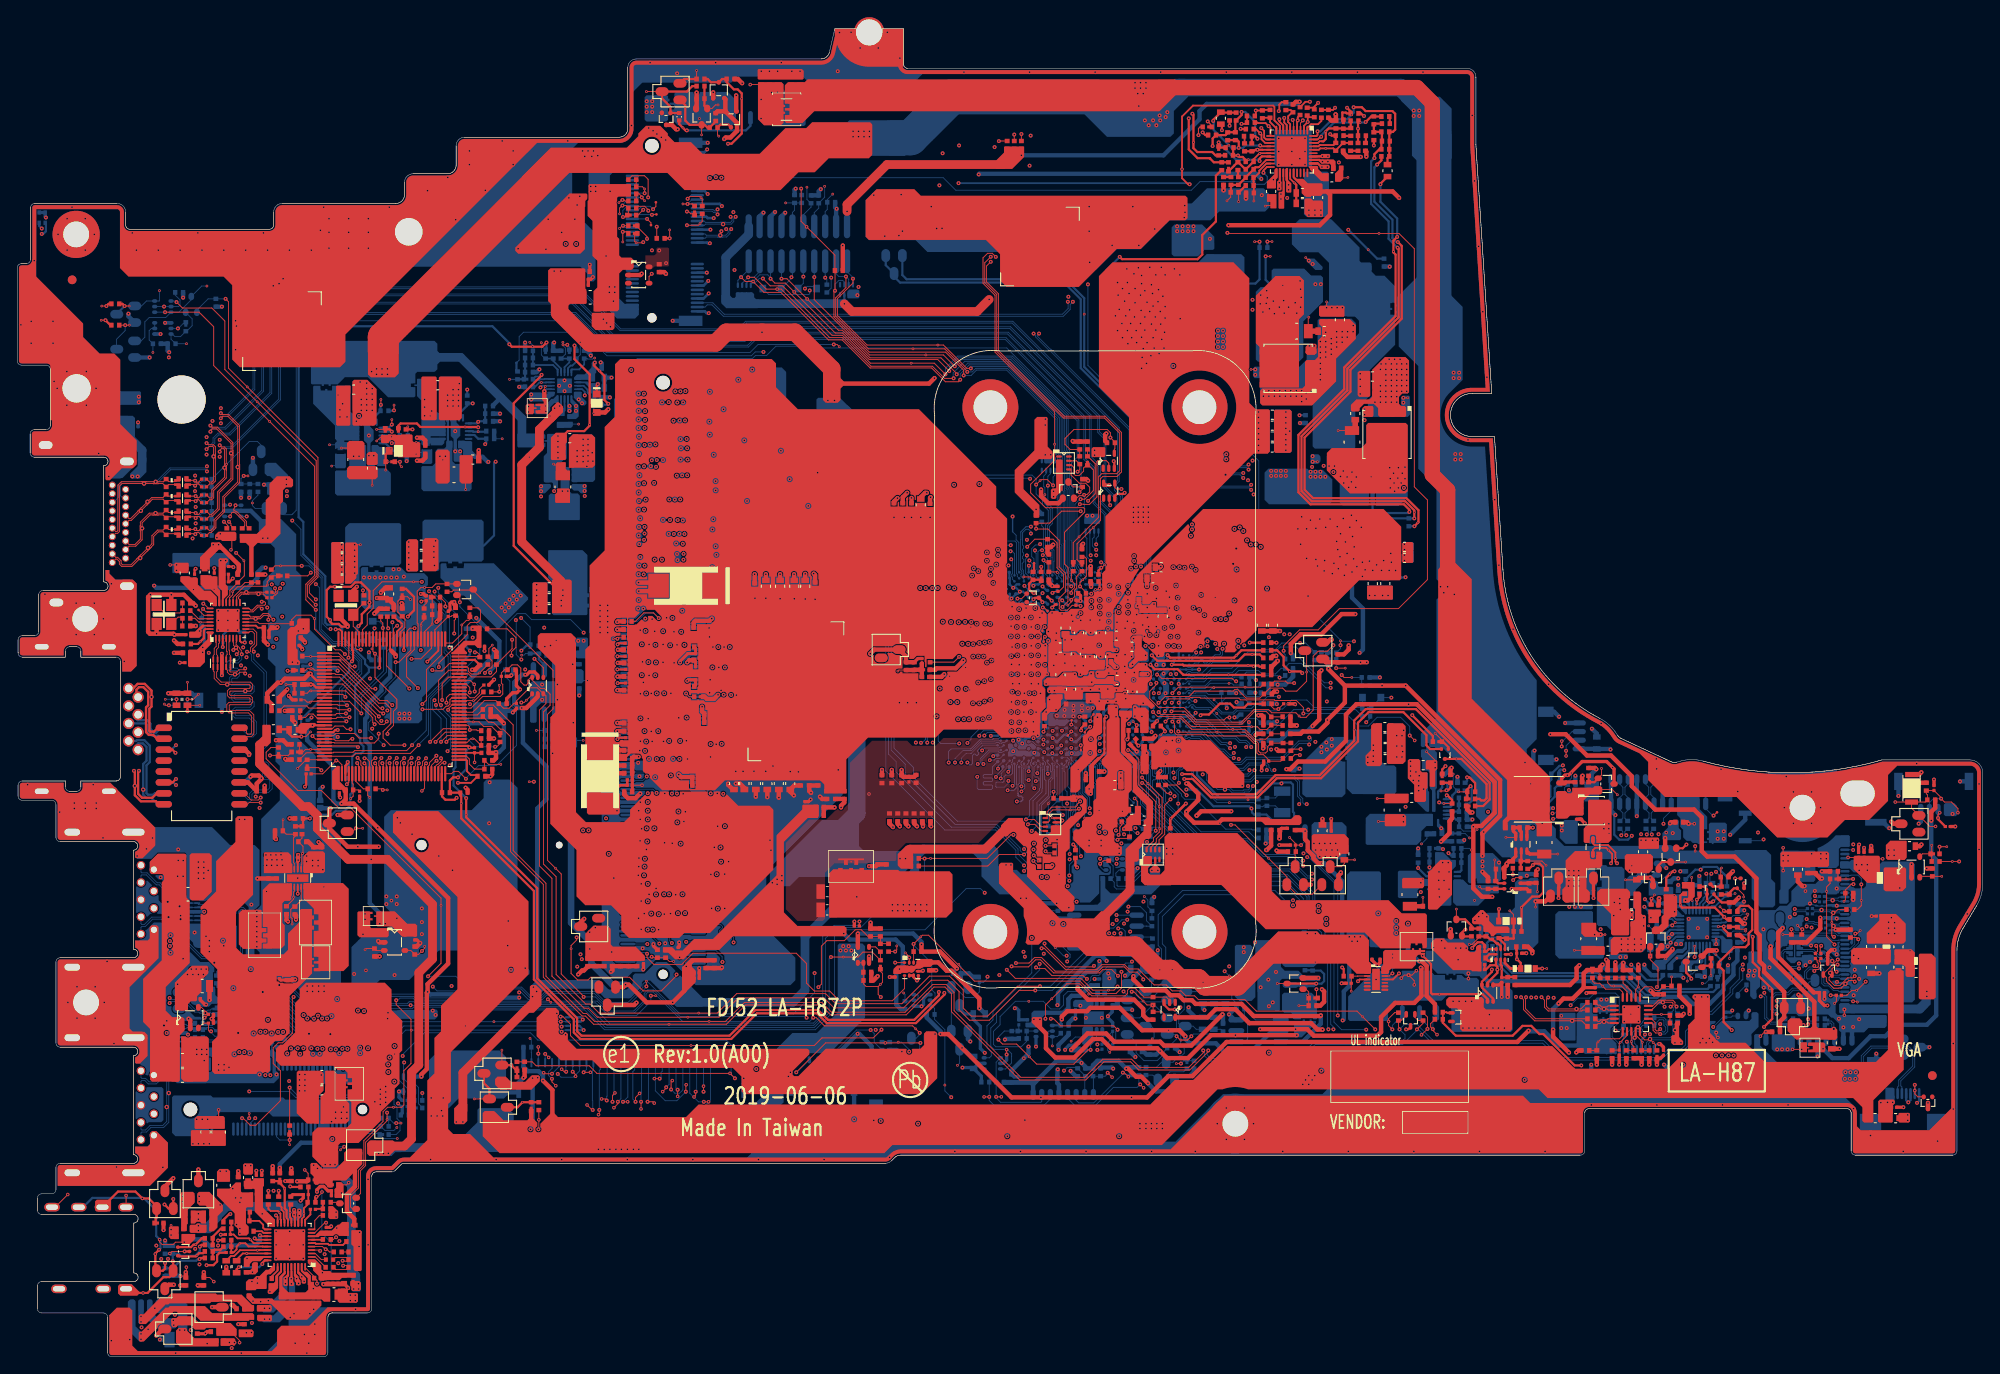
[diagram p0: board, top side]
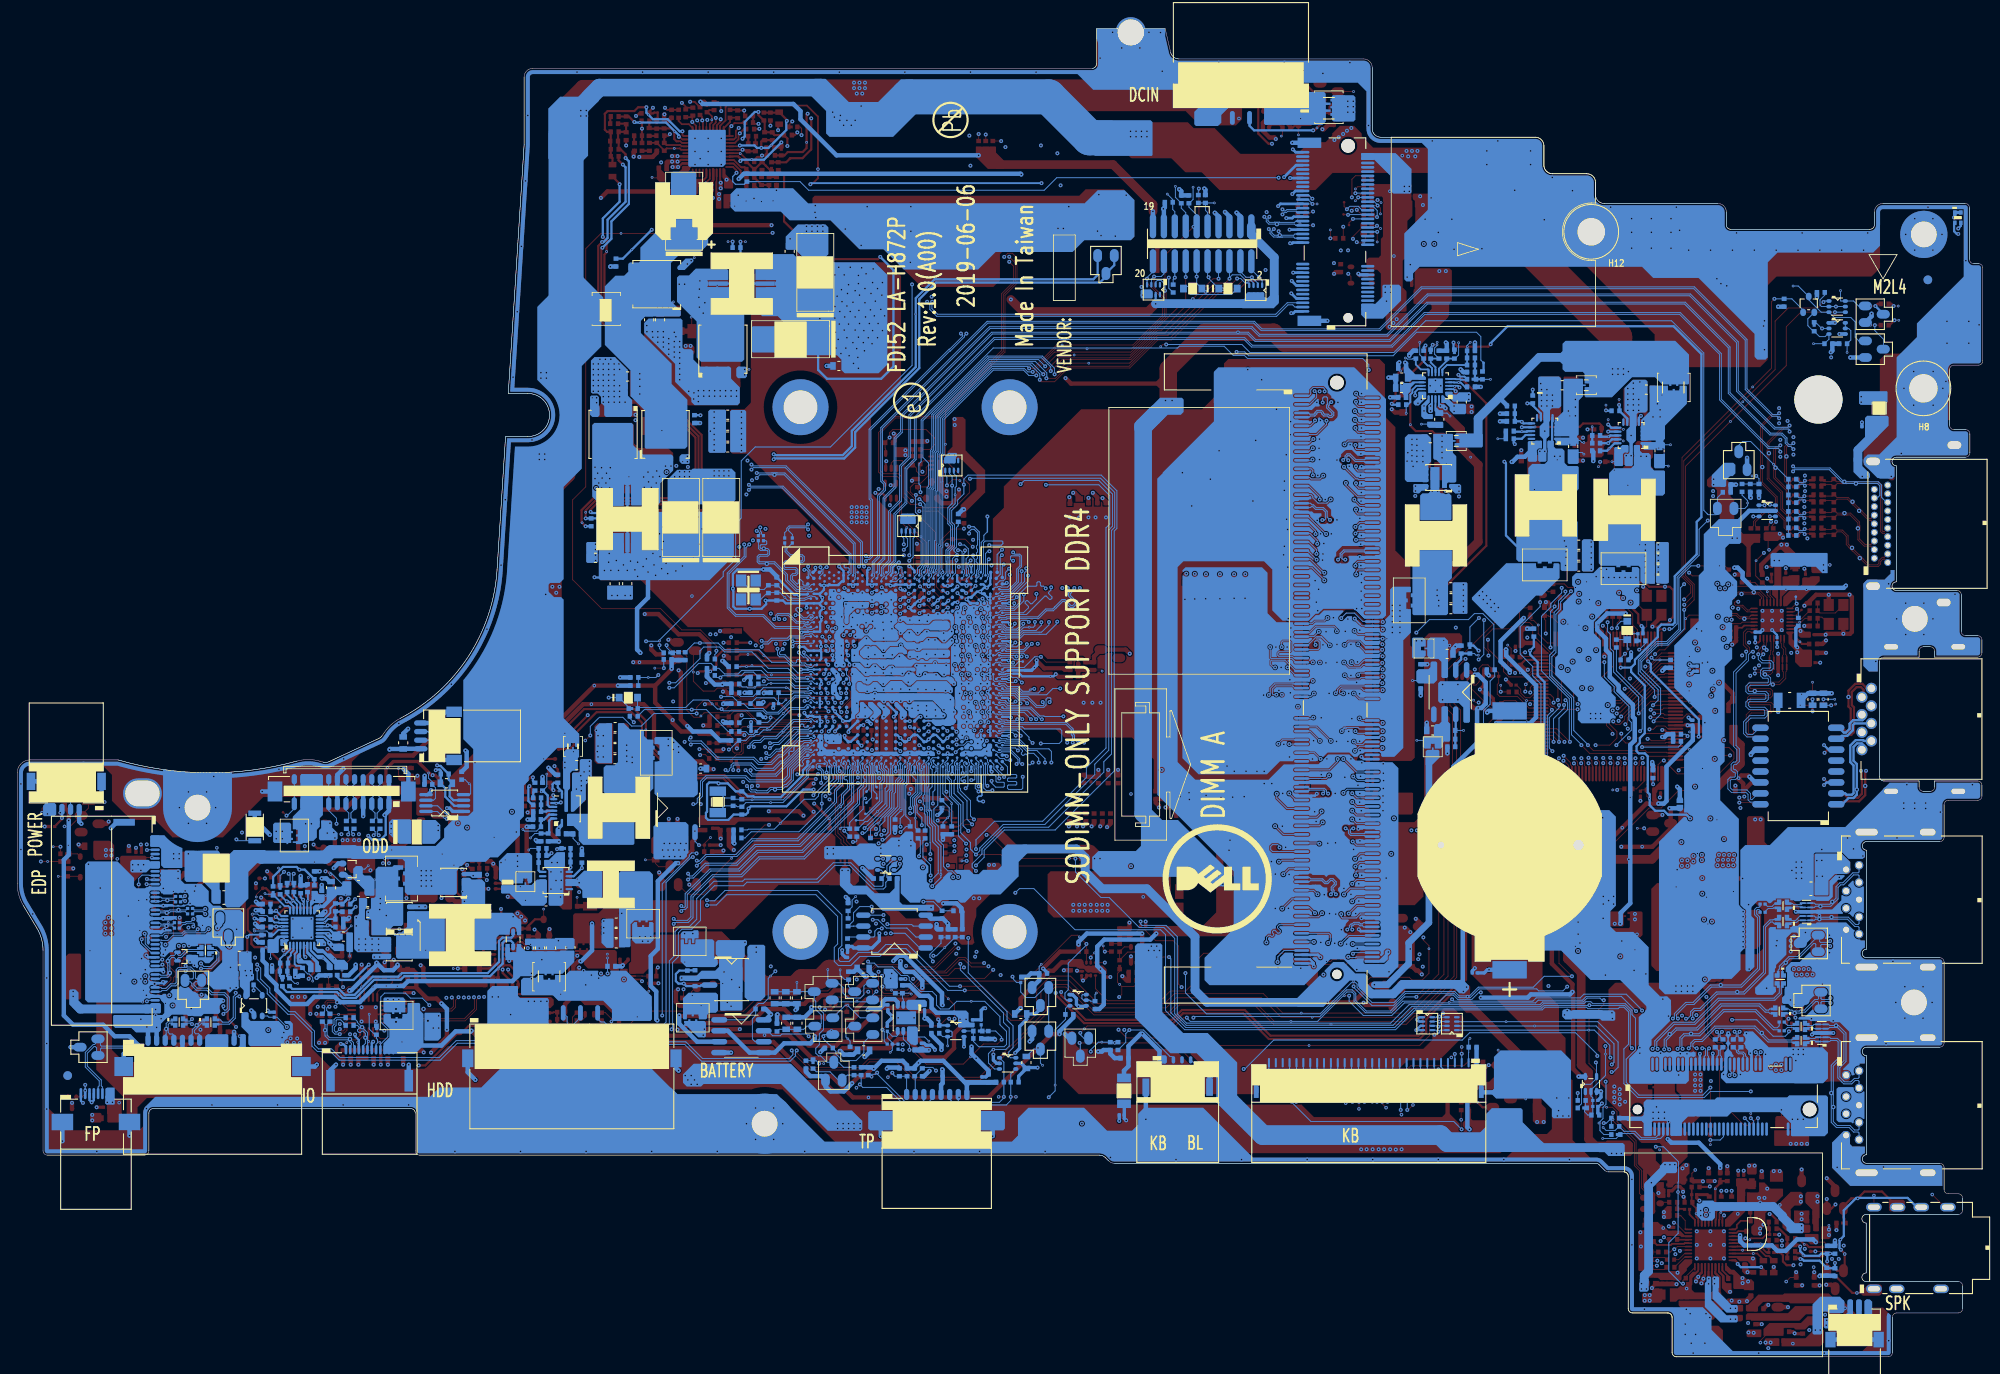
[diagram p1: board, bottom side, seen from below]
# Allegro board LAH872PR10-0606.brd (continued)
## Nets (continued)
BST_3V: PR301.1 PU301.1
BST_3V_R: PC307.1 PR301.2
BST_5V: PR501.1 PU501.1
BST_5V_R: PC507.1 PR501.2
BST_CHG: PCB06.1 PRB14.2
BST_CHG_R: PRB14.1 PUB01.12
BST_NB: PRZ08.1 PUZ01.31
BST_NB_R: PCZ09.1 PRZ08.2
BT_ON#: RW12.2 UC1.AV33
BT_ON#_R: JWLAN1.54 RW10.1 RW12.1
CAM_DETECT#: R5.1 RC34.1 UC1.AJ1
CAM_DETECT#_R: JEDP1.4 R5.2
CAP_LED: JKB1.27 R38.2
CAP_LED#_Q: Q11.1 R36.2 R38.1
CAP_LED#_R: Q10.1 Q11.2
CAPS_LED#: Q10.3 R37.2 R39.1 UE1.91
CBN: CA496.2 UA1.28
CBP: CA496.1 UA1.30
CCLIM: PRB27.2 PRB28.2 PUB01.26
CLK_PCIE_N0: UC1.M1 UL1.16
CLK_PCIE_N1: JWLAN1.49 UC1.L1
CLK_PCIE_N2: JSSD1.53 UC1.K1
CLK_PCIE_P0: UC1.M2 UL1.15
CLK_PCIE_P1: JWLAN1.47 UC1.L2
CLK_PCIE_P2: JSSD1.55 UC1.K2
CLK_SMB: PBATT1.7 PR42.1
CLKREQ_PCIE#0: RC130.1 UC1.AY32 UL1.12
CLKREQ_PCIE#1: RC36.1 RW5.1 UC1.AY31
CLKREQ_PCIE#1_R: JWLAN1.53 RW5.2
CLKREQ_PCIE#2: JSSD1.52 RC35.1 UC1.AV29
CLKRUN#: RE12.1 UC1.AY26
CLKRUN#_R: RE12.2 UE1.38
CMSRC: PRB08.2 PUB01.5
COMP: PCB12.1 PRB30.1 PUB01.28
CORE_NB_GATE: Q18.2 Q19.2 R54.1 U5.1 U5.6
CORETYPE: RC22.2 UC1.D9
CPVEE: CA25.1 UA1.27
CS_1.2V: PRM03.1 PUM01.13
CSIN_CHG: PCB03.2 PCB05.1 PRB12.2 PUB01.14
CSIP_CHG: PCB03.1 PCB04.1 PRB11.2 PUB01.15
CSON: PCB15.2 PCB16.1 PRB37.1 PUB01.1
CSON_R: PRB01.3 PRB37.2
CSOP: PCB15.1 PCB17.1 PRB36.1 PUB01.2
CSOP_R: PRB01.2 PRB36.2
DAT_SMB: PBATT1.6 PR37.1
DBC_EN: RV8.2 UE1.89
DBC_EN_R: JEDP1.11 RV8.1 RV10.1
DCIN_CHG: PCB07.2 PRB15.2 PUB01.17
DDR_A_ACT#: JDIMM1.114 UC1.L35
DDR_A_ADD0: JDIMM1.144 UC1.AG38
DDR_A_ADD1: JDIMM1.133 UC1.W35
DDR_A_ADD2: JDIMM1.132 UC1.W38
DDR_A_ADD3: JDIMM1.131 UC1.W34
DDR_A_ADD4: JDIMM1.128 UC1.U38
DDR_A_ADD5: JDIMM1.126 UC1.U37
DDR_A_ADD6: JDIMM1.127 UC1.U34
DDR_A_ADD7: JDIMM1.122 UC1.R35
DDR_A_ADD8: JDIMM1.125 UC1.R38
DDR_A_ADD9: JDIMM1.121 UC1.N38
DDR_A_ADD10: JDIMM1.146 UC1.AG34
DDR_A_ADD11: JDIMM1.120 UC1.R34
DDR_A_ADD12: JDIMM1.119 UC1.N37
DDR_A_ADD13: JDIMM1.158 UC1.AN35
DDR_A_BA0: JDIMM1.150 UC1.AJ38
DDR_A_BA1: JDIMM1.145 UC1.AG35
DDR_A_BG0: JDIMM1.115 UC1.N34
DDR_A_BG1: JDIMM1.113 UC1.L38
DDR_A_CAS#: JDIMM1.156 UC1.AN38
DDR_A_CKE0: JDIMM1.109 UC1.J38
DDR_A_CKE1: JDIMM1.110 UC1.J34
DDR_A_CLK0: JDIMM1.137 UC1.AC35
DDR_A_CLK1: JDIMM1.138 UC1.AA34
DDR_A_CLK#0: JDIMM1.139 UC1.AC34
DDR_A_CLK#1: JDIMM1.140 UC1.AA32
DDR_A_CS0#: JDIMM1.149 UC1.AL35
DDR_A_CS1#: JDIMM1.157 UC1.AR37
DDR_A_DM0: JDIMM1.12 UC1.B35
DDR_A_DM1: JDIMM1.33 UC1.D40
DDR_A_DM2: JDIMM1.54 UC1.K40
DDR_A_DM3: JDIMM1.75 UC1.T41
DDR_A_DM4: JDIMM1.178 UC1.AE41
DDR_A_DM5: JDIMM1.199 UC1.AL40
DDR_A_DM6: JDIMM1.220 UC1.AU40
DDR_A_DM7: JDIMM1.241 UC1.BA37
DDR_A_DQ0: JDIMM1.8 UC1.A34
DDR_A_DQ1: JDIMM1.7 UC1.B34
DDR_A_DQ2: JDIMM1.20 UC1.A38
DDR_A_DQ3: JDIMM1.21 UC1.B38
DDR_A_DQ4: JDIMM1.4 UC1.A33
DDR_A_DQ5: JDIMM1.3 UC1.B33
DDR_A_DQ6: JDIMM1.16 UC1.A37
DDR_A_DQ7: JDIMM1.17 UC1.B37
DDR_A_DQ8: JDIMM1.28 UC1.B41
DDR_A_DQ9: JDIMM1.29 UC1.C40
DDR_A_DQ10: JDIMM1.41 UC1.F41
DDR_A_DQ11: JDIMM1.42 UC1.G40
DDR_A_DQ12: JDIMM1.24 UC1.A40
DDR_A_DQ13: JDIMM1.25 UC1.B40
DDR_A_DQ14: JDIMM1.38 UC1.E41
DDR_A_DQ15: JDIMM1.37 UC1.F40
DDR_A_DQ16: JDIMM1.50 UC1.J40
DDR_A_DQ17: JDIMM1.49 UC1.J41
DDR_A_DQ18: JDIMM1.62 UC1.N40
DDR_A_DQ19: JDIMM1.63 UC1.N41
DDR_A_DQ20: JDIMM1.46 UC1.H40
DDR_A_DQ21: JDIMM1.45 UC1.H41
DDR_A_DQ22: JDIMM1.58 UC1.M40
DDR_A_DQ23: JDIMM1.59 UC1.M41
DDR_A_DQ24: JDIMM1.70 UC1.R40
DDR_A_DQ25: JDIMM1.71 UC1.T40
DDR_A_DQ26: JDIMM1.83 UC1.W40
DDR_A_DQ27: JDIMM1.84 UC1.Y40
DDR_A_DQ28: JDIMM1.66 UC1.P40
DDR_A_DQ29: JDIMM1.67 UC1.P41
DDR_A_DQ30: JDIMM1.79 UC1.V40
DDR_A_DQ31: JDIMM1.80 UC1.V41
DDR_A_DQ32: JDIMM1.174 UC1.AD41
DDR_A_DQ33: JDIMM1.173 UC1.AD40
DDR_A_DQ34: JDIMM1.187 UC1.AH41
DDR_A_DQ35: JDIMM1.186 UC1.AH40
DDR_A_DQ36: JDIMM1.170 UC1.AB40
DDR_A_DQ37: JDIMM1.169 UC1.AC40
DDR_A_DQ38: JDIMM1.183 UC1.AF40
DDR_A_DQ39: JDIMM1.182 UC1.AG40
DDR_A_DQ40: JDIMM1.195 UC1.AK41
DDR_A_DQ41: JDIMM1.194 UC1.AK40
DDR_A_DQ42: JDIMM1.207 UC1.AP41
DDR_A_DQ43: JDIMM1.208 UC1.AP40
DDR_A_DQ44: JDIMM1.191 UC1.AJ41
DDR_A_DQ45: JDIMM1.190 UC1.AJ40
DDR_A_DQ46: JDIMM1.203 UC1.AN41
DDR_A_DQ47: JDIMM1.204 UC1.AN40
DDR_A_DQ48: JDIMM1.216 UC1.AT40
DDR_A_DQ49: JDIMM1.215 UC1.AU41
DDR_A_DQ50: JDIMM1.228 UC1.AY40
DDR_A_DQ51: JDIMM1.229 UC1.BA40
DDR_A_DQ52: JDIMM1.211 UC1.AR40
DDR_A_DQ53: JDIMM1.212 UC1.AT41
DDR_A_DQ54: JDIMM1.224 UC1.AW40
DDR_A_DQ55: JDIMM1.225 UC1.AY41
DDR_A_DQ56: JDIMM1.237 UC1.BA38
DDR_A_DQ57: JDIMM1.236 UC1.AY37
DDR_A_DQ58: JDIMM1.249 UC1.BA34
DDR_A_DQ59: JDIMM1.250 UC1.BA33
DDR_A_DQ60: JDIMM1.232 UC1.AY39
DDR_A_DQ61: JDIMM1.233 UC1.AY38
DDR_A_DQ62: JDIMM1.245 UC1.AY35
DDR_A_DQ63: JDIMM1.246 UC1.AY34
DDR_A_DQS0: JDIMM1.13 UC1.B36
DDR_A_DQS1: JDIMM1.34 UC1.E40
DDR_A_DQS2: JDIMM1.55 UC1.L40
DDR_A_DQS3: JDIMM1.76 UC1.U41
DDR_A_DQS4: JDIMM1.179 UC1.AF41
DDR_A_DQS5: JDIMM1.200 UC1.AM40
DDR_A_DQS6: JDIMM1.221 UC1.AV40
DDR_A_DQS7: JDIMM1.242 UC1.BA36
DDR_A_DQS#0: JDIMM1.11 UC1.A36
DDR_A_DQS#1: JDIMM1.32 UC1.D41
DDR_A_DQS#2: JDIMM1.53 UC1.K41
DDR_A_DQS#3: JDIMM1.74 UC1.U40
DDR_A_DQS#4: JDIMM1.177 UC1.AE40
DDR_A_DQS#5: JDIMM1.198 UC1.AM41
DDR_A_DQS#6: JDIMM1.219 UC1.AV41
DDR_A_DQS#7: JDIMM1.240 UC1.AY36
DDR_A_EVENT#: JDIMM1.134 RC6.2 UC1.AA41
DDR_A_ODT0: JDIMM1.155 UC1.AN37
DDR_A_ODT1: JDIMM1.161 UC1.AU38
DDR_A_RAS#: JDIMM1.152 UC1.AJ37
DDR_A_RST#: CD1.1 DC1.2 JDIMM1.108 UC1.G38
DDR_A_SA0: JDIMM1.256 RD5.2 RD6.1
DDR_A_VREFDQ: T1.1(TP-1) UC1.Y41
DDR_A_WE#: JDIMM1.151 UC1.AL38
DDR_A_ZVDDIO: RC4.1 UC1.AB41
DEVSLP0_HDD: RC101.2 RS23.1 UC1.AV31
DEVSLP1_SSD: RC99.2 RS28.2 UC1.AU31
DEW1: RS4.1 RS17.1 US1.16
DEW2: RS3.1 RS16.1 US1.6
DISPOFF#: DV1.1 JEDP1.28 RV6.1 RV33.1
DMIC_CLK: L5.2 UA1.3
DMIC_DATA: RA46.2 UA1.2
DP_AUX_ZVSS: RC13.1 UC1.D21
DP_ZVSS: RC15.1 UC1.B18
EC_ENVDD: RV5.2 UE1.71
EC_MUTE#: RA8.2 UA1.40 UE1.83
EC_ON: PQB29.2 PR506.1 UE1.112
EC_PME#: RE17.1 RE32.1 UE1.29
EC_RSMRST#: CE11.1 DC2.1 RC93.1 RE28.1 UE1.100
EC_RSMRST#_R: CC14.2 DC2.2 RC93.2 RC96.2 UC1.AG1
EC_RST#: CE19.1 RE50.2 UE1.37
EC_RX: RW8.1 UE1.31
EC_RX_R: JWLAN1.40 RW8.2
EC_SCI#: RE19.2 RE21.2 UC1.AA8 UE1.20
EC_SMB_CK1: PD5.3 PR42.2 PRB20.1 RE13.2 UE1.77
EC_SMB_CK2: C14.1 QC2.3 RE15.2 U1.8 UE1.79
EC_SMB_DA1: PD5.2 PR37.2 PRB19.1 RE14.2 UE1.78
EC_SMB_DA2: C15.1 QC2.6 RE10.2 U1.7 UE1.80
EC_TP_INT#: R24.1 RE26.1 UE1.106
EC_TX: RE38.1 RW7.1 UE1.30
EC_TX_R: JWLAN1.38 RW7.2
ECAGND: CE5.2 CE7.1 LE2.1 PH1.2 UE1.69
EDP_AUXN: CV3.1 UC1.H15
EDP_AUXN_C: CV3.2 JEDP1.16
EDP_AUXP: CV2.1 UC1.G15
EDP_AUXP_C: CV2.2 JEDP1.15
EDP_HPD: JEDP1.12 RV1.1 UC1.D15
EDP_TXN0: CV4.1 UC1.B9
EDP_TXN0_C: CV4.2 JEDP1.18
EDP_TXN1: CV6.1 UC1.B10
EDP_TXN1_C: CV6.2 JEDP1.21
EDP_TXP0: CV5.1 UC1.A9
EDP_TXP0_C: CV5.2 JEDP1.19
EDP_TXP1: CV7.1 UC1.A10
EDP_TXP1_C: CV7.2 JEDP1.22
EGPIO131: RC75.2 UC1.AP31
EN_0.6VSP: PCM16.1 PRM09.2 PUM01.7
EN_0.95V: PCH09.1 PRH01.2 PRH02.1 PUH01.6
EN_1.2V: PCM15.1 PRM08.2 PUM01.8
EN_1.8V: PC1805.1 PR1801.2 PR1802.1 PU1801.5
EN_2.5V: PC2503.1 PR2501.2 PU2501.2
EN_3V: PR502.1 PU301.12
EN_5V: PR503.1 PU501.12
ENABLE_APU: PRZ85.2 PUZ01.8
ENLDO_3V5V: PC317.1 PR302.1 PR303.1 PU301.11 PU501.11
ENVDD: RC19.1 RC21.2 RV4.2 UC9.4
ENVDD_R: RC21.1 RPC2.6 UC1.B24 UC9.2
ENVDD_RE: RV4.1 RV5.1 UV1.4
FAN1_PWM: JFAN1.2 RE51.1 UE1.26
FAN1_TACH: JFAN1.3 RE52.1 UE1.28
FB_0.95V: PRH08.1 PRH09.1 PRH12.2 PUH01.10
FB_1.2V: PCM17.1 PRM10.1 PRM11.1 PUM01.6
FB_1.8V: PC1807.2 PR1805.1 PR1806.2 PU1801.6
FB_3V: PC315.1 PU301.13
FB_3V_R: PC315.2 PR306.1
FB_5V: PC517.1 PU501.13
FB_5V_R: PC517.2 PR509.1
FFS_INT1: RC57.1 UC1.AU33 US2.12
FFS_INT2: QS1.2 RC59.1 UC1.AH2 US2.11
FFS_INT2_Q: JHDD1.9 QS1.3 RS24.2
FPR_SCAN#: EU2.3 JFP1.2 RE23.1 UE1.118
FSET: PRB38.1 PUB01.3
GATEA20: RPC7.6 UC1.AU35 UE1.1
GPIO93: RC53.2 UC1.BA29
H_PROCHOT#: PQ11.1 PQ12.3 PQB32.1 PRB21.1 PRZ21.2 PUZ01.4 RC33.2 RC37.2 RE33.2 UC1.A31
HDA_BIT_CLK: RC87.2 RPC4.7 RPC5.6 UC1.AY6
HDA_BIT_CLK_R: RA50.2 RPC4.2 UA1.5
HDA_CODEC_SDIN0: RA30.2 UA1.7
HDA_RST#: RPC4.5 RPC5.8 UC1.AY4
HDA_SDIN0: RA30.1 RC86.2 UC1.BA6
HDA_SDIN1: RC83.2 UC1.AY5
HDA_SDIN2: RC85.2 UC1.BA5
HDA_SDOUT: RPC4.8 RPC5.5 UC1.BA4
HDA_SDOUT_R: RPC4.1 UA1.4
HDA_SYNC: RPC4.6 RPC5.7 UC1.BA3
HDA_SYNC_R: RPC4.3 UA1.9
HDD_A0_EQ: RS12.2 RS13.1 US1.18
HDD_A0_PRE0: RS7.2 RS20.1 US1.9
HDD_A0_PRE1: RS10.2 RS19.1 US1.17
HDD_B0_EQ: RS14.1 RS15.1 US1.13
HDD_B0_PRE0: RS8.2 RS18.1 US1.8
HDD_B0_PRE1: RS11.2 RS21.1 US1.19
HDMI_CLKN: CV15.2 LV2.2 RV11.1 RV16.1
HDMI_CLKP: CV16.2 LV2.3 RV13.1 RV17.1
HDMI_CTRL_CLK: JHDMI1.15 QV3.6 RV39.2
HDMI_CTRL_DATA: JHDMI1.16 QV3.3 RV38.2
HDMI_HPD: CV24.1 JHDMI1.19 RV30.2 RV31.1
HDMI_L_CLKN: JHDMI1.12 LV2.1 RV11.2 RV12.1
HDMI_L_CLKP: JHDMI1.10 LV2.4 RV12.2 RV13.2
HDMI_L_TX_N0: JHDMI1.9 LV3.1 RV14.2 RV15.1
HDMI_L_TX_N1: JHDMI1.6 LV4.1 RV23.2 RV24.1
HDMI_L_TX_N2: JHDMI1.3 LV5.1 RV28.2 RV29.2
HDMI_L_TX_P0: JHDMI1.7 LV3.4 RV15.2 RV22.2
HDMI_L_TX_P1: JHDMI1.4 LV4.4 RV24.2 RV25.2
HDMI_L_TX_P2: JHDMI1.1 LV5.4 RV26.2 RV28.1
HDMI_TX_N0: CV18.2 LV3.2 RV14.1 RV34.1
HDMI_TX_N1: CV20.2 LV4.2 RV21.1 RV23.1
HDMI_TX_N2: CV22.2 LV5.2 RV19.1 RV29.1
HDMI_TX_P0: CV19.2 LV3.3 RV22.1 RV35.1
HDMI_TX_P1: CV21.2 LV4.3 RV20.1 RV25.1
HDMI_TX_P2: CV23.2 LV5.3 RV18.1 RV26.1
HPOUT_L: CA498.1 DA8.2 JHP1.1 LA2.2 RA54.1
HPOUT_R: CA504.1 DA8.3 JHP1.2 LA3.2 RA57.1
HVB_FUNCTION: RC84.2 UC1.AP27
HW_ACAV_IN: PR31.1 PR909.2 PRB22.2 PRB25.2 PRB26.1 RE37.2
I2C_0_SCL: Q1.1 R2.2 UC1.AY22
I2C_0_SCL_R: Q1.6 R1.2 R12.1
I2C_0_SDA: Q1.4 R3.2 UC1.BA22
I2C_0_SDA_R: Q1.3 R4.2 R11.1
I2C_1_SCL: RPC7.8 UC1.AU19
I2C_1_SDA: RPC7.7 UC1.AV19
I2C_3_SCL: Q5.3 RPC6.1 UC1.AC5
I2C_3_SCL_R: JTP1.6 Q5.4 R35.1
I2C_3_SDA: Q5.6 RPC6.2 UC1.AC4
I2C_3_SDA_R: JTP1.7 Q5.1 R33.1
ILMT_0.95V: PRH03.2 PRH04.1 PUH01.12
IMON_APU: PCZ62.2 PRZ76.2 PUZ01.10
IMON_NB: PCZ18.2 PRZ18.2 PUZ01.2
INVTPWM: JEDP1.27 RC20.1 RC23.1 RV7.1 UC10.4
INVTPWM_R: RC23.2 RPC2.7 UC1.A24 UC10.2
ISOLATE#: RL8.2 RL9.1 UL1.20
JACK_PLUG: DA9.3 JHP1.5 RA51.1
JACK_PLUG_DET: DA9.2 JHP1.6 RA62.1
JHDD_P10: JHDD1.8 RS23.2
KB_BL_PWM: JKBBL1.4 Q4.1
KB_DET: R30.1 R31.1 UC1.BA28
KB_LED_PWM: Q4.2 UE1.25
KB_RST#: RC113.2 UC1.BA30 UE1.2
KSI0: JKB1.9 UE1.55
KSI1: JKB1.7 UE1.56
KSI2: JKB1.5 UE1.57
KSI3: JKB1.8 UE1.58
KSI4: JKB1.4 UE1.59
KSI5: JKB1.6 UE1.60
KSI6: JKB1.3 UE1.61
KSI7: JKB1.2 UE1.62
KSO0: JKB1.18 UE1.39
KSO1: JKB1.16 UE1.40
KSO2: JKB1.17 UE1.41
KSO3: JKB1.15 UE1.42
KSO4: JKB1.11 UE1.43
KSO5: JKB1.10 UE1.44
KSO6: JKB1.13 UE1.45
KSO7: JKB1.12 UE1.46
KSO8: JKB1.14 UE1.47
KSO9: JKB1.24 UE1.48
KSO10: JKB1.26 UE1.49
KSO11: JKB1.25 UE1.50
KSO12: JKB1.19 UE1.51
KSO13: JKB1.22 UE1.52
KSO14: JKB1.23 UE1.53
KSO15: JKB1.21 UE1.54
KSO16: JKB1.20 UE1.81
LAN_MDIN0: EL1.4 EL1.7 TL1.15 UL1.2
LAN_MDIN1: EL1.1 EL1.9 TL1.9 UL1.5
LAN_MDIN2: TL2.10 UL1.7
LAN_MDIN3: TL2.16 UL1.10
LAN_MDIP0: EL1.5 EL1.6 TL1.16 UL1.1
LAN_MDIP1: EL1.2 EL1.8 TL1.10 UL1.4
LAN_MDIP2: TL2.9 UL1.6
LAN_MDIP3: TL2.15 UL1.9
LANXIN: RL2.2 UL1.28
LANXIN_R: CL1.1 RL2.1 YL1.1
LANXOUT: RL3.2 UL1.29
LANXOUT_R: CL7.1 RL3.1 YL1.3
LCD_TEST: RV2.1 UE1.72
LCD_TST_C: JEDP1.10 RV2.2
LDO1_CAP: CA479.2 RA47.2 UA1.21
LDO2_CAP: CA482.2 UA1.32
LDO3_CAP: CA493.2 UA1.6
LG1_APU: PQZ05.4 PQZ06.4 PUZ01.24
LG_1.2V: PQM01.8 PUM01.15
LG_CHG: PQB25.4 PUB01.9
LG_NB: PQZ02.4 PQZ03.4 PUZ01.34
LID_SW#: DE1.1 EC2.1 JPWR1.3 RE18.1 UE1.115
LINE1-L: CA500.1 UA1.18
LINE1-L_C: CA500.2 RA59.1
LINE1-L_R: CA503.2 RA55.1
LINE1-R: CA503.1 UA1.17
LOM_TCT: CL21.1 TL1.11 TL1.14 TL2.11 TL2.14
LPC_AD0: UC1.BA26 UE1.10
LPC_AD1: UC1.AY28 UE1.8
LPC_AD2: UC1.AY25 UE1.7
LPC_AD3: UC1.AY23 UE1.5
LPC_CLK0_EC: RC77.2 RC89.1 RC107.1 RE11.1 UE1.12
LPC_CLK1: RC78.2 RC94.1 RC109.1
LPC_FRAME#: RC76.2 RC88.1 UC1.AY24 UE1.4
LPC_RST_A#: RC111.2 UC1.AY27
LPCPD#: RC108.2 UC1.AC1
LX1_APU: PCZ38.2 PLZ04.1 PQZ04.1 PQZ04.2 PQZ04.3 PQZ05.5 PQZ06.5 PRZ74.1 PUZ01.23
LX_0.95V: PCH12.2 PLH01.1 PRH07.1 PUH01.2 PUH01.3
LX_1.2V: PCM12.2 PLM01.2 PQM01.9 PRM01.1 PUM01.16
LX_1.8V: PL1812.1 PR1804.1 PU1801.2 PU1801.3
LX_3V: PC307.2 PL301.1 PR305.1 PU301.6 PU301.19 PU301.20
LX_5V: PC507.2 PL501.1 PR505.1 PU501.6 PU501.19 PU501.20
LX_CHG: PCB06.2 PLB01.1 PQB25.5 PQB26.1 PQB26.2 PQB26.3 PRB40.1 PUB01.10
LX_NB: PCZ09.2 PLZ02.1 PQZ01.1 PQZ01.2 PQZ01.3 PQZ02.5 PQZ03.5 PRZ10.1 PUZ01.33
MASK_BASE_LED#: Q7.2 Q7.5 R78.2 RE53.2
MASK_SATA_LED#: Q12.2 R42.1 RE20.2
MCT: CL20.1 RL12.1 RL13.1 RL14.1 RL15.1
MCT0: RL12.2 TL1.3
MCT1: RL13.2 TL1.6
MCT2: RL14.2 TL2.6
MCT3: RL15.2 TL2.3
MEM_VOLT_SEL: RC79.2 RC90.1 UC1.AJ7
MIC_CAP: CA26.1 UA1.15
NCT7718_DXN: C12.2 C13.2 Q13.3 U1.3
NCT7718_DXP: C12.1 C13.1 Q13.1 Q13.2 U1.2
NO_SMOKE_OVP: PC908.1 PC909.1 PD901.2 PQ900.5 PU900.1
NO_SMOKE_UVP: PC910.1 PC911.1 PD902.2 PQ900.2 PU900.7
NTC_CHG: PRB13.2 PUB01.13
ODD_DA#: JODD1.23 JODD1.24 T18.1(TP-1)
ON/OFF#: CE18.1 EC1.1 ED3.3 JPWR1.2 RE44.2 SW1.2 SW2.2 UE1.114
P_ZVDDP: RC1.2 UC1.U8
P_ZVSS: RC2.1 UC1.W8
PANEL_BKLEN: DV1.3 QC1.1 RC8.1 RE48.2
PANEL_BKLEN_APU: QC1.3 RPC2.5 UC1.B23
PBTN_OUT#: CE15.1 RC74.2 UC1.AD2 UE1.15
PCIE_ARX_C_DTX_N0: CL9.1 UL1.18
PCIE_ARX_C_DTX_P0: CL8.1 UL1.17
PCIE_ARX_DTX_N0: CL9.2 UC1.U5
PCIE_ARX_DTX_N1: JWLAN1.43 UC1.R10
PCIE_ARX_DTX_N2: JSSD1.43 UC1.R4
PCIE_ARX_DTX_N3: JSSD1.29 UC1.N5
PCIE_ARX_DTX_P0: CL8.2 UC1.U4
PCIE_ARX_DTX_P1: JWLAN1.41 UC1.R8
PCIE_ARX_DTX_P2: JSSD1.41 UC1.R5
PCIE_ARX_DTX_P3: JSSD1.31 UC1.N4
PCIE_ATX_C_DRX_N0: CL14.2 UL1.14
PCIE_ATX_C_DRX_N1: CC2.2 JWLAN1.37
PCIE_ATX_C_DRX_N2: CS33.2 JSSD1.47
PCIE_ATX_C_DRX_N3: CS31.2 JSSD1.35
PCIE_ATX_C_DRX_P0: CL13.2 UL1.13
PCIE_ATX_C_DRX_P1: CC1.2 JWLAN1.35
PCIE_ATX_C_DRX_P2: CS34.2 JSSD1.49
PCIE_ATX_C_DRX_P3: CS32.2 JSSD1.37
PCIE_ATX_DRX_N0: CL14.1 UC1.D1
PCIE_ATX_DRX_N1: CC2.1 UC1.C1
PCIE_ATX_DRX_N2: CS33.1 UC1.B1
PCIE_ATX_DRX_N3: CS31.1 UC1.B3
PCIE_ATX_DRX_P0: CL13.1 UC1.D2
PCIE_ATX_DRX_P1: CC1.1 UC1.C2
PCIE_ATX_DRX_P2: CS34.1 UC1.B2
PCIE_ATX_DRX_P3: CS32.1 UC1.A3
PLT_RST#: CC21.1 RC66.2 RC111.1 RC112.2 RL16.2 RW3.2 UE1.13
PLT_RST#_RW: JWLAN1.52 RW3.1 RW4.1
PM_SLP_S3#: RE31.1 UC1.AC2
PM_SLP_S3#_EC: RE31.2 UE1.6
PM_SLP_S5#: CE16.1 R67.2 RE35.1 UC1.AG4
PM_SLP_S5#_R: RE35.2 UE1.123
POK: CE17.1 PR35.1 PR304.2 PR504.2 PU301.9 PU501.9 UE1.34
PROG: PRB17.2 PUB01.19
PROH: PQB33.2 PRB21.2 PRB44.2 PUB01.23
PS_ID: PD2.1 PR1.2 PR5.1 UE1.16
PSID: PJPDC1.3 PL3.1
PSID-1: PQ2.2 PR3.2 PR6.1
PSID-2: PD1.2 PL3.2 PQ1.1 PR3.1
PSID-3: PQ1.3 PR1.1
PSID-4: PQ1.2 PQ2.1 PR4.2 PR7.1
PSID-5: PD3.1 PR7.2
PTP_DIS#: JTP1.3 R23.2 UE1.19
QPCN_CHG: PCB18.2 PUB01.6
QPCP_CHG: PCB18.1 PUB01.4
REGOUT: CL2.1 RL1.1 UL1.24
RESERVE_2: RC56.1 RC61.2 UC1.AY29
RING2: LA1.1 RA60.2 UA1.13
RING2_R: CA497.1 CA501.1 DA5.3 JHP1.4 LA1.2
RJ45_MDIN0: JLAN1.2 TL1.2
RJ45_MDIN1: JLAN1.6 TL1.8
RJ45_MDIN2: JLAN1.5 TL2.7
RJ45_MDIN3: JLAN1.8 TL2.1
RJ45_MDIP0: JLAN1.1 TL1.1
RJ45_MDIP1: JLAN1.3 TL1.7
RJ45_MDIP2: JLAN1.4 TL2.8
RJ45_MDIP3: JLAN1.7 TL2.2
RTC_CLK: RC62.1 RC80.2 RC91.1 UC1.AN4
RTC_DET#: QC3.1 RC70.2 UC1.AG8
RTC_DIS: QE1.2 RE29.1 UE1.36
S5_MUX_CTRL: Q15.5 R57.1 R65.2 UC1.AA7
SATA_ACT#: Q14.2 R44.1 RC104.2 RS27.2 UC1.AY30
SATA_ACT#_R: Q12.3 Q14.3 R44.2 R49.2
SATA_ARX_C_DTX_N0: CS10.2 JHDD1.5
SATA_ARX_C_DTX_N1: CS17.2 JODD1.9 JODD1.10
SATA_ARX_C_DTX_P0: CS9.2 JHDD1.6
SATA_ARX_C_DTX_P1: CS16.2 JODD1.11 JODD1.12
SATA_ARX_C_RD_DTX_N0: CS6.2 US1.4
SATA_ARX_C_RD_DTX_P0: CS5.2 US1.5
SATA_ARX_DTX_N0: CS6.1 UC1.AY12
SATA_ARX_DTX_N1: CS17.1 UC1.BA8
SATA_ARX_DTX_P0: CS5.1 UC1.BA12
SATA_ARX_DTX_P1: CS16.1 UC1.AY8
SATA_ARX_RD_DTX_N0: CS10.1 US1.12
SATA_ARX_RD_DTX_P0: CS9.1 US1.11
SATA_ATX_C_DRX_N0: CS8.2 JHDD1.3
SATA_ATX_C_DRX_N1: CS15.2 JODD1.5 JODD1.6
SATA_ATX_C_DRX_P0: CS7.2 JHDD1.2
SATA_ATX_C_DRX_P1: CS14.2 JODD1.3 JODD1.4
SATA_ATX_C_RD_DRX_N0: CS4.2 US1.2
SATA_ATX_C_RD_DRX_P0: CS3.2 US1.1
SATA_ATX_DRX_N0: CS4.1 UC1.AY10
SATA_ATX_DRX_N1: CS15.1 UC1.BA9
SATA_ATX_DRX_P0: CS3.1 UC1.BA10
SATA_ATX_DRX_P1: CS14.1 UC1.AY9
SATA_ATX_RD_DRX_N0: CS8.1 US1.14
SATA_ATX_RD_DRX_P0: CS7.1 US1.15
SATA_EN: CS35.1 RS9.2 US1.7
SATA_ODD_PRSNT#: JODD1.15 JODD1.16 RC44.2 UC1.AG5 UE1.101
SATA_ZVDD: RC103.1 UC1.AP11
SATA_ZVSS: RC102.1 UC1.AU11
SCL_CHG: PRB20.2 PUB01.22
SDA_CHG: PRB19.2 PUB01.21
SERIRQ: UC1.AV27 UE1.3
SKU_ID: RC132.1 RC133.2 UC1.AE8
SLEEVE: LA13.1 RA56.2 UA1.14
SLEEVE_R: CA499.1 CA502.1 DA5.2 JHP1.3 LA13.2
SN_0.95V: PCH13.1 PRH07.2
SN_1.2V: PCM11.1 PRM01.2
SN_1.8V: PC1806.1 PR1804.2
SN_3V: PC309.1 PR305.2
SN_5V: PC509.1 PR505.2
SN_+APU_CORE: PCZ54.1 PRZ74.2
SN_+APU_CORE_NB: PCZ13.1 PRZ10.2
SN_CHG: PCB29.1 PRB40.2
SSD_SCP#: RE49.1 RS26.2 UE1.107
SUSCLK_WLAN: JWLAN1.50 RC62.2 RE34.1
SUSP#: DE2.2 PRM09.1 R51.1 R52.1 R53.1 UE1.116
SWTRAP: RE39.1 RE41.2 UE1.70
SYS_RESET_L: CC15.2 RC81.2 RC92.1 UC1.AF1
SYSON: CE12.1 PR2501.1 PRM08.1 UE1.95
T_CRIT#: R46.2 U1.4
TON_1.2V: PRM07.2 PUM01.9
TOUCH_SCREEN_INT#: JEDP1.24 R17.2
TOUCH_SCREEN_RST: JEDP1.25 R19.2
TP_CLK: C7.1 JTP1.1 R25.2 UE1.87
TP_DATA: C8.1 JTP1.2 R26.2 UE1.88
TP_EN: R34.1 UE1.82
TP_I2C_INT#: JTP1.4 Q2.3 R22.2 R24.2 R29.1
TP_I2C_INT#_APU: Q2.1 R22.1 RC52.2
TP_ON#_GATE: C9.2 Q3.2 Q6.2 R34.2
TPAN_VDD_F: F2.1 R13.2 R14.2 R20.1
TS_EN_R: DE1.2 R6.2
TS_EN_RR: JEDP1.39 R6.1
UG1_APU: PQZ04.4 PUZ01.22
UG_1.2V: PQM01.1 PUM01.17
UG_CHG: PQB26.4 PUB01.11
UG_NB: PQZ01.4 PUZ01.32
USB3_ARX_DTX_0_N1: LU1.2 RU2.1 UC1.W1
USB3_ARX_DTX_0_N1_R: EU4.1 EU4.9 JUSB1.5 LU1.1 RU2.2
USB3_ARX_DTX_0_N2: LU4.2 RU7.1 UC1.Y1
USB3_ARX_DTX_0_N2_R: EU6.1 EU6.9 JUSB2.5 LU4.1 RU7.2
USB3_ARX_DTX_0_P1: LU1.3 RU1.1 UC1.W2
USB3_ARX_DTX_0_P1_R: EU4.2 EU4.8 JUSB1.6 LU1.4 RU1.2
USB3_ARX_DTX_0_P2: LU4.3 RU8.1 UC1.Y2
USB3_ARX_DTX_0_P2_R: EU6.2 EU6.8 JUSB2.6 LU4.4 RU8.2
USB3_ATX_C_DRX_0_N1: CU10.1 LU2.2 RU3.1
USB3_ATX_C_DRX_0_N2: CU20.1 LU5.2 RU9.1
USB3_ATX_C_DRX_0_P1: CU11.1 LU2.3 RU4.1
USB3_ATX_C_DRX_0_P2: CU21.1 LU5.3 RU10.1
USB3_ATX_DRX_0_N1: CU10.2 UC1.R2
USB3_ATX_DRX_0_N2: CU20.2 UC1.P2
USB3_ATX_DRX_0_P1: CU11.2 UC1.R1
USB3_ATX_DRX_0_P2: CU21.2 UC1.P1
USB3_ATX_L_DRX_0_N1: EU4.4 EU4.7 JUSB1.8 LU2.1 RU3.2
USB3_ATX_L_DRX_0_N2: EU6.4 EU6.7 JUSB2.8 LU5.1 RU9.2
USB3_ATX_L_DRX_0_P1: EU4.5 EU4.6 JUSB1.9 LU2.4 RU4.2
USB3_ATX_L_DRX_0_P2: EU6.5 EU6.6 JUSB2.9 LU5.4 RU10.2
USB20_N0: LU7.3 RU14.1 UC1.AW2
USB20_N0_R: JIOB1.4 LU7.4 RU14.2
USB20_N1: LU8.3 RU16.1 UC1.AV2
USB20_N1_R: JIOB1.7 LU8.4 RU16.2
USB20_N2: D1.2 JEDP1.36 R11.2 UC1.AU2
USB20_N3: L1.4 R9.1 UC1.AT2
USB20_N3_R: ED2.2 JEDP1.33 L1.3 R9.2
USB20_N4: JWLAN1.5 UC1.AR2
USB20_N5: LU3.3 RU6.1 UC1.AP2
USB20_N5_R: EU3.3 JUSB1.2 LU3.4 RU6.2
USB20_N6: LU6.3 RU12.1 UC1.AN2
USB20_N6_R: EU5.3 JUSB2.2 LU6.4 RU12.2
USB20_N7: EU1.2 JFP1.6 UC1.AM2
USB20_P0: LU7.2 RU13.1 UC1.AW1
USB20_P0_R: JIOB1.3 LU7.1 RU13.2
USB20_P1: LU8.2 RU15.1 UC1.AV1
USB20_P1_R: JIOB1.6 LU8.1 RU15.2
USB20_P2: D1.3 JEDP1.37 R12.2 UC1.AU1
USB20_P3: L1.1 R8.1 UC1.AT1
USB20_P3_R: ED2.3 JEDP1.34 L1.2 R8.2
USB20_P4: JWLAN1.3 UC1.AR1
USB20_P5: LU3.2 RU5.1 UC1.AP1
USB20_P5_R: EU3.2 JUSB1.3 LU3.1 RU5.2
USB20_P6: LU6.2 RU11.1 UC1.AN1
USB20_P6_R: EU5.2 JUSB2.3 LU6.1 RU11.2
USB20_P7: EU1.3 JFP1.5 UC1.AM1
USB_EN#: CU12.1 CU24.1 RE16.2 UE1.84 UU1.4 UU2.4
USB_OC0#: CU13.1 RC68.2 UC1.AB2 UU1.3
USB_OC1#: CU25.1 RC69.2 UC1.AG2 UU2.3
USB_ZVSS: RC100.1 UC1.AN7
USBSS_ZVDD: RC106.1 UC1.W5
USBSS_ZVSS: RC105.1 UC1.W4
VCIN0_PH1: PH1.1 PR9.2 UE1.109
VCIN1_BATT_TEMP: CE7.2 PC14.1 PD6.2 PR39.2 PR41.1 PRB24.2 UE1.63
VCIN1_BATT_TEMP_R: PBATT1.5 PR39.1
VCOUT0: RE30.1 UE1.104
VCOUT0_MAIN_PWR_ON: CE14.1 PR507.1 RE30.2
VCOUT1_PH: CE9.1 CE13.1 RE33.1 UE1.103
VGATE: PRZ70.2 PUZ01.20 RC38.1 UE1.74
VL: PC515.1 PU501.15
VR_ON: PRH20.2 PRZ85.1 UE1.121
VREF_0.775V: PC803.1 PQ801.1 PR802.2 PR803.1 PU800.3
VSUM+_APU: PCZ53.1 PCZ66.1 PRZ71.1 PRZ79.1 PRZ84.1 PUZ01.14
VSUM+_APU_R: PLZ04.2 PRZ84.2
VSUM-_APU: PCZ53.2 PCZ65.1 PCZ66.2 PHZ4.2 PLZ04.3 PRZ66.1 PRZ71.2 PRZ72.1
VSUMN_NB: PCZ11.2 PCZ12.2 PCZ14.1 PHZ1.2 PLZ02.3 PRZ11.2 PRZ13.1 PRZ15.1
VSUMP_NB: PCZ11.1 PCZ12.1 PRZ09.1 PRZ11.1 PRZ12.1 PUZ01.40
VSUMP_NB_R: PLZ02.2 PRZ12.2
VTTREF_1.2V: PCM19.1 PUM01.4
WL_OFF#: RC98.2 RW13.2 UC1.AA4
WL_OFF#_R: JWLAN1.56 RW11.1 RW13.1
WLAN_EN: RE54.1 UE1.64 UW1.4
WLAN_WAKE#: RE25.1 RW6.1 UE1.90
WLAN_WAKE#_R: JWLAN1.55 RW6.2
WOL_EN: RL11.2 UE1.98 UL2.4
XCLKI: RE34.2 UE1.122 YE1.3
N17389450: PC516.2 PD501.2 PR502.2 PR503.2 PR506.2 PR508.1
N17415515: PJP2.1 PJPDC1.1 PJPDC1.2 PL2.1
N21380741: PC508.1 PU501.16 PU501.17
N23133643: PDB01.1 PRB15.1
N27121430: RC3.2 UC1.AA40
N27174658: PC903.2 PD901.1 PR904.2 PR905.2 PU900.3
N27174719: PC904.2 PR907.2 PR908.2 PU900.6
N27174755: PC905.1 PD902.1 PR909.1 PR911.1 PU900.5
N27174767: PD900.1 PR906.2 PR907.1
N27174913: PQ900.3 PQ900.6 PR901.1
N27175044: PC901.2 PR902.2 PR903.2 PU900.2
N28483977: PQ13.2 PR31.2 PR35.2 PR45.1
N28484391: PC13.1 PQ12.6 PR33.2
N28484416: PQ12.2 PR36.2 PR44.2
N28484439: PC14.2 PQ11.2 PR43.1
N28484451: PQ13.5 PQ13.6 PR34.2 PR38.1
N28484500: PC13.2 PQ12.5 PR40.1
N28866422: PRB02.3 PRB12.1
N28866577: PCB11.1 PRB30.2
N28866613: PRB02.2 PRB11.1
N29056076: PQB28.2 PQB29.1
N29179188: PCB01.1 PQB03.3 PQB11.1 PQB11.2 PQB11.3 PQB12.1 PQB12.2 PQB12.3 PRB03.1 PRB08.1
N29179461: PCB70.1 PQB12.5 PRB02.1
N29179506: PCB01.2 PQB03.1 PQB11.4 PQB12.4 PRB07.1
N33029358: RA32.2 UA1.10
N33029552: CA487.2 RA50.1
N33029645: CA478.1 RA31.2 RA48.1
N33495776: JHDT1.13 RH3.2
N33495778: JHDT1.15 RH4.2
N33495792: JHDT1.11 RH2.2
N33497375: RC30.2 T12.1(TP-1)
N33500586: T17.1(TP-1) UC1.AY16
N33500588: T16.1(TP-1) UC1.BA13
N33500590: T15.1(TP-1) UC1.BA16
N33500707: T14.1(TP-1) UC1.AY15
N33501029: T13.1(TP-1) UC1.BA14
N33501291: CC16.1 RC63.2 RC65.2 RC67.1 UC13.1 UC13.2
N33501698: T25.1(TP-1) UC1.AY14
N33504981: RC107.2 UC1.BA25
N33505212: RC109.2 UC1.BA24
N33518659: JDIMM1.143 RD4.2
N33520030: JDIMM1.116 RD1.2
N33523233: RV3.2 UV1.3
N33524727: QV1.1 RV16.2 RV17.2 RV18.2 RV19.2 RV20.2 RV21.2 RV34.2 RV35.2
N33525049: QV2.2 RV30.1
N33527050: JWLAN1.48 T19.1(TP-1)
N33527052: JWLAN1.46 T24.1(TP-1)
N33527054: JWLAN1.44 T23.1(TP-1)
N33528036: DA10.2 RA52.1
N33528038: DA10.3 RA53.1
N33534280: C9.1 Q3.3 R28.2
N33534316: Q6.1 R32.1
N33537088: JKB1.30 R39.2 R41.1
N33537136: JKB1.1 RE43.2
N33538511: LED1.2 R40.1
N33538529: LED1.4 R43.1
N33538830: Q14.5 Q14.6 R50.2
N33539236: JKBBL1.2 R30.2
N33547368: QS1.5 QS1.6 RS25.2
N33548334: JSSD1.10 RS27.1
N33548545: JSSD1.8 RS26.1
N33548604: JSSD1.38 RS28.1
N33562066: Q16.1 R56.2
N33562240: Q15.2 Q15.3 R55.1
N33563792: R64.2 R68.2 U6.3
N33563833: Q18.1 R71.2
N33563843: Q20.1 R72.2
N33563845: Q18.3 Q19.3
N33563855: Q20.3 Q21.3
N33563865: C37.1 C38.1 C39.1 C40.1 C44.1 Q19.1 Q21.1 R73.1
N33564171: R61.1 U6.7 U6.8
N33564185: C46.1 R63.1 R65.1 U6.6
N33564230: C47.1 R66.1 R67.1 U6.5
N33566966: RE48.1 UE1.76
N33567076: CE8.1 RE11.2
N33568379: RE36.1 UE1.125
N34251929: T26.1(TP-1) UC1.AP23
N34251932: T27.1(TP-1) UC1.AP25
N34251935: T28.1(TP-1) UC1.AR25
N34251938: T29.1(TP-1) UC1.AV25
N34368532: C17.1 U2.12
N34368546: C24.1 U2.10
N34368727: C20.2 U3.12
N34582676: RE20.1 UE1.97
N34587636: RL10.2 UL2.3
N34587774: TP53.1(TP-1) UL1.27
N34587776: TP54.1(TP-1) UL1.25
N34587780: RL6.2 UL1.26
N34587808: RL7.2 UL1.31
N35139402: CC121.1 RC128.1
N35174703: PQB33.1 PRB42.2 PRB43.1
N35174707: PCB36.1 PQB32.2 PRB43.2
N35501849: RS6.2 US1.20
N35501851: RS5.2 US1.10
N35711175: RE53.1 UE1.92
N35713947: RL16.1 RL17.1 UL1.19
N38653708: PRH05.2 PUH01.7
N39173777: PCH10.1 PUH01.9
N39173785: PCH11.1 PRH11.2 PUH01.11
N39200796: PRM06.2 PUM01.10
N39291721: PQ13.3 PR32.2
N39393826: PQB03.2 PRB03.2 PRB04.1
N39406703: PRB31.2 PUB01.29
N39655859: PD501.1 PR507.2
N39825950: PRZ81.2 PUZ01.13
N39825993: PRZ16.2 PUZ01.1
N39826003: PHZ3.2 PRZ80.1 PRZ87.2
N39826010: PCZ07.2 PRZ07.1
N39826022: PCZ08.1 PRZ00.2 PRZ03.2 PRZ04.1 PRZ07.2 PUZ01.37
N39826039: PCZ07.1 PCZ10.2 PRZ03.1 PRZ06.2 PUZ01.38
N39826047: PCZ61.2 PRZ66.2 PUZ01.15
N39826052: PCZ15.1 PRZ15.2
N39826074: PCZ61.1 PRZ72.2
N39826078: PCZ63.1 PRZ26.1 PUZ01.25
N39826110: PCZ15.2 PRZ13.2 PUZ01.39
N39826159: PRZ80.2 PUZ01.11
N39826167: PCZ59.1 PCZ60.1 PRZ47.1 PRZ75.1 PUZ01.16
N39826173: PCZ58.1 PRZ69.1 PUZ01.17
N39826315: PCZ06.2 PCZ08.2 PRZ05.1 PUZ01.36
N39826443: PCZ06.1 PRZ04.2
N39826445: PCZ04.2 PRZ00.1
N39826475: PCZ68.1 PRZ47.2 PRZ65.1 PRZ73.2 PRZ77.1 PUZ01.18
N39826481: PCZ60.2 PRZ73.1
N39826485: PCZ37.1 PRZ65.2
N39826489: PCZ57.2 PCZ68.2 PRZ78.1 PUZ01.19
N39826495: PCZ57.1 PRZ77.2
N39826560: PHZ1.1 PRZ09.2
N39826575: PHZ4.1 PRZ79.2
N39826587: PHZ2.2 PRZ16.1 PRZ86.2
N39839956: PR1803.2 PU1801.4
N39865555: PCM17.2 PCM18.1 PRM10.2 PRM13.1 PRM14.1
N39865992: PRH08.2 PRH13.1 PRH14.1
N40401450: PQH01.2 PRH20.1
N40405759: PQH01.1 PRH14.2
N48572179: PCH14.2 PRH12.1

Pads without a net: DC1 3; DC3 3; DD1 3; DD2 3; ED3 2; EU2 2; FD1 1; FD2 1; FD3 1; FD4 1; JDIMM1 87 88 91 92 95 96 97 100 101 104 105 162 165; JEDP1 5 6 9 14 26; JHDMI1 13 14; JKB1 28 29; JKBBL1 3; JSSD1 5 6 7 11 12 13 17 19 20 22 23 24 25 26 28 30 32 34 36 40 42 44 46 48 56 58 67 68 69; JWLAN1 6 8 9 10 11 12 14 15 16 17 20 21 22 23 32 34 36 42 58 59 60 61 62 64 65 66 67 68 70 71 73; PD1 3; PD6 3; PJPDC1 4; PU301 10 15; PU501 10; PU1801 1 7; PU2501 1 5; PUB01 30; PUZ01 27 28 29 30 35; RPC1 4 5; RPC2 1 8; RPC4 4; RPC7 4 5; RPH2 1 8; TL1 4 5 12 13; TL2 4 5 12 13; U3 5 6 7 8 9 10; UC1 A4 A5 A6 A7 A11 A12 A19 A20 A21 A22 AA37 AA38 AB1 AD1 AE34 AE37 AE38 AH1 AJ34 AK1 AK2 AL8 AL34 AM15 AM17 AM19 AN8 AN34 AP13 AP15 AP17 AP19 AP21 AR13 AR15 AR17 AR21 AR29 AR38 AU4 AU13 AU15 AU17 AU23 AU27 AV7 AV9 AV11 AV13 AV15 AV17 AV21 AV23 AV35 AY3 AY7 AY18 B4 B5 B6 B7 B11 B12 B19 B20 B21 B22 BA27 D7 D11 D13 D19 E4 E7 E31 G4 G5 G19 H1 H2 H11 H13 H19 J1 J2 J4 J5 J37 L4 L5 L11 L34 T1 T2 V1 V2; UC9 1; UC10 1; UC11 1; UC12 1; UE1 14 18 68 85 86 102 117 119 120 126 128; UW1 3; YC2 2 4; YE1 1

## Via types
v1: diameter 0.457, hole 0.203, TOP to BOTTOM, 3851 vias
v2: diameter 0.305, hole 0.152, TOP to BOTTOM, 429 vias
v3: diameter 0.508, hole 0.254, TOP to BOTTOM, 60 vias
v4: diameter 0.406, hole 0.203, TOP to BOTTOM, 183 vias

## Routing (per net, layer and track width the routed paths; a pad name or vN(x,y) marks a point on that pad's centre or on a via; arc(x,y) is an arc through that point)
0.95VS_GATE: length 6.1
  TOP w0.102: Q17.1 148.5,58.66 R58.2 148.57,59.46 C35.1 ; C35.1 v1(149.18,59.49) ; C35.1 148.54,59.69 v2(147.85,60.37)
  BOTTOM w0.102: v1(149.18,59.49) 149.2,59.49 149.64,59.94 U4.4
0.95VS_PWR_EN#: length 168.9
  TOP w0.102: RE24.1 56.93,84.64 57.95,83.62 57.95,82.48 57.44,81.97 v1(57.44,81.53) ; v1(130.84,43.87) 130.84,44 130.12,44.72 129.26,44.72 128.65,45.33 126.15,45.33 125.65,44.84 120.61,44.84 119.03,46.41 118.21,46.41 117.57,45.78 v1(116.05,45.78) ; v1(141.04,61.84) 141.51,61.84 v2(145.39,57.97) 147.53,55.82 Q17.2 148.65,53.78 150.48,53.78 Q16.2
  TOP w0.203: v1(47.66,80.83) 48.93,82.1 UE1.99
  IN1 w0.127: v1(130.84,43.87) 130.84,44.3 133.99,47.45 133.99,47.72 133.94,47.77 133.94,50.62 141.19,57.87 141.19,61.69 v1(141.04,61.84)
  IN2 w0.127: v1(47.66,80.83) 47.89,81.06 53.16,81.06 53.69,81.59 57.37,81.59 v1(57.44,81.53) 58.77,81.53 59.72,82.48 60.68,82.48 61.97,81.19 61.97,74.89 62.99,73.87 62.99,61.82 64.99,59.81 69.08,59.81 70.6,58.29 70.6,54.71 71.09,54.22 71.09,49.34 71.7,48.74 71.7,47.09 72.06,46.73 72.06,44.65 72.39,44.32 73.23,44.32 74.62,42.92 86.95,42.92 89.58,45.55 100.52,45.55 101.51,46.54 102.21,46.54 102.97,47.3 107.22,47.3 108.17,46.35 110.78,46.35 111.01,46.12 115.71,46.12 v1(116.05,45.78)
0.775VALW_GATE: length 18.2
  TOP w0.127: v1(134.72,37.27) 135.16,36.83 v2(135.23,36.83) 135.99,36.83 v1(136.43,37.27)
  BOTTOM w0.102: Q20.2 129.11,37.48 130.02,36.57 130.02,35.34 130.92,34.44 132.48,34.44 133.26,35.22 133.26,35.51 133.63,35.87 R59.1 133.63,35.92 133.99,36.29 134.04,36.29 134.72,36.97 v1(134.72,37.27) 134.72,37.33 134.57,37.48 Q21.2 ; U5.7 141.19,37.9 140.62,37.33 139.73,37.33 139.54,37.52 136.69,37.52 v1(136.43,37.27)
1.8VS_GATE: length 3.6
  TOP w0.102: U3.3 155.78,44.27 155.76,44.25 R52.2 155.05,43.47 C21.2 v2(155.01,42.5)
3VS_GATE: length 7.1
  TOP w0.102: v2(30.9,62.44) 30.87,62.42 C25.2 31.26,60.76 R53.2 32.33,60.56 32.11,60.34 32.11,57.45 32.2,57.37 U2.5
3VS_LS:
  vias: v2(28.98,54.1)
5VS:
  vias: v2(35.63,54.63)
5VS_GATE: length 4.6
  TOP w0.102: U2.3 33,57.22 33.07,57.29 33.07,58.43 v2(33.16,58.52) 33.21,58.57 33.21,59.36 C16.2 33.09,60.31 R51.2
+0.6V_DDR_VTT: length 57.9
  IN2 w1.016: 58.33,109.66 57.48,108.81 57.48,91.2 59.37,89.31 59.37,86.38 60,85.75 65.81,85.75 66.77,84.78 66.77,67.18 66.01,66.42 66.01,62.23
  BOTTOM w0.203: v1(69.07,47.06) 69.28,46.86 69.28,46.26 69.55,45.99 70.84,45.99
  vias: v1(59.41,110.49) v1(59.41,109.85) v1(65.76,61.21) v1(66.39,61.21) v1(66.53,49.37) v1(67.17,49.9) v4(66.53,47.42)
+0.6VSP: length 3.3
  TOP w0.102: v2(61.36,112.81) 61.25,112.7 v1(61.25,112.26)
  TOP w0.508: v1(61.25,112.26) 61.25,111.37 61.44,111.18 v1(61.44,110.55)
  BOTTOM w0.203: PUM01.2 61.48,112.5 v1(61.25,112.26)
  vias: v1(61.44,109.91)
+0.95VALW: length 55.7
  TOP w0.254: v1(149.32,79.5) 149.13,79.69 v4(147.86,79.69) 147.16,80.4 147.16,81.38 146.39,82.14 RC106.2
  IN1 w0.254: v1(149.32,79.5) 149.32,79.58 149.07,79.83 146.43,79.83 146.14,79.54 140.86,79.54 140.13,78.81 131.63,78.81 130.9,78.08 130.9,76.76 130.34,76.2 130.34,75.99 130.21,75.86 130.21,75.8 v1(129.89,75.48)
  IN1 w0.508: v1(129.32,49.44) 138.08,58.2 138.08,64.51 137.82,64.77 137.82,67.66 v1(137.75,67.72)
  IN2 w0.508: v1(129.32,49.44) 129.28,49.4 129.28,48.33 127.53,46.58 127.53,45.13 126.97,44.57 v1(126.78,44.57)
  vias: v1(126.91,44) v1(129.87,74.49) v1(130.69,74.44) v1(151.55,70.92) v1(151.55,70.29) v1(152.12,71.43) v1(152.18,70.61) v1(152.75,71.81) v1(152.75,71.05)
+0.95VALWP: length 16
  TOP w0.254: v1(168.47,67.37) 168.75,67.37 169.41,66.71 PRH13.2
  IN2 w0.254: 158.28,69.21 159.42,70.35 167.48,70.35 168.47,69.36 v1(168.47,67.37)
  BOTTOM w0.254: v1(168.47,67.37) 168.47,66.98 PCH14.1
  vias: v1(156.94,69.72) v1(156.94,69.08) v1(157.58,71.12) v1(157.58,70.48) v1(157.58,69.85) v1(157.56,69.22)
+0.95VS: length 25
  TOP w0.254: RC103.2 129.13,71.92 v1(128.99,71.78)
  IN1 w0.254: v1(128.99,71.78) 127.05,71.78 126.42,72.4 125.45,72.4 125.32,72.27 124.39,72.27 123.98,71.86 123.41,71.86 122.84,71.29 121.95,71.29 121.59,71.65 121.16,71.65 120.8,71.29 120.8,67.03 119.66,65.89 119.66,65.63 116.74,62.71 116.74,61.16 117.63,60.27 117.63,59.24 117.88,58.99 v1(118.09,58.99)
  vias: v1(101.69,52.55) v1(101.69,51.86) v1(102.33,52.55) v1(102.33,51.86) v1(102.96,52.55) v1(102.96,51.86) v1(103.66,52.55) v1(103.66,51.86) v1(104.36,52.55) v1(104.36,51.86) v1(104.99,52.55) v1(104.99,51.86) v1(105.69,52.55) v1(105.69,51.86) v1(150.68,59.69) v1(150.87,58.92) v1(151.32,59.69) v1(151.35,58.16) v1(151.51,58.92) v1(151.95,59.69) v1(151.99,58.16) v1(152.14,58.92) v1(152.59,59.69) v1(152.62,58.16) v1(152.78,58.92) v1(153.22,59.69) v1(153.26,58.16) v1(153.41,58.92) v4(97.56,53.48)
+0.95VS_APU_GFX: length 26.4
  TOP w0.508: v1(146.29,81.51) 146.27,81.48 145.94,81.48 RC1.1
  IN1 w0.254: v1(123.73,75.71) 123.73,76.45 124.11,76.83 124.62,76.83 125.17,77.38 125.17,77.73 126.18,78.74 128.57,78.74 129.29,79.45 129.29,79.72 129.63,80.06 129.89,80.06 130.94,81.1 139.85,81.1 140.26,81.51 v1(146.29,81.51)
  vias: v1(120.8,74.53) v1(121.71,75.21) v1(121.67,74.51) v1(122.74,75.69) v1(122.74,75.13) v1(122.72,74.48) v1(123.72,75.16) v1(124.42,75.41) v1(124.98,75.43) v4(98.98,65.44)
+0.775VALW: length 46
  TOP w0.508: v1(148.69,37.4) v4(141.56,37.4) 138.72,37.4 136.05,34.73 133.61,34.73 v1(132.8,35.54) 132.47,35.87 127.1,35.87 126.02,36.95 125,36.95 122.84,34.79 120.62,34.79 119.54,35.87 119.54,37.59 118.53,38.6
  BOTTOM w0.508: 119.54,40 121.57,40 122.14,40.57 122.14,41.59 122.53,41.97 123.51,41.97 124.73,43.19 R64.1 ; C43.1 131.24,35.14 R72.1 132.36,35.14 132.76,35.54 132.8,35.54 v1(132.8,35.54)
  vias: v1(118.14,39.24) v1(118.84,39.24)
+1.2V_DDR: length 82.7
  TOP w0.254: CD7.1 72.82,73.7 v1(73.32,74.19) ; RD2.2 70.54,69.61 CD5.1
  TOP w0.508: CC25.1 104.99,97.6 v1(105,97.59) ; CC30.1 v1(91.57,88.11) ; CD5.1 72.31,70.52 v1(72.35,70.49) ; CD24.1 72.03,77.51 72.42,77.12 v1(72.42,77.08) ; v1(90.3,88.13) CC23.1 ; CD30.1 71.45,78.5 CD9.1 72.68,78.33 v1(72.76,78.41) ; v1(103.09,97.59) 102.9,97.79 CC62.1 ; v1(87,88.2) CC24.1 ; CC33.1 v1(88.65,88.13) ; CC60.1 103.91,97.6 v1(103.92,97.59) ; v1(101.88,97.59) CC61.1 ; CC64.1 v1(106.07,97.59) ; v1(85.73,88.2) CC34.1 ; CC38.1 v1(92.71,88.07)
  BOTTOM w0.254: UC1.AE35 117.53,77.71 117.04,77.25 v1(117.03,77.16) ; JDIMM1.148 72.25,73.49 72.39,73.63 72.76,73.63 v1(73.32,74.19) ; UC1.AR35 v1(118.09,72.67) ; JDIMM1.130 71.93,79.99 72.04,79.88 72.76,79.88 v1(73.42,79.22) ; UC1.AL37 116.83,74.26 v1(117.23,73.86) 118.04,73.86 v1(118.07,73.83) ; v1(80.47,77.2) 80.43,77.24 JDIMM1.141 ; v1(72.41,71.57) 71.99,71.99 JDIMM1.154 ; v1(117.23,87.06) 117.63,86.66 UC1.J35 ; JDIMM1.159 78.07,70.74 77.89,70.92 77.89,71.5 v1(77.76,71.63) 78.37,72.24 JDIMM1.153 ; UC1.L32 v1(118.83,85.96) ; JDIMM1.142 72.32,76.99 72.41,77.08 v1(72.42,77.08)
  BOTTOM w0.279: JDIMM1.163 v1(80.56,69.74)
  BOTTOM w0.305: JDIMM1.117 79.98,83.24 v1(80.44,83.7) ; v1(76.33,80.68) 76.77,80.24 JDIMM1.129 ; v1(80.52,78.71) 80.49,78.74 JDIMM1.135 ; 118.65,73.83 v1(118.07,73.83) ; 118.65,73.83 UC1.AL32 ; 118.65,73.83 118.96,73.51 118.96,73.13 118.58,72.74 118.17,72.74 v1(118.09,72.67) ; JDIMM1.124 71.96,81.49 v1(72.66,80.79) ; v1(117.83,84.86) 117.63,84.66 UC1.N35 v1(117.03,83.76) 116.83,83.56 UC1.R37 ; v1(117.83,80.46) UC1.AA35 ; UC1.AA35 117.58,79.91 v1(117.03,79.36) 116.83,79.16 UC1.AC37 117.31,78.27 v1(117.83,78.26) ; UC1.AA35 117.58,79.92 116.82,80.95 UC1.W37 116.83,81.36 v1(117.03,81.56) UC1.U35 117.63,82.46 v1(117.83,82.66) ; JDIMM1.118 71.76,82.99 72.33,83.56 73.29,83.56 v1(74.08,84.35) ; 118.68,76.06 v1(117.83,76.06) 117.63,75.86 UC1.AJ35 117.08,74.96 v1(116.97,74.96) 116.83,74.82 UC1.AL37 ; 118.68,76.06 UC1.AJ32 ; 118.68,76.06 UC1.AG32 119.23,76.8 v1(118.9,77.13) 118.9,77.37 UC1.AE32 119.19,77.71 v1(118.66,78.24) 118.64,78.26 v1(117.83,78.26) ; v1(117.83,78.26) UC1.AE35 ; v1(76.87,74.29) 77.43,73.74 JDIMM1.147 ; JDIMM1.136 72.68,78.49 v1(72.76,78.41) ; v1(119.45,82.69) 119.23,82.47 UC1.U32 v1(119.44,81.5) 119.23,81.3 UC1.W32 ; JDIMM1.112 v1(72.39,84.49) ; v1(117.03,77.16) 117.03,76.81 UC1.AG37 ; v1(76.67,82.78) 76.67,82.18 77.11,81.74 JDIMM1.123 ; UC1.L37 116.83,85.76 v1(117.03,85.96) UC1.J35 ; v1(80.4,84.74) JDIMM1.111
  BOTTOM w0.4: v1(118.66,78.24) UC1.AC32
  vias: v1(67.73,87.37) v1(67.73,86.74) v1(67.73,86.1) v1(67.73,85.47) v1(67.73,84.83) v1(67.73,84.2) v1(68.61,87.37) v1(68.61,86.74) v1(68.61,86.1) v1(68.61,85.47) v1(68.61,84.83) v1(68.61,84.2) v1(73.42,82.83) v1(73.67,77.13) v1(73.67,72.72) v1(73.77,85.77) v1(73.77,71.55) v1(75.04,82.83) v1(75.04,80.74) v1(75.1,71.55) v1(75.45,85.93) v1(75.96,77.14) v1(76.31,84.3) v1(77.89,69.5) v1(80.84,82.52) v1(81.22,71.22) v1(81.53,80.15) v1(81.79,77.48) v1(82.14,82.52) v1(83.5,68.07) v1(83.57,76.93) v1(84.34,68.07) v1(85.61,68.08) v1(86.98,68.08) v1(87.82,68.69) v1(89.83,68.04) v1(90.78,68) v1(95.4,68.24) v1(102.52,76.05) v1(103.47,76.05) v1(104.48,76.05) v1(115.49,84.95) v1(115.54,80.51) v1(115.54,76.14) v1(115.6,87.21) v1(115.6,82.52) v1(115.68,78.26) v1(116.43,80.46) v1(116.43,78.26) v1(116.37,71.75) v1(116.78,71.31) v1(118.39,74.96) v1(118.59,72.26) v1(119.1,86.48) v1(119.67,79.37) v4(93.01,102.79)
+1.2VP: length 54.4
  TOP w0.254: PCM10.1 57.69,94.29 57.69,110.87 60.93,114.1 v1(60.93,114.17)
  TOP w1.016: 62.26,109.41 60.68,107.82 60.68,105.76 v2(59.51,104.6) 58.62,103.71 58.62,94.76 63.15,90.23 63.15,89.85
  BOTTOM w0.203: v1(60.93,114.17) 60.73,113.97 60.22,113.97 59.93,113.67 PRM14.2 59.99,113.6 60.68,113.6 60.75,113.66 61.25,113.66 61.29,113.7 PUM01.5
  vias: v1(62.45,110.29) v1(63.03,110.55) v1(63.22,87.94) v1(63.22,87.31) v1(63.41,89.15) v1(63.41,88.51)
+1.8V_ALW: length 168.2
  TOP w0.254: v1(137.5,74.59) 137.59,74.67 138.48,74.67 139.75,75.94 140.94,75.94 141.39,75.5 142.59,75.5 143.02,75.92 RC96.1
  TOP w1.016: 129.31,58.01 129.31,54.22 126.6,51.5 ; 28.16,71.18 28.16,68.96 33.15,63.97 33.85,63.97 34.87,62.95 34.87,61.43 38.45,57.84 v4(41.13,57.84) 43.02,57.84 48.26,52.61 48.26,46.25 46.67,44.66 46.67,33.93 45.82,33.08 45.82,25.33 44.99,24.51 42.9,24.51
  TOP w2.286: 145.32,46.67 141.8,43.14 138.05,43.14 137.26,43.94 135.1,43.94 134.02,45.02 132.62,45.02 129.91,47.73 125.24,47.73
  IN1 w0.254: v1(128.97,74.23) 128.97,74.32 129.63,74.98 130.95,74.98 131.51,74.42 137.34,74.42 v1(137.5,74.59)
  IN1 w1.778: 112.81,55.75 111.82,55.75 106.55,50.48 101.25,50.48 98.65,47.87
  BOTTOM w1.016: 43.63,24.33 51.23,24.33 51.47,24.57
  BOTTOM w2.286: 57.12,24.95 62.2,24.95 63.03,25.78 83.66,25.78 87.79,29.9
  vias: v1(42.01,23.64) v1(42.57,23.63) v1(43.12,23.66) v1(95.67,47.24) v1(95.98,47.75) v1(96.3,47.24) v1(96.62,47.75) v1(96.94,47.24) v1(114.9,57.19) v1(115.47,57.19) v1(116.61,53.32) v1(117.25,53.32) v1(149.89,49.21) v1(150.85,49.21) v1(154.78,48.83) v1(155.1,48.32) v1(155.42,48.83) v1(155.74,48.32) v1(156.05,48.83)
+1.8V_AVDD: length 27.2
  TOP w0.102: v4(33.41,21.73) 33.8,21.33 RA35.2
  TOP w0.508: RA35.2 33.64,20.4 v1(32.52,20.4)
  IN2 w0.508: v1(32.52,20.4) 32.52,19.91 32.52,19.91 32.52,18.83 31.15,17.46 31.15,16.06 30.77,15.68 28.36,15.68 26.32,13.65 24.93,13.65 22.91,11.63 22.91,9.19 23.97,8.12 27.4,8.12 27.97,7.55 v1(29.37,7.55)
+1.8V_CPVDD: length 20.8
  TOP w0.102: v4(38.52,20.24) 38.27,20 RA36.2
  IN2 w0.508: v1(37.69,19.05) 38.13,18.6 38.13,12.98 36.13,10.98 35.21,10.98 34.26,10.03 28.29,10.03 26.89,11.43 v1(26.7,11.43)
+1.8V_DVDDIO:
  vias: v4(37.13,14.97)
+1.8VALWP: length 17.3
  IN2 w0.254: v1(166.32,58.56) 166.76,58.56 167.62,57.71 167.62,54.17 165.55,52.1 158.69,52.1 v1(158.15,51.56)
  BOTTOM w0.254: v1(166.32,58.56) 166.59,58.29 PC1807.1 PR1806.1
+1.8VS: length 314.9
  TOP w0.381: QC2.5 60.49,79.24 60.11,79.62 59.53,79.62 59.22,79.31 v1(59.03,79.31) ; v1(124.55,59.41) 124.88,59.08 ; UC9.5 126.47,101.34 v1(126.91,101.34) ; 124.25,58.9 124.3,58.85
  TOP w0.432: QC2.2 60.49,76.77
  TOP w0.483: PRZ23.1 148.27,145.61 148.57,145.92 v1(149.01,145.92)
  TOP w0.508: QC1.2 121.49,99.74 121,99.25 119.8,99.25 118.97,100.07 v1(118.97,100.83) ; 60.49,76.77 59.15,75.43 v1(58.63,75.43) ; v1(120.38,94.42) 120.11,94.15 RC18.1 119.72,93.44 RC25.2 ; RA65.1 39.16,16.05 38.31,16.9 38.31,18.86 39.25,19.8 39.25,21.61 38.96,21.9 ; v1(123.85,94.53) 123.73,94.4 RC24.2 ; RC26.1 131.35,39.19 130.84,39.7 130.84,40.46 129.78,41.52 124.43,41.52 123.22,42.73 v1(123.22,42.92) ; RC17.1 v1(118.39,98.53)
  TOP w1.016: v1(96.11,122.42) 97,121.53 111.54,121.53 v1(112.94,122.93) ; 59.28,40.51 51.79,33.02 51.79,28.57 ; 114.52,138.62 101.06,138.62 96.43,133.98 v1(96.43,133.17)
  IN1 w0.508: v1(126.91,101.34) 126.91,102.99 125.64,104.26 ; v1(125.74,46.01) 125.27,46.48 125.27,51.93 129.28,55.95 129.28,57.64 ; v1(118.97,100.83) 118.97,99.11 v1(118.39,98.53)
  IN1 w1.016: v1(96.11,122.42) 98.08,122.42 99.48,123.82 99.48,128.84 96.43,131.88 v1(96.43,133.17) ; 118.72,109.33 118.72,112.77 112.94,118.55 v1(112.94,122.93)
  IN2 w1.016: 34.83,23.11 34.83,24.8 36.32,26.29 44.44,26.29 44.69,26.54 48.61,26.54
  BOTTOM w0.254: RPH2.7 v1(96.11,122.42)
  BOTTOM w0.508: v1(149.01,145.92) 148.75,145.66 138.21,145.66 137.38,144.84 137.38,143.89 133.19,139.7 v1(116.68,139.7) ; v1(59.98,42.98) 60.42,43.43 60.42,63.75 61.5,64.83 61.5,68.64 58.77,71.37 58.77,75.3 v1(58.63,75.43) 58.26,75.43 57.76,75.94 57.76,78.42 58.65,79.31 v1(59.03,79.31) ; v1(123.22,42.92) 123.22,43.72 124.25,44.74 125.27,44.74 125.78,45.25 125.78,45.97 v1(125.74,46.01) ; 96.43,131.44 v1(96.43,133.17) ; RC33.1 118.51,98.53 v1(118.39,98.53)
  BOTTOM w1.016: 111.41,59.05 105.32,59.05 104.3,58.03 104.3,56.38 102.33,54.41 97.13,54.41 91.54,48.83 91.54,42.6 90.14,41.21 76.81,41.21 ; 72.04,43.72 72.04,43.21 71.03,42.19 68.52,42.19 67.41,43.3 61.12,43.3 ; 82.33,122.74 82.33,127.82 85,130.49 JHDT1.1 ; v1(96.11,122.42) 96.09,122.45 85.47,122.45
  vias: v1(34.45,22.28) v1(34.9,21.9) v1(51.02,27.3) v1(51.79,27.3) v1(60.36,42.48) v1(119.48,109.02) v1(119.46,108.33) v1(119.46,104.87) v1(120.11,104.88) v1(124.55,60.05) v1(125.19,105.41) v1(125.19,104.83) v1(125.95,60.05) v1(125.95,59.41) v1(127.69,75.5) v1(127.69,74.42) v1(128.04,59.13) v1(128.04,58.52) v1(133.57,59.11) v1(133.57,58.46) v1(134.27,59.11) v1(134.27,58.46) v4(59.88,41.88)
+1.8VS_LS:
  vias: v2(159.83,46.82)
+2.5V_MEM: length 49.2
  TOP w0.508: DD1.2 70.42,42.99 v1(70.7,43.26) 71.07,43.26 73.12,41.21 v4(76.17,41.21) 77.5,42.54 77.5,45.15 v1(77.74,45.39) 78.46,46.11 CD40.1 CD41.1
  BOTTOM w0.254: 77.74,45.49 77.74,45.79 78.19,46.24 JDIMM1.257 ; 77.74,45.49 v1(77.74,45.39) ; 77.74,45.49 77.99,45.74 JDIMM1.259
  BOTTOM w0.762: v1(70.7,43.26) 69.16,43.26 66.71,45.72 66.71,48.13 64.36,50.48 64.36,69.46
+2.5VP: length 0.9
  BOTTOM w0.102: 64.85,71.67 v2(65.77,71.67)
+3V_DVDD: length 10.8
  TOP w0.102: v1(34.77,18.6) 34.92,18.6 35.42,19.1 v4(35.42,19.16)
  TOP w0.305: RA40.2 34.65,18.49 v1(34.77,18.6)
  IN1 w0.305: v1(34.77,18.6) 34.69,18.52 34.69,10.55 v1(35.47,9.77)
+3VALW: length 411.6
  TOP w0.254: RPC6.8 121.16,62.64 v1(121.45,62.35) 121.45,62.33 121.25,62.14 RPC6.7 ; v1(126.54,74.42) 126.33,74.21 126.33,70.14 125.82,69.64
  TOP w0.508: 154.28,78.04 152.36,79.95 v1(152.36,80.01) ; 154.28,78.04 v1(158.59,78.04) v4(161.34,78.04) 172.31,67.07 172.31,62.92 v4(170.4,61.02) 170.26,60.88 v1(170.26,58.24) ; 154.28,78.04 154.28,76.07 v1(152.24,74.04) 152.24,73.72 151.23,72.7 149.39,72.7 149.11,72.43 RC55.2 ; RC82.1 RC79.1 144.62,74.59 v1(144.22,74.59) ; v1(109.19,45.14) 107.22,47.11 RC59.2 v1(105.08,47.94) ; PR33.1 170.91,55.75 v1(170.26,56.4) ; v1(30.07,71.69) 30.9,71.69 31.37,71.21 RE17.2 ; v1(165.45,59.91) 166.43,60.88 166.43,62.25 166.59,62.42 166.59,62.47 166.73,62.61 PRH05.1 ; RC44.1 RE18.2 42.05,86.97 v1(41.5,86.42) ; PRB42.1 198.87,55.95 v1(199.36,56.45) ; RA41.2 v1(29.69,22.16) ; RE3.2 30.45,76.67 v1(31.38,77.59) ; RC70.1 146.06,77.34 v1(146.39,77.34) ; PR41.2 164.74,41 163.78,41.97 163.78,45.43 163.21,46 v1(162.95,46) ; PR5.2 83.75,148.57 v1(84.24,148.08) ; RC80.1 144.79,70.76 v1(144.77,70.74) ; RL10.1 v1(42.12,46.55) ; v1(31.1,75.1) 31.52,75.1 31.54,75.12 RE19.1 ; UC13.5 v1(97.68,49.21)
  IN1 w0.381: v1(141.64,77.16) 141.55,77.26 135.1,77.26 v1(135,77.16)
  IN1 w0.508: v1(84.24,148.08) 84.24,148.01 84.93,147.32 84.93,127.38 83.92,126.36 v1(83.35,126.36) ; v1(30.65,58.37) 30.65,58.87 31.76,59.98 31.76,61.04 30.26,62.54 30.26,67.94 30.01,68.19 30.01,71.62 v1(30.07,71.69) ; v1(146.39,73.89) 146.52,74.02 152.22,74.02 v1(152.24,74.04) ; v1(19.27,123.15) 20.27,123.15 22.01,121.41 28.55,121.41 32.86,125.73 60.07,125.73 v1(63.74,129.4) ; v1(42.77,50.35) 42.96,50.16 42.96,47.39 v1(42.12,46.55) 42.12,35.92 40.55,34.35 33.24,34.35 31.59,32.7 v1(31.59,32.06) ; v1(199.36,56.45) 207.87,56.45 210.73,53.59 211.62,53.59 212.89,52.32 220.57,52.32 224.32,56.07 224.32,62.54 v1(224.89,63.11) ; v1(41.5,86.42) 41.82,86.74 45.82,86.74 46.33,86.23 48.87,86.23 49.63,85.47 51.15,85.47 52.93,83.69 v1(52.93,83.62)
  IN1 w1.016: 31.28,56.31 31.28,55.62 32.1,54.8 33.24,54.8 38.39,49.65 41.37,49.65
  IN2 w0.381: v1(126.54,74.42) 126.54,72.85 127.03,72.36 130.46,72.36 131.77,71.05 135.17,71.05 135.6,71.48 135.6,76.56 v1(135,77.16)
  IN2 w0.508: v1(29.69,22.16) 29.69,30.41 31.34,32.06 v1(31.59,32.06) ; v1(31.38,77.59) 30.7,76.92 30.7,75.88 31.1,75.48 v1(31.1,75.1) 30.07,74.07 v1(30.07,71.69) ; v1(172.18,57.46) 173.2,58.48 174.19,58.48 174.83,59.11 176.35,59.11 177.05,59.81 187.89,59.81 188.27,59.43 191.97,59.43 192.71,60.17 195.64,60.17 v1(199.36,56.45)
  BOTTOM w0.254: UC1.AJ17 UC1.AL19 126.23,74.73 126.29,74.68 v1(126.54,74.42)
  BOTTOM w0.381: R28.1 108.73,44.69 v1(109.19,45.14)
  BOTTOM w0.508: v1(161.6,50.36) 161.6,47.25 162.86,46 v1(162.95,46) ; RC72.1 RC71.1 146.39,78.23 v1(146.47,78.16) 147.34,78.16 148.25,79.07 RC48.1 RC74.1 ; v1(114.78,36.89) 114.85,36.96 R63.2 116.33,36.96 R57.2 ; RC68.1 RC42.1 152.28,81.01 RC22.1 v1(152.36,80.01) ; v1(42.13,50.35) 42.07,50.41 42.07,51.62 40.97,52.73 40.97,71.14 40.44,71.67 40.44,74.18 40.66,74.4 40.66,75.81 42.32,77.47 42.32,78.03 43.34,79.05 43.34,81.72 43.79,82.16 43.79,83.5 44.8,84.51 44.8,85.28 43.66,86.42 v1(41.5,86.42) ; R78.1 v1(19.27,123.15) ; RC81.1 141.59,77.21 v1(141.64,77.16) ; PR1803.1 v1(162.78,59.11) ; RC69.1 146.32,75.94 v1(146.37,75.9) ; v1(165.45,59.91) 165.48,59.94 PRH03.1 ; v1(105.08,47.94) 105.08,48.24 104.11,49.21 v1(97.68,49.21) ; v1(66.65,116.4) 66.65,116.51 66.19,116.98 PRM06.1 ; RC73.1 146,73.72 146.02,73.74 146.24,73.74 v1(146.39,73.89) ; RC132.2 v1(158.59,78.04)
  vias: v1(28.9,58.35) v1(29.03,57.78) v1(28.99,57.15) v1(29.47,58.35) v1(29.6,57.78) v1(29.56,57.15) v1(30.07,58.35) v1(30.18,57.78) v1(30.2,57.15) v1(30.77,57.78) v1(30.83,57.15) v1(56.3,87.12) v1(56.68,86.67) v1(56.75,87.57) v1(57.13,87.13) v1(57.21,88.03) v1(57.59,87.59) v1(57.67,88.49) v1(58.05,88.04) v1(58.12,88.95) v1(58.5,88.5) v1(65.19,83.24) v1(65.82,83.24) v1(74.6,128.63) v1(75.4,127.16) v1(124.56,66.02) v1(124.75,65.48) v1(142.53,47.62) v1(142.53,47.05) v1(170.26,57.6) v1(170.26,57.03) v4(44.12,50.99)
+3VALW_1.8V:
  vias: v2(169.34,53.07)
+3VALW_2.5V:
  vias: v2(62.63,83.29)
+3VALW_EC: length 279.5
  TOP w0.254: UE1.9 34.79,78.62 34.09,79.33 v1(34.09,79.42)
  TOP w0.457: YE1.4 39.05,89.11 v1(39.47,89.53)
  TOP w0.508: v1(56.55,73.66) 55.76,74.45 RE13.1 RE14.1 ; RE39.2 54.79,71.05 LE1.1 55.56,70.21 v1(55.64,70.29) 55.64,69.6 55.38,69.35 RE5.2 ; RE47.1 29.55,75.89 RE3.1 29.05,77.15 30.29,78.38 v1(30.64,78.38) 31.1,78.84 33.35,78.84 33.93,79.42 v1(34.09,79.42) ; v1(42.26,88.83) 42.26,88.9 42.77,89.4 RE2.1 ; v1(151.67,38.03) 151.66,38.05 151.09,38.05 150.34,38.79 143.16,38.79 141.54,40.42 139.26,40.42 138.31,39.47 UC11.5 ; RE25.2 55.69,81.96 v1(55.41,82.24) ; RE50.1 38.17,65.86 38.17,64.8 v1(37.69,64.32) 39.09,64.32 v4(41.9,61.51) 50.07,53.34 50.07,45.72 47.68,43.33 v1(47.68,42.42) 47.6,42.33 47.6,33.46 46.96,32.82 v1(46.96,32.58)
  IN1 w0.508: v1(151.67,38.03) 151.42,38.03 150.91,37.52 150.91,37.21 145.76,32.05 137.76,32.05 135.58,29.87 124.33,29.87 123.52,29.06 107.97,29.06 107.38,29.65 84.98,29.65 80.38,34.25 67.87,34.25 66.78,35.34 64.31,35.34 58.57,41.08 58.57,41.51 v1(58.33,41.76) ; v1(55.41,82.24) 53.01,84.64 v1(52.95,84.64) 51.42,86.16 49.88,86.16 49.05,86.99 46.71,86.99 46.14,87.55 45.83,87.55 44.55,88.83 v1(42.26,88.83) ; v1(34.31,73.43) 34.13,73.43 30.64,76.92 v1(30.64,78.38) ; v1(34.09,79.42) 36.82,79.42 37.17,79.76 v1(37.23,79.76) 37.38,79.76 37.73,79.42 39.83,79.42 40.86,80.45 v1(40.86,81.91) 40.86,82.14 40.14,82.86 36.36,82.86 34.26,84.96 34.26,86.23 34.04,86.44 34.04,88.31 35.96,90.23 38.77,90.23 v1(39.47,89.53)
  IN2 w0.508: v1(42.26,88.83) 41.75,88.83 40.86,89.72 39.66,89.72 v1(39.47,89.53)
  BOTTOM w0.356: v1(34.09,79.42) 33.89,79.42 33.6,79.71 CE3.1 ; v1(34.31,73.43) 34.3,73.43 CE4.1 33.69,73.15
  BOTTOM w0.457: RE23.2 40.86,81.33 v1(40.86,81.91)
  BOTTOM w0.508: v1(47.68,42.42) 47.97,42.13 52.51,42.13 52.89,41.76 v1(58.33,41.76) ; v1(52.95,84.64) 52.94,84.65 PR9.1 ; v1(55.64,70.29) 55.98,70.29 56.55,70.86 v1(56.55,73.66) 52.61,73.66 51.91,74.35 51.91,78.06 55.38,81.53 55.38,82.22 v1(55.41,82.24) ; 33.69,73.15 33.69,71.69 36.75,68.63 36.75,64.63 37.05,64.32 v1(37.69,64.32) ; UC12.5 v1(46.96,32.58) ; v1(37.23,79.76) 36.89,80.11 RE36.2
+3VALWP: length 59.8
  TOP w0.102: v1(43.79,110.04) v2(43.79,110.65)
  IN1 w0.254: v1(54.38,106.11) 54.16,105.9 54.16,103.45 54.83,102.77 54.83,93.47 54.33,92.96 49.44,92.96 v1(48.48,92.01) ; v1(55.6,104.07) 54.96,104.71 54.96,109.78 v1(52.29,112.45)
  IN2 w0.254: v1(43.79,110.04) 43.14,110.69 43.14,112.95 45.06,114.87 51.02,114.87 52.29,113.59 v1(52.29,112.45)
  BOTTOM w0.254: PU301.14 53.13,107.18 53.56,106.74 PR306.2 54.5,106.24 v1(54.38,106.11) ; 54.2,94.29 55.41,95.5 55.41,103.88 v1(55.6,104.07) ; PR504.1 43.73,109.99 v1(43.79,110.04) ; PR304.1 v1(52.29,112.45)
  vias: v1(48.42,94.23) v1(48.42,93.59) v1(48.42,92.96) v1(48.61,94.86)
+3VLP: length 326.7
  TOP w0.254: v1(171.23,46.03) 170.94,46.03 PC902.1 171.04,46.79 PU900.8
  TOP w0.508: RE44.1 222.87,63.83 222.41,63.37 v1(222.41,62.35) ; v1(144.43,38.1) v4(148.55,38.1) 149.89,38.1 150.66,37.33 158.06,37.33 158.48,37.75 158.48,39.51 160.12,41.14 162.34,41.14 163.17,41.97 163.17,45.18 v1(163.1,45.25) ; v1(41.8,88.22) 43,88.22 RE2.2 43.77,87.45 RE6.1 ; v1(166.54,49.73) 166.58,49.69 PD900.2 ; v1(181.52,45.52) 181.2,45.21 181.2,44 180.43,43.23 PR902.1
  IN1 w0.508: v1(144.43,38.1) 143.12,36.79 137.58,36.79 136.95,36.15 126.84,36.15 125.34,34.65 124.6,34.65 123.98,35.27 123.26,35.27 123.06,35.07 119.82,35.07 119.29,34.54 112.24,34.54 111.61,35.17 106.14,35.17 105.84,34.87 93.81,34.87 89.72,38.96 70.82,38.96 67.79,41.99 67.79,42.25 66.54,43.49 65.29,43.49 64.07,44.72 64.07,52.17 61.44,54.79 61.44,68.09 57.55,71.99 57.07,71.99 55.15,73.91 55.15,77.91 54.81,78.25 54.81,79 54.96,79.15 v1(54.96,79.55) ; 166.53,47.05 165.45,45.97 163.83,45.97 v1(163.1,45.25) ; 166.53,47.05 166.53,49.72 v1(166.54,49.73) ; 166.53,47.05 167.55,46.03 v1(171.23,46.03) ; v1(41.8,88.22) 41.8,87.67 40.8,86.67 40.8,84.56 42.43,82.93 46.13,82.93 v1(46.9,82.16)
  IN2 w0.508: v1(46.9,82.16) 48.11,83.38 51.6,83.38 52.29,84.07 52.29,84.86 v1(53.34,85.9) 55.72,88.29 55.72,102.87 54.74,103.85 v1(54.74,104.05) ; v1(209.84,35.81) 209.84,40.51 209.39,40.95 209.39,44.32 210.23,45.15 210.23,48.29 209.72,48.8 205.88,48.8 202.98,45.91 202.98,44.13 202.47,43.62 199.23,43.62 197.9,44.95 182.03,44.95 181.52,45.46 v1(181.52,45.52) 180.37,44.38 174.09,44.38 172.44,46.03 v1(171.23,46.03)
  BOTTOM w0.508: v1(209.84,35.81) 210.92,34.73 212.82,34.73 215.36,37.27 217.08,37.27 218.41,38.6 221.9,38.6 222.98,39.68 222.98,57.78 222.41,58.35 v1(222.41,62.35) ; 52.36,105.5 53.22,104.64 54.07,104.64 54.66,104.05 v1(54.74,104.05) ; v1(53.34,85.9) 56.03,83.21 56.03,80.86 54.96,79.79 v1(54.96,79.55)
+3VS: length 589.1
  TOP w0.203: v1(150.21,145.92) 149.69,145.92 PRZ21.1
  TOP w0.381: RE15.1 56.88,76.53 57.57,77.21 58.06,77.21 v1(58.44,77.59) 58.01,78.02 58.01,79.76 RE10.1 ; 182.03,42.92 CS2.1 ; CS1.1 190.97,34.72 RS5.1
  TOP w0.508: RV3.1 v1(221.89,56.78) ; RS5.1 v1(190.53,33.97) ; RC8.2 124.24,102.05 v1(124.43,101.86) ; v1(178.47,38.03) 178.47,37.21 v1(180.31,35.36) ; 192.85,37.13 192.86,37.14 192.86,38.69 RS14.2 ; RS4.2 190.22,42.15 v1(189.8,42.57) ; v1(151.55,79.81) 151.29,79.56 151.29,74.1 v1(150.53,73.34) ; RL8.1 27.21,94.8 ; RC122.1 122.73,64.94 RC104.1 ; RE21.1 31.96,74.06 v1(32.29,73.73) ; v1(111.8,40.53) 111.8,41.64 108.56,44.89 108,44.89 107.03,45.86 CS19.1 ; R19.1 R17.1 207.92,48.18 209.52,49.78 v1(209.52,51.05) ; v1(184.21,45.59) 183.93,45.31 RS11.1 RS6.1 182.42,44.97 182.03,44.57 182.03,42.92 180.76,41.65 179.68,41.65 v1(179.1,41.08) ; RS8.1 v1(186.98,33.97) ; 94.65,113.15 105.95,113.15 v1(106.59,113.79) ; RS3.2 v1(183.55,33.97) ; v1(122.65,106.48) 122.72,106.41 RC20.2 RC19.2 ; v1(147.99,81.83) 147.99,82.87 149.13,84.01 151.55,84.01 153.89,86.36 v1(155.48,86.36) ; v1(186.64,45.8) 186.6,45.76 RS12.1 RS10.1 ; RS7.1 v1(189.65,33.97) ; RS9.1 v1(185.33,33.97)
  TOP w1.016: 115.03,61.57 112.48,59.03 103.74,59.03 103.6,58.89
  TOP w2.032: 63.03,123.31 63.03,121.41 66.56,117.87 81.15,117.87 82.39,119.12 v4(86.55,119.12) 90.39,119.12 94.65,114.87 94.65,113.15
  IN1 w0.508: v1(111.73,137.47) 111.73,132.71 106.59,127.57 v1(106.59,113.79) 106.59,109.66 110.96,105.28 111.41,105.28 111.67,105.02 118.4,105.02 ; v1(151.55,79.81) 150.01,79.81 v1(147.99,81.83) ; 118.4,105.02 118.4,106.07 118.81,106.48 v1(122.65,106.48) ; 118.4,105.02 119.48,103.94 123.86,103.94 124.43,103.37 v1(124.43,101.86) 124.43,101.53 125.38,100.58 127.1,100.58 128.81,102.29 132.61,102.29 134.26,100.64 138.25,100.64 141.61,97.28 142.65,97.28 146,93.94 146,92.85 152.48,86.36 v1(155.48,86.36) ; v1(32.59,80.67) 32.8,80.46 32.8,79.62 33.64,78.78 40.91,78.78 v1(40.99,78.86) ; v1(121.57,50.31) 121.57,51.59 v1(122.21,52.23) ; v1(217.45,50.53) 217.33,50.41 216.38,50.41 216.25,50.29 210.28,50.29 v1(209.52,51.05) ; v1(37.24,72.07) 36.8,72.07 36.07,72.8 33.6,72.8 32.66,73.73 v1(32.29,73.73) ; v1(131.85,56.55) 131.59,56.82 v1(130.19,56.82) ; v1(176.31,70.48) 176.44,70.35 176.44,65.82 v1(178.47,63.79) ; v1(192.63,36.51) v1(193.33,36.51)
  IN1 w1.016: 31.09,103.44 31.09,109.28 24.04,116.33 18.58,116.33
  IN2 w0.508: v1(181.06,67.56) 181.06,67.41 180.55,66.9 178.18,66.9 176.31,68.77 v1(176.31,70.48) 176.31,70.69 163.84,83.16 156.35,83.16 154.53,81.34 152.24,81.34 151.73,80.83 151.73,80 v1(151.55,79.81) ; v1(144.56,136.95) 145.07,136.95 145.64,137.52 149.6,137.52 150.39,138.31 150.39,142.63 150.72,142.96 150.72,144.41 150.28,144.86 150.28,145.85 v1(150.21,145.92) ; v1(58.44,77.59) 57.84,78.19 55.67,78.19 55.58,78.1 54.38,78.1 54.26,78.23 47.41,78.23 46.45,79.18 41.31,79.18 v1(40.99,78.86)
  IN2 w1.016: 19.21,116.33 23.97,121.09 24,121.09 29.5,126.59 61.4,126.59 61.44,126.55 ; 49.69,40.24 52.43,40.24 59.41,33.27
  BOTTOM w0.305: v1(76.97,46.45) 77.26,46.74 JDIMM1.255
  BOTTOM w0.381: U1.1 177.79,63.41 178.17,63.79 v1(178.47,63.79)
  BOTTOM w0.508: v1(144.56,136.95) 143.96,137.55 PRZ70.1 111.81,137.55 v1(111.73,137.47) ; R50.1 R49.1 17.48,116.98 v1(17.66,116.8) ; R45.1 181.06,66.57 v1(181.06,67.56) ; v1(120.83,60.13) RC56.2 RC53.1 ; R1.1 128.98,55.6 v1(130.19,56.82) ; v1(147.99,81.83) 148.25,81.57 RC98.1 ; v1(121.57,50.31) 121.57,49.8 121.48,49.71 RC76.1 ; v1(178.47,38.03) 178.47,40.44 v1(179.1,41.08) ; v1(150.53,73.34) 149.89,72.7 147.8,72.7 146.76,71.67 RC34.2 ; RC78.1 118.58,51.74 RC77.1 118.7,52.17 119.25,52.72 v1(120.79,52.72) ; RS25.1 102.66,40.43 102.14,40.95 102.14,44.7 v1(102.52,45.08) 102.9,45.46 102.9,47.68 102.08,48.51 96.74,48.51 v1(96.05,49.21) ; QV3.5 QV3.2 27.15,98.36 28.48,97.02 ; v1(111.8,40.53) 111.82,40.53 R27.1 ; v1(37.24,72.07) 36.99,72.07 36.67,72.39 RE51.2 RE52.2 ; v1(176.31,70.48) 176.17,70.34 176.17,68.6 R46.1 ; v1(184.21,45.59) 184.21,45.46 184.72,44.95 185.79,44.95 v1(186.64,45.8) 186.64,45.54 189.58,42.61 189.76,42.61 v1(189.8,42.57) ; v1(59.65,26.45) 59.89,26.69 v1(59.89,32.41)
  BOTTOM w1.016: 39.34,8.69 39.34,9.46 38.83,9.96 38.83,19.93 37.25,21.52 ; 47.53,39.81 44.42,39.81
  BOTTOM w2.032: 95.98,109.72 97.56,108.14 97.56,63.17 96.05,61.65
  vias: v1(17.62,116.2) v1(27.85,51.76) v1(27.85,51.18) v1(27.85,50.59) v1(27.85,50.01) v1(27.85,49.42) v1(27.85,48.84) v1(27.85,48.26) v1(27.85,47.67) v1(28.55,95.18) v1(29.12,95.18) v1(31.28,102.04) v1(31.28,101.4) v1(31.97,80.77) v1(32.67,84.39) v1(33.24,84.64) v1(33.69,43.11) v1(33.69,42.48) v1(34.32,43.11) v1(34.32,42.48) v1(35.02,43.11) v1(35.02,42.48) v1(35.66,43.11) v1(35.66,42.48) v1(35.78,22.35) v1(36.36,22.34) v1(36.93,22.35) v1(39.09,7.88) v1(39.66,8.5) v1(39.67,7.88) v1(41.56,29.65) v1(42.19,31.11) v1(42.19,30.54) v1(42.19,29.97) v1(42.19,29.33) v1(42.82,31.43) v1(42.82,30.79) v1(42.82,30.16) v1(42.82,29.59) v1(43.04,39.32) v1(43.09,40) v1(48.29,40.24) v1(48.61,39.75) v1(60.49,32.44) v1(62.39,126.23) v1(63.15,126.23) v1(87.74,55.11) v1(88.3,55.52) v1(88.3,54.94) v1(88.86,55.94) v1(88.86,55.35) v1(94.2,111.18) v1(94.97,111.18) v1(102.58,57.93) v1(103.21,57.93) v1(132.55,56.55) v1(212.44,33.08) v1(212.38,32.32) v1(212.95,32.32) v1(213.01,33.08) v1(213.65,33.08) v1(213.58,32.32) v1(217.46,58.92) v1(217.46,58.29) v1(217.46,49.84) v1(217.46,49.21) v1(217.78,51.05) v1(218.09,58.92) v1(218.09,58.29) v1(218.16,50.48) v1(218.16,49.84) v1(218.16,49.21) v1(219.68,28.13) v1(219.68,27.49)
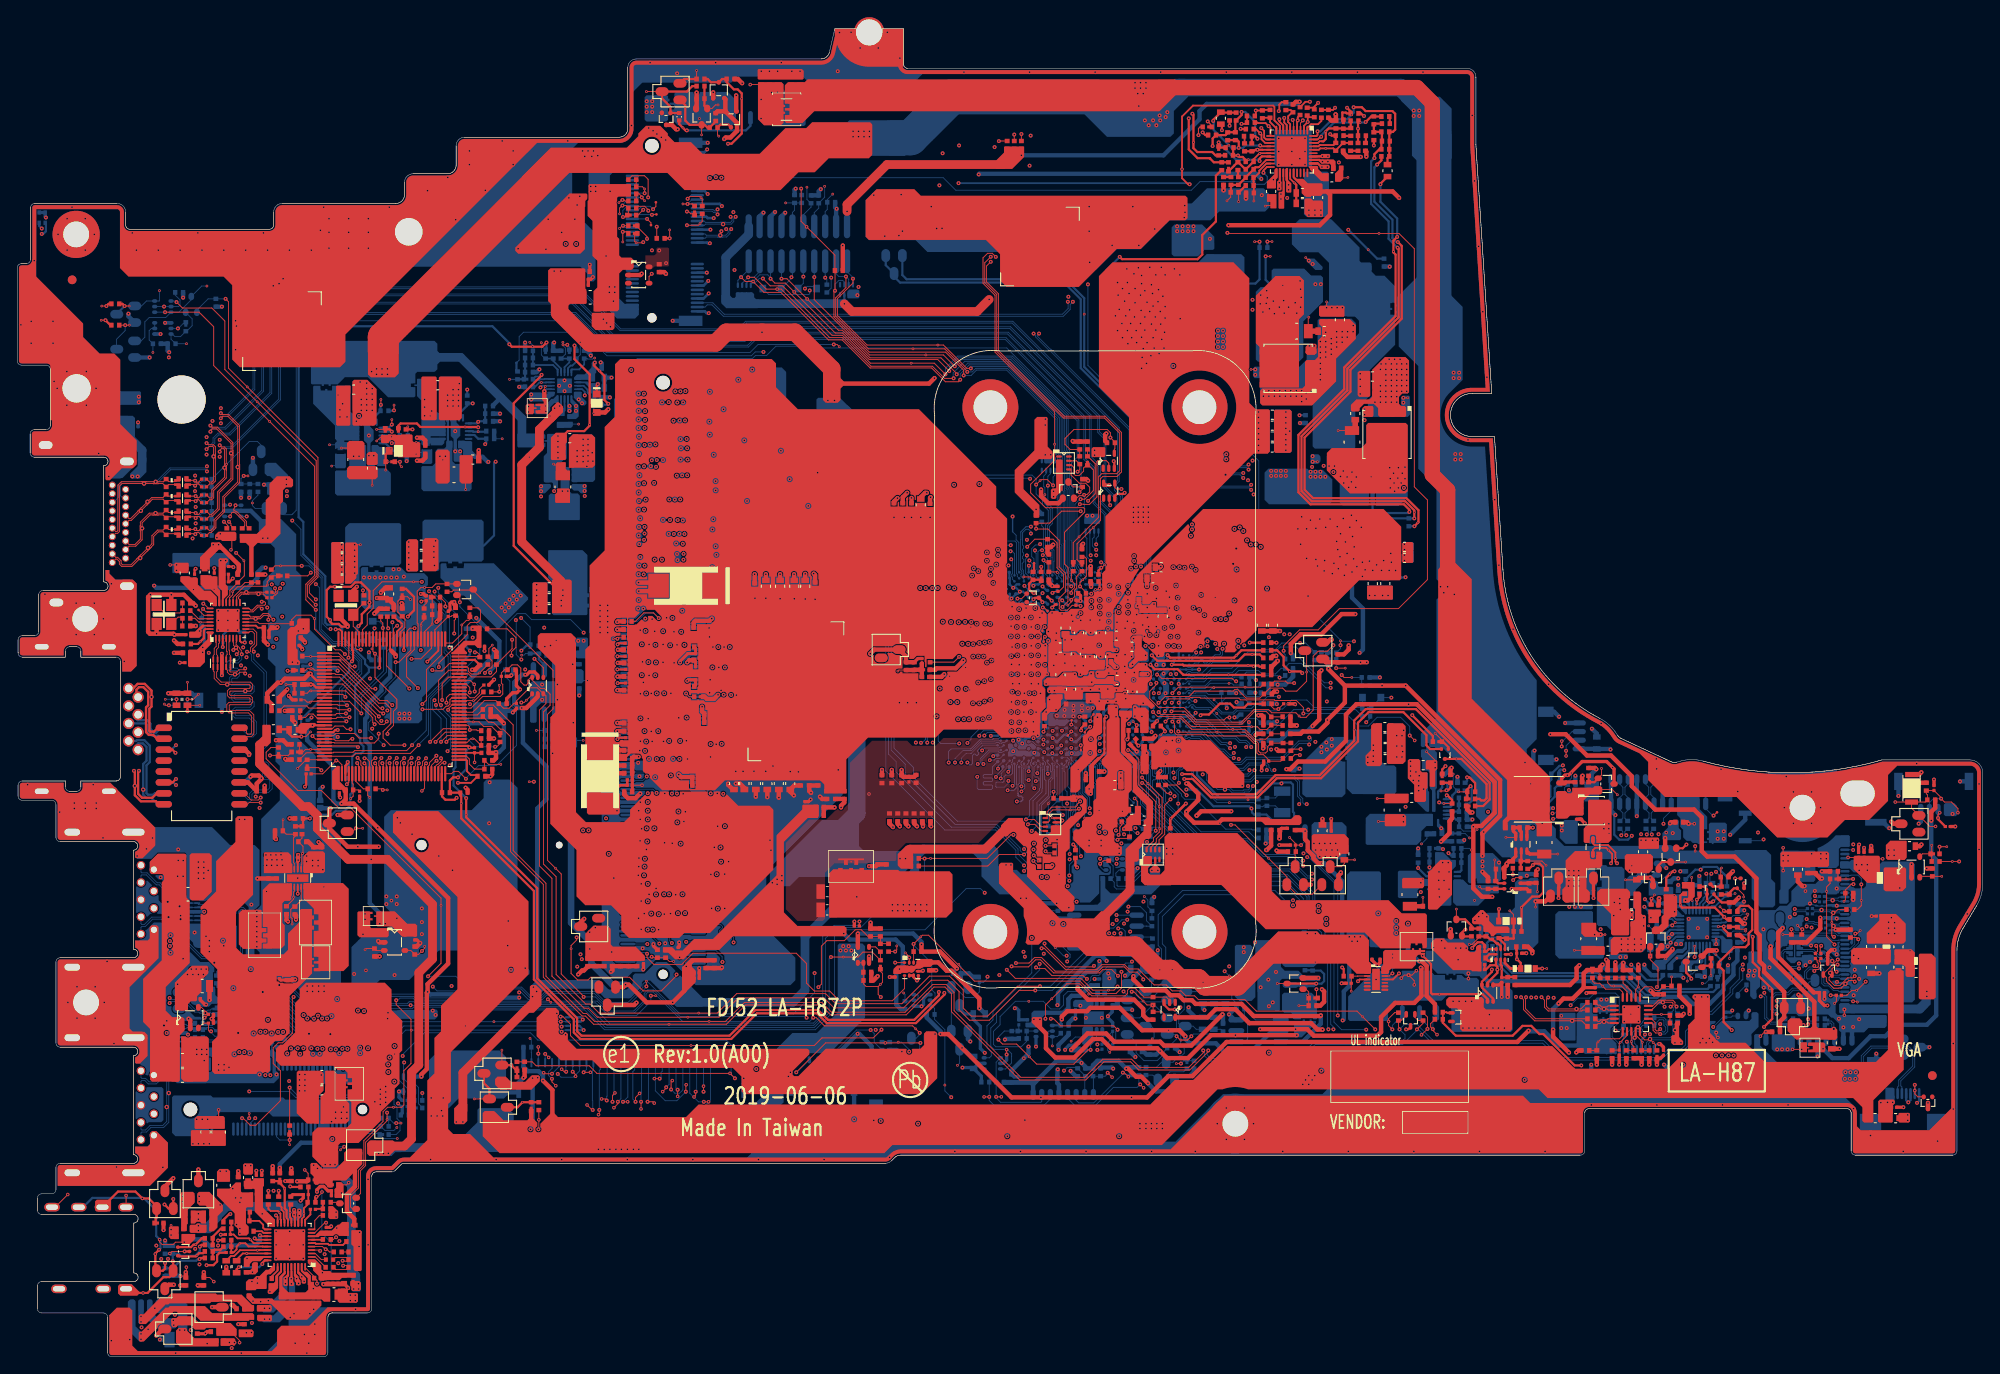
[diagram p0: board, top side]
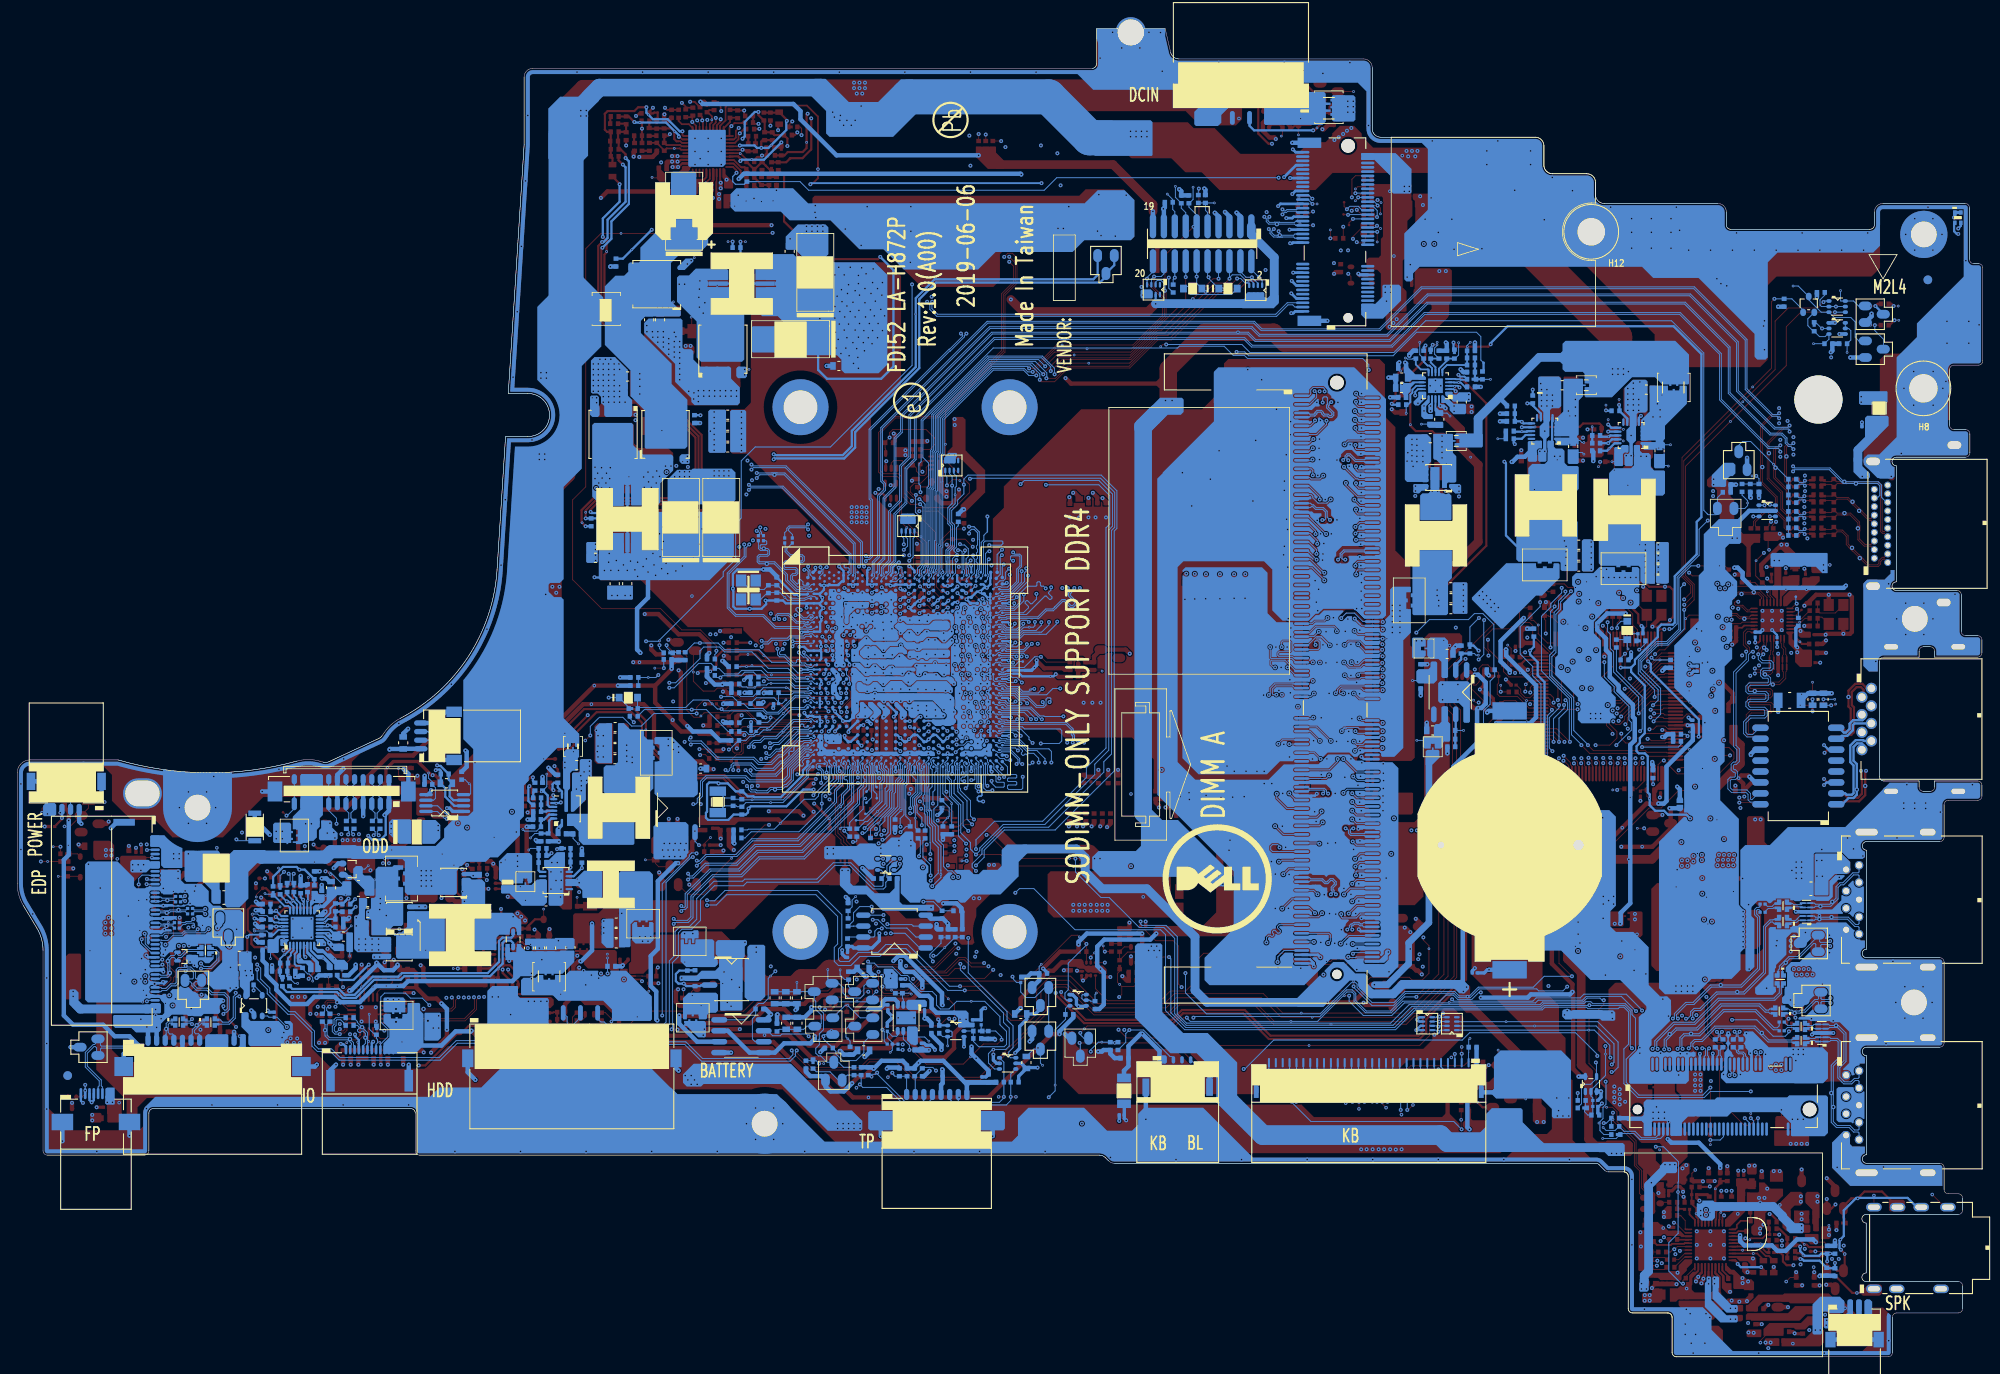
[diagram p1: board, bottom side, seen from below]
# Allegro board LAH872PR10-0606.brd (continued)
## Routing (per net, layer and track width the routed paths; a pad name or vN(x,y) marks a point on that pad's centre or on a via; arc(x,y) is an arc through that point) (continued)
+3VS_APU:
  vias: v1(125.53,74.36) v2(123.29,68.3)
+3VS_CAM: length 1.1
  BOTTOM w0.305: JEDP1.29 213.18,46.45 v1(213.39,46.67)
  vias: v4(213.95,46.3)
+3VS_SSD: length 4.7
  TOP w0.127: CS29.1 v4(23.4,28.71)
  BOTTOM w0.508: RE49.2 41.25,27.74 41.18,27.68 39.28,27.68
  vias: v1(20.86,27.62) v1(21.5,27.62) v1(22.13,27.62) v1(36.99,28.44) v1(36.99,27.74) v1(37.68,28.43) v1(37.68,27.73) v1(38.31,28.43) v1(38.31,27.73) v4(36.52,27.34) v4(37.92,29.05)
+3VS_TOUCH: length 56.9
  TOP w0.102: v1(114.97,35.15) v4(114.97,35.71)
  TOP w0.508: v1(131.39,31.81) 130.64,32.56 130.03,32.56 129.09,33.5 v1(128.88,33.5)
  IN2 w0.381: v1(114.97,35.15) 116.14,35.15 116.95,34.33 123.51,34.33 v1(123.68,34.17)
  IN2 w0.508: v1(114.97,35.15) 112.62,35.15 v1(112.43,35.34) 110.72,33.63 v1(109.84,33.63)
  BOTTOM w0.381: R32.2 111.03,33.63 v1(109.84,33.63) ; R32.2 112.04,32.62 R35.2 ; R32.2 111.72,34.11 Q5.5 ; v1(114.97,35.15) 114.97,34.5 114.59,34.11 Q5.2 ; v1(112.43,35.34) 111.92,35.85 111.92,38.41 111.1,39.24 R27.2 110.09,39.86 109.51,40.44 Q3.1
  BOTTOM w0.508: v1(131.39,31.81) 132.34,30.86 133.89,30.86 134.48,31.44 Q2.2 134.95,32.63 136.24,32.63 136.75,33.14 RE26.2 ; R21.2 115.53,31.94 R33.2 ; R29.2 R23.1 129.04,33.66 v1(128.88,33.5) 127.96,34.41 125.51,34.41 125,33.9 R25.1 R26.1 124.11,33.73 v1(123.68,34.17) 123.43,34.41 120.78,34.41 118.05,31.68 JTP1.8
+3VS_WLAN_NGFF:
  vias: v1(66.65,136.08) v1(66.65,135.5) v1(67.22,136.08) v1(67.22,135.5) v1(68.8,124.39) v1(68.8,123.76) v1(69.44,124.39) v1(69.44,123.76) v4(68.42,127.99) v4(68.89,135.52) v4(69.29,122.74)
+5V_AVDD:
  vias: v4(28.47,16.62)
+5V_HDD: length 84.1
  TOP w0.508: v1(107.29,37.52) 108.17,37.52 v4(109.79,35.91) 115.54,30.16 v4(118.96,30.16) v4(129.49,30.16) 131.29,30.16 133.77,32.63 136.56,32.63 140.53,36.6 174.31,36.6 v1(175.61,37.9)
  BOTTOM w0.508: v1(107.29,37.52) 107.29,37.84 105.69,39.44 RS24.1 ; 181.45,36.19 179.1,36.19 177.45,37.84 175.68,37.84 v1(175.61,37.9)
+5V_HDMI: length 16.8
  TOP w0.102: v4(24.84,93.82) 24.94,93.92 24.94,95.09
  IN1 w1.016: 14.13,100.2 18.07,96.26 18.07,95.65 19.48,94.24 20.93,94.24 22.13,95.44 22.39,95.44
  BOTTOM w1.016: 12.61,107.31 14.51,105.41 14.51,104.2
  vias: v1(13.37,102.36) v1(14,102.36) v1(23.21,95.25) v1(23.59,95.69)
+5V_PVDD:
  vias: v4(34.41,7.93)
+5V_USB_PWR1:
  vias: v1(18.64,55.88) v1(18.7,57.72) v1(19.29,57.69) v1(19.27,55.88) v4(17.38,39.06) v4(18.98,51.29) v4(19.27,46.29)
+5V_USB_PWR2: length 0.7
  TOP w0.102: v1(197.42,37.7) 197.42,37.32 v4(197.62,37.12)
+5VALW: length 273.7
  TOP w0.203: v1(155.8,43.67) 156.01,43.87 U3.4 ; v1(32.65,57.75) 32.6,57.67 U2.4
  TOP w0.508: PR4.1 81.38,144.81 PD3.3 ; PD3.3 83.65,143.45 83.65,142.54 82.88,141.77 82.32,141.77 v1(82.15,141.59) ; PD3.3 82.29,146.22 PD2.3 ; v1(147.48,68.32) 147.93,68.32 148.81,69.21 151.99,69.21 154.4,71.62 154.4,74.67 155.61,75.88 v4(161.68,75.88) 162.64,75.88 171.67,66.84 171.67,63.24 170.15,61.72 169.29,61.72 v1(169.2,61.63) 169.2,54.48 170.19,53.49 v1(171.4,53.49) ; R58.1 146.47,58.73 v1(146.34,58.86)
  IN1 w0.508: v1(82.15,141.59) 81.06,140.5 81.06,140.13 77.94,137.01 77.2,137.01 75.09,134.9 75.09,132.58 74.58,132.08 74.01,132.08 73.61,131.67 72.16,131.67 67.98,127.49 67.98,125.73 67.62,125.37 67.62,123.54 69.8,121.37 69.8,116.91 69.06,116.17 v1(69.06,113.85) 69.06,112.93 69.5,112.48 69.5,92.53 64.35,87.37 64.35,86.78 62.35,84.78 v1(61.24,84.78) 57.61,84.78 51.87,90.52 47.62,90.52 47.43,90.71 v1(44.93,90.71) ; v1(28.86,91.75) 29.14,91.75 29.5,91.39 29.5,90.67 27.66,88.83 27.66,86.74 28.29,86.1 28.29,82.45 28.83,81.91 28.83,74.54 30.7,72.66 30.7,71.5 31.78,70.42 31.78,64.96 33.12,63.62 33.12,58.29 ; v1(146.34,58.86) 146.02,59.18 146.02,61.53 145.13,62.42 145.13,66.65 145.79,67.31 146.97,67.31 147.48,67.81 v1(147.48,68.32)
  IN2 w0.508: v1(12.92,121.28) 15.39,118.82 v1(15.39,116.19) 13.24,114.04 13.24,108.07 14.64,106.68 14.64,91.75 15.91,90.48 v1(15.91,89.66) ; v1(65.31,76.89) 65.31,80.7 v1(61.24,84.78)
  BOTTOM w0.381: C48.1 127.86,40.92
  BOTTOM w0.457: 126.44,41.59 126.08,41.23 U6.4
  BOTTOM w0.508: R54.2 141.45,40.44 v1(140.81,39.81) 141.45,39.17 U5.8 ; v1(135.08,35.42) 134.63,35.87 134.57,35.87 R59.2 ; PRM05.2 PRM04.1 v1(69.06,113.85) ; v1(12.92,121.28) 12.92,120.98 Q8.3 ; v1(121,35.68) 121,36.27 122.18,37.44 R55.2 ; v1(15.91,89.66) 16.16,89.4 26.77,89.4 27.91,90.55 27.91,91.18 28.48,91.75 v1(28.86,91.75) ; PRH11.1 v1(169.2,61.63) ; v1(129.55,40.32) 129.43,40.44 128.24,40.44 127.86,40.83 127.86,41.23 127.5,41.59 126.44,41.59 ; Q9.3 v1(15.39,116.19) ; PR2504.1 v1(65.31,76.89)
  vias: v1(19.78,44.45) v1(20.23,45.08) v1(20.42,44.45) v1(20.8,45.08) v1(21.05,44.45) v1(21.37,45.08) v1(21.64,44.45) v1(21.95,45.08) v1(32.65,58.35) v1(33.63,58.22) v1(33.63,57.59) v1(34.32,57.72) v1(34.32,57.08) v1(34.96,57.72) v1(34.96,57.08) v1(40.29,90.61) v1(40.93,90.61) v1(41.56,90.61) v1(42.2,90.61) v1(42.83,90.61) v1(43.47,90.61) v1(43.72,91.56) v1(44.1,90.61) v1(44.36,91.56) v1(44.41,74.78) v1(44.41,74.2) v1(44.99,74.78) v1(44.99,74.2) v1(45.57,74.78) v1(45.57,74.2) v1(201.14,44.32) v1(201.27,44.89) v1(201.77,44.32) v1(201.9,44.89) v4(18.64,43.32) v4(35.52,56.64)
+5VALW_VDD: length 1
  BOTTOM w0.102: PR2504.2 v2(66.26,78.62)
+5VALWP: length 21.4
  TOP w0.102: v1(39.21,94.42) v2(39.87,94.42)
  IN2 w0.254: v1(39.21,93.09) 42.83,93.09 45.31,95.56 45.31,102.48 43.53,104.26 v1(43.53,106.23)
  BOTTOM w0.254: PU501.14 43.09,106.67 v1(43.53,106.23) PR509.2
  vias: v1(39.21,93.78) v1(39.21,92.45) v1(39.21,91.82) v1(39.21,91.12)
+5VS: length 216.2
  TOP w0.203: v1(144.56,142.87) 144.89,142.54 144.89,141.76 145.12,141.54 PUZ01.12
  TOP w0.508: v1(140.75,131.57) 151.35,131.57 152.55,132.77 152.55,135.13 152.19,135.49 ; v1(61.1,32.11) 62.19,31.02 62.19,27.67 ; R36.1 59.72,27.24 ; PCZ55.1 152.19,135.49 ; 152.19,135.49 159.83,135.49 v1(160.57,134.74)
  IN1 w0.508: v1(160.57,134.74) 160.57,133.67 163.04,131.21 163.04,103.56 164.09,102.51 164.09,81.11 166.72,78.48 176.12,78.48 178.98,75.62 179.18,75.62 183.11,71.7 184.04,71.7 v1(185.14,70.61) 185.14,70.52 187.37,68.28 189.16,68.28 189.91,67.53 196.85,67.53 202.28,62.1 v1(202.28,60.96)
  IN2 w0.508: v1(140.75,131.57) 137.96,134.36 137.96,141.09 138.87,142.01 143.16,142.01 144.03,142.87 v1(144.56,142.87)
  IN2 w1.016: 15.27,109.09 15.27,107.75 16.1,106.93 16.1,92.51 19.13,89.48 19.13,82.99 21.74,80.39 24.05,80.39 26.08,78.35 26.08,63.84 25.94,63.69
  BOTTOM w0.381: v1(99.54,27.49) 99.75,27.71 C5.1 99.75,29.38 F3.1
  BOTTOM w0.508: RE43.1 58.82,33.73 59.34,33.21 60.59,33.21 61.1,32.7 v1(61.1,32.11) ; JFAN1.1 183.53,70.69 C53.1 185.07,70.67 v1(185.14,70.61)
  vias: v1(14.13,111.63) v1(14.13,110.99) v1(21.94,48.89) v1(22.32,48.38) v1(22.32,47.75) v1(22.32,47.11) v1(23.4,33.97) v1(23.4,33.33) v1(24.04,33.97) v1(24.04,33.33) v1(24.61,33.65) v1(25.82,62.48) v1(26.45,62.48) v1(26.51,22.22) v1(27.15,22.22) v1(38.71,7.17) v1(38.71,6.54) v1(39.28,7.17) v1(39.29,6.52) v1(67.53,24.13) v1(68.21,24.1) v1(68.87,24.13) v1(69.57,24.13) v1(70.2,24.13) v1(70.9,24.13) v1(71.6,24.13) v1(72.23,24.13) v1(130.46,27.11) v1(130.46,26.54) v1(131.16,27.11) v1(131.16,26.54) v1(131.8,27.11) v1(131.8,26.54) v1(132.43,27.11) v1(132.43,26.54) v1(133.07,27.11) v1(133.07,26.54) v1(149.39,31.68) v1(149.7,32.19) v1(150.08,32.7) v1(150.08,31.68) v1(150.47,32.19) v1(150.78,32.7) v1(184.06,41.52) v1(184.69,41.52) v1(185.33,41.52) v1(194.98,41.84) v1(195.55,36.51) v1(195.74,41.84) v1(195.87,37.02) v1(196.25,36.51) v1(196.44,41.84) v1(196.63,37.02) v1(197.01,36.57) v1(197.6,61.1) v1(197.6,60.23) v1(198.31,61.1) v1(198.31,60.23) v4(117.09,27.52)
+5VS_KBL: length 9.8
  BOTTOM w0.508: 95.67,34.73 95.67,35.57 v1(97.66,37.56) 97.84,37.56 99.27,36.13 C6.1 99.27,33.79 99.79,33.27 F3.2
+5VS_ODD: length 1.4
  TOP w0.102: v1(194.22,61.97) v4(194.88,61.97)
  TOP w0.508: v1(194.22,61.97) 194.03,62.16 CS20.1
+17.4V_BATT: length 2.6
  TOP w0.102: v2(176.44,52.29) v1(176.44,52.95)
  TOP w0.508: PD14.2 177.55,52.95 v1(176.44,52.95)
+17.4V_BATT+: length 64.1
  TOP w0.102: v1(168.63,44.59) v4(168.63,43.96)
  IN1 w0.508: v1(187.36,56.57) 187.36,55.68 182.66,50.99 182.66,45.67 181.82,44.83 180.56,44.83 180.12,44.38 168.83,44.38 v1(168.63,44.59)
  BOTTOM w0.508: PRB35.1 199.88,46.07 199.42,45.61 199.42,44.38 198.28,43.24 198.28,42.67 196.63,41.02 194.73,41.02 193.9,41.84 191.5,41.84 190.9,41.24 190.83,41.24 188.59,41.24 186.72,43.11 183.55,43.11 182.98,43.68 170.85,43.68 170.28,44.25 170.28,44.45
+17.4V_BATT++: length 3.5
  TOP w0.102: v4(162.34,43.24) 162.34,43.72 v1(161.68,44.38) ; v1(161.68,44.38) 162.07,44.38 v4(162.58,44.89) ; v1(161.68,44.38) 161.18,44.38 v4(160.83,44.03)
+19V_ADPIN: length 1.3
  TOP w0.102: v4(85.17,147.92) PC2.1
  vias: v1(87.66,147) v1(88.35,147.02) v4(86.44,146.19) v4(86.43,143.98)
+19V_VIN: length 205.3
  TOP w0.457: PR36.1 176.5,56.5 v1(176.69,56.69)
  TOP w0.508: PRB09.1 190.76,52.56 190.76,53.27 v1(190.79,53.3)
  TOP w1.778: 166.21,91.05 166.21,100.77 164.44,102.55 164.44,145.79 162.66,147.57 132.56,147.57
  IN1 w0.508: 177.45,57.78 177.01,57.34 177.01,57.01 v1(176.69,56.69) ; 177.45,57.78 177.45,61.78 v1(177.2,62.03) ; 177.45,57.78 184.06,57.78 184.69,58.42 188.5,58.42 190.09,56.83 v1(191.61,56.83)
  IN1 w1.778: 132.37,147.61 163.67,147.61 165.2,146.08 165.2,114.8 164.44,114.04 164.44,104.83 165.83,103.44 165.83,90.74
  IN2 w0.508: v1(191.61,56.83) 191.61,54.15 190.79,53.32 v1(190.79,53.3)
  BOTTOM w0.508: v1(191.61,56.83) 191.09,57.35 PDB01.2
  vias: v1(129.89,148.14) v1(129.89,147.51) v1(130.21,146.87) v1(130.53,148.14) v1(130.53,147.51) v1(130.84,146.87) v1(131.16,148.14) v1(131.16,147.51) v1(165.39,89.53) v1(165.77,88.83) v1(166.21,89.53) v4(130.34,145.42) v4(166.99,88.64) v4(175.21,69.1)
+19VB: length 181
  TOP w0.254: v1(168.28,49.68) 168.23,49.68 167.88,49.33 PD900.3 167.96,48.88 PR906.1
  TOP w3.556: 62.55,138.58 42.52,118.55 42.52,116.97
  IN1 w0.508: v1(168.28,49.68) 168.4,49.79 169.97,49.79 171.13,50.96 171.13,52.1 172.56,53.53 175.29,53.53 176.18,54.41 179.93,54.41 v1(180.25,54.73)
  IN2 w2.032: 134.91,147.44 160.82,147.44 161.64,146.62
  BOTTOM w0.508: PR302.2 55.29,110.63 56.2,111.53
  BOTTOM w1.016: 58.64,106.74 58.64,109.09 51.53,116.2 47.34,116.2
  BOTTOM w1.524: 200.12,58.16 200.05,58.1 192.57,58.1 191.94,58.72 189.32,58.72 189.24,58.64 185.1,58.64 185.09,58.63
  BOTTOM w2.032: 134.53,147.06 135.04,147.57 160.75,147.57 161.83,146.49
  BOTTOM w4.064: 164.63,121.6 164.63,142.17 ; 124.88,146.49 108.56,146.49 103.79,141.73 101.51,141.73
  vias: v1(41.18,114.55) v1(41.75,114.86) v1(41.75,114.23) v1(42.39,114.86) v1(42.39,114.23) v1(43.02,114.86) v1(43.02,114.23) v1(65.69,140.2) v1(65.95,139.57) v1(66.33,140.2) v1(66.77,139.57) v1(66.96,140.2) v1(73.38,142.87) v1(73.88,142.55) v1(74.33,142.17) v1(74.84,141.79) v1(75.35,141.47) v1(97.13,142.49) v1(97.13,141.85) v1(97.76,142.49) v1(97.76,141.85) v1(98.4,142.49) v1(98.4,141.85) v1(99.03,142.49) v1(99.03,141.85) v1(131.03,143.76) v1(131.48,143.19) v1(131.99,143.76) v1(132.37,143.19) v1(132.75,144.33) v1(132.81,143.76) v1(133.45,144.14) v1(133.64,144.71) v1(162.28,144.9) v1(162.28,144.27) v1(162.91,144.9) v1(162.91,144.27) v1(166.91,114.42) v1(166.91,113.79) v1(167.1,104.96) v1(167.1,104.33) v1(167.55,114.42) v1(167.55,113.79) v1(167.74,104.96) v1(167.74,104.33) v1(180.31,56.51) v1(180.31,55.94) v1(180.31,55.37) v1(180.88,56.51) v1(180.88,55.94) v1(180.88,55.37) v1(180.88,54.73) v1(181.45,56.51) v1(181.45,55.94) v1(181.45,55.37) v1(181.45,54.73) v4(67.46,139.66)
+19VB_0.95V: length 1.6
  TOP w0.102: v1(164.76,69.12) 164.76,69.36 v2(163.76,70.35)
  vias: v1(164.76,68.48)
+19VB_1.2V: length 14.6
  TOP w0.254: PCM04.1 63.5,107.15 63.98,107.63 65.88,107.63 66.52,108.26 v2(66.52,108.38) 66.52,114.23 64.76,115.99 v1(64.76,117.58)
  BOTTOM w0.254: v1(64.76,117.58) 64.97,117.37 PRM07.1
  vias: v1(62.84,107.06) v1(62.84,106.42) v1(62.84,105.79) v1(62.84,105.15) v1(62.84,104.52)
+19VB_3V:
  vias: v1(47.34,111.31) v1(47.34,110.42) v1(47.34,109.4) v1(48.15,109.96) v2(47.99,109.39)
+19VB_5V:
  vias: v1(37.5,110.1) v1(37.5,109.28) v1(37.82,110.8) v1(38.32,109.28) v2(37.28,111.82)
+19VB_APU: length 0.7
  TOP w0.102: v2(152.15,122.65) v1(152.15,121.98)
  vias: v1(152.76,121.98) v1(153.37,121.98) v1(153.98,121.98) v1(156.05,114.3) v1(156.05,113.66) v1(156.05,112.83) v1(156.05,111.95)
+19VB_CHG:
  vias: v1(185.58,52.83) v1(186.22,53.27) v1(186.22,52.7) v1(186.28,52) v1(187.61,51.68) v1(187.61,51.11) v4(185.52,51.3)
+VCC0: length 3.3
  TOP w0.203: UE1.111 44.13,84.33 44.7,84.9 v2(44.7,85.1) 44.7,85.24 44.41,85.53 44.29,85.53 RE6.2
+VCC_IO2: length 18.4
  TOP w0.102: v1(33.02,72.1) 33.53,72.1 v2(34.08,72.65)
  TOP w0.254: v1(33.02,72.1) 31.94,72.1 31.59,72.45 RE8.2 31.54,72.96 RE7.2 ; v1(38.9,80.86) 39.02,80.99 39.02,82.08 38.93,82.18 UE1.124
  BOTTOM w0.254: v1(38.9,80.86) 38.58,80.54 38.58,79.69 32.99,74.1 32.99,72.13 v1(33.02,72.1)
+VDD_TOUCH: length 9.3
  TOP w0.102: v1(212.31,40.38) v4(212.31,39.72)
  BOTTOM w1.016: 221.59,40.95 221.08,40.44 213.18,40.44
  vias: v1(221.9,42.48) v1(221.9,41.91)
+VDDCR_FCH_ALW: length 49.2
  TOP w0.508: v1(122.46,35.68) 124.37,37.59 126.53,37.59 127.48,36.63 132.81,36.63 133.26,36.19 136.43,36.19 v1(140.05,39.81)
  IN1 w0.508: v1(140.83,45.4) 141.32,45.88 141.32,52.26 142.08,53.02 142.08,66.14 v1(142.34,66.4)
  IN2 w0.508: v1(140.05,39.81) 140.05,39.87 140.12,39.94 140.12,42.86 141,43.75 141,45.22 v1(140.83,45.4)
  BOTTOM w0.508: v1(140.05,39.81) 140.12,39.75 R73.2
  vias: v1(133.53,71.57) v1(134.23,71.66) v4(133.42,68.91)
+VDDREG:
  vias: v2(22.88,89.24)
GND: length 1964.2
  TOP w0.203: PCZ18.1 150.53,145.23 PRZ18.1 150.72,145.35 v1(151.16,145.79) ; U2.11 v1(32.6,53.84) ; v1(146.59,144.84) 146.66,144.9 146.66,145.6 146.92,145.87 PCZ64.2 ; UE1.113 43.33,82.24 43.47,82.1 ; US1.3 US1.21 ; PRZ76.1 144.75,144.98 PCZ62.1 144.67,144.9 v1(143.93,144.9) 143.93,144.38 PRZ87.1 ; U3.11 159.86,43.87 v1(160.56,44.57)
  TOP w0.254: v1(128.69,100.45) 128.56,100.33 127.79,100.33 127.54,100.07 UC9.3 ; v1(20.74,91.63) 20.61,91.5 CL2.2 ; PRZ81.1 142.2,142.74 v1(142.17,142.78) ; PCB36.2 198.06,52.83 197.16,53.73 PQB33.3 ; v1(119.13,87.73) 119.13,87.82 DC1.1 118.26,88.24 v1(118.1,88.07) ; PCZ14.2 v1(157.64,140.84) ; CE17.2 33.57,66.43 v1(33.44,66.29) ; UE1.35 38.13,68.71 38.41,68.99 v1(38.41,69.15) ; v1(25.05,90.48) 24.67,90.1 CL3.2 CL4.2 ; v1(39.65,84.96) 39.65,84.96 40.04,85.35 40.04,86.34 40.93,87.23 v1(40.93,87.69) 40.93,89.04 39.93,90.04 39.28,90.04 38.77,89.53 v1(36.93,89.53) 36.36,89.53 35.96,89.14 35.96,86.05 v1(36.36,85.66) 36.36,85.47 36.61,85.21 37.37,85.21 37.69,84.89 v1(38.39,84.89) ; PCZ58.2 141.3,140.55 141.3,139.72 PRZ67.2 141.3,139.67 v1(141.85,139.67) 142.02,139.5 142.4,139.5 142.75,139.15 PCZ59.2 ; CD14.2 69.89,82.97 v1(69.77,82.84) ; CV11.2 v1(215.49,51.24) ; CD15.2 v1(69.75,81.44) ; CD9.2 v1(69.77,78.33) ; CD13.2 69.91,71.98 v1(69.75,71.82) ; PD5.1 161.91,38.35 161.65,38.1 161.41,38.1 v1(161.39,38.07) ; CD12.2 v1(69.74,79.92) ; UE1.11 34.73,77.82 34.38,78.17 v1(34.13,78.17) ; v1(127.42,104.14) 127.49,104.06 UC10.3 ; CL11.2 v1(18.89,80.7) ; v1(25.12,91.82) 25.05,91.88 CL16.2 ; v1(137.75,142.36) 138.07,142.04 PCZ65.2 ; CL12.2 v1(22.89,91.69) ; UC11.3 133.26,40.95 133.83,40.38 v1(134.53,40.38) ; UE1.24 36.72,72.62 36.98,72.88 v1(37.24,72.88) ; CE12.2 53.17,81.02 UE1.94
  TOP w0.305: v1(105.25,44.89) 105.19,44.83 US2.8 ; CD21.2 CD20.2 70.04,66.46 v1(69.66,66.08) ; PU900.4 v1(173.58,46.79) ; US2.5 US2.6 104.16,44.15 v1(104.56,43.75) 104.71,43.9 US2.7
  TOP w0.356: CD32.2 78.83,80.83 CD10.2 ; v1(50.77,87.75) 50.45,87.75 50.29,87.59 50.29,86.86 CE11.2 ; C19.2 30.62,43.8 C18.2 ; CA49.2 v1(28.42,21.64) ; CD23.2 78.83,82.36 CD11.2 77.92,81.76 77.03,80.87 v1(77.03,80.72) ; CW3.2 v1(66.53,126.98) ; CA490.2 36.36,15.04 v1(36.48,15.17) ; CA50.2 CA46.2 ; C30.2 v1(152.69,62.54) ; CA45.2 v1(27.78,21.64) ; v1(46.82,48.11) 46.46,48.47 CL19.2 ; CE1.2 37.44,65.13 v1(37.53,65.03) ; CE19.2 v1(39.79,64.64)
  TOP w0.381: v1(120.27,89.63) 120.33,89.57 CC5.1 ; CC14.1 148.45,75.92 v1(148.5,75.87) ; v1(34.83,19.18) 34.83,19.43 35.21,19.81 35.6,19.81 36.11,19.3 CA46.2 ; v1(144.6,68.18) 144.6,68.67 144.83,68.9 CC9.2 ; v1(21.94,40.95) 21.81,40.95 21.28,41.49 CU8.2 ; CS2.2 182.39,42.34 v1(182.34,42.29) ; v1(173.64,54.41) PQ12.1 175.41,54.41 PR44.1 ; CU1.1 v1(219.17,29.01) ; CC6.1 123.1,87.89 v1(123.55,87.89) 123.55,88.49 RC28.2 ; CL15.2 29.26,84.45 CL10.2 ; C35.2 v1(146.66,59.49) ; CW1.2 CW2.2 66.64,125.28 v1(66.89,125.53) ; CV12.2 v1(214.6,59.18) ; CC10.2 v1(97.28,50.6) ; EC2.2 v1(225.21,61.65) ; v1(190.79,36.38) 190.92,36.38 191.3,36 CS1.2 ; C11.2 91.95,64.55 v1(92.2,64.8) ; CE18.2 v1(222.73,67.11) ; v1(57.41,79.24) 57.29,79.12 C15.2 ; CL5.2 v1(18.26,83.96) ; PR45.2 173.8,57.87 174.12,58.2 PQ13.1 ; v1(179.1,53.34) 179.1,54.54 179.13,54.57 PD14.1 ; v1(214.03,59.56) 213.97,59.49 CV13.2 ; v1(132.45,73.92) 131.97,73.45 RC100.2 ; v1(76.92,48.18) 76.93,48.17 76.93,47.72 CD42.2 ; PQ13.4 175.42,61.45 PR38.2 v1(176.12,61.53) ; v1(101.38,44.15) CS18.2 ; CU12.2 22.81,39.53 v1(22.58,39.3) 22.81,39.07 CU13.2 ; CD31.2 78.83,78.11 CD8.2 77.98,78.71 v1(77.85,78.58) ; v1(73.93,47.98) 73.93,47.78 RD5.1 ; CE15.2 32,76.39 31.55,76.83 v1(31.55,76.87) ; CC4.2 104.66,81.19 CC3.2 ; v1(46.9,88.7) 47.21,88.7 47.43,88.49 CE14.2 ; C14.2 58.01,75.35 v1(57.59,74.93) ; RC102.2 130.1,70.41 v1(130.1,70.36) ; v1(72.74,45.02) 72.77,45.05 CD16.2 ; CC105.2 146.92,61.44 CC104.2 ; PDB13.1 183.16,54.22 183.17,54.22 v1(183.17,53.34) ; v1(33.13,82.25) 33.13,82.35 C26.2 ; CD43.2 CD39.2 79.26,45.17 v1(79.25,45.18) ; PC903.1 v1(175.36,46.92) ; PQB32.3 v1(200.66,55.05) ; C22.2 157.43,46.12 v1(158.03,45.51) 158.36,45.84 C23.2 ; CA480.2 22.06,2.92 v1(21.87,2.73) 21.81,2.68 20.95,2.68 CA476.2 ; CS35.2 v1(186.15,33.97) ; v1(172.5,41.84) PC901.1 172.22,43.24 PQ900.4 ; C21.1 v1(153.89,43.43) ; CU24.2 54.81,78.14 v1(55.42,78.75) ; CE2.2 v1(54.3,82.07) ; CC119.2 v1(210,41.61)
  TOP w0.406: v1(211.18,47.3) 210.79,47.3 210.37,46.88 ED1.1 ; v1(23.78,79.24) EL1.3 v1(23.78,81.75)
  TOP w0.457: RC85.1 RC87.1 132.61,67.88 v1(132.83,68.1) ; RE9.1 55.2,67.7 v1(55,67.5) ; LE2.2 52.34,65.94 v1(52.1,66.18) ; CA27.2 v1(25.69,3.79)
  TOP w0.508: v1(43.98,81.4) 43.98,81.59 43.47,82.1 ; PR508.2 47.42,106.53 47.09,106.86 v1(46.45,106.86) ; CC62.2 102.9,99.94 v1(103.41,100.45) ; DA8.1 17.61,8.38 v1(18.2,8.38) ; v1(200.06,53.4) 199.49,52.83 PCB36.2 ; v1(16.2,84.07) 18.16,84.07 v1(18.26,83.96) ; v1(16.2,84.07) YL1.2 ; v1(16.2,84.07) 15.43,84.07 15.21,84.28 15.21,88.34 v1(15.48,88.61) 17.89,88.61 v1(17.9,88.6) ; PCZ37.2 140.17,135.64 v1(140.18,135.63) ; RC60.1 144.05,72.43 v1(143.9,72.29) ; v1(44.67,87.63) 44.74,87.56 CE10.1 ; CH2.2 v1(95.93,129.21) ; PQ2.3 78.94,145.2 PR6.2 v1(78.94,146.99) ; v1(18.22,83.29) 18.63,82.88 RL7.1 ; CV10.2 C10.2 93.73,63.88 v1(94.97,63.88) ; CC36.2 90.3,66.43 CC32.2 89.83,65.7 v1(90.25,65.27) ; v1(80.71,85.82) 80.46,85.57 78.8,85.57 78.6,85.37 CD2.2 ; DE2.1 v1(31.66,62.59) ; v1(120.26,57.13) 120.13,57 RC84.1 ; v1(52.87,79.88) 53.2,79.88 CE12.2 ; CL7.2 20.74,84.97 v1(20.75,84.98) ; EU2.1 v1(222.03,29.52) ; PDM01.2 68.31,109.8 v1(68.68,110.17) ; v1(76.87,67.69) 77.17,67.39 CD33.2 CD3.2 ; v1(188.76,33.97) RS20.2 RS18.2 ; CC37.2 93.55,64.86 v1(93.28,65.12) ; CC28.2 v1(87.16,65.07) ; v1(58.84,32.44) 58.96,32.57 R41.2 ; v1(101.76,61.59) 101.37,61.99 101.37,62.07 101.36,62.07 CC107.2 ; RV1.2 v1(213.34,53.14) ; UC13.3 v1(98.98,46.56) ; v1(102.29,99.84) 101.88,99.43 CC61.2 ; RV6.2 v1(211.31,49.67) ; CC98.2 CC99.2 99.77,57.04 v1(98.98,57.04) ; CC103.2 131.93,71.87 v1(132.26,72.2) ; v1(17.9,88.6) 19.37,88.6 20.11,87.85 CL1.2 20.42,87.65 v1(20.74,87.33) ; v1(17.9,88.6) YL1.4 ; Q16.3 153.53,55.95 153.8,56.23 v1(153.8,56.32) ; CD29.2 v1(69.79,82.2) ; CC41.2 CC40.2 92.04,65.79 v1(92.24,65.59) ; CC113.2 106.12,61.75 v1(106.2,61.67) ; v1(46.82,48.11) 46.4,47.7 RL11.1 ; PD3.2 83.54,144.86 v1(83.54,146.66) ; v1(69.72,85.44) 69.79,85.51 CD1.2 ; CA51.2 v1(25.69,21.59) ; CA28.2 25.04,6.03 v1(24.93,6.03) ; v1(156.77,139.54) 156.77,140.11 PCZ04.1 ; v1(65.19,44.46) 65.64,44.92 65.85,44.92 66.28,45.35 66.28,45.41 CD44.2 66.48,45.42 66.48,45.43 CD17.2 CD18.2 ; RC126.2 154.16,81.67 154.72,82.23 v1(154.72,82.71) ; PQ801.3 v1(151.18,44.05) ; CC27.2 88.49,65.04 v1(88.51,65.02) ; CD32.2 78.11,81 v1(77.85,80.74) ; C27.2 33.44,83.12 v1(33.44,83.05) ; RA38.2 21,8.3 v1(20.99,8.31) ; v1(83.5,66.65) 83.99,66.65 84.49,66.14 CC31.2 ; CD28.2 70.54,65.38 70.96,64.96 71.86,64.96 v1(72.39,65.49) ; C24.2 31.29,50.78 v1(31.47,50.6) ; CV14.2 v1(215.43,59.39) ; Q17.3 v1(150.3,54.9) ; DA5.1 v1(21.05,21.78) ; PRH15.1 168.49,63.65 168.86,63.29 v1(169.09,63.29) ; CC21.2 RC112.1 v1(99.16,50.48) ; DD2.1 65.48,50.52 v1(65.88,50.92) ; DD1.1 71.69,40.9 v1(71.95,41.17) ; C3.2 v1(216.38,44.57) ; v1(76.74,142.72) 76.57,142.72 76.06,143.23 PD1.1 ; CD26.2 CD35.2 CD27.2 CD34.2 69.15,44.92 v1(69,44.76) ; v1(41.94,48.34) 42.09,48.19 UL2.2 ; EC1.2 v1(220.71,66.75) ; v1(81.44,76.97) 80.96,76.49 80.14,76.49 79.88,76.74 RD4.1 ; PRB28.1 200.06,50.86 200.57,50.35 v1(200.76,50.35) ; CC13.2 v1(126.33,68.05) ; RV7.2 126.42,106.49 126.42,107.21 v1(126.55,107.34) ; v1(181.17,35.4) 181.39,35.62 RS16.2 ; v1(194.34,39.87) 194.34,40.76 193.15,41.96 RS17.2 ; v1(30.23,84.83) 30.17,84.77 CL15.2 ; CC120.2 v1(211.74,35.81) ; SW1.1 221,67.7 v1(221.26,67.95) ; PQ12.4 172.79,56.66 PR40.2 172.75,56.82 173.08,57.16 v1(173.08,57.33) 173.38,57.63 PR45.2 ; v1(173.2,41.84) PR903.1 ; v1(99.13,81.75) 99.6,82.23 DC3.1 103.28,81.43 RC7.1 CC3.2 ; v1(30.07,60.19) 29.96,60.31 C25.1 ; CD7.2 69.74,73.7 v1(69.74,73.7) ; v1(146.73,84.39) 146.73,84.39 144.62,84.39 ; v1(193.65,39.87) 193.46,39.68 RS15.2 ; v1(95.73,63.88) 95.73,64.07 96.1,64.44 CC39.2 CC63.2 ; UW1.2 72.41,125.78 v1(72.56,125.93) ; CD24.2 v1(69.74,77.51) ; v1(38.39,84.89) 38.39,85.02 37.35,86.06 YE1.2 ; RS21.2 184.82,45.99 v1(184.65,46.16) ; v1(72.23,89.02) 73.88,89.02 CD37.2 74.16,90.01 v1(72.2,90.01) ; ED3.1 218.03,61.97 v1(217.78,62.23) ; CC65.2 127.1,80.7 127.61,80.19 v1(127.74,80.19) ; CV9.2 206.92,55.24 207.43,54.73 v1(207.68,54.73) ; C19.2 31.9,43.8 31.97,43.87 v1(32.29,43.87) ; PR905.1 175.55,47.68 176.06,47.18 v1(176.06,46.92) ; v1(92.55,91.05) 92.71,90.9 CC38.2 ; PD2.2 v1(80.87,147.02) ; v1(32.39,50.84) 32.39,51.31 C17.2 ; RC27.2 119.88,90.03 v1(120.27,89.63) ; v1(145.13,58.92) 145.2,58.92 145.7,59.43 CC97.1 ; PQB31.3 190.66,47.28 PRB45.2 191.6,46.59 192.34,47.33 v1(192.34,47.43) ; RC13.2 124.73,90.06 124.79,90 v1(124.79,89.52) ; CC30.2 v1(91.57,91.03) ; DA2.1 16.93,3.23 v1(16.16,2.47) ; RE38.2 31.24,69.43 v1(31.15,69.52) ; CA52.2 v1(31.85,21.93) ; CD19.2 69.74,72.74 v1(69.74,72.73) ; v1(82.61,66.65) 82.61,66.51 83.16,65.96 CC29.2 ; CC76.2 v1(131.28,89.61) ; v1(153.2,144.46) 153.23,144.42 PCZ10.1 152.7,143.73 PRZ86.1 ; CU7.2 v1(22.35,41.49) ; RV10.2 v1(209.71,56.45) ; CD6.2 v1(69.72,84.55) ; v1(69.77,70.77) 70.02,70.52 CD5.2 ; v1(46.45,104.2) 47.09,104.2 47.42,104.53 PC516.1 ; v1(192.06,62.03) 192.19,62.16 CS20.2 ; RC91.2 146.53,70.45 v1(146.33,70.65) ; C29.2 v1(151.67,62.54) ; PRB04.2 183.35,68.46 v1(183.49,68.32) ; CA53.2 v1(18.96,8.3) ; CC100.2 104.22,67.43 CC101.2 102.96,67.43 CC111.2 v1(102.77,68.24) ; C31.2 C32.2 v1(27.91,55.61) ; RS19.2 v1(188.38,45.59) ; v1(148.68,73.41) 148.68,73.4 RC95.2 RC90.2 ; v1(106.14,99.94) 106.07,99.87 CC64.2 ; DA9.1 17.17,19.79 v1(18.13,20.76) ; PQB29.3 v1(191.48,60.32) ; CE9.2 CE13.2 49.13,85.86 v1(48.74,85.47) ; v1(146.46,80.9) 145.79,80.24 RC105.2 RC2.2 ; CD25.2 v1(69.78,80.68) ; PCB10.2 54.82,72.79 RE41.1 v1(55.41,71.89) ; RE28.2 50.94,87.37 50.77,87.54 v1(50.77,87.75) ; PRZ78.2 142.79,134.68 v1(142.78,134.68) ; RC15.2 124.73,91.9 v1(124.74,91.91) ; PC805.2 151.42,40.83 151.86,41.27 151.86,42.48 v1(151.61,42.73) ; PRH02.2 166.55,68.37 v1(166.66,68.48) ; v1(99.98,44.25) 99.49,43.76 RC65.1 99.25,44.7 CC16.2 ; v1(69.66,67.85) CD36.2 ; CD4.2 CD22.2 79.58,75.03 v1(79.58,75.59) ; CW8.2 75.18,126.12 v1(75.38,125.92) ; CC60.2 v1(103.91,99.86) ; v1(34.13,78.17) 33.44,78.17 33.44,78.16 CE8.2 ; v1(19.91,39.3) 20.1,39.11 UU1.2 ; v1(105.7,100.45) 105.5,100.45 104.99,99.94 CC25.2 ; v1(152.73,83.37) 152.56,83.37 152.26,83.07 QC3.3 ; CC112.2 105.17,62 105.25,61.92 v1(105.25,61.67) ; PC309.2 v1(53.63,105.4) ; CC116.2 v1(101.63,68.24) ; CC115.2 102.31,61.96 102.55,61.72 v1(102.55,61.67) ; CC106.2 103.27,61.96 v1(103.56,61.67) ; CC24.2 v1(87,90.99) ; CC33.2 v1(88.65,90.99) ; PCB11.2 200.17,49.03 v1(200.7,48.5) ; CV8.2 209.01,56.24 209.01,56.13 209.52,55.62 v1(209.71,55.62) ; PQ11.3 196.43,47.25 PR43.2 v1(197.47,47.25) ; QE1.3 v1(37.23,63) ; CV1.2 221.08,59.37 v1(221.27,59.56) ; CC114.2 v1(100.48,68.24) ; v1(90.27,90.99) CC23.2 ; RD3.1 69.85,68.74 69.66,68.93 69.66,68.95 v1(69.67,68.95) ; CC122.2 132.8,91.79 v1(132.89,91.88) ; v1(146.66,60.26) 146.71,60.31 146.71,60.55 146.71,60.55 CC104.2 ; CC34.2 v1(85.7,90.99) ; DA1.1 v1(22.64,5.77) ; CC110.2 104.22,62.01 v1(104.55,61.68) ; v1(124.17,67.86) 124.17,67.11 CC78.2 ; PRZ05.2 154.07,140 154.57,139.5 v1(156.12,139.5) ; CD40.2 CD41.2 81.81,45.2 v1(81.89,45.27) ; CA25.2 v1(24.29,10.45) ; CD30.2 v1(69.76,79.09) ; CS19.2 v1(106.78,44.94) ; RS13.2 v1(185.71,45.87) ; v1(35.02,59.84) 35.4,59.46 C34.2 C33.2 33.82,59.89 C16.1 ; UV1.2 v1(220.13,57.27) ; PCB13.2 v1(55,67.5) ; CL17.2 v1(18.22,81.85) ; RL9.2 v1(28.82,90.95) ; CL21.2 v1(28.75,66.4) ; CC26.2 v1(85.83,65.12) ; CC71.2 v1(131.35,79.37)
  VCC w0.203: JUSB2.7 14.89,28.74 ; JUSB2.7 13.87,28.74 ; JUSB2.7 14.38,29.9 ; JUSB2.7 15.03,29.25 ; JUSB2.7 14.89,29.76 ; JUSB2.7 14.38,28.6 ; JUSB2.7 13.87,29.76 ; 12.6,92.29 JHDMI1.2 ; JHDMI1.2 13.05,92.4 ; JHDMI1.2 12.04,92.85 ; JHDMI1.2 12.15,93.3 ; JHDMI1.2 13.16,92.85 ; JHDMI1.2 13.05,93.3 ; JHDMI1.2 12.15,92.4 ; JHDMI1.22 5.81,87.7 ; JHDMI1.22 3.29,86.8 ; JHDMI1.22 5.81,86.8 ; JHDMI1.22 4.55,88.6 ; JHDMI1.22 4.55,86.8 ; JHDMI1.22 3.29,87.7 ; JHDMI1.22 3.29,88.6 ; JHDMI1.22 5.81,88.6 ; H6.1 208.85,62.45 ; H6.1 206.05,65.25 ; H6.1 205.54,63.85 ; H6.1 207.45,65.76 ; H6.1 208.85,65.25 ; H6.1 207.45,61.94 ; H6.1 206.05,62.45 ; H6.1 209.36,63.85 ; 3.3,105.1 JHDMI1.21 ; JHDMI1.21 4.56,106 ; JHDMI1.21 3.3,106.9 ; JHDMI1.21 4.56,105.1 ; JHDMI1.21 4.56,106.9 ; JHDMI1.21 2.04,106.9 ; JHDMI1.21 2.04,105.1 ; JHDMI1.21 2.04,106 ; H8.1 8.96,112.6 ; H8.1 5.39,114.11 ; H8.1 8.41,114.11 ; H8.1 8.41,111.09 ; H8.1 6.9,110.54 ; H8.1 4.84,112.6 ; H8.1 5.39,111.09 ; H8.1 6.9,114.66 ; 10.6,94.8 JHDMI1.5 ; JHDMI1.5 10.49,94.35 ; JHDMI1.5 11.5,94.8 ; JHDMI1.5 11.5,93.9 ; JHDMI1.5 11.61,94.35 ; JHDMI1.5 10.6,93.9 ; 4.94,130.5 H1.1 ; H1.1 5.45,131.9 ; H1.1 6.85,128.59 ; H1.1 8.76,130.5 ; H1.1 5.45,129.1 ; H1.1 8.25,131.9 ; H1.1 6.85,132.41 ; H1.1 8.25,129.1 ; 11.75,20.55 JUSB2.10 ; JUSB2.10 15.25,20.55 ; JUSB2.10 15.25,21.4 ; JUSB2.10 15.25,22.25 ; JUSB2.10 11.75,21.4 ; JUSB2.10 13.5,20.55 ; JUSB1.12 13.5,61.85 ; JUSB1.12 11.75,61 ; JUSB1.12 15.25,60.15 ; JUSB1.12 11.75,61.85 ; JUSB1.12 15.25,61.85 ; JUSB1.12 15.25,61 ; JUSB1.7 14.89,53.66 ; JUSB1.7 13.87,53.66 ; JUSB1.7 14.89,52.64 ; JUSB1.7 14.38,52.5 ; JUSB1.7 14.38,53.8 ; JUSB1.7 15.03,53.15 ; JUSB1.7 13.87,52.64 ; 15.88,25.1 JUSB2.4 ; JUSB2.4 16.53,25.75 ; JUSB2.4 16.39,25.24 ; JUSB2.4 16.39,26.26 ; JUSB2.4 15.37,25.24 ; JUSB2.4 15.23,25.75 ; JUSB2.4 15.37,26.26 ; JUSB2.4 15.88,26.4 ; JUSB1.10 15.25,45.3 ; JUSB1.10 13.5,44.45 ; JUSB1.10 11.75,44.45 ; JUSB1.10 11.75,45.3 ; JUSB1.10 15.25,46.15 ; JUSB1.10 15.25,44.45 ; JHDMI1.23 14.01,90.5 ; JHDMI1.23 11.49,88.7 ; JHDMI1.23 11.49,89.6 ; JHDMI1.23 11.49,90.5 ; JHDMI1.23 12.75,88.7 ; JHDMI1.23 14.01,89.6 ; JHDMI1.23 12.75,90.5 ; JHDMI1.23 14.01,88.7 ; 12.15,95.4 JHDMI1.8 ; JHDMI1.8 13.05,96.3 ; JHDMI1.8 12.15,96.3 ; JHDMI1.8 13.05,95.4 ; JHDMI1.8 13.16,95.85 ; JHDMI1.8 12.04,95.85 ; JLAN1.12 11.81,65.1 ; JLAN1.12 10.65,66.4 ; JLAN1.12 9.49,65.75 ; JLAN1.12 10.65,65.1 ; JLAN1.12 9.49,66.4 ; JLAN1.12 9.49,65.1 ; JUSB2.13 7.75,37.1 ; JUSB2.13 5.05,37.1 ; JUSB2.13 7.75,37.95 ; JUSB2.13 6.4,37.95 ; JUSB2.13 5.05,37.95 ; 11.49,103.2 JHDMI1.20 ; JHDMI1.20 11.49,105 ; JHDMI1.20 12.75,105 ; JHDMI1.20 11.49,104.1 ; JHDMI1.20 14.01,103.2 ; JHDMI1.20 14.01,105 ; JHDMI1.20 14.01,104.1 ; JHDMI1.20 12.75,103.2 ; 213.85,63.59 H13.1 ; H13.1 211.45,67.41 ; H13.1 213.85,67.41 ; H13.1 211.45,65.5 ; H13.1 216.25,63.59 ; H13.1 216.25,67.41 ; H13.1 216.25,65.5 ; H13.1 211.45,63.59 ; 15.37,49.14 JUSB1.4 ; JUSB1.4 15.37,50.16 ; JUSB1.4 15.23,49.65 ; JUSB1.4 15.88,50.3 ; JUSB1.4 16.53,49.65 ; JUSB1.4 15.88,49 ; JUSB1.4 16.39,50.16 ; JUSB1.4 16.39,49.14 ; 1.69,82.55 JLAN1.10 ; JLAN1.10 4.01,81.9 ; JLAN1.10 4.01,82.55 ; JLAN1.10 4.01,83.2 ; JLAN1.10 1.69,83.2 ; JLAN1.10 2.85,81.9 ; JLAN1.10 2.85,83.2 ; JLAN1.10 1.69,81.9 ; JUSB1.13 6.4,61.85 ; JUSB1.13 5.05,61 ; JUSB1.13 7.75,61.85 ; JUSB1.13 7.75,61 ; JUSB1.13 5.05,61.85 ; 44.03,132.27 H12.1 ; H12.1 46.97,132.27 ; H12.1 43.49,130.8 ; H12.1 44.03,129.33 ; H12.1 46.97,129.33 ; H12.1 47.51,130.8 ; H12.1 45.5,132.81 ; H12.1 45.5,128.79 ; JLAN1.9 11.81,83.2 ; JLAN1.9 10.65,81.9 ; JLAN1.9 11.81,82.55 ; JLAN1.9 11.81,81.9 ; JLAN1.9 9.49,81.9 ; JLAN1.9 10.65,83.2 ; JLAN1.9 9.49,83.2 ; JLAN1.9 9.49,82.55 ; JLAN1.11 4.01,66.4 ; JLAN1.11 4.01,65.1 ; JLAN1.11 1.69,66.4 ; JLAN1.11 2.85,65.1 ; JLAN1.11 4.01,65.75 ; JLAN1.11 1.69,65.75 ; JLAN1.11 1.69,65.1 ; JLAN1.11 2.85,66.4 ; 6.09,41.2 H5.1 ; H5.1 6.6,39.8 ; H5.1 8,39.29 ; H5.1 9.4,42.6 ; H5.1 9.4,39.8 ; H5.1 9.91,41.2 ; H5.1 6.6,42.6 ; H5.1 8,43.11 ; JHDMI1.11 11.61,97.35 ; JHDMI1.11 10.49,97.35 ; JHDMI1.11 11.5,97.8 ; JHDMI1.11 10.6,97.8 ; JHDMI1.11 10.6,96.9 ; JHDMI1.11 11.5,96.9 ; H4.1 9.3,84.4 ; H4.1 7.9,83.89 ; H4.1 9.81,85.8 ; H4.1 6.5,87.2 ; H4.1 6.5,84.4 ; H4.1 7.9,87.71 ; H4.1 5.99,85.8 ; H4.1 9.3,87.2 ; JHDMI1.17 11.5,100.8 ; JHDMI1.17 10.6,99.9 ; JHDMI1.17 11.61,100.35 ; JHDMI1.17 10.49,100.35 ; JHDMI1.17 10.6,100.8 ; JHDMI1.17 11.5,99.9 ; 111.36,108.69 HCPU1.1 ; HCPU1.1 111.36,112.13 ; HCPU1.1 113.08,108.04 ; HCPU1.1 113.08,112.77 ; HCPU1.1 110.72,110.41 ; 5.05,20.55 JUSB2.11 ; JUSB2.11 7.75,20.55 ; JUSB2.11 6.4,20.55 ; JUSB2.11 7.75,21.4 ; JUSB2.11 5.05,21.4 ; 11.75,37.95 JUSB2.12 ; JUSB2.12 13.5,37.95 ; JUSB2.12 15.25,37.1 ; JUSB2.12 15.25,37.95 ; JUSB2.12 11.75,37.1 ; JUSB2.12 15.25,36.25 ; JUSB1.11 7.75,44.45 ; JUSB1.11 6.4,44.45 ; JUSB1.11 5.05,44.45 ; JUSB1.11 5.05,45.3 ; JUSB1.11 7.75,45.3
  IN2 w0.254: v1(120.42,100.64) v1(120.42,100) 120.85,99.57 120.85,96.98 122.76,95.08 125.75,95.08 127.23,93.59 130.47,93.59 131.16,92.9 131.16,89.73 v1(131.28,89.61) ; v1(27.21,52.57) 27.91,52.57 28.61,51.87 28.61,47.3 26.57,45.26 26.57,41.91 25.21,40.55 25.21,35.21 v1(25.24,35.17) ; v1(30.23,84.83) 28.93,84.83 26.07,87.69 26.07,96.07 27.58,97.58 27.58,102.17 27.39,102.36 v1(27.39,104.52) 27.4,104.53 27.4,119.59 33.54,125.73 63.47,125.73 65.89,128.15 74.98,128.15 76.52,129.69 76.52,134.68 80,138.16 110.27,138.16 126.07,122.35 126.07,119.65 129.84,115.89 129.84,113.35 140.69,102.5 140.69,101.31 144.41,97.59 144.41,94.26 v1(144.5,94.17)
  IN2 w0.508: v1(77.85,80.74) 77.83,80.72 v1(77.03,80.72) 77.03,78.52 ; 77.03,78.52 74.43,78.52 73.69,77.78 70.01,77.78 v1(69.74,77.51) ; 77.03,78.52 77.79,78.52 v1(77.85,78.58) 79.57,78.58 80.14,78.01 80.52,78.01 81.06,77.47 81.06,77.34 v1(81.44,76.97) 80.06,75.59 v1(79.58,75.59)
  GND w0.203: 10.6,99.9 JHDMI1.17 ; JHDMI1.17 11.5,99.9 ; JHDMI1.17 10.49,100.35 ; JHDMI1.17 10.6,100.8 ; JHDMI1.17 11.61,100.35 ; JHDMI1.17 11.5,100.8 ; 6.4,44.45 JUSB1.11 ; JUSB1.11 7.75,45.3 ; JUSB1.11 5.05,45.3 ; JUSB1.11 7.75,44.45 ; JUSB1.11 5.05,44.45 ; 10.6,94.8 JHDMI1.5 ; JHDMI1.5 11.5,94.8 ; JHDMI1.5 11.5,93.9 ; JHDMI1.5 11.61,94.35 ; JHDMI1.5 10.6,93.9 ; JHDMI1.5 10.49,94.35 ; H1.1 8.25,129.1 ; H1.1 8.76,130.5 ; H1.1 6.85,128.59 ; H1.1 5.45,131.9 ; H1.1 5.45,129.1 ; H1.1 4.94,130.5 ; H1.1 6.85,132.41 ; H1.1 8.25,131.9 ; 3.29,87.7 JHDMI1.22 ; JHDMI1.22 4.55,86.8 ; JHDMI1.22 5.81,87.7 ; JHDMI1.22 5.81,88.6 ; JHDMI1.22 4.55,88.6 ; JHDMI1.22 5.81,86.8 ; JHDMI1.22 3.29,86.8 ; JHDMI1.22 3.29,88.6 ; JLAN1.11 4.01,65.1 ; JLAN1.11 4.01,66.4 ; JLAN1.11 1.69,66.4 ; JLAN1.11 1.69,65.75 ; JLAN1.11 1.69,65.1 ; JLAN1.11 2.85,65.1 ; JLAN1.11 2.85,66.4 ; JLAN1.11 4.01,65.75 ; HCPU1.1 115.44,110.41 ; HCPU1.1 113.08,112.77 ; HCPU1.1 113.08,108.04 ; HCPU1.1 111.36,112.13 ; HCPU1.1 110.72,110.41 ; HCPU1.1 114.8,112.13 ; HCPU1.1 114.8,108.69 ; HCPU1.1 111.36,108.69 ; 15.88,49 JUSB1.4 ; JUSB1.4 15.37,50.16 ; JUSB1.4 15.88,50.3 ; JUSB1.4 15.23,49.65 ; JUSB1.4 16.53,49.65 ; JUSB1.4 16.39,50.16 ; JUSB1.4 16.39,49.14 ; JUSB1.4 15.37,49.14 ; 10.49,97.35 JHDMI1.11 ; JHDMI1.11 11.5,97.8 ; JHDMI1.11 10.6,97.8 ; JHDMI1.11 10.6,96.9 ; JHDMI1.11 11.5,96.9 ; JHDMI1.11 11.61,97.35 ; 13.87,52.64 JUSB1.7 ; JUSB1.7 13.87,53.66 ; JUSB1.7 14.89,52.64 ; JUSB1.7 15.03,53.15 ; JUSB1.7 14.38,52.5 ; JUSB1.7 14.38,53.8 ; JUSB1.7 14.89,53.66 ; JUSB2.12 15.25,37.95 ; JUSB2.12 11.75,37.95 ; JUSB2.12 11.75,37.1 ; JUSB2.12 15.25,37.1 ; JUSB2.12 15.25,36.25 ; JUSB2.12 13.5,37.95 ; H13.1 213.85,67.41 ; H13.1 213.85,63.59 ; H13.1 211.45,67.41 ; H13.1 216.25,67.41 ; H13.1 211.45,63.59 ; H13.1 211.45,65.5 ; H13.1 216.25,63.59 ; H13.1 216.25,65.5 ; 13.87,28.74 JUSB2.7 ; JUSB2.7 14.89,28.74 ; JUSB2.7 14.38,28.6 ; JUSB2.7 13.87,29.76 ; JUSB2.7 15.03,29.25 ; JUSB2.7 14.89,29.76 ; JUSB2.7 14.38,29.9 ; 45.5,128.79 H12.1 ; H12.1 46.97,132.27 ; H12.1 44.03,132.27 ; H12.1 43.49,130.8 ; H12.1 47.51,130.8 ; H12.1 45.5,132.81 ; H12.1 46.97,129.33 ; H12.1 44.03,129.33 ; 6.09,41.2 H5.1 ; H5.1 8,43.11 ; H5.1 9.91,41.2 ; H5.1 6.6,42.6 ; H5.1 9.4,42.6 ; H5.1 6.6,39.8 ; H5.1 9.4,39.8 ; H5.1 8,39.29 ; HCPU4.1 137.38,51.77 ; HCPU4.1 139.1,51.13 ; HCPU4.1 139.1,47.69 ; HCPU4.1 135.02,49.41 ; HCPU4.1 139.74,49.41 ; HCPU4.1 135.66,47.69 ; HCPU4.1 137.38,47.04 ; HCPU4.1 135.66,51.13 ; JHDMI1.23 14.01,88.7 ; JHDMI1.23 14.01,90.5 ; JHDMI1.23 14.01,89.6 ; JHDMI1.23 11.49,89.6 ; JHDMI1.23 11.49,88.7 ; JHDMI1.23 11.49,90.5 ; JHDMI1.23 12.75,88.7 ; JHDMI1.23 12.75,90.5 ; 15.37,26.26 JUSB2.4 ; JUSB2.4 15.37,25.24 ; JUSB2.4 16.39,25.24 ; JUSB2.4 16.39,26.26 ; JUSB2.4 16.53,25.75 ; JUSB2.4 15.23,25.75 ; JUSB2.4 15.88,26.4 ; JUSB2.4 15.88,25.1 ; JHDMI1.21 3.3,106.9 ; JHDMI1.21 2.04,106.9 ; JHDMI1.21 4.56,106 ; JHDMI1.21 4.56,106.9 ; JHDMI1.21 4.56,105.1 ; JHDMI1.21 2.04,106 ; JHDMI1.21 2.04,105.1 ; JHDMI1.21 3.3,105.1 ; 137.38,108.04 HCPU2.1 ; HCPU2.1 135.66,112.13 ; HCPU2.1 135.66,108.69 ; HCPU2.1 135.02,110.41 ; HCPU2.1 139.1,108.69 ; HCPU2.1 139.74,110.41 ; HCPU2.1 137.38,112.77 ; HCPU2.1 139.1,112.13 ; 12.6,92.29 JHDMI1.2 ; JHDMI1.2 12.04,92.85 ; JHDMI1.2 12.15,92.4 ; JHDMI1.2 13.05,92.4 ; JHDMI1.2 12.15,93.3 ; JHDMI1.2 13.05,93.3 ; JHDMI1.2 13.16,92.85 ; JUSB1.10 15.25,45.3 ; JUSB1.10 11.75,45.3 ; JUSB1.10 11.75,44.45 ; JUSB1.10 13.5,44.45 ; JUSB1.10 15.25,46.15 ; JUSB1.10 15.25,44.45 ; JHDMI1.20 14.01,103.2 ; JHDMI1.20 12.75,105 ; JHDMI1.20 11.49,103.2 ; JHDMI1.20 11.49,104.1 ; JHDMI1.20 12.75,103.2 ; JHDMI1.20 14.01,105 ; JHDMI1.20 11.49,105 ; JHDMI1.20 14.01,104.1 ; 4.84,112.6 H8.1 ; H8.1 8.41,114.11 ; H8.1 5.39,111.09 ; H8.1 8.96,112.6 ; H8.1 8.41,111.09 ; H8.1 5.39,114.11 ; H8.1 6.9,110.54 ; H8.1 6.9,114.66 ; JLAN1.10 4.01,81.9 ; JLAN1.10 1.69,83.2 ; JLAN1.10 4.01,83.2 ; JLAN1.10 4.01,82.55 ; JLAN1.10 1.69,81.9 ; JLAN1.10 2.85,83.2 ; JLAN1.10 1.69,82.55 ; JLAN1.10 2.85,81.9 ; JUSB1.12 13.5,61.85 ; JUSB1.12 11.75,61 ; JUSB1.12 15.25,61 ; JUSB1.12 11.75,61.85 ; JUSB1.12 15.25,60.15 ; JUSB1.12 15.25,61.85 ; 206.05,65.25 H6.1 ; H6.1 208.85,62.45 ; H6.1 207.45,65.76 ; H6.1 208.85,65.25 ; H6.1 205.54,63.85 ; H6.1 207.45,61.94 ; H6.1 209.36,63.85 ; H6.1 206.05,62.45 ; 110.72,49.41 HCPU3.1 ; HCPU3.1 111.36,47.69 ; HCPU3.1 114.8,51.13 ; HCPU3.1 115.44,49.41 ; HCPU3.1 114.8,47.69 ; HCPU3.1 113.08,47.04 ; HCPU3.1 113.08,51.77 ; HCPU3.1 111.36,51.13 ; JLAN1.9 11.81,83.2 ; JLAN1.9 9.49,83.2 ; JLAN1.9 9.49,81.9 ; JLAN1.9 11.81,81.9 ; JLAN1.9 10.65,83.2 ; JLAN1.9 9.49,82.55 ; JLAN1.9 10.65,81.9 ; JLAN1.9 11.81,82.55 ; 6.5,87.2 H4.1 ; H4.1 5.99,85.8 ; H4.1 9.3,87.2 ; H4.1 7.9,87.71 ; H4.1 7.9,83.89 ; H4.1 9.3,84.4 ; H4.1 6.5,84.4 ; H4.1 9.81,85.8 ; JUSB2.13 7.75,37.1 ; JUSB2.13 6.4,37.95 ; JUSB2.13 7.75,37.95 ; JUSB2.13 5.05,37.1 ; JUSB2.13 5.05,37.95 ; 5.05,61.85 JUSB1.13 ; JUSB1.13 7.75,61 ; JUSB1.13 7.75,61.85 ; JUSB1.13 5.05,61 ; JUSB1.13 6.4,61.85 ; 12.15,96.3 JHDMI1.8 ; JHDMI1.8 12.04,95.85 ; JHDMI1.8 13.05,96.3 ; JHDMI1.8 12.15,95.4 ; JHDMI1.8 13.05,95.4 ; JHDMI1.8 13.16,95.85 ; 140.15,28.5 H7.1 ; H7.1 139.64,27.1 ; H7.1 141.55,29.01 ; H7.1 141.55,25.19 ; H7.1 142.95,25.7 ; H7.1 143.46,27.1 ; H7.1 140.15,25.7 ; H7.1 142.95,28.5 ; JUSB2.10 15.25,21.4 ; JUSB2.10 13.5,20.55 ; JUSB2.10 11.75,21.4 ; JUSB2.10 11.75,20.55 ; JUSB2.10 15.25,22.25 ; JUSB2.10 15.25,20.55 ; JUSB2.11 7.75,21.4 ; JUSB2.11 5.05,21.4 ; JUSB2.11 6.4,20.55 ; JUSB2.11 5.05,20.55 ; JUSB2.11 7.75,20.55 ; 10.65,65.1 JLAN1.12 ; JLAN1.12 11.81,65.1 ; JLAN1.12 9.49,65.1 ; JLAN1.12 10.65,66.4 ; JLAN1.12 9.49,66.4 ; JLAN1.12 9.49,65.75
  BOTTOM w0.152: UC1.AA2 UC1.AA1 ; UC1.AY11 UC1.BA11 ; UC1.N1 UC1.N2
  BOTTOM w0.203: UC1.B32 119.1,90.16 118.75,89.81 UC1.C33 ; v1(137.33,79.91) 137.33,79.91 UC1.AA1 ; UC1.BA11 v1(130.73,67.98) ; UC1.AM27 121.98,73.95 122.99,73.95 UC1.AM25 ; v1(65.95,111.78) 65.95,112.2 65.65,112.5 PUM01.14 ; UC1.AA3 UC1.AA2 ; v1(125.95,92.37) 126.07,92.37 126.69,91.76 126.69,91.12 126.88,90.93 UC1.A18 ; v1(60.8,112.71) 60.99,112.9 PUM01.3 ; UC1.BA7 132.93,68.24 132.83,68.14 v1(132.83,68.1) ; UC1.A35 117.53,91.95 v1(117.56,91.98)
  BOTTOM w0.254: v1(77.38,65.46) 77.6,65.24 JDIMM1.181 ; UC1.E21 125.49,88.31 v1(125.79,88.01) ; v1(80.61,56.08) 80.45,56.24 JDIMM1.217 ; UC1.AJ5 133.63,75.31 v1(133.37,75.04) 133.37,74.94 UC1.AL7 132.45,74.02 v1(132.45,73.92) 131.72,73.92 UC1.AL10 ; v1(41.44,104.77) v1(40.86,104.77) ; v1(40.86,104.77) 40.86,104.37 PC508.2 ; v1(40.86,104.77) PU501.18 ; JDIMM1.243 74.62,49.74 v1(74.54,49.65) ; JDIMM1.234 72.41,51.99 v1(72.86,51.53) ; JDIMM1.180 v1(72.39,65.49) ; v1(80.48,107.21) 80.01,106.74 JDIMM1.23 ; v1(112.93,74.33) 113,74.41 UC1.AL41 ; UC1.G41 v1(113.13,87.61) ; v1(51.28,110.55) 51.28,110.29 50.9,109.91 PU301.8 ; JDIMM1.222 v1(72.51,54.99) ; v1(132.26,72.2) 132.26,71.93 UC1.AU9 131.53,71.51 UC1.AR11 ; UC1.AW31 120.11,70.01 v1(120.28,70.18) 120.45,70.01 UC1.AW29 ; v1(40.61,110.04) 40.41,109.84 PU501.7 ; v1(73.93,47.98) 73.42,48.49 JDIMM1.248 ; v1(73.42,53.77) 73.2,53.99 JDIMM1.226 ; JDIMM1.223 77.54,54.74 v1(76.52,53.72) 76.95,53.29 77.57,53.29 78.02,53.74 JDIMM1.227 ; UC1.G3 135.13,87.47 v1(134.72,87.05) 135.13,86.64 UC1.J3 135.13,86.13 v1(134.96,85.96) 134.96,85.58 UC1.L3 135.1,85.37 135.1,84.34 UC1.N3 UC1.N2 ; UC1.G3 134.84,87.89 v1(134.84,88.26) 135.13,88.55 UC1.E3 ; UC1.G3 UC1.G2 UC1.G1 ; JDIMM1.30 v1(72.26,104.99) ; JDIMM1.230 v1(72.5,52.99) ; v1(81.34,65.5) 81.29,65.45 81.29,65.2 80.33,64.24 JDIMM1.185 ; JDIMM1.251 77.99,47.74 77.81,47.56 75.82,47.56 v1(75.3,48.08) ; JDIMM1.15 80.42,108.74 v1(80.43,108.73) ; v1(113.14,72.19) 113.16,72.21 UC1.AR41 ; UC1.A39 115.28,90.56 UC1.B39 UC1.C39 v1(115.73,89.41) ; C2.2 140.05,90.55 140.05,90.54 138.09,88.58 v1(137.58,88.58) 137.51,88.64 136.6,88.64 UC1.E1 ; UC1.AR31 119.96,72.31 v1(120.32,71.94) 120.76,71.51 UC1.AU29 121.63,72.31 UC1.AR27 121.97,72.31 v1(122.49,71.79) 122.77,71.51 UC1.AU25 123.83,72.31 UC1.AR23 124.28,72.31 v1(124.77,71.81) 125.08,71.51 UC1.AU21 125.34,71.51 v1(125.78,71.94) 126.14,72.31 UC1.AR19 ; v1(115.53,79.36) v1(116.23,79.36) 116.03,79.16 UC1.AC38 ; v1(115.53,79.36) 115.33,79.56 UC1.AA39 ; v1(115.53,79.36) 115.33,79.16 UC1.AC39 ; JDIMM1.175 76.08,66.74 75.25,65.91 v1(75.25,65.5) ; JDIMM1.19 77.96,107.74 76.98,108.73 v1(76.98,108.86) ; JDIMM1.6 v1(72.22,110.99) ; v1(82.21,56.12) 82.21,56.11 81.07,57.24 JDIMM1.213 ; JDIMM1.247 77.48,48.74 v1(76.92,48.18) ; JDIMM1.188 v1(72.22,63.49) ; v1(51.47,105.28) v1(50.9,105.28) ; v1(50.9,105.28) PU301.18 ; v1(50.9,105.28) 50.9,104.88 PC308.2 ; v1(124.74,91.91) 124.64,91.91 124.13,91.4 UC1.A23 ; v1(135.85,65.95) 137.06,65.95 139.01,64 143.16,64 v1(143.42,63.75) 143.48,63.69 143.48,63.3 143.73,63.04 CC18.2 145.15,63.04 145.78,62.42 148.12,62.42 148.37,62.67 148.37,63.24 148.24,63.37 148.24,66.52 147.99,66.78 147.01,66.78 v1(146.9,66.67) 145.84,66.67 144.92,65.74 CC19.2 144.09,65.74 143.52,65.16 142.84,65.16 142.74,65.06 139.66,65.06 137.1,67.63 137.1,68.2 136.57,68.73 136.57,69.17 UC1.AY1 ; UC1.AE39 115.33,77.64 v1(115.64,77.33) 115.64,77.18 115.33,76.88 UC1.AG39 ; UC1.R39 115.33,83.56 115.47,83.69 v1(115.47,83.76) 115.47,83.82 115.33,83.96 UC1.N39 ; v1(115.73,89.41) 116.07,89.41 v1(116.51,88.96) ; v1(115.73,89.41) 116.13,89.81 UC1.C37 ; v1(77.38,110.97) 78.11,110.24 JDIMM1.9 ; JDIMM1.68 v1(72.21,95.49) ; JEDP1.13 v1(211.43,54.45) ; 80.49,112.22 v1(80.49,112.2) ; v1(80.49,112.2) 80.45,112.24 JDIMM1.1 ; v1(80.49,112.2) 80.49,111.44 80.29,111.24 JDIMM1.5 ; JDIMM1.166 72.08,68.99 v1(72.15,69.06) ; UC1.AN5 133.63,73.19 v1(134.1,72.72) ; v1(116.51,88.96) 116.25,88.71 UC1.E38 116.03,88.66 v1(115.53,88.16) ; v1(116.51,88.96) 116.88,88.96 UC1.E35 117.86,88.31 v1(118.1,88.07) 117.63,87.61 UC1.G35 UC1.G37 ; JFP1.3 220,29.84 v1(219.74,29.59) 219.5,29.83 JFP1.4 ; JDIMM1.171 76.92,67.74 v1(76.87,67.69) ; UC1.AN39 115.33,72.95 v1(115.53,72.75) 115.33,72.55 UC1.AR39 ; UC1.A2 135.91,91.21 135.65,91.47 v1(135.65,91.75) ; JDIMM1.90 72.17,89.99 v1(72.2,90.01) ; JDIMM1.27 80.07,105.74 v1(80.94,104.87) 80.8,104.74 JDIMM1.31 ; v1(211.31,49.67) 211.53,49.45 JEDP1.23 ; v1(76.21,69.52) 76.99,68.74 JDIMM1.167 ; RPC5.4 v1(65.82,37.98) 65.82,37.99 65.33,38.48 RPC5.3 ; JDIMM1.189 77.77,63.24 v1(77.64,63.37) ; v1(134.65,89.68) 135,89.68 UC1.C3 ; v1(134.65,89.68) 134.65,89.18 UC1.E3 ; v1(134.65,89.68) 134.16,89.68 UC1.C5 133.95,89.72 133.02,89.72 UC1.C7 132.58,90.16 UC1.B8 UC1.A8 132.38,91.37 v1(132.89,91.88) ; v1(115.53,88.16) 115.33,87.96 UC1.G39 ; v1(115.53,88.16) 115.33,88.36 UC1.E39 ; UC1.E3 UC1.E2 ; UC1.AJ3 135.13,75.89 v1(134.97,76.05) 135.13,76.22 UC1.AG3 ; v1(190.79,36.38) 190.72,36.32 190.47,36.32 190.2,36.05 JHDD1.1 ; JDIMM1.201 76.64,60.24 v1(76.11,59.71) ; JDIMM1.85 80.19,91.24 v1(80.76,91.81) 80.33,92.24 JDIMM1.81 ; JDIMM1.61 80.74,97.24 v1(80.89,97.38) 80.03,98.24 JDIMM1.57 ; UC1.AC3 134.97,78.64 v1(134.97,78.24) 135.13,78.07 UC1.AE3 ; JDIMM1.18 v1(72.2,107.99) ; JDIMM1.103 v1(77.28,86.74) ; v1(129.74,84.42) 129.26,84.91 UC1.L13 ; v1(119.75,67.79) 119.73,67.81 UC1.BA31 ; JDIMM1.98 v1(72.22,87.99) ; UC1.G1 139.09,87.61 139.42,87.93 C1.2 v1(141.45,87.93) 141.38,87.86 141.38,87.5 141.91,86.97 v1(143.28,86.97) 144.93,86.97 145.19,87.23 145.19,89.05 145.24,89.1 v1(145.24,89.32) 145.24,91.03 144.72,91.54 v1(141.7,91.54) ; UC1.G1 136.68,87.46 v1(136.68,87.1) ; v1(113.21,80.96) 113.26,81.01 UC1.W41 ; v1(80.71,85.82) 80.62,85.74 JDIMM1.107 ; UC1.A32 UC1.B32 ; UC1.BA15 128.53,68.14 v1(128.25,67.86) ; v1(213.39,42.03) 213.31,41.95 JEDP1.38 ; JDIMM1.218 v1(72.16,55.99) ; v1(113.14,78.79) 113.16,78.81 UC1.AC41 ; JDIMM1.193 v1(77.47,62.24) ; JEDP1.35 211.6,43.45 v1(211.46,43.59) ; JDIMM1.209 82,58.24 v1(82.66,57.58) ; JHDD1.7 187.2,36.48 v1(187.04,36.63) ; v1(113.08,76.39) 113.3,76.61 UC1.AG41 ; UC1.C35 117.92,89.81 v1(118.08,89.64) 118.25,89.81 UC1.C33 ; UC1.BA39 115.28,68.14 v1(115.17,68.02) ; JEDP1.20 v1(211.43,50.95) ; v1(189.15,37.47) 189.15,37.27 188.7,36.82 JHDD1.4 ; JDIMM1.205 v1(81,59.24) ; UC1.R41 113.08,83.21 v1(113.01,83.14) ; JDIMM1.2 v1(72.2,111.99) ; UC1.L39 115.33,85.76 115.47,85.89 v1(115.47,85.96) 115.47,86.02 115.33,86.16 UC1.J39 ; JDIMM1.210 v1(72.25,57.99) ; UC1.C25 122.71,89.81 v1(122.48,89.58) 122.25,89.81 UC1.C27 ; UC1.W39 115.33,81.27 v1(115.52,81.45) 115.52,81.57 115.33,81.76 UC1.U39 ; JDIMM1.39 80.23,102.74 v1(81.15,101.81) 81.08,101.74 JDIMM1.43 ; JEDP1.17 v1(211.43,52.45) ; UC1.BA23 124.13,67.9 v1(124.17,67.86) ; UC1.C9 131.48,89.81 v1(131.28,89.61) 131.08,89.81 UC1.C11 ; JDIMM1.172 v1(72.31,67.49) ; JDIMM1.60 v1(72.38,97.49) ; RPC5.1 65.47,39.48 65.72,39.23 v1(65.72,39.21) 65.49,38.98 RPC5.2 ; JDIMM1.51 80.16,99.74 v1(81.16,100.74) JDIMM1.47 ; PU501.8 40.86,109.4 41.25,109.78 v1(41.25,110.04) ; UC1.U3 134.97,81.95 134.97,81.17 UC1.W3 ; UC1.U3 135,82.23 v1(135,82.59) 135,83.08 UC1.R3 ; UC1.U3 UC1.U2 UC1.U1 136.53,82.13 136.95,82.55 v1(137.51,82.55) ; UC1.E25 123.13,88.31 v1(123.55,87.89) 123.75,87.89 UC1.G23 124.51,87.13 v1(124.8,87.13) 124.38,86.71 UC1.H23 ; UC1.C41 113.54,89.86 v1(113.41,89.98) ; PU301.7 50.45,110.35 v1(50.64,110.55) ; v1(44.26,29.46) 44.61,29.11 CC12.2 ; v1(126.33,68.05) UC1.BA19 ; JDIMM1.196 72.46,61.49 v1(72.56,61.39) ; JDIMM1.48 v1(72.22,100.49) ; UC1.C15 128.91,89.81 v1(129.07,89.64) 129.24,89.81 UC1.C13 UC1.B13 UC1.A13 129.63,91.44 v1(129.43,91.64) ; JDIMM1.192 v1(72.39,62.49) ; JDIMM1.202 v1(72.38,59.99) ; v1(113.07,85.2) 113.27,85.41 UC1.L41 ; UC1.E29 121.07,88.31 v1(121.43,87.95) 121.87,87.51 UC1.G27 ; JDIMM1.89 v1(77.58,90.24) ; UC1.C23 124.5,89.81 v1(124.79,89.52) 125.07,89.81 UC1.C21 125.26,89.78 126.3,89.78 UC1.C19 126.48,89.66 v1(126.92,89.66) 127.07,89.81 UC1.C17 ; JDIMM1.239 76.7,50.74 v1(75.91,51.53) ; v1(75.18,51.47) 75.18,51.6 76.33,52.74 JDIMM1.231 ; UC1.C29 120.65,89.63 v1(120.27,89.63) 119.91,89.63 UC1.C31 ; JDIMM1.77 v1(81.24,93.24) ; PUH01.8 165.3,64.38 v1(165.23,64.46) ; JDIMM1.197 80.94,61.24 v1(81.39,61.69) ; v1(80.68,52.14) 80.28,51.74 JDIMM1.235 ; v1(73.42,69.52) 72.39,68.49 JDIMM1.168 ; UC1.AJ39 115.33,75.18 115.48,75.03 v1(115.48,74.97) 115.48,74.93 115.33,74.78 UC1.AL39 ; JDIMM1.252 v1(72.68,47.49) ; JDIMM1.44 v1(72.2,101.49) ; JDIMM1.86 v1(72.2,90.99) ; JFP1.1 221,29.76 v1(220.76,29.52) ; v1(187.61,60.57) 187.17,60.13 186.15,60.13 185.58,60.7 185.58,62.86 v1(185.71,62.99) ; JDIMM1.22 v1(72.25,106.99) ; JDIMM1.214 v1(72.23,56.99) ; JDIMM1.93 77.18,89.24 v1(77.18,89.24) ; JDIMM1.36 v1(72.19,103.49) ; JDIMM1.99 v1(77.45,87.74) ; JDIMM1.176 73.24,66.49 v1(74.13,67.38) ; v1(72.16,86.99) JDIMM1.102 ; v1(113.41,69.84) 113.53,69.96 UC1.AW41 ; JDIMM1.106 71.85,85.99 72.76,86.9 v1(72.76,86.99) ; UC1.N1 136.56,84.28 137.18,84.28 v1(137.26,84.19) ; CL18.2 23.91,83.92 v1(24.48,84.5) ; JDIMM1.52 v1(72.25,99.49) ; v1(119.13,87.73) 119.51,87.73 UC1.G31 ; JDIMM1.184 v1(72.4,64.49) ; v1(136.93,74.88) 136.93,74.81 UC1.AL1 136.41,74.52 135.95,74.52 UC1.AL2 UC1.AL3 135.13,74.06 v1(134.93,73.86) 135.13,73.66 UC1.AN3 ; JDIMM1.64 v1(72.25,96.49) ; JDIMM1.73 v1(81.16,94.24) ; JDIMM1.56 v1(72.2,98.49) ; UC1.BA35 v1(117.53,68.09) ; JDIMM1.40 v1(72.3,102.49) ; JDIMM1.10 v1(72.22,109.99) ; JDIMM1.82 v1(72.26,91.99) ; JDIMM1.238 v1(72.2,50.99) ; JDIMM1.78 v1(72.4,92.99) ; JDIMM1.26 v1(72.2,105.99) ; JDIMM1.206 v1(73.11,58.99) ; JDIMM1.72 v1(72.28,94.49) ; JDIMM1.14 v1(72.2,108.99)
  BOTTOM w0.305: v1(80.3,125.09) 79.76,124.55 JWLAN1.13 ; JWLAN1.69 79.79,138.55 v1(81.19,137.16) ; JSSD1.15 35.87,34.89 35.53,35.24 v1(35.15,35.24) ; JSSD1.21 v1(34.38,35.23) ; JWLAN1.39 v1(80.55,131.05) ; JSSD1.27 v1(32.87,35.23) ; JWLAN1.33 80.16,129.55 80.23,129.47 v1(80.49,129.47) ; v1(80.17,140.38) 79.84,140.05 JWLAN1.75 ; v1(81.89,133.79) 81.63,134.05 JWLAN1.51 ; v1(80.23,135.2) 79.88,135.55 JWLAN1.57 ; v1(80.36,121.34) 80.11,121.34 79.9,121.55 JWLAN1.1 ; v1(80.49,137.05) JWLAN1.63 ; JWLAN1.7 79.76,123.05 v1(80.35,123.64) ; JDIMM1.69 80.41,95.24 80.77,95.6 80.77,96.18 v1(80.79,96.19) 80.74,96.24 JDIMM1.65 ; 69.78,49.49 JDIMM1.244 72.29,49.49 v1(72.5,49.71) ; v1(80.93,132.39) 80.23,132.39 80.08,132.55 JWLAN1.45 ; JWLAN1.19 v1(80.13,126.05) ; JEDP1.32 211.59,44.95 v1(211.42,44.77) ; JSSD1.33 v1(31.38,35.27)
  BOTTOM w0.356: CE4.2 33.88,74.01 v1(34.2,74.33) ; JWLAN1.18 72.43,125.8 v1(72.56,125.93) ; v1(34.07,80.51) 33.85,80.3 CE3.2 ; CU25.2 199.09,40.06 v1(199.29,40.26) ; CE16.2 39.49,84.8 v1(39.65,84.96)
  BOTTOM w0.381: v1(44.36,30.84) 44.36,30.18 CC11.2 ; C4.1 115.83,32.55 R21.1 ; ED2.1 208.31,46.48 v1(208.31,45.91) ; U1.5 180.71,65.36 180.31,65.76 v1(180.31,65.9) ; CC22.1 132.15,46.43 132.53,46.81 v1(132.53,47.28) ; RC45.1 142.04,74.67 141.7,74.34 v1(141.44,74.34) ; CU23.2 v1(202.95,42.93) ; LED1.3 LED1.1 3.25,132.55 v1(3.34,132.46) ; v1(140.55,75.41) 140.55,75.59 140.51,75.63 CC15.1 ; CV17.2 v1(14.04,108.64) ; C41.2 123.01,36.45 122.79,36.23 122.22,36.23 121.76,35.77 v1(121.76,35.68) ; CC130.2 59.32,44.87 59.03,45.16 v1(59.03,45.19) ; CL6.2 25.84,84.26 v1(25.6,84.5) ; C48.2 127.23,40.09 v1(126.74,39.6) 126.74,39.41 127.29,38.85 C47.2 ; v1(122.96,39.33) 122.96,40.32 C42.2 ; C5.2 v1(100.34,27.43) ; C49.2 v1(125.19,43.93) ; v1(143.95,78.68) 143.6,79.03 RC49.1 143.19,79.02 RC43.1 ; C45.2 C46.2 116.38,40.27 116.13,40.53 115.92,40.53 v1(115.92,40.53) ; CC12.2 44.73,28.32 44.57,28.16 CC7.2 ; QS1.1 105.78,42.11 105.32,41.65 105.32,40.98 v1(105.08,40.75) 104.24,40.75 QS1.4 ; v1(121.5,62.99) 121.38,62.99 120.95,63.42 RC61.1 ; v1(118.38,36.06) Q15.4 ; CC8.2 v1(143.13,73.8)
  BOTTOM w0.406: v1(17.37,37.65) EU6.3 19.66,37.65 v1(19.85,37.46) ; 19.08,51.75 EU4.3 v1(21.73,51.75)
  BOTTOM w0.432: Q14.1 v1(17.18,120.22) ; Q14.4 v1(16.66,118.92)
  BOTTOM w0.508: JFP1.10 v1(223.15,25.08) ; PHZ3.1 159.46,126.77 v1(159.48,126.74) ; v1(178.86,69.46) 178.79,69.39 JFAN1.6 ; RH4.1 95.04,133.65 v1(95.22,133.47) 95.16,133.41 JHDT1.17 ; v1(143.88,77.21) RC41.1 ; JSPK1.5 v1(13.08,2) ; v1(190.5,68.35) 191.2,67.66 JODD1.14 JODD1.13 ; v1(88.06,133.1) 87.54,132.58 JHDT1.5 ; PHZ2.1 v1(149.06,108.57) ; QV1.3 v1(27.39,104.52) ; v1(179.17,74.42) 178.59,74.99 JFAN1.5 ; JKBBL1.5 v1(97.25,27.62) ; PR303.2 v1(56.1,109.66) ; UC15.2 v1(202.9,49.7) ; C36.2 129.4,44.82 128.9,44.31 v1(128.72,44.31) ; CV24.2 v1(26.01,99.88) ; UU2.2 200.88,39.94 v1(201.2,40.26) ; v1(191.36,33.97) 192,33.33 JHDD1.13 ; PR2503.2 v1(62.21,70.16) ; RC108.1 145.73,80.24 146.39,80.9 v1(146.46,80.9) ; PRB23.2 200.38,52.64 v1(200.66,52.92) ; PRB17.1 194.8,54.82 PRB16.2 v1(195.46,55.9) ; C53.2 183.55,72.45 v1(182.98,73.02) ; v1(89.24,133.02) 88.81,132.58 JHDT1.7 ; PCM19.2 v1(58.33,112.77) ; v1(76.17,120.45) JWLAN1.76 ; v1(203.62,45.27) 203.45,45.44 CU22.2 ; PCB07.1 192.11,55.25 192.48,55.62 v1(193.01,55.62) ; PC317.2 v1(56.1,108.77) ; C2.2 140.13,90.74 140.93,91.54 v1(141.7,91.54) ; PCB12.2 200.38,49.97 v1(200.76,50.35) ; v1(120.92,33.42) 120.87,33.38 120.87,32.64 120.86,32.63 120.86,31.82 121.05,31.63 JTP1.5 ; PC515.2 45.26,105.21 v1(45.26,104.15) ; Q4.3 106.17,37.04 v1(106.65,37.52) ; v1(110.75,36.67) 110.47,36.94 Q6.3 ; PCB09.2 200.03,51.91 v1(200.68,51.91) ; v1(158.03,45.51) 158.15,45.4 C20.1 ; v1(126.4,60.95) 126.4,61.19 RC115.2 ; CH1.2 90.33,135.69 v1(90.46,135.82) ; v1(185.71,62.99) 185.2,63.5 JODD1.1 JODD1.2 ; v1(122.4,33.24) 123.02,32.62 C8.2 ; RV32.2 RV27.2 v1(28.67,101.4) ; RC133.1 v1(158.34,78.99) ; 86.27,131.44 86.27,132.58 v1(86.71,133.03) ; JODD1.25 v1(199.93,65.72) ; EU1.1 v1(222.2,36) ; PC2504.2 v1(64.55,80.53) ; PCM15.2 PCM16.2 62.29,117.82 v1(62.39,117.93) ; PCB08.1 v1(193.01,54.86) ; PCH10.2 v1(167.36,67.43) ; v1(145.07,59.69) 145.16,59.78 RC86.1 RC83.1 ; v1(38.41,69.15) 38.41,68.85 38.32,68.77 RE29.2 ; JFAN1.4 v1(179.87,73.69) ; JEDP1.41 v1(214.03,39.25) ; JKB1.32 84.43,31.81 84.43,31.81 v1(84.43,32.38) ; v1(93.38,135.76) 93.14,135.51 RH3.1 RH2.1 ; JPWR1.1 221.2,62.23 v1(220.95,61.98) ; v1(57.41,79.24) 57.63,79.46 RE54.2 ; JFP1.9 v1(215.35,25.73) ; PRB26.2 v1(193.25,56.45) ; v1(137.96,40.32) 137.8,40.48 C39.2 C40.2 C37.2 ; v1(189.07,45.59) 189.07,45.17 189.88,44.37 PCB19.2 ; v1(188.2,62.86) JODD1.7 JODD1.8 ; PRB13.1 190.51,50.87 PCB05.2 190,50.88 v1(189.84,51.05) ; v1(168.14,60.09) 167.99,59.94 PRH04.2 ; PCH09.2 165.84,67.66 v1(166.66,68.48) ; PCM14.2 67.93,115.49 v1(67.8,115.62) ; 56.5,30.75 JKB1.31 58.27,31.88 v1(58.84,32.44) ; PRM11.2 v1(59.01,117.93) ; v1(60.68,114.8) 60.36,114.49 PCM18.2 ; PCB16.2 v1(198.79,45.52) ; v1(132.11,53.46) 131.85,53.2 CC121.2 ; v1(57.59,74.93) 57.58,74.93 57.41,75.1 JRTC1.2 ; v1(127.35,33.5) 127.22,33.63 125.99,33.63 C7.2 ; JWLAN1.77 v1(80.23,141.15) ; v1(151.55,33.27) 151.85,33.57 PBATT1.12 ; PCB14.2 200.4,48.19 v1(200.7,48.5) ; v1(199.04,60.7) 200.8,62.45 SW2.1 ; PC2501.2 61.57,82.29 61.31,82.55 v1(61.31,82.57) 61.2,82.69 PC2503.2 ; RC94.2 RC88.2 120.23,50.34 v1(120.3,50.41) 120.83,50.94 RC89.2 122.23,50.94 122.63,51.35 UC14.4 ; JPWR1.5 v1(218.6,65.21) ; v1(169.09,62.46) PCH11.2 168.44,62.49 PRH09.2 ; v1(175.17,32.2) 176.05,33.09 PBATT1.11 ; PCZ80.2 v1(134.34,115.21) ; v1(145.45,35.36) U5.4 ; v1(35.51,66.28) 35.2,65.97 CLRP1.2 ; JIOB1.2 v1(212.2,38.3) ; C6.2 100.87,34.73 101.38,35.24 R31.2 102.18,35.67 102.36,35.49 v1(102.8,35.49) ; JTP1.10 v1(128.05,25.65) ; JIOB1.18 193.8,33.75 v1(193.58,33.97) ; JTP1.9 v1(115.05,25.65) ; C43.2 129.35,35.43 v1(129.93,34.86) ; v1(217.52,61.46) 216.83,62.15 JEDP1.42 ; PCB17.2 v1(196.1,44.19) 195.7,44.19 195.58,44.31 PRB38.2 ; JHDD1.14 v1(182.9,33.95) ; C28.2 v1(149.01,68.38) ; JPWR1.6 v1(225.75,66.9) ; v1(136.11,40.64) 136.11,40.25 136.9,39.47 C44.2 C38.2 ; v1(213.33,38.35) 213.2,38.22 JIOB1.1 ; v1(117.51,36.06) 117.51,35.25 v4(116.98,34.72) 115.54,33.28 R21.1 ; v1(23.78,122.09) R42.2 ; JODD1.26 182.95,67.79 v1(183.49,68.32) ; PC2502.2 v1(64.61,73.72) ; v1(23.78,74.99) CL20.2 ; PCM13.2 v1(68.87,111.55) ; v1(89.85,33.08) JKBBL1.6 ; RV31.2 27.02,99.94 v1(26.96,99.88) ; UC12.3 v1(44.36,30.84) ; JIOB1.17 v1(216.02,35.24) ; PJPDC1.7 v1(76.68,149.22) ; R60.1 122.18,38.83 122.68,39.33 v1(122.96,39.33) ; RC92.2 141.87,75.94 v1(141.69,76.13) ; JSPK1.6 v1(16.58,2) ; JIOB1.5 v1(209.2,34.92)
  vias: v1(0.43,119.98) v1(1.21,66.52) v1(1.62,120.39) v1(1.62,117.85) v1(1.97,127.45) v1(3.23,88.67) v1(4.16,120.39) v1(4.16,117.85) v1(4.28,113.41) v1(4.64,112.6) v1(4.74,130.5) v1(4.93,63.33) v1(5.8,132.33) v1(5.8,128.67) v1(5.77,114.56) v1(5.77,110.64) v1(5.79,85.8) v1(5.89,41.2) v1(6.37,133.67) v1(6.64,64.38) v1(6.64,63.75) v1(6.85,87.63) v1(6.85,83.97) v1(6.95,43.03) v1(6.95,39.37) v1(7.9,132.33) v1(7.9,128.67) v1(7.91,64.38) v1(7.91,63.75) v1(8.03,114.56) v1(8.03,110.64) v1(8.83,66.52) v1(8.96,130.5) v1(8.95,87.63) v1(8.95,83.97) v1(9.05,43.03) v1(9.05,39.37) v1(9.16,112.6) v1(9.18,64.38) v1(9.18,63.75) v1(9.47,105.03) v1(10.01,85.8) v1(9.97,60.33) v1(10.11,41.2) v1(10.44,45.97) v1(10.64,102.36) v1(10.94,89.87) v1(10.93,1.87) v1(11.24,36.43) v1(11.54,22.07) v1(12.43,80.85) v1(13.37,130.67) v1(13.85,128.67) v1(13.93,58.23) v1(14.45,3.42) v1(15.02,59.05) v1(15.72,60.32) v1(16.39,128.67) v1(16.67,55.75) v1(16.93,22.03) v1(17.81,49.02) v1(17.81,46.99) v1(18.32,4.88) v1(18.41,0.43) v1(18.7,58.99) v1(18.93,128.67) v1(20.16,3.11) v1(20.38,95.15) v1(20.42,24.76) v1(20.61,49.33) v1(20.67,102.45) v1(20.66,100.65) v1(20.74,98.8) v1(20.74,96.9) v1(20.86,35.74) v1(20.86,35.15) v1(20.99,130.67) v1(21.05,57.53) v1(21.05,56.89) v1(21.05,56.26) v1(21.05,55.62) v1(21.05,24.76) v1(21.45,35.74) v1(21.45,35.15) v1(21.47,128.67) v1(21.69,57.53) v1(21.69,56.89) v1(21.69,56.26) v1(21.69,55.62) v1(21.69,24.76) v1(22.01,106.93) v1(22.01,104.9) v1(22.03,35.74) v1(22.03,35.15) v1(22.26,81.85) v1(22.32,24.76) v1(22.69,108.81) v1(23.36,86.73) v1(23.36,85.61) v1(23.36,84.5) v1(23.53,106.61) v1(23.53,104.64) v1(23.59,21.59) v1(23.67,110.29) v1(23.67,108.54) v1(23.91,48.38) v1(24.01,128.67) v1(24.29,21.59) v1(24.48,86.73) v1(24.48,85.61) v1(24.93,1.01) v1(25.12,82.18) v1(25.12,42.86) v1(25.37,120.45) v1(25.37,117.09) v1(25.6,86.73) v1(25.6,85.61) v1(26.01,80.39) v1(26.03,0.43) v1(26.26,82.48) v1(26.55,128.67) v1(26.64,81.34) v1(27.02,79.18) v1(27.02,35.3) v1(27.15,83.05) v1(27.15,45.08) v1(27.34,9.84) v1(27.28,3.93) v1(27.4,6.47) v1(27.47,37.59) v1(27.71,65.13) v1(27.97,81.55) v1(28.16,63.81) v1(28.16,32.82) v1(28.29,6.41) v1(28.61,130.67) v1(29.09,128.67) v1(29.05,87.12) v1(29.18,6.54) v1(29.58,89.81) v1(29.56,37.59) v1(29.75,124.52) v1(30.11,83.47) v1(30.13,32.82) v1(30.08,14.59) v1(30.08,13.01) v1(30.08,11.44) v1(30.85,89.88) v1(30.79,86.05) v1(30.9,125.34) v1(31.63,128.67) v1(31.66,14.59) v1(31.66,13.01) v1(31.66,11.44) v1(31.72,4.57) v1(32.17,5.01) v1(32.29,1.58) v1(32.6,55.66) v1(32.8,32.82) v1(32.8,32.19) v1(32.8,31.55) v1(32.8,30.92) v1(33.23,14.59) v1(33.23,13.01) v1(33.23,11.44) v1(33.28,39.73) v1(33.44,32.82) v1(33.44,32.19) v1(33.44,31.55) v1(33.44,30.92) v1(33.37,2.6) v1(33.65,0.43) v1(33.88,1.58) v1(34.01,5.01) v1(34.17,128.67) v1(34.45,5.52) v1(34.58,3.81) v1(34.58,2.6) v1(34.95,39.66) v1(35.23,130.98) v1(35.34,32.76) v1(35.62,133.67) v1(35.59,8.44) v1(35.72,11.93) v1(36.23,132.33) v1(36.23,130.74) v1(36.23,128.9) v1(36.52,39.61) v1(37.05,16.82) v1(37.05,16.25) v1(37.18,41.59) v1(37.3,10.88) v1(37.44,35.3) v1(37.44,13.46) v1(37.71,94.42) v1(37.71,93.85) v1(37.71,93.15) v1(37.71,92.58) v1(37.71,91.81) v1(37.71,91.24) v1(38.52,132.33) v1(38.52,130.74) v1(38.52,128.9) v1(38.45,8) v1(39.15,44.51) v1(39.32,5.53) v1(39.72,12.82) v1(39.85,113.34) v1(39.85,35.94) v1(39.85,35.3) v1(39.79,14.47) v1(39.98,111.31) v1(39.98,110.67) v1(39.98,110.04) v1(40.61,113.21) v1(40.61,112.58) v1(40.61,111.94) v1(40.61,111.31) v1(40.61,110.67) v1(40.8,132.33) v1(40.8,130.74) v1(40.8,128.9) v1(40.77,20.63) v1(40.77,13.01) v1(40.86,107.12) v1(41.25,112.58) v1(41.25,111.94) v1(41.25,111.31) v1(41.25,110.67) v1(41.25,73.03) v1(42.32,73.94) v1(42.9,53.53) v1(42.9,52.64) v1(43.01,75.15) v1(43.24,133.67) v1(43.85,44.38) v1(44.1,53.53) v1(44.1,52.64) v1(44.17,62.67) v1(45.5,94.73) v1(45.5,94.16) v1(45.5,93.46) v1(45.5,92.89) v1(45.5,92.13) v1(45.5,91.56) v1(45.88,60.76) v1(47.02,52.13) v1(47.02,50.54) v1(47.02,49.14) v1(47.68,135.58) v1(48.03,22.93) v1(48.1,30.09) v1(48.1,28) v1(48.99,58.22) v1(49.44,28) v1(49.5,30.09) v1(50.03,137.12) v1(50.01,111.82) v1(50.01,111.18) v1(50.01,110.55) v1(50.64,112.45) v1(50.64,111.82) v1(50.64,111.18) v1(50.58,56.57) v1(50.9,107.63) v1(50.96,132.2) v1(51.28,112.45) v1(51.28,111.82) v1(51.28,111.18) v1(52.55,140.2) v1(52.55,138.62) v1(54.39,135.63) v1(54.83,62.03) v1(54.9,66.8) v1(55.65,22.93) v1(56.36,141.37) v1(56.99,47.81) v1(57.06,50.67) v1(57.63,140.2) v1(57.63,138.62) v1(58.2,128.84) v1(59.72,111.88) v1(59.72,111.31) v1(60.36,89.78) v1(60.36,89.15) v1(60.36,88.51) v1(60.36,87.88) v1(60.36,87.24) v1(60.36,86.61) v1(60.87,100.03) v1(60.99,78.16) v1(60.99,76.39) v1(61.44,128.77) v1(61.69,132.27) v1(62.39,100.66) v1(62.71,39.93) v1(62.77,78.16) v1(62.77,76.39) v1(62.98,112.9) v1(63.27,22.93) v1(63.6,113.52) v1(63.6,112.28) v1(63.72,37.44) v1(63.98,141.37) v1(64.11,134.74) v1(64.22,112.9) v1(64.8,132.27) v1(65.06,133.92) v1(65.06,105.34) v1(65.06,104.71) v1(65.06,104.07) v1(65.38,134.93) v1(65.76,106.68) v1(65.76,105.98) v1(65.76,105.34) v1(65.76,104.71) v1(65.76,104.07) v1(65.95,100.08) v1(66.33,106.68) v1(66.33,106.04) v1(66.33,105.41) v1(66.33,104.77) v1(66.33,104.14) v1(66.9,104.14) v1(68.11,120.65) v1(68.49,120.2) v1(68.93,119.76) v1(69.63,66.99) v1(69.69,65.21) v1(69.69,64.45) v1(69.69,63.5) v1(70.89,22.93) v1(71.38,143.16) v1(73.15,145.98) v1(73.15,145.35) v1(73.15,144.71) v1(73.54,150.47) v1(73.52,106.04) v1(73.62,103.55) v1(73.78,145.98) v1(73.78,145.35) v1(73.78,144.71) v1(74.23,54.45) v1(74.93,110.97) v1(75.04,104.26) v1(75.04,97.3) v1(75.22,59.76) v1(75.71,95.68) v1(76.42,99.67) v1(76.57,94.56) v1(76.67,93.34) v1(76.72,92.63) v1(76.95,95.68) v1(77.06,112.25) v1(77.08,106.7) v1(77.13,105.64) v1(77.08,104.32) v1(77.27,102.49) v1(77.34,97.25) v1(78.51,22.93) v1(81.16,150.47) v1(81.82,130.87) v1(82.08,110.17) v1(82.22,52.13) v1(83.22,133.09) v1(83.79,113.6) v1(84.49,106.55) v1(84.81,99.5) v1(85.41,114.78) v1(86.13,22.93) v1(86.46,149.47) v1(87.41,149.47) v1(87.47,60.07) v1(88.36,149.47) v1(88.74,105.34) v1(88.78,150.47) v1(89.76,102.04) v1(90.01,149.47) v1(90.97,149.47) v1(91.92,98.93) v1(93.75,22.93) v1(95.35,149.47) v1(95.55,153.97) v1(96.89,154) v1(97.63,123.44) v1(97.76,124.39) v1(97.95,152.17) v1(99.54,135.06) v1(99.76,38.01) v1(100.05,152.17) v1(100.81,130.3) v1(101.11,154) v1(101.37,23.18) v1(102.46,130.36) v1(102.57,151) v1(102.71,135.12) v1(104.42,71.41) v1(104.93,89.38) v1(106.21,133.73) v1(106.39,71.41) v1(106.84,131.19) v1(106.96,89.38) v1(108.96,23.88) v1(109.82,82.91) v1(110.01,149.37) v1(115.19,92.01) v1(115.73,70.41) v1(116.58,23.88) v1(117.33,94.99) v1(117.63,149.37) v1(118.18,70.23) v1(119.56,78.24) v1(119.56,74.97) v1(119.8,83.24) v1(119.96,76.41) v1(120.71,75.23) v1(121.63,79.29) v1(121.76,83.35) v1(122.14,123.25) v1(122.29,57.84) v1(122.5,83.37) v1(122.53,70.17) v1(122.9,79.35) v1(123.77,84.19) v1(123.82,82.33) v1(124.18,39.41) v1(124.2,23.88) v1(124.32,97.79) v1(124.56,133.73) v1(124.56,130.87) v1(124.62,127.25) v1(124.73,76.24) v1(124.68,70.21) v1(124.79,79.42) v1(124.87,78.43) v1(124.96,97.79) v1(125.25,149.37) v1(125.74,84.16) v1(125.73,76.23) v1(125.84,57.91) v1(125.88,81.42) v1(126.04,39.41) v1(126.73,76.2) v1(127.22,129.22) v1(127.48,49.23) v1(127.73,82.16) v1(127.69,76.2) v1(127.67,61.19) v1(127.73,57.33) v1(127.77,78.23) v1(127.76,50.78) v1(128.23,67.29) v1(128.3,59.7) v1(128.61,50.36) v1(128.73,77.1) v1(128.81,76.51) v1(129.03,51.76) v1(129.64,133.73) v1(129.6,80.51) v1(129.72,83.5) v1(129.73,78.7) v1(130.18,87.31) v1(130.34,129.22) v1(130.84,75.99) v1(131.11,81.56) v1(131.23,70.2) v1(131.31,87.12) v1(131.82,23.88) v1(132.1,87.51) v1(132.18,131.12) v1(132.87,149.37) v1(133.21,79.44) v1(133.31,78.33) v1(133.43,77.16) v1(133.49,70.27) v1(134.48,65.17) v1(134.78,131.44) v1(134.78,130.87) v1(134.93,71.66) v1(134.94,70.49) v1(135.42,131.44) v1(135.42,130.87) v1(135.61,132.46) v1(135.67,133.85) v1(136.05,131.44) v1(136.05,130.87) v1(136.38,95.47) v1(136.69,131.44) v1(136.69,130.87) v1(136.9,23.88) v1(138.59,129.98) v1(139.22,85.76) v1(139.22,82.91) v1(139.44,27.1) v1(139.53,119.31) v1(139.53,118.68) v1(139.53,118.04) v1(139.53,117.41) v1(140.12,119.31) v1(140.12,118.68) v1(140.12,118.04) v1(140.12,117.41) v1(140.24,82.91) v1(140.49,149.37) v1(140.5,28.93) v1(140.5,25.27) v1(140.83,86.41) v1(141.45,96.26) v1(141.5,70.91) v1(141.95,69.51) v1(142.58,82.72) v1(142.6,28.93) v1(142.6,25.27) v1(142.91,94.93) v1(143.02,101.92) v1(143.54,122.89) v1(143.54,121.74) v1(143.54,104.2) v1(143.67,100.26) v1(143.66,27.1) v1(143.84,48.19) v1(144.05,66.84) v1(144.49,42.97) v1(144.62,135.06) v1(144.81,112.33) v1(144.81,111.69) v1(145.45,112.33) v1(145.45,111.69) v1(145.38,43.85) v1(145.45,40.76) v1(145.7,103.01) v1(145.7,102.42) v1(145.89,41.21) v1(146.08,112.33) v1(146.08,111.69) v1(146.27,103.01) v1(146.27,102.42) v1(146.27,44.74) v1(146.59,141.66) v1(146.59,140.14) v1(146.59,138.62) v1(146.72,112.33) v1(146.72,111.69) v1(146.85,103.01) v1(146.85,102.42) v1(147.06,23.88) v1(147.35,112.33) v1(147.35,111.69) v1(147.42,109.85) v1(147.42,109.22) v1(147.42,108.58) v1(147.42,107.95) v1(147.42,107.25) v1(147.42,106.61) v1(147.42,106.04) v1(147.42,105.41) v1(147.42,103.01) v1(147.42,102.42) v1(147.57,134.74) v1(147.99,112.33) v1(147.99,111.69) v1(148.11,149.37) v1(148.12,141.66) v1(148.12,140.14) v1(148.12,138.62) v1(148.62,112.33) v1(148.62,111.69) v1(149.26,112.33) v1(149.26,111.69) v1(149.26,111.06) v1(149.64,141.66) v1(149.64,140.14) v1(149.64,138.62) v1(149.79,111.36) v1(150.1,133.32) v1(150.1,132.75) v1(150.29,102.9) v1(150.29,102.32) v1(150.36,112.26) v1(150.47,103.46) v1(150.8,133.32) v1(150.8,132.75) v1(150.85,71.5) v1(150.86,102.9) v1(150.86,102.32) v1(151.42,118.04) v1(151.42,117.41) v1(151.42,116.77) v1(151.42,116.14) v1(151.42,115.5) v1(151.42,114.87) v1(151.42,114.23) v1(151.42,113.6) v1(151.43,102.9) v1(151.43,102.32) v1(151.49,133.32) v1(151.49,132.75) v1(151.81,103.59) v1(151.86,118.6) v1(152,102.32) v1(152.05,118.04) v1(152.05,117.41) v1(152.05,116.82) v1(152.05,116.24) v1(152.69,118.37) v1(152.69,117.79) v1(152.69,117.15) v1(152.69,116.57) v1(152.94,102.87) v1(153.32,119.18) v1(153.32,118.55) v1(153.32,117.98) v1(153.32,117.41) v1(153.58,138.87) v1(153.96,119.18) v1(153.96,118.55) v1(153.96,117.97) v1(154.54,118.55) v1(154.59,119.18) v1(154.68,23.88) v1(155.23,119.18) v1(155.73,149.37) v1(156.56,108.9) v1(157.13,88.51) v1(157.77,110.99) v1(157.77,88.51) v1(157.9,43.87) v1(158.4,114.8) v1(158.4,112.9) v1(158.4,112.26) v1(158.4,111.63) v1(158.4,110.99) v1(158.66,88.51) v1(159.04,115.44) v1(159.04,114.8) v1(159.04,114.17) v1(159.04,113.53) v1(159.04,112.9) v1(159.04,112.26) v1(159.04,111.63) v1(159.04,110.99) v1(159.29,88.51) v1(159.42,115.98) v1(159.67,115.44) v1(159.67,114.8) v1(159.67,114.17) v1(159.67,113.53) v1(159.67,112.9) v1(159.67,112.26) v1(159.67,111.63) v1(159.67,110.99) v1(160.05,115.98) v1(160.24,50.67) v1(160.24,49.91) v1(160.24,49.27) v1(160.31,115.44) v1(160.31,114.8) v1(160.31,114.17) v1(160.31,113.53) v1(160.31,112.9) v1(160.31,112.26) v1(160.31,111.63) v1(160.31,110.99) v1(160.3,72.22) v1(160.3,71.01) v1(160.3,69.74) v1(160.69,115.98) v1(160.88,115.44) v1(160.88,114.8) v1(160.88,114.17) v1(160.88,113.53) v1(160.88,112.9) v1(160.88,112.26) v1(160.91,72.22) v1(160.91,71.01) v1(160.91,69.74) v1(161.13,101.02) v1(161.2,94.48) v1(161.2,93.85) v1(161.2,93.21) v1(161.2,92.58) v1(161.32,63.94) v1(161.46,115.44) v1(161.46,114.8) v1(161.46,114.17) v1(161.46,113.53) v1(161.46,112.9) v1(161.46,112.26) v1(161.9,69.25) v1(161.9,68.67) v1(161.9,68.1) v1(161.9,67.53) v1(162.22,67.02) v1(162.3,23.88) v1(162.53,68) v1(162.91,67.56) v1(162.85,66.96) v1(162.85,66.39) v1(162.85,65.82) v1(163.1,54.03) v1(163.35,149.37) v1(163.43,66.01) v1(164.58,47.61) v1(165.21,56.38) v1(165.21,54.37) v1(165.26,53.46) v1(165.52,48.38) v1(165.64,57.46) v1(165.79,55.38) v1(165.9,47.52) v1(166.28,57.46) v1(166.38,56.38) v1(166.38,54.37) v1(166.85,41.33) v1(167.17,47.52) v1(167.55,41.33) v1(167.74,47.52) v1(167.99,38.22) v1(168.31,41.33) v1(168.37,47.52) v1(168.58,106.61) v1(168.69,38.22) v1(169.01,41.33) v1(169.07,144.33) v1(169.33,136.71) v1(169.39,50.73) v1(169.39,38.22) v1(169.82,129.11) v1(169.83,51.18) v1(169.92,23.88) v1(170.09,38.22) v1(170.3,121.5) v1(170.28,51.56) v1(170.79,113.9) v1(170.79,38.22) v1(171.48,38.22) v1(171.69,99.65) v1(172.12,38.22) v1(172.18,92.04) v1(172.82,38.22) v1(173.82,84.6) v1(174.15,41.84) v1(175.93,41.78) v1(176.5,41.78) v1(177.54,23.88) v1(177.95,78.2) v1(178.53,41.74) v1(179.42,38.22) v1(179.49,61.77) v1(179.49,61.2) v1(180.06,38.22) v1(180.35,52.31) v1(182.91,29.28) v1(183.99,49.72) v1(184.05,73.64) v1(186.41,48.57) v1(186.41,47.94) v1(186.41,47.3) v1(186.74,40.64) v1(186.74,38.98) v1(187.17,48.57) v1(187.17,47.94) v1(187.17,47.3) v1(187.93,48.57) v1(187.93,47.94) v1(187.93,47.3) v1(188.39,40.64) v1(188.39,38.98) v1(188.69,60.76) v1(188.69,60.07) v1(188.69,48.57) v1(188.69,47.94) v1(188.69,47.3) v1(189.01,51.05) v1(189.25,60.07) v1(189.73,37.5) v1(190.03,60.07) v1(190.46,69.51) v1(190.53,29.28) v1(190.58,60.07) v1(190.72,60.76) v1(190.92,38.69) v1(191.42,40.7) v1(192.38,60.89) v1(193.48,40.7) v1(194.23,50.91) v1(194.23,48.78) v1(195.3,49.85) v1(196.36,50.91) v1(196.36,48.78) v1(197.39,35.05) v1(197.99,68.31) v1(198.15,29.28) v1(199.44,35.03) v1(200.76,46.41) v1(204.46,41.39) v1(204.5,35.75) v1(205.08,35.75) v1(205.34,63.85) v1(205.56,67.47) v1(205.71,35.75) v1(205.77,29.28) v1(205.98,51.13) v1(206.4,65.68) v1(206.4,62.02) v1(207.81,45.52) v1(208.19,40.48) v1(208.31,52.7) v1(208.44,47.81) v1(208.5,65.68) v1(208.5,62.02) v1(208.5,49.91) v1(208.89,54.16) v1(209.56,63.85) v1(211.43,46.79) v1(211.68,39.3) v1(213.38,28.86) v1(213.52,45) v1(214.03,43.94) v1(219.15,23.88) v1(220.72,68.97) v1(224.97,44.04) v1(224.97,36.42) v1(224.97,28.8) v1(226.6,51.49) v1(227.97,66.6) v1(227.97,58.98) v4(21.73,34.44) v4(22.18,56.55) v4(24,47.79) v4(25.47,119.85) v4(30.43,124.77) v4(39.4,108.78) v4(40.52,44.93) v4(43.48,53.04) v4(44.52,62.07) v4(48.79,28) v4(49.3,28.62) v4(51.37,113.15) v4(61.97,82.7) v4(63.27,130.73) v4(66.2,103.53) v4(66.81,105.11) v4(69.33,55.66) v4(87.59,58.9) v4(89.61,32.6) v4(102.87,130.88) v4(107.46,131.2) v4(135.7,133.07) v4(147.86,107.63) v4(149.04,139.3) v4(149.77,112.07) v4(152.05,119.12) v4(155.24,119.9) v4(158.48,115.44) v4(160.99,70.37) v4(161.11,72.84) v4(165.18,55.41) v4(167.43,46.17) v4(170.77,51.16) v4(171.06,39.78) v4(179.42,39.64) v4(189,50.1) v4(191.61,60.96) v4(203.65,42.87) v4(207.79,54.15)
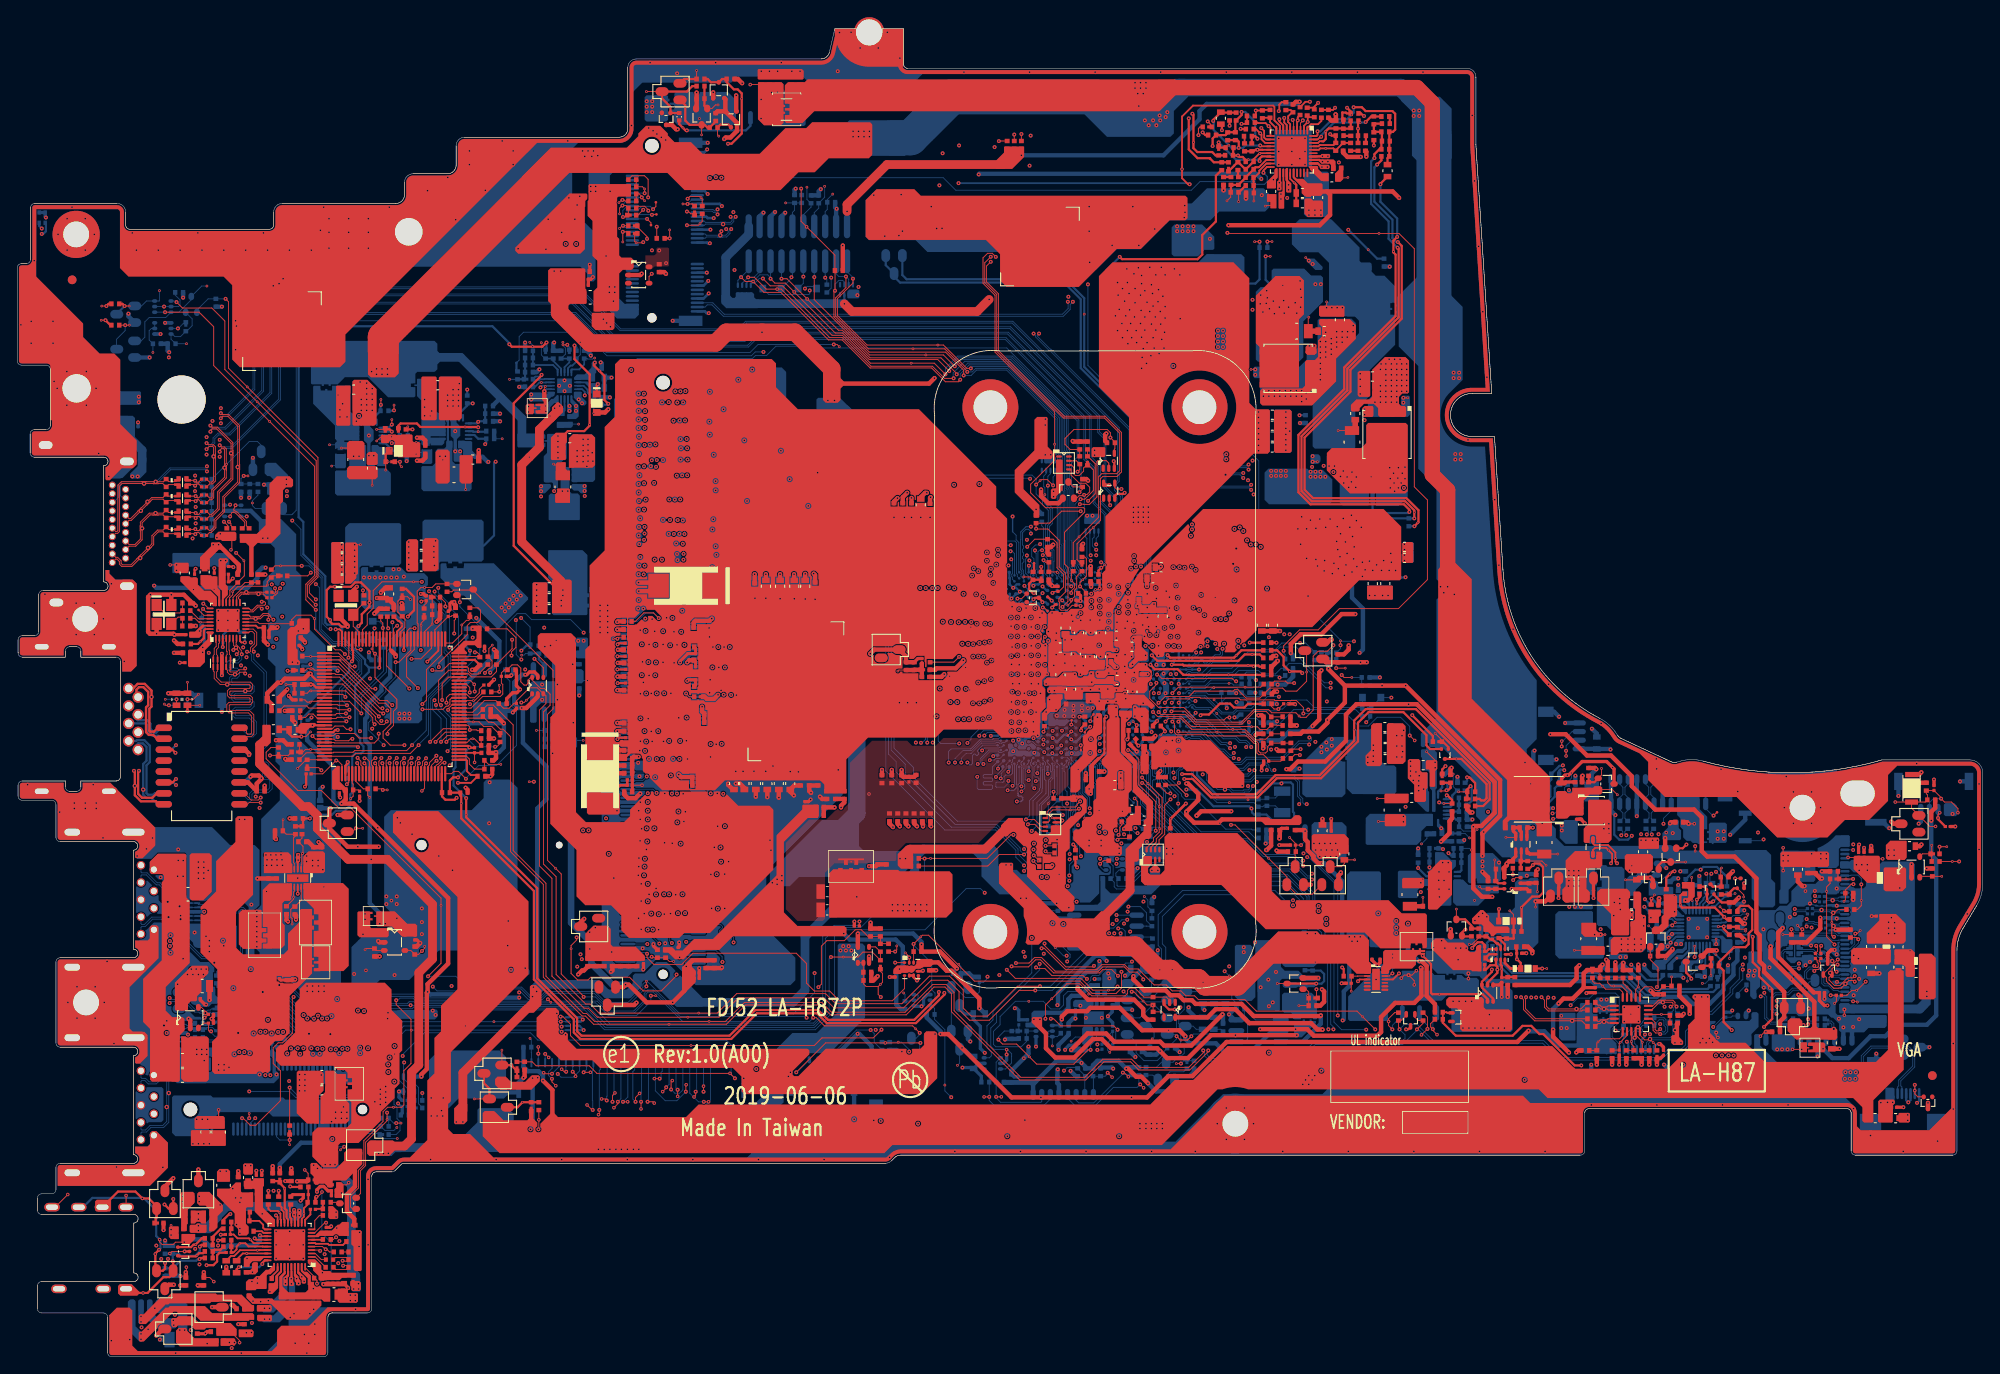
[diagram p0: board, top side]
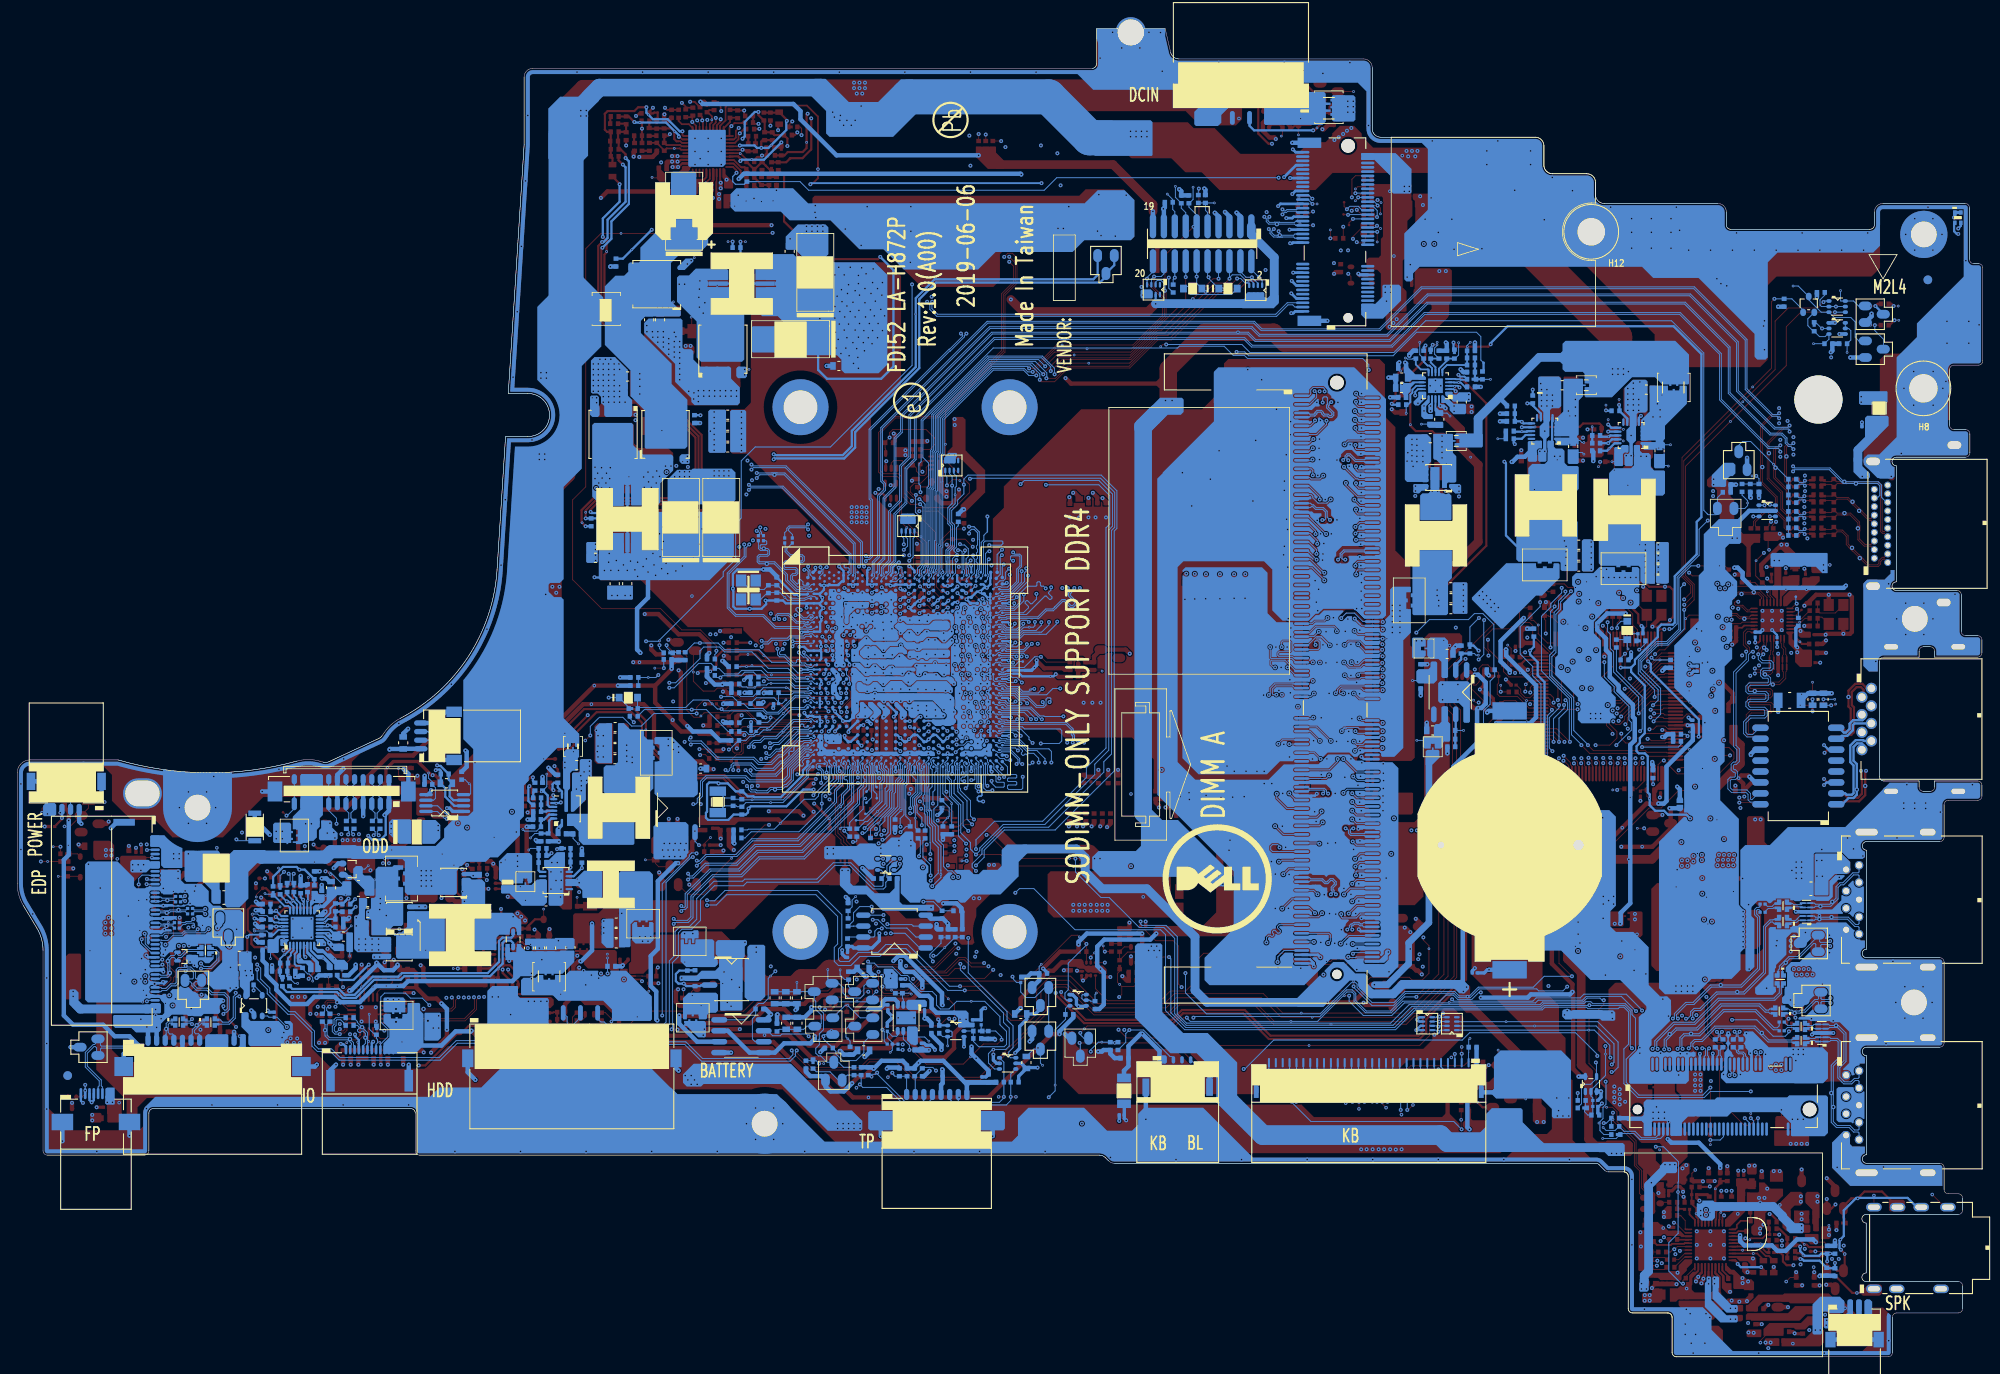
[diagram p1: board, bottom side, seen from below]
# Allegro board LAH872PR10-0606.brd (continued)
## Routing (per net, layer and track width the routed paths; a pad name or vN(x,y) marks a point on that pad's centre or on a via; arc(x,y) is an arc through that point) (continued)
GNDA: length 25.7
  TOP w0.102: v1(19.59,9.84) 19.66,9.9 v4(19.66,10.42) ; v4(22.84,8.75) 22.37,9.22 RA38.1
  TOP w0.203: UA1.19 30.26,16.25 v1(30.07,16.44)
  TOP w0.254: CA505.2 24.16,14.2 v1(23.65,14.2) ; CA506.2 24.26,12.1 23.52,12.1 23.22,11.81 23.22,11.08 22.79,10.65 v1(22.01,10.65)
  TOP w0.356: CA26.2 32.01,18.85 CA488.2 33.24,18.47 v1(32.93,18.16)
  TOP w0.457: RA62.2 v1(17,14.73) ; CA52.1 v1(31.15,20.43)
  TOP w0.508: CA53.1 v1(19.59,9.84) ; v1(21.69,9.84) RA38.1
  VCC w0.203: 8.95,7.9 JHP1.7 ; JHP1.7 8.95,7.25 ; JHP1.7 10,7.25 ; JHP1.7 11.06,7.9 ; JHP1.7 11.06,7.25
  GND w0.203: JHP1.7 11.06,7.9 ; JHP1.7 8.95,7.9 ; JHP1.7 11.06,7.25 ; JHP1.7 8.95,7.25 ; JHP1.7 10,7.25
  BOTTOM w0.508: v1(18.97,9.38) 18.92,9.43 RA57.2 17.23,9.43 CA504.2 ; v1(17.18,13.52) RA54.2 CA498.2
  vias: v1(16.16,12.93) v1(16.73,11.37) v1(17.52,11.38) v1(20.68,12.55) v1(21.05,16.63) v1(21.05,16) v1(21.18,10.74) v1(23.34,12.94) v1(25.05,19.55) v1(25.37,18.47) v1(25.48,15.38) v1(25.88,14.92) v1(25.88,14.35) v1(26.01,18.47) v1(27.28,8.76) v1(27.92,9.15) v1(27.91,8.57) v1(29.79,19.3) v4(25.88,17.95)
V3D3_STB: length 6.1
  TOP w0.203: UA1.16 31.46,15.97 31.3,16.13 31.3,16.37
  TOP w0.254: RA41.1 RA37.1 30.51,20.19 31.09,19.62 v2(31.09,19.53) 31.09,17.24 31.3,17.03 31.3,16.37
VBAT: length 1
  BOTTOM w0.102: PRB35.2 v2(198.97,46.31)
VDD_1.2V: length 7
  TOP w0.254: v1(67.12,115.59) 67.01,115.49 67.01,115.26 v2(67.65,114.62) 68.23,114.04 68.23,111.25 v1(68.68,110.8)
  BOTTOM w0.254: PRM03.2 68.58,110.7 v1(68.68,110.8)
  BOTTOM w0.508: v1(67.12,115.59) 67.01,115.49 PCM14.1
VDD_CHG: length 17
  TOP w0.102: PRB44.1 v2(194.57,55.74)
  IN1 w0.254: v1(193.86,53.07) 193.71,52.92 193.71,51.87 193.05,51.22 191.38,51.22 191.23,51.07 191.23,49.16 188.36,46.29 188.36,46.26 187.69,45.59 v1(187.55,45.59)
  BOTTOM w0.254: v1(187.55,45.59) 189.33,43.81 190.85,43.81 191.22,44.18 PRB39.2
VDDCR_FCH_S5:
  vias: v2(149.96,42.01)
VDDIO_APU: length 3.4
  TOP w0.203: PUZ01.6 147.92,143.32 147.68,143.56 v2(147.68,143.82) 147.68,144.23 148.15,144.7 PRZ23.2 147.99,144.95 PCZ64.1
VDDIO_AUDIO: length 21
  TOP w0.305: v1(135.8,64.32) v2(134.03,62.56) 133.99,62.51 RC123.2
  IN1 w0.381: v1(135.8,64.32) 135.8,64.38 136.96,65.54 136.96,71.85 135.53,73.28 131.12,73.28 130.44,73.96 129.77,73.96 129.64,73.84 129.44,73.84 v1(129.19,73.59)
  BOTTOM w0.4: v1(129.19,73.59) 129.51,73.91 UC1.AM13
VDDP_1.2V: length 1.2
  TOP w0.254: PDM01.1 67.34,112.96 v1(67.47,113.09)
VDDP_CHG:
  vias: v2(191.55,46.27)
VIN_0.775V:
  vias: v2(150.83,45.89)
0.95_1.8VALW_PWREN: length 206.7
  TOP w0.102: v1(120.11,39.3) 120.43,39.3 121.26,38.48 127.42,38.48 v1(127.86,38.03)
  TOP w0.203: v1(37.01,84.58) 37.48,84.58 37.73,84.33 UE1.127
  TOP w0.254: v1(165.97,68.67) 165.58,68.29 PRH01.1
  IN1 w0.127: v1(127.86,38.03) 128.2,38.37 141.57,38.37 148.23,45.04 148.23,46.01 150.1,47.87 161.71,47.87 167.85,54.02 167.85,57.98 166.81,59.03 v1(165.68,59.03) 165.68,59.4 168.06,61.78 168.06,68.7 167.61,69.15 166.44,69.15 v1(165.97,68.67)
  IN2 w0.127: v1(37.01,84.58) 37.01,84.43 37.65,83.79 37.65,76.32 37.66,76.31 37.66,70.58 36.63,69.55 36.63,69.06 38,67.69 47.85,67.69 48.61,66.92 48.61,59.9 55.93,52.58 55.93,42.48 62.98,35.44 67.46,35.44 67.85,35.04 100.86,35.04 102.73,36.91 105.8,36.91 105.95,36.76 108.57,36.76 109.78,37.98 119.3,37.98 120.11,38.79 v1(120.11,39.3)
  BOTTOM w0.102: v1(127.86,38.03) 127.65,37.82 127.65,36.7 R66.2
  BOTTOM w0.254: PR1801.1 165.59,59.11 v1(165.68,59.03)
0.775PW_EN#: length 160.6
  TOP w0.102: RE47.2 31.02,75.67 33.64,75.67 33.89,75.42 UE1.17 37.06,75.42 37.26,75.23 v1(38.59,75.23) ; v1(150.97,42.73) 150.99,42.72 PR801.1
  IN1 w0.127: v1(150.97,42.73) 150.3,42.73 142.74,35.17 136.54,35.17 135.88,34.51 135.05,34.51 134.6,34.06 129.6,34.06 129.01,34.64 126.64,34.64 125.75,33.75 123.04,33.75 122.54,34.25 120.16,34.25 119.63,33.71 111.9,33.71 111.27,34.34 106.48,34.34 106.18,34.04 93.15,34.04 89.13,38.07 70.35,38.07 66.84,41.59 66.84,41.91 66.07,42.67 64.95,42.67 63.03,44.59 63.03,52.04 60.62,54.45 60.62,64.63 54.85,70.4 54.85,72.68 53.99,73.54 53.99,77.48 53.44,78.04 46.92,78.04 46.79,78.17 43.81,78.17 41.71,76.07 39.46,76.07 38.63,75.23 v1(38.59,75.23)
0.775PW_EN_R: length 3.5
  TOP w0.102: PQ801.2 149.75,42.75 150.07,42.43 PR801.2 PC805.1 v2(148.93,40.83)
32K_X1: length 13.8
  BOTTOM w0.102: UC1.BA2 136.01,68.61 136.49,68.13 136.49,67.37 139.43,64.43 v2(140.85,64.43) 143.72,64.43 CC18.1 144.74,63.96 144.84,64.06 RC97.2 146.2,64.06 YC1.1
32K_X2: length 14.1
  BOTTOM w0.102: UC1.AY2 135.85,69.31 136.29,68.87 136.29,68.61 136.69,68.21 136.69,67.45 139.38,64.76 v2(143.01,64.76) 144.13,64.76 CC19.1 145.07,64.83 RC97.1 146.2,64.97 YC1.2
48M_X1: length 10.3
  BOTTOM w0.102: YC2.1 143.25,89.22 141.61,89.22 RC116.2 C2.1 140.08,89.71 138.56,88.2 136.91,88.2 136.47,88.38 136.39,88.38 136.31,88.46 136.06,88.46 135.97,88.38 135.7,88.38 UC1.F2
48M_X2: length 7.1
  BOTTOM w0.102: YC2.3 142.01,88.05 141.27,88.8 RC116.1 141.06,88.85 C1.1 139.76,88.85 v2(139.2,88.29) 138.88,87.96 136.96,87.96 136.48,88.16 UC1.F1
+0.775MOS: length 31.3
  TOP w0.508: v1(121.38,39.24) 121.38,39.56 122.02,40.19 124.3,40.19 124.68,40.57 128.11,40.57 130.72,37.97 v2(133.79,37.97) 135.04,37.97 v1(135.73,37.27)
  BOTTOM w0.254: Q15.1 120.29,38.53 R60.2 121.26,39.12 v1(121.38,39.24)
  BOTTOM w0.508: v1(135.73,37.27) 135.73,36.95 136.24,36.44 139.29,36.44 140.37,35.36 U5.5 143.29,35.36 145.83,37.9 U5.2
+APU_CORE: length 61.8
  TOP w0.254: v1(128.11,127.88) 128.38,127.62 137.16,127.62 137.7,128.16 137.7,130.42 139.29,132.01 139.29,137.32 139.94,137.97 PRZ51.2 ; PR904.1 v1(143.22,83.03)
  IN1 w0.254: v1(143.22,83.03) 143.22,84.71 140.17,87.75 133.99,87.75
  BOTTOM w0.254: UC1.K21 125.55,85.91 v1(125.79,85.66) ; PCZ78.1 135.33,114.75 134.3,113.71 128.01,113.71 126.58,115.15 126.58,126.35 v1(128.11,127.88)
  vias: v1(119.81,84.33) v1(120.25,86.48) v1(120.45,80.39) v1(120.75,84.15) v1(120.7,83.3) v1(120.73,81.65) v1(120.7,79.35) v1(121.41,86.37) v1(121.73,81.65) v1(121.74,80.65) v1(122.53,86.23) v1(122.66,85.52) v1(122.69,84.3) v1(122.73,81.7) v1(122.91,80.34) v1(123.55,79.36) v1(123.58,85.62) v1(123.81,81.38) v1(123.88,80.35) v1(124.68,85.66) v1(124.74,84.19) v1(124.65,81.39) v1(127.61,121.03) v1(127.86,124.9) v1(127.92,123.44) v1(127.86,119.31) v1(128.05,121.79) v1(128.43,124.2) v1(128.37,120.14) v1(128.43,118.49) v1(128.69,122.74) v1(128.81,121.03) v1(128.94,126.49) v1(129,124.9) v1(129,119.31) v1(129.07,117.79) v1(129.19,123.63) v1(129.26,121.72) v1(129.38,120.14) v1(129.51,118.49) v1(129.71,98.77) v1(129.71,98.19) v1(129.71,97.6) v1(129.71,97.02) v1(129.76,125.92) v1(129.83,120.9) v1(129.89,124.2) v1(129.89,122.55) v1(130.02,119.31) v1(129.96,116.96) v1(130.08,117.91) v1(130.27,126.61) v1(130.27,98.79) v1(130.27,98.21) v1(130.27,97.62) v1(130.27,97.04) v1(130.53,123.44) v1(130.53,120.14) v1(130.59,121.66) v1(130.65,125.73) v1(130.65,124.77) v1(130.65,118.55) v1(130.72,116.2) v1(130.65,114.93) v1(130.84,117.22) v1(130.85,98.79) v1(130.85,98.21) v1(130.85,97.62) v1(130.85,97.04) v1(131.03,123.95) v1(131.03,120.9) v1(131.03,119.38) v1(131.23,115.5) v1(131.29,122.61) v1(131.29,117.91) v1(131.43,98.79) v1(131.43,98.21) v1(131.43,97.62) v1(131.43,97.04) v1(131.61,126.68) v1(131.61,121.53) v1(131.73,116.39) v1(131.8,124.65) v1(131.8,120.07) v1(131.92,123.63) v1(131.99,122.17) v1(131.99,118.49) v1(132.11,117.28) v1(132.24,120.9) v1(132.3,125.79) v1(132.3,119.38) v1(132.62,124.07) v1(132.56,122.68) v1(132.69,116.64) v1(132.81,121.53) v1(132.94,126.68) v1(132.88,120.07) v1(133,118.3) v1(133.13,123.31) v1(133.32,119.12) v1(133.26,117.28) v1(133.38,125.79) v1(133.38,122.11) v1(133.38,120.77) v1(134.46,126.49) v1(135.1,125.79) v1(144.24,109.85) v1(144.24,109.22) v1(144.24,108.58) v1(144.24,107.95) v1(144.24,107.31) v1(144.24,106.68) v1(144.24,105.98) v1(144.24,105.34) v4(135.14,120.7)
+APU_CORE_NB: length 168.3
  TOP w0.254: v1(156.5,144.27) 156.43,144.27 156.13,144.57 PRZ02.1
  TOP w0.508: v1(141.07,63.43) 137.58,63.43 137.07,62.92 v1(137.04,62.92) ; v1(129.7,44.25) 129.7,43.87 130.97,42.6 133.45,42.6 134.02,42.03 134.97,42.03 135.54,41.46 136.5,41.46 136.93,41.03 142.26,41.03 143.67,39.62 151.42,39.62 v1(151.48,39.68)
  IN1 w0.508: v1(152.18,76.2) 153.01,75.37 153.01,73.27 152.43,72.7 148.18,72.7 147.42,71.94 147.42,70.61 146.53,69.72 143.67,69.72 141.07,67.11 v1(141.07,63.43) ; v1(137.04,62.92) 136.8,62.68 136.8,59.04 133,55.24 132.05,55.24 130.87,54.06 v1(130.87,52.93)
  IN2 w0.254: v1(156.5,144.27) 158.09,144.27 159.61,142.74 159.61,133.6 162.66,130.55 162.66,102.87 163.48,102.04 163.48,92.64 161.48,90.64 v1(161.32,90.64)
  IN2 w0.508: v1(155.99,81.85) 155.99,79.88 152.31,76.2 v1(152.18,76.2) ; v1(130.87,52.93) 130.37,52.43 130.37,45.52 129.75,44.9 129.75,44.31 v1(129.7,44.25) 129.7,44.19 129.19,43.68 127.63,43.68 127.06,43.11 126.15,43.11 123.86,40.83 v1(123.54,40.83)
  BOTTOM w0.254: v1(161.32,90.64) 161.3,90.61 PCZ101.1
  BOTTOM w0.508: v1(129.7,44.25) 129.89,44.25 130.79,45.15 C36.1 131.18,44.77 R71.1 ; v1(155.99,81.85) 156.37,82.23 156.37,86.99 155.1,88.26 v1(155.1,91.24) ; v1(151.48,39.68) 151.48,38.73 149.39,36.63 U5.3
  vias: v1(119.94,77.41) v1(120.52,77.45) v1(121.78,77.57) v1(122.8,77.57) v1(123.73,77.64) v1(124.71,77.57) v1(125.54,79.44) v1(125.73,82.72) v1(125.73,77.64) v1(126.72,81.62) v1(126.73,80.12) v1(126.73,77.64) v1(126.84,88.01) v1(126.84,86.29) v1(126.84,85.47) v1(126.75,84.64) v1(126.84,79.5) v1(127.73,84.51) v1(127.73,83.56) v1(127.73,77.53) v1(127.8,85.4) v1(127.75,81.5) v1(127.75,79.5) v1(127.99,88.7) v1(128.73,84.7) v1(128.73,81.64) v1(128.7,80.26) v1(128.75,79.56) v1(128.73,77.71) v1(129,85.53) v1(129.07,88.01) v1(129.52,82.42) v1(129.5,81.41) v1(129.64,77.38) v1(129.76,85.34) v1(129.8,79.56) v1(130.08,86.29) v1(130.2,88.81) v1(130.78,85.09) v1(130.99,83.76) v1(131.1,80.46) v1(131.31,88.71) v1(131.34,85.96) v1(131.47,84.89) v1(132.38,88.17) v1(132.37,84.89) v1(132.38,80.45) v1(132.59,86.03) v1(132.63,82.66) v1(132.63,81.56) v1(133.21,80.45) v1(133.51,89.02) v1(133.82,85.95) v1(133.89,88.32) v1(133.89,87.05) v1(148.81,96.26) v1(149.13,94.48) v1(149.26,97.66) v1(149.83,96.26) v1(149.83,92.83) v1(150.28,97.28) v1(150.91,96.32) v1(150.91,92.71) v1(151.1,91.94) v1(151.35,97.4) v1(151.93,92.58) v1(151.86,91.37) v1(152.05,96.45) v1(152.56,97.4) v1(152.82,91.05) v1(153.01,92.26) v1(153.32,94.8) v1(153.39,96.52) v1(153.45,93.85) v1(153.51,91.63) v1(153.7,93.02) v1(153.77,95.69) v1(154.09,97.47) v1(154.21,90.86) v1(154.34,94.74) v1(154.4,92.07) v1(154.53,93.4) v1(154.85,96.45) v1(155.04,97.85) v1(155.16,95.37) v1(155.29,92.77) v1(155.36,94.17) v1(155.61,97.21) v1(155.67,91.88) v1(156.18,96.45) v1(156.31,92.39) v1(156.31,90.74) v1(156.63,91.5) v1(157.13,92.51) v1(157.51,91.44) v1(157.96,92.07) v1(158.53,91.44) v1(158.78,92.58) v1(159.42,91.44) v1(159.61,93.4) v1(159.67,92.39) v1(160.17,91.42) v4(150,88.45)
+CHGRTC: length 9.8
  TOP w0.102: v1(207.36,35.75) v4(206.29,35.75)
  TOP w0.508: v1(206.98,42.1) 207.21,41.86 207.21,41.48 207.25,41.45 DC4.2
  IN2 w0.508: v1(206.98,42.1) 207.21,41.86 207.21,39.09 206.5,38.37 206.5,36.55 207.3,35.75 v1(207.36,35.75)
+EC_VCCA: length 3.7
  TOP w0.102: CE5.1 v4(53.15,69.11)
  TOP w0.203: LE1.2 53.93,70.23 CE5.1 53.14,70.22 UE1.67
+FP_VCC:
  vias: v1(217.33,29.59) v1(217.94,29.59) v4(216.56,29.55)
+INV_PWR_SRC: length 2
  TOP w0.102: v1(205.2,57.65) v4(205.2,56.52) ; v1(205.2,58.29) v4(205.2,59.18)
  vias: v1(205.77,58.29) v1(205.77,57.65) v1(209.58,58.48) v1(209.58,57.91) v1(210.22,58.48) v1(210.22,57.91) v4(208.52,58.48)
+LAN_VDD10: length 3.9
  TOP w0.102: v1(18.51,92.07) v4(17.78,92.07)
  TOP w0.203: UL1.3 23.88,82.53 v1(23.89,82.52) ; v1(26.45,83.05) 26.05,83.05 25.88,83.22 UL1.8
  BOTTOM w0.203: v1(23.89,82.52) 23.91,82.54 CL18.1
  BOTTOM w0.254: CL6.1 v1(26.45,83.05)
  vias: v1(18.51,91.44) v1(21.18,84.39) v1(23.66,92.58) v1(24.23,92.58)
+LAN_VDD33: length 50.7
  TOP w0.203: UL1.11 27.73,85.01 27.97,84.77 CL15.1
  TOP w0.508: v1(29.12,82.8) 28.67,83.24 CL10.1 28.67,84.76 CL15.1 ; v1(23.4,94.42) 25.74,92.08 25.74,91.36 25.62,91.24 RC131.1
  IN1 w1.016: 29.72,81.56 29.72,79.98 29.75,79.94 29.75,74.87 32.15,72.47 32.15,71.63 34.01,69.78 34.01,67.69 34.64,67.05 34.64,64.54 34.9,64.28 34.9,61.59 40.55,55.94 40.55,52.76
  IN2 w0.762: 22.51,83.31 25.56,83.31 26.04,83.79 28.13,83.79
  BOTTOM w0.381: RL6.1 21.73,84.7 21.73,82.65 v1(21.56,82.48)
  vias: v1(21.56,81.91) v1(22.77,94.42) v1(29.75,82.55) v1(40.42,51.49) v1(40.42,50.86) v4(40.18,49.12)
+LCDVDD:
  vias: v4(218.75,54.5)
+LCDVDD_CONN: length 2.6
  TOP w0.102: CV14.1 v4(216.77,57.89) ; CV13.1 v4(212.75,58.06)
  vias: v1(213.71,57.21) v1(214.35,57.21) v1(214.98,57.21) v1(214.98,56.57) v4(214.03,56.55)
+LINE1_VREFO_L: length 12.9
  TOP w0.102: v1(19.45,12.25) 17.98,12.25 v4(17.74,12.01)
  TOP w0.203: v1(27.59,13.77) 27.76,13.61 UA1.24
  TOP w0.254: v1(19.45,12.25) DA10.1
  IN1 w0.254: v1(19.45,12.25) 19.53,12.25 19.78,12 23.15,12 24.29,13.14 26.89,13.14 27.53,13.77 v1(27.59,13.77)
+MEM_VREF: length 4.4
  TOP w0.102: v2(102.33,79.73) 102.45,79.85 RC7.2
  TOP w0.508: RC3.1 104.26,79.88 CC3.1 RC7.2 ; RC3.1 105.11,79.05 RC5.1 ; RC3.1 105.11,80.59 CC4.1
+MIC2-VREFO: length 15
  TOP w0.102: v4(16.54,13.62) 16.54,13.36 16.85,13.05 18.12,13.05 18.4,13.33 v1(19.4,13.33)
  TOP w0.203: UA1.23 28.32,14.01 v1(28.2,14.13)
  BOTTOM w0.508: v1(28.2,14.13) 28.2,13.46 27.69,12.95 24.51,12.95 23.87,12.31 22.92,12.31 21.59,13.65 19.72,13.65 v1(19.4,13.33)
+RTC_APU: length 98.2
  TOP w0.381: v1(210.35,40.85) 210,40.85 209.42,41.43 CC119.1 208.76,42.35
  TOP w0.508: RC124.2 149.53,61.24 v4(149.65,61.12) 149.65,60.16 149.96,59.86 149.96,58.9 150.63,58.22 150.63,57.94 151.17,57.4 v1(151.61,57.4) ; v1(205.14,49.84) 204.63,49.33 204.63,46.48 208.76,42.35
  IN1 w0.508: v1(210.35,40.85) 209.37,39.87 206.48,39.87 205.82,39.21 196.36,39.21 194.86,37.71 193.11,37.71 191.23,39.59 184.76,39.59 184.66,39.5 157.07,39.5 156.56,38.99 154.15,38.99 v1(154.02,39.11)
  BOTTOM w0.508: v1(154.02,39.11) 154.15,39.24 154.15,42.48 154.78,43.11 154.78,46.6 153.96,47.43 153.96,55.3 151.86,57.4 v1(151.61,57.4) ; UC15.3 204.83,50.27 205.14,49.97 v1(205.14,49.84)
+RTC_APU_R: length 163.2
  TOP w0.508: v1(135.85,66.65) 136.05,66.65 137.24,65.46 137.24,64.75 v1(135.86,63.37) 135.86,62.99 136.75,62.1 139.61,62.1 139.99,62.48 145.3,62.48 ; v1(36.39,63.77) 36.27,63.65 QE1.1 36.27,61.43 38.39,59.3 v4(39.58,59.3) v1(42.01,59.3)
  IN1 w0.508: v1(135.86,63.37) 135.86,59 132.74,55.88 130.11,55.88 126.27,52.04 126.27,47.11 126.59,46.79 v1(126.59,46.02) ; v1(135.85,66.65) 135.9,66.65 136.41,67.16 136.41,71.28 135.46,72.23
  IN2 w0.508: v1(42.01,59.3) 43.4,57.91 47.89,57.91 55.49,50.31 55.49,42.3 62.79,34.99 67.27,34.99 67.67,34.6 101.05,34.6 102.79,36.34 104.24,36.34 104.79,35.79 108.22,35.79 109.97,37.53 119.48,37.53 120.75,38.79 120.75,40.7 120.87,40.83 v1(120.87,40.89)
  BOTTOM w0.254: UC1.AM11 131.81,72.83 v1(131.81,72.64)
  BOTTOM w0.508: v1(36.39,63.77) 35.23,63.77 CLRP1.1 ; v1(120.87,40.89) 120.94,40.95 120.94,42.3 125.27,46.63 125.99,46.63 v1(126.59,46.02)
+RTCBATT: length 168.7
  TOP w0.102: v4(202.56,37.28) 203.06,37.78 v1(203.2,37.78)
  TOP w0.508: RC125.2 v1(203.2,37.78)
  IN1 w0.508: v1(203.2,37.78) 202.45,37.02 202.45,34.66 198.69,30.91 147.42,30.91 147.27,30.76 138.3,30.76 137.89,30.35 136.12,28.58 124.86,28.58 124.03,27.74 107.45,27.74 106.84,28.35 94.84,28.35 94.14,27.66 83.78,27.66 79.88,31.55 77.08,31.55 75.68,32.95 67.3,32.95 66.2,34.04 63.78,34.04 56.8,41.02 56.8,44.43 v1(57.37,45)
  BOTTOM w0.381: v1(57.37,45) 57.57,45 57.93,44.64 CC130.1
  BOTTOM w0.508: JIOB1.11 v1(203.2,37.78) ; v1(57.37,45) JRTC1.1
+RTCBATT_R: length 83.3
  TOP w0.508: v1(156.82,80.75) v4(156.09,80.75) RC126.1 152.08,80.75 QC3.2 ; RC125.1 204.83,39 205.32,39.48 DC4.3 205.32,42.43 202.98,44.76 202.98,45.46 202.47,45.97 202.47,49.02 202.09,49.4 202.09,55.62 199.55,58.16 196.38,58.16 195.74,58.8 195.74,62.73 194.85,63.62 190.34,63.62 187.61,66.35 187.61,67.5 185.2,69.91 182.41,69.91 179.93,72.39 v1(178.15,72.39)
  IN1 w0.508: v1(178.15,72.39) 175.55,74.99 164.18,74.99 158.42,80.75 v1(156.82,80.75)
+RTCVCC: length 198
  TOP w0.508: 208.82,37.97 208.82,41.27 v2(206.18,43.91) 203.74,46.35 v1(203.74,47.71) ; RA37.2 v1(30.51,21.97)
  IN1 w0.508: v1(207.11,38.03) 205.93,38.03 203.6,35.7 203.6,34.91 198.95,30.27 182.06,30.27 181.91,30.12 138.57,30.12 136.38,27.94 125.13,27.94 123.94,26.75 107.07,26.75 106.71,27.11 v1(104.68,27.11)
  IN2 w0.508: v1(36.61,25.32) 36.69,25.4 44.8,25.4 45,25.6 100.06,25.6 101.57,27.11 v1(104.68,27.11)
  BOTTOM w0.508: v1(30.51,21.97) 30.51,22.41 32.99,24.89 36.18,24.89 v1(36.61,25.32) ; UC15.1 203.87,47.84 v1(203.74,47.71)
+SPI_VCC: length 24.2
  TOP w0.102: RC118.2 130.2,64.56 v4(129.84,64.92)
  IN2 w0.381: v1(128.22,49.23) 128.28,49.23 129.8,50.75 129.8,53.7 131.29,55.19 131.29,58.44 131.83,58.98 131.83,60.82 130.64,62.01 129.25,62.01 v1(128.61,61.38)
  BOTTOM w0.381: CC22.2 RC119.2 131.4,47.72 131.22,47.54 UC14.8 129.06,47.54 128.22,48.38 v1(128.22,49.23)
+VREF_CA: length 7.2
  TOP w0.102: CD20.1 v4(72.6,66.46)
  TOP w0.356: CD28.1 71.48,65.72 CD20.1 CD21.1 71.48,67.83 CD36.1
  TOP w0.508: CD36.1 RD3.2 RD2.1 71.64,69.76 v1(72.2,69.76)
  BOTTOM w0.254: JDIMM1.164 71.93,69.49 v1(72.2,69.76)
A_MIC_CLK: length 213.1
  TOP w0.102: v1(213.52,44.25) 213.33,44.06 212.7,44.06 211.81,43.18 211.17,43.18 210.54,43.81 210.54,44.11 ED1.3 210.87,45.09 211.38,45.6 v1(211.52,45.6) ; v1(37.82,11.17) 37.88,11.11 38.31,11.11 CA486.1 38.25,11.55 36.97,11.55 L5.1
  IN2 w0.127: v1(37.82,11.17) 38.76,12.2 38.76,23.24 40.29,24.78 45.06,24.78 45.26,24.98 100.45,24.98 100.68,25.2 132.52,25.2 137.93,30.62 149.69,30.62 152.13,33.05 175.7,33.05 178.14,30.62 207.14,30.62 214.54,38.01 214.54,41.91 213.08,43.37 213.08,43.81 v1(213.52,44.25)
  BOTTOM w0.102: JEDP1.31 211.68,45.45 v1(211.52,45.6)
A_MIC_DATA: length 214.4
  TOP w0.102: v1(37.87,10.59) 37.91,10.63 38.29,10.63 CA491.1 38.25,10.16 37,10.16 RA46.1 ; v1(211.55,46.19) 211.53,46.19 209.87,44.53 ED1.2 210.22,44.1 210.22,43.68 211.04,42.86 211.93,42.86 v3(212.44,43.37) 212.82,43.75 213.39,43.75 v1(213.52,43.62)
  IN2 w0.127: v1(213.52,43.62) 213.52,43.56 214.98,42.1 214.98,37.84 207.32,30.18 177.96,30.18 175.52,32.62 152.31,32.62 149.87,30.18 138.11,30.18 132.68,24.76 100.94,24.76 100.72,24.54 45.44,24.54 45.24,24.35 40.48,24.35 39.19,23.05 39.19,11.91 v1(37.87,10.59)
  BOTTOM w0.102: JEDP1.30 211.95,45.95 211.72,46.19 v1(211.55,46.19)
AC_OFF#: length 200
  TOP w0.102: PQB31.2 189.76,46.6 PRB45.1 189.75,46.19 190.66,45.27 v2(190.66,44.95) 190.66,43.11 v1(190.54,42.98) ; UE1.27 36.81,71.42 36.86,71.37 41.5,71.37 42.01,71.88 v1(42.01,72.45)
  IN1 w0.127: v1(190.54,42.98) 190.54,42.22 190.34,42.03 186.13,42.03 185.43,42.73 181.96,42.73 181.52,42.29 159.06,42.29 157.56,40.79 150.87,40.79 147.35,37.27 147.35,36.11 144.59,33.35 137.35,33.35 135.08,31.08 123.7,31.08 123.22,30.6 118.89,30.6 118.57,30.92 107.4,30.92 107.08,30.6 105.31,30.6 105.18,30.73 87.54,30.73 83.07,35.2 68.27,35.2 66.56,36.91 65.48,36.91 64.09,38.3 64.09,39.56 62.91,40.74 60.39,40.74 59.53,41.61 59.53,44.06 59.95,44.48 59.95,51.14 57.81,53.29 57.81,61.3 53.12,65.99 53.12,67.67 52.05,68.73 52.05,69.39 51.28,70.16 51.28,71.76 49.64,73.4 43.4,73.4 43.21,73.21 42.64,73.21 42.01,72.58 v1(42.01,72.45)
ACAV_IN: length 6.8
  TOP w0.102: v2(45.7,88.04) 45.36,88.37 RE37.1 44.23,87.87 44.23,86.6 CE10.2 45.06,85.77 45.06,84.79 44.53,84.27 UE1.110
ACIN_CHG:
  vias: v1(192.59,51.75) v2(192.55,53.61)
ACLIN: length 3.4
  TOP w0.102: v2(195.18,52.66) v1(195.18,53.14)
  TOP w0.254: v1(195.18,53.14) 195.49,53.45 PRB18.1
  BOTTOM w0.203: PUB01.20 195.1,52.93 195.18,53.02 v1(195.18,53.14) 195.46,53.42 PRB16.1
ACOK_CHG: length 3.9
  BOTTOM w0.102: v2(199.61,53.87) 199.53,53.78 PRB22.1
  BOTTOM w0.203: PUB01.24 196.7,52.21 196.9,52.41 197.33,52.41 198.66,53.74 PRB22.1
AD_BID0: length 7
  TOP w0.102: v2(56.19,68.88) 54.76,68.88 RE5.1 RE9.2 53.12,68.33 52.54,68.92 52.54,69.5 52.21,69.82 UE1.66
ADJ_2.5V: length 4.8
  BOTTOM w0.102: PC2505.2 v2(60.33,72.83)
  BOTTOM w0.254: PU2501.7 61.25,72.88 PC2505.2 PR2502.2 PR2503.1
ADP_I: length 207.3
  TOP w0.203: UE1.65 52.16,69.42 52.27,69.32 52.27,68.08 52.71,67.64 53.35,67.64 PCB13.1 52.73,66.73 v1(51.22,66.73)
  TOP w0.254: v1(201.67,48.83) v2(201.67,47.06) 201.67,45.88 202.41,45.14 202.41,44.25 203.93,42.73 203.93,39.3 v1(202.98,38.35)
  IN1 w0.203: v1(51.22,66.73) 50.52,66.04 50.52,64.88 56.43,58.97 56.43,52.71 57.86,51.28 57.86,44.61 57.29,44.04 57.29,41.22 63.98,34.53 66.44,34.53 67.54,33.43 79.69,33.43 84.29,28.83 107.04,28.83 107.63,28.25 123.86,28.25 124.66,29.06 135.92,29.06 138.1,31.24 146.4,31.24 149.37,34.21 177.64,34.21 179.87,31.99 198.61,31.99 201.89,35.26 201.89,37.26 v1(202.98,38.35)
  BOTTOM w0.203: PRB31.1 199.92,49.08 201.41,49.08 v1(201.67,48.83)
AGPIO8: length 30.1
  TOP w0.102: v1(152.94,82.74) 152.24,82.04 151.16,82.04 150.59,81.47 150.59,75.18 149.77,74.35 149.11,74.35 v2(148.95,74.51) 148.58,74.88 145.79,74.88 145.42,75.25 143.71,75.25 142.25,73.79 136.96,73.79 135.68,75.07 134.15,75.07 v1(134.12,75.04)
  BOTTOM w0.1: UC1.AJ4 134.43,75.37
  BOTTOM w0.102: v1(134.12,75.04) 134.12,75.06 134.43,75.37 ; RC42.2 151.93,81.92 152,81.85 RC52.1 152.36,81.88 152.94,82.47 v1(152.94,82.74)
AGPIO11: length 16.7
  TOP w0.102: RC95.1 146.42,73.4 146.38,73.45 RC82.2 145.21,72.94 144.43,72.94 144.11,73.25 v2(143.43,73.25) 143.4,73.29 136.44,73.29 135.29,74.44 132.51,74.44 v1(131.98,74.97)
  BOTTOM w0.102: v1(131.98,74.97) 132.03,75.02 UC1.AJ8
AGPIO25: length 10.2
  BOTTOM w0.102: v2(132.77,61.4) 132.6,61.57 132,61.57 131.82,61.39 RC37.1 131.66,62.13 130.1,63.69 130.1,65.93 129.69,66.33 129.69,68.24 129.94,68.48 129.94,68.74 129.63,69.04 UC1.AY13
ALERT#: length 4.5
  BOTTOM w0.102: v2(180.6,67.88) 180.6,67.28 180.17,66.85 R45.2 179.8,66.18 179.8,64.93 180.02,64.71 U1.6
APU_ALERT#: length 13
  BOTTOM w0.102: UC1.A30 120.25,90.89 120.25,92.91 120.25,93.73 119.71,94.27 119.71,96.63 120.04,96.96 120.04,98.56 119.41,99.18 v2(119.41,100.24) 119.41,101.06 119.28,101.2 119.28,102.4 119.56,102.68 RPC1.3
APU_DBRDY: length 58.8
  TOP w0.102: v1(92.62,125.53) 92.62,122.91 99.05,116.48 v2(105.58,116.48) 107.63,116.48 v1(108.95,115.16)
  BOTTOM w0.102: UC1.A26 122.48,91.02 122.44,91.06 122.44,91.42 122.36,91.49 122.36,91.69 122.22,91.83 122.22,100.89 122.09,101.03 122.09,105.27 121.92,105.44 121.92,109.5 115.47,115.94 109.73,115.94 v1(108.95,115.16) ; v1(92.62,125.53) JHDT1.14
APU_DBREQ#: length 75.8
  TOP w0.102: v1(107.86,114.23) 106.56,115.53 v2(103.88,115.53) 99.14,115.53 95.9,118.77 94.69,118.77 88.93,124.52 87.5,124.52 v1(86.65,125.37)
  IN2 w0.127: v1(86.65,125.37) 87.09,124.93 94.04,124.93 v1(94.59,125.47)
  BOTTOM w0.102: RPH1.4 85.24,124.73 85.34,124.84 85.7,124.84 86.23,125.37 v1(86.65,125.37) ; v1(107.86,114.23) 107.86,114.94 109.27,116.35 115.64,116.35 123.16,108.83 123.16,104.58 122.49,103.91 122.49,101.23 122.68,101.04 122.68,91.94 122.89,91.74 122.89,91.35 UC1.A25 ; RH5.2 94.59,124.25 v1(94.59,125.47)
APU_DBREQ#_R: length 2.8
  BOTTOM w0.102: JHDT1.16 v1(93.89,125.47) 94.08,125.28 RH5.1
APU_DP1_CTRL_CLK: length 162.6
  TOP w0.102: RV36.2 26.64,96.63 26.64,97.12 25.51,98.25 25.2,98.39 25.15,98.53 v1(25.37,99.01)
  IN1 w0.127: v1(31.34,100.66) 31.18,100.5 28.22,100.5 25.96,98.24 25.51,98.24 25.38,98.3 25.24,98.37 25.17,98.59 v1(25.37,99.01)
  IN2 w0.102: 128.41,91.95 128.41,91.92 128.43,91.91 128.43,91.29 128.45,91.26 128.45,89.49 128.47,89.47 128.47,88.65 128.15,88.32 128.15,87.31 v1(128,87.17)
  IN2 w0.127: v1(31.34,100.66) 31.47,100.53 31.71,100.53 31.84,100.65 31.84,118.6 35.55,122.31 65.01,122.31 66.04,123.34 69.61,123.34 70.66,124.39 82.53,124.39 83.35,123.56 93.57,123.56 94.65,124.65 95.47,124.65 98.71,121.41 116.49,121.41 118.54,119.36 118.54,119.17 v1(118.74,118.97) ; 128.41,91.95 128.41,92.58 128.69,92.86 129.55,92.86 v1(129.79,93.1)
  BOTTOM w0.102: v1(129.79,93.1) 129.79,93.02 129.69,92.91 129.43,92.91 129.21,93.13 129.21,99.54 129.41,99.73 129.41,107.86 120.11,117.15 120.05,117.15 118.53,118.67 118.53,118.75 v1(118.74,118.97) ; UC1.G17 127.43,87.31 127.67,87.07 127.9,87.07 v1(128,87.17) ; QV3.1 v1(25.37,99.01)
APU_DP1_CTRL_DATA: length 162.4
  TOP w0.102: v1(24.74,97.71) 24.94,98.15 25.1,98.21 25.39,98.08 26.44,97.04 26.44,96.62 RV37.2
  IN1 w0.127: v1(31.34,100.07) 31.18,100.23 28.32,100.23 26.07,97.98 25.45,97.98 25.06,98.16 24.94,98.12 v1(24.74,97.71)
  IN2 w0.102: 128.68,91.95 128.68,91.92 128.69,91.9 128.69,89.55 128.71,89.54 128.71,88.55 128.38,88.23 128.38,87.01 128,86.63 v1(128,86.57)
  IN2 w0.127: v1(31.34,100.07) 31.53,100.26 31.82,100.26 32.1,100.54 32.1,118.49 35.66,122.04 65.12,122.04 66.15,123.07 69.72,123.07 70.77,124.12 82.42,124.12 83.24,123.3 93.67,123.3 94.76,124.38 95.36,124.38 98.6,121.15 116.38,121.15 118.27,119.25 118.27,119.14 v1(118.1,118.97) ; 128.68,91.95 128.68,92.47 128.8,92.6 129.71,92.6 v1(129.79,92.52)
  BOTTOM w0.102: UC1.H17 127.43,86.74 127.56,86.87 127.77,86.87 128,86.64 v1(128,86.57) ; v1(129.79,92.52) 129.79,92.61 129.69,92.71 129.34,92.71 129.01,93.05 129.01,99.62 129.2,99.82 129.2,107.77 120.03,116.95 119.96,116.95 118.32,118.59 118.32,118.74 v1(118.1,118.97) ; QV3.4 v1(24.74,97.71)
APU_DP1_HPD: length 147.3
  TOP w0.102: v2(95.53,117.45) 95.27,117.7 v1(94.89,117.7)
  IN1 w0.102: 118.18,94.49 118.65,94.01 118.65,92.7 119.11,92.24 119.95,92.24 120.88,91.31 124.74,91.31 125.31,91.89 125.31,93.13 v1(125.38,93.19)
  IN1 w0.127: v1(94.89,117.7) 97.38,115.21 97.38,100.96 99.18,99.16 112.41,99.16 117,94.57 118.1,94.57 118.18,94.49
  IN2 w0.102: 126.46,91.95 126.46,90.95 v1(127.94,89.47)
  IN2 w0.127: v1(125.38,93.19) 125.76,93.19 126.46,92.5 126.46,91.95
  BOTTOM w0.102: v1(127.94,89.47) 127.88,89.47 127.51,89.11 UC1.D17 ; v1(94.89,117.7) 94.89,117.7 86.09,117.7 85.16,116.77 68.43,116.77 64.75,120.45 36.17,120.45 32.42,116.71 32.42,98.42 32.04,98.04 32.04,98.01 31.94,97.91 30.96,97.91 30.84,98.03 QV2.3 30.84,99.88 RV32.1
APU_DP1_N0: length 156.5
  TOP w0.102: CV22.1 22.35,96.05 22.45,96.05 22.88,96.47 22.88,97.33 23.9,98.35 23.9,100 25.62,101.72 v3(25.62,103.45) 25.62,108.2 24.47,109.36 23.89,109.36 v1(23.66,109.13)
  BOTTOM w0.102: v1(23.66,109.13) 23.89,109.36 24.49,109.36 27.61,112.47 27.61,118.21 33.58,124.19 65.17,124.19 70.05,119.31 83.85,119.31 84.72,120.19 115.61,120.19 127.85,107.95 127.85,101.87 127.51,101.54 127.51,100.73 128.22,100.03 128.22,92.95 128.84,92.33 128.84,91.06 128.78,91 128.78,90.73 129.14,90.36 129.14,90.22 UC1.B14
APU_DP1_N1: length 152.9
  TOP w0.102: CV20.1 22.35,97.95 22.6,97.95 23.26,98.61 23.26,100.54 24.85,102.13 v3(24.85,105.06) 24.85,106.21 23.18,107.88 22.64,107.88 22.45,107.69 v1(22.45,107.56)
  BOTTOM w0.102: v1(22.45,107.56) 22.45,107.77 22.55,107.87 24.21,107.87 28.62,112.28 28.62,117.93 34.06,123.36 64.46,123.36 69.15,118.68 84.11,118.68 84.99,119.56 115.35,119.56 125.56,109.34 125.56,107.48 126.3,106.74 126.3,101.05 127.59,99.76 127.59,92.75 128.22,92.12 128.22,91.08 128.4,90.9 128.4,90.64 UC1.B15
APU_DP1_N2: length 145.7
  TOP w0.102: CV18.1 22.35,101.7 22.62,101.7 22.82,101.9 v3(22.82,104.68) 22.82,105.74 22.72,105.84 22.31,105.84 v1(22.01,105.53)
  BOTTOM w0.102: UC1.B16 127.98,90.41 127.67,90.73 127.67,90.99 127.78,91.1 127.78,91.67 126.95,92.5 126.95,98.2 125.66,99.49 125.66,103.5 124.58,104.58 124.58,109.42 115.08,118.92 85.43,118.92 84.55,118.04 68.88,118.04 64.52,122.41 34.66,122.41 29.57,117.32 29.57,112.02 24.74,107.18 23.4,107.18 22.96,106.74 22.96,106.23 22.56,105.84 22.31,105.84 v1(22.01,105.53)
APU_DP1_N3: length 143.8
  TOP w0.102: CV15.1 22.35,99.86 22.53,99.86 22.63,99.96 22.63,100.81 24.09,102.27 v3(24.09,103.37) 24.09,105.48 23.99,105.58 23.72,105.58 23.53,105.39 v1(23.53,105.23)
  BOTTOM w0.102: UC1.B17 127.43,90.74 127.2,90.97 127.2,91 126.94,91.27 126.94,91.86 126.32,92.49 126.32,97.94 125.03,99.23 125.03,103.24 123.95,104.32 123.95,109.16 114.82,118.29 85.85,118.29 84.97,117.41 68.62,117.41 64.82,121.2 35.23,121.2 30.59,116.56 30.59,111.26 24.93,105.6 23.73,105.6 23.53,105.39 v1(23.53,105.23)
APU_DP1_P0: length 156.6
  TOP w0.102: v1(23.66,109.71) 23.82,109.56 24.55,109.56 25.83,108.28 25.83,103.76 25.85,103.73 25.85,103.17 25.83,103.14 25.83,101.64 24.1,99.91 24.1,98.26 23.08,97.25 23.08,96.39 22.54,95.84 22.35,95.84 CV23.1
  BOTTOM w0.102: v1(23.66,109.71) 23.82,109.56 24.41,109.56 27.4,112.55 27.4,118.3 33.5,124.39 65.26,124.39 70.13,119.52 83.76,119.52 84.64,120.39 115.69,120.39 128.05,108.04 128.05,101.79 127.72,101.45 127.72,100.82 128.42,100.11 128.42,93.03 129.04,92.41 129.04,91.05 129.08,91.01 UC1.A14
APU_DP1_P1: length 152.9
  TOP w0.102: v1(22.45,108.28) 22.64,108.09 23.26,108.09 25.05,106.29 25.05,105.37 25.08,105.35 25.08,104.78 25.05,104.75 25.05,102.05 23.47,100.46 23.47,98.53 22.69,97.75 22.35,97.75 CV21.1
  BOTTOM w0.102: UC1.A15 128.42,91.32 128.42,92.21 127.79,92.84 127.79,99.85 126.5,101.14 126.5,106.82 125.76,107.56 125.76,109.43 115.43,119.76 84.9,119.76 84.02,118.88 69.23,118.88 64.55,123.57 33.97,123.57 28.42,118.01 28.42,112.36 24.13,108.07 22.65,108.07 v1(22.45,108.28)
APU_DP1_P2: length 145.8
  TOP w0.102: CV19.1 22.35,101.49 22.7,101.49 23.02,101.81 23.02,104.37 23.05,104.4 23.05,104.96 23.02,104.99 23.02,105.82 22.8,106.04 22.2,106.04 v1(22.01,106.23)
  BOTTOM w0.102: v1(22.01,106.23) 22.2,106.04 22.48,106.04 22.75,106.32 22.75,106.82 23.32,107.39 24.65,107.39 29.37,112.11 29.37,117.41 34.58,122.61 64.6,122.61 68.97,118.25 84.47,118.25 85.35,119.12 115.17,119.12 124.79,109.5 124.79,104.67 125.87,103.59 125.87,99.58 127.15,98.29 127.15,92.59 127.98,91.76 UC1.A16
APU_DP1_P3: length 143.8
  TOP w0.102: v1(23.53,105.98) 23.72,105.79 24.07,105.79 24.29,105.57 24.29,103.68 24.32,103.66 24.32,103.09 24.29,103.07 24.29,102.18 22.83,100.72 22.83,99.87 22.61,99.65 22.35,99.65 CV16.1
  BOTTOM w0.102: v1(23.53,105.98) 23.71,105.8 24.84,105.8 30.39,111.34 30.39,116.64 35.15,121.41 64.91,121.41 68.71,117.61 84.88,117.61 85.76,118.49 114.9,118.49 124.15,109.24 124.15,104.4 125.23,103.32 125.23,99.31 126.52,98.02 126.52,92.57 127.14,91.95 127.14,91.35 127.29,91.21 UC1.A17
APU_FCH_POK: length 3.6
  TOP w0.102: UE1.32 33.7,69.42 RC40.2 33.57,69.41 v2(32.57,68.41)
APU_FCH_PWRGD: length 49.6
  TOP w0.102: RC40.1 35.04,68.5 v1(35.34,68.2)
  IN1 w0.127: v1(35.34,68.2) 36.04,67.5 36.04,65.02 37.82,63.24 37.82,60.64 45.04,53.41 45.04,37.32 v1(43.85,36.13)
  BOTTOM w0.102: v1(43.85,36.13) v2(43.85,35.2) 43.85,32.7 45.53,31.02 UC12.2 45.53,30.32 45.32,30.1 CC11.1 CC12.1 45.32,28.32 45.48,28.16 CC7.1 45.89,28.11 46.29,28.5 46.29,28.8 RC54.1 RC38.2
APU_FCH_PWRGD_R: length 174.6
  TOP w0.102: v1(73.11,43.07) v2(73.11,43.67)
  IN1 w0.127: v1(73.11,43.07) 73.15,43.11 74.29,43.11 74.58,42.81 86.71,42.81 87.42,43.53 95.06,43.53 97.78,40.81 100.94,40.81 101.11,40.98 104.19,40.98 105.06,40.11 117.49,40.11 117.79,40.41 121.09,40.41 121.95,41.27 124.51,41.27 124.75,41.03 128.6,41.03 129.08,41.52 132.3,41.52 132.6,41.82 139.33,41.82 144.92,47.41 144.92,52.04 147.67,54.8 147.67,60.77 151.11,64.22 151.11,68.25 153.64,70.78 153.64,75.56 151.29,77.91 149.45,77.91 148.39,78.97 v1(146.69,78.97) ; v1(48.29,43.03) 48.29,41.99 47.37,41.06 47.37,36.63 v1(44.96,34.22)
  BOTTOM w0.102: RC48.2 147.08,78.97 v1(146.69,78.97) 146.47,79.19 144.27,79.19 143.85,79.6 142.84,79.6 RC49.2 141.46,79.03 141.13,78.7 138.73,78.7 138.04,78.01 136.41,78.01 136.1,77.71 UC1.AE2 ; v1(44.96,34.22) 44.88,34.14 UC12.4 44.88,32.36 45.56,31.68 46.26,31.68 46.64,31.31 46.64,29.42 47.07,28.98 RC54.2 ; v1(73.11,43.07) 73.07,43.03 73.07,42.93 70.96,40.83 68.49,40.83 67.06,42.26 61.44,42.26 60.94,41.76 59.55,41.76 58.54,42.77 51.83,42.77 51.6,42.54 48.79,42.54 v1(48.29,43.03)
APU_ID: length 15.7
  TOP w0.102: RC55.1 RC60.2 145.09,71.81 144.47,71.81 144.39,71.73 143.89,71.73 142.66,72.96 v2(141.26,72.96) 136.48,72.96 135.2,74.24 133.81,74.24 v1(133.43,73.86)
  BOTTOM w0.1: UC1.AL5 133.63,74.06 v1(133.43,73.86)
APU_PCIE_RST#: length 229.6
  TOP w0.102: UC13.4 99.74,47.66 RC66.1 RC67.2 99.36,47.05 98.27,47.05 97.7,46.48 v2(95.98,46.48) v1(94.56,46.48) ; RW4.2 72.12,132.74 v1(72.74,133.36) ; RL17.2 33.75,90.8 v1(34.12,91.17)
  IN1 w0.127: v1(45.71,40.88) 45.71,42.26 45.89,42.44 45.89,53.48 38.32,61.04 38.32,64.96 36.55,66.73 36.55,69.7 38.02,71.17 38.02,73.06 34.23,76.84 33.17,76.84 30.72,79.29 30.72,80.47 31.56,81.3 31.56,85.23 31.85,85.53 31.85,88.6 34.12,90.87 v1(34.12,91.17) 34.12,97.39 35.21,98.48 35.21,118.04 41.75,124.58 60.15,124.58 v1(64.95,129.39)
  IN2 w0.127: v1(40.76,35.87) 40.76,35.39 40.1,34.73 33,34.73 27.66,29.39 v1(27.66,27.74) ; v1(64.95,129.39) 66.12,130.55 67.41,130.55 69.95,133.09 72.2,133.09 72.47,133.36 v1(72.74,133.36)
  BOTTOM w0.102: v1(27.66,27.74) 27.13,27.21 JSSD1.50 ; v1(40.76,35.87) 40.97,36.08 40.97,40.2 41.62,40.85 45.69,40.85 v1(45.71,40.88) 45.74,40.85 50.97,40.85 51.28,40.54 66.09,40.54 68.34,38.29 92.62,38.29 94.34,40.01 94.34,46.26 v1(94.56,46.48)
APU_PCIE_RST#_C: length 11.7
  TOP w0.102: RC63.1 144.49,77.86 v2(142.68,77.86) 134.93,77.86 v1(134.23,77.16)
  BOTTOM w0.102: v1(134.23,77.16) 134.43,77.36 UC1.AE4
APU_PCIE_WAKE#: length 89.6
  TOP w0.102: v1(32.12,41.84) 31.97,41.7 31.97,37.64 30.85,36.51 30.32,36.51 29.75,35.94 29.75,34.09 30.58,33.27 30.58,29.78 27.72,26.92 27.09,26.92 26.26,27.74 v1(26.13,27.74) ; v1(29.37,69.92) RC39.1 31.49,69.92 RE32.2 ; v1(25.43,93.47) v2(26.35,92.56) 26.39,92.51 26.39,90.8 25.62,90.04 RC131.2 24.71,89.11 24.71,88.55 24.28,88.12 UL1.21
  IN1 w0.127: v1(25.43,93.47) 26.14,92.76 26.14,87.74 27.15,86.74 27.15,86.16 27.59,85.72 27.59,82.52 28.38,81.73 28.38,74.01 29.37,73.02 v1(29.37,69.92) 29.24,69.8 29.24,62.29 25.62,58.67 25.62,45.84 29.63,41.84 v1(32.12,41.84)
  BOTTOM w0.102: JSSD1.54 v1(26.13,27.74)
APU_PCIE_WAKE#_R: length 173.1
  TOP w0.102: RC39.2 29.48,70.84 28.93,70.29 28.93,69.53 32.61,65.84 35.34,65.84 37.37,63.81 38.77,63.81 49.25,53.33 v2(49.25,52.48) 49.25,45.75 v1(47.74,44.24)
  IN1 w0.102: v1(132.66,77.16) 132.2,76.7 132.18,76.7 131.99,76.51 131.99,75.81 132.17,75.63 134.5,75.63 134.66,75.46 137.46,75.46 138.38,74.54 138.38,73.88 138.1,73.6 138.1,68.83 138.6,68.32 138.6,65.58 138.91,65.28
  IN1 w0.127: 138.91,65.28 138.91,65.27 138.91,57.93 131.11,50.13 131.11,49.2 126.9,44.99 126.56,44.99 125.61,44.04 125.61,43.76 125.28,43.43 120.82,43.43 119.32,41.93 110.8,41.93 110.25,41.38 106.18,41.38 105.32,42.25 97.78,42.25 95.42,44.61 v1(92.66,44.61)
  BOTTOM w0.102: UC1.AE7 132.83,77.33 v1(132.66,77.16) ; v1(47.74,44.24) 50.97,44.24 52.23,42.98 58.62,42.98 59.64,41.96 60.85,41.96 61.36,42.46 67.14,42.46 68.4,41.21 70.98,41.21 72.7,42.93 72.7,43.33 72.87,43.49 73.38,43.49 77,39.87 90.2,39.87 92.66,42.32 v1(92.66,44.61)
APU_PWRGD: length 232.7
  TOP w0.102: v1(123.56,87.3) 123.48,87.38 CC6.2 122.6,87.38 122.02,86.8 121.29,86.8 121.08,87.01 121.08,87.32 121.13,87.38 121.13,87.7 121.04,87.79 121.04,88.16 121.79,88.91 121.79,91.13 121.08,91.84 121.08,94.93 119.77,96.24 118.43,96.24 v1(118.39,96.28) RC17.2 119.97,96.93 121.36,98.32 v1(123.58,98.32)
  TOP w0.203: PUZ01.9 146.72,143.13 146.08,143.76 146.08,145.33 145.94,145.47 136.62,145.47 135.35,144.2 v4(135.35,138.08) 135.35,137.03 136.05,136.33 v1(136.24,136.33)
  IN1 w0.127: v1(123.58,98.32) 123.66,98.4 127.83,98.4 129.19,99.77 132.02,99.77 133.55,98.23 137.26,98.23 143.35,92.13 144.88,92.13 146.66,90.36 146.66,88.32 147.86,87.12 v1(147.86,84.01) ; v1(109.38,136.46) 109.63,136.21 109.63,135.88 104.37,130.62 104.37,107.91 110.39,101.89 113.01,101.89 118.39,96.51 v1(118.39,96.28) 118.51,96.16 118.51,95.41 118.33,95.23 117.69,95.23 117.51,95.41 116.52,95.41 112.51,99.42 100.76,99.42 98.01,102.17 98.01,117.34 92.09,123.27 v1(92.09,123.98)
  IN2 w0.127: v1(147.86,84.01) 148.88,84.01 149.74,83.14 149.74,75.52 v1(150.02,75.24)
  BOTTOM w0.102: RC51.2 145.79,72.71 148.32,75.24 v1(150.02,75.24) 155.53,75.24 RC127.1 ; v1(123.56,87.3) 123.35,87.51 UC1.G25 ; v1(92.09,123.98) 92.09,123.61 91.98,123.5 87.34,123.5 DH1.2
  BOTTOM w0.203: v1(136.24,136.33) 136.11,136.46 v1(109.38,136.46)
APU_PWRGD_BUF: length 3.7
  BOTTOM w0.102: JHDT1.10 90.08,125.64 v1(89.96,125.52) 89.96,125.39 DH1.1
APU_PWRGD_EC: length 170.8
  TOP w0.102: v1(46.17,84.71) 45.63,84.71 45.33,84.41 UE1.108
  IN1 w0.127: v1(46.17,84.71) 46.18,84.72 46.38,84.72 46.58,84.51 50.96,84.51 52.55,82.93 52.8,82.93 54.2,81.53 55.72,81.53 57.83,79.42 57.83,78.83 59.3,77.36 59.3,74.56 63.48,70.39 63.48,65.08 67.84,60.71 67.84,46.95 73.23,41.56 74.04,41.56 74.26,41.78 88.87,41.78 89.09,41.56 95.53,41.56 97.29,39.8 101.39,39.8 101.51,39.92 103.81,39.92 104.64,39.09 116.75,39.09 117.28,38.57 124.01,38.57 125.46,40.02 128.49,40.02 128.61,39.9 138.93,39.9 139.52,40.48 140.34,40.48 146.69,46.84 146.69,49.06 148.48,50.85 148.48,52.1 149.01,52.63 149.01,58.68 149.73,59.39 149.73,60.27 151.45,61.99 151.88,61.99 152.24,62.35 152.24,62.89 152.51,63.15 152.51,67.85 155.77,71.11 155.77,72.11 156.75,73.08 v1(156.75,73.78)
  BOTTOM w0.102: v1(156.75,73.78) 157.21,74.24 RC127.2
APU_PWRGD_R: length 10.4
  BOTTOM w0.102: RC51.1 143.75,72.71 143.39,72.35 142.86,72.35 142.54,72.67 CC8.1 142.06,73.19 141,73.19 v2(139.39,74.8) 138.69,75.5 136.97,75.5 136.66,75.81 136.41,75.81 136.28,75.69 136.27,75.69 136.09,75.51 UC1.AJ2
APU_RST#: length 179.2
  TOP w0.102: v1(117.36,94.18) 118.25,95.06 RC18.2 120.38,95.06 120.83,94.61 120.83,91.74 121.59,90.97 121.59,89.52 121.06,88.99 CC5.2 120.47,88.99 v1(120.3,88.82) ; v1(149.05,69.97) 149,70.02 148.44,70.02 RC50.2 ; UC11.4 133.26,39.87 133.02,40.11 RC26.2 131.99,40.9 RC32.1 131.28,40.91 v2(130.83,41.36) 129.75,42.44 v1(129.51,42.44)
  IN1 w0.102: 116.53,94.49 116.84,94.18 v1(117.36,94.18) 117.36,94.03 118.14,93.26 118.14,90.72 118.65,90.21 118.65,88.75 118.98,88.41 119.35,88.41 120.14,89.2 120.68,89.2 121.52,90.04 126.39,90.04 128.04,91.7 128.04,94.49
  IN1 w0.127: v1(91.54,124.2) 91.54,118.87 96.3,114.1 96.3,101.28 98.84,98.74 112.28,98.74 116.53,94.49 ; v1(149.05,69.97) 148.1,69.02 145.96,69.02 145.63,68.69 145.63,67.8 144.64,66.81 144.64,63.27 144.48,63.11 144.48,58.34 144.12,57.97 144.12,53.91 141.83,51.62 141.83,45.76 138.91,42.84 131.78,42.84 131.67,42.73 129.8,42.73 v1(129.51,42.44) ; 128.04,94.49 128.04,98.26 129.3,99.51 131.91,99.51 133.45,97.98 137,97.98 143.16,91.82 144.56,91.82 146.27,90.1 146.27,88.07 147.23,87.12 v1(147.23,84.01)
  IN2 w0.127: v1(147.23,84.01) 148.65,82.58 148.65,79.15 148.92,78.89 148.92,75.28 148.15,74.51 148.15,70.93 149.05,70.03 v1(149.05,69.97)
  BOTTOM w0.102: v1(120.3,88.82) 120.54,88.82 UC1.D29 ; v1(91.54,124.2) 91.79,124.46 92.63,124.46 DH2.2
APU_RST#_BUF: length 3.4
  BOTTOM w0.102: 91.35,127.37 v1(91.35,125.59) 91.35,124.81 DH2.1
APU_RST#_EC: length 128.7
  TOP w0.102: UC11.2 133.91,41.44 133.53,41.82 RC32.2 130.93,41.82 129.89,42.86 129.26,42.86 129,42.6 129,42.22 128.75,41.97 124.88,41.97 123.48,43.37 121.95,43.37 v2(120.21,41.63) 119.48,40.89 v1(119.48,39.3) ; UE1.73 49.74,72.62 v1(48.61,71.5)
  IN2 w0.127: v1(48.61,71.5) 48.61,71.24 48.78,71.08 50.05,71.08 52.74,68.38 52.74,65.91 52.87,65.78 52.87,57.48 62.93,47.42 65.44,47.42 66.03,46.83 66.03,44.51 61.69,40.17 61.69,37.08 63.08,35.69 67.56,35.69 67.96,35.3 100.76,35.3 102.63,37.17 105.91,37.17 106.06,37.02 108.46,37.02 109.68,38.23 119.2,38.23 119.48,38.51 v1(119.48,39.3)
APU_RST#_R: length 16.8
  TOP w0.102: RC50.1 147.08,69.51 146.83,69.25 CC9.1 145.42,69.41 144.82,70 144.26,70 144.05,70.22 144.05,71.24 143.96,71.32 143.72,71.32 142.85,72.19 138.34,72.19 138.21,72.33 134.73,72.33 134.48,72.58 134.48,73.61 v1(134.23,73.86)
  BOTTOM w0.1: UC1.AL4 134.43,74.06 v1(134.23,73.86)
APU_SCLK0: length 78.3
  TOP w0.102: US2.1 102.09,45.83 102.09,45.83 v1(102.02,45.83) ; v1(117.22,62.48) 118.18,62.48 119.02,61.64 RPC6.3
  IN1 w0.127: v1(81.95,45.91) 95.79,45.91 96.3,45.4 101.64,45.4 102.02,45.77 v1(102.02,45.83)
  IN2 w0.127: v1(81.95,45.91) 82.01,45.97 86.31,45.97 88.22,47.89 91.07,47.89 97.36,54.18 109.16,54.18 111.6,56.62 112.38,56.62 116.18,60.42 116.18,61.44 v1(117.22,62.48)
  BOTTOM w0.102: v1(117.22,62.48) 117.63,62.89 117.63,64.67 118.8,65.84 118.8,66.06 118.93,66.19 118.93,68.23 118.93,68.23 118.93,68.29 118.93,68.3 118.93,68.46 118.95,68.48 118.95,68.75 118.87,68.83 118.87,69.07 UC1.AY33 ; v1(81.95,45.91) 81.92,45.94 81.92,46.52 81.19,47.24 JDIMM1.253
APU_SDATA0: length 103.2
  TOP w0.102: v1(117.45,61.91) 118.24,61.91 119.01,61.14 RPC6.4 ; v1(73.19,46.86) 73.19,46.41 73.97,45.63 77.22,45.63 78.52,46.92 90.52,46.92 91.73,45.72 91.73,43.43 92.63,42.53 94.41,42.53 95.54,41.4 101.7,41.4 103.11,42.81 US2.4
  IN2 w0.127: v1(117.45,61.91) 117.38,61.91 116.62,61.15 116.62,60.25 112.56,56.19 111.78,56.19 109.34,53.75 97.66,53.75 91.28,47.36 88.36,47.36 84.93,43.94 78.59,43.94 76.94,45.59 73.82,45.59 73.19,46.22 v1(73.19,46.86)
  BOTTOM w0.102: v1(117.45,61.91) 118.03,62.5 118.03,64.64 119.09,65.7 119.09,66.02 119.13,66.06 119.13,68.21 119.18,68.26 UC1.BA32 ; JDIMM1.254 73.06,46.99 73.19,46.86 v1(73.19,46.86)
APU_SIC: length 198.9
  TOP w0.102: v1(118.4,101.4) v2(118.86,101.87) 118.98,101.99 119.7,101.99 v1(120.37,101.32) ; QC2.4 61.14,80.12 v1(60.11,81.15)
  IN1 w0.127: v1(116.99,57.13) 116.55,56.68 116.55,56.24 118.4,54.39 118.4,51.87 116.68,50.16 116.68,47.34 v1(116.93,47.09)
  IN2 w0.127: v1(116.93,47.09) 116.53,46.69 116.53,45.67 115.44,44.57 114.54,44.57 113.99,45.12 110.93,45.12 110.46,45.59 107.48,45.59 107.1,45.97 104.62,45.97 103.13,44.48 102.24,44.48 102.04,44.67 96.97,44.67 96.46,44.16 92.32,44.16 89.26,44.16 87.26,42.16 74.31,42.16 73.93,42.54 72.74,42.54 72.36,42.92 72.36,43.27 71.29,44.34 71.29,46.42 70.94,46.77 70.94,48.42 69.9,49.46 69.9,53.08 67.73,55.25 64.39,55.25 59.44,60.2 59.44,73.56 59.79,73.91 59.79,80.83 v1(60.11,81.15)
  BOTTOM w0.102: v1(120.37,101.32) 120.37,102.3 120.56,102.49 RPC1.1 ; UC1.B30 120.28,90.41 119.97,90.73 119.97,91 120.04,91.07 120.04,93.66 119.48,94.21 119.48,96.72 119.81,97.06 119.81,98.4 119.12,99.09 119.12,99.6 118.4,100.33 v1(118.4,101.4) 118.4,102.04 117.92,102.52 102.44,102.52 100.62,100.69 100.62,96.32 100.93,96.01 100.93,68.11 107.79,61.25 113.69,61.25 116.04,58.9 116.04,58.08 v1(116.99,57.13)
APU_SID: length 190.6
  TOP w0.102: v1(58.58,76.07) 58.9,76.07 v2(59.17,76.34) 59.84,77.01 QC2.1
  IN1 w0.127: v1(116.99,56.49) 116.99,56.15 118.65,54.49 118.65,51.77 116.93,50.05 116.93,47.94 117.35,47.52 117.35,46.78 v1(117.09,46.52) ; v1(117.69,102.08) 118.97,102.08 v1(119.76,101.29)
  IN2 w0.127: v1(117.09,46.52) 117.09,45.87 115.19,43.97 113.56,43.97 112.92,44.61 112.15,44.61 112.05,44.51 109.76,44.51 109.6,44.34 109.04,44.34 108.87,44.51 105.89,44.51 105.83,44.45 104.07,44.45 102.99,43.37 94.71,43.37 94.43,43.65 89.48,43.65 89.13,43.3 89.12,43.3 87.47,41.65 74.26,41.65 73.86,41.26 73.05,41.26 71.73,42.58 71.73,43.19 70.79,44.13 70.79,46.21 70.43,46.56 70.43,48.21 69.39,49.25 69.39,50.82 67.18,53.04 65.52,53.04 58.35,60.21 58.35,74.81 58.07,75.09 58.07,75.63 58.51,76.07 v1(58.58,76.07)
  BOTTOM w0.102: RPC1.2 120.06,102.67 119.76,102.38 v1(119.76,101.29) 119.76,99.21 120.27,98.71 120.27,96.87 119.94,96.54 119.94,94.33 120.48,93.79 120.48,92.51 120.45,92.49 120.45,91.14 120.81,90.78 120.81,90.69 120.83,90.67 UC1.B29 ; v1(117.69,102.08) 117.5,102.08 117.44,102.15 102.52,102.15 100.87,100.5 100.87,96.45 101.25,96.07 101.25,70.08 102.14,69.19 102.14,67.98 108.55,61.57 113.76,61.57 116.3,59.03 116.3,58.46 117.44,57.32 117.44,56.94 v1(116.99,56.49)
APU_SPI_CLK: length 15.4
  IN2 w0.127: v1(129.12,52.34) 129.12,53.91 130.65,55.45 130.65,59.23 v1(131.28,59.86)
  BOTTOM w0.102: v1(129.12,52.34) 130.51,52.34 131.23,51.62 131.23,50.69 RC128.2 131.24,50.06 131.23,50.08 UC14.6 ; RC110.1 130.84,59.98 130.96,59.86 v1(131.28,59.86)
APU_SPI_CLK_R: length 9.9
  BOTTOM w0.102: RC110.2 130.71,61.39 129.88,62.23 129.61,62.23 v2(128.42,63.42) 127.55,64.29 127.55,66.09 127.35,66.29 127.35,68.1 127.75,68.49 127.75,68.74 127.6,68.88 127.6,69.13 UC1.AY17
APU_SPI_CS1#: length 28
  TOP w0.102: RC121.1 129.05,60.28 128.02,60.28 v1(127.85,60.11)
  IN2 w0.127: v1(126.88,49.24) 126.87,49.25 126.87,56.38 127.14,56.64 127.14,58.45 127.31,58.62 127.31,59.56 v1(127.85,60.11)
  BOTTOM w0.102: v1(126.88,49.24) 125.23,49.24 123.52,47.54 UC14.1 ; UC1.AY21 125.23,69.05 125.55,68.74 125.55,68.41 125.52,68.39 125.52,67.1 125.83,66.8 125.83,63.85 126.91,62.77 126.91,60.82 127.63,60.11 v1(127.85,60.11)
APU_SPI_CS1#_R: length 10.4
  BOTTOM w0.102: UC1.AY19 126.48,69.16 126.48,68.9 126.65,68.74 126.65,68.73 126.68,68.71 126.68,68.29 126.71,68.25 126.71,67.89 126.65,67.83 126.65,65.72 126.77,65.6 126.77,63.86 126.85,63.78 126.85,63.76 128.04,62.57 128.04,62.38 v2(128.37,62.05) 128.44,61.97 128.64,61.97 129.25,61.36 RC114.1
APU_SPI_HOLD#: length 26.5
  IN2 w0.127: v1(127.94,49.81) 128.18,50.04 128.18,54.3 129.09,55.21 129.09,57.38 129.71,58.01 129.71,60.42 v1(130.19,60.89)
  BOTTOM w0.102: v1(130.19,60.89) 129.91,60.89 129.57,61.23 129.57,61.38 127.05,63.9 127.05,65.7 126.86,65.89 126.86,67.61 126.94,67.69 126.94,68.31 126.88,68.37 UC1.BA18 ; RC119.1 131.74,48.81 UC14.7 128.87,48.81 128.75,48.93 128.75,49.48 128.42,49.81 v1(127.94,49.81)
APU_SPI_MISO: length 27.5
  IN2 w0.127: v1(129.94,61.47) 129.96,61.45 130.24,61.45 130.61,61.08 130.61,60.7 130.15,60.24 130.15,57.83 129.52,57.2 129.52,55.03 128.61,54.12 128.61,51.19 v1(128.98,50.81)
  BOTTOM w0.102: v1(129.94,61.47) 129.93,61.47 127.34,64.05 127.34,65.72 127.07,66 127.07,67.53 127.14,67.61 127.14,68.32 UC1.BA17 ; v1(128.98,50.81) 128.37,50.81 127.4,49.84 125,49.84 123.97,48.81 UC14.2
APU_SPI_MOSI: length 22.9
  IN2 w0.127: v1(128.61,60.75) 129.28,60.08 129.28,58.19 128.65,57.56 128.65,55.39 127.74,54.47 v1(127.74,51.37)
  BOTTOM w0.102: v1(127.74,51.37) 127.76,51.35 UC14.5 ; v1(128.61,60.75) 128.17,61.19 128.17,61.73 127.58,62.32 127.58,62.73 126.52,63.8 126.52,65.47 126.34,65.65 126.34,66.99 125.93,67.39 125.93,68.22 125.97,68.26 125.97,68.7 126.02,68.74 126.02,68.75 126.1,68.83 126.1,69.09 125.9,69.28 125.9,69.28 125.78,69.4 UC1.AY20
APU_SPI_TPMCS#: length 6.6
  BOTTOM w0.102: RC115.1 126.39,62.84 v2(125.71,63.52) 125.59,63.64 125.59,66.65 125.32,66.92 125.32,68.52 UC1.BA21
APU_SPI_WP#: length 27.1
  TOP w0.102: RC120.1 128.35,61.81 128.11,61.58 128.11,60.82 v1(127.98,60.68)
  IN2 w0.127: v1(127.29,50.31) 127.31,50.32 127.31,54.65 128.22,55.57 128.22,57.76 128.85,58.39 128.85,59.81 v1(127.98,60.68)
  BOTTOM w0.102: v1(127.29,50.31) 127.23,50.25 124.46,50.25 124.28,50.08 UC14.3 ; UC1.BA20 125.78,68.79 125.77,68.78 125.77,68.35 125.73,68.31 125.73,67.28 126.08,66.92 126.08,63.98 126.31,63.74 126.31,63.71 127.22,62.81 127.22,60.95 127.48,60.68 v1(127.98,60.68)
APU_SPKR: length 134.9
  TOP w0.102: CC10.1 97.86,50.54 97.86,50.54 v1(97.86,50.6) ; DA7.2 38.97,17.19 38.72,17.44 38.72,18.69 39.66,19.63 39.66,21.69 40.28,22.32 40.28,25.13 42.51,27.36 42.51,28.49 43.04,29.01 v2(43.72,29.01) 44.67,29.01 44.93,29.27 44.93,33.27 45.75,34.09 45.75,39.24 44.04,40.95 v1(44.04,41.46)
  IN2 w0.102: 119.54,65.28 119.54,66.69 120.17,67.32 120.17,68.3 118.73,69.74 118.73,71.79 119.21,72.26 119.56,72.26 120.07,72.77 v1(120.32,72.77)
  IN2 w0.127: 119.54,65.28 119.54,64.77 117.89,63.12 117.89,61.76 117.06,60.93 117.06,60.08 112.74,55.76 111.96,55.76 109.52,53.32 100.26,53.32 97.86,50.92 v1(97.86,50.6)
  BOTTOM w0.102: v1(120.32,72.77) 120.66,73.11 UC1.AP29 ; v1(97.86,50.6) 97.86,50.33 97.7,50.16 94.9,50.16 93.6,48.86 93.6,39.88 92.52,38.79 68.8,38.79 66.65,40.94 51.45,40.94 51.14,41.26 46.43,41.26 45.99,41.7 44.48,41.7 44.24,41.46 v1(44.04,41.46)
APU_SVC: length 105.5
  TOP w0.102: PUZ01.3 149.12,143.44 149.39,143.71 v1(149.39,143.76) ; v1(116.68,142.17) RC14.2 ; v1(113.13,127.31) 112.63,126.82 112.63,124.98 114.03,123.59 114.03,116.98 121.66,109.36 126.42,109.36 128.32,107.46 128.32,102.88 127.8,102.36 126.15,102.36 125.87,102.08 125.87,97.24 v2(125.03,96.4) 123.15,94.53 123.15,92.69 123.59,92.25 RC10.1
  IN1 w0.127: v1(116.68,142.17) 116.63,142.17 116.28,142.53 113.48,142.53 112.55,141.59 112.55,127.89 113.12,127.31 v1(113.13,127.31)
  IN2 w0.127: v1(116.68,142.17) 116.87,142.17 118.53,140.52 133.77,140.52 137.89,144.65 140.94,144.65 141.89,145.6 147.16,145.6 147.35,145.41 147.74,145.41 v1(149.39,143.76)
APU_SVC_R: length 5.3
  TOP w0.102: RC10.2 123.11,90.73 123.11,89.39 122.86,89.13 122.86,88.39 122.48,88.01 v1(122.48,88.01) 122.48,87.77 v2(122.09,87.38)
  BOTTOM w0.102: UC1.E27 122.18,88.31 v1(122.48,88.01)
APU_SVD: length 103.9
  TOP w0.102: RC12.1 122.71,94.65 v2(123.39,95.33) 125.67,97.61 125.67,102.32 126.02,102.67 127.75,102.67 128.11,103.04 128.11,107.37 126.34,109.15 121.57,109.15 113.83,116.9 113.83,123.5 112.43,124.9 112.43,127.2 v1(113.13,127.9) ; PUZ01.5 148.32,143.7 148.21,143.8 v1(148.21,143.81) ; RC16.2 v1(115.86,142.11)
  IN1 w0.127: v1(113.13,127.9) 112.8,128.23 112.8,141.4 113.51,142.11 v1(115.86,142.11)
  IN2 w0.127: v1(148.21,143.81) 148.21,144.49 147.54,145.16 147.16,145.16 146.97,145.35 142.08,145.35 141.13,144.39 138.15,144.39 133.96,140.2 118.33,140.2 117.26,141.28 116.49,141.28 115.86,141.92 v1(115.86,142.11)
APU_SVD_R: length 3.6
  TOP w0.102: RC12.2 122.49,91.12 v2(122.49,90.29) 122.49,90.25 122.86,89.88 122.86,89.42 122.48,89.04 v1(122.48,88.81)
  BOTTOM w0.102: v1(122.48,88.81) 122.18,89.11 UC1.D27
APU_SVT: length 39
  TOP w0.102: v1(114.07,141.35) 114.08,141.36 RC11.2
  TOP w0.127: v1(138.34,143.63) 138.67,143.3 RC9.1
  TOP w0.203: v1(147.23,144.04) 147.23,143.51 147.52,143.22 PUZ01.7
  IN2 w0.127: v1(147.23,144.04) 147.23,144.14 147.05,144.32 141.44,144.32 141.26,144.14 138.82,144.14 138.34,143.65 v1(138.34,143.63) 137.77,143.63 134.08,139.95 118.21,139.95 117.33,140.83 114.59,140.83 v1(114.07,141.35)
APU_SVT_R: length 94.2
  TOP w0.102: v1(121.46,87.18) 122.1,87.82 122.1,91.77 121.69,92.18 121.69,95.86 124.04,98.21 124.04,98.59 123.91,98.73 119.49,98.73 117.76,100.45 117.76,101.46 120.55,104.24 v2(120.55,106.1) 120.55,109.89 113.62,116.81 113.62,123.42 112.23,124.82 112.23,127.77 112.76,128.3 113.3,128.3 113.71,127.89 v1(113.71,127.88)
  TOP w0.127: RC9.2 137.45,143 137.26,142.81 v1(137.26,142.04)
  IN1 w0.127: v1(113.71,127.88) 113.71,127.91 113.06,128.55 113.06,140.52 113.19,140.65 v1(113.57,140.65)
  IN2 w0.127: v1(113.57,140.65) 114.4,140.65 114.59,140.46 117.26,140.46 118.02,139.7 134.21,139.7 136.55,142.04 v1(137.26,142.04)
  BOTTOM w0.102: v1(121.46,87.18) 121.46,87.18 UC1.H27
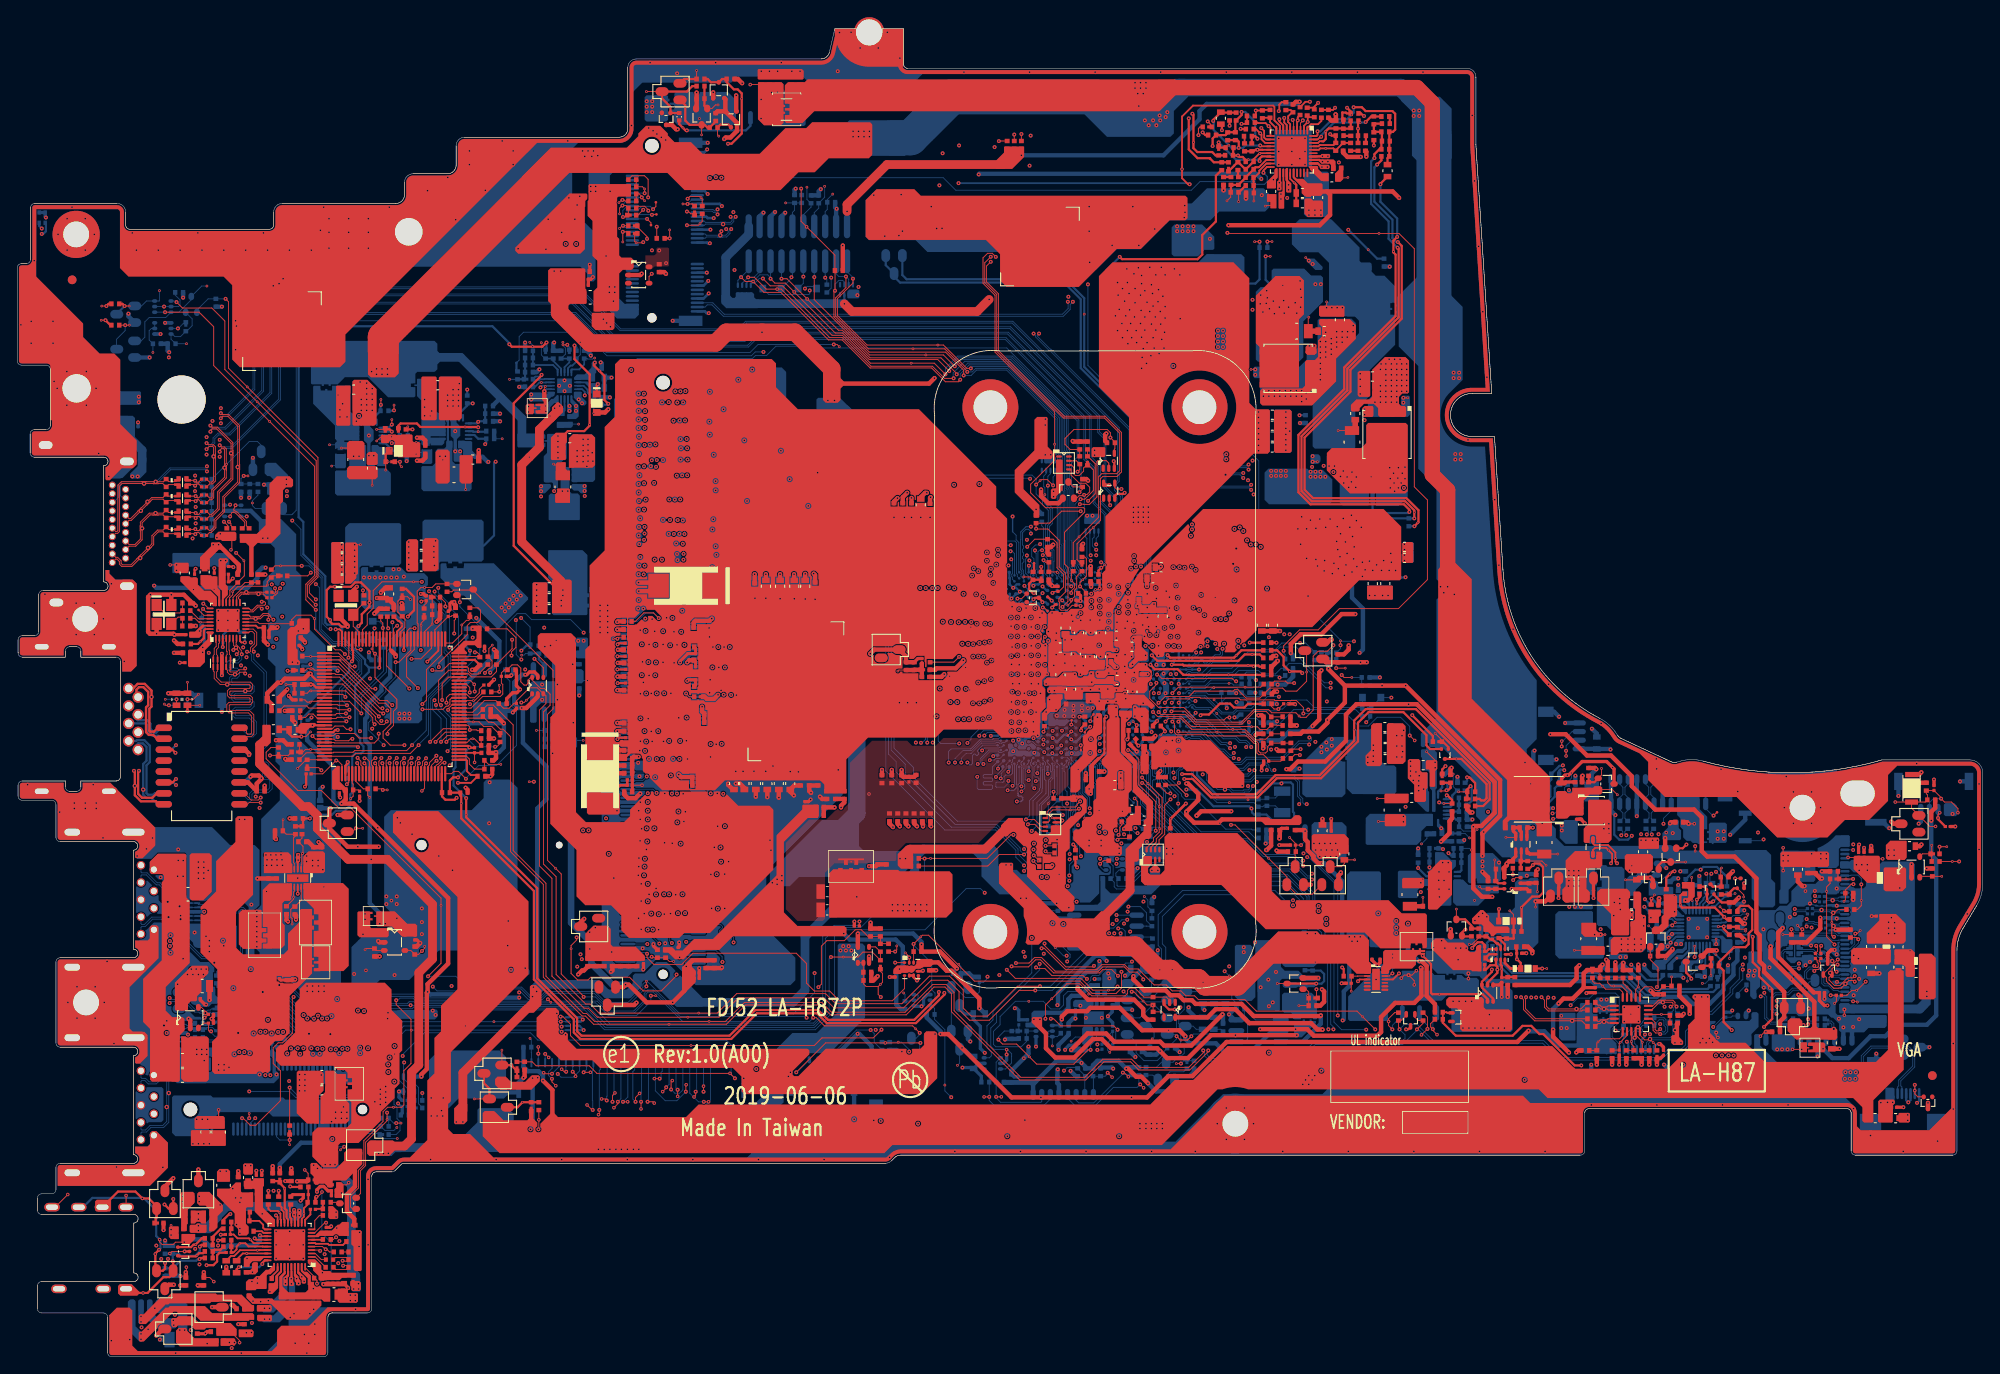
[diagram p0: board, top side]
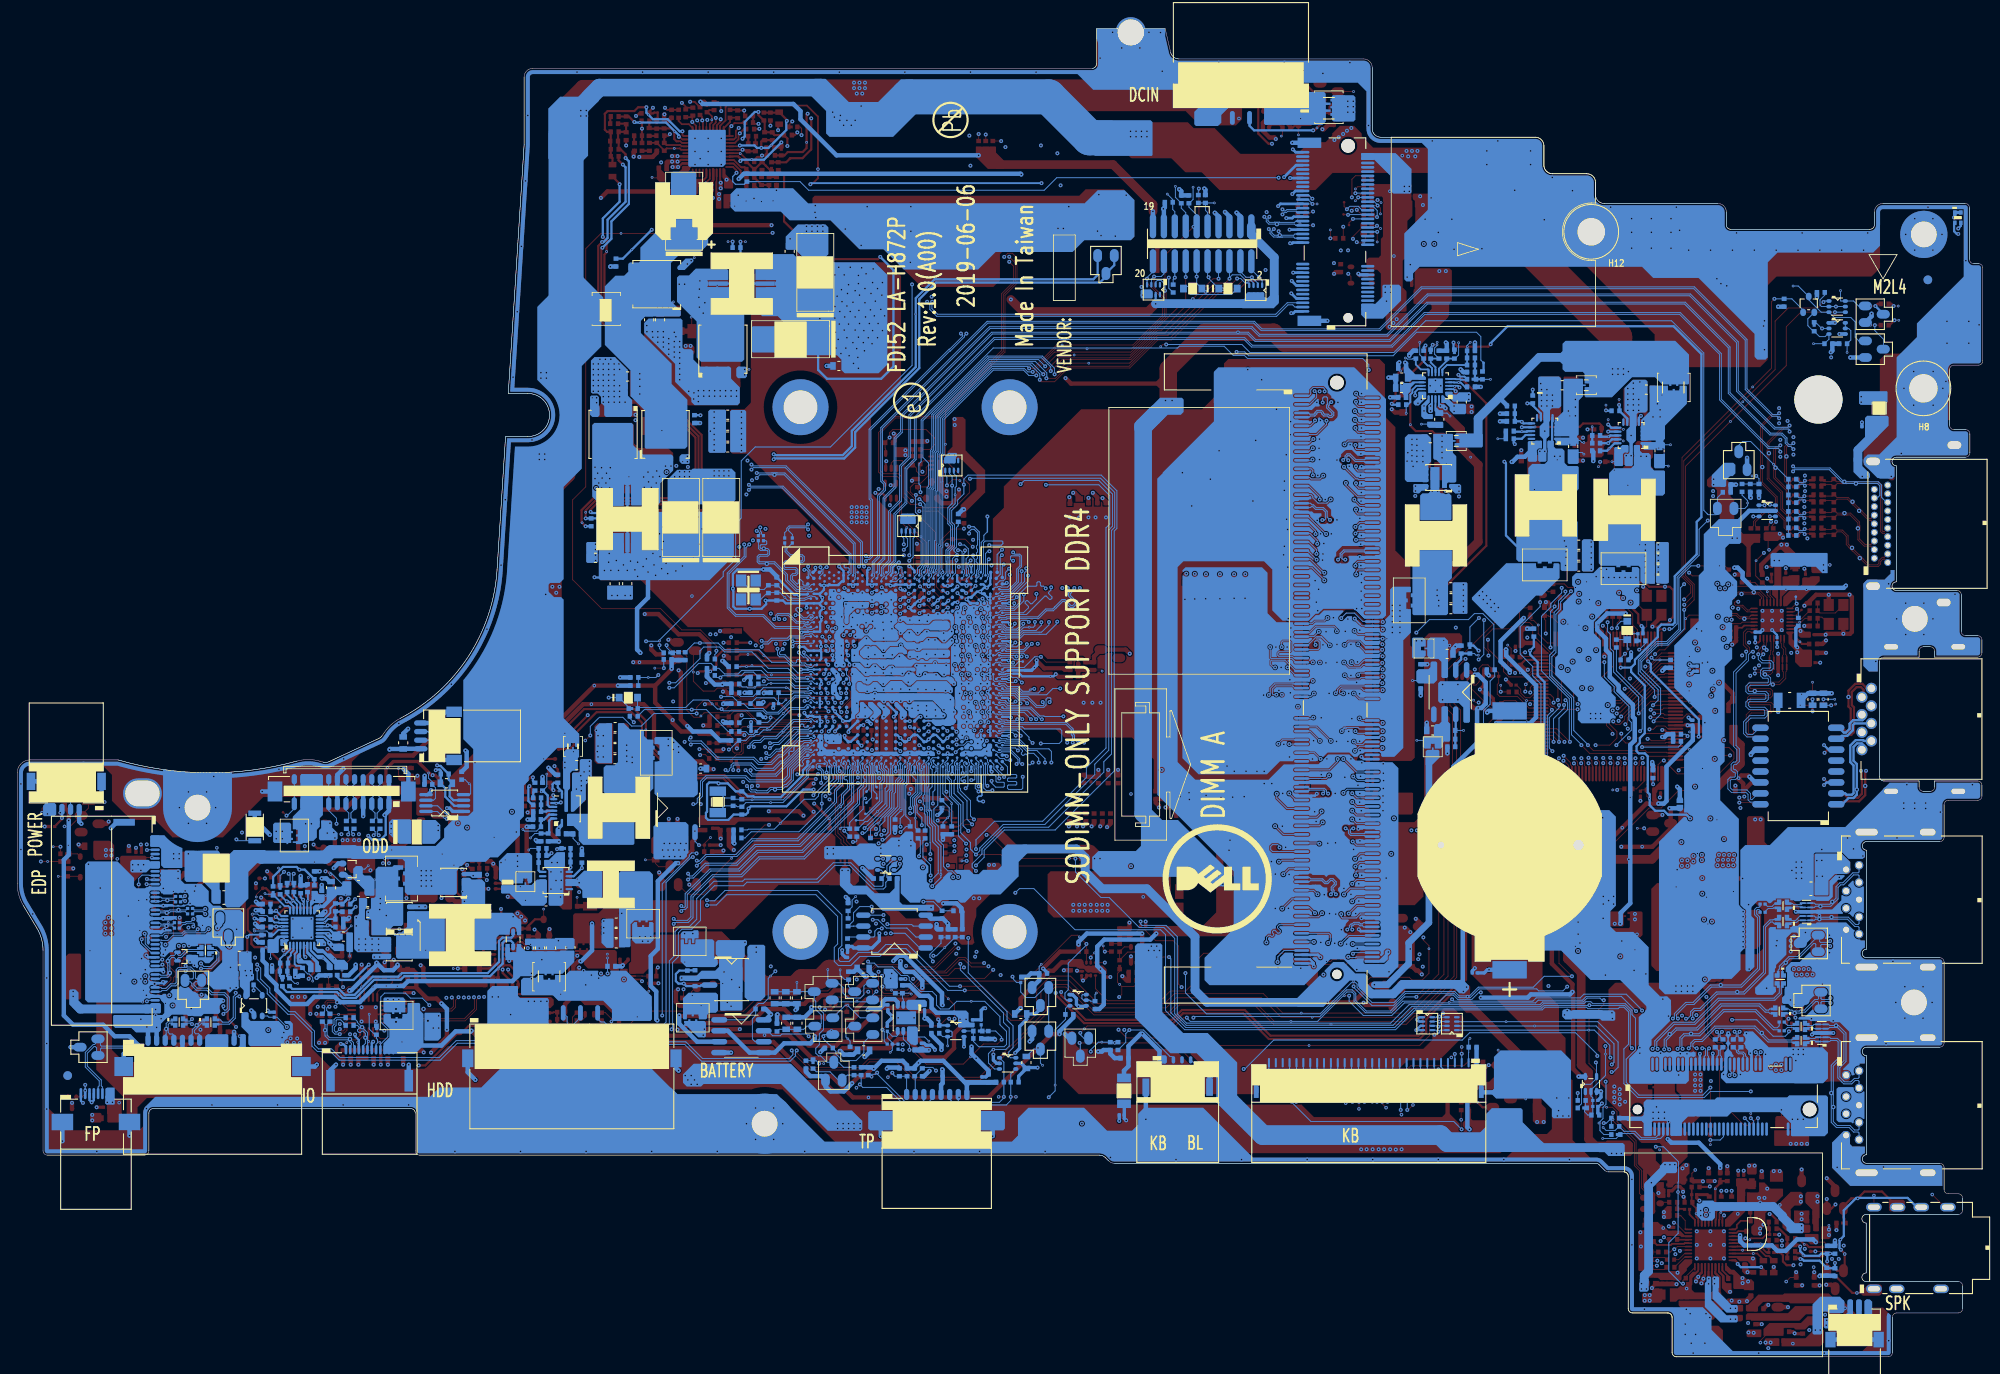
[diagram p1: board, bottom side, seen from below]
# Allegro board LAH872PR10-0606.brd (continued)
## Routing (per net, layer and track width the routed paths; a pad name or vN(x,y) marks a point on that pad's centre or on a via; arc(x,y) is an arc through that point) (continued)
APU_TCK: length 68.3
  TOP w0.102: v1(84.11,125.53) 84.61,125.03 v4(85.51,125.03) 86.78,123.76 88.74,123.76 94.26,118.23 95.86,118.23 99.12,114.97 106.26,114.97 107.86,113.36 109.34,113.36 v1(109.57,113.6)
  BOTTOM w0.102: v1(109.57,113.6) 109.57,114.27 110.64,115.33 115.22,115.33 121.31,109.25 121.31,105.19 121.48,105.02 121.48,100.7 121.54,100.64 121.54,94.54 121.59,94.49 121.59,91.6 121.68,91.51 121.68,91.38 121.63,91.32 121.63,91.07 121.93,90.76 UC1.B27 ; RPH1.1 83.74,125.16 v1(84.11,125.53) 85,126.42 JHDT1.2
APU_TDI: length 67.7
  TOP w0.102: v1(108.3,114.61) 106.96,115.95 99,115.95 95.92,119.03 95.06,119.03 v4(90.28,123.81) 89.25,124.84 88.05,124.84 v1(87.54,125.34)
  BOTTOM w0.102: v1(108.3,114.61) 108.3,115.09 109.35,116.15 115.56,116.15 122.12,109.58 122.12,105.52 122.29,105.35 122.29,101.11 122.45,100.95 122.45,94.9 122.48,94.87 122.48,91.86 122.59,91.75 122.59,91.55 122.64,91.5 122.64,91.15 123.03,90.76 UC1.B25 ; RPH1.3 84.74,124.83 85.02,125.12 85.59,125.12 86.28,125.8 87.21,125.8 87.54,125.47 ; 87.54,125.47 v1(87.54,125.34) ; 87.54,125.47 JHDT1.6
APU_TDO: length 60.8
  TOP w0.102: v1(109.17,114.23) 109.17,114.32 107.34,116.15 99.09,116.15 95.88,119.36 95.42,119.36 v4(91.79,122.99) 89.44,125.34 v1(88.81,125.34)
  BOTTOM w0.102: v1(109.17,114.23) 110.47,115.54 115.3,115.54 121.51,109.33 121.51,105.27 121.68,105.1 121.68,100.79 121.74,100.72 121.74,94.93 121.79,94.87 121.79,91.68 121.91,91.57 121.91,91.41 121.93,91.39 UC1.A27 ; JHDT1.8 v1(88.81,125.34)
APU_TEST0: length 10.1
  BOTTOM w0.102: RC72.2 144.5,76.95 144.31,76.76 142.9,76.76 142.44,77.21 RC41.2 141.71,77.79 v2(139.04,77.79) 138.86,77.79 138.48,77.4 136.39,77.4 136.32,77.47 136.05,77.47 135.74,77.16 UC1.AF2
APU_TEST1: length 8.7
  BOTTOM w0.102: UC1.AE1 136.53,77.71 138.02,77.71 138.62,78.3 v2(140.81,78.3) 141.13,78.3 141.33,78.1 142.15,78.1 RC43.2 142.74,77.77 143.52,77.77 143.64,77.89 144.16,77.89 RC71.2
APU_TEST2: length 17.6
  TOP w0.102: v1(132.37,78.35) 132.37,78.15 131.6,77.38 131.6,76.52 132.62,75.5 135.56,75.5 137.02,74.04 140.23,74.04 140.53,74.33 v1(140.86,74.33)
  BOTTOM w0.102: RC73.2 144.02,74.21 142.66,74.21 RC45.2 141.19,73.76 140.89,74.06 140.89,74.24 140.86,74.27 v1(140.86,74.33) ; v1(132.37,78.35) 132.37,78.47 UC1.AC8
APU_TEST4: length 1.4
  TOP w0.254: T2.1 120.62,87.48 v1(120.26,87.11)
  BOTTOM w0.102: UC1.H29 120.43,87.11 v1(120.26,87.11)
APU_TEST5: length 1.5
  TOP w0.254: T3.1 119.76,88.37 v1(120.21,87.91)
  BOTTOM w0.25: UC1.G29 120.62,87.51 v1(120.21,87.91)
APU_TEST6: length 1.2
  TOP w0.102: T4.1 123.56,86.36 v1(123.56,86.46)
  BOTTOM w0.102: v1(123.56,86.46) 123.31,86.71 UC1.H25
APU_TEST9: length 1.2
  TOP w0.102: v1(119.42,83.71) 119.27,83.57 T5.1
  BOTTOM w0.102: UC1.R32 119.23,83.53 v1(119.42,83.71)
APU_TEST10: length 1.2
  TOP w0.102: v1(119.38,84.86) 119.12,84.6 T6.1
  BOTTOM w0.102: v1(119.38,84.86) 119.23,84.71 UC1.N32
APU_TEST14: length 10.3
  IN2 w0.102: v1(125.79,87.21) 126.23,87.64 126.23,89.74 125.46,90.5 125.46,91.95
  IN2 w0.127: v1(124.74,93.19) 125.46,92.47 125.46,91.95
  BOTTOM w0.102: v1(125.79,87.21) 125.49,87.51 UC1.G21 ; v1(124.74,93.19) 124.64,93.29 RPC3.7
APU_TEST15: length 11
  IN2 w0.102: 125.21,91.95 125.21,87.18 125.79,86.6 v1(125.79,86.41)
  IN2 w0.127: 125.21,91.95 125.21,92.09 v1(124.74,92.56)
  BOTTOM w0.102: v1(125.79,86.41) 125.49,86.71 UC1.H21 ; v1(124.74,92.56) 124.3,93 124.3,95.16 124.14,95.32 RPC3.8
APU_TEST16: length 10
  IN2 w0.102: 123.62,91.95 123.62,91.44 124.38,90.68 124.38,89.14 v1(124.8,88.72)
  IN2 w0.127: v1(125.38,93.83) 124.61,93.83 123.62,92.84 123.62,91.95
  BOTTOM w0.102: v1(124.8,88.72) 124.52,88.72 UC1.D23 ; v1(125.38,93.83) 124.93,94.27 124.93,95.1 125.14,95.31 RPC3.6
APU_TEST17: length 11.1
  IN2 w0.102: v1(124.83,87.88) 124.79,87.92 124.79,87.93 124.13,88.58 124.13,90.49 123.18,91.44 123.18,91.95
  IN2 w0.127: 123.18,91.95 123.18,92.96 124.68,94.46 v1(125.38,94.46)
  BOTTOM w0.102: RPC3.5 125.64,95.43 125.38,95.16 v1(125.38,94.46) ; v1(124.83,87.88) 124.4,88.31 UC1.E23
APU_TEST18: length 57.3
  TOP w0.102: v1(110.81,114.93) 110.34,114.93 107.63,117.64 v2(106.98,117.64) 98.75,117.64 95.31,121.08 95.31,123.04 97.11,124.84 v1(97.11,125.34)
  BOTTOM w0.102: v1(110.81,114.93) 111.02,115.13 115.14,115.13 121.1,109.16 121.1,105.1 121.27,104.93 121.27,94.47 121.39,94.36 121.39,90.86 UC1.A28 ; 96.43,127.37 96.43,126.17 97.11,125.48 v1(97.11,125.34) RPH2.4
APU_TEST19: length 59.3
  TOP w0.102: v1(96.3,125.6) 96.3,124.32 95.11,123.12 95.11,120.99 98.91,117.19 v2(104.09,117.19) 107.78,117.19 110.4,114.58 v1(110.4,114.52)
  BOTTOM w0.102: v1(110.4,114.52) 110.98,114.52 111.39,114.93 115.05,114.93 120.9,109.08 120.9,105.02 121.07,104.85 121.07,101.71 121.06,101.7 121.06,94.3 121.18,94.17 121.18,91.13 121.02,90.96 121.02,90.78 121.38,90.41 UC1.B28 ; RPH2.3 96.61,125.28 v1(96.3,125.6) 95.47,125.6 95.16,125.92 JHDT1.18
APU_TEST28_H: length 1.1
  TOP w0.102: T7.1 132.58,84.11 v1(132.37,83.9)
  BOTTOM w0.102: v1(132.37,83.9) 132.03,84.24 UC1.N8
APU_TEST28_L: length 1.1
  TOP w0.102: v1(131.61,83.93) 131.3,84.24 T8.1
  BOTTOM w0.102: UC1.N10 v1(131.61,83.93)
APU_TEST31: length 1.4
  TOP w0.102: v1(119.18,87.12) 119.32,87.12 T9.1
  BOTTOM w0.102: v1(119.18,87.12) 119.59,86.71 UC1.H31
APU_TEST36: length 5.9
  TOP w0.102: RC24.1 124.06,92.99 124.23,92.81 124.23,90.77 v2(123.81,90.34) 123.5,90.03 v1(123.5,89.57) 124.19,88.88 RC28.1
  BOTTOM w0.102: UC1.D25 v1(123.5,89.57)
APU_TEST41: length 5.2
  TOP w0.102: v1(119.26,92.63) 119.51,92.38 RC25.1 RC27.1 120.79,91.26 v2(120.87,91.18)
  BOTTOM w0.102: v1(119.26,92.63) 119.26,92.37 119.37,92.27 119.37,91.12 119.73,90.76 UC1.B31
APU_TMS: length 69.2
  TOP w0.102: v1(84.93,125.51) 85.65,125.51 87.03,124.14 v4(88.3,124.14) 88.77,124.14 94.41,118.5 95.88,118.5 99.2,115.17 106.34,115.17 107.75,113.76 108.8,113.76 v1(108.81,113.77)
  BOTTOM w0.102: RPH1.2 84.24,124.82 v1(84.93,125.51) 84.94,125.52 85.62,125.52 86.27,126.17 86.27,127.37 ; UC1.B26 122.48,90.41 122.17,90.73 122.17,91.01 122.24,91.08 122.24,91.33 122.14,91.43 122.14,91.63 122,91.77 122,100.83 121.88,100.94 121.88,105.19 121.71,105.36 121.71,109.42 115.39,115.74 110.1,115.74 108.76,114.4 108.76,113.82 v1(108.81,113.77)
APU_TRST#: length 69.3
  TOP w0.102: v1(91.09,135.82) 91.09,132.01 v4(91.73,131.38) 95.02,128.09 CH2.1 95.03,126.28 v1(95.03,123.95) 94.9,123.82 94.9,120.91 99,116.81 107.88,116.81 109.98,114.71 v1(109.98,114.1)
  BOTTOM w0.102: v1(91.09,135.82) 91.16,135.76 RH1.1 ; v1(109.98,114.1) 110.85,114.1 111.47,114.72 114.97,114.72 120.7,108.99 120.7,104.93 120.87,104.76 120.87,101.81 120.85,101.79 120.85,94.14 120.95,94.04 120.95,91.56 120.83,91.44 UC1.A29 ; RPH2.2 96.11,124.96 95.92,125.16 95.49,125.16 95.03,124.7 v1(95.03,123.95)
APU_TRST#_R: length 4.7
  BOTTOM w0.102: CH1.1 90.33,133.31 90.08,133.05 JHDT1.9 ; CH1.1 RH1.2 ; CH1.1 v2(89.29,134.16)
APU_VDD_RUN_FB_L: length 113.6
  TOP w0.203: RC29.2 v1(118.99,91.85)
  TOP w0.254: PRZ67.1 140.34,139.68 PRZ69.2 139.25,139.68 138.86,140.08 137.13,140.08 136.68,140.53 v2(136.68,141.21) 136.68,144.4 v1(136.55,144.53)
  IN1 w0.254: v1(136.55,144.53) 135.87,144.53 135.35,144.01 135.35,143.51 133.64,141.79 119.79,141.79 117.98,143.61 112.28,143.61 110.2,141.53 110.2,133.47 104.94,128.21 104.94,108.43 110.74,102.63 119.92,102.63 120.96,101.59 120.96,98.95 123.85,96.05 125.31,96.05 126.72,94.64 126.72,91.85 125.9,91.03 120.76,91.03 119.95,91.85 v1(118.99,91.85)
APU_VDD_SEN: length 114.2
  TOP w0.254: PRZ75.2 139.97,138.88 PRZ51.1 139.05,138.89 T10.1 138.57,139.37 137.15,139.37 136.14,140.38 v1(136.14,143.99)
  IN1 w0.254: v1(119.15,89.57) 119.14,89.58 119.14,89.94 119.87,90.67 126.05,90.67 127.1,91.73 127.1,94.83 125.48,96.46 123.99,96.46 121.34,99.11 121.34,101.75 120.07,103.01 110.89,103.01 105.32,108.58 105.32,128.02 110.58,133.28 110.58,141.34 112.47,143.23 117.82,143.23 119.74,141.31 133.73,141.31 136.14,143.71 v1(136.14,143.99)
  BOTTOM w0.254: v1(119.15,89.57) 119.61,89.11 UC1.D31
APU_VDDIO_MEM_S3_FB_H: length 82.9
  IN1 w0.102: 116.04,94.49 116.62,93.91 116.62,92.64 117.04,92.22 v1(117.04,89.64)
  IN1 w0.127: 116.04,94.49 114.65,95.88 114.5,95.88 112.09,98.29 98.14,98.29 87.03,109.41 87.03,116.58 86.78,116.84 v1(86.71,116.84)
  BOTTOM w0.102: v1(86.71,116.84) 85.76,116.84 85.31,116.39 68.52,116.39 65.79,119.12 58.84,119.12 58.33,118.61 58.33,115.88 T30.1
  BOTTOM w0.125: v1(117.04,89.64) 117.53,89.15 UC1.D35
  BOTTOM w0.254: PRM13.2 58.01,114.69 T30.1
APU_VDDNB_SEN: length 128.9
  TOP w0.254: v1(154.53,145.22) 154.94,144.81 PRZ02.2 154.48,144.57 154.39,144.66 T11.1 153.98,144.05 154.1,143.94 PRZ06.1
  IN1 w0.254: v1(154.53,145.22) 153.96,145.79 152.43,145.79 151.22,144.57 149.24,144.57 148.15,145.66 138.63,145.66 133.35,140.39 120.11,140.39 117.66,142.85 112.66,142.85 110.97,141.15 110.97,133.09 105.7,127.83 105.7,108.74 110.71,103.73 116.45,103.73 116.79,103.39 120.23,103.39 121.72,101.91 121.72,99.26 124.14,96.84 125.67,96.84 127.48,95.02 127.48,91.61 126.19,90.32 120.3,90.32 119.6,89.62 119.6,89.25 v1(119.15,88.79)
  BOTTOM w0.125: v1(119.15,88.79) 118.66,88.31 UC1.E33
APU_VDDP_RUN_FB_H: length 54.6
  TOP w0.102: T31.1 124.79,74.42 124.79,74.02 v1(124.68,73.91)
  TOP w0.254: v1(135.61,67.18) 136.58,67.18 138.71,65.04 144.14,65.04 146.36,67.27 151.5,67.27 155.8,71.57 155.8,73.72 157.03,74.95 161.07,74.95 163.75,72.28 163.75,71.09 164.17,70.67 PQH01.3
  IN1 w0.102: v1(135.61,67.18) 135.86,67.43 135.86,67.94 134.84,68.96 133.96,68.96 129.7,73.21 126.78,73.21 126.08,73.91 v1(124.68,73.91)
  BOTTOM w0.254: UC1.AM21 v1(124.68,73.91)
APU_VDDP_RUN_FB_L: length 64.5
  TOP w0.254: PRH15.2 170.34,64.04 171.1,64.79 171.1,66.74 162.53,75.31 156.69,75.31 155.36,73.97 v2(155.36,72.89) 155.36,71.62 151.35,67.62 146.21,67.62 143.99,65.4 138.86,65.4 136.51,67.75 v1(135.35,67.75) ; RC31.2 123.62,73.07 v1(123.62,72.83)
  IN1 w0.102: v1(123.62,72.83) 125.08,72.83 125.13,72.88 129.59,72.88 133.84,68.64 134.59,68.64 135.16,68.07 135.16,67.94 v1(135.35,67.75)
APU_VSS_SENSE_A: length 4.8
  TOP w0.102: v2(116.96,90.67) 117.71,90.67 RC30.1
  TOP w0.254: RC29.1 RC30.1 117.59,89.9 117.59,89.22 118.01,88.8 v1(118.14,88.8)
  BOTTOM w0.254: v1(118.14,88.8) 118.45,89.11 UC1.D33
APU_VSS_SENSE_B: length 1.6
  TOP w0.254: RC31.1 123.45,74.43 v1(123.43,74.41)
  BOTTOM w0.254: UC1.AM23 123.62,74.42 123.43,74.42 123.43,74.41 v1(123.43,74.41)
ASGATE:
  vias: v2(192.86,46.35)
AUD_HP1_JACK_L: length 6.2
  TOP w0.203: RA59.2 RA58.1 24.77,14.79 CA505.1 25.15,14.22 25.6,13.77 26.92,13.77 v2(27.09,13.61) 27.48,13.21 UA1.25
AUD_HP1_JACK_L1: length 2.6
  TOP w0.254: RA58.2 23.66,14.89 22.72,13.95 RA52.2 LA2.1
AUD_HP1_JACK_R: length 6.5
  TOP w0.203: UA1.26 28.56,12.81 28.54,12.83 26.89,12.83 26.51,13.2 25.88,13.2 v2(25.8,13.12) 25.5,12.82 25.5,12.49 25.13,12.13 CA506.1 24.87,12.79 RA61.1 RA55.2
AUD_HP1_JACK_R1: length 2.2
  TOP w0.254: RA61.2 23.62,12.45 22.92,12.45 RA53.2 LA3.1
AUD_PC_BEEP: length 1.8
  TOP w0.203: UA1.11 33.46,15.93 34.07,16.54 CA478.2
AUD_PC_BEEP_C: length 1.1
  TOP w0.102: RA31.1 37.36,17.97 DA7.1
AUD_SENSE_A: length 4.5
  TOP w0.203: RA51.2 CA488.1 33.83,18.05 RA40.1 33.74,17.7 33.31,17.27 v2(33.31,16.65) 33.31,16.29 33.06,16.04 UA1.12
AUD_SPK_L+:
  vias: v1(28.74,5.65) v1(29.32,5.63) v1(31.17,9.08) v1(31.17,8.49)
AUD_SPK_L+_C:
  vias: v1(14.39,4.69) v1(14.39,4.06) v4(16,5.65)
AUD_SPK_L-:
  vias: v1(28.74,4.38) v1(29.32,4.38) v1(31.83,9.08) v1(31.86,8.48)
AUD_SPK_L-_C:
  vias: v1(14.39,2.66) v1(14.39,2.03) v4(15.21,3.2)
AUD_SPK_R+:
  vias: v1(24.66,1.66) v1(25.24,1.66) v1(33.07,9.29) v1(33.33,8.77)
AUD_SPK_R+_C:
  vias: v1(18.89,3.11) v1(19.47,3.11) v4(22.07,1.53)
AUD_SPK_R-:
  vias: v1(26.63,2.79) v1(27.22,2.83) v1(32.47,9.08) v1(32.7,8.54)
AUD_SPK_R-_C: length 1.4
  TOP w0.102: LA16.2 25.14,2.58 25.84,1.89 v4(25.84,1.65)
  vias: v1(18.13,4.25) v1(18.2,3.68)
AUD_VREF: length 1.7
  TOP w0.203: CA489.1 28.42,14.6 28.61,14.41 UA1.22
BA: length 5
  TOP w0.127: v2(186.89,55.46) PRB41.2
  TOP w0.508: PQB28.1 190.08,55.4 189.79,55.68 v1(189.73,55.68) 188.43,55.68 PRB41.2
  BOTTOM w0.508: PDB01.3 190.28,56.05 189.94,55.71 189.76,55.71 v1(189.73,55.68)
BATGONE: length 4.1
  TOP w0.102: v1(198.32,51.86) v2(197.86,52.32)
  TOP w0.254: PRB24.1 198.41,51.77 v1(198.32,51.86)
  BOTTOM w0.203: PUB01.25 197.7,51.24 v1(198.32,51.86) 198.43,51.75 198.95,51.75 PCB09.1
  BOTTOM w0.254: PRB23.1 PCB09.1
BATT_CHG_LED: length 4.4
  TOP w0.102: R40.2 v1(12.54,119.95) v2(13.03,119.95)
  BOTTOM w0.102: Q9.1 11.53,117.19 11.53,118.3 12.54,119.31 v1(12.54,119.95)
BATT_CHG_LED#: length 65.7
  TOP w0.102: v1(17.18,121.46) 21.13,121.46 22.83,119.76 22.83,115.25 v2(29.32,108.76) 34.54,103.54 34.54,90.82 33.54,89.82 33.54,88.01 v1(34.7,86.85) ; v1(38.25,73.88) 38.19,73.82 UE1.21
  BOTTOM w0.102: v1(34.7,86.85) 34.7,84.63 36.58,82.75 37.74,82.75 39.62,80.86 39.62,79.91 37.44,77.72 37.44,74.7 v1(38.25,73.88) ; Q7.4 v1(17.18,121.46)
BATT_CHG_LED_R#: length 12.3
  BOTTOM w0.102: v2(22.04,124.49) 21.44,124.49 Q12.1 20.23,122.91 18.78,121.46 Q7.3 17.25,120.84 15.34,120.84 14.83,120.33 14.83,118.55 14.4,118.12 Q9.2
BATT_I: length 192.6
  TOP w0.102: v2(201.1,51.46) 201.1,51.24 v1(200.82,50.96) ; UE1.75 52.39,73.42 52.56,73.25 52.56,72.92 v1(52.6,72.89) 53.39,72.89 53.49,72.8 PCB10.1
  IN1 w0.127: v1(52.6,72.89) 52.6,72.66 53.58,71.67 53.58,69.81 55.66,67.73 55.66,66.59 59.35,62.9 59.35,53.92 61.55,51.72 61.55,43.89 62.9,42.54 63.27,42.54 65.67,40.14 66.11,40.14 69.45,36.8 88.51,36.8 92.68,32.63 108.8,32.63 108.99,32.44 119.29,32.44 119.54,32.19 122.66,32.19 123.07,32.6 128.97,32.6 129.89,33.52 135.25,33.52 136.64,34.92 142.85,34.92 150.24,42.31 155.56,42.31 155.83,42.58 157.19,42.58 158.55,43.94 180.84,43.94 181.23,44.33 188.94,44.33 189.36,44.75 191.23,44.75 192.62,43.37 196.89,43.37 198.37,44.84 198.37,45.7 200.28,47.61 200.28,50.64 200.61,50.96 v1(200.82,50.96)
  BOTTOM w0.203: v1(200.82,50.96) 200.61,50.96 200.48,50.83 PRB29.1
BATT_LOW_LED: length 2.6
  TOP w0.102: v1(12.48,122.17) v2(13.01,122.17)
  TOP w0.254: R43.2 12.23,122.42 v1(12.48,122.17)
  BOTTOM w0.254: Q8.1 11.57,121.26 v1(12.48,122.17)
BATT_LOW_LED#: length 67.1
  TOP w0.102: UE1.93 50.25,80.62 49.37,79.75 48.34,79.75 v1(48.23,79.86) ; v1(34.69,87.43) 33.74,88.38 33.74,89.73 34.74,90.73 34.74,104.18 v2(27.89,111.03) 24.13,114.79 24.13,120.43 22.61,121.94 19.2,121.94 v1(18.51,122.63)
  IN1 w0.127: v1(34.69,87.43) 34.71,87.43 35.28,86.87 35.28,84.57 36.41,83.43 40.48,83.43 42.26,81.65 42.26,81.47 43.87,79.86 v1(48.23,79.86)
  BOTTOM w0.102: v1(18.51,122.63) 18.39,122.76 Q7.1
BATT_LOW_LED_R#: length 4.3
  BOTTOM w0.102: v2(16.53,123.96) 16.53,122.79 16.5,122.76 Q7.6 15.02,122.76 14.45,122.18 Q8.2
BEEP#: length 64.8
  TOP w0.102: v1(42.98,28.38) v2(42.98,27.61) 42.98,27.44 40.48,24.95 40.48,22.23 39.89,21.64 39.89,18.99 DA7.3 ; UE1.23 36.61,73.02 36.93,73.34 37.88,73.34 38.26,72.96 v1(38.73,72.96)
  IN1 w0.127: v1(42.98,28.38) 43.58,28.99 43.58,31.08 44.29,31.79 44.29,33.29 44.12,33.46 44.12,35.26 46.14,37.28 46.14,53.58 39.91,59.81 39.91,63.69 39.21,64.38 39.21,66.29 37.48,68.02 37.48,69.68 38.53,70.72 38.53,72.75 v1(38.73,72.96)
BGATE: length 31.6
  TOP w0.102: v1(197.42,47.99) v2(197.42,48.56)
  IN2 w0.508: v1(197.42,47.99) 197.7,48.27 197.7,51.47 196.38,52.79 196.38,53.78 194.78,55.38 194.78,56.84 193.84,57.78 187.24,57.78 186.89,58.14 179.59,58.14 177.39,55.94 v1(175.42,55.94)
BKOFF#: length 10.6
  TOP w0.102: UE1.105 46.53,84.3 46.58,84.35 46.58,85.21 46.48,85.31 46.48,89.02 46.9,89.44 v2(47.33,89.44) 48.21,89.44 48.62,89.86 RV33.2 49.95,89.86 DV1.2
BMON: length 4.1
  BOTTOM w0.102: v2(201.01,51.48) 200.47,51.48 200.27,51.29 199.39,51.29 198.97,50.87 PRB29.2
  BOTTOM w0.203: PUB01.27 197.96,50.44 198.02,50.5 198.51,50.5 198.84,50.83 PRB29.2
BST1_APU:
  vias: v1(145.97,136.86)
BST1_APU_R: length 1
  TOP w0.102: v2(145.03,133.79) 145.09,133.85 PCZ38.1
BST_0.95V:
  vias: v1(165.46,61.45)
BST_0.95V_R: length 1.4
  BOTTOM w0.102: PCH12.1 163.81,60.26 v2(163.18,59.63)
BST_1.2V: length 1.4
  BOTTOM w0.102: v2(61.91,109.38) 62.25,109.72 PRM02.1
BST_1.2V_R: length 1
  BOTTOM w0.102: PCM12.1 v2(65.24,108.44)
BST_3V: length 1.3
  BOTTOM w0.102: PR301.1 46.82,106.55 46.58,106.31 v2(46.36,106.31)
BST_3V_R: length 1.3
  BOTTOM w0.102: v2(46.35,104.95) 46.55,105.15 PR301.2
BST_5V: length 1.3
  BOTTOM w0.102: PR501.1 v2(36.3,106.04)
BST_5V_R: length 1
  BOTTOM w0.102: v2(36.55,103.56) 36.62,103.64 PC507.1
BST_CHG: length 1
  BOTTOM w0.102: PCB06.1 v2(189.76,46.59)
BST_CHG_R: length 2.4
  BOTTOM w0.102: PRB14.1 191.21,49.31 191.05,49.46 190.23,49.46 v2(189.59,50.1)
BST_NB_R: length 0.8
  TOP w0.102: v2(154.63,137.13) 154.58,137.08 153.88,137.08
BT_ON#: length 155.5
  TOP w0.102: v2(69.92,134.2) 70.23,134.5 v1(70.33,134.5) 70.51,134.5 70.62,134.39 RW12.2
  IN1 w0.127: v1(119.35,70.3) 119.16,70.11 119.16,65.7 116.23,62.78 116.23,61.22 116.99,60.45 v1(116.99,59.03) ; v1(107.53,139.93) 107.53,137.78 103.67,133.92 103.67,106.8 108.87,101.6 v1(108.87,101.39)
  IN2 w0.127: v1(107.53,139.93) 80.22,139.93 76,135.7 72.55,135.7 71.34,134.5 v1(70.33,134.5)
  BOTTOM w0.102: v1(108.87,101.39) 102.71,101.39 101.44,100.12 101.44,96.83 101.88,96.39 101.88,70.78 104.17,68.49 104.17,67.35 109.25,62.27 114.83,62.27 116.99,60.11 v1(116.99,59.03) ; v1(119.35,70.3) 118.93,70.71 UC1.AV33
BT_ON#_R: length 3.3
  TOP w0.102: RW12.1 RW10.1 72.27,135.21 72.58,134.9 v1(72.58,134.8) 72.58,134.74 v2(72.91,134.41)
  BOTTOM w0.102: JWLAN1.54 v1(72.58,134.8)
CAM_DETECT#: length 109.9
  TOP w0.102: v1(210.73,42.03) R5.1 211.39,41.31 v2(211.17,41.09)
  IN1 w0.127: v1(153.45,39.68) 153.58,39.56 156.5,39.56 156.89,39.94 184.48,39.94 184.6,40.06 191.42,40.06 192.76,38.73 195.25,38.73 196.17,39.66 202.13,39.66 204.51,42.03 205.82,42.03 206.31,42.53 208.01,42.53 208.06,42.48 210.28,42.48 v1(210.73,42.03)
  IN2 w0.127: v1(149.46,58.53) 149.6,58.67 149.6,60.32 150.48,61.2 150.48,67.58 148.2,69.86 146.82,71.24 146.02,71.24 145.7,70.92 v1(145.7,70.61)
  BOTTOM w0.102: UC1.AJ1 136.75,75.29 138.47,75.29 140.88,72.87 141.7,72.87 142.22,72.35 142.58,72.35 142.78,72.15 143.25,72.15 143.73,71.67 RC34.1 144.55,71.67 145.61,70.61 v1(145.7,70.61) ; v1(153.45,39.68) 153.45,54.99 150.3,58.14 150.3,58.33 150.04,58.59 149.52,58.59 v1(149.46,58.53)
CAM_DETECT#_R: length 21.4
  TOP w0.102: R5.2 212.61,42.03 213.18,42.6 v2(213.74,42.6) 213.78,42.6 v1(214.79,43.62)
  IN2 w0.127: v1(214.79,43.62) 214.79,54.16 215.62,54.99 215.62,57.34 214.03,58.92 v1(213.33,58.92)
  BOTTOM w0.102: JEDP1.4 213.3,58.95 v1(213.33,58.92)
CAP_LED: length 28
  TOP w0.102: v1(60.56,26.45) 60.61,26.5 v4(60.61,27.55) R38.2
  BOTTOM w0.102: v1(60.56,26.45) 61.48,27.36 78.08,27.36 80.55,29.84 JKB1.27
CAP_LED#_Q: length 3.9
  TOP w0.254: R38.1 R36.2 v2(58.72,29.6) 58.14,29.01 Q11.1
CAP_LED#_R: length 5
  TOP w0.102: v2(53.11,29.98) Q11.2
  TOP w0.254: Q11.2 54.87,31.17 54.24,31.81 Q10.1
CAPS_LED#: length 59
  TOP w0.102: UE1.91 50.14,79.82 48.97,78.65 48.97,76.05 v1(49.24,75.78) ; Q10.3 v2(56.32,35.66)
  TOP w0.254: Q10.3 v1(57.41,33.92) 57.41,33.9 57.93,33.38 R39.1 R37.2
  IN1 w0.254: v1(57.41,33.92) 57.41,34.06 55.02,36.45 55.02,51.81 54.75,52.08 54.75,58.35 47.99,65.11 47.99,70.18 48.61,70.8 49.5,70.8 49.88,70.42 v1(50.01,70.42)
  BOTTOM w0.102: v1(49.24,75.78) 49.24,75.45 50.37,74.32 50.37,70.78 v1(50.01,70.42)
CBN: length 4
  TOP w0.203: UA1.28 v2(26.67,12.01) 26.21,12.01 25.5,11.3 CA496.2
CBP: length 4.5
  TOP w0.254: v1(25.75,10.42) 25.5,10.17 CA496.1 ; v1(28.48,10.79) 28.48,10.92 28.78,11.21 UA1.30
  BOTTOM w0.254: v1(28.48,10.79) 28.11,10.42 v1(25.75,10.42)
CCLIM: length 9.3
  TOP w0.254: PRB28.2 198.64,50.86 198.38,51.11 198.38,51.14 v1(198.36,51.14) 197.27,52.23 193.46,52.23 193.25,52.43 v2(193.25,52.55) 193.25,53.6 193.48,53.83 PRB27.2
  BOTTOM w0.203: v1(198.36,51.14) 198.28,51.14 197.99,50.84 PUB01.26
CLK_PCIE_N0: length 206.6
  TOP w0.102: UL1.16 26.94,87.01 27.13,86.82 27.32,86.82 27.89,87.38 28.75,87.38 28.85,87.49 28.85,87.69 28.75,87.79 v1(28.42,87.79)
  IN2 w0.127: v1(143.34,94.45) 143.34,94.46 143.66,94.78 143.66,97.46 140.1,101.02 140.1,102.26 129.26,113.11 129.26,115.65 125.49,119.41 125.49,122.11 110.02,137.57 80.24,137.57 77.1,134.44 77.1,129.45 75.22,127.57 66.26,127.57 63.84,125.15 33.78,125.15 28.16,119.53 28.16,97.34 26.83,96.01 26.83,87.88 27.31,87.4 28.61,87.4 28.74,87.52 28.74,87.7 28.65,87.79 v1(28.42,87.79)
  BOTTOM w0.102: v1(143.34,94.45) 143.35,94.45 143.72,94.08 143.72,93 145.69,91.03 145.69,87.14 144.86,86.3 141.68,86.3 140.28,84.9 137.61,84.9 137.52,84.81 137.15,84.81 136.98,84.98 136.83,84.98 136.66,84.81 136.22,84.81 UC1.M1
CLK_PCIE_N1: length 96.1
  IN2 w0.127: v1(81.38,133.41) 81.44,133.41 81.68,133.17 82.15,133.17 82.78,133.8 83.65,133.8 88.8,128.66 98.26,128.66 102,124.91 117.38,124.91 122.01,120.28 122.01,117.97 125.77,114.2 125.77,111.67 136.62,100.82 136.62,99.28 139.12,96.78 139.12,95.16 140.16,94.13 140.16,86.97 140.29,86.84 140.29,85.92 v1(140.45,85.76)
  BOTTOM w0.102: JWLAN1.49 79.59,133.55 79.73,133.4 80.85,133.4 81.02,133.23 81.2,133.23 v1(81.38,133.41) ; UC1.L1 136.54,85.4 136.84,85.4 136.95,85.51 137.82,85.51 138.74,86.43 140.03,86.43 140.25,86.21 140.25,85.95 v1(140.45,85.76)
CLK_PCIE_N2: length 228.1
  IN2 w0.102: 136.9,90.63 136.88,90.61 136.88,90.59 136.67,90.39 136.67,88.25 136.88,88.04 136.88,88.02 136.9,88
  IN2 w0.127: v1(137.35,86.83) 137.57,86.83 137.69,86.95 137.69,87.23 137.67,87.23 136.9,88 ; v1(26.39,35.43) 26.39,35.44 26.07,35.76 26.07,39.5 27.86,41.29 27.86,44.14 35.88,52.16 35.88,58.13 34.07,59.94 34.07,61.33 31.15,64.25 31.15,68.64 30.7,69.08 30.7,70.35 31.4,71.05 31.4,73.97 32.37,74.94 32.37,79.78 31.15,81 31.15,85.41 31.54,85.8 31.54,98.62 32.9,99.98 32.9,118.01 36.13,121.25 65.45,121.25 66.48,122.28 70.05,122.28 71.1,123.33 77.94,123.33 78.3,122.96 82.45,122.96 82.91,122.5 94.9,122.5 97.05,120.35 114.87,120.35 122.21,113.01 122.21,110.36 123.49,109.08 123.49,104.95 126.29,102.16 130.22,102.16 133.25,99.13 133.25,97.68 133.57,97.36 133.57,97.22 137.69,93.1 137.69,91.43 136.9,90.63
  BOTTOM w0.102: v1(137.35,86.83) 137.63,87.11 137.77,87.11 137.91,86.97 137.91,86.82 137.01,85.91 136.66,85.91 136.3,86.27 136.03,86.27 135.92,86.16 135.92,86.05 136.02,85.95 136.17,85.95 UC1.K1 ; v1(26.39,35.43) 26.2,35.24 26.2,35.1 26.38,34.92 JSSD1.53
CLK_PCIE_P0: length 206.6
  TOP w0.102: UL1.15 27.41,86.61 27.97,87.18 28.22,87.18 v1(28.42,86.98)
  IN2 w0.127: v1(28.42,86.98) 28.26,87.13 27.2,87.13 26.57,87.77 26.57,96.12 27.9,97.45 27.9,119.64 33.67,125.41 63.73,125.41 66.15,127.83 75.11,127.83 76.84,129.56 76.84,134.55 80.13,137.84 110.13,137.84 125.76,122.22 125.76,119.52 129.52,115.76 129.52,113.22 140.37,102.37 140.37,101.13 143.92,97.57 v1(143.92,94.45)
  BOTTOM w0.102: UC1.M2 136.1,84.55 136.31,84.55 136.37,84.61 137.61,84.61 137.69,84.7 140.36,84.7 141.77,86.1 144.94,86.1 145.89,87.05 145.89,91.12 143.92,93.09 v1(143.92,94.45)
CLK_PCIE_P1: length 96.1
  IN2 w0.127: v1(139.86,85.76) 140.02,85.92 140.02,86.73 139.9,86.86 139.9,94.02 138.86,95.06 138.86,96.67 136.36,99.17 136.36,100.71 125.51,111.56 125.51,114.09 121.75,117.86 121.75,120.17 117.27,124.65 101.9,124.65 98.15,128.39 88.69,128.39 83.54,133.54 82.89,133.54 82.26,132.9 81.45,132.9 v1(81.38,132.82)
  BOTTOM w0.102: v1(81.38,132.82) 81.17,133.03 80.93,133.03 80.76,133.2 79.77,133.2 79.62,133.05 JWLAN1.47 ; v1(139.86,85.76) 140.05,85.95 140.05,86.13 139.95,86.23 138.82,86.23 137.9,85.31 137.03,85.31 136.92,85.19 136.75,85.19 136.66,85.1 136.55,85.1 136.41,85.1 136.1,85.41 UC1.L2
CLK_PCIE_P2: length 228.1
  IN2 w0.102: 137.08,88.19 137.07,88.21 137.05,88.21 136.91,88.35 136.91,90.29 137.05,90.43 137.07,90.43 137.08,90.44
  IN2 w0.127: 137.08,90.44 137.96,91.32 137.96,93.21 133.84,97.33 133.84,97.47 133.52,97.79 133.52,99.24 130.33,102.42 126.4,102.42 123.75,105.06 123.75,109.18 122.47,110.47 122.47,113.12 114.98,120.61 97.16,120.61 95.01,122.76 83.02,122.76 82.56,123.22 78.41,123.22 78.05,123.59 70.99,123.59 69.94,122.54 66.38,122.54 65.34,121.51 36.02,121.51 32.63,118.12 32.63,100.09 31.28,98.73 31.28,85.91 30.89,85.52 30.89,80.89 32.1,79.67 32.1,75.04 31.14,74.08 31.14,71.16 30.44,70.46 30.44,68.97 30.88,68.53 30.88,64.14 33.81,61.22 33.81,59.83 35.62,58.02 35.62,52.27 27.59,44.24 27.59,41.4 25.8,39.61 v1(25.8,35.43) ; 137.08,88.19 137.96,87.32 v1(137.96,86.23)
  BOTTOM w0.102: v1(25.8,35.43) 26,35.23 26,35.04 25.87,34.92 JSSD1.55 ; v1(137.96,86.23) 137.61,86.23 137.09,85.71 136.37,85.71 136.31,85.65 136.01,85.65 135.71,85.96 UC1.K2
CLK_SMB: length 5.5
  TOP w0.102: PR42.1 160.05,40.01 159.36,39.31 v4(159.36,38.98) 159.36,38.51 v1(159.79,38.07)
  BOTTOM w0.102: v1(159.79,38.07) 159.79,38.08 159.79,38.54 160.19,38.93 160.57,38.93 160.95,39.31 PBATT1.7
CLKREQ_PCIE#0: length 156.6
  TOP w0.102: v1(38.08,81.7) 37.59,82.19 36.96,82.19 34.54,84.62 v2(34.54,85.82) 34.13,86.23 32.42,86.23 31.9,85.71 RC130.1 31.86,85.24 28.14,85.24 27.96,85.41 UL1.12
  IN2 w0.127: v1(117.88,61.14) 117.88,60.36 117.42,59.9 117.42,58.14 114.33,55.05 111.98,55.05 110.08,53.14 110.08,52.62 106.8,49.33 102.59,49.33 99.31,46.06 89.36,46.06 86.81,43.51 74.79,43.51 73.48,44.81 73.48,45.23 72.61,46.1 72.61,46.89 72.21,47.3 72.21,48.95 71.6,49.56 71.6,54.43 71.11,54.92 71.11,60.79 68.72,63.18 68.17,63.18 67.85,62.86 67.85,60.76 67.53,60.45 65.26,60.45 63.62,62.08 63.62,74.14 63.19,74.57 63.19,81.49 60.74,83.94 54.58,83.94 53.31,82.67 52.03,82.67 51.05,81.69 46.71,81.69 43.19,85.21 41.12,85.21 38.08,82.18 v1(38.08,81.7)
  BOTTOM w0.102: UC1.AY32 119.18,69.39 119.49,69.08 119.49,68.8 119.38,68.7 119.38,68.17 119.37,68.16 119.37,67.16 119.54,66.99 119.54,65.5 118.49,64.46 118.49,61.75 v1(117.88,61.14)
CLKREQ_PCIE#1: length 160.5
  TOP w0.102: v1(116.99,58.4) 114.11,58.4 112.78,57.06 RC36.1 ; v1(77.82,133.15) 78.01,133.15 78.28,132.89 RW5.1
  IN1 w0.127: v1(107.16,136.2) 106.65,136.2 104.11,133.66 104.11,107.44 110.08,101.47 v1(111.81,101.47)
  IN2 w0.127: v1(107.16,136.2) 106.84,136.52 80.97,136.52 79.62,135.17 77.82,133.37 v1(77.82,133.15)
  BOTTOM w0.102: v1(111.81,101.47) 111.79,101.47 111.36,101.89 102.71,101.89 101.13,100.31 101.13,96.57 101.56,96.13 101.56,70.52 103.19,68.9 103.19,67.69 108.99,61.89 113.82,61.89 116.55,59.16 116.55,58.84 v1(116.99,58.4) 117.63,59.03 117.63,59.79 118.76,60.92 118.76,64.16 119.84,65.24 119.84,67.03 120.15,67.34 120.15,68.03 120.11,68.07 120.11,68.07 120.08,68.11 120.08,68.7 119.73,69.05 UC1.AY31
CLKREQ_PCIE#1_R: length 2.8
  TOP w0.102: v2(77.36,134.04) v1(77.89,134.04) 78.47,134.04 RW5.2
  BOTTOM w0.102: JWLAN1.53 78.4,134.55 v1(77.89,134.04)
CLKREQ_PCIE#2: length 139.4
  TOP w0.102: RC35.1 119.69,58.59 v1(119.5,58.78) ; v1(26.96,27.74) v2(26.96,28.29)
  IN2 w0.102: 121.89,65.28 121.89,65.53 122.33,65.97
  IN2 w0.127: v1(112.42,53.95) 112.95,54.48 115.93,54.48 118.81,57.35 118.81,58.13 119.46,58.78 v1(119.5,58.78) 119.93,59.21 119.93,62.86 121.89,64.82 121.89,65.28 ; v1(26.96,30.86) v1(26.96,27.74) ; v1(121.32,71.08) 121.95,70.45 121.95,69.15 122.33,68.77 122.33,65.97
  BOTTOM w0.102: v1(26.96,27.74) 26.63,27.41 JSSD1.52 ; v1(112.42,53.95) 111.94,54.43 110.27,54.43 105.49,49.65 95.54,49.65 94.96,49.08 94.96,40.25 92.74,38.03 68.23,38.03 65.93,40.34 51.2,40.34 50.88,40.65 46.06,40.65 45.88,40.47 42.38,40.47 42.2,40.65 41.7,40.65 41.17,40.11 41.17,36.33 41.71,35.79 41.71,31.76 40.1,30.16 32.36,30.16 31.66,30.86 v1(26.96,30.86)
  BOTTOM w0.254: UC1.AV29 120.95,70.71 v1(121.32,71.08)
CLKRUN#: length 143.7
  TOP w0.102: RE12.1 42.36,66.04 v1(42.48,65.91) v2(43,65.91) ; v1(119.38,48.05) 119.38,47.82 121.86,45.33 125,45.33 v1(125.12,45.45)
  IN1 w0.127: v1(50.47,43.11) 50.37,43.21 50.37,53.74 42.48,61.62 v1(42.48,65.91)
  IN2 w0.127: v1(50.47,43.11) 50.63,43.27 53.88,43.27 62.61,34.55 67.09,34.55 67.48,34.15 102.14,34.15 103.22,35.24 103.22,35.64 103.48,35.9 104.05,35.9 104.61,35.34 110.59,35.34 111.89,36.64 112.98,36.64 113.16,36.46 116.3,36.46 116.6,36.76 119.71,36.76 121.86,38.91 121.86,42.17 125.12,45.43 v1(125.12,45.45) ; v1(122.29,58.46) 121.11,57.27 121.11,56.78 120.07,55.74 120.07,55.33 119.36,54.62 119.36,48.06 v1(119.38,48.05)
  BOTTOM w0.102: UC1.AY26 122.48,69.4 122.8,69.09 122.8,68.82 122.72,68.74 122.72,66.67 122.78,66.61 122.78,63.42 122.65,63.29 122.65,61.82 122.33,61.51 122.33,59.79 122.31,59.77 122.31,58.54 122.29,58.52 v1(122.29,58.46)
CLKRUN#_R: length 3.7
  TOP w0.102: UE1.38 39.33,66.93 40.23,66.04 RE12.2 40.72,65.29 v2(40.97,65.04)
CMSRC: length 41.2
  TOP w0.102: v1(194.92,46.48) v2(194.92,47.75)
  TOP w0.508: v1(181.9,67.56) 181.83,67.5 PRB08.2
  IN1 w0.457: 194.98,46.48 v1(194.92,46.48) ; 192.36,63.03 191.98,63.03 190.57,64.44 185.02,64.44 v1(181.9,67.56)
  IN1 w0.508: 192.36,63.03 192.99,62.4 192.99,59.2 193.96,58.22 197.53,58.22 198.66,57.09 198.66,54.86 199,54.52 199,47.33 197.58,45.91 195.55,45.91 194.98,46.48
  BOTTOM w0.203: v1(194.92,46.48) 195.1,46.66 PUB01.5
COMP: length 3.5
  TOP w0.127: v1(198.31,50.02) v2(197.67,50.02)
  TOP w0.254: PRB30.1 198.94,49.1 198.31,49.74 v1(198.31,50.02)
  BOTTOM w0.203: 198.33,50.02 198.31,50.04 PUB01.28 ; 198.33,50.02 198.35,50.04 198.7,50.04 198.78,49.97 PCB12.1 ; 198.33,50.02 v1(198.31,50.02)
CORE_NB_GATE: length 34.3
  IN1 w0.127: v1(128.56,42.48) 129.07,42.98 131.48,42.98 131.59,43.09 138.51,43.09 140.24,44.83 v1(140.31,44.83)
  BOTTOM w0.102: R54.1 143.87,39.17 U5.1 ; R54.1 142.59,40.43 142.59,39.68 142.97,39.3 142.97,36.95 142.66,36.63 U5.6 ; R54.1 142.6,40.75 142.27,41.08 141.7,41.08 141.13,41.65 141.13,44 v2(140.86,44.27) v1(140.31,44.83) ; Q19.2 133.49,41.27 129.23,41.27 Q18.2 129.01,42.03 v1(128.56,42.48)
CORETYPE: length 27.5
  TOP w0.102: v1(153.26,80.07) v2(154.31,80.07)
  IN1 w0.102: v1(132.28,89.39) 132.3,89.4 134.15,89.4 134.25,89.29 139.08,89.29 139.88,88.5
  IN1 w0.127: 139.88,88.5 145.64,82.74 145.7,82.74 145.83,82.61 148.18,82.61 150.15,80.64 152.69,80.64 v1(153.26,80.07)
  BOTTOM w0.102: UC1.D9 131.83,89.11 132.11,89.39 v1(132.28,89.39) ; RC22.2 153.27,80.08 v1(153.26,80.07)
CPVEE: length 5.3
  TOP w0.203: UA1.27 28.2,12.41 28.18,12.39 v2(27.91,12.39) 25.89,12.39 25.22,11.72 24.84,11.72 CA25.1
CS_1.2V: length 4.5
  BOTTOM w0.102: v2(67,109.69) PRM03.1
  BOTTOM w0.203: PRM03.1 66.81,110.7 66.52,110.99 66.52,111.86 66.28,112.1 66.28,112.44 65.82,112.9 PUM01.13
CSIN_CHG: length 3.7
  BOTTOM w0.203: PUB01.14 192.73,50.44 192.29,50.88 PCB05.1
  BOTTOM w0.254: PRB12.2 191.37,51.75 PCB03.2 191.42,50.9 PCB05.1
CSIP_CHG: length 6
  TOP w0.102: v1(189.9,53.27) 189.9,53.3 190.24,53.64 v2(190.24,53.7)
  TOP w0.254: PCB04.1 189.87,53.25 v1(189.9,53.27)
  BOTTOM w0.203: PCB03.1 192.01,52.13 192.01,51.61 192.77,50.84 PUB01.15
  BOTTOM w0.254: v1(189.9,53.27) 189.98,53.27 190.25,52.99 190.25,52.97 190.59,52.64 PRB11.2 190.66,52.69 191.02,52.69 191.04,52.71 PCB03.1
CSON: length 4.4
  BOTTOM w0.203: PCB15.2 197.85,46.29 v2(197.39,46.74) 197.32,46.74 196.7,47.36 PUB01.1
  BOTTOM w0.254: PCB15.2 197.87,45.75 PCB16.1 197.87,44.31 PRB37.1
CSON_R: length 32.2
  BOTTOM w0.254: PRB01.3 170.77,48.12 171.04,48.38 171.74,48.38 171.99,48.13 171.99,45.72 173.45,44.25 183.42,44.25 183.84,43.84 186.94,43.84 189.05,41.73 190.57,41.73 v2(190.93,42.08) 191.26,42.41 197.07,42.41 197.58,42.92 PRB37.2
CSOP: length 5.4
  BOTTOM w0.102: PRB36.1 196.16,43.42 v2(195.82,43.42)
  BOTTOM w0.203: PUB01.2 196.3,47.26 196.6,46.95 196.6,46.67 196.93,46.34 PCB15.1
  BOTTOM w0.254: PCB15.1 197.01,45.7 PCB17.1 197.01,44.27 PRB36.1
CSOP_R: length 31.1
  BOTTOM w0.254: PRB36.2 196.43,42.77 191.02,42.77 190.33,42.08 189.19,42.08 187.08,44.19 184.12,44.19 v2(183.91,44.4) 183.7,44.61 173.73,44.61 172.41,45.93 172.41,48.34 172.02,48.74 170.98,48.74 170.77,48.94 PRB01.2
DAT_SMB: length 5.3
  TOP w0.102: v4(163.17,37.43) v1(163.87,38.12) 163.88,38.13 163.88,39.49 PR37.1
  BOTTOM w0.102: v1(163.87,38.12) 163.87,38.53 162.95,39.45 PBATT1.6
DBC_EN: length 215.2
  TOP w0.102: UE1.89 50.11,79.02 49.38,78.29 v1(49.38,76.36) ; v1(211.17,47.93) 210.25,48.85 v2(210.25,54.11) 210.25,54.64 210.65,55.04 RV8.2
  IN1 w0.127: v1(49.38,76.36) 49.49,76.47 50.36,76.47 50.49,76.35 50.49,73.27 51.79,71.97 51.79,70.67 52.56,69.9 52.56,68.94 53.69,67.81 53.69,66.14 58.32,61.51 58.32,53.5 60.46,51.36 60.46,43.54 62.48,41.52 62.85,41.52 64.74,39.63 64.74,38.37 65.69,37.42 66.77,37.42 68.48,35.71 86.22,35.71 90.5,31.43 118.82,31.43 119.12,31.13 123.03,31.13 123.49,31.59 129.39,31.59 130.31,32.51 135.79,32.51 137.14,33.85 143.22,33.85 150.66,41.3 157.35,41.3 158.92,42.87 181.34,42.87 181.7,43.24 189.36,43.24 189.78,43.66 190.81,43.66 192.21,42.26 197.42,42.26 198.65,43.49 202.18,43.49 203.19,44.51 204,44.51 206.6,47.11 210.35,47.11 v1(211.17,47.93)
DBC_EN_R: length 3.7
  TOP w0.102: v1(213.33,55.56) v2(212.51,55.56) RV8.1 RV10.1
  BOTTOM w0.102: v1(213.33,55.56) 213.22,55.45 JEDP1.11
DCIN_CHG: length 2.7
  BOTTOM w0.102: 190.29,54.45 190.29,54.63 191.92,56.26 v2(192.1,56.26)
DDR_A_ACT#: length 55.6
  IN1 w0.102: 110.67,92.9 112.29,91.27 112.29,89.98 115.53,86.74 115.83,86.74 116.02,86.55 117.21,86.55 v1(117.79,85.97)
  IN1 w0.211: v1(73.01,84.4) 73.06,84.4 73.57,84.91 74.87,84.91 75.38,85.42 75.63,85.42 75.65,85.43 76.44,85.43 76.71,85.7 76.71,86.82 77.09,87.2 77.58,87.2 78.43,88.05 80.46,88.05 85.5,93.09 110.48,93.09 110.67,92.9
  BOTTOM w0.102: v1(117.79,85.97) 117.63,85.8 UC1.L35 ; JDIMM1.114 72.6,83.99 v1(73.01,84.4)
DDR_A_ADD0: length 48.6
  IN1 w0.102: v1(116.3,77.16) 116.07,77.16 115.87,76.95 115.01,76.95 113.65,75.59 110.67,75.59
  IN1 w0.211: v1(73.09,77.12) 73.09,76.46 74.42,75.12 81.04,75.12 81.34,74.83 86.87,74.83 87.63,75.59 107.61,75.59 110.67,75.59
  BOTTOM w0.102: v1(73.09,77.12) 72.45,76.49 JDIMM1.144 ; UC1.AG38 116.3,76.87 v1(116.3,77.16)
DDR_A_ADD1: length 51.7
  IN1 w0.102: 110.67,82.36 113.86,82.36 114.28,81.94 117.45,81.94 v1(117.83,81.56)
  IN1 w0.211: v1(80.79,80.15) 80.79,80.51 80.57,80.72 80.18,80.72 79.63,80.18 79.63,79.9 79.84,79.69 84.75,79.69 86.04,80.99 86.04,82.02 86.26,82.23 87.28,82.23 88.49,83.43 101.82,83.43 102.67,82.58 102.97,82.58 103.18,82.8 103.18,83.91 103.39,84.12 103.81,84.12 104.02,83.91 104.02,82.57 104.23,82.36 104.64,82.36 104.85,82.57 104.85,83.91 105.06,84.12 105.48,84.12 105.7,83.91 105.7,82.58 105.91,82.36 110.67,82.36
  BOTTOM w0.102: v1(80.79,80.15) 79.87,79.24 JDIMM1.133 ; v1(117.83,81.56) 117.63,81.36 UC1.W35
DDR_A_ADD2: length 48.7
  IN1 w0.102: v1(116.23,81.56) 115.75,81.07 114.16,81.07 113.29,81.94 111.07,81.94 110.98,81.84 110.67,81.84
  IN1 w0.211: 110.67,81.84 102.68,81.84 101.98,82.55 88.62,82.55 85.25,79.18 74.88,79.18 74.35,79.7 73.03,79.7 v1(72.58,79.25)
  BOTTOM w0.102: UC1.W38 116.23,81.21 v1(116.23,81.56) ; JDIMM1.132 72.34,79.49 v1(72.58,79.25)
DDR_A_ADD3: length 52.3
  IN1 w0.102: 110.67,83.51 110.67,83.52 113.23,83.52 114.61,82.14 117.53,82.14 117.64,82.04 118.15,82.04 v1(118.63,81.56)
  IN1 w0.211: v1(82.23,80.15) 82.07,80.32 82.07,80.66 82.28,80.87 82.58,80.87 82.79,80.66 82.79,80.45 83,80.24 83.36,80.24 83.57,80.45 83.57,80.78 83.75,80.97 84.06,80.97 84.52,80.51 84.82,80.51 85.12,80.81 85.12,81.17 84.7,81.58 84.7,81.88 84.9,82.07 85.36,82.07 85.57,82.28 85.57,82.72 86,83.15 86.3,83.15 86.65,82.8 86.95,82.8 87.31,83.17 87.31,83.47 87,83.78 87,84.08 87.56,84.64 98.72,84.64 98.97,84.39 99.48,84.39 99.73,84.64 101.13,84.64 101.51,84.26 102.8,84.26 103.17,84.64 105.99,84.64 106.26,84.37 106.26,83.69 106.47,83.48 106.74,83.48 106.95,83.27 106.95,83.08 107.16,82.87 107.59,82.87 107.8,83.08 107.8,83.27 108.01,83.48 108.4,83.48 108.61,83.27 108.61,83.08 108.82,82.87 109.16,82.87 109.37,83.08 109.37,83.27 109.62,83.51 110.67,83.51
  BOTTOM w0.102: JDIMM1.131 79.83,79.74 81.09,81 82.64,81 82.74,80.9 82.74,80.47 82.43,80.15 v1(82.23,80.15) ; UC1.W34 118.43,81.36 v1(118.63,81.56)
DDR_A_ADD4: length 49.6
  IN1 w0.102: v1(116.23,82.66) 115.92,82.97 114.55,82.97 113.49,84.03 110.67,84.03
  IN1 w0.211: 110.67,84.03 107.41,84.03 106.28,85.15 86.9,85.15 83.25,81.51 80.23,81.51 78.94,80.22 74.73,80.22 v1(74.22,80.73)
  BOTTOM w0.102: v1(74.22,80.73) 74.22,80.73 74.2,80.73 73.65,80.17 72.32,80.17 72,80.49 JDIMM1.128 ; UC1.U38 116.23,82.31 v1(116.23,82.66)
DDR_A_ADD5: length 50.4
  IN1 w0.102: v1(117.03,82.66) 116.52,83.17 114.63,83.17 113.26,84.55 110.67,84.55
  IN1 w0.211: 110.67,84.55 107.82,84.55 106.7,85.67 86.68,85.67 83.04,82.02 80.02,82.02 79.25,81.26 79.19,81.26 79.15,81.22 74.39,81.22 74.38,81.22 73.79,81.22 v1(73.34,80.77)
  BOTTOM w0.102: v1(73.34,80.77) 72.98,80.41 72.46,80.41 71.89,80.99 JDIMM1.126 ; UC1.U37 116.83,82.46 v1(117.03,82.66)
DDR_A_ADD6: length 51.9
  IN1 w0.102: 110.67,86.18 111.43,86.18 111.87,85.74 111.87,84.94 112.07,84.75 113.15,84.75 113.62,85.21 113.77,85.21 114.07,84.91 114.07,84.76 113.86,84.54 113.86,84.4 114.16,84.1 114.3,84.1 114.51,84.31 114.67,84.31 115.03,83.95 115.03,83.81 114.84,83.62 114.84,83.48 114.94,83.38 116.75,83.38 117.08,83.04 118.07,83.04 118.39,83.37 118.97,83.37 119.1,83.24 119.1,82.89 118.87,82.66 v1(118.62,82.66)
  IN1 w0.211: 110.67,86.18 105.79,86.18 105.58,86.4 105.58,86.86 105.26,87.18 104.6,87.18 104.25,86.84 104.25,86.4 104.04,86.18 93.19,86.18 92.8,86.58 92.05,86.58 91.65,86.18 90.27,86.18 89.87,86.58 89.25,86.58 88.86,86.18 87.98,86.18 87.59,86.58 87.22,86.58 86.83,86.18 85.97,86.18 85.76,85.97 85.76,85.48 85.5,85.21 85.02,85.21 84.81,85 84.81,84.52 84.57,84.29 83.95,84.29 83.79,84.13 83.79,83.51 83.49,83.21 82.87,83.21 82.64,82.98 82.64,82.68 v1(82.8,82.52)
  BOTTOM w0.102: JDIMM1.127 79.82,80.74 80.28,81.2 82.7,81.2 82.8,81.3 v1(82.8,82.52) ; UC1.U34 118.43,82.47 v1(118.62,82.66)
DDR_A_ADD7: length 53
  IN1 w0.102: 110.67,87.22 111.46,87.22 112.42,86.25 113.3,86.25 115.21,84.34 115.77,84.34 115.98,84.14 117.45,84.14 v1(117.83,83.76)
  IN1 w0.211: 110.67,87.22 108.4,87.22 107.21,88.41 104.13,88.41 103.33,87.61 85.48,87.61 81.28,83.41 80.9,83.41 80.27,82.78 80.04,82.78 79,81.74 74.6,81.74 74.06,82.27 73.15,82.27 v1(72.58,82.84)
  BOTTOM w0.102: v1(72.58,82.84) 71.73,81.99 JDIMM1.122 ; UC1.R35 117.63,83.56 v1(117.83,83.76)
DDR_A_ADD8: length 51.9
  IN1 w0.102: v1(116.23,83.76) 116.01,83.76 115.63,84.14 115.13,84.14 113.28,85.99 112.13,85.99 111.42,86.7 110.67,86.7
  IN1 w0.211: 110.67,86.7 107.75,86.7 107.54,86.91 107.54,87.35 107.32,87.56 107.02,87.56 106.81,87.35 106.81,86.91 106.6,86.7 106.3,86.7 106.09,86.91 106.09,87.68 105.88,87.89 104.34,87.89 103.74,87.29 103.74,86.9 103.54,86.7 103.54,86.7 103.07,86.7 102.7,87.06 102.41,87.06 102.04,86.7 101.61,86.7 101.24,87.06 100.95,87.06 100.61,86.73 100.25,86.73 99.88,87.09 99.58,87.09 99.19,86.7 98.65,86.7 98.27,87.08 98.27,87.09 97.89,87.09 97.49,86.7 97.03,86.7 96.67,87.06 96.37,87.06 96.01,86.7 95,86.7 94.61,87.09 94.24,87.09 93.85,86.7 93.4,86.7 93.01,87.09 91.83,87.09 91.44,86.7 90.53,86.7 90.14,87.09 89.04,87.09 88.65,86.7 88.2,86.7 87.8,87.09 86.03,87.09 83.27,84.34 83.27,83.94 83.06,83.73 82.66,83.73 81.47,82.54 v1(81.47,82.52)
  BOTTOM w0.102: v1(116.23,83.76) 116.23,83.41 UC1.R38 ; v1(81.47,82.52) 81.47,83.09 81.33,83.24 80.54,83.24 80.39,83.09 80.39,82.08 80.49,81.98 81.77,81.98 81.92,81.84 81.92,81.55 81.77,81.4 80.19,81.4 80.03,81.24 JDIMM1.125
DDR_A_ADD9: length 52.2
  IN1 w0.102: v1(116.16,84.85) 116.15,84.85 115.63,85.37 114.94,85.37 113.53,86.78 112.74,86.78 111.26,88.26 110.67,88.26
  IN1 w0.211: v1(77.53,82.78) 77.46,82.85 77.46,83.15 78.3,83.99 78.6,83.99 78.83,83.76 79.12,83.76 79.42,84.06 79.42,84.36 79.2,84.59 79.2,84.88 79.56,85.25 81.32,85.25 86.08,90.01 86.52,90.01 87.09,89.44 87.51,89.44 88.08,90.01 88.45,90.01 89.03,89.44 89.54,89.44 90.12,90.01 90.55,90.01 91.12,89.44 91.76,89.44 92.34,90.01 92.7,90.01 93.28,89.44 93.67,89.44 94.24,90.01 94.67,90.01 95.22,89.47 95.6,89.47 96.15,90.01 96.77,90.01 96.94,89.84 96.94,89.84 97.32,89.47 97.63,89.47 98.01,89.84 107.26,89.84 107.6,89.51 107.6,89.48 108.83,88.25 110.65,88.25 110.67,88.26
  BOTTOM w0.102: UC1.N38 116.03,84.6 116.16,84.72 v1(116.16,84.85) ; JDIMM1.121 77.25,82.24 77.1,82.38 77.1,83.11 77.25,83.25 77.53,83.25 77.63,83.16 77.63,82.87 v1(77.53,82.78)
DDR_A_ADD10: length 51.2
  IN1 w0.102: 110.67,73.56 112.79,73.56 113.79,74.56 113.79,74.97 115.37,76.55 117.6,76.55 v1(118.2,77.15)
  IN1 w0.211: v1(72.42,74.23) 72.42,74.71 72.63,74.93 73.89,74.93 75.02,73.79 78.33,73.79 78.63,74.09 80.62,74.09 80.91,73.79 87.36,73.79 87.51,73.95 106.7,73.95 107.08,73.56 110.67,73.56
  BOTTOM w0.102: v1(72.42,74.23) 72.19,73.99 JDIMM1.146 ; UC1.AG34 118.43,76.92 v1(118.2,77.15)
DDR_A_ADD11: length 53.9
  IN1 w0.102: 110.67,87.73 111.35,87.73 112.57,86.52 113.32,86.52 115.3,84.54 115.86,84.54 116.06,84.34 117.83,84.34 118.42,83.75 v1(118.59,83.75)
  IN1 w0.211: v1(74.17,82.78) 74.35,82.78 74.88,82.25 78.34,82.25 80.33,84.24 81.03,84.24 85.72,88.92 107.42,88.92 108.61,87.73 110.67,87.73
  BOTTOM w0.102: UC1.R34 118.43,83.58 v1(118.59,83.75) ; v1(74.17,82.78) 73.72,83.22 72.42,83.22 71.69,82.49 JDIMM1.120
DDR_A_ADD12: length 52.5
  IN1 w0.102: 110.67,89.17 112.19,89.17 114.17,87.19 114.17,86.49 115.09,85.58 115.71,85.58 116.01,85.28 117.02,85.28 117.12,85.18 117.12,84.95 v1(117.03,84.86)
  IN1 w0.211: v1(75.87,82.72) 75.87,83.32 76.39,83.84 77.42,83.84 80.02,86.44 81.39,86.44 85.49,90.53 108.36,90.53 109.72,89.17 110.67,89.17
  BOTTOM w0.102: v1(117.03,84.86) 116.83,84.66 UC1.N37 ; JDIMM1.119 78.43,82.74 77.46,83.71 77.28,83.71
  BOTTOM w0.163: 77.28,83.71 76.85,83.71 v1(75.87,82.72)
DDR_A_ADD13: length 57.6
  IN1 w0.102: 110.67,67.09 111.4,67.09 111.45,67.03 112.09,67.03 112.94,67.88 112.94,68.19 114.35,69.6 114.35,70.74 115.11,71.5 115.11,72.87 115.42,73.18 115.74,73.18 115.98,72.94 115.98,72.65 116.2,72.43 116.75,72.43 v1(117.16,72.84)
  IN1 w0.211: 110.67,67.09 95.06,67.09 94.6,67.54 90.3,67.54 87.73,64.97 87.73,64.96 87.09,64.32 81.11,64.32 79.57,65.87 79.57,68.48 77.94,70.11 73.29,70.11 v1(72.96,70.44)
  BOTTOM w0.102: v1(72.96,70.44) 72.41,70.99 JDIMM1.158 ; v1(117.16,72.84) UC1.AN35
DDR_A_BA0: length 48.8
  IN1 w0.102: 110.67,73.05 112.57,73.05 113.99,74.47 113.99,74.88 114.86,75.76 115.93,75.76 v1(116.23,76.06)
  IN1 w0.211: v1(74.49,72.74) 74.47,72.76 74.47,73.07 74.68,73.28 74.9,73.28 75.15,73.02 75.3,73.02 75.56,73.28 78.54,73.28 78.84,73.58 80.4,73.58 80.7,73.28 88.05,73.28 88.2,73.43 106.48,73.43 106.87,73.05 110.67,73.05
  BOTTOM w0.102: 73.98,73.11 73.91,73.17 72.61,73.17 72.42,72.99 JDIMM1.150 ; v1(116.23,76.06) 116.23,75.71 UC1.AJ38
  BOTTOM w0.163: 73.98,73.11 74.21,73.11 74.49,72.83 v1(74.49,72.74)
DDR_A_BA1: length 51.7
  IN1 w0.102: 110.67,75.07 110.93,75.07 111.03,74.97 111.03,74.62 111.13,74.51 111.63,74.51 111.73,74.62 111.73,75.28 111.83,75.38 112.35,75.38 112.56,75.18 112.56,74.93 112.68,74.8 113.27,74.8 115.22,76.75 117.51,76.75 117.62,76.85 v1(117.62,77.15)
  IN1 w0.211: 110.67,75.07 110.33,75.07 109.93,74.67 109.51,74.67 109.11,75.07 108.7,75.07 108.49,74.86 108.49,74.29 108.28,74.08 107.69,74.08 107.48,74.29 107.48,74.86 107.27,75.07 106.54,75.07 106.33,74.86 106.33,74.67 106.12,74.46 105.89,74.46 105.28,75.07 104.75,75.07 104.14,74.46 103.75,74.46 103.18,75.03 102.82,75.03 102.25,74.46 101.91,74.46 101.34,75.03 101.04,75.03 100.47,74.46 100.06,74.46 99.49,75.03 99.14,75.03 98.58,74.47 98.28,74.47 97.72,75.03 97.36,75.03 96.79,74.46 96.38,74.46 95.78,75.06 95.48,75.06 94.88,74.46 94.48,74.46 93.91,75.03 93.49,75.03 92.92,74.46 92.44,74.46 91.87,75.03 91.52,75.03 90.95,74.46 90.41,74.46 89.85,75.03 89.55,75.03 88.98,74.46 88.57,74.46 88.05,74.98 87.75,74.98 87.08,74.31 81.13,74.31 80.83,74.61 78.07,74.61 v1(77.78,74.32)
  BOTTOM w0.102: v1(77.78,74.32) 77.86,74.24 JDIMM1.145 ; v1(117.62,77.15) 117.63,77.14 UC1.AG35
DDR_A_BG0: length 51.9
  IN1 w0.102: 110.67,89.77 110.75,89.69 111.96,89.69 114.43,87.22 114.43,87 115.09,86.34 115.66,86.34 115.85,86.15 115.85,86.12 115.85,86.11 115.85,85.8 115.85,85.8 115.85,85.73 116.1,85.48 118.19,85.48 118.56,85.11 v1(118.56,84.86)
  IN1 w0.211: v1(77.15,84.3) 77.76,84.9 77.76,85.84 78.87,86.95 81,86.95 85.57,91.52 87.68,91.52 88.16,91.99 89.41,91.99 89.89,91.52 93.21,91.52 93.68,91.99 94.46,91.99 95.17,91.28 95.96,91.28 95.98,91.31 108.31,91.31 109.84,89.77 110.67,89.77
  BOTTOM w0.102: 77.28,84.17 77.71,83.74 JDIMM1.115 ; UC1.N34 118.43,84.73 v1(118.56,84.86)
  BOTTOM w0.163: 77.28,84.17 v1(77.15,84.3)
DDR_A_BG1: length 53.3
  IN1 w0.102: 110.67,90.29 111.65,90.29 115.39,86.54 115.74,86.54 116.23,86.05 v1(116.23,85.96)
  IN1 w0.211: 110.67,90.29 110.46,90.49 110.46,90.49 110.25,90.7 110.25,91 108.68,92.57 85.71,92.57 80.67,87.53 78.71,87.53 78.55,87.37 78.55,87.36 77.22,86.03 77.22,85.48 76.65,84.91 75.86,84.91 75.85,84.9 75.59,84.9 v1(75.06,84.36)
  BOTTOM w0.102: v1(116.23,85.96) 116.23,85.61 UC1.L38 ; JDIMM1.113 78.21,84.24 77.5,84.95 75.4,84.95 75.06,84.61 v1(75.06,84.36)
DDR_A_CAS#: length 55.2
  IN1 w0.102: v1(115.53,73.78) 115.23,73.78 114.91,73.46 114.91,71.61 114.15,70.85 114.15,69.68 112.32,67.85 110.67,67.85
  IN1 w0.211: v1(73.09,71.54) 73.09,71.09 73.55,70.62 78.22,70.62 80.79,68.06 80.79,67.82 83.02,65.58 87.21,65.58 89,67.37 89,68.26 89.63,68.89 98.72,68.89 100.01,67.6 110.07,67.6 110.32,67.85 110.67,67.85
  BOTTOM w0.102: v1(115.53,73.78) 115.56,73.78 UC1.AN38 ; JDIMM1.156 71.74,71.49 72.04,71.19 72.74,71.19 v1(73.09,71.54)
DDR_A_CKE0: length 52.3
  IN1 w0.102: 110.67,93.57 112.5,91.74 112.5,90.36 115.08,87.78 115.58,87.78 v1(116.42,86.93)
  IN1 w0.211: 110.67,93.57 110.26,93.98 93.95,93.98 93.54,94.39 86.07,94.39 80.24,88.56 78.07,88.56 77.85,88.35 77.4,88.35 76.14,87.08 v1(76.14,85.91)
  BOTTOM w0.102: v1(76.14,85.91) 76.5,85.54 77.62,85.54 77.92,85.24 JDIMM1.109 ; UC1.J38 116.42,86.9 v1(116.42,86.93)
DDR_A_CKE1: length 57.3
  IN1 w0.102: v1(118.3,87.05) 117.94,87.42 117.51,87.42 116.19,88.74 115.86,88.74 114.6,90 114.6,91.82 113.13,93.29 113.13,93.61 112.25,94.49 111.92,94.49
  IN1 w0.211: 111.92,94.49 110.59,95.82 96.11,95.82 95.98,95.69 85.31,95.69 79.33,89.7 76.99,89.7 73.11,85.83 v1(72.99,85.83)
  BOTTOM w0.102: v1(118.3,87.05) 118.43,86.92 UC1.J34 ; 72.35,85.19 72.15,84.99 JDIMM1.110
  BOTTOM w0.163: 72.35,85.19 v1(72.99,85.83)
DDR_A_CLK0: length 57.3
  IN1 w0.102: 110.67,80 114.72,80 114.92,79.8 118.04,79.8 118.18,79.65 118.18,79.46 118.08,79.36 v1(117.83,79.36)
  IN1 w0.211: 110.67,80 103.38,80 103.17,79.79 103.17,78.59 102.73,78.16 101.56,78.16 101.13,78.59 101.13,79.79 100.92,80 99.82,80 99.61,79.79 99.61,78.34 99.17,77.9 97.94,77.9 97.51,78.34 97.51,79.79 97.3,80 96.33,80 96.12,79.79 96.12,78.26 95.68,77.82 94.52,77.82 94.08,78.26 94.08,79.79 93.87,80 92.76,80 92.55,79.79 92.55,78.26 92.12,77.82 90.83,77.82 90.39,78.26 90.39,79.78 90.17,80 88.71,80 86.15,77.44 83.19,77.44 82.96,77.21 v1(82.96,76.95)
  BOTTOM w0.102: JDIMM1.137 80.15,78.24 80.15,78.24 82.28,78.24 82.8,77.71 82.8,77.1 v1(82.96,76.95) ; v1(117.83,79.36) 117.83,79.44 117.93,79.54 118.15,79.54 118.25,79.44 118.25,79.15 117.84,78.74 117.7,78.74 UC1.AC35
DDR_A_CLK1: length 54.4
  IN1 w0.102: v1(118.63,80.46) 118.63,80.52 118.73,80.62 118.91,80.62 119.01,80.52 119.01,79.05 118.9,78.93 114.15,78.93 113.23,78.02 111.25,78.02 111.15,78.12 111.15,78.14 110.96,78.33 110.96,78.41 110.94,78.43
  IN1 w0.211: 110.94,78.43 110.82,78.55 106.6,78.55 104.94,76.9 87.06,76.9 86.29,76.14 81.88,76.14 81.59,76.43 75.25,76.43 75.05,76.64 75.05,76.73 75.05,77 v1(75.19,77.15)
  BOTTOM w0.102: v1(118.63,80.46) 118.76,80.46 118.91,80.3 118.91,80.06 118.67,79.82 118.52,79.82 UC1.AA34 ; v1(75.19,77.15) 74.99,77.34 74.99,77.58 74.58,77.99 JDIMM1.138
DDR_A_CLK#0: length 57.4
  IN1 w0.102: v1(118.63,79.36) 118.46,79.53 118.46,79.76 118.15,80.08 115.04,80.08 114.84,80.28 110.86,80.28 110.81,80.33 110.74,80.33 110.68,80.39 110.67,80.39
  IN1 w0.211: 110.67,80.39 103.22,80.39 102.78,79.95 102.78,78.76 102.57,78.54 101.73,78.54 101.51,78.76 101.51,79.95 101.08,80.39 99.66,80.39 99.22,79.95 99.22,78.5 99.01,78.29 98.11,78.29 97.9,78.5 97.9,79.95 97.46,80.39 96.17,80.39 95.73,79.95 95.73,78.42 95.52,78.21 94.68,78.21 94.47,78.42 94.47,79.95 94.03,80.39 92.6,80.39 92.16,79.95 92.16,78.42 91.95,78.21 90.99,78.21 90.78,78.42 90.78,79.94 90.33,80.39 88.55,80.39 85.99,77.82 82.93,77.82 v1(82.09,76.98)
  BOTTOM w0.102: JDIMM1.139 79.93,77.74 80.19,78 82.18,78 82.55,77.63 82.55,77.08 82.45,76.98 v1(82.09,76.98) ; UC1.AC34 118.58,78.96 118.58,79.31 v1(118.63,79.36)
DDR_A_CLK#1: length 54.4
  IN1 w0.102: v1(119.43,80.46) 119.29,80.32 119.29,78.93 119.01,78.65 114.26,78.65 113.35,77.74 111.14,77.74 110.87,78 110.87,78.03 110.76,78.14 110.69,78.14 110.67,78.16
  IN1 w0.211: v1(74.31,77.13) 74.66,76.79 74.66,76.48 75.09,76.05 81.42,76.05 81.72,75.75 86.45,75.75 87.22,76.51 105.1,76.51 106.76,78.16 110.66,78.16 110.67,78.16
  BOTTOM w0.102: JDIMM1.140 71.95,77.49 72.21,77.75 74.48,77.75 74.76,77.48 74.76,77.23 74.66,77.13 v1(74.31,77.13) ; v1(119.43,80.46) 119.23,80.26 UC1.AA32
DDR_A_CS0#: length 57.6
  IN1 w0.102: v1(117.78,74.96) 117.78,74.87 117.44,74.52 116.12,74.52 116.06,74.59 114.96,74.59 114.6,74.23 114.6,74.22 114.3,73.92 114.3,71.87 112.49,70.06
  IN1 w0.211: v1(75.76,71.6) 75.76,71.38 76,71.14 78.15,71.14 78.75,71.73 82.17,71.73 82.38,71.52 82.38,69.25 82.59,69.04 83.07,69.04 83.28,69.25 83.28,71.52 83.49,71.73 87.14,71.73 87.35,71.52 87.35,71.01 87.56,70.8 88.09,70.8 88.3,71.01 88.3,71.52 88.51,71.73 88.89,71.73 89.88,70.74 101.99,70.74 102.4,70.33 111.53,70.33 111.8,70.06 112.49,70.06
  BOTTOM w0.102: UC1.AL35 117.63,74.76 117.77,74.89 117.77,74.94 v1(117.78,74.96) ; JDIMM1.149 77.4,73.24 v1(75.76,71.6)
DDR_A_CS1#: length 57.7
  IN1 w0.102: 110.67,68.37 112.54,68.37 113.94,69.76 113.94,70.94 114.71,71.7 114.71,73.63 115.23,74.16 115.69,74.16 115.98,73.87 115.98,73.69 116.36,73.31 v1(116.36,72.81)
  IN1 w0.211: 110.67,68.37 110.4,68.63 109.88,68.63 109.37,68.12 109.07,68.12 108.56,68.63 108.17,68.63 107.65,68.12 107.11,68.12 106.64,68.58 106.03,68.58 105.59,68.15 105.3,68.15 104.56,68.89 103.95,68.89 103.76,68.7 102.57,68.7 101.8,69.46 101.28,69.46 100.52,68.7 99.8,68.7 99.09,69.41 89.2,69.41 88.87,69.08 88.52,69.08 88.33,68.89 88.33,68.54 88.1,68.31 88.1,68.01 88.34,67.77 88.34,67.47 88.16,67.3 87.86,67.3 87.62,67.54 87.32,67.54 87.03,67.24 87.03,66.37 86.82,66.16 86.55,66.16 86.33,66.37 86.33,67.26 86.12,67.47 85.7,67.47 85.49,67.26 85.49,66.31 85.28,66.1 84.85,66.1 84.54,66.41 84.54,67.4 84.33,67.61 83.47,67.61 83.17,67.31 82.71,67.31 82.41,67.61 81.97,67.61 80.65,68.93 78.91,70.67 78.91,70.97 79.12,71.18 79.42,71.18 79.8,70.8 80.14,70.8 v1(80.58,71.24)
  BOTTOM w0.102: UC1.AR37 116.83,72.34 v1(116.36,72.81) ; v1(80.58,71.24) JDIMM1.157
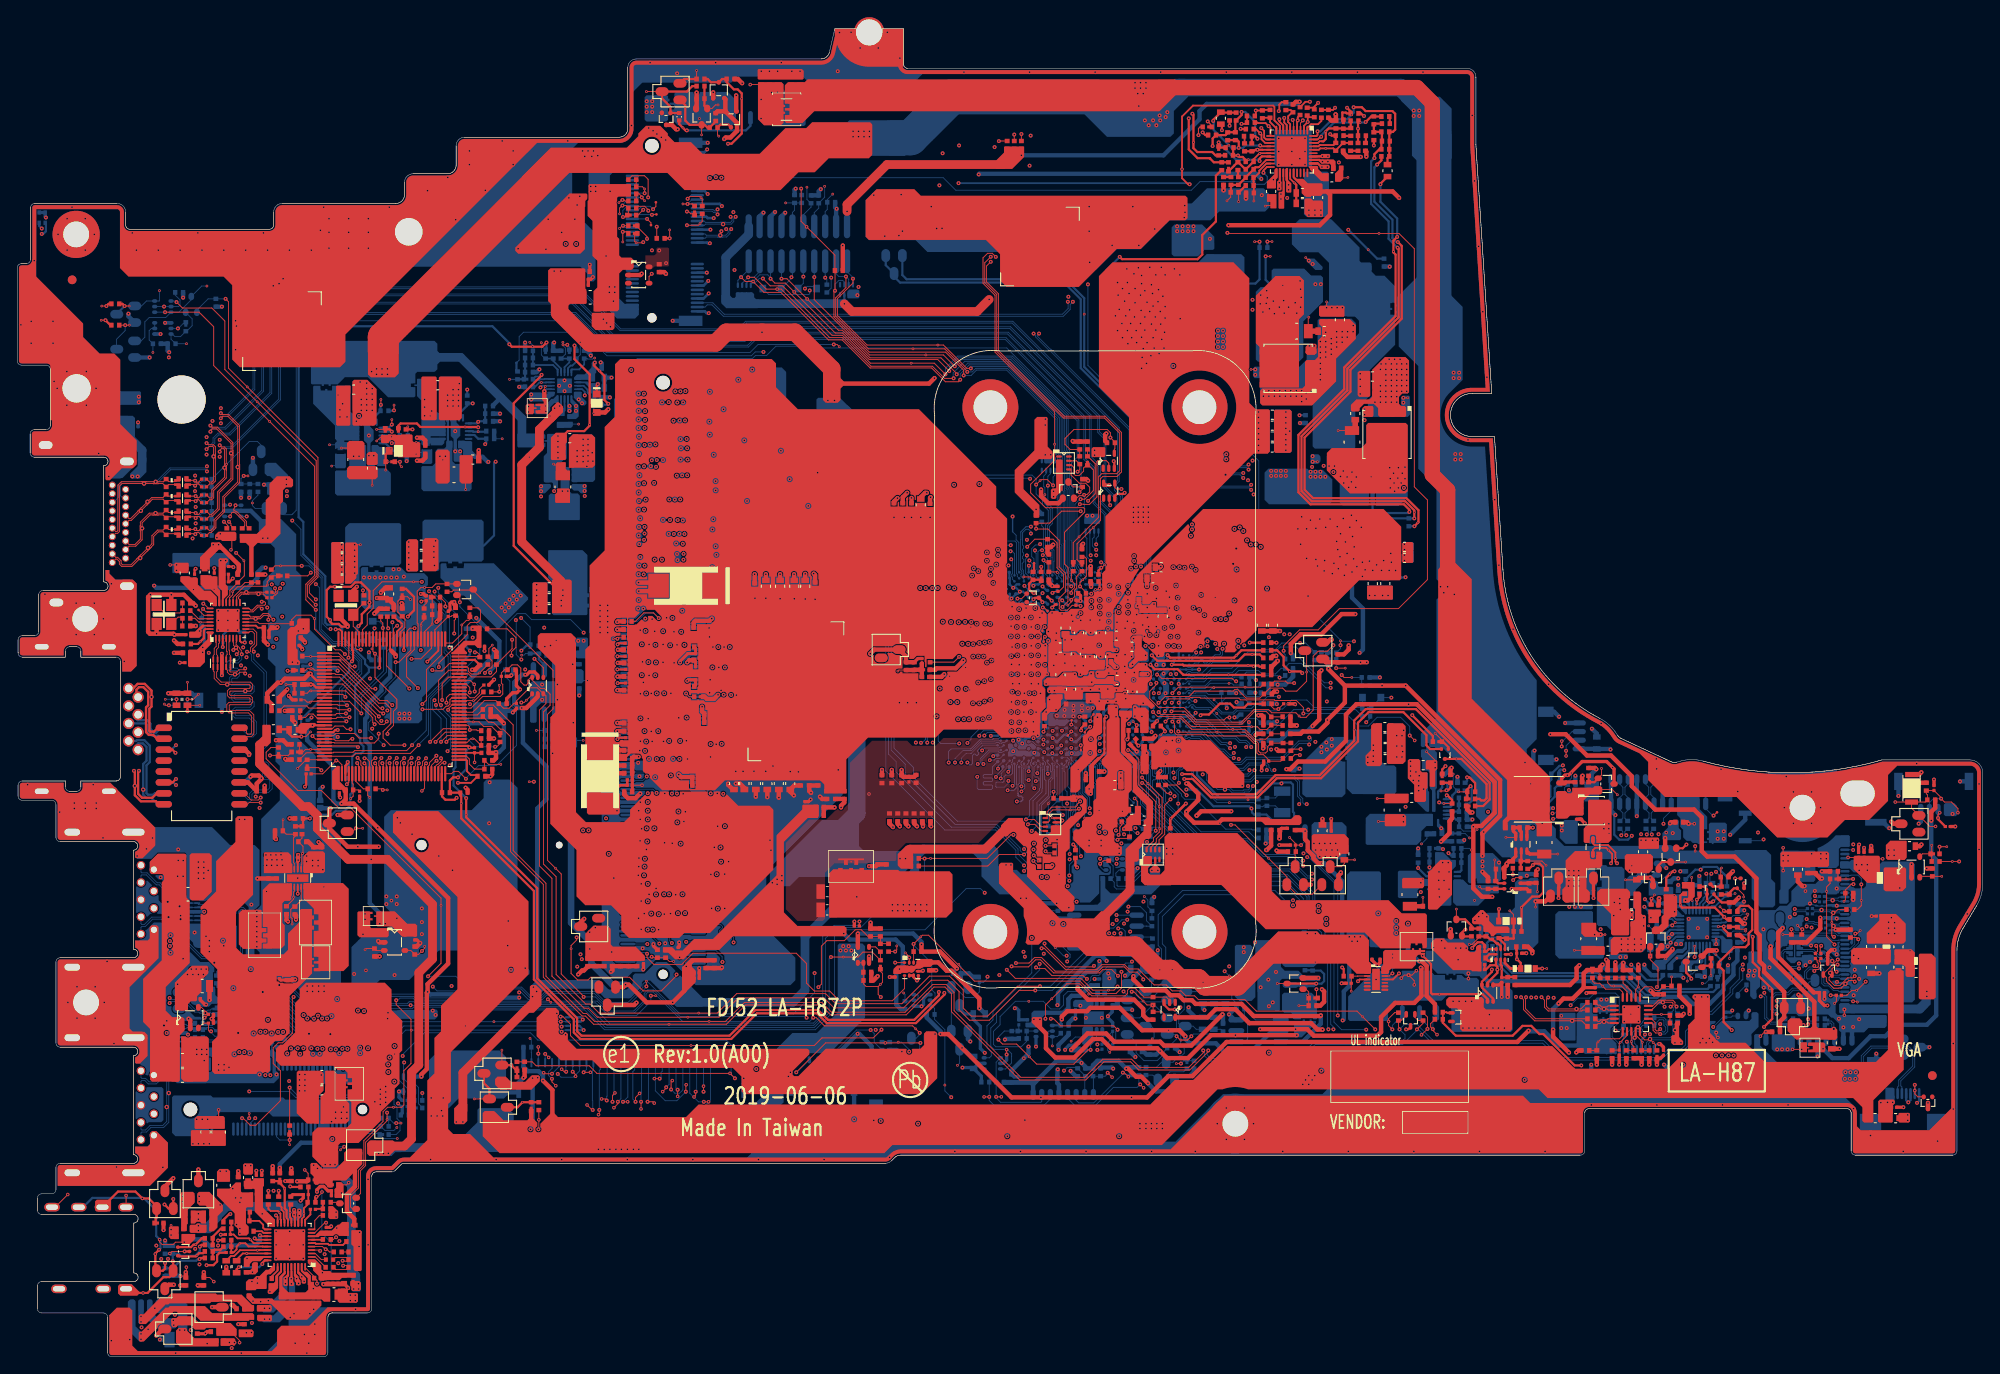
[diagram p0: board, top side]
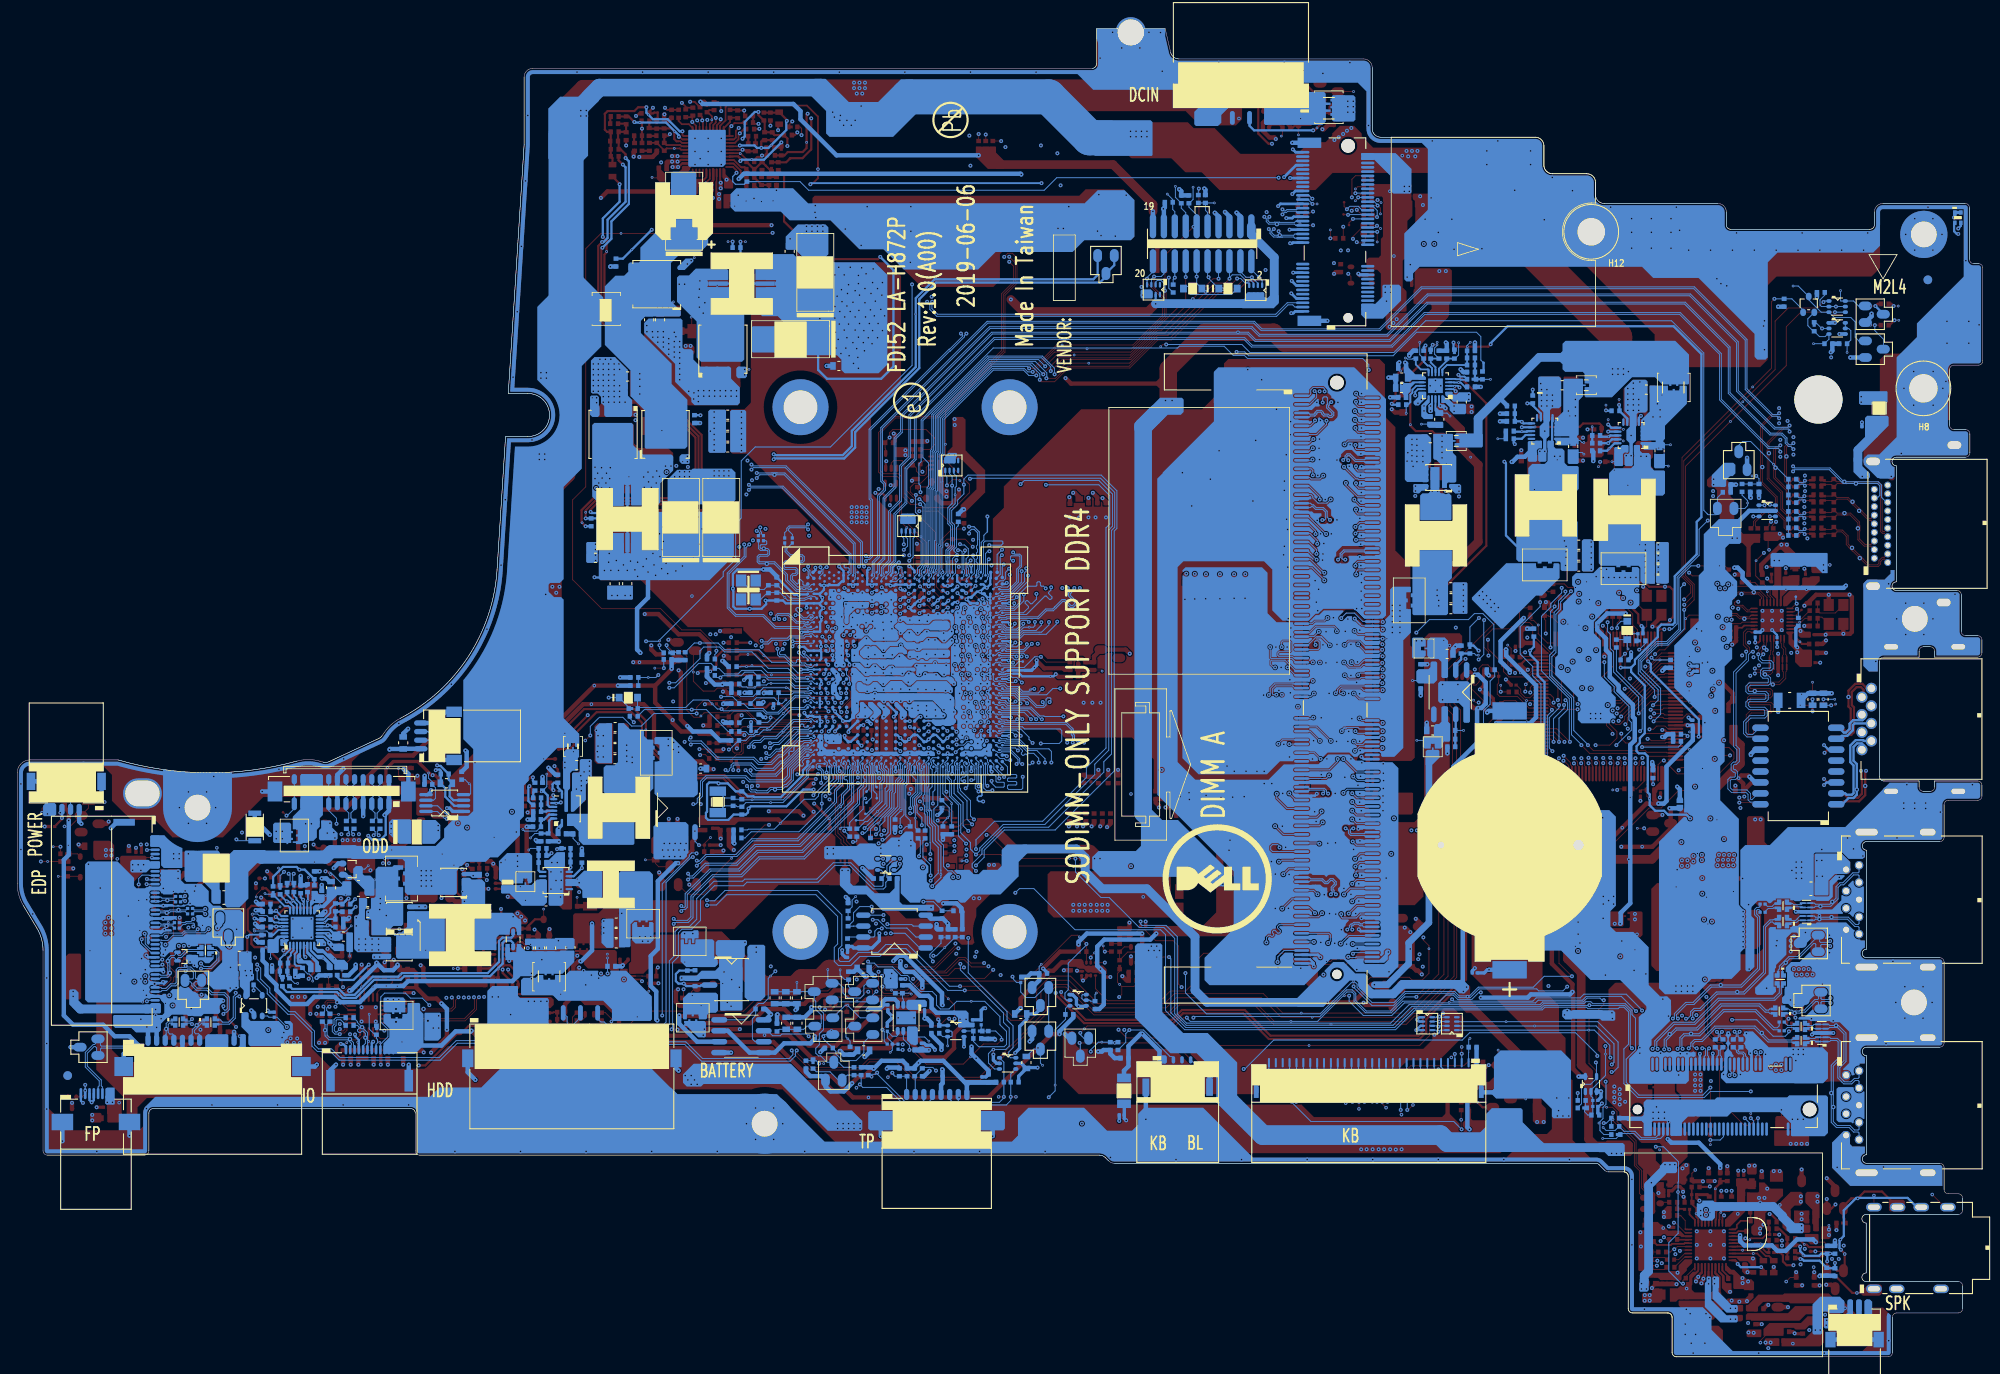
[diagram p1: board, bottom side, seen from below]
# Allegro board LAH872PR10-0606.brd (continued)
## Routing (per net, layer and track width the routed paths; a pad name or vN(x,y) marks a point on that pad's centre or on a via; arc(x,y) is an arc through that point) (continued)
DDR_A_DM0: length 67.6
  IN2 w0.127: v1(117.32,93.17) 116.91,93.58 116.91,95.31 116.18,96.04 116.18,98.5 112.36,102.32 111.57,102.32 111.37,102.52 111.37,102.7 111.78,103.12 111.78,103.3 111.6,103.48 111.42,103.48 111.01,103.06 110.83,103.06 110.4,103.49 110.4,104.01 110.27,104.14 109.54,104.14 105.34,108.34 105.34,108.55 103.51,110.38 102.57,110.38 102.44,110.51 102.44,111.19 102.31,111.32 97.99,111.32 97.05,110.38 94.18,110.38 94.01,110.55 93.59,110.55 93.42,110.38 93.16,110.38 93.04,110.51 93.04,110.99 92.91,111.12 92.65,111.12 92.53,110.99 92.53,110.51 92.4,110.38 92.15,110.38 92.02,110.51 92.02,111.21 91.89,111.34 91.64,111.34 91.51,111.21 91.51,110.51 91.38,110.38 83.42,110.38 82.02,111.78 79.79,111.78 78.39,110.38 74.52,110.38 74.39,110.51 74.39,110.99 74.26,111.12 74.01,111.12 73.88,110.99 73.88,110.51 73.75,110.38 73.09,110.38 72.96,110.25 v1(72.96,109.95)
  BOTTOM w0.102: JDIMM1.12 72.5,109.49 v1(72.96,109.95) ; v1(117.32,93.17) 117.32,92.9 117.18,92.76 117.18,91.1 117.53,90.75 UC1.B35
DDR_A_DM1: length 60
  IN2 w0.127: v1(113.08,90.93) 112.43,91.58 112.43,92.05 110.67,93.81 110.67,94.04 106.63,98.07 105,98.07 104.5,98.58 104.32,98.58 103.7,97.96 103.41,97.96 103.28,98.08 103.28,98.26 103.96,98.94 103.96,99.12 103.78,99.3 103.6,99.3 102.92,98.62 102.74,98.62 102.62,98.75 102.62,99.03 103.24,99.66 103.24,99.84 102.53,100.54 102.35,100.54 101.63,99.82 101.45,99.82 101.29,99.98 101.29,100.16 102.01,100.88 102.01,101.06 101.85,101.22 101.67,101.22 100.95,100.5 100.77,100.5 100.59,100.68 100.59,100.86 101.31,101.58 101.31,101.76 101.15,101.93 100.61,101.93 100.48,101.8 100.48,101.3 100.35,101.17 100.1,101.17 99.97,101.3 99.97,101.74 99.78,101.93 98.9,101.93 98.38,102.45 91.17,102.45 91.05,102.58 90.54,102.58 90.41,102.45 90.16,102.45 90.03,102.58 90.03,102.89 89.9,103.02 89.65,103.02 89.52,102.89 89.52,102.58 89.4,102.45 89.14,102.45 89.02,102.58 89.02,102.89 88.89,103.02 88.63,103.02 88.51,102.89 88.51,102.58 88.38,102.45 88.13,102.45 88,102.58 88,102.89 87.87,103.02 87.62,103.02 87.49,102.89 87.49,102.58 87.36,102.45 87.11,102.45 86.98,102.58 86.98,102.89 86.86,103.02 86.6,103.02 86.48,102.89 86.48,102.58 86.35,102.45 86.09,102.45 85.97,102.58 85.97,102.89 85.84,103.02 85.59,103.02 85.46,102.89 85.46,102.58 85.33,102.45 84.83,102.45 82.96,104.32 v1(77.89,104.32)
  BOTTOM w0.102: JDIMM1.33 78.04,104.24 77.96,104.32 v1(77.89,104.32) ; UC1.D40 114.76,89.48 114.5,89.48 114.41,89.57 114.17,89.57 114.07,89.49 113.32,89.49 113.02,89.8 113.02,90.87 v1(113.08,90.93)
DDR_A_DM2: length 52.7
  IN2 w0.127: v1(73.03,99.67) 73.52,99.67 73.64,99.79 73.64,100.1 73.77,100.23 74.02,100.23 74.15,100.1 74.15,99.79 74.28,99.67 75.06,99.67 75.63,99.09 79.83,99.09 80.56,98.36 81.5,98.36 84.62,95.24 91.09,95.24 91.28,95.44 91.91,95.44 92.11,95.24 92.8,95.24 92.93,95.37 93.69,95.37 96.17,92.89 105.04,92.89 108.25,89.68 v1(108.25,89.47)
  BOTTOM w0.102: v1(108.25,89.47) 108.3,89.43 108.3,89.13 108.55,88.88 108.55,88.74 108.16,88.35 108.16,88.21 108.31,88.07 108.45,88.07 108.83,88.45 108.98,88.45 111.12,86.3 113.55,86.3 113.68,86.18 114.05,86.18 114.14,86.27 114.41,86.27 114.5,86.18 114.76,86.18 UC1.K40 ; v1(73.03,99.67) 72.35,98.99 JDIMM1.54
DDR_A_DM3: length 53.5
  IN2 w0.127: v1(111.81,82.99) 111.81,83.15 110.67,84.29 107.02,84.29 106.75,84.56 101.49,84.56 101.21,84.83 100.53,84.83 100.4,84.96 100.4,85.34 100.28,85.47 100.02,85.47 99.9,85.34 99.9,85 99.73,84.83 99.52,84.83 99.39,84.96 99.39,85.34 99.26,85.47 99.01,85.47 98.88,85.34 98.88,84.97 98.75,84.84 98.57,84.84 98.4,85.01 98.4,85.34 98.27,85.47 98.02,85.47 97.89,85.34 97.89,84.96 97.76,84.83 97.51,84.83 97.38,84.96 97.38,85.34 97.26,85.47 97,85.47 96.87,85.34 96.87,84.96 96.75,84.83 96.49,84.83 96.37,84.96 96.37,85.34 96.24,85.47 95.99,85.47 95.86,85.34 95.86,84.96 95.73,84.83 95.43,84.83 95.3,84.96 95.3,85.28 95.17,85.4 94.92,85.4 94.79,85.28 94.79,84.96 94.66,84.83 94.41,84.83 94.28,84.96 94.28,85.28 94.16,85.4 93.9,85.4 93.78,85.28 93.78,84.96 93.65,84.83 93.39,84.83 93.27,84.96 93.27,85.28 93.14,85.4 92.89,85.4 92.76,85.28 92.76,84.96 92.63,84.83 92.38,84.83 92.25,84.96 92.25,85.28 92.12,85.4 91.87,85.4 91.74,85.28 91.74,84.96 91.62,84.83 91.36,84.83 91.24,84.96 91.24,85.28 91.11,85.4 90.85,85.4 90.73,85.28 90.73,84.96 90.6,84.83 90.35,84.83 90.22,84.96 90.22,85.28 90.09,85.4 89.84,85.4 89.71,85.28 89.71,84.96 89.58,84.83 88.83,84.83 88.05,85.62 85.66,85.62 80.75,90.53 79.2,90.53 77.41,92.32 v1(77.41,92.68)
  BOTTOM w0.102: JDIMM1.75 78.47,93.74 78.3,93.57 78.29,93.57 78.1,93.38 78.1,93.36 v1(77.41,92.68) ; UC1.T41 113.53,82.66 113.42,82.55 112.26,82.55 v1(111.81,82.99)
DDR_A_DM4: length 52.6
  IN2 w0.127: v1(74.3,65.57) 74.3,66.05 74.17,66.18 73.85,66.18 73.66,66.37 73.66,66.77 73.79,66.9 74.99,66.9 75.23,67.14 77.83,67.14 79.17,68.48 79.17,70.58 79.31,70.71 79.31,70.71 80.74,72.15 81.82,72.15 88.37,78.7 106.21,78.7 v1(107.2,77.7)
  BOTTOM w0.102: v1(74.3,65.57) 73.87,65.99 JDIMM1.178 ; UC1.AE41 113.75,77.53 112.29,77.53 111.73,76.97 108.78,76.97 108.05,77.7 v1(107.2,77.7)
DDR_A_DM5: length 58.2
  IN2 w0.127: v1(112.19,74.13) 112.19,74.15 112.77,74.73 113.2,74.73 113.32,74.6 113.32,73.86 113.2,73.74 111.82,73.74 109.95,71.86 103.64,71.86 103.52,71.74 103.52,70.62 103.39,70.5 103.13,70.5 103.01,70.62 103.01,71.74 102.88,71.86 102.65,71.86 102.45,71.66 102.45,70.62 102.32,70.5 102.12,70.5 101.94,70.67 101.94,71.74 101.82,71.86 101.64,71.86 101.44,71.66 101.44,70.62 101.31,70.5 101.1,70.5 100.93,70.67 100.93,71.74 100.8,71.86 100.62,71.86 100.42,71.66 100.42,70.62 100.29,70.5 100.09,70.5 99.91,70.67 99.91,71.74 99.78,71.86 99.6,71.86 99.4,71.66 99.4,70.97 99.28,70.84 99.1,70.84 98.97,70.97 98.97,71.74 98.84,71.86 98.61,71.86 97.25,70.5 88.12,70.5 87.4,69.77 87.4,67.43 86.89,66.92 86.89,65.46 86.68,65.24 86.68,64.77 83.71,61.8 82.34,61.8 v1(82.23,61.69)
  BOTTOM w0.102: UC1.AL40 114.41,74.18 114.16,74.18 114.06,74.09 114.06,74.09 114.01,74.04 113.41,74.04 113.32,73.95 112.37,73.95 v1(112.19,74.13) ; JDIMM1.199 81.28,60.74 v1(82.23,61.69)
DDR_A_DM6: length 52.3
  IN2 w0.102: 111.16,69.04 111.16,68.62 111.06,68.51 110.67,68.51
  IN2 w0.127: 111.16,69.04 111.81,69.69 111.81,70.18 v1(112.13,70.5) ; v1(73.27,54.99) 74.83,56.55 76.71,56.55 77.06,56.2 78.7,56.2 79.79,55.1 81.65,55.1 81.82,55.27 82.78,55.27 83.7,56.19 86.17,56.19 93.43,63.46 96.2,63.46 97.28,64.53 97.83,64.53 98.37,65.07 107.19,65.07 110.64,68.51 110.67,68.51
  BOTTOM w0.102: UC1.AU40 114.41,70.88 114.15,70.88 114.06,70.79 112.42,70.79 v1(112.13,70.5) ; v1(73.27,54.99) 72.77,55.49 JDIMM1.220
DDR_A_DM7: length 64
  IN2 w0.127: v1(116.16,64.57) 116.02,64.7 115.78,64.7 115.6,64.53 115.6,64.03 113.45,61.88 112.96,61.88 108.56,57.49 108.37,57.49 108.24,57.36 108.24,57.15 108.17,57.07 108.17,56.89 108.36,56.7 108.36,56.47 108.23,56.34 107.76,56.34 107.63,56.47 107.63,57.04 107.82,57.24 107.82,57.42 107.7,57.54 107.44,57.54 107.01,57.12 107.01,56.94 107.31,56.64 107.31,56.47 107.19,56.34 106.85,56.34 106.72,56.47 106.72,56.54 106.6,56.67 106.34,56.67 106.22,56.54 106.22,56.47 106.09,56.34 105.84,56.34 105.71,56.47 105.71,56.54 105.58,56.67 105.33,56.67 105.2,56.54 105.2,56.47 105.07,56.34 104.82,56.34 104.69,56.47 104.69,56.67 104.57,56.8 104.31,56.8 104.18,56.67 104.18,56.47 104.06,56.34 103.8,56.34 103.68,56.47 103.68,56.54 103.55,56.67 103.3,56.67 103.17,56.54 103.17,56.47 103.04,56.34 102.79,56.34 102.66,56.47 102.66,56.54 102.53,56.67 102.28,56.67 102.15,56.54 102.15,56.47 102.03,56.34 101.85,56.34 101.72,56.47 101.72,56.8 101.54,56.97 101.36,56.97 101.24,56.85 101.24,56.47 101.11,56.34 100.93,56.34 100.8,56.47 100.8,56.85 100.67,56.97 100.5,56.97 100.37,56.85 100.37,56.47 100.24,56.34 100.06,56.34 99.93,56.47 99.93,56.85 99.81,56.97 99.63,56.97 99.5,56.85 99.5,56.47 99.37,56.34 96.47,56.34 90.25,50.12 87.21,50.12 87.07,49.98 86.82,49.98 86.68,50.12 86.5,50.12 86.4,50.02 86.4,49.87 86.6,49.67 86.6,49.52 86.48,49.39 86.3,49.39 86.08,49.61 85.9,49.61 85.78,49.48 85.78,49.3 85.99,49.09 85.99,48.91 85.86,48.78 85.68,48.78 85.47,48.99 85.29,48.99 85.16,48.86 85.16,48.6 85.31,48.45 85.31,48.26 85.18,48.13 84.98,48.13 84.85,48.26 84.85,48.7 84.73,48.83 84.53,48.83 84.4,48.7 84.4,48.26 84.27,48.13 84.11,48.13 83.91,48.32 83.73,48.32 83.54,48.13 83.29,48.13 v1(83.24,48.18)
  BOTTOM w0.102: 116.3,65.55 116.28,65.56 116.28,65.9 116.3,65.91 116.3,66.52 116.43,66.66 UC1.BA37 ; JDIMM1.241 81.75,50.24 81.96,50.03 81.96,49.88 81.63,49.55 81.63,49.4 81.77,49.26 81.92,49.26 82.25,49.59 82.39,49.59 82.54,49.45 82.54,49.31 82.39,49.16 82.39,49.02 82.52,48.89 82.66,48.89 82.79,49.02 82.97,49.02 83.24,48.75 v1(83.24,48.18)
  BOTTOM w0.163: 116.3,65.55 116.3,65.29 116.4,65.19 116.66,65.19 116.83,65.03 116.83,64.73 116.66,64.57 v1(116.16,64.57)
DDR_A_DQ0: length 66.8
  IN2 w0.127: v1(118.86,94.49) 118.86,94.64 119.86,95.64 119.86,98.88 118.85,99.89 118.65,99.89 112.11,106.43 111.28,106.43 109.71,108 109.71,108.67 104.79,113.59 94.73,113.59 93.92,114.4 87.52,114.4 87.48,114.36 82.6,114.36 82.56,114.4 78.01,114.4 75.15,111.55 73.35,111.55 v1(72.84,111.03)
  BOTTOM w0.102: JDIMM1.8 72.54,110.49 72.84,110.78 v1(72.84,111.03) ; v1(118.86,94.49) 118.76,94.39 118.32,94.39 117.88,93.96 117.88,93.04 118.14,92.78 118.14,91.62 118.08,91.56 UC1.A34
DDR_A_DQ1: length 70.3
  IN2 w0.127: v1(117.61,92.59) 117.87,92.84 117.87,95.12 118.81,96.05 118.81,98.7 118.49,99.02 118,99.02 111.45,105.57 110.26,105.57 103.12,112.71 94.39,112.71 93.56,113.54 91.19,113.54 89.41,111.75 88.92,111.75 88.8,111.88 88.8,113.15 88.67,113.28 88.41,113.28 88.29,113.15 88.29,111.88 88.16,111.75 87.93,111.75 87.81,111.88 87.81,112.92 87.64,113.08 87.42,113.08 87.3,112.96 87.3,111.88 87.17,111.75 86.92,111.75 86.79,111.88 86.79,112.39 86.66,112.52 86.41,112.52 86.28,112.39 86.28,111.88 86.15,111.75 85.88,111.75 85.75,111.88 85.75,112.39 85.63,112.52 85.37,112.52 85.24,112.39 85.24,111.94 85.05,111.75 84.86,111.75 84.74,111.88 84.74,112.39 84.61,112.52 84.36,112.52 84.23,112.39 84.23,111.94 84.1,111.82 83.92,111.82 82.2,113.54 79.25,113.54 78,112.28 77.65,112.28 v1(77.65,112.28)
  BOTTOM w0.102: JDIMM1.7 78.21,110.74 77.41,111.54 77.41,112.05 v1(77.65,112.28) ; v1(117.61,92.59) 117.94,92.26 117.94,91.76 117.85,91.67 117.85,91.08 117.85,91.07 117.85,91.07 117.77,90.99 117.77,90.74 118.08,90.43 UC1.B34
DDR_A_DQ2: length 67.9
  IN2 w0.127: v1(72.9,107.99) 72.81,108.08 72.81,108.26 72.95,108.41 73.3,108.41 73.5,108.2 73.81,108.2 73.95,108.34 73.95,108.74 74.08,108.87 74.33,108.87 74.46,108.74 74.46,108.44 74.58,108.32 75.15,108.32 76.27,109.43 78.9,109.43 79.75,110.29 81.2,110.29 82.05,109.43 103.21,109.43 104.47,108.17 104.47,107.98 115.75,96.7 115.75,95.58 116.48,94.85 116.48,90.04 116.35,89.91 116.02,89.91 115.9,90.04 115.9,93.49 115.73,93.66 v1(115.43,93.66)
  BOTTOM w0.102: UC1.A38 115.88,90.86 115.88,93.39 115.61,93.66 v1(115.43,93.66) ; JDIMM1.20 72.59,107.49 72.9,107.79 v1(72.9,107.99)
DDR_A_DQ3: length 70.9
  IN2 w0.127: v1(76.26,108.84) 76.26,108.82 75.98,108.53 75.98,108.45 76.12,108.32 76.39,108.32 79.3,108.32 80.41,109.42 80.68,109.42 81.79,108.32 101.35,108.32 101.68,107.98 101.86,107.98 102.2,108.32 102.39,108.32 102.54,108.17 102.54,107.99 102.22,107.66 102.22,107.45 102.3,107.36 102.48,107.36 102.89,107.77 103.07,107.77 103.2,107.64 103.2,107.46 102.79,107.05 102.79,106.87 102.97,106.69 103.15,106.69 103.56,107.1 103.74,107.1 103.92,106.93 103.92,106.75 103.6,106.42 103.6,106.24 103.73,106.12 103.91,106.12 104.42,106.63 104.6,106.63 104.78,106.45 104.78,106.27 104.26,105.76 104.26,105.58 104.48,105.36 104.66,105.36 105.14,105.85 105.32,105.85 105.5,105.67 105.5,105.49 105.04,105.02 105.04,104.81 105.22,104.63 105.4,104.63 105.88,105.11 106.06,105.11 106.18,104.98 106.18,104.8 105.72,104.34 105.72,104.12 105.92,103.93 106.1,103.93 106.58,104.41 106.76,104.41 106.94,104.23 106.94,104.05 106.47,103.58 106.47,103.37 106.65,103.19 106.83,103.19 107.35,103.7 107.53,103.7 107.71,103.52 107.71,103.34 107.19,102.83 107.19,102.65 107.37,102.47 107.55,102.47 108.07,102.98 108.25,102.98 108.43,102.8 108.43,102.63 107.88,102.08 107.88,101.9 108.06,101.73 108.24,101.73 108.59,102.07 108.59,102.08 108.78,102.27 108.96,102.27 109.37,101.86 109.37,101.21 109.01,100.84 109.01,100.66 109.17,100.49 109.4,100.49 109.65,100.25 109.65,100.02 109.9,99.76 110.08,99.76 110.33,99.51 110.33,99.33 114.95,94.72 114.95,92.65 115.07,92.52 115.37,92.52 115.5,92.65 v1(115.5,92.72)
  BOTTOM w0.102: UC1.B38 115.66,90.38 115.66,90.63 115.57,90.73 115.57,90.97 115.65,91.07 115.65,92.58 v1(115.5,92.72) ; JDIMM1.21 77.4,107.24 76.26,108.38 v1(76.26,108.84)
DDR_A_DQ4: length 66.8
  IN2 w0.127: v1(72.82,111.99) 72.82,112.62 75.4,115.2 88.44,115.2 88.81,114.83 94.1,114.83 94.91,114.03 104.97,114.03 110.14,108.85 110.14,108.64 111.59,107.19 111.95,107.19 118.83,100.32 119.03,100.32 120.29,99.06 120.29,95.31 119.08,94.11 v1(119.08,93.78)
  BOTTOM w0.102: v1(72.82,111.99) 72.82,111.91 72.4,111.49 JDIMM1.4 ; v1(119.08,93.78) 118.79,93.78 118.61,93.59 118.61,91.23 UC1.A33
DDR_A_DQ5: length 71
  IN2 w0.127: v1(76.48,112.25) 76.48,112.26 77.01,112.8 77.69,112.8 78.86,113.97 82.38,113.97 83.4,112.95 86.68,112.95 87.7,113.97 93.74,113.97 94.57,113.14 103.3,113.14 105.26,111.18 105.44,111.18 105.93,111.67 106.11,111.67 106.28,111.5 106.28,111.32 105.79,110.83 105.79,110.65 105.97,110.47 106.15,110.47 106.64,110.95 106.82,110.95 107,110.77 107,110.59 106.51,110.11 106.51,109.93 106.74,109.7 106.92,109.7 107.4,110.19 107.58,110.19 107.76,110.01 107.76,109.83 107.28,109.34 107.28,109.16 107.45,108.98 107.63,108.98 108.09,109.44 108.27,109.44 108.45,109.26 108.45,109.08 107.99,108.62 107.99,108.44 108.17,108.26 108.35,108.26 108.78,108.69 108.96,108.69 109.14,108.51 109.14,108.33 108.71,107.91 108.71,107.73 110.44,106 111.63,106 118.18,99.45 118.67,99.45 119.24,98.88 119.24,95.76 118.3,94.82 118.3,93.8 v1(118.26,93.77)
  BOTTOM w0.102: UC1.B33 118.41,90.73 118.41,90.98 118.32,91.08 118.32,91.44 118.4,91.53 118.4,93.39 118.22,93.57 118.22,93.72 v1(118.26,93.77) ; JDIMM1.3 78.29,111.74 78.1,111.93 78.1,112.41 77.81,112.69 76.65,112.69 76.48,112.52 v1(76.48,112.25)
DDR_A_DQ6: length 67.6
  IN2 w0.127: v1(72.96,108.94) 73.33,109.31 74.37,109.31 74.5,109.43 74.5,109.82 74.63,109.95 74.88,109.95 75.01,109.82 75.01,109.43 75.13,109.31 75.53,109.31 76.17,109.95 78.68,109.95 79.98,111.25 81.94,111.25 83.24,109.95 100.23,109.95 100.36,110.08 100.36,110.76 100.48,110.89 100.74,110.89 100.86,110.76 100.86,109.99 100.99,109.86 101.25,109.86 101.37,109.99 101.37,110.76 101.5,110.89 101.75,110.89 101.88,110.76 101.88,110.08 102.01,109.95 103.33,109.95 104.91,108.37 104.91,108.16 111.17,101.89 112.18,101.89 112.73,101.34 112.73,101.16 112.4,100.84 112.4,100.66 112.54,100.53 112.72,100.53 113.04,100.85 113.22,100.85 113.4,100.67 113.4,100.49 113.08,100.17 113.08,99.99 113.26,99.81 113.44,99.81 113.76,100.13 113.94,100.13 114.12,99.95 114.12,99.77 113.8,99.45 113.8,99.27 114.01,99.06 114.21,99.06 114.52,99.37 114.7,99.37 114.88,99.19 114.88,99.01 114.56,98.68 114.56,98.5 114.74,98.32 114.92,98.32 115.24,98.65 115.42,98.65 115.66,98.41 v1(115.66,97.7)
  BOTTOM w0.102: v1(72.96,108.94) 72.51,108.49 JDIMM1.16 ; 115.66,95.92 116.08,95.51 116.08,94.99 116.38,94.69 116.38,91.26 UC1.A37
  BOTTOM w0.163: 115.66,95.92 v1(115.66,97.7)
DDR_A_DQ7: length 70.9
  IN2 w0.102: v1(115.45,94.36) 115.8,94.02 115.94,94.02 116.1,94.17 116.1,94.43 116.05,94.49
  IN2 w0.127: 116.05,94.49 116.05,94.67 115.48,95.24 115.04,95.24 114.76,95.51 114.76,95.89 115.27,96.39 115.27,96.57 115.09,96.75 114.91,96.75 114.31,96.15 114.13,96.15 113.97,96.3 113.97,96.48 114.58,97.08 114.58,97.26 114.4,97.44 114.22,97.44 113.62,96.84 113.44,96.84 113.26,97.02 113.26,97.2 113.86,97.8 113.86,97.98 113.68,98.16 113.5,98.16 112.9,97.56 112.72,97.56 112.54,97.74 112.54,97.92 113.14,98.52 113.14,98.7 112.96,98.88 112.78,98.88 112.27,98.37 112.09,98.37 111.93,98.54 111.93,98.72 112.44,99.22 112.44,99.4 112.26,99.58 112.08,99.58 111.64,99.14 111.46,99.14 111.28,99.32 111.28,99.5 111.72,99.94 111.72,100.12 111.54,100.3 111.36,100.3 110.95,99.89 110.77,99.89 110.61,100.05 110.61,100.23 111,100.62 111,100.84 110.87,100.97 110.66,100.97 110.31,100.62 110.1,100.62 109.88,100.84 109.88,101.02 110.26,101.4 110.26,101.58 104.49,107.35 104.31,107.35 104.29,107.34 104.11,107.34 103.93,107.52 103.93,107.7 104.04,107.81 104.04,107.99 103.86,108.17 103.68,108.17 103.58,108.06 103.4,108.06 103.3,108.16 103.3,108.34 103.4,108.44 103.4,108.62 103.27,108.75 102.46,108.75 102.25,108.96 101.44,108.96 101.23,108.75 81.97,108.75 80.86,109.85 80.23,109.85 79.19,108.81 77.66,108.81 v1(77.6,108.87)
  BOTTOM w0.102: v1(115.45,94.36) 114.04,94.36 113.87,94.54 113.87,94.74 113.97,94.84 115.94,94.84 116.12,94.67 116.12,91.08 116.21,90.98 116.21,90.73 UC1.B37 ; v1(77.6,108.87) 77.6,108.77 78.13,108.24 JDIMM1.17
DDR_A_DQ8: length 57.2
  IN2 w0.127: v1(72.9,106.02) 72.9,106.54 74.15,107.78 79.58,107.78 79.86,108.06 81.05,108.06 81.33,107.78 101.13,107.78 114.41,94.5 114.41,91.23 114.29,91.1 113.9,91.1 113.77,91.23 v1(113.77,92.11)
  BOTTOM w0.102: v1(72.9,106.02) 72.9,105.64 72.75,105.49 JDIMM1.28 ; v1(113.77,92.11) 113.93,91.95 UC1.B41
DDR_A_DQ9: length 60.5
  IN2 w0.127: v1(77.85,105.64) 77.95,105.73 79.66,105.73 80.17,106.24 83.15,106.24 84.66,104.72 85.23,104.72 85.36,104.85 85.36,105.51 85.49,105.64 85.74,105.64 85.87,105.51 85.87,104.85 85.99,104.72 86.25,104.72 86.37,104.85 86.37,105.51 86.5,105.64 86.76,105.64 86.88,105.51 86.88,104.85 87.01,104.72 87.26,104.72 87.39,104.85 87.39,105.51 87.52,105.64 87.77,105.64 87.9,105.51 87.9,104.85 88.03,104.72 98.31,104.72 99.23,105.64 99.41,105.64 99.59,105.46 99.59,105.28 98.67,104.36 98.67,104.18 98.85,104.01 99.03,104.01 99.95,104.92 100.13,104.92 100.31,104.74 100.31,104.56 99.39,103.65 99.39,103.47 99.56,103.3 103.78,103.3 104.21,102.87 104.21,102.69 103.96,102.44 103.96,102.26 104.14,102.08 104.32,102.08 104.57,102.33 104.75,102.33 104.93,102.15 104.93,101.97 104.68,101.72 104.68,101.54 104.86,101.36 105.04,101.36 105.29,101.61 105.47,101.61 107.68,99.39 107.68,99.21 107.68,99.21 107.68,99.03 107.86,98.85 108.04,98.85 108.04,98.85 108.22,98.85 108.4,98.67 108.4,98.49 108.4,98.49 108.4,98.31 108.58,98.13 108.76,98.13 108.76,98.13 108.94,98.13 109.12,97.95 109.12,97.77 109.12,97.77 109.12,97.59 109.3,97.41 109.48,97.41 109.48,97.41 109.66,97.41 109.84,97.24 109.84,97.06 109.84,97.05 109.84,96.87 110.02,96.69 110.2,96.69 110.2,96.7 110.38,96.7 110.56,96.52 110.56,96.34 110.55,96.33 110.55,96.15 110.73,95.97 110.91,95.97 110.92,95.98 111.1,95.98 111.28,95.8 111.28,95.62 111.27,95.61 111.27,95.43 111.45,95.25 111.63,95.25 111.64,95.26 111.82,95.26 113.14,93.93 v1(113.14,91.63)
  BOTTOM w0.102: v1(113.14,91.63) 113.58,91.2 113.58,90.46 113.81,90.22 114.22,90.22 UC1.C40 ; JDIMM1.29 78.31,105.24 77.92,105.64 v1(77.85,105.64)
DDR_A_DQ10: length 59.9
  IN2 w0.127: v1(76.64,102.45) 76.56,102.52 74.62,102.52 74.33,102.23 74.33,102.04 74.66,101.71 80.09,101.71 80.64,102.26 81.35,102.26 85.48,98.13 92.35,98.13 92.47,98.26 92.47,99.04 92.6,99.17 92.85,99.17 92.98,99.04 92.98,98.26 93.11,98.13 97.1,98.13 97.18,98.05 97.36,98.05 98.23,98.92 98.41,98.92 98.55,98.78 98.55,98.6 97.53,97.57 97.53,97.39 97.71,97.2 97.89,97.2 98.92,98.23 99.1,98.23 99.26,98.07 99.26,97.89 98.3,96.93 98.3,96.75 98.43,96.62 98.71,96.62 98.94,96.85 99.12,96.85 99.35,96.62 100.67,96.62 101.73,95.57 106.22,95.57 110.96,90.83 v1(110.96,90.83)
  BOTTOM w0.102: JDIMM1.41 78.21,102.24 78.04,102.06 77.02,102.06 v1(76.64,102.45) ; v1(110.96,90.83) 110.96,90.16 112.79,88.33 113.46,88.33 113.63,88.16 UC1.F41
DDR_A_DQ11: length 57.4
  IN2 w0.127: v1(112.26,88.33) 114.03,88.33 114.26,88.56 114.26,89.1 114.01,89.35 112.24,89.35 112.12,89.48 112.12,91.76 110.81,93.07 110.81,93.23 110.52,93.52 110.45,93.52 106.86,97.12 102.68,97.12 102.4,97.4 102.4,98.26 99.16,101.5 85.1,101.5 82.79,103.81 80,103.81 79.67,103.48 v1(74.23,103.48)
  BOTTOM w0.102: v1(112.26,88.33) 112.56,88.03 113.36,88.03 113.43,87.96 113.54,87.96 113.55,87.95 114.03,87.95 114.06,87.92 114.06,87.92 114.16,87.83 114.41,87.83 UC1.G40 ; JDIMM1.42 72.53,101.99 72.62,102.08 72.84,102.08 v1(74.23,103.48)
DDR_A_DQ12: length 57.5
  IN2 w0.127: v1(74.17,106.08) 74.17,106.8 74.72,107.35 75.02,107.35 75.15,107.23 75.15,106.27 75.27,106.14 75.53,106.14 75.65,106.27 75.65,107.23 75.78,107.35 76.01,107.35 76.14,107.23 76.14,106.21 76.26,106.08 76.53,106.08 76.66,106.21 76.66,107.23 76.78,107.35 79.88,107.35 80.16,107.63 80.75,107.63 81.11,107.27 83.58,107.27 83.73,107.11 101.18,107.11 113.96,94.34 v1(113.96,93.84)
  BOTTOM w0.102: JDIMM1.24 73.76,106.49 v1(74.17,106.08) ; UC1.A40 114.53,91.65 114.53,91.65 114.53,93.27 v1(113.96,93.84)
DDR_A_DQ13: length 60
  IN2 w0.127: v1(77.79,106.72) 77.99,106.92 78.4,106.92 78.56,106.76 78.56,106.29 78.69,106.17 78.94,106.17 79.07,106.29 79.07,106.67 79.19,106.79 83.32,106.79 84.05,106.07 88.2,106.07 88.43,106.29 89.03,106.29 89.25,106.07 89.95,106.07 90.08,106.2 90.08,106.56 90.21,106.68 90.46,106.68 90.59,106.56 90.59,106.2 90.72,106.07 90.97,106.07 91.1,106.2 91.1,106.56 91.22,106.68 91.48,106.68 91.6,106.56 91.6,106.2 91.73,106.07 91.99,106.07 92.11,106.2 92.11,106.56 92.24,106.68 92.49,106.68 92.62,106.56 92.62,106.2 92.75,106.07 93,106.07 93.13,106.2 93.13,106.56 93.26,106.68 93.51,106.68 93.64,106.56 93.64,106.2 93.76,106.07 94.02,106.07 94.14,106.2 94.14,106.56 94.27,106.68 94.53,106.68 94.65,106.56 94.65,106.2 94.78,106.07 100.17,106.07 100.79,106.68 100.97,106.68 101.15,106.5 101.15,106.32 100.33,105.51 100.33,105.33 100.51,105.15 100.68,105.15 101.5,105.97 101.68,105.97 101.86,105.79 101.86,105.61 101.04,104.79 101.04,104.61 101.22,104.43 101.4,104.43 102.22,105.25 102.4,105.25 102.58,105.07 102.58,104.89 101.76,104.07 101.76,103.89 101.93,103.73 103.96,103.73 113.53,94.16 113.53,93.66 v1(113.98,93.21)
  BOTTOM w0.102: v1(77.79,106.72) 78.26,106.24 JDIMM1.25 ; v1(113.98,93.21) 114.18,93.01 114.18,90.96 UC1.B40
DDR_A_DQ14: length 57.4
  IN2 w0.127: v1(111.68,91.35) 111.68,91.76 110.57,92.86 110.5,92.86 106.76,96.6 102.11,96.6 100.83,97.88 100.83,98.06 101.32,98.55 101.32,98.73 101.14,98.91 100.96,98.91 100.47,98.42 100.29,98.42 100.11,98.6 100.11,98.78 100.6,99.27 100.6,99.45 100.42,99.63 100.24,99.63 99.75,99.14 99.57,99.14 99.39,99.32 99.39,99.5 99.88,99.99 99.88,100.17 99.7,100.34 99.52,100.34 99.03,99.86 98.85,99.86 98.67,100.04 98.67,100.22 99.16,100.7 99.16,100.88 98.98,101.06 98.8,101.06 98.32,100.57 85.3,100.57 82.58,103.29 80.22,103.29 79.88,102.95 73.1,102.95 72.84,103.22 v1(72.84,103.54)
  BOTTOM w0.102: v1(111.68,91.35) 111.68,91.34 111.72,91.3 111.72,90.06 113.04,88.73 113.78,88.73 113.81,88.71 UC1.E41 ; JDIMM1.38 72.6,102.99 72.84,103.22 v1(72.84,103.54)
DDR_A_DQ15: length 60
  IN2 w0.127: v1(111.15,91.67) 110.97,91.67 106.47,96.17 101.77,96.17 98.19,99.75 95.41,99.75 95.28,99.63 95.28,99.12 95.09,98.93 94.84,98.93 94.65,99.12 94.65,99.63 94.52,99.75 91.5,99.75 91.37,99.63 91.37,98.69 91.25,98.56 90.99,98.56 90.87,98.69 90.87,99.63 90.74,99.75 90.48,99.75 90.36,99.63 90.36,98.69 90.23,98.56 89.98,98.56 89.85,98.69 89.85,99.63 89.72,99.75 89.47,99.75 89.34,99.63 89.34,98.69 89.21,98.56 88.96,98.56 88.83,98.69 88.83,99.63 88.71,99.75 88.45,99.75 88.33,99.63 88.33,98.69 88.2,98.56 87.94,98.56 87.82,98.69 87.82,99.63 87.69,99.75 87.44,99.75 87.31,99.63 87.31,98.69 87.18,98.56 86.93,98.56 86.8,98.69 86.8,99.63 86.67,99.75 86.42,99.75 86.29,99.63 86.29,98.69 86.17,98.56 85.91,98.56 85.79,98.69 85.79,99.63 85.66,99.75 85.39,99.75 82.37,102.77 80.43,102.77 79.99,102.33 78.01,102.33 v1(77.85,102.49)
  BOTTOM w0.102: v1(77.85,102.49) 77.85,103.05 78.04,103.24 JDIMM1.37 ; v1(111.15,91.67) 111.15,91.37 111.34,91.18 111.34,90.15 112.96,88.53 113.55,88.53 113.61,88.46 113.68,88.46 113.75,88.39 114.06,88.39 114.14,88.47 114.41,88.47 114.5,88.38 114.76,88.38 UC1.F40
DDR_A_DQ16: length 53.1
  IN2 w0.127: v1(111.43,88.64) 111.08,88.99 111.08,89.83 105.88,95.04 101.51,95.04 100.45,96.09 97.61,96.09 96.11,97.59 85.26,97.59 84.36,98.49 84.18,98.49 84.1,98.41 83.89,98.41 83.74,98.57 83.74,98.77 83.82,98.85 83.82,99.03 83.64,99.21 83.46,99.21 83.38,99.13 83.17,99.13 83.02,99.28 83.02,99.49 83.1,99.57 83.1,99.75 82.92,99.93 82.74,99.93 82.67,99.85 82.45,99.85 82.33,99.98 82.33,100.23 82.38,100.29 82.38,100.47 81.65,101.2 80.4,101.2 80.37,101.17 74.44,101.17 v1(74.01,101.6)
  BOTTOM w0.102: v1(74.01,101.6) 74.01,101.35 72.65,99.99 JDIMM1.50 ; v1(111.43,88.64) 111.43,87.9 112.54,86.79 113.67,86.79 113.69,86.81 114.06,86.81 114.36,86.51 UC1.J40
DDR_A_DQ17: length 55.4
  IN2 w0.127: v1(109.97,88.71) 109.97,89.34 107.19,92.12 107.19,92.24 105.67,93.76 105,93.76 104.87,93.88 104.87,94.05 104.74,94.17 104.49,94.17 104.36,94.05 104.36,93.88 104.24,93.76 103.98,93.76 103.86,93.88 103.86,94.05 103.73,94.17 103.47,94.17 103.35,94.05 103.35,93.88 103.22,93.76 102.97,93.76 102.84,93.88 102.84,94.05 102.71,94.17 102.46,94.17 102.33,94.05 102.33,93.88 102.2,93.76 101.95,93.76 101.82,93.88 101.82,94.05 101.7,94.17 101.44,94.17 101.32,94.05 101.32,93.88 101.19,93.76 100.36,93.76 100.29,93.83 100.29,94.02 100.63,94.37 100.63,94.69 100.34,94.98 100.16,94.98 99.71,94.53 99.59,94.53 99.48,94.64 98.73,94.64 98.61,94.77 98.61,95.1 98.48,95.23 98.22,95.23 98.1,95.1 98.1,94.77 97.97,94.64 97.72,94.64 97.59,94.77 97.59,95.1 97.46,95.23 97.21,95.23 97.08,95.1 97.08,94.77 96.95,94.64 96.73,94.64 94.76,96.61 84.48,96.61 81.69,99.39 81.02,99.39 80.27,100.14 76.18,100.14 75.78,99.74 v1(75.78,99.68)
  BOTTOM w0.102: JDIMM1.49 78.04,100.24 77.85,100.05 77.85,99.86 77.25,99.26 76.2,99.26 v1(75.78,99.68) ; UC1.J41 111.47,86.51 110.89,87.09 110.89,87.23 111.28,87.62 111.28,87.77 111.13,87.91 110.99,87.91 110.63,87.55 110.49,87.55 109.97,88.07 v1(109.97,88.71)
DDR_A_DQ18: length 52.5
  IN2 w0.127: v1(72.9,96.49) 73.03,96.49 73.22,96.68 73.77,96.68 73.89,96.56 73.89,95.67 74.02,95.54 74.27,95.54 74.4,95.67 74.4,96.56 74.53,96.68 74.76,96.68 74.88,96.56 74.88,96.24 75.01,96.11 75.26,96.11 75.39,96.24 75.39,96.56 75.52,96.68 76.49,96.68 76.5,96.7 78.76,96.7 79.73,95.73 81.14,95.73 83.99,92.88 93.45,92.88 95.24,91.09 96.31,91.09 97.32,90.08 103.64,90.08 104.76,88.96 107.28,88.96 107.95,88.29 109,88.29 111.49,85.8 v1(111.49,85.23)
  BOTTOM w0.102: UC1.N40 114.41,84.53 114.15,84.53 114.06,84.62 113.82,84.62 113.59,84.4 112.18,84.4 111.49,85.09 v1(111.49,85.23) ; v1(72.9,96.49) 72.4,96.99 JDIMM1.62
DDR_A_DQ19: length 55.2
  IN2 w0.127: v1(110.15,85.44) 110.15,85.81 108.76,87.19 107.21,87.19 107.08,87.32 107.08,87.54 106.96,87.67 106.7,87.67 106.58,87.54 106.58,87.32 106.45,87.19 106.22,87.19 106.01,87.41 106.01,87.97 105.88,88.1 105.63,88.1 105.5,87.97 105.5,87.32 105.37,87.19 105.12,87.19 104.99,87.32 104.99,87.97 104.87,88.1 104.61,88.1 104.49,87.97 104.49,87.32 104.36,87.19 104.13,87.19 104,87.32 104,88.32 103.86,88.46 103.68,88.46 103.5,88.28 103.5,87.32 103.37,87.19 103.11,87.19 102.92,87.39 102.92,89.09 102.8,89.21 102.54,89.21 102.42,89.09 102.42,87.41 102.29,87.28 102.08,87.28 101.22,88.14 101.22,88.32 101.78,88.88 101.78,89.06 101.62,89.21 101.39,89.21 100.86,88.68 100.68,88.68 100.15,89.21 93.7,89.21 93.25,89.66 85.72,89.66 81.62,93.76 80.24,93.76 78.25,95.75 77.62,95.75 v1(77.53,95.67)
  BOTTOM w0.102: JDIMM1.63 78.29,96.74 77.53,95.98 v1(77.53,95.67) ; UC1.N41 113.82,84.2 112.07,84.2 111.96,84.3 111.96,84.3 111.43,84.83 v2(110.8,84.83) 110.31,84.83 110.15,85 110.15,85.17 v1(110.15,85.44)
DDR_A_DQ20: length 52.2
  IN2 w0.127: v1(72.84,101.57) 72.84,101.19 73.37,100.66 74.2,100.66 74.28,100.57 74.5,100.57 74.67,100.74 75.1,100.74 75.27,100.57 75.52,100.57 75.69,100.74 76.11,100.74 76.28,100.57 76.54,100.57 76.7,100.74 77.13,100.74 77.3,100.57 77.63,100.57 77.79,100.74 78.15,100.74 78.31,100.57 78.57,100.57 78.73,100.74 79.16,100.74 79.33,100.57 80.48,100.57 81.15,99.91 81.79,99.91 84.65,97.04 95.46,97.04 96.84,95.66 100.27,95.66 101.33,94.61 105.55,94.61 107.4,92.76 108.75,91.41 110.57,89.59 110.57,88.75 111.7,87.61 v1(112.55,87.61)
  BOTTOM w0.102: JDIMM1.46 72.51,100.99 72.89,101.37 72.89,101.52 v1(72.84,101.57) ; v1(112.55,87.61) 112.55,87.37 112.71,87.21 113.38,87.21 113.47,87.29 114.07,87.29 114.15,87.37 114.41,87.37 114.5,87.28 114.76,87.28 UC1.H40
DDR_A_DQ21: length 55.4
  IN2 w0.127: v1(108.89,89.34) 108.87,89.37 108.87,89.83 107.71,90.98 107.71,90.98 107.14,91.56 105.37,93.32 99.55,93.32 99.43,93.45 99.43,94.08 99.3,94.21 99.04,94.21 98.92,94.08 98.92,93.45 98.79,93.32 98.54,93.32 98.41,93.45 98.41,94 98.21,94.2 98.03,94.2 97.9,94.07 97.9,93.45 97.77,93.32 97.52,93.32 97.39,93.45 97.39,94.08 97.27,94.21 97.01,94.21 96.89,94.08 96.89,93.45 96.76,93.32 96.35,93.32 95.84,93.83 95.84,94.01 96.2,94.38 96.2,94.56 96.02,94.74 95.84,94.74 95.53,94.43 95.36,94.43 95.18,94.61 95.18,94.79 95.48,95.1 95.48,95.28 95.3,95.46 95.12,95.46 94.82,95.15 94.64,95.15 94.46,95.33 94.46,95.51 94.76,95.82 94.76,96 94.58,96.18 94.4,96.18 94.1,95.87 93.63,95.87 93.33,96.18 92.97,96.18 92.66,95.87 92.11,95.87 91.8,96.18 91.35,96.18 91.18,96.01 84.46,96.01 81.6,98.87 80.77,98.87 80.04,99.61 77.12,99.61 v1(77.05,99.68)
  BOTTOM w0.102: v1(108.89,89.34) 109.14,89.6 109.4,89.6 109.51,89.7 109.51,90 109.61,90.1 109.81,90.1 109.91,90 109.91,89.7 110.01,89.6 111.05,89.6 111.81,88.84 111.81,87.81 112.63,86.99 113.52,86.99 113.58,87.06 UC1.H41 ; JDIMM1.45 78.28,101.24 77.05,100.01 v1(77.05,99.68)
DDR_A_DQ22: length 52
  IN2 w0.127: v1(72.84,98.51) 72.84,99.02 72.96,99.15 74.84,99.15 75.42,98.57 79.61,98.57 80.35,97.84 81.27,97.84 84.44,94.67 93.66,94.67 95.87,92.46 104.74,92.46 107.6,89.61 107.6,89.45 107.6,89.26 107.93,88.92 109.16,88.92 110.61,87.48 111.03,87.48 112.48,86.02 v1(112.48,85.25)
  BOTTOM w0.102: v1(72.84,98.51) 72.84,98.21 72.62,97.99 JDIMM1.58 ; v1(112.48,85.25) 112.48,85.1 112.77,84.81 113.42,84.81 113.71,85.09 114.07,85.09 114.15,85.17 114.41,85.17 114.5,85.08 114.76,85.08 UC1.M40
DDR_A_DQ23: length 55.7
  IN2 w0.127: v1(76.3,95.67) 76.24,95.73 76.24,95.91 76.6,96.27 78.46,96.27 80.02,94.71 81.39,94.71 84.36,91.75 91.32,91.75 91.44,91.88 91.44,92.32 91.57,92.45 91.83,92.45 91.95,92.32 91.95,91.88 92.08,91.75 92.28,91.75 92.98,92.45 93.26,92.45 93.39,92.32 93.39,92.14 92.87,91.62 92.87,91.44 93.05,91.26 93.23,91.26 93.75,91.79 93.93,91.79 94.11,91.61 94.11,91.43 93.59,90.9 93.59,90.72 93.77,90.55 93.95,90.55 94.47,91.07 94.65,91.07 94.83,90.89 94.83,90.71 94.31,90.19 94.31,90.01 94.67,89.64 95.17,89.64 95.3,89.77 95.3,90.53 95.43,90.66 95.68,90.66 95.81,90.53 95.81,89.77 95.94,89.64 103.46,89.64 104.58,88.53 107.1,88.53 107.77,87.86 108.71,87.86 110.86,85.71 v1(110.86,85.44)
  BOTTOM w0.102: UC1.M41 113.76,84.86 113.51,84.6 112.27,84.6 111.87,85 111.87,85.47 111.72,85.62 111.04,85.62 v1(110.86,85.44) ; v1(76.3,95.67) 76.36,95.67 78.43,97.74 JDIMM1.59
DDR_A_DQ24: length 50.5
  IN2 w0.127: v1(72.84,94.99) 72.84,94.02 73.06,93.79 73.29,93.79 73.42,93.91 73.42,94.33 73.55,94.46 73.8,94.46 73.93,94.33 73.93,93.91 74.05,93.79 77.88,93.79 78.44,93.22 78.44,92.79 79.84,91.39 81.23,91.39 86.14,86.48 100.78,86.48 101.8,85.46 107.54,85.46 v1(107.55,85.47)
  BOTTOM w0.102: v1(72.84,94.99) JDIMM1.70 ; v1(107.55,85.47) 107.67,85.35 107.67,85.17 108.83,84.01 109.54,84.01 109.65,84.01 111.39,84.01 111.81,83.59 113.4,83.59 113.43,83.56 113.54,83.56 113.55,83.55 114.03,83.55 114.15,83.43 114.41,83.43 UC1.R40
DDR_A_DQ25: length 54
  IN2 w0.127: v1(112.42,83.05) 112.27,82.9 112.27,82.11 112.8,81.57 114.77,81.57 114.9,81.7 114.9,82.27 114.77,82.4 114.39,82.4 114.26,82.53 114.26,82.86 114.39,82.99 114.77,82.99 114.9,83.11 114.9,83.54 114.2,84.24 111.67,84.24 111.1,84.81 107.23,84.81 107.05,84.99 101.66,84.99 100.6,86.05 85.96,86.05 81.63,90.38 81.05,90.96 79.53,90.96 79.41,91.09 79.41,91.09 77.93,92.57 77.93,93.01 77.58,93.36 v1(77.43,93.36)
  BOTTOM w0.102: v1(112.42,83.05) 112.72,82.75 113.33,82.75 113.47,82.89 114.07,82.89 114.15,82.97 114.41,82.97 114.5,82.88 114.76,82.88 UC1.T40 ; JDIMM1.71 78.32,94.74 77.43,93.85 v1(77.43,93.36)
DDR_A_DQ26: length 53.5
  IN2 w0.127: v1(76.52,90.27) 76.2,89.95 76.2,89.25 76.9,88.55 77.93,88.55 78.17,88.31 78.17,87.92 78.3,87.79 78.7,87.79 78.83,87.92 78.83,88.16 78.96,88.28 80.21,88.28 80.37,88.12 80.37,87.94 79.89,87.46 79.89,87.28 80.07,87.1 80.25,87.1 80.73,87.58 80.91,87.58 81.09,87.4 81.09,87.22 80.89,87.02 80.89,86.85 81.07,86.67 81.25,86.67 81.45,86.86 81.63,86.86 81.79,86.7 81.79,86.52 81.6,86.32 81.6,86.14 81.78,85.96 81.95,85.96 82.15,86.16 82.33,86.16 82.51,85.98 82.51,85.8 82.24,85.53 82.24,85.35 82.42,85.17 82.6,85.17 82.87,85.44 83.05,85.44 83.23,85.26 83.23,85.08 82.96,84.81 82.96,84.63 83.14,84.45 83.32,84.45 83.55,84.68 83.81,84.68 83.99,84.5 83.99,84.32 83.73,84.06 83.73,83.88 84.86,82.75 105.3,82.75 105.89,82.16 108.94,82.16 109.19,81.91 109.84,81.91 110.78,80.98 111.27,80.98 111.7,81.4 v1(111.7,81.43)
  BOTTOM w0.102: v1(111.7,81.43) 112.08,81.04 112.5,81.04 112.8,81.34 114.04,81.34 114.15,81.23 114.41,81.23 UC1.W40 ; v1(76.52,90.27) 76.52,90.33 77.92,91.74 JDIMM1.83
DDR_A_DQ27: length 50.2
  IN2 w0.127: v1(112.69,80.71) 112.69,80.58 112.24,80.13 109.31,80.13 108.32,81.12 95.18,81.12 94.84,81.47 86.2,81.47 85.95,81.72 85.63,81.72 85.51,81.59 85.51,81.42 85.38,81.29 84.62,81.29 79.65,86.27 77.15,86.27 72.8,90.62 v1(72.8,90.97)
  BOTTOM w0.102: JDIMM1.84 72.63,91.49 72.8,91.32 v1(72.8,90.97) ; UC1.Y40 114.74,80.7 114.48,80.7 114.42,80.76 114.14,80.76 113.96,80.58 112.81,80.58 v1(112.69,80.71)
DDR_A_DQ28: length 50.2
  IN2 w0.127: v1(109.4,85.41) 109.13,85.41 107.87,86.66 101.94,86.66 99.93,88.68 93.31,88.68 92.86,89.12 85.38,89.12 81.76,92.75 79.94,92.75 79.48,93.21 79.48,93.65 78.15,94.98 75.66,94.98 75.53,94.85 75.53,94.68 75.4,94.55 75.15,94.55 75.02,94.68 75.02,94.85 74.9,94.98 73.58,94.98 72.89,95.67 v1(72.89,95.72)
  BOTTOM w0.102: UC1.P40 114.76,83.98 114.5,83.98 114.41,84.07 114.14,84.07 114.06,83.99 113.75,83.99 113.74,83.99 111.98,83.99 111.52,84.45 110,84.45 109.4,85.06 v1(109.4,85.41) ; v1(72.89,95.72) 72.63,95.99 JDIMM1.66
DDR_A_DQ29: length 53.6
  IN2 w0.127: v1(77.34,94.53) 77.41,94.53 77.41,94.52 77.98,94.52 78.99,93.51 78.99,92.94 79.7,92.23 81.55,92.23 85.13,88.64 92.73,88.64 93.2,88.18 94.64,88.18 94.77,88.05 94.77,87.19 94.9,87.06 95.15,87.06 95.28,87.19 95.28,88.11 95.4,88.24 95.66,88.24 95.79,88.11 95.79,87.19 95.91,87.06 96.17,87.06 96.29,87.19 96.29,88.12 96.42,88.25 96.67,88.25 96.8,88.12 96.8,87.19 96.93,87.06 97.18,87.06 97.31,87.19 97.31,88.12 97.44,88.25 97.69,88.25 97.82,88.12 97.82,87.19 97.94,87.06 98.2,87.06 98.33,87.19 98.33,87.92 98.45,88.05 98.64,88.05 98.77,87.92 98.77,87.19 98.9,87.06 99.28,87.06 99.4,87.19 99.4,87.48 99.53,87.61 99.72,87.61 99.85,87.48 99.85,87.35 100.14,87.06 100.82,87.06 101.9,85.98 107.89,85.98 108.44,85.43 v1(108.51,85.43)
  BOTTOM w0.102: UC1.P41 113.63,83.76 113.6,83.79 111.89,83.79 111.44,84.25 109.65,84.25 109.37,84.25 108.51,85.11 v1(108.51,85.43) ; JDIMM1.67 78.18,95.74 77.34,94.9 77.34,94.53 v1(77.34,94.53)
DDR_A_DQ30: length 53.5
  IN2 w0.127: v1(111.09,81.41) 111.09,81.47 111.21,81.6 111.31,81.6 111.66,81.95 111.66,82.19 111.5,82.35 109.49,82.35 109.16,82.67 106.11,82.67 105.6,83.19 86.04,83.19 80.51,88.72 78.39,88.72 78.15,88.95 78.15,89.13 78.29,89.26 78.29,89.44 78.11,89.62 77.93,89.62 77.79,89.49 77.61,89.49 77.09,90.01 77.09,90.56 76.96,90.69 76.18,90.69 75.82,90.33 74.78,90.33 74.36,90.75 74.36,91.22 74.51,91.37 76.15,91.37 76.36,91.16 v1(76.52,91.16)
  BOTTOM w0.102: JDIMM1.79 78.16,92.74 76.77,91.35 76.71,91.35 v1(76.52,91.16) ; UC1.V40 114.71,81.56 114.37,81.9 114.19,81.9 114.06,81.77 112.6,81.77 112.56,81.81 111.49,81.81 v1(111.09,81.41)
DDR_A_DQ31: length 50.2
  IN2 w0.127: v1(112.29,81.42) 112.29,81.2 111.65,80.56 109.61,80.56 108.62,81.56 105.54,81.56 104.78,82.32 84.2,82.32 81.15,85.37 81.15,86.01 80.9,86.27 80.26,86.27 79.38,87.15 78.92,87.15 78.8,87.03 78.8,86.83 78.67,86.7 78.27,86.7 78.14,86.83 78.14,87.03 78.01,87.15 77.35,87.15 72.8,91.7 72.8,91.88 v1(72.9,91.98)
  BOTTOM w0.102: v1(112.29,81.42) 112.35,81.42 112.47,81.54 114.11,81.54 114.13,81.56 UC1.V41 ; v1(72.9,91.98) 72.9,92.21 72.62,92.49 JDIMM1.80
DDR_A_DQ32: length 52.1
  IN2 w0.127: v1(73.15,67.47) 72.77,67.85 72.77,68.74 73.07,69.04 78.02,69.04 78.31,69.33 78.31,70.93 80.38,73.01 81.46,73.01 88.09,79.64 106.77,79.64 108.06,78.35 109.53,78.35 v1(110.22,77.66)
  BOTTOM w0.102: JDIMM1.174 72.67,66.99 v1(73.15,67.47) ; UC1.AD41 113.63,78.25 113.31,77.93 112.12,77.93 111.56,77.38 110.84,77.38 v2(110.69,77.53) 110.56,77.66 v1(110.22,77.66)
DDR_A_DQ33: length 55.5
  IN2 w0.127: v1(109.27,77.66) 109.27,77.66 108.14,77.66 106.67,79.13 88.19,79.13 81.64,72.58 80.56,72.58 78.74,70.75 78.74,68.77 78.58,68.61 78.05,68.61 77.92,68.48 77.92,68.04 77.79,67.92 77.54,67.92 77.41,68.04 77.41,68.48 77.28,68.61 77.06,68.61 76.93,68.48 76.93,68.23 76.8,68.11 76.55,68.11 76.42,68.23 76.42,68.48 76.29,68.61 76.04,68.61 75.91,68.48 75.91,68.23 75.79,68.11 75.53,68.11 75.4,68.23 75.4,68.48 75.28,68.61 74.9,68.61 74.38,68.09 74.38,67.73 74.51,67.6 v1(75.95,67.6)
  BOTTOM w0.102: UC1.AD40 114.76,78.03 114.5,78.03 114.41,77.94 114.14,77.94 114.06,78.02 113.75,78.02 113.46,77.73 112.2,77.73 111.65,77.18 109.75,77.18 v1(109.27,77.66) ; v1(75.95,67.6) 76.31,67.24 JDIMM1.173
DDR_A_DQ34: length 55.2
  IN2 w0.127: v1(82.04,65.46) 82.04,65.48 82.38,65.81 82.38,66.29 82.04,66.63 82.04,67.34 82.27,67.56 82.46,67.56 82.58,67.69 82.58,67.88 82.46,68 82.17,68 82.04,68.13 82.04,69.06 89.01,76.03 89.58,76.03 89.71,75.9 89.71,75.34 89.83,75.21 90.09,75.21 90.22,75.34 90.22,75.9 90.34,76.03 90.6,76.03 90.72,75.9 90.72,75.34 90.85,75.21 91.1,75.21 91.23,75.34 91.23,75.9 91.36,76.03 91.95,76.03 92.07,75.9 92.07,75.56 92.26,75.38 92.44,75.38 92.62,75.56 92.62,75.81 92.84,76.03 93.09,76.03 93.24,75.88 93.7,75.88 93.83,76.01 94.01,76.01 94.21,75.81 94.21,75.34 94.34,75.21 94.59,75.21 94.72,75.34 94.72,75.9 94.84,76.03 95.1,76.03 95.22,75.9 95.22,75.34 95.35,75.21 95.61,75.21 95.73,75.34 95.73,75.9 95.86,76.03 96.47,76.03 96.62,76.18 96.62,76.63 96.71,76.73 96.89,76.73 97.02,76.6 97.02,75.34 97.15,75.21 97.4,75.21 97.53,75.34 97.53,76.6 97.65,76.73 97.99,76.73 98.14,76.58 98.14,76.45 98.27,76.32 98.45,76.32 98.59,76.45 98.59,76.6 98.71,76.73 104.63,76.73 105.7,75.66 106.05,75.66 106.33,75.94 106.81,75.94 107.61,75.15 110.99,75.15 v1(111.81,75.97)
  BOTTOM w0.102: JDIMM1.187 80.85,63.74 82.04,64.93 v1(82.04,65.46) ; UC1.AH41 113.63,76.06 113.32,75.74 112.04,75.74 v1(111.81,75.97)
DDR_A_DQ35: length 52.4
  IN2 w0.127: v1(73.27,64.51) 73.32,64.56 82.35,64.56 83.92,66.13 83.92,69.72 88.55,74.35 97.76,74.35 99.27,75.86 100.99,75.86 102.06,74.79 106.5,74.79 v1(106.83,74.46)
  BOTTOM w0.102: UC1.AH40 114.76,75.83 114.5,75.83 114.42,75.75 114.13,75.75 114.06,75.82 113.75,75.82 113.46,75.54 110.58,75.54 109.55,74.51 109.1,74.51 109.04,74.44 106.85,74.44 v1(106.83,74.46) ; v1(73.27,64.51) 72.75,63.99 JDIMM1.186
DDR_A_DQ36: length 52.5
  IN2 w0.127: v1(112.38,78.55) 112.38,78.85 111.92,79.31 109.26,79.31 107.98,80.59 87.82,80.59 81.1,73.87 79.63,73.87 78.27,72.51 75.98,72.51 75.47,72 74.95,72 74.65,71.7 74.65,70.89 74.04,70.27 74.04,69.69 74.23,69.5 v1(74.31,69.5)
  BOTTOM w0.102: UC1.AB40 114.98,78.69 114.8,78.5 114.51,78.5 114.44,78.57 114.13,78.57 114.06,78.5 113.48,78.5 113.38,78.41 112.52,78.41 v1(112.38,78.55) ; JDIMM1.170 72.79,67.99 v1(74.31,69.5)
DDR_A_DQ37: length 55.2
  IN2 w0.127: v1(74.96,69.5) 74.96,70.58 75.56,71.18 75.82,71.18 75.95,71.05 75.95,70.06 76.07,69.94 76.33,69.94 76.45,70.06 76.45,71.05 76.58,71.18 76.84,71.18 76.96,71.05 76.96,70.05 77.09,69.92 77.34,69.92 77.47,70.05 77.47,71.05 77.6,71.18 77.94,71.18 80.21,73.44 81.28,73.44 88,80.16 107.68,80.16 108.98,78.86 111.2,78.86 v1(111.66,78.4)
  BOTTOM w0.102: v1(74.96,69.5) 74.96,69.22 75.94,68.24 JDIMM1.169 ; v1(111.66,78.4) 112.26,78.99 112.78,78.99 112.98,79.19 113.31,79.19 113.37,79.13 114.04,79.13 114.18,78.99 114.45,78.99 UC1.AC40
DDR_A_DQ38: length 55.4
  IN2 w0.102: 110.67,77.22 110.99,77.22 111.09,77.12 111.09,76.02 v1(111.05,75.98)
  IN2 w0.127: 110.67,77.22 110.26,77.22 110.07,77.03 110.07,75.92 109.86,75.7 107.81,75.7 107.14,76.37 105.79,76.37 105.01,77.16 96.48,77.16 96.03,76.7 89.07,76.7 81.26,68.89 81.26,68.45 81.55,68.15 81.55,67.97 81.37,67.8 81.19,67.8 80.9,68.09 80.72,68.09 80.54,67.91 80.54,67.73 81.61,66.66 81.61,66.48 81.43,66.3 81.25,66.3 80.22,67.34 79.97,67.34 79.79,67.16 79.79,66.98 80.5,66.27 80.5,66.09 80.32,65.91 80.14,65.91 79.43,66.62 79.25,66.62 78.57,65.94 78.57,65.76 78.82,65.5 v1(80.58,65.5)
  BOTTOM w0.102: v1(111.05,75.98) 111.43,76.36 112.02,76.36 112.58,76.92 114,76.92 114.01,76.92 114.06,76.92 114.07,76.92 114.08,76.92 114.15,76.84 114.41,76.84 114.5,76.93 114.76,76.93 UC1.AF40 ; v1(80.58,65.5) 80.58,65.48 79.84,64.74 JDIMM1.183
DDR_A_DQ39: length 52.7
  IN2 w0.127: v1(112.39,76.19) 112.39,76 111.01,74.61 107.38,74.61 106.77,75.22 102.26,75.22 101.19,76.29 99.09,76.29 97.58,74.78 88.37,74.78 83.03,69.44 83.03,65.85 82.17,65 73.81,65 v1(73.27,65.53)
  BOTTOM w0.102: v1(73.27,65.53) 72.73,64.99 JDIMM1.182 ; v1(112.39,76.19) 112.58,76.01 113.29,76.01 113.54,76.26 113.58,76.29 114.06,76.29 114.16,76.38 114.41,76.38 UC1.AG40
DDR_A_DQ40: length 57.5
  IN2 w0.127: v1(76.71,62.14) 76.71,62.02 77.03,61.69 77.79,61.69 77.92,61.82 77.92,62.45 78.13,62.66 81.72,62.66 81.85,62.79 81.85,62.96 81.97,63.08 82.23,63.08 82.36,62.96 82.36,62.79 82.48,62.66 82.7,62.66 83.03,62.99 83.21,62.99 83.35,62.84 83.53,62.84 83.71,63.02 83.71,63.2 83.57,63.35 83.57,63.53 83.75,63.71 83.92,63.71 84.07,63.56 84.25,63.56 84.43,63.74 84.43,63.92 84.28,64.07 84.28,64.25 86.03,65.99 86.03,69.85 88.18,72 91.03,72 91.38,72.35 91.84,72.35 91.97,72.23 91.97,71.68 92.1,71.55 92.35,71.55 92.48,71.68 92.48,71.77 92.6,71.9 92.86,71.9 92.99,71.77 92.99,71.68 93.11,71.55 93.37,71.55 93.49,71.68 93.49,71.77 93.62,71.9 93.87,71.9 94,71.77 94,71.68 94.13,71.55 94.38,71.55 94.51,71.68 94.51,71.77 94.64,71.9 94.89,71.9 95.02,71.77 95.02,71.68 95.14,71.55 95.68,71.55 95.81,71.68 95.81,72.23 95.94,72.35 96.19,72.35 96.32,72.23 96.32,71.68 96.45,71.55 96.68,71.55 96.8,71.68 96.8,72.23 96.93,72.35 97.88,72.35 98.01,72.48 98.01,72.62 98.31,72.92 99.09,72.92 99.21,73.05 99.21,73.36 99.37,73.51 99.57,73.51 99.72,73.36 99.72,73.05 99.85,72.92 100.03,72.92 100.16,73.05 100.16,74.03 100.28,74.16 100.54,74.16 100.67,74.03 100.67,73.05 100.79,72.92 101.15,72.92 101.24,73.01 104,73.01 104.09,72.92 109.77,72.92 110.6,73.75 v1(110.6,74.13)
  BOTTOM w0.102: JDIMM1.195 77.11,61.74 v1(76.71,62.14) ; v1(110.6,74.13) 111.4,74.93 114.25,74.93 UC1.AK41
DDR_A_DQ41: length 54.3
  IN2 w0.127: v1(111.61,74.13) 111.6,74.13 109.76,72.3 103.95,72.3 103.76,72.49 98.63,72.49 97.19,71.05 88.07,71.05 86.46,69.45 86.46,65.66 86.25,65.44 86.25,64.95 83.53,62.23 78.49,62.23 78.36,62.11 78.36,61.45 78.17,61.26 76.86,61.26 75.05,63.07 73.4,63.07 73.27,62.94 v1(73.27,62.48)
  BOTTOM w0.102: v1(73.27,62.48) 72.78,61.99 JDIMM1.194 ; UC1.AK40 114.76,74.73 114.5,74.73 114.41,74.64 114.15,74.64 114.07,74.72 114.07,74.72 114.06,74.72 112.2,74.72 v1(111.61,74.13)
DDR_A_DQ42: length 57.3
  IN2 w0.127: v1(81.73,59.22) 81.79,59.22 81.79,59.22 84.45,59.22 88.56,63.33 88.9,63.33 89.84,64.27 89.84,66.43 91.23,67.82 105.6,67.82 106.54,68.76 106.54,68.94 106.4,69.08 106.4,69.26 106.58,69.44 106.76,69.44 106.9,69.3 107.08,69.3 107.26,69.48 107.26,69.66 107.24,69.68 107.24,69.86 107.42,70.03 107.6,70.03 107.62,70.02 107.8,70.02 107.88,70.1 109.87,70.1 111.04,71.27 111.04,72.52 111.9,73.38 113.79,73.38 114.01,73.6 114.01,74.84 114.14,74.97 114.84,74.97 115.14,74.67 115.14,73.36 115.15,73.34 115.15,72.9 114.88,72.62 112.21,72.62 111.79,72.2 v1(111.79,72.2)
  BOTTOM w0.102: v1(111.79,72.2) 111.79,72.32 112.26,72.79 114.25,72.79 UC1.AP41 ; v1(81.73,59.22) 81.73,59.34 81.93,59.55 82.54,59.55 82.74,59.34 82.74,58.96 82.52,58.74 JDIMM1.207
DDR_A_DQ43: length 54.5
  IN2 w0.127: v1(112.38,72.23) 112.38,71.72 112.43,71.67 113.19,71.67 113.32,71.55 113.32,71.02 113.19,70.89 111.39,70.89 110.13,69.63 108.02,69.63 105.78,67.39 91.56,67.39 90.94,66.77 90.94,66.01 91.07,65.88 91.07,65.57 90.94,65.44 90.94,64.76 88.91,62.73 88.57,62.73 84.46,58.62 81.77,58.62 81.58,58.81 73.84,58.81 v1(72.94,57.91)
  BOTTOM w0.102: v1(72.94,57.91) 72.36,58.49 JDIMM1.208 ; UC1.AP40 114.71,72.76 114.41,72.45 114.14,72.45 114,72.59 112.73,72.59 v1(112.38,72.23)
DDR_A_DQ44: length 57.4
  IN2 w0.127: v1(109.33,74.13) 109.08,73.87 108.38,73.87 108.17,74.08 107.87,74.08 107.66,73.87 106.12,73.87 105.99,74 105.99,74.13 105.87,74.26 105.61,74.26 105.49,74.13 105.49,74 105.36,73.87 104.82,73.87 104.69,74 104.69,74.13 104.57,74.26 104.31,74.26 104.18,74.13 104.18,74 104.06,73.87 103.41,73.87 103.28,74 103.28,74.13 103.16,74.26 102.9,74.26 102.78,74.13 102.78,74 102.65,73.87 102.23,73.87 100.77,75.33 100.48,75.33 100.36,75.2 100.36,75.15 100.23,75.03 99.98,75.03 99.85,75.15 99.85,75.2 99.72,75.33 99.49,75.33 97.98,73.81 97.61,73.81 97.48,73.69 97.48,73.34 97.36,73.22 97.1,73.22 96.98,73.34 96.98,73.69 96.85,73.81 96.6,73.81 96.47,73.69 96.47,73.34 96.34,73.22 96.09,73.22 95.96,73.34 95.96,73.69 95.83,73.81 95.58,73.81 95.45,73.69 95.45,73.34 95.33,73.22 95.07,73.22 94.94,73.34 94.94,73.69 94.82,73.81 94.56,73.81 94.44,73.69 94.44,73.34 94.31,73.22 94.06,73.22 93.93,73.34 93.93,73.69 93.8,73.81 93.55,73.81 93.42,73.69 93.42,73.34 93.29,73.22 93.04,73.22 92.91,73.34 92.91,73.69 92.79,73.81 92.53,73.81 92.4,73.69 92.4,73.34 92.28,73.22 92.02,73.22 91.43,73.81 90.78,73.81 90.65,73.69 90.65,73.34 90.52,73.22 90.27,73.22 90.14,73.34 90.14,73.69 90.02,73.81 89.76,73.81 89.63,73.69 89.63,73.34 89.51,73.22 89.25,73.22 89.13,73.34 89.13,73.69 89,73.81 88.77,73.81 84.76,69.8 84.76,66.22 82.57,64.03 76.89,64.03 76.68,63.82 76.68,63.57 v1(76.84,63.41)
  BOTTOM w0.102: UC1.AJ41 113.76,75.33 110.67,75.33 109.46,74.13 v1(109.33,74.13) ; v1(76.84,63.41) 76.84,63.28 77.38,62.74 JDIMM1.191
DDR_A_DQ45: length 54.6
  IN2 w0.127: v1(73.27,63.5) 75.23,63.5 76.02,62.71 77.57,62.71 78.37,63.51 78.63,63.51 78.76,63.39 78.76,63.22 78.89,63.1 79.14,63.1 79.27,63.22 79.27,63.39 79.39,63.51 79.65,63.51 79.77,63.39 79.77,63.22 79.9,63.1 80.16,63.1 80.28,63.22 80.28,63.39 80.41,63.51 80.67,63.51 80.79,63.39 80.79,63.22 80.92,63.1 81.17,63.1 81.3,63.22 81.3,63.39 81.43,63.51 82.67,63.51 85.19,66.04 85.19,69.62 88.35,72.78 97.56,72.78 98.52,73.74 98.7,73.74 98.75,73.68 98.93,73.68 99.11,73.86 99.11,74.04 99.05,74.1 99.05,74.28 99.37,74.59 100.89,74.59 102.05,73.44 109.44,73.44 110,73.99 v1(110,74.13)
  BOTTOM w0.102: v1(73.27,63.5) 72.76,62.99 JDIMM1.190 ; v1(110,74.13) 111,75.13 114,75.13 114.15,75.28 114.41,75.28 UC1.AJ40
DDR_A_DQ46: length 57.9
  IN2 w0.127: v1(77.09,59.66) 77.09,59.76 77.22,59.89 77.86,59.89 78.08,59.67 78.52,59.67 79.12,60.28 79.33,60.28 79.45,60.15 79.45,59.8 79.58,59.67 79.84,59.67 79.96,59.8 79.96,60.13 80.09,60.26 84.26,60.26 88.28,64.28 88.59,64.28 88.97,64.66 88.97,65.84 88.85,65.97 88.64,65.97 88.51,66.09 88.51,66.35 88.64,66.47 88.85,66.47 88.97,66.6 88.97,67.06 89.28,67.37 89.28,68.96 89.44,69.12 91.37,69.12 91.54,68.96 91.75,68.96 91.92,69.12 92.26,69.12 92.39,69 92.39,68.81 92.52,68.68 92.77,68.68 92.9,68.81 92.9,69 93.02,69.12 93.28,69.12 93.41,69 93.41,68.81 93.53,68.68 93.79,68.68 93.91,68.81 93.91,69 94.04,69.12 96.53,69.12 96.65,69 96.65,68.81 96.78,68.68 97.03,68.68 97.16,68.81 97.16,69 97.29,69.12 97.54,69.12 97.67,69 97.67,68.81 97.8,68.68 98.05,68.68 98.18,68.81 98.18,69 98.3,69.12 98.56,69.12 98.68,69 98.68,68.81 98.81,68.68 99.07,68.68 99.19,68.81 99.19,69 99.32,69.12 104.92,69.12 105.1,69.3 105.1,69.46 105.49,69.86 105.77,69.86 106.03,70.12 106.03,70.69 106.14,70.8 106.4,70.8 107.03,71.43 109.34,71.43 v1(109.46,71.31)
  BOTTOM w0.102: UC1.AN41 113.88,73.25 111.6,73.25 111.34,73 107.22,73 107.02,72.81 107.02,71.6 107.32,71.31 v1(109.46,71.31) ; JDIMM1.203 77.23,59.74 77.15,59.66 v1(77.09,59.66)
DDR_A_DQ47: length 54.5
  IN2 w0.127: v1(110.41,71.37) 109.71,70.67 107.19,70.67 106.9,70.37 105.22,68.69 100.18,68.69 99.73,68.25 96.53,68.25 96.09,68.69 94.53,68.69 94.08,68.25 91.91,68.25 91.91,68.26 91.62,68.26 91.43,68.45 90.63,68.45 90.33,68.15 90.33,67.81 89.4,66.88 89.4,64.48 88.77,63.84 88.46,63.84 84.35,59.74 80.91,59.74 80.42,59.24 75.03,59.24 74.8,59.48 74.8,60.64 74.67,60.77 73.03,60.77 72.9,60.64 72.9,60.23 v1(73.22,59.92)
  BOTTOM w0.102: v1(110.41,71.37) 110.83,71.79 110.83,72.04 111.78,72.99 114.06,72.99 114.15,73.08 114.41,73.08 UC1.AN40 ; JDIMM1.204 72.79,59.49 v1(73.22,59.92)
DDR_A_DQ48: length 52.4
  IN2 w0.127: v1(109.71,69.09) 109.7,69.09 106.54,65.93 96.67,65.93 95.57,64.83 93.59,64.83 85.81,57.06 83.35,57.06 82.88,56.59 81.41,56.59 80.15,57.85 76.49,57.85 75.76,57.12 74.39,57.12 73.25,55.98 v1(72.84,55.98)
  BOTTOM w0.102: UC1.AT40 114.76,71.43 114.5,71.43 114.41,71.34 114.14,71.34 114.06,71.42 113.75,71.42 113.68,71.35 112.05,71.35 110.87,70.17 110.29,70.17 109.71,69.59 v1(109.71,69.09) ; v1(72.84,55.98) 72.84,56.39 72.73,56.49 JDIMM1.216
DDR_A_DQ49: length 56.1
  IN2 w0.127: v1(81.28,56.11) 80.81,56.57 80.17,56.57 79.98,56.38 79.8,56.38 79.67,56.51 79.67,56.71 80.04,57.08 80.04,57.27 79.95,57.36 77.23,57.36 77.11,57.24 77.11,56.77 77.24,56.63 78.88,56.63 79.21,56.3 79.97,55.54 81.47,55.54 81.64,55.7 82.6,55.7 83.53,56.63 85.99,56.63 93.77,64.4 93.89,64.4 94.01,64.28 94.01,64.02 94.14,63.89 94.33,63.89 94.46,64.02 94.46,64.28 94.59,64.4 95.75,64.4 96.85,65.5 97.03,65.5 97.16,65.37 97.16,65.09 97.29,64.97 97.47,64.97 97.59,65.09 97.59,65.3 97.79,65.5 107.01,65.5 107.18,65.66 107.18,65.95 107.39,66.17 107.68,66.17 107.89,66.38 107.89,66.67 108.11,66.88 108.4,66.88 108.61,67.1 108.61,67.39 108.83,67.6 109.12,67.6 109.33,67.82 109.33,68.11 109.55,68.32 109.84,68.32 110.41,68.9 v1(110.41,69.09)
  BOTTOM w0.102: v1(110.41,69.09) 110.67,68.83 110.86,68.83 111.02,68.99 111.02,69.93 111.16,70.07 111.3,70.07 111.44,69.94 111.58,69.94 111.73,70.08 111.73,70.23 111.59,70.36 111.59,70.5 112.2,71.11 UC1.AU41 ; v1(81.28,56.11) 80.65,56.74 JDIMM1.215
DDR_A_DQ50: length 52.2
  IN2 w0.127: v1(113.97,68.39) 112.11,66.53 112.11,66.53 108.38,62.8 102.11,62.8 101.98,62.68 101.98,62.18 101.86,62.05 101.6,62.05 101.48,62.18 101.48,62.68 101.35,62.8 101,62.8 100.29,62.09 98.76,62.09 97.87,61.2 96.1,61.2 88.83,53.93 84.6,53.93 83.71,53.04 82.75,53.04 82.45,52.74 73.49,52.74 v1(73.27,52.96)
  BOTTOM w0.102: v1(113.97,68.39) 113.97,68.64 UC1.AY40 ; JDIMM1.228 72.74,53.49 v1(73.27,52.96)
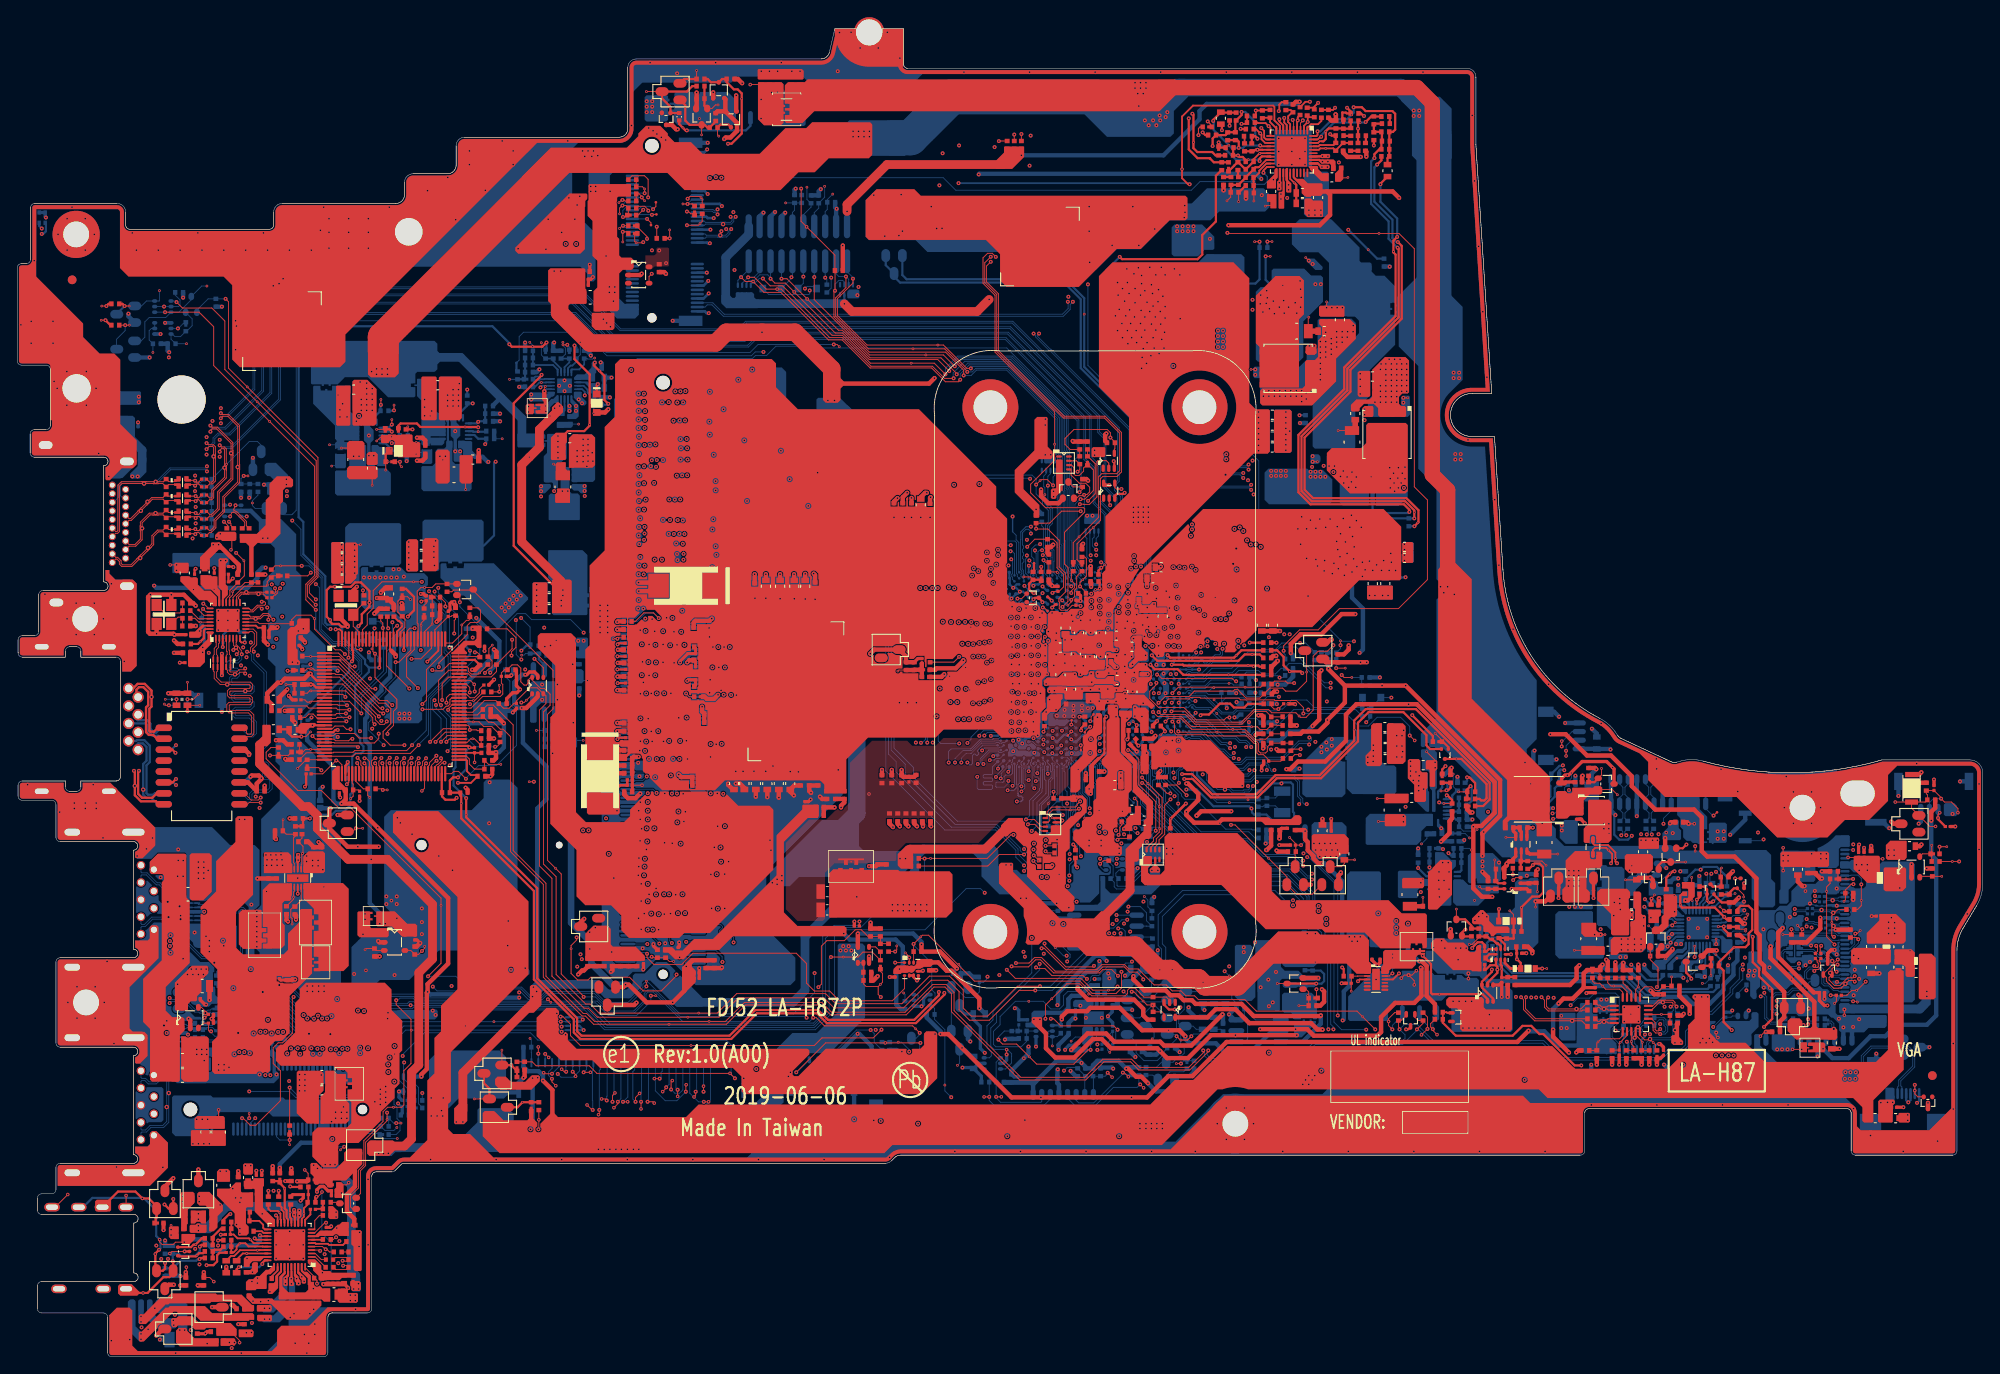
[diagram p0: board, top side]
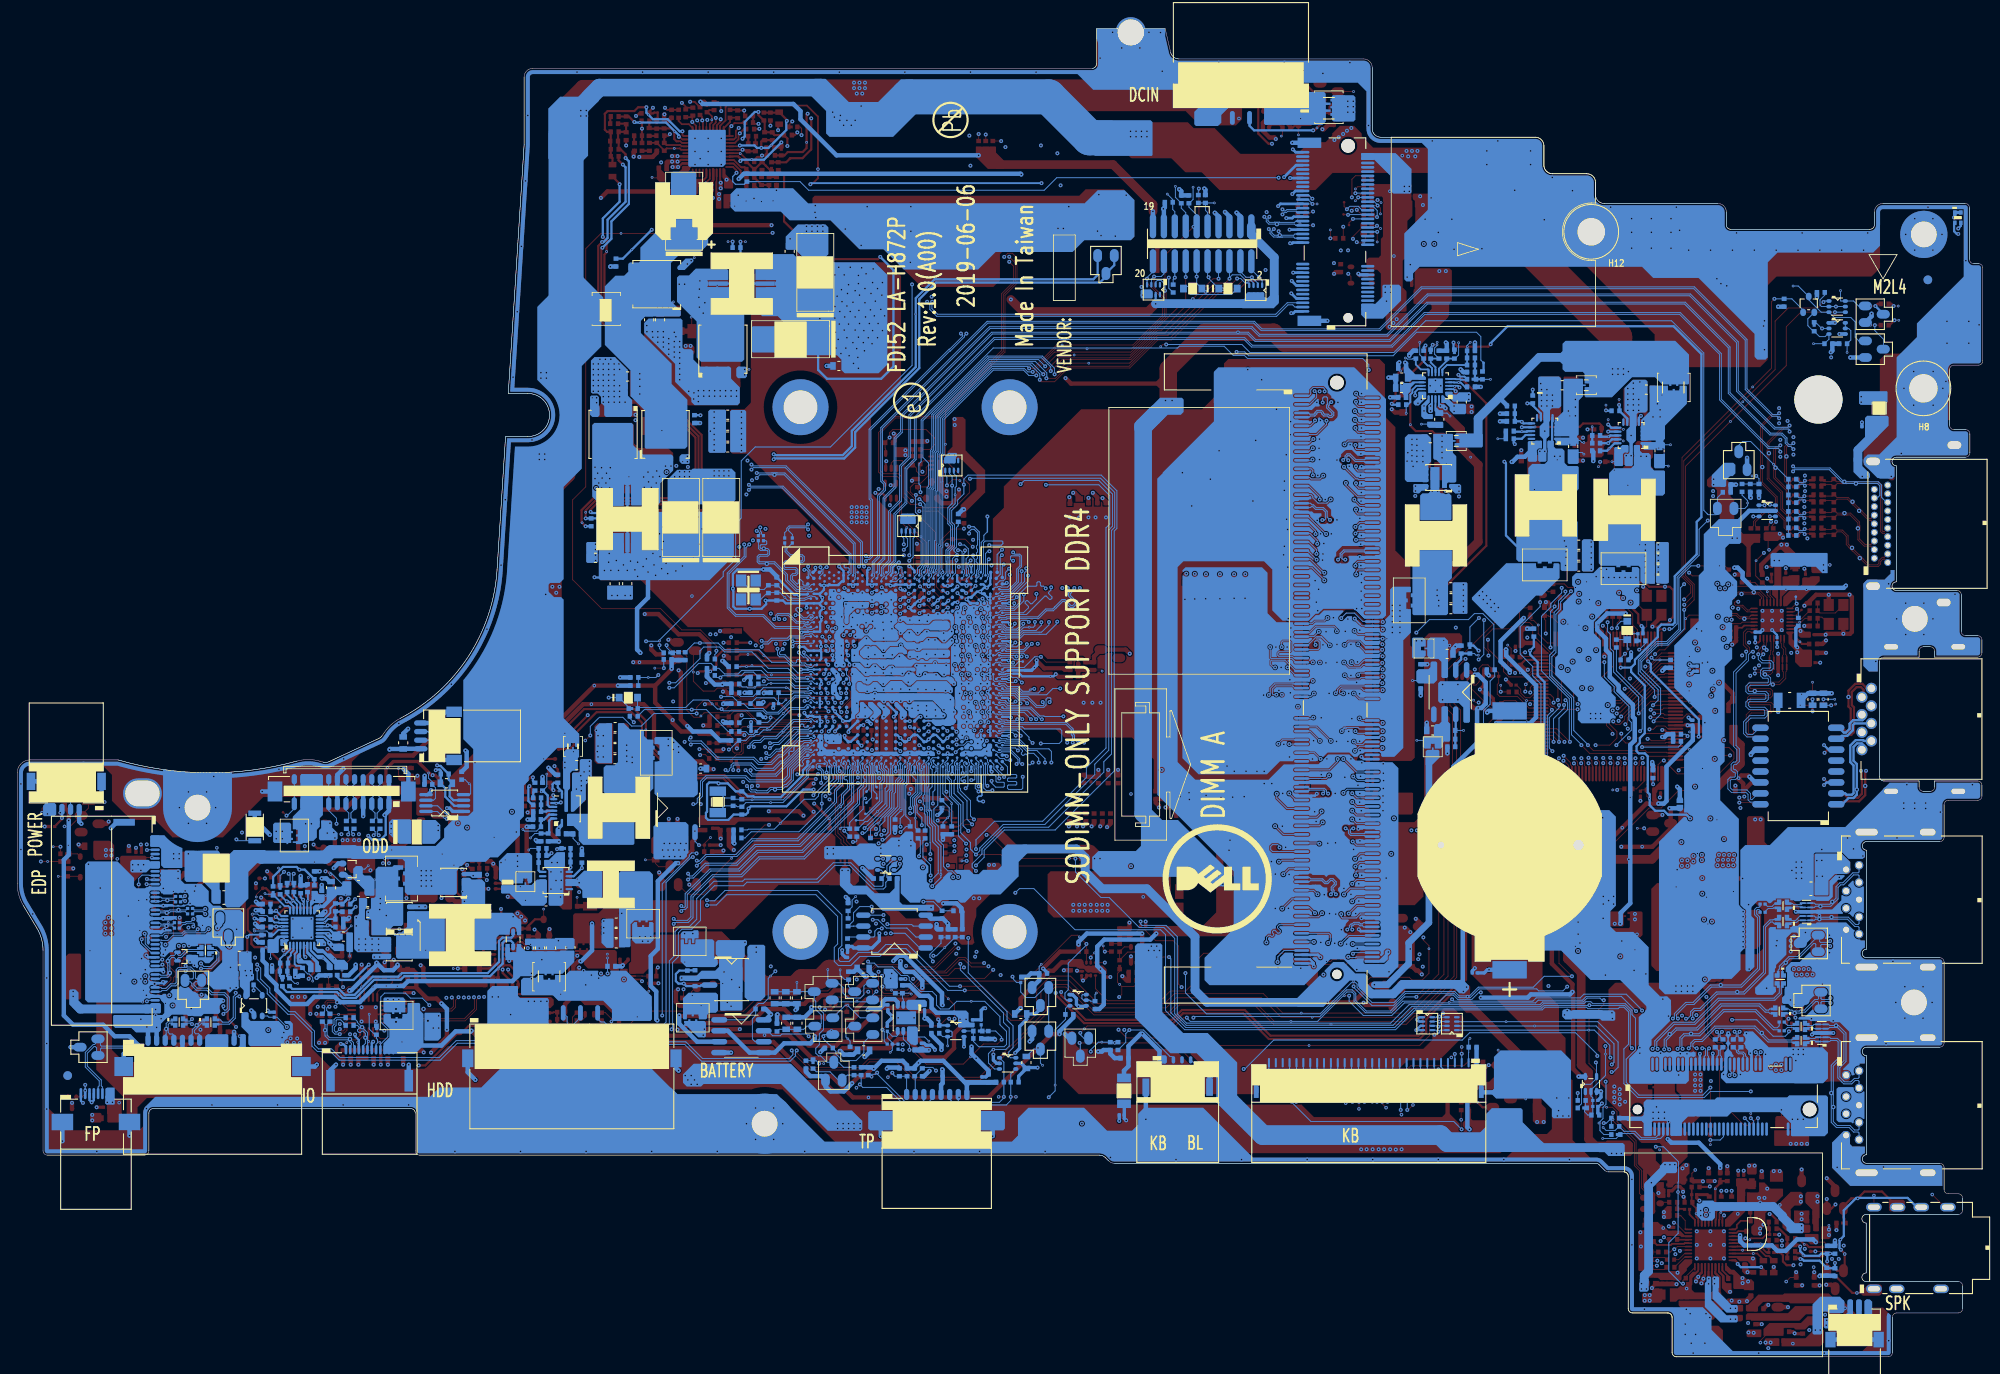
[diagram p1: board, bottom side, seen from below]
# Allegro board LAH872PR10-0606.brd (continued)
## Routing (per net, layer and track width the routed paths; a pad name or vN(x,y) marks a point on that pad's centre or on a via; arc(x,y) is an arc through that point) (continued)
DDR_A_DQ51: length 54.9
  IN2 w0.127: v1(81.41,52.11) 81.41,52.11 81.67,52.11 81.85,51.93 81.85,51.75 81.98,51.62 82.31,51.62 82.64,51.96 82.64,52.32 82.92,52.6 84.2,52.6 84.39,52.8 84.39,53.11 84.78,53.5 89.1,53.5 96.37,60.77 97.4,60.77 97.53,60.64 97.53,60.3 97.66,60.17 98.45,60.17 98.58,60.3 98.58,60.45 98.26,60.77 98.26,60.95 98.45,61.14 98.63,61.14 99.03,60.75 99.36,60.75 99.49,60.87 99.49,61.53 99.61,61.66 99.87,61.66 99.99,61.53 99.99,60.87 100.12,60.75 100.71,60.75 100.83,60.87 100.83,61.63 101,61.79 101.21,61.79 101.34,61.66 101.34,60.87 101.47,60.75 101.85,60.75 101.98,60.87 101.98,61.1 102.17,61.3 102.35,61.3 102.48,61.17 102.48,60.87 102.61,60.75 102.86,60.75 102.99,60.87 102.99,61.17 103.12,61.3 103.34,61.3 103.5,61.14 103.5,60.87 103.63,60.75 103.88,60.75 104.01,60.87 104.01,61.14 104.17,61.3 104.36,61.3 104.52,61.14 104.52,60.87 104.64,60.75 104.9,60.75 105.02,60.87 105.02,61.1 105.15,61.23 105.4,61.23 105.53,61.1 105.53,60.87 105.66,60.75 105.91,60.75 106.04,60.87 106.04,61.02 106.17,61.15 106.42,61.15 106.55,61.02 106.55,60.87 106.67,60.75 107.06,60.75 107.45,61.14 107.45,61.37 106.78,62.04 106.78,62.22 106.93,62.37 107.11,62.37 107.8,61.68 107.98,61.68 108.11,61.81 108.11,62.24 108.24,62.37 108.68,62.37 v1(113.73,67.42)
  BOTTOM w0.102: UC1.BA40 114.53,68.34 113.73,67.54 v1(113.73,67.42) ; v1(81.41,52.11) 80.27,53.24 JDIMM1.229
DDR_A_DQ52: length 55.4
  IN2 w0.127: v1(108.23,69.09) 108.23,68.97 106.12,66.85 96.37,66.85 96.17,66.66 95.99,66.66 95.8,66.85 95.62,66.85 95.49,66.73 95.49,65.98 95.36,65.85 95.11,65.85 94.98,65.98 94.98,66.68 94.86,66.81 94.68,66.81 94.55,66.68 94.55,65.83 94.42,65.7 94.21,65.7 94.08,65.83 94.08,66.69 93.92,66.85 93.7,66.85 93.57,66.73 93.57,66.13 93.44,66 93.19,66 93.06,66.13 93.06,66.73 92.93,66.85 92.71,66.85 92.58,66.73 92.58,66.13 92.45,66 92.27,66 92.15,66.13 92.15,66.54 91.96,66.73 91.69,66.73 91.5,66.54 91.5,66.2 91.73,65.97 91.73,65.46 91.47,65.21 91.47,64.96 91.82,64.61 91.82,64.43 91.39,64 91.11,64 90.93,63.82 90.93,63.54 90.69,63.3 90.41,63.3 90.27,63.16 90.27,62.92 90.08,62.73 89.84,62.73 89.63,62.53 89.63,62.29 89.51,62.16 88.98,62.16 88.85,62.03 88.85,61.86 88.96,61.75 88.96,61.57 88.78,61.39 88.6,61.39 88.38,61.61 88.2,61.61 88.02,61.43 88.02,61.25 88.24,61.03 88.24,60.85 88.06,60.67 87.88,60.67 87.72,60.84 87.43,60.84 86.9,60.31 86.9,60.13 87.03,60 87.03,59.82 86.9,59.7 86.72,59.7 86.59,59.82 86.41,59.82 86.26,59.67 86.26,59.48 86.47,59.27 86.47,59.09 86.29,58.91 86.11,58.91 85.9,59.13 85.72,59.13 85.54,58.95 85.54,58.77 85.76,58.55 85.76,58.37 85.58,58.19 85.4,58.19 85.23,58.35 85.05,58.35 84.71,58 84.07,58 83.99,58.09 81.71,58.09 81.59,57.96 81.59,57.69 81.71,57.57 v1(81.79,57.57)
  BOTTOM w0.102: UC1.AR40 114.41,71.98 114.16,71.98 114.06,71.89 114.06,71.89 114.03,71.86 113.43,71.86 113.38,71.81 111.93,71.81 110.81,70.69 108.52,70.69 108.23,70.4 v1(108.23,69.09) ; v1(81.79,57.57) 81.6,57.57 81.43,57.74 JDIMM1.211
DDR_A_DQ53: length 52.7
  IN2 w0.127: v1(72.9,56.99) 73.19,57.29 73.19,57.29 74.18,58.28 74.72,58.28 74.84,58.15 74.84,57.68 74.97,57.55 75.22,57.55 75.35,57.68 75.35,58.15 75.48,58.28 80.33,58.28 81.5,57.11 82.78,57.11 83.25,57.57 85.57,57.57 92.62,64.62 92.62,65.34 92.85,65.57 93.42,65.57 93.73,65.27 95.39,65.27 96.49,66.36 106.24,66.36 v1(108.97,69.09)
  BOTTOM w0.102: UC1.AT41 114.25,71.63 113.6,71.63 113.56,71.59 112,71.59 110.9,70.48 109.91,70.48 108.97,69.55 v1(108.97,69.09) ; v1(72.9,56.99) 72.4,57.49 JDIMM1.212
DDR_A_DQ54: length 51.9
  IN2 w0.127: v1(113.01,69.37) 113.01,68.16 108.09,63.23 100.82,63.23 100.11,62.52 98.58,62.52 97.69,61.63 95.92,61.63 88.65,54.36 84.42,54.36 83.53,53.47 82.57,53.47 82.27,53.17 74.81,53.17 v1(74.23,53.76)
  BOTTOM w0.102: v1(113.01,69.37) 113.53,69.37 113.72,69.56 114.19,69.56 UC1.AW40 ; v1(74.23,53.76) 73.5,54.49 JDIMM1.224
DDR_A_DQ55: length 55.4
  IN2 w0.127: v1(111.56,67.43) 107.79,63.67 100.19,63.67 100.06,63.54 100.06,63.08 99.93,62.96 99.68,62.96 99.55,63.08 99.55,63.54 99.4,63.7 98.93,63.7 97.32,62.09 94,62.09 86.71,54.79 84.25,54.79 83.35,53.9 82.39,53.9 82.18,53.69 79.27,53.69 78.13,54.83 77.22,54.83 76.93,54.54 76.93,54.14 v1(77.3,53.77)
  BOTTOM w0.102: JDIMM1.225 77.77,54.24 v1(77.3,53.77) ; v1(111.56,67.43) 111.56,66.1 111.69,65.97 113.2,65.97 113.33,66.1 113.33,66.37 113.23,66.48 112.36,66.48 112.26,66.58 112.26,66.78 112.36,66.88 113.23,66.88 113.33,66.98 113.33,67.19 113.23,67.29 112.36,67.29 112.26,67.39 112.26,67.59 112.36,67.7 113.23,67.7 113.33,67.8 113.33,68.61 UC1.AY41
DDR_A_DQ56: length 63.4
  IN2 w0.127: v1(115.66,66.39) 114.91,66.39 107.87,59.35 106.69,59.35 106.12,58.78 96.35,58.78 89.53,51.95 85.7,51.95 84.95,51.21 84.46,51.21 84.36,51.11 84.36,50.99 84.41,50.94 84.41,50.76 84.28,50.63 84.08,50.63 83.78,50.94 83.6,50.94 83.29,50.63 82.78,50.13 81.2,50.13 81.07,50.25 81.07,50.49 80.81,50.75 80.63,50.75 80.43,50.55 80.43,50.25 80.3,50.13 78.45,50.13 78.32,50.25 78.32,50.49 78.2,50.61 78,50.61 77.87,50.49 77.87,50.25 77.75,50.13 77.57,50.13 77.44,50.25 77.44,51.09 77.33,51.2 77.15,51.2 77.06,51.11 77.06,50.25 76.97,50.16 76.74,50.16 76.62,50.29 76.62,51.05 76.55,51.11 76.42,51.11 76.3,50.99 76.3,50.27 76.17,50.14 75.99,50.14 75.92,50.21 75.92,50.67 75.83,50.76 75.63,50.76 75.54,50.67 75.54,50.25 75.41,50.13 75.27,50.13 75.14,50.25 75.14,50.41 75.01,50.54 74.36,50.54 74.24,50.67 74.24,50.83 74.33,50.92 75.28,50.92 75.41,51.05 75.41,51.05 76.02,51.05 76.55,51.58 v1(76.77,51.58)
  BOTTOM w0.102: v1(115.66,66.39) 115.68,66.39 115.88,66.59 UC1.BA38 ; JDIMM1.237 78.26,51.24 78.17,51.15 77.22,51.15 76.77,51.6 v1(76.77,51.58)
DDR_A_DQ57: length 60.4
  IN2 w0.127: v1(115.09,65.87) 115,65.87 108.05,58.92 106.87,58.92 106.3,58.35 96.53,58.35 89.71,51.52 85.87,51.52 84.56,50.2 83.47,50.2 82.96,49.69 75.09,49.69 74.69,50.09 74.2,50.09 74.04,50.25 72.9,50.25 72.74,50.42 72.74,50.8 72.87,50.92 73.71,50.92 74.25,51.47 v1(74.55,51.47)
  BOTTOM w0.102: UC1.AY37 116.43,69.31 116.21,69.08 116.21,68.83 116.11,68.73 116.11,66.62 116.09,66.61 116.09,66.13 115.79,65.83 115.13,65.83 v1(115.09,65.87) ; v1(74.55,51.47) 74.55,51.15 74.42,51.03 72.79,51.03 72.33,51.49 JDIMM1.236
DDR_A_DQ58: length 63.5
  IN2 w0.127: v1(118.36,66.93) 117.73,67.55 117.33,67.55 116.81,68.07 116.62,68.07 116.18,67.63 116.18,67.45 117.21,66.42 117.21,65.33 116.87,64.99 116.87,64.68 113.63,61.45 113.13,61.45 108.79,57.1 108.79,56.25 108.44,55.91 96.64,55.91 90.43,49.69 87.39,49.69 85.39,47.7 82.95,47.7 82.82,47.83 82.82,48.2 82.69,48.32 82.44,48.32 82.31,48.2 82.31,47.83 82.19,47.7 81.89,47.7 81.77,47.83 81.77,48.2 81.64,48.32 81.39,48.32 81.26,48.2 81.26,47.83 81.13,47.7 80.88,47.7 80.75,47.83 80.75,48.2 80.62,48.32 80.37,48.32 80.24,48.2 80.24,47.83 80.12,47.7 79.86,47.7 79.74,47.83 79.74,48.2 79.61,48.32 79.35,48.32 79.23,48.2 79.23,47.83 79.1,47.7 78.85,47.7 78.72,47.83 78.72,48.23 78.63,48.32 78.36,48.32 78.23,48.2 78.23,47.86 78.11,47.74 77.62,47.74 77.49,47.86 77.49,48.11 77.62,48.24 v1(77.72,48.24)
  BOTTOM w0.102: JDIMM1.249 v1(77.72,48.24) ; v1(118.36,66.93) 118.62,66.93 118.72,67.03 118.72,67.25 118.56,67.41 118.31,67.41 118.15,67.57 118.15,68.01 118.15,68.02 118.15,68.57 118.41,68.83 118.41,69.09 118.34,69.17 118.19,69.17 118.08,69.06 UC1.BA34
DDR_A_DQ59: length 60.6
  IN2 w0.127: v1(118.53,67.86) 118.75,67.64 118.75,64.73 114.5,60.49 114.5,60.13 108.98,54.61 97.18,54.61 90.89,48.32 88.05,48.32 86.13,46.4 78.23,46.4 77.86,46.03 75.17,46.03 v1(73.22,47.99)
  BOTTOM w0.102: UC1.BA33 118.53,68.51 v1(118.53,67.86) ; v1(73.22,47.99) JDIMM1.250
DDR_A_DQ60: length 60.2
  IN2 w0.127: v1(114.29,67.25) 114.29,67.22 107.28,60.21 99.24,60.21 99.11,60.08 99.11,59.77 98.99,59.64 97.12,59.64 96.99,59.77 96.99,60.08 96.87,60.21 96.56,60.21 89.32,52.96 85.32,52.96 84.42,52.07 83.51,52.07 82.53,51.09 81.69,51.09 81.14,51.64 80.59,51.64 80.02,52.21 79.73,52.21 79.6,52.08 79.6,51.6 79.48,51.48 79.22,51.48 79.1,51.6 79.1,52.08 78.97,52.21 78.74,52.21 78.61,52.08 78.61,51.61 78.49,51.48 78.31,51.48 78.12,51.67 78.12,52.04 77.95,52.21 73.26,52.21 72.96,52.51 72.32,52.51 72.19,52.38 72.19,52.08 72.32,51.95 73.07,51.95 73.49,51.53 v1(73.68,51.53)
  BOTTOM w0.102: UC1.AY39 114.92,68.89 114.92,68.41 114.35,67.84 114.35,67.31 v1(114.29,67.25) ; JDIMM1.232 72.72,52.49 v1(73.68,51.53)
DDR_A_DQ61: length 63
  IN2 w0.127: v1(115.18,66.96) 115.71,67.5 115.71,68.57 115.53,68.75 114.84,68.75 114.68,68.59 114.68,66.77 108.72,60.81 107.69,59.78 104.17,59.78 104.04,59.65 104.04,59.34 103.91,59.21 103.66,59.21 103.53,59.34 103.53,59.65 103.4,59.78 103.15,59.78 103.02,59.65 103.02,59.34 102.9,59.21 102.64,59.21 102.51,59.34 102.51,59.65 102.39,59.78 102.13,59.78 102.01,59.65 102.01,59.34 101.88,59.21 101.63,59.21 101.5,59.34 101.5,59.65 101.37,59.78 101.12,59.78 100.99,59.65 100.99,59.34 100.86,59.21 100.2,59.21 100.07,59.34 100.07,59.65 99.95,59.78 99.66,59.78 99.53,59.65 99.53,59.33 99.41,59.21 96.17,59.21 89.35,52.38 85.38,52.38 84.63,51.64 83.69,51.64 82.62,50.57 81.6,50.57 80.96,51.21 80.15,51.21 80.02,51.09 80.02,50.71 79.9,50.59 79.72,50.59 79.59,50.71 79.59,50.92 79.46,51.04 79.28,51.04 79.14,50.9 79.14,50.69 79.01,50.57 78.83,50.57 78.7,50.69 78.7,50.92 78.57,51.05 78.13,51.05 v1(77.6,51.58)
  BOTTOM w0.102: UC1.AY38 115.88,69.66 115.66,69.43 115.66,69.18 115.57,69.09 115.57,68.85 115.65,68.75 115.65,67.84 115.45,67.64 114.85,67.64 114.67,67.46 114.67,66.93 114.54,66.8 113.78,66.8 113.71,66.73 113.71,66.3 113.78,66.23 114.7,66.23 115.18,66.71 v1(115.18,66.96) ; v1(77.6,51.58) 78.26,52.24 JDIMM1.233
DDR_A_DQ62: length 63.6
  IN2 w0.127: v1(117.53,67.05) 117.59,66.99 117.59,64.8 113.52,60.73 113.52,60.37 112.76,59.61 112.58,59.61 112.34,59.86 112.16,59.86 111.98,59.68 111.98,59.5 112.22,59.25 112.22,59.07 112.09,58.94 111.82,58.94 111.62,59.14 111.44,59.14 111.26,58.96 111.26,58.78 111.5,58.54 111.5,58.36 111.38,58.23 111.2,58.23 110.95,58.48 110.77,58.48 110.59,58.3 110.59,58.12 110.84,57.87 110.84,57.69 110.71,57.56 110.53,57.56 110.29,57.81 110.11,57.81 109.93,57.63 109.93,57.45 110.17,57.2 110.17,57.02 110.01,56.86 109.83,56.86 109.58,57.1 109.4,57.1 109.22,56.92 109.22,56.74 109.47,56.5 109.47,56.32 108.62,55.47 96.82,55.47 90.53,49.18 87.69,49.18 85.77,47.27 78.26,47.27 78.22,47.3 76.43,47.3 76.07,47.66 v1(76.07,48.1)
  BOTTOM w0.102: JDIMM1.245 76,49.24 75.82,49.06 75.82,48.36 v1(76.07,48.1) ; v1(117.53,67.05) 117.23,67.05 117.13,67.15 117.13,68.25 117.21,68.34 117.21,68.74 117.4,68.92 117.4,68.92 117.53,69.05 UC1.AY35
DDR_A_DQ63: length 60.9
  IN2 w0.127: v1(74.61,48.04) 75.78,46.87 78.04,46.87 78.08,46.83 85.95,46.83 87.87,48.75 90.71,48.75 97,55.04 108.8,55.04 113.95,60.19 113.95,60.55 118.18,64.78 v1(118.18,66.1)
  BOTTOM w0.102: v1(74.61,48.04) 73.67,48.99 JDIMM1.246 ; UC1.AY34 117.86,69.43 117.86,69.2 117.84,69.16 117.77,69.09 117.77,68.83 117.93,68.66 117.93,66.35 v1(118.18,66.1)
DDR_A_DQS0: length 70.6
  IN2 w0.147: v1(117.79,96.52) 117.61,96.34 117.41,96.34 117.26,96.48 117.26,96.7 117.13,96.83 117.13,97.04 117.28,97.19 117.95,97.19 118.27,97.5 118.27,97.95 117.95,98.26 117.28,98.26 117.13,98.41 117.13,99.12 111.23,105.02 110.03,105.02 102.89,112.17 97.03,112.17 96.72,111.85 96.72,111.36 96.57,111.21 96.13,111.21 95.98,111.36 95.98,111.85 95.67,112.17 92.96,112.17 92.82,112.31 92.82,112.68 92.5,112.99 91.83,112.99 91.51,112.68 91.51,112.31 91.36,112.17 90.59,112.17 90.3,111.87 90.3,111.31 90.2,111.21 83.76,111.21 81.97,112.99 79.63,112.99 78.34,111.7 76.61,111.7 75.91,111 v1(75.7,111)
  BOTTOM w0.102: 116.61,95.03 116.59,95 116.59,91.51 116.74,91.35 116.74,91.07 116.64,90.97 116.64,90.74 116.98,90.4 UC1.B36
  BOTTOM w0.114: v1(75.7,111) 75.83,111 75.95,110.89 75.95,110.67 76.04,110.58 76.04,110.42 75.42,109.8 75.42,109.46 75.65,109.22 75.99,109.22 76.15,109.39 76.58,109.39 76.82,109.62 76.82,109.72 76.93,109.83 77.27,109.83 77.39,109.72 77.39,109.62 77.62,109.39 78.15,109.39 78.29,109.24 JDIMM1.13 ; 116.61,95.03 116.61,95.91 117.22,96.52 v1(117.79,96.52)
DDR_A_DQS1: length 57.8
  IN2 w0.147: v1(73.74,104.24) 73.75,104.24 73.9,104.39 73.9,104.71 74.38,105.19 80.02,105.19 80.41,105.59 82.97,105.59 84.71,103.85 88.07,103.85 88.4,104.18 89.21,104.18 89.54,103.85 90.11,103.85 90.44,104.18 91.25,104.18 91.58,103.85 92.16,103.85 92.49,104.18 93.29,104.18 93.63,103.85 94.2,103.85 94.53,104.18 95.34,104.18 95.67,103.85 96.24,103.85 96.57,104.18 97.38,104.18 97.71,103.85 98.24,103.85 99.33,102.76 102.29,102.76 103.63,101.42 104.03,101.42 106.06,99.38 106.49,99.38 111.56,94.31 111.56,93.82 112.1,93.29 112.44,93.29 v1(112.68,93.52)
  BOTTOM w0.102: v1(112.68,93.52) 112.47,93.32 111.91,93.32 111.69,93.1 111.69,91.87 112.06,91.5 112.06,90.06 113.11,89.01 114.1,89.01 114.4,88.71 UC1.E40
  BOTTOM w0.114: JDIMM1.34 71.75,103.99 71.83,104.06 71.83,104.08 71.84,104.09 72.92,104.09 73.6,104.77 73.78,104.77 73.9,104.66 73.9,104.4 v1(73.74,104.24)
DDR_A_DQS2: length 56.3
  IN2 w0.147: v1(76.75,97.29) 76.7,97.24 76.44,97.24 76.29,97.39 76.29,97.66 76.38,97.75 79.25,97.75 80.33,96.67 81.27,96.67 84.31,93.63 93.47,93.63 95.47,91.63 97.09,91.63 97.23,91.48 97.23,90.93 97.55,90.62 98.23,90.62 98.54,90.93 98.54,91.48 98.69,91.63 99.45,91.63 99.6,91.48 99.6,90.93 99.91,90.62 100.59,90.62 100.9,90.93 100.9,91.48 101.05,91.63 101.49,91.63 101.64,91.48 101.64,90.93 101.95,90.62 102.63,90.62 102.95,90.93 102.95,91.48 103.09,91.63 104.31,91.63 105.85,90.09 105.85,89.67 v1(105.56,89.38)
  BOTTOM w0.102: UC1.L40 114.41,85.63 114.15,85.63 114.02,85.76 113.43,85.76 113.36,85.82 109.72,85.82 108.8,86.74 108,86.74 107.68,87.06
  BOTTOM w0.114: v1(76.75,97.29) 76.74,97.28 76.51,97.28 76.39,97.4 76.39,98.22 76.7,98.52 77.53,98.52 77.86,98.85 78.02,98.85 78.13,98.74 JDIMM1.55 ; 107.68,87.06 106.9,87.84 106.73,87.84 106.02,87.13 105.69,87.13 105.32,87.5 105.32,87.83 106.04,88.54 106.04,88.71 105.88,88.86 105.88,89.07 v1(105.56,89.38)
DDR_A_DQS3: length 51.2
  IN2 w0.147: v1(110.5,82.9) 110.59,82.9 110.59,82.89 110.71,83.01 110.71,83.27 110.56,83.42 106.72,83.42 106.41,83.73 88.23,83.73 87.92,84.04 87.92,84.5 87.77,84.65 87.33,84.65 87.18,84.5 87.18,84.04 86.87,83.73 86.38,83.73 80.85,89.26 79.24,89.26 76.77,91.73 76.56,91.73 76.09,92.2 75.53,92.2 75.3,91.98 74.86,91.98 74.55,92.29 74.55,92.39 74.25,92.69 v1(74.08,92.69)
  BOTTOM w0.102: v1(110.5,82.9) 110.59,82.9 110.59,82.81 111.36,82.04 113.48,82.04 113.49,82.04 113.51,82.04 113.68,82.21 113.83,82.21 UC1.U41
  BOTTOM w0.114: v1(74.08,92.69) 74.34,92.69 74.47,92.82 74.47,93.29 74.17,93.59 71.84,93.59 71.74,93.49 JDIMM1.76
DDR_A_DQS4: length 55.3
  IN2 w0.147: v1(108.43,76.12) 108.68,76.36 108.68,76.66 108.51,76.83 107.74,76.83 107.65,76.92 106.08,76.92 105.25,77.74 96.3,77.74 95.8,77.24 94.78,77.24 94.47,77.56 94.47,77.72 94.32,77.87 93.88,77.87 93.73,77.72 93.73,77.56 93.42,77.24 92.74,77.24 92.43,77.56 92.43,77.72 92.28,77.87 91.84,77.87 91.69,77.72 91.69,77.56 91.38,77.24 90.7,77.24 90.38,77.56 90.38,77.72 90.24,77.87 89.8,77.87 89.65,77.72 89.65,77.56 89.33,77.24 88.84,77.24 88.3,76.7 87.85,76.7 87.8,76.75 87.59,76.75 87.28,76.44 87.28,76.23 87.33,76.17 87.33,75.73 86.85,75.25 86.41,75.25 86.35,75.3 86.15,75.3 85.83,74.99 85.83,74.78 85.89,74.73 85.89,74.29 85.41,73.81 84.96,73.81 84.91,73.86 84.7,73.86 84.39,73.55 84.39,73.34 84.44,73.29 84.44,72.84 83.96,72.36 83.52,72.36 83.47,72.42 83.26,72.42 82.94,72.1 82.94,71.89 83,71.84 83,71.4 82.11,70.51 80.34,70.51 80,70.16 80,68.13 78.13,66.27 76.77,66.27 76.52,66.02 76.52,65.62 v1(76.66,65.48)
  BOTTOM w0.102: UC1.AF41 114.25,77.13 114.15,77.13 114.15,77.13 113.93,77.13 113.92,77.12 112.46,77.12 111.9,76.57 111.05,76.57 109.99,75.51 109.11,75.51 108.85,75.77 108.85,76.46 108.69,76.62 108.39,76.62 108.29,76.52 108.29,76.27 v1(108.43,76.12)
  BOTTOM w0.114: v1(76.66,65.48) 76.47,65.67 76.47,65.77 76.59,65.88 78.27,65.88 78.3,65.89 78.44,65.74 JDIMM1.179
DDR_A_DQS5: length 54.9
  IN2 w0.147: v1(105.75,71.4) 105.5,71.15 105.49,71.15 105.49,70.63 104.53,69.67 88.82,69.67 88.53,69.38 88.53,67.39 87.97,66.83 87.97,64.87 83.94,60.84 78.92,60.84 78.51,60.43 76.42,60.43 74.93,61.92 74.06,61.92 73.91,61.78 73.91,61.57 v1(74.04,61.44)
  BOTTOM w0.102: 105.84,72.27 105.84,72.28 105.92,72.36 105.92,72.92 106.54,73.54 113.68,73.54 113.75,73.61 114.07,73.61 114.14,73.54 114.41,73.54 114.5,73.63 114.76,73.63 UC1.AM40
  BOTTOM w0.114: 105.84,72.27 105.75,72.19 105.75,71.41 v1(105.75,71.4) ; JDIMM1.200 71.7,60.49 71.83,60.61 73.46,60.61 73.7,60.85 73.7,61.2 73.93,61.44 v1(74.04,61.44)
DDR_A_DQS6: length 55.6
  IN2 w0.147: v1(75.75,53.77) 75.6,53.92 75.6,54.17 75.78,54.34 75.78,54.79 75.37,55.2 75.37,55.41 75.68,55.72 75.89,55.72 76.3,55.31 76.75,55.31 76.81,55.37 78.35,55.37 79.45,54.28 81.99,54.28 82.16,54.44 83.13,54.44 84.02,55.34 86.48,55.34 93.77,62.63 97.1,62.63 98.71,64.24 107.54,64.24 111.13,67.84 111.28,67.84 111.94,68.5 111.94,68.6 v1(112.27,68.92)
  BOTTOM w0.102: UC1.AV40 114.5,70.33 114.41,70.24 114.17,70.24 114.05,70.34 113,70.34 112.11,69.45 112.11,69.08 v1(112.27,68.92)
  BOTTOM w0.114: JDIMM1.221 78.26,55.24 78.14,55.36 76.79,55.36 76.45,55.01 76.12,55.01 75.75,55.38 75.59,55.38 75.35,55.14 75.35,54.98 75.71,54.61 75.71,54.27 75.6,54.16 75.6,53.93 v1(75.75,53.77)
DDR_A_DQS7: length 59.7
  IN2 w0.147: v1(73.26,49.67) 73.41,49.52 73.41,49.18 73.73,48.87 74.51,48.87 74.84,48.54 75.63,48.54 75.96,48.87 83.34,48.87 83.84,49.37 84.9,49.37 86.2,50.67 90.03,50.67 96.87,57.52 97.15,57.52 97.3,57.37 97.3,57.2 97.61,56.88 98.24,56.88 98.55,57.2 98.55,57.37 98.7,57.52 101.85,57.52 102.15,57.21 103.56,57.21 103.86,57.52 104.61,57.52 104.92,57.21 106.34,57.21 107.22,58.09 108.4,58.09 112.89,62.58 113.39,62.58 113.76,62.96 113.76,63.46 114.02,63.71 114.49,63.71 115,64.22 115,64.69 116.2,65.89 116.54,65.89 v1(116.69,65.73)
  BOTTOM w0.102: 116.75,65.78 117.08,66.11 117.08,66.47 116.88,66.67 116.88,68.33 116.98,68.43 UC1.BA36
  BOTTOM w0.114: JDIMM1.242 71.95,49.99 72.08,50.12 72.38,50.12 72.57,50.3 73,50.3 73.19,50.12 73.31,50.12 73.37,50.06 73.37,49.78 v1(73.26,49.67) ; 116.75,65.78 v1(116.69,65.73)
DDR_A_DQS#0: length 70.6
  IN2 w0.147: v1(76.71,110.95) 76.58,111.08 76.58,111.27 76.73,111.41 78.45,111.41 79.75,112.71 81.86,112.71 83.64,110.92 90.31,110.92 90.58,111.19 90.58,111.76 90.71,111.88 91.48,111.88 91.8,112.2 91.8,112.56 91.94,112.71 92.39,112.71 92.53,112.56 92.53,112.2 92.85,111.88 95.55,111.88 95.7,111.74 95.7,111.24 96.01,110.92 96.69,110.92 97.01,111.24 97.01,111.74 97.15,111.88 102.77,111.88 109.92,104.74 111.11,104.74 116.84,99 116.84,98.29 117.16,97.98 117.83,97.98 117.98,97.83 117.98,97.62 117.83,97.47 117.16,97.47 116.84,97.16 116.84,96.72 116.97,96.59 116.97,96.37 117.29,96.05 117.29,95.87 117.43,95.72 v1(117.79,95.72)
  BOTTOM w0.102: 116.82,94.99 116.82,94.96 116.81,94.95 116.81,94.4 116.94,94.27 116.94,94 116.81,93.86 116.81,93.59 116.94,93.45 116.94,93.18 116.81,93.05 116.81,92.85 116.97,92.68 116.97,92.44 116.78,92.25 116.78,91.59 116.93,91.44 116.93,90.9 UC1.A36
  BOTTOM w0.114: 116.82,94.99 116.82,95.82 117.21,96.21 117.51,96.21 117.79,95.93 v1(117.79,95.72) ; JDIMM1.11 78.34,109.74 78.19,109.6 77.71,109.6 77.59,109.71 77.59,109.8 77.36,110.04 76.84,110.04 76.61,109.8 76.61,109.71 76.49,109.6 76.06,109.6 75.9,109.43 75.74,109.43 75.63,109.55 75.63,109.71 76.25,110.33 76.25,110.66 76.15,110.76 76.15,111.5 76.27,111.61 76.56,111.61 76.71,111.47 v1(76.71,110.95)
DDR_A_DQS#1: length 57.8
  IN2 w0.147: v1(112.68,92.56) 112.68,92.86 112.53,93 111.98,93 111.28,93.7 111.28,94.2 106.38,99.1 105.95,99.1 103.91,101.13 103.51,101.13 102.17,102.47 99.22,102.47 98.12,103.56 97.59,103.56 97.26,103.9 96.69,103.9 96.36,103.56 95.55,103.56 95.22,103.9 94.65,103.9 94.32,103.56 93.51,103.56 93.18,103.9 92.6,103.9 92.27,103.56 91.47,103.56 91.13,103.9 90.56,103.9 90.23,103.56 89.42,103.56 89.09,103.9 88.52,103.9 88.19,103.56 84.59,103.56 82.85,105.3 80.53,105.3 80.13,104.91 74.5,104.91 74.19,104.59 74.19,104.39 74.34,104.24 74.34,104.26 v1(74.32,104.26)
  BOTTOM w0.102: v1(112.68,92.56) 112.82,92.56 112.99,92.73 112.99,93.02 112.88,93.13 111.99,93.13 111.89,93.02 111.89,91.96 112.26,91.59 112.26,90.14 113.19,89.22 114.24,89.22 UC1.D41
  BOTTOM w0.114: JDIMM1.32 71.64,104.49 71.83,104.3 72.84,104.3 73.51,104.98 73.87,104.98 74.11,104.74 74.11,104.48 v1(74.32,104.26)
DDR_A_DQS#2: length 56.2
  IN2 w0.147: v1(75.85,97.3) 76.01,97.46 76.01,97.78 76.26,98.03 79.37,98.03 80.45,96.95 81.39,96.95 84.43,93.91 93.59,93.91 95.59,91.92 97.2,91.92 97.52,91.6 97.52,91.05 97.67,90.9 98.11,90.9 98.26,91.05 98.26,91.6 98.57,91.92 99.57,91.92 99.88,91.6 99.88,91.05 100.03,90.9 100.47,90.9 100.62,91.05 100.62,91.6 100.93,91.92 101.61,91.92 101.93,91.6 101.93,91.05 102.07,90.9 102.51,90.9 102.66,91.05 102.66,91.6 102.98,91.92 104.43,91.92 106.14,90.21 106.14,89.58 v1(106.33,89.38)
  BOTTOM w0.102: UC1.K41 114.11,85.96 114.11,85.96 113.51,85.96 113.45,86.03 109.8,86.03 108.89,86.94 108.07,86.94 107.88,87.14 107.88,87.15 107.84,87.19 107.84,87.2 106.98,88.05 106.65,88.05 105.93,87.34 105.84,87.34
  BOTTOM w0.114: v1(106.33,89.38) 106.09,89.15 106.09,88.95 106.24,88.79 106.24,88.46 105.53,87.74 105.53,87.58 105.77,87.34 105.84,87.34 ; v1(75.85,97.3) 75.85,97.3 76.18,97.63 76.18,98.31 76.61,98.73 77.45,98.73 77.77,99.05 77.94,99.05 78.12,99.24 JDIMM1.53
DDR_A_DQS#3: length 51.2
  IN2 w0.147: v1(111.08,82.86) 111.08,83.3 110.68,83.71 106.83,83.71 106.53,84.01 88.35,84.01 88.2,84.16 88.2,84.62 87.89,84.94 87.21,84.94 86.9,84.62 86.9,84.16 86.75,84.01 86.5,84.01 80.97,89.54 79.36,89.54 76.89,92.01 76.68,92.01 76.21,92.48 75.41,92.48 75.19,92.26 74.98,92.26 74.83,92.41 74.83,92.59 v1(74.92,92.68)
  BOTTOM w0.102: UC1.U40 114.36,82.11 114.06,82.41 113.57,82.41 113.4,82.24 111.45,82.24 111.08,82.6 v1(111.08,82.86)
  BOTTOM w0.114: JDIMM1.74 71.66,93.99 71.85,93.8 74.25,93.8 74.68,93.38 74.68,92.93 v1(74.92,92.68)
DDR_A_DQS#4: length 55.4
  IN2 w0.147: v1(109.23,76.12) 108.96,76.4 108.96,76.78 108.62,77.12 107.85,77.12 107.77,77.2 106.2,77.2 105.37,78.03 96.18,78.03 95.69,77.53 94.9,77.53 94.75,77.68 94.75,77.84 94.44,78.15 93.76,78.15 93.45,77.84 93.45,77.68 93.3,77.53 92.86,77.53 92.71,77.68 92.71,77.84 92.4,78.15 91.72,78.15 91.41,77.84 91.41,77.68 91.26,77.53 90.82,77.53 90.67,77.68 90.67,77.84 90.35,78.15 89.68,78.15 89.36,77.84 89.36,77.68 89.22,77.53 88.73,77.53 88.18,76.98 87.97,76.98 87.92,77.03 87.47,77.03 86.99,76.55 86.99,76.11 87.05,76.06 87.05,75.85 86.73,75.54 86.53,75.54 86.47,75.59 86.03,75.59 85.55,75.11 85.55,74.67 85.6,74.61 85.6,74.4 85.29,74.09 85.08,74.09 85.03,74.14 84.58,74.14 84.1,73.66 84.1,73.22 84.16,73.17 84.16,72.96 83.84,72.65 83.64,72.65 83.58,72.7 83.14,72.7 82.66,72.22 82.66,71.78 82.71,71.72 82.71,71.51 81.99,70.79 80.23,70.79 79.72,70.28 79.72,68.25 78.02,66.55 76.66,66.55 76.24,66.14 76.24,65.65 v1(76.08,65.48)
  BOTTOM w0.102: v1(109.23,76.12) 109.09,75.98 109.09,75.82 109.19,75.72 109.91,75.72 110.96,76.77 111.82,76.77 112.37,77.32 113.84,77.32 113.84,77.33 114,77.33 114.18,77.51 114.42,77.51 114.61,77.71 UC1.AE40
  BOTTOM w0.114: JDIMM1.177 78.42,66.24 78.27,66.09 76.5,66.09 76.26,65.86 76.26,65.67 v1(76.08,65.48)
DDR_A_DQS#5: length 54.8
  IN2 w0.147: v1(73.14,61.44) 73.26,61.31 73.45,61.31 73.61,61.48 73.61,61.55 73.63,61.57 73.63,61.89 73.94,62.21 75.05,62.21 76.53,60.72 78.39,60.72 78.8,61.12 83.82,61.12 87.68,64.99 87.68,66.94 88.25,67.51 88.25,69.5 88.7,69.95 104.41,69.95 105.21,70.74 105.21,71.2 v1(105.02,71.39)
  BOTTOM w0.102: UC1.AM41 114.24,73.82 113.67,73.82 113.59,73.75 106.45,73.75 105.84,73.13
  BOTTOM w0.114: 105.84,73.13 105.69,72.99 105.69,72.42 105.55,72.27 105.55,71.78 105.15,71.39 v1(105.02,71.39) ; JDIMM1.198 71.71,60.99 71.88,60.82 73.37,60.82 73.49,60.94 73.49,61.28 73.37,61.39 73.33,61.44 v1(73.14,61.44)
DDR_A_DQS#6: length 55.5
  IN2 w0.147: v1(75.17,53.77) 75.32,53.92 75.32,54.28 75.5,54.46 75.5,54.67 75.08,55.08 75.08,55.53 75.56,56.01 76.01,56.01 76.42,55.59 76.63,55.59 76.69,55.66 78.47,55.66 79.57,54.56 81.88,54.56 82.04,54.73 83.01,54.73 83.9,55.62 86.36,55.62 93.66,62.91 96.98,62.91 98.59,64.52 107.42,64.52 111.01,68.12 111.16,68.12 111.66,68.62 111.66,68.87 v1(111.61,68.92)
  BOTTOM w0.102: UC1.AV41 112.94,70.56 112.92,70.54 112.91,70.54 111.91,69.53 111.91,69.05 111.78,68.92 v1(111.61,68.92)
  BOTTOM w0.114: v1(75.17,53.77) 75.39,54 75.39,54.25 75.5,54.36 75.5,54.52 75.14,54.89 75.14,55.22 75.5,55.59 75.84,55.59 76.2,55.22 76.37,55.22 76.71,55.56 78.07,55.56 78.25,55.74 JDIMM1.219
DDR_A_DQS#7: length 59.7
  IN2 w0.147: v1(73.85,49.67) 73.7,49.52 73.7,49.3 73.84,49.15 74.63,49.15 74.96,48.82 75.51,48.82 75.84,49.15 83.22,49.15 83.73,49.66 84.78,49.66 86.08,50.95 89.91,50.95 96.76,57.8 97.27,57.8 97.58,57.49 97.58,57.31 97.73,57.17 98.12,57.17 98.27,57.31 98.27,57.49 98.58,57.8 101.97,57.8 102.27,57.5 103.44,57.5 103.74,57.8 104.73,57.8 105.04,57.5 106.22,57.5 107.1,58.37 108.28,58.37 112.77,62.87 113.27,62.87 113.48,63.08 113.48,63.57 113.9,64 114.37,64 114.72,64.34 114.72,64.81 116.08,66.17 116.54,66.17 v1(116.69,66.32)
  BOTTOM w0.102: v1(116.69,66.32) 116.68,66.33 116.68,68.42 116.74,68.48 116.74,68.56 116.74,68.57 116.74,68.77 116.65,68.86 116.65,69.09 116.74,69.18 116.74,69.19 116.98,69.43 UC1.AY36
  BOTTOM w0.114: JDIMM1.240 71.95,50.49 72.12,50.33 72.3,50.33 72.48,50.51 73.09,50.51 73.27,50.33 73.4,50.33 73.6,50.13 73.6,49.92 v1(73.85,49.67)
DDR_A_EVENT#: length 49.5
  TOP w0.102: v1(109.44,81.38) 108.83,80.77 106.09,80.77 RC6.2
  IN1 w0.127: v1(74.15,79.24) 75.48,77.91 80.62,77.91 81.41,78.7 85.6,78.7 88.16,81.27 109.33,81.27 v1(109.44,81.38)
  BOTTOM w0.102: UC1.AA41 113.72,80.12 112.04,80.12 112.03,80.14 111.41,80.14 110.16,81.38 v1(109.44,81.38) ; JDIMM1.134 72.24,78.99 72.43,78.8 73.7,78.8 v1(74.15,79.24)
DDR_A_ODT0: length 56.6
  IN1 w0.102: v1(116.44,73.76) 116.44,73.87 115.93,74.39 115.08,74.39 114.5,73.81 114.5,71.78 113.53,70.81 113.53,70.5 112.84,69.81
  IN1 w0.211: v1(81.86,71.27) 81.86,71.21 81.54,70.89 81.54,69.14 82.15,68.53 84.09,68.53 84.3,68.74 84.3,70.79 84.51,71 84.81,71 85.02,70.79 85.02,68.85 85.23,68.64 85.53,68.64 85.74,68.85 85.74,70.78 85.95,70.99 86.25,70.99 86.46,70.78 86.46,68.82 86.67,68.61 86.97,68.61 87.18,68.82 87.18,69.95 87.39,70.16 87.73,70.16 88.21,69.68 88.73,69.68 89.23,70.17 99.05,70.17 99.89,69.34 100.43,69.34 101.32,70.23 101.77,70.23 102.78,69.21 103.54,69.21 104.02,69.69 105.02,69.69 105.5,69.21 106.02,69.21 106.55,69.75 112.77,69.75 112.83,69.81 112.84,69.81
  BOTTOM w0.102: JDIMM1.155 81.39,71.74 v1(81.86,71.27) ; v1(116.44,73.76) 116.83,73.37 UC1.AN37
DDR_A_ODT1: length 56.5
  IN1 w0.102: 112.06,66.42 113.14,67.5 113.14,68.1 114.67,69.63 114.67,70.58 v1(115.72,71.63)
  IN1 w0.211: 112.06,66.42 111.6,66.42 111.45,66.57 95.76,66.57 95.69,66.51 90.55,66.51 89.19,65.15 89.19,64.38 87.28,62.48 86.6,62.48 86.38,62.69 86.38,63.32 86.17,63.53 85.75,63.53 85.54,63.32 85.54,62.73 85.33,62.52 84.91,62.52 84.7,62.73 84.7,63.32 84.49,63.53 84.07,63.53 83.85,63.32 83.85,62.73 83.64,62.52 83.22,62.52 83.01,62.73 83.01,63.32 82.8,63.53 82.38,63.53 82.17,63.32 82.17,62.73 81.96,62.52 81.54,62.52 81.32,62.73 81.32,63.32 81.11,63.53 80.53,63.53 79.02,65.04 79.02,67.56 77.07,69.5 76.96,69.5 v1(76.95,69.52)
  BOTTOM w0.102: v1(76.95,69.52) 77.67,70.24 JDIMM1.161 ; UC1.AU38 116.03,71.32 v1(115.72,71.63)
DDR_A_RAS#: length 49.2
  IN1 w0.102: 110.67,72.53 110.88,72.53 111.03,72.68 112.49,72.68 114.19,74.39 114.19,74.8 114.95,75.55 116.53,75.55 v1(117.03,76.06)
  IN1 w0.211: 110.67,72.53 104.04,72.53 103.65,72.92 88.58,72.92 88.42,72.76 75.78,72.76 75.24,72.23 73.41,72.23 v1(72.9,72.74)
  BOTTOM w0.102: JDIMM1.152 72.64,72.49 v1(72.9,72.74) ; v1(117.03,76.06) 116.83,75.86 UC1.AJ37
DDR_A_RST#: length 59.5
  TOP w0.102: DC1.2 116.73,88.16 v1(116.23,88.16) ; CD1.1 71.82,85.51 72.81,86.5 73.94,86.5 v1(74.55,85.89)
  IN1 w0.102: 110.67,94.49 111.87,93.28 111.87,92.71 112.41,92.18 113.17,92.18 114.4,90.95 114.4,89.68 115.54,88.54 115.85,88.54 v1(116.23,88.16)
  IN1 w0.127: 110.67,94.49 110.29,94.86 85.51,94.86 79.77,89.13 77.96,89.13 77.66,88.82 77.14,88.82 74.55,86.23 v1(74.55,85.89)
  BOTTOM w0.102: JDIMM1.108 72.03,85.49 73,86.46 73.98,86.46 v1(74.55,85.89) ; v1(116.23,88.16) 116.03,87.96 UC1.G38
DDR_A_SA0: length 5.6
  TOP w0.102: v2(76.27,45.97) 75.78,45.97 RD6.1 RD5.2 73.83,46.4 v1(73.73,46.51)
  BOTTOM w0.102: v1(73.73,46.51) 73.63,46.41 72.87,46.41 72.79,46.49 JDIMM1.256
DDR_A_VREFDQ: length 3
  BOTTOM w0.102: T1.1 112,80.83 112.51,80.33 114.15,80.33 UC1.Y41
DDR_A_WE#: length 57.5
  IN1 w0.102: v1(116.26,74.96) 115.86,75.35 115.09,75.35 114.4,74.66 114.4,74.3 114.1,74 114.1,71.95 113.63,71.48 111.41,71.48 110.77,70.84 110.67,70.84
  IN1 w0.211: v1(77.03,71.6) 77.67,72.25 89.1,72.25 90.09,71.26 96.98,71.26 97.19,71.47 97.19,72.17 97.4,72.39 97.7,72.39 97.91,72.17 97.91,71.47 98.12,71.26 98.42,71.26 98.63,71.47 98.63,72.19 98.84,72.4 99.14,72.4 99.35,72.19 99.35,71.47 99.56,71.26 99.86,71.26 100.07,71.47 100.07,72.18 100.28,72.39 100.58,72.39 100.79,72.18 100.79,71.43 100.97,71.26 101.23,71.26 101.44,71.47 101.44,72.19 101.65,72.4 101.95,72.4 102.16,72.19 102.16,71.47 102.37,71.26 102.67,71.26 102.88,71.47 102.88,72.11 103.09,72.32 103.52,72.32 103.86,71.98 103.86,71.05 104.07,70.84 106.82,70.84 107.03,71.05 107.03,71.81 107.24,72.02 108.09,72.02 108.3,71.81 108.3,71.06 108.51,70.85 110.66,70.85 110.67,70.84
  BOTTOM w0.102: UC1.AL38 116.03,74.61 116.16,74.92 v1(116.26,74.96) ; JDIMM1.151 78.17,72.74 v1(77.03,71.6)
DDR_A_ZVDDIO: length 8.7
  TOP w0.508: RC4.1 107.4,79.05 v1(107.72,79.37)
  BOTTOM w0.15: 112.69,79.43 113.5,79.43 113.57,79.36 114.17,79.36
  BOTTOM w0.152: UC1.AB41 114.17,79.36
  BOTTOM w0.254: v1(107.72,79.37) 107.96,79.12 v2(108.35,79.12) 111.62,79.12 111.93,79.43 112.69,79.43
DEVSLP0_HDD: length 101.3
  TOP w0.102: v1(157.81,38.07) v2(156.35,39.52) 155.69,40.19 143.99,40.19 142.66,41.52 137.26,41.52 136.81,41.97 135.8,41.97 135.23,42.54 134.21,42.54 133.51,43.24 132.11,43.24 130.26,45.09 129.17,45.09 128.68,45.59 126.02,45.59 125.47,45.04 121.8,45.04 119.35,47.49 v1(119.03,47.49) ; RC101.2 v1(119.5,59.41)
  IN1 w0.127: v1(157.81,38.07) 158.28,38.54 166.85,38.54 167.93,37.46 185.27,37.46 v1(185.73,37.93) ; v1(119.5,59.41) 119.56,59.41 120.82,58.14 120.82,54.4 120.34,53.92 120.34,51.96 120.75,51.56 120.75,48.83 119.41,47.49 v1(119.03,47.49)
  IN2 w0.102: 120.93,65.28 121.06,65.4 121.06,69.98 120.26,70.78 v1(120.26,70.93)
  IN2 w0.127: 120.93,65.28 120.68,65.02 120.68,64.83 119.03,63.19 119.03,59.88 v1(119.5,59.41)
  BOTTOM w0.102: v1(120.26,70.93) 120.03,70.71 UC1.AV31 ; v1(185.73,37.93) 185.81,38.01 186.27,38.01 186.63,38.36 RS23.1
DEVSLP1_SSD: length 129.8
  TOP w0.102: v1(31.66,31.3) RS28.2 ; RC99.2 105.41,57.95 v1(105.44,57.93) 105.46,57.95 v2(106.13,57.95) 112.73,57.95 115.46,60.68 v1(115.76,60.68)
  IN1 w0.127: v1(115.76,60.68) 115.76,62.88 118.93,66.04 118.93,69.72 118.85,69.8 118.85,71.36 v1(119.25,71.77)
  BOTTOM w0.102: UC1.AU31 119.51,71.51 119.25,71.76 v1(119.25,71.77) ; v1(105.44,57.93) 105.44,56.38 102.46,53.4 101.5,53.4 98.01,49.91 95.16,49.91 93.9,48.65 93.9,39.89 92.55,38.54 68.53,38.54 66.33,40.74 51.37,40.74 51.05,41.05 46.35,41.05 46.12,41.28 45.54,41.28 45.32,41.05 41.53,41.05 40.76,40.28 40.76,39.77 40.36,39.37 40.36,35.68 41.44,34.6 41.44,31.91 39.95,30.42 32.53,30.42 v1(31.66,31.3)
DEW1: length 6
  TOP w0.102: v2(192.24,44.17) RS17.1 192.19,43.06 RS4.1 190.81,42.58 190.37,42.58 189.93,43.01 189.1,43.01 188.56,42.47 US1.16
DEW2: length 5.6
  TOP w0.102: RS16.1 182.69,35.63 RS3.1 183.55,36.46 v2(183.69,36.6) 184.06,36.98 186.18,36.98 186.56,37.36 US1.6
DISPOFF#: length 240.4
  TOP w0.102: RV6.1 213.72,48.75 v1(213.93,48.55) ; v1(65.82,41.84) 65.82,41.91 63.22,44.51 63.22,56.13 v2(62.54,56.8) 61.63,57.72 61.63,74.7 62.26,75.34 62.26,79.81 52.99,89.09 DV1.1 52.93,89.15 50.71,89.15 50.5,88.95 RV33.1
  IN1 w0.127: v1(91.73,39.43) 91.73,39.05 92.6,38.17 97.96,38.17 98.92,37.21 102.4,37.21 102.55,37.37 104.07,37.37 104.45,36.99 105.74,36.99 105.9,36.83 108.37,36.83 109.04,37.5 115.88,37.5 116.37,37.02 124.71,37.02 125.28,37.59 128.3,37.59 128.84,38.12 141.68,38.12 148.48,44.93 148.48,45.9 150.1,47.52 161.71,47.52 168.49,54.3 168.49,58.85 170.91,61.27 v1(170.91,63.37)
  IN2 w0.127: v1(170.91,63.37) 173.89,66.35 180.77,66.35 181.4,65.71 188.88,65.71 191.88,62.71 196.74,62.71 197.18,62.27 197.18,60.06 198.83,58.41 198.83,57.66 202.73,53.76 202.73,51.66 205.14,49.25 212.4,49.25 213.1,48.55 v1(213.93,48.55)
  BOTTOM w0.102: v1(213.93,48.55) 213.97,48.51 213.97,48.13 212.79,46.95 JEDP1.28 ; v1(91.73,39.43) 91.73,39.45 91.63,39.56 77.03,39.56 73.92,42.67 73.27,42.67 72.86,42.25 72.86,41.42 71.64,40.2 68.83,40.2 67.19,41.84 v1(65.82,41.84)
DMIC_CLK: length 2
  TOP w0.102: L5.2 35.34,11.3 34.63,12.01 UA1.3
DMIC_DATA: length 2.1
  TOP w0.102: UA1.2 34.63,11.61 RA46.2
DP_AUX_ZVSS: length 2
  TOP w0.102: v2(125.29,89.2) 125.66,89.2 v1(125.77,89.32)
  TOP w0.254: RC13.1 125.77,90.01 v1(125.77,89.32)
  BOTTOM w0.25: v1(125.77,89.32) 125.56,89.11 UC1.D21
DP_ZVSS: length 6.7
  TOP w0.102: v1(125.97,91.75) 126.03,91.75 v2(126.36,92.08)
  TOP w0.254: RC15.1 125.64,91.42 v1(125.97,91.75)
  BOTTOM w0.102: 125.46,90.99 125.59,91.12 125.59,91.76 125.69,91.86 125.86,91.86 v1(125.97,91.75) 125.97,91.12 126.23,90.87 126.4,90.87 126.64,90.63 126.64,90.4 UC1.B18 126.24,90.16 125.84,90.55 125.65,90.55 125.46,90.74 125.46,90.99
EC_ENVDD: length 234.3
  TOP w0.102: v1(49.87,71.5) 50.2,71.82 UE1.71 ; v1(225.65,57.59) v2(224.86,57.59) RV5.2
  IN1 w0.127: v1(48.66,75.78) 48.91,76.04 48.91,76.49 49.24,76.82 50.52,76.82 50.75,76.6 50.75,73.37 52.04,72.08 52.04,70.78 52.81,70 52.81,69.2 53.95,68.07 53.95,66.24 58.57,61.62 58.57,53.6 60.71,51.46 60.71,43.65 62.58,41.78 62.95,41.78 64.99,39.74 64.99,39.17 65.5,38.67 65.97,38.67 68.67,35.96 88.27,35.96 92.55,31.68 118.92,31.68 119.22,31.38 122.93,31.38 123.38,31.84 129.29,31.84 130.21,32.76 135.61,32.76 136.95,34.11 143.11,34.11 150.56,41.55 157.24,41.55 158.87,43.18 181.22,43.18 181.53,43.49 189.18,43.49 189.6,43.91 190.92,43.91 192.32,42.52 197.18,42.52 198.41,43.75 202.07,43.75 203.09,44.76 203.81,44.76 207.43,48.38 212.44,48.38 212.95,47.87 220.76,47.87 225.65,52.76 v1(225.65,57.59)
  BOTTOM w0.102: v1(48.66,75.78) 48.66,75.42 49.87,74.2 v1(49.87,71.5)
EC_MUTE#: length 98
  TOP w0.102: v1(34.83,8.5) 34.83,8.89 34.58,9.14 RA8.2 34.5,9.33 33.46,10.37 UA1.40 ; v1(47.09,75.28) 49.48,75.28 49.84,75.65 50.05,75.65 50.28,75.87 50.28,76.4 50.5,76.62 UE1.83 ; v2(37.55,24.06) 37.91,24.42 v1(37.99,24.42)
  IN1 w0.127: v1(47.09,75.28) 47.53,75.73 47.53,76.13 47.09,76.58 42.58,76.58 41.81,75.81 40.04,75.81 39.15,74.93 39.15,72.34 39.4,72.09 39.4,71.71 38.86,71.17 38.86,70.7 37.74,69.57 37.74,68.13 40.23,65.63 40.23,59.85 46.4,53.69 46.4,47.23 47.11,46.51 47.11,37.89 44.37,35.15 44.37,33.57 44.55,33.4 44.55,31.68 43.84,30.97 43.84,27.74 43.15,27.05 40.99,27.05 38.36,24.42 v1(37.99,24.42)
  BOTTOM w0.102: v1(34.83,8.5) 35.02,8.5 36.48,9.96 36.48,13.27 35.4,14.35 35.4,20.32 35.35,20.37 35.35,22.68 37.09,24.42 v1(37.99,24.42)
EC_ON: length 247.2
  TOP w0.102: v1(44.15,85) 44.06,85 43.73,84.67 UE1.112
  TOP w0.254: v1(193.96,59.56) 193.53,59.13 PQB29.2 ; PR506.1 v1(45.93,107.83)
  IN1 w0.127: v1(193.96,59.56) 193.96,60.02 193.68,60.3 193.68,62.69 190.66,65.72 185.01,65.72 181.45,69.27 181.45,70.04 179.8,71.69 177.94,71.69 175.95,73.67 158.17,73.67 156.28,71.79 156.28,70.88 153.12,67.72 153.12,63.07 153.36,62.83 153.36,62.12 152.72,61.48 151.76,61.48 150.26,59.97 150.26,58.88 150.66,58.48 150.66,56.99 150.92,56.73 150.92,53.51 148.99,51.58 148.99,50.64 147.27,48.91 147.27,46.69 141.23,40.66 141.23,39.64 140.99,39.39 127.48,39.39 126.69,38.6 124.98,38.6 124.98,38.6 124.77,38.6 124.2,38.04 117.01,38.04 116.47,38.59 104.43,38.59 103.6,39.42 101.73,39.42 101.6,39.29 97.08,39.29 95.31,41.05 73.02,41.05 71.49,42.59 70.42,42.59 68.58,44.43 68.58,45.29 66.06,47.8 66.06,49.53 65.4,50.19 65.4,60.1 62.97,62.54 62.97,68.46 58.66,72.77 58.66,74.81 57.44,76.03 57.44,77.72 56.74,78.42 56.74,79.75 55.47,81.02 53.93,81.02 53.76,81.19 52.24,81.19 51.43,82 51.43,82.76 50.18,84.01 45.23,84.01 44.25,85 v1(44.15,85)
  IN2 w0.127: v1(45.93,107.83) 45.93,103.32 46.33,102.93 46.33,89.91 47.53,88.7 47.53,86.93 45.6,85 v1(44.15,85)
EC_PME#: length 3.9
  TOP w0.102: UE1.29 v2(34.1,70.62) 33.5,70.62 33.2,70.32 RE32.1 RE17.1
EC_RSMRST#: length 179.1
  TOP w0.102: v1(50.78,84.09) 50.78,85.6 50.94,85.76 RE28.1 50.5,86.16 50.41,86.08 CE11.1 48.53,84.52 UE1.100
  IN1 w0.127: v1(159.67,76.64) 159.67,75.56 156.03,71.92 156.03,71.01 152.87,67.84 152.87,62.96 153.11,62.72 153.11,62.23 152.61,61.73 151.66,61.73 149.98,60.05 149.98,58.8 150.4,58.38 150.4,57.15 149.41,56.15 149.41,52.48 148.74,51.81 148.74,50.74 146.95,48.95 146.95,46.74 140.44,40.23 139.71,40.23 139.12,39.64 127.38,39.64 126.59,38.86 125.08,38.86 124.66,38.86 124.1,38.29 117.12,38.29 116.57,38.84 104.54,38.84 103.71,39.67 101.62,39.67 101.49,39.54 97.18,39.54 95.42,41.31 73.13,41.31 71.59,42.84 70.52,42.84 69.41,43.95 69.41,44.94 67.59,46.76 67.59,60.6 63.22,64.97 63.22,68.56 59.05,72.73 59.05,76.61 58.77,76.89 58.07,76.89 57.69,77.27 57.69,77.85 56.99,78.54 56.99,79.86 55.58,81.28 54.03,81.28 53.87,81.44 52.45,81.44 51.91,81.97 51.91,82.74 50.78,83.87 v1(50.78,84.09)
  BOTTOM w0.102: v1(159.67,76.64) DC2.1 157.21,75.39 RC93.1
EC_RSMRST#_R: length 25.1
  TOP w0.102: CC14.2 146.55,75.32 v1(146.55,75.31) 146.05,75.31 145.76,75.6 RC96.2
  BOTTOM w0.102: DC2.2 156.32,75.39 RC93.2 156.17,75.5 150.72,75.5 149.86,76.36 148.09,76.36 v2(147.65,75.92) 147.04,75.31 v1(146.55,75.31) 146.35,75.11 141.74,75.11 141.38,74.74 139.91,74.74 137.94,76.71 136.63,76.71 UC1.AG1
EC_RST#: length 3.9
  TOP w0.102: RE50.2 39.63,65.91 CE19.1 ; RE50.2 39.04,65.18 v2(38.76,64.91) ; RE50.2 39.04,66.59 38.93,66.7 UE1.37
EC_RX: length 102.5
  TOP w0.102: UE1.31 39,69.82 39.34,70.16 45.69,70.16 v1(46.64,71.12) ; RW8.1 71.93,131.5 73.19,130.25 v1(73.19,129.98)
  IN1 w0.127: v1(48.5,88.97) 49,88.48 50.98,88.48 51.02,88.51 52.04,88.51 56.11,84.45 56.11,84.17 57.33,82.95 57.68,82.95 57.97,83.24 62.88,83.24 65.81,86.17 65.81,86.77 71.01,91.96 71.01,114.02 70.68,114.35 70.68,115.64 71.26,116.22 71.26,128.71 72.57,130.02 73.15,130.02 v1(73.19,129.98)
  BOTTOM w0.102: v1(46.64,71.12) 46.64,71.18 47.79,72.32 47.79,76.58 50.33,79.12 50.33,81.59 49.82,82.1 49.82,86.55 49.31,87.05 49.31,87.88 48.5,88.69 v1(48.5,88.97)
EC_RX_R: length 2.3
  TOP w0.102: RW8.2 v1(70.39,131.5) 70.3,131.5 v2(69.99,131.19)
  BOTTOM w0.102: JWLAN1.40 70.6,131.3 v1(70.39,131.5)
EC_SCI#: length 169.2
  TOP w0.102: v1(38.62,74.35) 37.18,74.35 37.05,74.22 UE1.20 34.9,74.22 34.39,74.73 33.88,74.73 33.48,74.33 RE21.2 RE19.2 ; v1(76.62,44.45) 76.62,44.32 74.84,42.54 72.74,42.54 71.15,44.13 66.65,44.13 66.33,43.81 65.12,43.81 64.36,44.57 v2(64.36,47.44) 64.36,47.81 65.01,48.46 v1(65.01,48.76)
  IN1 w0.102: 138.46,65.28 138.32,65.42 138.32,68.13 137.74,68.72 137.74,73.87 138.06,74.19 138.06,74.57 137.37,75.26 134.48,75.26 134.31,75.42 132.8,75.42 132.77,75.4 131.83,75.4 131.67,75.56 131.67,77.51 131.73,77.57 v1(131.73,78.23)
  IN1 w0.127: 138.46,65.28 138.59,65.15 138.59,57.97 130.86,50.24 130.86,49.3 126.8,45.25 126.4,45.25 125.73,44.57 121.6,44.57 119.22,42.18 110.7,42.18 110.15,41.63 106.29,41.63 105.33,42.6 97.82,42.6 95.27,45.14 87.25,45.14 86.19,44.08 76.98,44.08 v1(76.62,44.45)
  IN2 w0.127: v1(65.01,48.76) 63.95,48.76 54.33,58.39 54.33,69.24 53.69,69.87 53.69,70.31 52.27,71.74 52.18,71.74 51.14,72.78 43.94,72.78 43.31,73.4 42.26,73.4 41.71,73.96 41.36,73.96 41.16,73.77 39.2,73.77 v1(38.62,74.35)
  BOTTOM w0.102: v1(131.73,78.23) 131.67,78.29 131.67,78.95 132.03,79.31 UC1.AA8
EC_SMB_CK1: length 217.3
  TOP w0.102: v1(138.4,35.62) 138.4,35.49 136.25,33.35 130.32,33.35 129.37,34.3 126.27,34.3 124.16,32.19 116.49,32.19 108.56,40.13 108.56,42.24 107.8,42.99 106.53,42.99 103.3,39.76 94.5,39.76 93.36,40.9 84.64,40.9 82.41,38.67 v2(75.74,38.67) 66.98,38.67 66.03,39.62 65.64,39.62 61.13,44.13 61.13,54.92 57.32,58.73 57.32,72.11 56.46,72.97 56.14,72.97 55.35,73.76 55.24,73.76 55.24,73.76 55.12,73.76 55.1,73.78 54.77,73.78 RE13.2 53.92,74.26 52.41,74.26 52.37,74.22 UE1.77 ; PD5.3 161.41,39.7 160.8,39.1 PR42.2 160.5,38.35 160.63,38.22 v1(160.63,38.07)
  IN2 w0.127: v1(196.86,56.16) 196.78,56.09 196.78,55.95 196.78,55.04 199.5,52.32 199.5,46.15 200.12,45.52 200.44,45.52 v1(200.52,45.6)
  BOTTOM w0.102: PRB20.1 196.69,55.29 196.69,56 v1(196.86,56.16) ; v1(138.4,35.62) 138.27,35.49 138.27,35.11 138.71,34.68 148.76,34.68 150.71,36.62 160.86,36.62 161.26,37.02 161.26,37.44 v1(160.63,38.07) 161.21,38.66 162.67,38.66 162.92,38.4 162.92,38.38 164.54,36.76 177.39,36.76 179.36,34.79 190.86,34.79 191.87,35.8 193.39,35.8 193.85,36.25 193.85,37.85 196.12,40.13 196.82,40.13 199.04,42.35 199.04,42.86 200.11,43.92 200.11,45.2 v1(200.52,45.6)
EC_SMB_CK2: length 197.8
  TOP w0.102: UE1.79 51.44,74.94 52.93,74.94 54.27,76.28 55.62,76.28 RE15.2 56.49,75.41 57.16,75.41 57.73,75.98 C14.1 58.01,76.26 59.53,77.78 60.44,77.78 QC2.3 61.2,77.09 61.44,76.85 61.44,75.95 60.68,75.19 60.68,57.08 62.14,55.62 62.14,44.25 65.86,40.53 66.35,40.53 67.41,39.48 v2(77.92,39.48) 81.54,39.48 83.8,41.74 93.73,41.74 94.9,40.57 103,40.57 106.2,43.78 108.13,43.78 109.44,42.47 109.44,40.35 110.67,39.13 112.95,39.13 116.43,42.6 v1(118.3,42.6)
  IN2 w0.127: v1(178.47,62.54) 178.34,62.68 174.87,62.68 171.48,59.28 171.48,54.61 170.85,53.97 170.85,53.01 167.67,49.84 167.67,49.31 167.06,48.7 165.94,48.7 165.81,48.83 163.12,48.83 161.34,47.05 158.42,47.05 156.08,49.4 155.01,49.4 151.39,53.02 149.64,53.02 149.2,52.57 148.32,52.57 v1(148.24,52.5)
  BOTTOM w0.102: v1(178.47,62.54) 178.53,62.61 178.77,62.61 179.57,63.41 U1.8 ; v1(118.3,42.6) 120.27,42.6 125.13,47.46 127.26,47.46 128.18,46.54 130.48,46.54 131.53,45.49 132.96,45.49 133.46,45.98 133.46,47.61 133.07,48 133.07,51.2 135.59,53.72 145.97,53.72 147.15,52.54 148.2,52.54 v1(148.24,52.5)
EC_SMB_DA1: length 217.9
  TOP w0.102: v1(137.82,35.62) 137.88,35.55 137.88,35.41 136.13,33.65 130.45,33.65 129.5,34.6 126.15,34.6 124.04,32.49 116.62,32.49 108.86,40.25 108.86,42.37 107.93,43.3 106.4,43.3 103.17,40.06 94.63,40.06 93.48,41.21 84.51,41.21 82.3,39 v2(80.4,39) 67.08,39 66.16,39.92 65.77,39.92 61.44,44.25 61.44,55.05 57.63,58.86 57.63,73.46 55.31,75.78 54.62,75.78 RE14.2 53.46,74.62 UE1.78 ; PD5.2 162.41,39.49 162.8,39.1 PR37.2 163.36,38.78 v1(162.65,38.07)
  IN2 w0.127: v1(200.52,45.02) 200.44,45.09 199.94,45.09 199.07,45.97 199.07,52.04 196.27,54.83 v1(196.27,56.16)
  BOTTOM w0.102: PRB19.1 196.39,55.09 196.39,56.04 v1(196.27,56.16) ; v1(200.52,45.02) 200.52,43.9 200.41,43.8 199.35,42.73 199.35,42.22 196.95,39.82 196.25,39.82 194.15,37.73 194.15,36.13 193.52,35.49 191.99,35.49 190.99,34.49 179.23,34.49 177.26,36.46 164.41,36.46 162.79,38.07 v1(162.65,38.07) 162.65,37.98 160.99,36.32 150.83,36.32 148.89,34.37 138.58,34.37 137.97,34.98 137.97,35.47 v1(137.82,35.62)
EC_SMB_DA2: length 202.5
  TOP w0.102: UE1.80 52.73,75.42 54.07,76.77 56.13,76.77 56.42,77.06 56.42,78.16 56.26,78.33 C15.1 56.26,79.52 56.61,79.88 RE10.2 56.98,79.93 57.5,80.45 58.14,80.45 58.52,80.07 58.52,78.48 58.9,78.1 59.17,78.1 59.33,78.26 59.33,78.29 59.34,78.3 59.34,78.67 59.66,78.99 QC2.6 59.84,78.69 60.8,77.72 61.25,77.72 61.92,77.05 61.92,75.75 61.16,74.99 61.16,57.28 62.62,55.82 62.62,44.46 66.06,41.02 66.56,41.02 67.61,39.96 v2(79.19,39.96) 81.34,39.96 83.6,42.22 93.93,42.22 95.1,41.05 102.8,41.05 106,44.26 108.33,44.26 109.93,42.67 109.93,40.55 110.87,39.61 112.75,39.61 116.23,43.09 v1(118.84,43.09)
  IN2 w0.127: v1(178.41,63.18) 174.66,63.18 170.98,59.49 170.98,54.82 170.34,54.18 170.34,53.22 167.17,50.05 167.17,49.53 166.85,49.21 166.15,49.21 166.02,49.34 162.91,49.34 161.13,47.56 158.64,47.56 156.29,49.91 155.22,49.91 151.6,53.53 149.43,53.53 148.92,53.02 148.31,53.02 v1(148.24,53.08)
  BOTTOM w0.102: U1.7 179.54,64.06 178.66,63.18 v1(178.41,63.18) ; v1(118.84,43.09) 120.07,43.09 124.93,47.94 127.46,47.94 128.38,47.02 130.68,47.02 131.73,45.97 132.76,45.97 132.98,46.18 132.98,47.41 132.58,47.8 132.58,51.4 135.39,54.21 146.17,54.21 147.35,53.02 148.18,53.02 v1(148.24,53.08)
EC_TP_INT#: length 131.6
  TOP w0.102: v1(46.56,77.75) 45.25,79.06 45.25,81.34 46.13,82.22 UE1.106 ; v1(135.23,34.09) v2(134.69,34.09)
  IN1 w0.127: v1(46.56,77.75) 46.59,77.78 53.32,77.78 53.74,77.36 53.74,73.43 54.59,72.58 54.59,70.28 60.36,64.51 60.36,54.35 62.77,51.94 62.77,44.49 64.85,42.41 65.84,42.41 66.39,41.86 66.39,41.33 69.91,37.82 89.02,37.82 93.05,33.79 106.29,33.79 106.58,34.09 111.16,34.09 111.79,33.46 119.73,33.46 120.27,33.99 122.44,33.99 122.94,33.49 125.86,33.49 126.75,34.39 128.91,34.39 129.49,33.8 130.37,33.8 130.4,33.78 134.91,33.78 v1(135.23,34.09)
  BOTTOM w0.102: RE26.1 R24.1 135.56,34.43 v1(135.23,34.09)
EC_TX: length 105.6
  TOP w0.102: v1(72.74,129.6) 72.67,129.52 v2(71.92,129.52) 71.75,129.69 71.75,130.44 RW7.1 ; RE38.1 33.59,70.22 UE1.30 36.72,70.22 36.79,70.29 39.02,70.29 39.21,70.48 45.25,70.48 v1(45.88,71.12)
  IN1 w0.127: v1(47.86,89.01) 47.87,89.01 48.65,88.22 51.09,88.22 51.12,88.26 51.93,88.26 55.85,84.34 55.85,83.94 57.09,82.7 57.78,82.7 58.07,82.99 62.98,82.99 66.06,86.07 66.06,86.66 71.26,91.86 71.26,114.13 70.93,114.46 70.93,115.53 71.51,116.12 71.51,128.5 72.61,129.6 v1(72.74,129.6)
  BOTTOM w0.102: v1(45.88,71.12) 45.88,71.18 47.53,72.83 47.53,76.64 50.07,79.18 50.07,81.4 49.6,81.87 49.6,86.34 49.06,86.89 49.06,87.75 47.86,88.95 v1(47.86,89.01)
EC_TX_R: length 3
  TOP w0.102: RW7.2 70.83,130.8 v1(70.37,130.8) v2(70.37,129.62)
  BOTTOM w0.102: JWLAN1.38 v1(70.37,130.8)
ECAGND: length 120.6
  TOP w0.254: UE1.69 52.39,71.02 v1(52.56,70.85) 52.56,70.85 52.6,70.81 CE5.2 ; v1(122.72,59.56) 122.95,59.33 PH1.2 ; v1(51.22,67.37) 50.64,67.37 50.28,67 CE7.1 LE2.1 51.49,65.25 51.6,65.15 v2(51.6,64.35) 51.6,62.61 60.04,54.16 60.04,43.87 64.68,39.24 64.68,37.71 65.44,36.95 82.97,36.95 85.95,39.94 92.93,39.94 94.08,38.79 104.43,38.79 107.73,42.1 v1(107.73,42.31)
  IN1 w0.254: v1(122.72,59.56) 122.97,59.31 122.97,57.84 124.32,56.5 124.32,50.24 120.87,46.79 120.87,46.22 117.51,42.86 108.28,42.86 v1(107.73,42.31)
  BOTTOM w0.254: v1(51.22,67.37) 52.17,68.32 52.17,70.46 v1(52.56,70.85)
EDP_AUXN: length 118.1
  IN2 w0.102: v1(130.58,91.89) 130.39,91.7 130.39,91.23 129.76,90.59 129.76,87.03 129.52,86.79 129.36,86.79 v1(129.08,86.51)
  IN2 w0.127: v1(208.9,53) 208.75,53.14 207.36,53.14 201.16,59.35 201.16,61.87 197.94,65.09 192.8,65.09 189.15,68.74 185.25,68.74 183.06,70.92 181.67,70.92 178.31,74.28 177.56,74.28 164.97,86.86 154.83,86.86 148.05,93.64 148.05,99.1 143.86,103.3 143.23,103.3 v1(143.08,103.16)
  BOTTOM w0.102: v1(208.9,53) 209.01,53.11 209.2,53.11 CV3.1 ; UC1.H15 128.88,86.71 v1(129.08,86.51) ; v1(130.58,91.89) 130.49,91.89 130.39,91.99 130.39,94.64 139.13,103.38 142.86,103.38 v1(143.08,103.16)
EDP_AUXN_C: length 2.5
  BOTTOM w0.102: JEDP1.16 211.68,52.95 211.56,53.08 v3(210.96,53.08) 210.19,53.08 CV3.2
EDP_AUXP: length 118
  IN2 w0.102: v1(130,91.89) 130.15,91.73 130.15,91.32 129.52,90.69 129.52,87.13 129.42,87.03 129.36,87.03 v1(129.08,87.31)
  IN2 w0.127: v1(143.08,103.74) 143.1,103.74 143.11,103.72 143.11,103.69 143.24,103.56 143.97,103.56 148.32,99.21 148.32,93.75 154.94,87.13 165.08,87.13 177.67,74.54 178.42,74.54 181.78,71.19 183.17,71.19 185.35,69 189.26,69 192.91,65.36 198.05,65.36 201.42,61.98 201.42,59.46 207.47,53.41 208.73,53.41 v1(208.9,53.58)
  BOTTOM w0.102: v1(129.08,87.31) 128.88,87.51 UC1.G15 ; CV2.1 209.26,53.36 209.11,53.36 v1(208.9,53.58) ; v1(130,91.89) 130.19,92.08 130.19,94.72 139.05,103.58 142.92,103.58 v1(143.08,103.74)
EDP_AUXP_C: length 2.5
  BOTTOM w0.102: JEDP1.15 211.7,53.45 211.58,53.32 210.21,53.32 CV2.2
EDP_HPD: length 111.3
  TOP w0.102: v1(213.37,54.95) 213.1,54.95 212.43,54.28 RV1.1 212.43,53.12 v2(212.28,52.97)
  IN1 w0.127: v1(145.45,83.67) 145.91,83.67 146.08,83.5 148.05,83.5 148.93,84.37 158.23,84.37 165.83,76.77 174.76,76.77 177.11,74.42 177.98,74.42 185.6,66.8 188.88,66.8 189.1,66.58 194.88,66.58 202.34,59.11 212.19,59.11 212.91,58.39 212.91,55.38 213.35,54.95 v1(213.37,54.95)
  IN2 w0.102: 138.86,83.68 138.25,83.68 137.5,82.93 136.48,82.93 135.86,82.3 135.86,81.91 135.48,81.53 134.26,81.53 133.81,81.97 130.97,81.97 130.4,82.55 130.4,85.72 130.21,85.91 129.92,85.91 129.82,86.02 128.87,86.02 128.65,86.24 128.65,88.2 129,88.55 129,88.75 v1(129.09,88.84)
  IN2 w0.127: 138.86,83.68 139.1,83.68 141.02,83.68 141.29,83.94 145.18,83.94 v1(145.45,83.67)
  BOTTOM w0.102: v1(129.09,88.84) 129.09,88.89 128.87,89.11 UC1.D15 ; JEDP1.12 v1(213.37,54.95)
EDP_TXN0: length 108.6
  IN2 w0.127: v1(143.38,101.38) 143.54,101.22 143.85,101.22 146.62,98.46 146.62,93.05 154.53,85.14 164.67,85.14 180.99,68.81 182.1,68.81 183.99,66.92 188.94,66.92 192.26,63.61 197.4,63.61 199.73,61.28 199.73,58.03 205.77,51.98 206.47,51.98 v1(206.55,52.07)
  BOTTOM w0.102: CV4.1 207.84,51.95 206.67,51.95 v1(206.55,52.07) ; UC1.B9 131.88,90.55 131.88,90.8 131.77,90.9 131.71,90.9 131.52,91.09 131.52,93.34 139.41,101.23 143.22,101.23 v1(143.38,101.38)
EDP_TXN0_C: length 3.9
  BOTTOM w0.102: JEDP1.18 211.91,51.95 211.79,51.82 211.33,51.82 211.3,51.85 210.79,51.85 210.68,51.95 v3(209.66,51.95) 208.78,51.95 CV4.2
EDP_TXN1: length 113.8
  IN2 w0.127: v1(207.93,50.9) 207.78,50.74 207.51,50.74 207.28,50.97 207.28,52.3 200.52,59.06 200.52,61.61 197.67,64.46 192.53,64.46 189.18,67.81 185.27,67.81 183.27,69.81 181.87,69.81 178.09,73.59 177.35,73.59 165,85.94 154.86,85.94 147.42,93.38 147.42,98.84 143.59,102.66 142.56,102.66 v1(142.47,102.76)
  BOTTOM w0.102: v1(207.93,50.9) 208.21,50.62 208.78,50.62 208.92,50.48 CV6.1 ; UC1.B10 131.06,90.38 131.06,90.63 130.98,90.72 130.98,91 131.04,91.06 131.04,94.6 139.19,102.76 140.1,102.76 140.12,102.78 140.69,102.78 140.72,102.76 v1(142.47,102.76)
EDP_TXN1_C: length 2.4
  BOTTOM w0.102: JEDP1.21 211.84,50.45 211.69,50.3 211.37,50.3 211.34,50.33 210.77,50.33 210.75,50.3 210.31,50.3 CV6.2
EDP_TXP0: length 108.5
  IN2 w0.127: v1(143.38,100.8) 143.54,100.96 143.74,100.96 146.36,98.35 146.36,92.94 154.42,84.87 164.56,84.87 180.89,68.55 181.99,68.55 183.88,66.66 188.83,66.66 192.15,63.34 197.29,63.34 199.46,61.17 199.46,57.92 205.66,51.72 206.31,51.72 v1(206.55,51.48)
  BOTTOM w0.102: v1(206.55,51.48) 206.82,51.75 207.83,51.75 208.02,51.56 CV5.1 ; v1(143.38,100.8) 143.15,101.02 139.49,101.02 131.72,93.25 131.72,92.24 131.82,92.14 132.2,92.14 132.3,92.03 132.3,91.83 132.2,91.73 131.82,91.73 131.72,91.63 131.72,91.39 131.83,91.28 UC1.A9
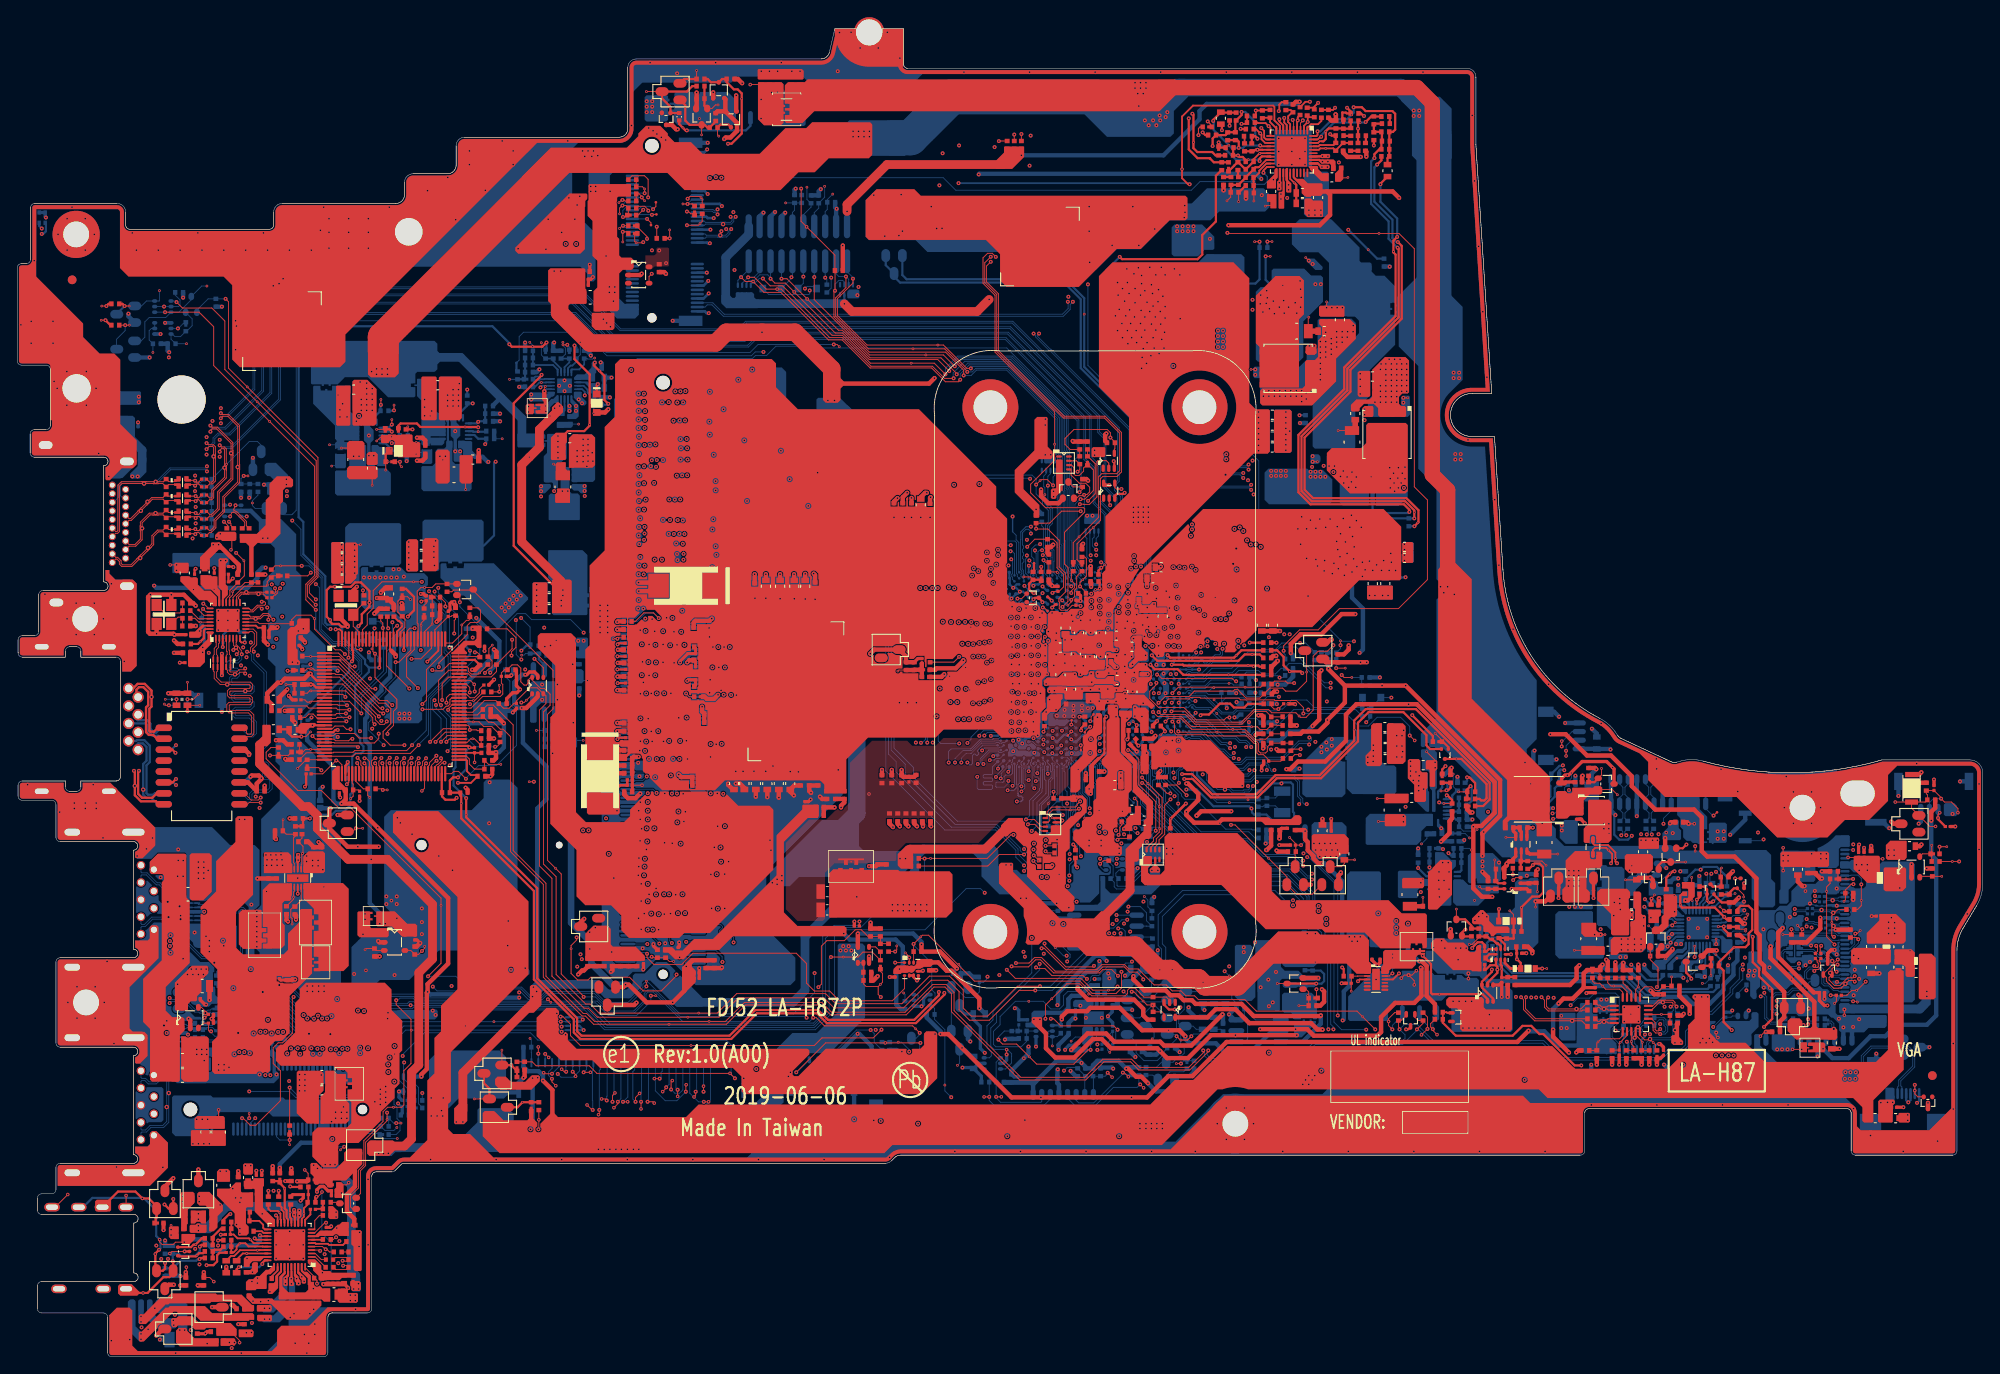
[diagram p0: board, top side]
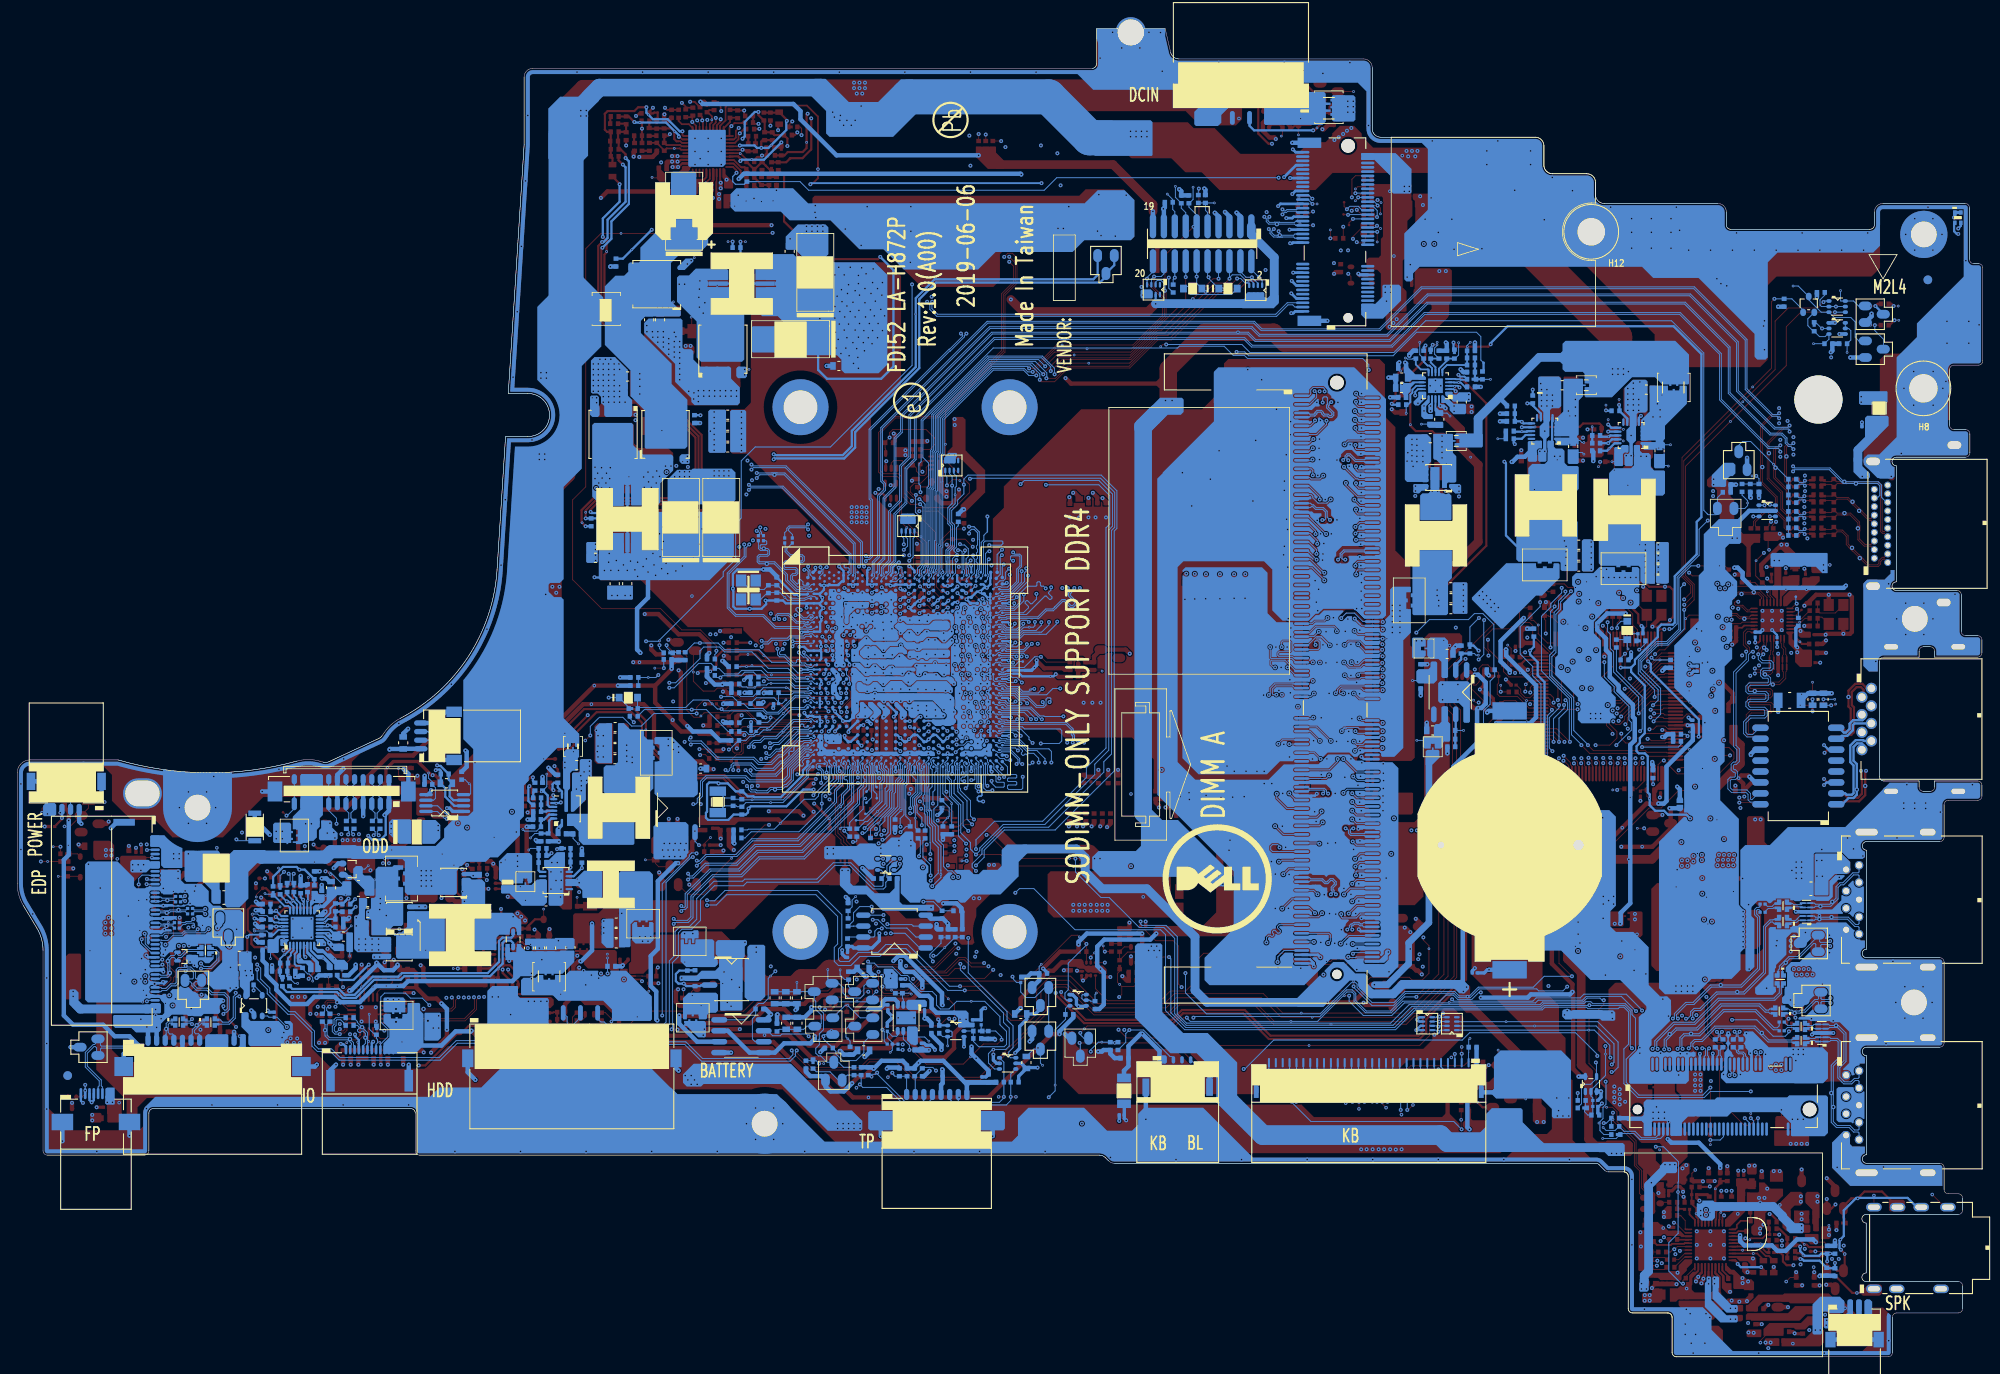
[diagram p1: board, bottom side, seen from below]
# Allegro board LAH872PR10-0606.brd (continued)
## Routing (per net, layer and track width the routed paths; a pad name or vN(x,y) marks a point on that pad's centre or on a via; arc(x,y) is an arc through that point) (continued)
EDP_TXP0_C: length 4
  BOTTOM w0.102: JEDP1.19 211.93,51.45 211.76,51.62 v3(211.02,51.62) 210.73,51.62 210.6,51.75 209.97,51.75 209.94,51.72 209.38,51.72 209.35,51.75 208.86,51.75 CV5.2
EDP_TXP1: length 113.7
  IN2 w0.127: v1(207.93,50.03) 207.93,50.35 207.81,50.48 207.6,50.48 207.4,50.48 207.02,50.86 207.02,52.19 200.26,58.95 200.26,61.5 197.56,64.19 192.42,64.19 189.07,67.55 185.16,67.55 183.16,69.55 181.76,69.55 177.98,73.33 177.24,73.33 164.89,85.67 154.75,85.67 147.15,93.27 147.15,98.73 143.49,102.4 142.7,102.4 142.54,102.24 142.54,102.24 v1(142.47,102.17)
  BOTTOM w0.102: CV7.1 209.11,50.27 208.83,50.27 208.7,50.41 207.9,50.41 207.81,50.32 207.81,50.14 207.91,50.03 v1(207.93,50.03) ; UC1.A10 131.24,90.9 131.24,94.52 139.28,102.55 v3(140.41,102.55) 142.09,102.55 142.47,102.18 v1(142.47,102.17)
EDP_TXP1_C: length 2.4
  BOTTOM w0.102: JEDP1.22 211.89,49.95 211.74,50.1 v3(211.06,50.1) 210.38,50.1 CV7.2
EGPIO131: length 1.4
  TOP w0.102: RC75.2 119.37,72.79 v1(119.25,72.68)
  BOTTOM w0.102: UC1.AP31 119.69,73.11 v1(119.25,72.68)
EN_0.6VSP: length 5
  BOTTOM w0.102: v2(60.91,117.9) 60.91,116.48 61.32,116.06 PRM09.2
  BOTTOM w0.203: PUM01.7 63.2,114.89 62.29,115.79 PCM16.1 PRM09.2
EN_0.95V: length 5.9
  TOP w0.102: v2(165.45,65.79) 166,65.79 v1(166.09,65.88)
  TOP w0.254: v1(166.09,65.88) 166.28,65.88 166.53,66.13 166.53,66.16 166.55,66.18 PRH02.1 PRH01.2
  BOTTOM w0.254: PUH01.6 165.1,65.71 165.58,66.2 PRH01.2 166.01,66.74 166.19,66.56 166.19,65.98 v1(166.09,65.88)
EN_1.2V: length 5
  BOTTOM w0.102: PCM15.1 63.7,116.57 63.7,117.29 63.41,117.58 v2(63.41,117.95)
  BOTTOM w0.203: PCM15.1 PRM08.2 64.16,115.62 63.6,115.06 PUM01.8
EN_1.8V: length 2.8
  BOTTOM w0.254: PU1801.5 164.24,56.65 164.11,56.79 v1(164.11,56.9) PC1805.1 PR1802.1 PR1801.2
EN_2.5V: length 4.3
  BOTTOM w0.102: PR2501.2 59.08,81.77 58.89,81.58 v2(58.62,81.58)
  BOTTOM w0.254: PR2501.2 PC2503.1 60.61,81.08 61.25,80.45 PU2501.2
EN_3V: length 11.1
  TOP w0.254: v1(53.56,108.08) 53.53,108.11 v2(52.03,108.11) 46.85,108.11 46.44,108.51 44.55,108.51 44.29,108.26 PR502.1
  BOTTOM w0.254: PU301.12 v1(53.56,108.08)
EN_5V: length 3
  TOP w0.102: v2(41.77,107.83) PR503.1
  TOP w0.254: PR503.1 43.27,107.83 v1(43.53,107.57)
  BOTTOM w0.254: PU501.12 v1(43.53,107.57)
ENABLE_APU: length 82.7
  TOP w0.102: v1(75.81,130.04) v2(75.81,131.02)
  TOP w0.203: PUZ01.8 147.12,143.17 146.66,143.63 v1(146.66,143.89)
  TOP w0.254: PRZ85.2 v1(75.81,130.04)
  IN1 w0.254: v1(117.64,138.49) 134.56,138.49 140.33,144.25 145.97,144.25 146.34,143.89 v1(146.66,143.89)
  IN2 w0.127: v1(75.81,130.04) 75.81,134.42 80.14,138.74 117.38,138.74 v1(117.64,138.49)
ENLDO_3V5V: length 15.8
  TOP w0.102: v1(43.53,108.39) v2(43.53,108.96)
  IN2 w0.254: v1(53.56,108.7) 53.25,108.7 52.93,108.39 v1(43.53,108.39)
  BOTTOM w0.254: PU501.11 43.16,108.02 v1(43.53,108.39) ; PR302.1 PR303.1 PC317.1 53.63,108.77 v1(53.56,108.7) 53.39,108.53 PU301.11
ENVDD: length 127.8
  TOP w0.102: v2(224.21,59.3) v1(223.38,59.3) RV4.2 ; v1(128.3,100.9) 127.73,100.9 127.54,101.09 UC9.4 ; v1(124.43,99.52) 125.26,100.35 125.26,103.84 124.4,104.7 RC21.2 RC19.1
  IN1 w0.127: v1(124.43,99.52) 126.93,99.52 v1(128.3,100.9) 131.25,100.9 133.66,98.48 137.51,98.48 143.48,92.51 144.88,92.51 147.1,90.29 147.1,90.1 152.52,84.68 158.62,84.68 166.09,77.21 175.55,77.21 182.73,70.03 183.56,70.03 186.29,67.29 189.03,67.29 189.49,66.83 195.11,66.83 202.57,59.37 212.29,59.37 213.16,58.5 215.26,58.5 216.73,59.98 222.7,59.98 v1(223.38,59.3)
ENVDD_R: length 23.9
  TOP w0.102: RPC2.6 122.51,103.68 122.77,103.42 122.77,102.66 122.96,102.46 123.41,102.46 123.92,102.97 123.92,103.34 RC21.1 125.06,103.09 125.06,100.72 124.05,99.71 v1(123.57,99.71) ; v1(127,99.02) 126.99,99.02 126.89,99.12 UC9.2
  IN1 w0.127: v1(127,99.02) 124.34,99.02 123.65,99.71 v1(123.57,99.71)
  BOTTOM w0.102: UC1.B24 123.58,90.41 123.27,90.73 123.27,91 123.35,91.08 123.35,91.39 123.1,91.64 123.1,91.81 122.91,92 122.91,99.14 123.48,99.71 v1(123.57,99.71)
ENVDD_RE: length 3.4
  TOP w0.102: v2(222.46,59.47) RV4.1 ; RV4.1 221.4,58.48 UV1.4 ; RV4.1 RV5.1
FAN1_PWM: length 197
  TOP w0.102: v1(38.95,71.84) 38.74,71.84 38.52,71.63 36.99,71.63 36.79,71.82 UE1.26 34.66,71.82 v1(34.31,72.17) ; v1(179.98,70.46) v4(179.98,69.86)
  IN1 w0.127: v1(65.61,46.23) 65.75,46.09 65.84,46.09 71.64,40.29 93.5,40.29 95.36,38.43 98.07,38.43 99.03,37.47 102.15,37.47 102.3,37.62 104.18,37.62 104.56,37.24 106.17,37.24 106.31,37.1 108.1,37.1 108.82,37.82 116.15,37.82 116.7,37.28 124.61,37.28 125.17,37.84 127.01,37.84 127.8,38.63 141.46,38.63 147.98,45.14 147.98,46.11 148.27,46.41 148.27,48.66 149.39,49.78 150.13,49.78 154.68,54.33 154.68,68.14 157.04,70.5 157.04,71.32 158.57,72.85 175.33,72.85 177.72,70.46 v1(179.98,70.46)
  IN2 w0.127: v1(65.61,46.23) 65.46,46.38 63.26,46.38 50.14,59.5 50.14,66.56 48.5,68.19 39.47,68.19 38.95,68.71 v1(38.95,71.84)
  BOTTOM w0.102: JFAN1.2 180.63,71.69 179.98,71.04 v1(179.98,70.46) ; RE51.1 34.52,72.39 v1(34.31,72.17)
FAN1_TACH: length 200.1
  TOP w0.102: UE1.28 39.4,71.02 39.54,70.89 v1(39.59,70.89) ; v1(179.47,70.96) v4(179.47,71.59)
  IN1 w0.127: v1(179.47,70.96) 177.81,70.96 175.67,73.1 158.42,73.1 156.79,71.47 156.79,70.6 154.84,68.66 154.78,68.66 153.63,67.51 153.63,63.28 153.87,63.04 153.87,61.04 154.43,60.48 154.43,57.68 153.06,56.31 153.06,54.92 151.86,53.73 151.86,51.87 150.09,50.1 149.32,50.1 147.94,48.71 147.94,46.44 147.72,46.22 147.72,45.25 141.36,38.88 127.69,38.88 126.91,38.1 125.07,38.1 124.5,37.53 116.8,37.53 116.26,38.08 104.16,38.08 103.95,37.87 102.68,37.87 101.82,38.73 95.42,38.73 93.6,40.54 71.74,40.54 66.57,45.71 66.57,45.86 65.67,46.76 65.49,46.76 v1(65.46,46.79)
  IN2 w0.127: v1(39.59,70.89) 42.05,70.89 42.39,70.54 49.12,70.54 49.88,69.78 50.33,69.78 50.9,69.21 50.9,68.07 50.52,67.69 50.52,66.48 51.34,65.65 52.17,65.65 52.61,65.21 52.61,57.38 63.2,46.79 v1(65.46,46.79)
  BOTTOM w0.102: JFAN1.3 180.68,72.69 179.47,71.48 v1(179.47,70.96) ; RE52.1 35.07,71.19 35.38,70.89 v1(39.59,70.89)
FB_0.95V: length 3.1
  BOTTOM w0.254: PUH01.10 166.83,63.48 166.92,63.39 PRH09.1 PRH08.1 PRH12.2
FB_1.2V: length 6.2
  BOTTOM w0.102: PRM11.1 59.93,117.58 v2(59.56,117.95)
  BOTTOM w0.203: PUM01.6 62.8,114.78 62.26,115.31 PRM10.1 PCM17.1 PRM11.1
FB_1.8V: length 4.3
  BOTTOM w0.102: v2(168.96,58.92) 168.77,59.11 PR1806.2
  BOTTOM w0.254: PU1801.6 167.63,56.38 167.81,56.56 PR1805.1 PC1807.2 PR1806.2
FB_3V: length 2.1
  BOTTOM w0.254: PU301.13 52.93,107.63 52.99,107.56 v2(53.56,107.56) 54.44,107.56 PC315.1
FB_3V_R: length 1.8
  BOTTOM w0.102: PR306.1 v2(56.36,106.74)
  BOTTOM w0.508: PC315.2 PR306.1
FB_5V: length 2.2
  BOTTOM w0.254: PC517.1 44.32,106.97 v2(43.51,106.97) 43.43,106.97 43.28,107.12 PU501.13
FB_5V_R: length 1.9
  BOTTOM w0.102: PC517.2 v2(45.39,108.14)
  BOTTOM w0.254: PR509.1 PC517.2
FFS_INT1: length 49.6
  TOP w0.102: RC57.1 118.66,57.76 v1(118.12,58.3) ; US2.12 v1(103.66,46.42) 103.66,46.51 v2(103.21,46.96)
  IN1 w0.127: v1(118.09,71.92) 118.62,71.4 118.62,69.43 118.03,68.85 118.03,67.45 117.94,67.36 117.94,66.66 117.61,66.33 117.61,65.18 115.34,62.9 115.34,59.16 116.61,57.89 117.17,57.89 117.59,58.3 v1(118.12,58.3) 117.65,57.84 117.65,55.85 118.91,54.6 118.91,51.66 117.19,49.94 117.19,48.04 117.61,47.62 117.61,46.44 115.74,44.57 114.65,44.57 113.51,45.72 104.36,45.72 v1(103.66,46.42)
  BOTTOM w0.102: v1(118.09,71.92) 118.51,71.51 UC1.AU33
FFS_INT2: length 80
  TOP w0.102: US2.11 104.16,45.84 RC59.1 v1(104.16,48) v2(104.99,48.83) 105.18,49.02 105.89,49.02 111.23,43.68 123.48,43.68 124.91,42.25 127.69,42.25 128.31,42.87 v1(128.31,44.76)
  IN1 w0.102: v1(136.91,76.25) 136.94,76.28 137.65,76.28 139.47,74.47 139.47,68.68 139.23,68.44 139.23,66 139.8,65.43 139.8,65.28
  IN1 w0.127: 139.8,65.28 139.8,65.18 139.86,65.11 139.86,57.62 132.43,50.19 132.43,48.7 130.15,46.41 129.41,46.41 128.31,45.32 v1(128.31,44.76)
  BOTTOM w0.102: QS1.2 106.46,41.46 106.65,41.65 106.65,42.29 106.27,42.67 106.27,45.77 104.16,47.87 v1(104.16,48) ; UC1.AH2 135.73,76.06 136.08,76.4 136.3,76.4 136.49,76.21 136.87,76.21 v1(136.91,76.25)
FFS_INT2_Q: length 102.3
  IN1 w0.127: v1(108.53,30.18) 109.02,30.67 118.47,30.67 118.79,30.35 123.33,30.35 123.81,30.82 135.19,30.82 137.45,33.09 144.7,33.09 147.62,36.01 147.62,36.97 151.19,40.53 179.9,40.53 180.25,40.88 v1(180.51,40.88)
  BOTTOM w0.102: v1(180.51,40.88) 181.32,41.7 182.71,41.7 183.3,42.29 185.71,42.29 186.15,41.84 186.15,38.92 185.33,38.1 185.33,37.21 186.2,36.33 JHDD1.9 ; QS1.3 106.28,40.81 106.59,40.51 106.59,39.82 RS24.2 106.6,39.23 107.79,38.03 v2(107.79,31.59) 107.79,30.92 v1(108.53,30.18)
FPR_SCAN#: length 241.1
  TOP w0.102: UE1.118 41.33,81.99 v1(41.58,81.75) 41.58,78.98 44.11,76.44 44.11,75.44 43.72,75.05 43.72,73.4 43.02,72.7 v1(43.02,72.42) ; v1(220.5,31.62) v4(220.5,30.95) 220.5,30.58 220.86,30.22 EU2.3
  IN1 w0.127: v1(220.5,31.62) 220.5,32.2 215.43,37.27 215.43,42.16 214.79,42.79 206.22,42.79 205.71,42.29 204.4,42.29 202.8,40.68 199.12,40.68 198.5,40.06 194.75,40.06 193.67,41.14 189.84,41.14 189.76,41.05 182.99,41.05 182.22,40.28 151.44,40.28 149.96,38.79 149.96,37.65 145.06,32.75 137.47,32.75 135.29,30.57 124.04,30.57 123.23,29.76 108.26,29.76 107.67,30.35 87.41,30.35 82.81,34.95 68.16,34.95 66.45,36.66 65.37,36.66 63.84,38.19 63.84,39.45 62.81,40.49 60.29,40.49 59.27,41.5 59.27,44.16 59.7,44.59 59.7,51.04 57.56,53.18 57.56,61.2 52.87,65.89 52.87,67.56 51.8,68.63 51.8,69.07 51.02,69.85 51.02,71.66 49.72,72.96 43.56,72.96 v1(43.02,72.42)
  BOTTOM w0.102: JFP1.2 v1(220.5,31.62) ; v1(41.58,81.75) 42.08,81.24 RE23.1
FSET: length 5.5
  BOTTOM w0.102: v2(194.06,43.68) 194.06,44.1 194.47,44.51 194.65,44.51 195.25,45.11 PRB38.1
  BOTTOM w0.203: PRB38.1 195.49,45.46 195.97,45.46 196.16,45.65 196.16,46.82 195.9,47.08 PUB01.3
GATEA20: length 179.1
  TOP w0.102: v1(134.01,64.81) 133.34,64.14 133.34,60.76 132.68,60.1 132.68,59.73 132.23,59.28 RPC7.6 ; UE1.1 37.33,81.82 38.89,80.26 v1(39.21,80.26)
  IN1 w0.102: v1(119.24,71.18) 119.47,71.41 120.42,71.41 121.25,72.24 123.97,72.24 124.28,72.55 125.2,72.55 125.33,72.68 129.51,72.68 133.29,68.89 133.29,65.53 133.54,65.28
  IN1 w0.127: 133.54,65.28 v1(134.01,64.81) 134.01,64.33 134.53,63.81 136.94,63.81 137.58,63.18 137.58,59.05 132.69,54.16 132.11,54.16 131.42,53.46 131.42,52.56 128.88,50.02 128.88,48.58 127.03,46.74 127.03,45.84 126.69,45.5 126.29,45.5 125.62,44.83 119.93,44.83 117.54,42.44 110.59,42.44 110.04,41.89 106.4,41.89 105.43,42.85 97.93,42.85 95.38,45.4 86.93,45.4 85.87,44.34 77.61,44.34 76.11,45.84 74.48,45.84 74.26,45.61 73.2,45.61 70.71,48.11 70.71,53.53 69.76,54.48 69.76,57.18 69.67,57.27 69.67,59.2 69.11,59.75 69.11,61.24 64.75,65.6 64.75,70.92 60.57,75.09 60.57,77.88 59.56,78.9 59.56,79.67 59.31,79.92 v1(59.03,79.92)
  IN2 w0.127: v1(39.21,80.26) 39.25,80.3 39.94,80.3 40.55,79.69 46.71,79.69 47.53,78.86 49.44,78.86 49.49,78.81 54.89,78.81 55.24,79.16 56.6,79.16 57.35,79.92 v1(59.03,79.92)
  BOTTOM w0.102: v1(119.24,71.18) 119.18,71.12 118.41,71.12 118.03,71.51 UC1.AU35
GPIO93: length 7.4
  BOTTOM w0.102: UC1.BA29 120.83,67.53 120.84,67.52 120.84,65.48 119.81,64.45 v2(119.81,64.31) RC53.2
H_PROCHOT#: length 409.9
  TOP w0.102: v1(49.75,87.24) 49.75,87.7 RE33.2 ; PQB32.1 v1(199.61,55.62) ; v1(132.3,61.17) 132.3,64.56 130.33,66.52 130.33,69.47 129.25,70.55 v1(129.08,70.55) ; v1(173.83,55.43) 174.11,55.71 PQ12.3
  TOP w0.203: PRZ21.2 148.8,144.11 v1(148.8,143.76) 148.72,143.68 PUZ01.4
  TOP w0.254: v1(194.53,43.95) 194.53,44.07 193.93,44.67 PQ11.1
  IN1 w0.102: v1(122.48,70.8) 122.63,70.65 124.74,70.65 124.89,70.8 128.83,70.8 v1(129.08,70.55) ; 119.55,94.49 119.55,93.31 119.44,93.2 v1(119.18,93.2)
  IN1 w0.127: v1(194.53,43.95) 194.2,43.62 192.82,43.62 192.57,43.87 192.57,45.62 196.78,49.84 196.78,52.65 196.66,52.78 196.66,54.9 197.4,55.64 v1(197.4,56.38) ; v1(109.44,140.84) 109.89,140.4 109.89,135.5 104.62,130.24 104.62,108.29 110.78,102.14 113.41,102.14 119.55,96 119.55,94.49 ; v1(50.23,82.47) 50.23,81.94 51.87,80.3 53.39,80.3 53.56,80.13 55.1,80.13 55.85,79.39 55.85,78.06 55.6,77.81 55.6,76.56 56.36,75.8 56.36,74.48 57.06,73.78 57.06,73.11 61.89,68.28 61.89,54.98 64.52,52.35 64.52,45.24 64.82,44.94 65.73,44.94 66.71,43.96 68.33,42.34 68.33,42.13 71.05,39.4 89.98,39.4 93.38,36 103.75,36 104.44,35.31 105.47,35.31 105.76,35.61 111.51,35.61 111.68,35.78 116.6,35.78 117.09,35.3 119.42,35.3 120.24,36.13 125.32,36.13 v1(125.51,36.32) 125.79,36.6 136.73,36.6 137.37,37.23 142.94,37.23 149.37,43.67 149.37,45.51 149.77,45.9 149.77,45.9 150.43,46.57 162.49,46.57 166.05,50.12 166.12,50.12 169.45,53.44 169.45,53.52 171.36,55.43 v1(173.83,55.43) ; v1(148.8,143.76) 148.8,144.1 147.54,145.35 139.1,145.35 133.83,140.08 119.67,140.08 v1(117.76,141.98)
  IN2 w0.102: v1(122.48,70.8) 122.48,71.2 121.88,71.79 121.88,73.24 121.42,73.7 120.83,73.7 120.17,74.36 120.17,75.35 119.5,76.02 119.5,77.53 119.6,77.64 119.98,78.02 119.98,78.86 120.08,78.97 120.08,79.84 119.98,79.95 119.98,82.84 120.19,83.06 120.19,85.6 119.81,85.98 119.81,92.79 119.4,93.2 v1(119.18,93.2)
  IN2 w0.127: v1(173.83,55.43) 174.31,55.91 174.31,57.11 175.29,58.1 176.5,58.1 177.39,58.99 187.55,58.99 187.93,58.61 195.17,58.61 v1(197.4,56.38) 198.22,56.38 198.98,55.62 v1(199.61,55.62) ; v1(109.44,140.84) 111.35,140.84 113.32,142.81 116.87,142.81 117.7,141.98 v1(117.76,141.98) ; v1(132.3,61.17) 132.3,58.1 133.26,57.15 133.26,55.49 131.61,53.84 131.61,52.52 130.82,51.73 130.82,44.72 130.4,44.31 130.4,42.71 127.16,39.47 127.16,37.35 126.13,36.32 v1(125.51,36.32)
  BOTTOM w0.102: v1(49.75,87.24) 49.75,87.12 50.23,86.64 v1(50.23,82.47) ; UC1.A31 119.73,92.79 119.39,93.13 119.25,93.13 v1(119.18,93.2) 119.18,93.34 119.55,93.71 119.55,93.85 119.25,94.15 119.25,96.42 119.05,96.63 RC33.2 ; PRB21.1 197.85,55.93 v1(197.4,56.38) ; RC37.2 131.66,60.53 v1(132.3,61.17)
HDA_BIT_CLK: length 101.4
  TOP w0.102: v1(134,65.51) 133.61,65.51 132.63,66.48 RC87.2
  IN2 w0.127: v1(63.26,38.38) 64.11,38.38 65.86,36.63 68.35,36.63 68.56,36.42 88.35,36.42 88.54,36.24 100.37,36.24 102.72,38.59 108.7,38.59 109.29,39.17 116.76,39.17 117.76,40.17 118.52,40.17 125.5,47.15 125.5,56.55 125.42,56.64 125.42,58.26 125.76,58.61 125.76,58.9 125.5,59.16 125.5,60.49 125.31,60.68 125.31,61.9 126.93,63.51 131.95,63.51 133.95,65.51 v1(134,65.51)
  BOTTOM w0.102: v1(134,65.51) 134,65.85 132.96,66.89 132.96,67.68 133.21,67.94 133.21,68.46 133.24,68.48 133.24,68.73 133.21,68.76 133.21,68.8 133.18,68.83 133.18,69.08 133.21,69.12 133.21,69.16 133.24,69.18 133.24,69.27 133.48,69.51 UC1.AY6 ; RPC4.7 63.16,38.48 v1(63.26,38.38) 63.36,38.48 RPC5.6
HDA_BIT_CLK_R: length 54.7
  TOP w0.102: RA50.2 36.29,12.19 35.98,12.5 v1(35.85,12.5) 35.72,12.63 35.66,12.63 35.48,12.81 UA1.5
  IN2 w0.127: v1(35.85,12.5) 35.72,12.63 35.66,12.63 35.47,12.82 35.47,16.19 36.04,16.76 36.04,19.29 35.22,20.11 34.48,20.11 32.8,21.78 32.8,27.49 38.67,33.36 42.49,33.36 v1(43.11,33.99)
  BOTTOM w0.102: RPC4.2 60.8,38.48 60.78,38.46 v2(52.08,38.46) 44.93,38.46 42.86,36.39 42.86,34.25 v1(43.11,33.99)
HDA_CODEC_SDIN0: length 1.3
  TOP w0.203: UA1.7 35.48,13.61 RA30.2
HDA_RST#: length 99.7
  TOP w0.102: v1(63.15,39.55) 63.41,39.55 64.3,38.67 64.3,37.33 65.44,36.19 v2(78.29,36.19) 92.62,36.19 93.51,37.08 99.48,37.08 v1(100.43,38.03)
  IN2 w0.102: 132.29,65.28 134.08,67.07 134.08,67.66 v1(134.36,67.93)
  IN2 w0.127: v1(100.43,38.03) 100.62,38.03 102.11,39.53 108.31,39.53 108.9,40.11 116.35,40.11 117.34,41.11 118.13,41.11 124.4,47.37 124.4,53.58 124.22,53.76 124.22,55.79 124.47,56.04 124.47,58.73 124.13,59.07 124.13,61.3 124.14,61.32 124.14,62.06 126.61,64.53 131.54,64.53 132.29,65.28
  BOTTOM w0.102: v1(134.36,67.93) 134.36,68.71 134.28,68.79 134.28,69.08 134.58,69.39 UC1.AY4 ; RPC5.8 63.48,39.48 63.41,39.55 v1(63.15,39.55) 63.02,39.55 62.95,39.48 RPC4.5
HDA_SDIN0: length 164.9
  TOP w0.102: v1(37.05,13.9) 36.99,13.9 36.74,13.65 RA30.1
  IN2 w0.127: v1(85.89,33.46) 86.15,33.72 108.94,33.72 109.47,34.25 110.46,34.25 112.18,35.96 112.69,35.96 112.88,35.77 116.4,35.77 117.05,35.12 119.04,35.12 122.54,38.62 122.54,40.93 124.73,43.12 124.73,44.3 126.16,45.73 126.16,46.48 126.44,46.76 126.44,56.72 126.7,56.98 126.7,58.62 126.87,58.8 126.87,60.14 127.25,60.52 127.25,61.51 128.32,62.57 133.15,62.57 v1(134.9,64.32) ; v1(37.05,13.9) 37.5,14.35 37.5,17.65 37.05,18.09 37.05,19.6 35.61,21.05 34.87,21.05 33.74,22.17 33.74,26.91 39.26,32.42 43.16,32.42 43.66,32.93 43.66,33.84 v1(44.79,34.98)
  BOTTOM w0.102: RC86.2 143.83,60.32 143.11,61.04 137.56,61.04 134.9,63.7 v1(134.9,64.32) 134.9,65.38 133.97,66.31 133.16,67.12 133.16,67.51 133.42,67.77 133.42,68.37 133.44,68.4 133.44,68.82 133.42,68.84 133.42,68.88 133.41,68.89 UC1.BA6 ; v1(85.89,33.46) 85.76,33.46 82.39,36.83 60.49,36.83 59.64,37.68 47.32,37.68 44.79,35.15 v1(44.79,34.98)
HDA_SDIN1: length 15.6
  BOTTOM w0.102: UC1.AY5 134.03,69.05 133.77,68.78 133.77,68.78 133.73,68.73 133.73,68.48 133.77,68.44 133.77,67.84 133.57,67.63 133.57,67.15 135.29,65.42 135.29,65.21 135.67,64.83 136.94,64.83 v2(139.73,62.03) 140.42,61.35 143.44,61.35 143.53,61.26 RC83.2
HDA_SDIN2: length 7.1
  TOP w0.102: v1(135.88,65.3) 134.7,66.48 RC85.2
  BOTTOM w0.102: v1(135.88,65.3) 133.97,67.2 133.97,68.48 134.03,68.54 UC1.BA5
HDA_SDOUT: length 100
  IN2 w0.127: v1(63.26,37.8) 63.32,37.86 63.91,37.86 65.65,36.12 67.88,36.12 68.17,35.83 88.22,35.83 88.33,35.73 100.58,35.73 102.93,38.08 108.91,38.08 109.5,38.66 116.97,38.66 117.04,38.73 117.04,38.73 117.97,39.66 118.73,39.66 126.01,46.94 126.01,56.9 126.27,57.16 126.27,58.8 126.39,58.92 126.39,60.3 126.82,60.73 126.82,61.68 128.14,63 132.93,63 134.99,65.06 v1(134.99,66.73)
  BOTTOM w0.102: RPC5.5 63.53,37.98 63.34,37.8 v1(63.26,37.8) 63.14,37.92 63.06,37.92 62.99,37.98 RPC4.8 ; v1(134.99,66.73) 134.94,66.78 134.94,68.08 135.1,68.23 135.31,68.23 135.56,68.48 135.56,68.83 135.43,68.96 134.59,68.96 UC1.BA4
HDA_SDOUT_R: length 52.3
  TOP w0.102: UA1.4 35.1,12.41 v1(35.2,12.31)
  IN2 w0.127: v1(43.27,34.79) 43.05,34.57 42.93,34.57 42.23,33.87 38.42,33.87 32.29,27.74 32.29,21.57 34.26,19.6 35.01,19.6 35.4,19.2 35.4,16.95 34.96,16.51 34.96,12.56 v1(35.2,12.31)
  BOTTOM w0.102: RPC4.1 v2(45.79,37.98) 45.13,37.98 43.34,36.19 43.34,34.86 v1(43.27,34.79)
HDA_SYNC: length 97.6
  IN2 w0.102: 134.46,66.98 v1(134.46,67.3)
  IN2 w0.127: 134.46,66.98 134.46,66.91 133.2,65.65 133.2,65.52 131.77,64.1 126.79,64.1 124.8,62.11 124.8,60.43 125,60.24 125,58.65 124.91,58.56 124.91,55.86 124.65,55.61 124.65,54.23 124.83,54.05 124.83,47.19 118.31,40.67 117.55,40.67 116.55,39.68 109.08,39.68 108.49,39.09 102.51,39.09 100.16,36.74 88.75,36.74 88.56,36.93 68.77,36.93 68.56,37.14 66.07,37.14 64.24,38.97 v1(63.17,38.97)
  BOTTOM w0.102: v1(134.46,67.3) 134.74,67.57 134.74,68.16 UC1.BA3 ; RPC4.6 63.15,38.98 v1(63.17,38.97) 63.18,38.98 RPC5.7
HDA_SYNC_R: length 51.8
  TOP w0.102: UA1.9 34.56,14.41 35.74,15.58 35.88,15.58 35.88,15.59 v1(35.89,15.59)
  IN2 w0.127: v1(43.13,33.11) 42.87,32.86 38.99,32.86 33.31,27.17 33.31,21.99 34.69,20.62 35.43,20.62 36.61,19.43 36.61,16.31 v1(35.89,15.59)
  BOTTOM w0.102: RPC4.3 60.98,38.98 60.97,38.96 v2(55.39,38.96) 44.74,38.96 42.38,36.59 42.38,33.66 42.93,33.11 v1(43.13,33.11)
HDD_A0_EQ: length 3.6
  TOP w0.102: US1.18 187.56,42.49 v2(187.06,42.99) 186.6,43.45 RS12.2 RS13.1
HDD_A0_PRE0: length 3.4
  TOP w0.102: US1.9 188.06,37.42 188.83,36.65 v2(188.83,36.57) 188.83,35.71 RS20.1 RS7.2
HDD_A0_PRE1: length 3.3
  TOP w0.102: US1.17 188.06,42.7 v2(188.38,43.01) RS19.1 RS10.2
HDD_B0_EQ: length 3.5
  TOP w0.102: US1.13 v2(191.05,39.81) 191.92,39.81 RS15.1 RS14.1
HDD_B0_PRE0: length 3.2
  TOP w0.102: US1.8 v2(187.56,36.66) 187.56,36.37 187.87,36.06 RS18.1 RS8.2
HDD_B0_PRE1: length 4.8
  TOP w0.102: RS11.2 RS21.1 184.82,43.49 185.2,43.11 v2(185.52,43.11) 186.41,43.11 187.06,42.46 US1.19
HDMI_CLKN: length 3.2
  TOP w0.102: RV11.1 LV2.2 20.73,100.07 v1(20.74,100.07) 20.93,99.87 21.09,99.87 CV15.2
  BOTTOM w0.102: v1(20.74,100.07) 20.93,99.88 21.36,99.88 RV16.1
HDMI_CLKP: length 3.2
  TOP w0.102: CV16.2 21.06,99.67 20.92,99.67 v1(20.74,99.49) 20.66,99.57 LV2.3 19.67,99.4 RV13.1
  BOTTOM w0.102: v1(20.74,99.49) 20.87,99.63 21.37,99.63 21.67,99.32 RV17.1
HDMI_CTRL_CLK: length 26.9
  TOP w0.102: RV39.2 24.47,96.44 24.47,96.64 v1(24.02,97.09)
  IN2 w0.127: v1(22.05,103.53) 22.21,103.37 23.25,103.37 23.53,103.09 23.53,96.65 23.66,96.53 24.06,96.53 24.18,96.65 24.18,96.93 v1(24.02,97.09) 24.02,97.59 24.73,98.3 v1(24.73,99.07)
  BOTTOM w0.102: v1(22.05,103.53) 21.86,103.34 17.75,103.34 16.14,101.74 12.14,101.74 11.77,101.36 11.77,99.93 11.19,99.35 JHDMI1.15 ; v1(24.73,99.07) 24.7,99.07 24.64,99.01 QV3.6
HDMI_CTRL_DATA: length 26.6
  TOP w0.102: v1(24.61,97.09) 24.84,96.86 24.84,96.64 RV38.2
  IN2 w0.127: v1(22.05,102.95) 22.21,103.11 23.14,103.11 23.26,102.98 23.26,96.54 23.55,96.26 24.17,96.26 24.45,96.54 24.45,96.93 v1(24.61,97.09) 26.02,97.09 26.64,97.71 v1(26.67,97.71)
  BOTTOM w0.102: JHDMI1.16 12.26,99.85 11.97,100.13 11.97,101.28 12.23,101.53 16.22,101.53 17.83,103.14 21.86,103.14 v1(22.05,102.95) ; QV3.3 v1(26.67,97.71)
HDMI_HPD: length 20.3
  TOP w0.102: v1(26.32,102.42) v2(26.82,102.42)
  IN1 w0.127: JHDMI1.19 11.05,101.75 12.16,102.87 13.75,102.87 14.26,103.37 20.61,103.37 21.56,102.42 v1(26.32,102.42)
  BOTTOM w0.102: v1(26.32,102.42) 26.01,102.1 CV24.1 RV31.1 RV30.2
HDMI_L_CLKN: length 7.7
  TOP w0.102: JHDMI1.12 13,97.45 13.17,97.45 14.01,98.29 14.01,98.32 14.41,98.72 14.44,98.72 v3(15.14,99.42) 15.64,99.92 16.95,99.92 RV12.1 17.51,100.07 LV2.1 RV11.2
HDMI_L_CLKP: length 7.7
  TOP w0.102: JHDMI1.10 13,97.25 13.26,97.25 v3(14.37,98.36) 15.07,99.06 15.1,99.06 15.5,99.46 15.5,99.49 15.73,99.72 16.95,99.72 RV12.2 17.51,99.57 LV2.4 18.75,99.4 RV13.2
HDMI_L_TX_N0: length 13.8
  TOP w0.102: JHDMI1.9 11.45,95.95 11.59,95.95 11.69,96.05 11.69,101.34 12.09,101.74 14.43,101.74 14.46,101.76 15.02,101.76 15.05,101.74 v3(16.09,101.74) 16.99,101.74 RV15.1 17.6,101.76 18.43,101.76 LV3.1 18.75,102.08 RV14.2
HDMI_L_TX_N1: length 9.3
  TOP w0.102: JHDMI1.6 13,94.45 13.69,94.45 14.31,95.08 14.31,96.02 14.28,96.04 14.28,96.61 14.31,96.63 14.31,97.04 15.35,98.09 v3(16.07,98.09) 16.95,98.09 RV24.1 17.59,98.17 LV4.1 18.75,98.32 RV23.2
HDMI_L_TX_N2: length 11
  TOP w0.102: RV29.2 18.75,96.36 LV5.1 17.59,96.2 RV28.2 16.95,96.12 16.31,96.12 15.66,95.47 15.66,94.52 v3(15.19,94.06) 14.36,93.23 14.33,93.23 13.93,92.83 13.93,92.79 13.22,92.08 12.24,92.08 12.07,92.25 12.07,92.55 11.68,92.95 11.45,92.95 JHDMI1.3
HDMI_L_TX_P0: length 13.8
  TOP w0.102: JHDMI1.7 11.45,95.75 11.68,95.75 11.9,95.97 11.9,101.25 12.18,101.53 v3(14.74,101.53) 15.78,101.53 15.8,101.51 16.37,101.51 16.4,101.53 16.91,101.53 RV15.2 17.58,101.41 LV3.4 18.75,101.24 RV22.2
HDMI_L_TX_P1: length 9.3
  TOP w0.102: RV25.2 18.75,97.51 LV4.4 17.44,97.67 RV24.2 16.95,97.89 16.38,97.89 16.36,97.86 15.79,97.86 15.77,97.89 15.44,97.89 14.51,96.96 v3(14.51,96.32) 14.51,94.99 13.77,94.25 13,94.25 JHDMI1.4
HDMI_L_TX_P2: length 11
  TOP w0.102: JHDMI1.1 11.45,92.75 11.59,92.75 11.87,92.47 11.87,92.16 12.15,91.88 13.31,91.88 v3(14.29,92.86) 15.12,93.69 15.16,93.69 15.56,94.09 15.56,94.13 15.86,94.43 15.86,95.39 16.39,95.92 16.95,95.92 RV28.1 17.44,95.7 LV5.4 18.75,95.54 RV26.2
HDMI_TX_N0: length 3.3
  TOP w0.102: CV18.2 21.08,101.7 20.84,101.7 v1(20.67,101.86) 20.62,101.91 LV3.2 19.67,102.08 RV14.1
  BOTTOM w0.102: RV34.1 21.29,101.66 20.87,101.66 v1(20.67,101.86)
HDMI_TX_N1: length 3.3
  TOP w0.102: CV20.2 21.05,97.93 20.91,97.93 v1(20.74,98.1) 20.67,98.17 LV4.2 19.67,98.34 RV23.1
  BOTTOM w0.102: RV21.1 21.29,97.91 20.93,97.91 v1(20.74,98.1)
HDMI_TX_N2: length 3.2
  TOP w0.102: RV29.1 19.67,96.37 LV5.2 20.66,96.2 v1(20.7,96.24) 20.86,96.07 21.1,96.07 CV22.2
  BOTTOM w0.102: v1(20.7,96.24) 20.86,96.07 21.36,96.07 RV19.1
HDMI_TX_P0: length 3.3
  TOP w0.102: RV22.1 19.67,101.24 LV3.3 20.54,101.41 v1(20.67,101.28) 20.89,101.49 21.08,101.49 CV19.2
  BOTTOM w0.102: RV35.1 21.37,101.46 20.85,101.46 v1(20.67,101.28)
HDMI_TX_P1: length 3.2
  TOP w0.102: RV25.1 19.67,97.49 LV4.3 20.59,97.67 v1(20.74,97.52) 20.9,97.69 21.14,97.69 CV21.2
  BOTTOM w0.102: RV20.1 21.36,97.72 20.94,97.72 v1(20.74,97.52)
HDMI_TX_P2: length 3.3
  TOP w0.102: RV26.1 19.67,95.52 LV5.3 20.65,95.7 v1(20.7,95.65) 20.91,95.87 21.05,95.87 CV23.2
  BOTTOM w0.102: v1(20.7,95.65) 20.91,95.87 21.31,95.87 RV18.1
HPOUT_L: length 13.8
  TOP w0.254: LA2.2 21.42,13.01 v1(21.22,12.81) ; 13.13,7.42 v4(14.63,7.42) 15.15,7.42 16.99,9.27 17.69,9.27 18.12,9.7 DA8.2 18.12,11.07 v1(18.08,11.11)
  BOTTOM w0.254: v1(21.22,12.81) 21.22,12.29 20.67,11.74 19.02,11.74 18.78,11.98 CA498.1 ; CA498.1 18.07,11.12 v1(18.08,11.11) ; CA498.1 RA54.1
HPOUT_R: length 25
  TOP w0.254: v1(17.18,10.9) 17.18,10.26 16.93,10 DA8.3 16.05,10.14 v4(16.05,11.95) 16.05,12.01 v1(16.48,12.44) ; LA3.2 21.32,11.49 v1(21.19,11.36)
  BOTTOM w0.254: v1(21.19,11.36) 20.99,11.36 20.8,11.17 18.96,11.17 RA57.1 18.08,10.3 CA504.1 v1(17.18,10.9) ; JHP1.2 7.66,17.4 8.73,18.47 14.7,18.47 16.15,17.03 16.15,14.04 16.65,13.55 16.65,12.61 v1(16.48,12.44)
HVB_FUNCTION: length 20.1
  TOP w0.102: v1(118.07,57.66) 118.07,57.66 118.74,57 RC84.2
  IN2 w0.102: v1(121.4,72.79) 121.23,72.79 120.83,72.39 120.47,72.39 120.19,72.39 119.79,71.98 119.79,69.95 120.49,69.25 120.49,67.22 119.81,66.55 119.81,65.28
  IN2 w0.127: v1(118.07,57.66) 117.67,58.06 117.67,59.8 118.3,60.42 118.3,63.17 119.81,64.68 119.81,65.28
  BOTTOM w0.102: v1(121.4,72.79) 121.71,73.11 UC1.AP27 ; v1(118.07,57.66) v2(118.63,57.66)
HW_ACAV_IN: length 228
  TOP w0.254: RE37.2 45.17,89.29 46.11,88.35 46.11,86.79 v1(45.39,86.06) ; PR31.1 175.68,56.73 176.03,57.08 176.03,57.08 v1(176.12,57.17) 176.3,57.35 176.91,57.35 177.3,56.95 177.3,53.96 176.86,53.51 176.04,53.51 174.8,52.27 v2(174.8,52.22) PR909.2
  IN1 w0.254: v1(176.12,57.17) 175.64,57.65 174.53,57.65 172.88,56 170.85,56 161.98,47.14 150.17,47.14 148.8,45.77 148.8,44.8 141.81,37.8 131.82,37.8 131.29,37.27 125.41,37.27 124.84,36.7 116.94,36.7 116.59,36.36 111.45,36.36 111.27,36.18 105.53,36.18 105.36,36.01 104.75,36.01 103.87,36.89 98.56,36.89 98.38,37.07 93.19,37.07 90.3,39.97 71.5,39.97 65.73,45.75 65.41,45.75 64.93,46.22 64.93,47.62 65.49,48.18 65.49,48.97 64.83,49.62 64.83,52.48 62.21,55.11 62.21,68.41 57.37,73.24 57.37,73.91 56.68,74.61 56.68,77.59 56.17,78.1 56.17,79.52 55.24,80.45 53.69,80.45 53.52,80.62 52,80.62 50.86,81.76 50.86,82.53 49.95,83.43 43.02,83.43 42,84.46 42,85.21 42.83,86.04 45.36,86.04 v1(45.39,86.06)
  IN2 w0.254: v1(176.12,57.17) 176.6,57.65 176.86,57.65 177.85,58.64 187.1,58.64 187.45,58.29 194.29,58.29 195.61,56.97 v1(195.61,56.64)
  BOTTOM w0.254: PRB22.2 198.66,55.8 197.51,56.95 195.93,56.95 v1(195.61,56.64) 194.99,56.64 PRB26.1 193.87,55.52 PRB25.2
I2C_0_SCL: length 16.4
  TOP w0.102: v1(125.84,57.32) 126.2,57.68 R2.2
  IN1 w0.127: v1(125.76,61.63) 125.5,61.63 124.99,61.12 124.99,60.69 125.25,60.43 125.25,59.37 126.34,58.29 126.34,57.82 v1(125.84,57.32)
  BOTTOM w0.102: v1(125.76,61.63) 125.8,61.68 125.8,62.57 125.36,63.01 125.36,66.55 125.05,66.85 125.05,68.28 124.92,68.42 124.92,68.74 124.99,68.81 124.99,69.1 124.82,69.27 124.82,69.52 UC1.AY22 ; v1(125.84,57.32) 125.84,56.98 126.22,56.6 Q1.1
I2C_0_SCL_R: length 111.2
  TOP w0.102: v1(209.62,47.78) 209.51,47.67 209.51,46.97 R12.1
  IN2 w0.127: v1(209.62,47.78) 209.56,47.72 209.56,46.96 209.01,46.41 205.46,46.41 204.82,45.78 204.82,42.34 204,41.52 203.99,41.52 198.15,35.68 196.76,35.68 196.47,35.4 183.9,35.4 183.04,36.25 178.85,36.25 176.46,38.64 155.01,38.64 154.44,38.07 v1(152.94,38.07)
  BOTTOM w0.102: Q1.6 128.03,56.6 127.66,56.24 127.66,55.91 R1.2 127.79,55.43 127.79,54.81 127.89,54.71 128.81,54.71 131.54,57.44 133.57,57.44 135.47,55.54 143.86,55.54 144.1,55.29 147.43,55.29 149.44,53.28 149.44,50.87 150.28,50.03 151.35,50.03 151.96,49.43 151.96,46.7 152.62,46.03 152.62,38.67 152.94,38.35 v1(152.94,38.07)
I2C_0_SDA: length 13.9
  IN1 w0.127: v1(125.76,61) 126.65,60.11 126.65,58.71 127.46,57.9 127.78,57.9 v1(127.79,57.91)
  BOTTOM w0.102: v1(127.79,57.91) 127.79,57.9 Q1.4 ; UC1.BA22 124.68,68.31 124.85,68.14 124.85,66.69 125.15,66.39 125.15,62.87 124.64,62.36 R3.2 125.09,61.67 v1(125.76,61)
I2C_0_SDA_R: length 112.5
  TOP w0.102: R11.1 209.2,47.15 209.2,47.62 v1(209.04,47.78)
  IN2 w0.127: v1(209.04,47.78) 209.13,47.69 209.13,47.16 208.82,46.86 205.27,46.86 204.38,45.97 204.38,42.54 197.96,36.13 196.57,36.13 196.31,35.87 184.06,35.87 183.23,36.7 179.1,36.7 176.69,39.11 154.85,39.11 154.28,38.54 152.82,38.54 152.78,38.49 152.77,38.49 152.52,38.25 152.52,38.24 v1(152.36,38.07)
  BOTTOM w0.102: Q1.3 127.34,57.08 127.34,55.76 127.18,55.6 R4.2 127.47,55.17 127.47,54.65 127.73,54.4 128.93,54.4 131.68,57.14 133.38,57.14 135.34,55.19 143.6,55.19 144.02,54.76 147.39,54.76 149.01,53.14 149.01,50.73 150.02,49.72 151.16,49.72 151.58,49.3 151.58,46.51 152.24,45.84 152.24,38.19 v1(152.36,38.07)
I2C_1_SCL: length 18.7
  TOP w0.102: RPC7.8 131.23,59.17 132.04,59.98 132.04,60.34 132.7,61 v2(132.7,63.97) 132.7,64.85 130.84,66.71 v1(130.71,66.71)
  IN2 w0.102: v1(125.79,71.25) 125.06,70.52 125.06,69.63 125.63,69.06 127.92,69.06 130.27,66.71 v1(130.71,66.71)
  BOTTOM w0.1: v1(125.79,71.25) 125.87,71.25 126.13,71.51 UC1.AU19
I2C_1_SDA: length 17.6
  TOP w0.102: v1(130.71,67.35) v2(131.41,66.65) 133.03,65.03 133.03,60.9 132.36,60.22 132.36,59.86 131.73,59.23 RPC7.7
  IN2 w0.102: v1(125.78,70.42) 125.69,70.33 125.57,70.33 125.47,70.23 125.47,69.8 125.8,69.47 128.08,69.47 130.21,67.35 v1(130.71,67.35)
  BOTTOM w0.1: 126.17,70.71 126.07,70.71 v1(125.78,70.42)
  BOTTOM w0.102: 126.17,70.71 126.17,70.71 UC1.AV19
I2C_3_SCL: length 71.8
  TOP w0.102: RPC6.1 119.57,62.64 119.67,62.74 119.67,63.36 120.23,63.92 v2(120.82,63.92) 122.99,63.92 123.17,64.1 123.17,64.24 123.27,64.34 v1(123.51,64.58)
  IN1 w0.127: v1(118.81,45.68) 118.61,45.89 118.61,47.9 119,48.29 119,50.42 119.91,51.34 119.91,55 119.64,55.27 v1(119.64,55.76)
  IN2 w0.102: 123.41,65.28 123.41,68.62 123.18,68.85 123.18,73.21 124.25,74.29 124.92,74.29 125.37,74.74 125.95,74.74 126.08,74.87 126.73,74.87 126.92,74.67 126.92,73.09 127.3,72.71 130.67,72.71 131.37,73.4 131.37,75.06 131.88,75.56 131.88,76.14 131.62,76.39 131.62,77.38 131.84,77.6 133.4,77.6 v1(134.12,78.32)
  IN2 w0.127: v1(119.64,55.76) 119.64,55.92 120.68,56.96 120.68,58.12 121.86,59.31 121.86,60.14 122.28,60.56 122.28,62.03 123.85,63.6 123.85,64.11 123.51,64.45 v1(123.51,64.58) 123.41,64.68 123.41,65.28
  BOTTOM w0.1: v1(134.12,78.32) UC1.AC5
  BOTTOM w0.102: v1(118.81,45.68) 118.81,44.98 113.8,39.97 113.8,38.9 113.13,38.22 113.13,36.13 113.51,35.75 115.04,35.75 115.55,35.24 115.55,34.93 115.54,34.92 115.54,34.16 114.85,33.46 Q5.3
I2C_3_SCL_R: length 12.6
  TOP w0.102: v1(112.95,30.22) v4(112.35,30.22)
  BOTTOM w0.102: Q5.4 112.95,32.88 R35.1 v1(112.95,30.22) 112.95,29.8 113.47,29.28 119.36,29.28 120.05,29.97 JTP1.6
I2C_3_SDA: length 69
  TOP w0.102: RPC6.2 119.78,62.14 119.98,62.33 119.98,63.24 120.33,63.59 v2(122.35,63.59) 123.13,63.59 123.26,63.72 v1(123.37,63.72)
  IN2 w0.102: 122.97,65.28 122.97,73.33 124.14,74.49 124.84,74.49 125.28,74.94 125.87,74.94 126.05,75.12 126.86,75.12 127.18,74.8 127.18,73.15 127.37,72.96 130.42,72.96 131.11,73.66 131.11,75.18 131.62,75.69 131.62,76.07 131.31,76.39 131.31,77.35 131.81,77.86 133.37,77.86 133.74,78.22 133.74,78.48 134.04,78.77 v1(134.04,79.37)
  IN2 w0.127: 122.97,65.28 122.97,64.38 123.37,63.99 v1(123.37,63.72) 121.85,62.2 121.85,60.74 121.43,60.32 121.43,59.49 119.84,57.9 119.84,57.16 118.53,55.85 118.53,49.33 v1(117.89,48.7)
  BOTTOM w0.1: 134.43,78.98 v1(134.04,79.37)
  BOTTOM w0.102: UC1.AC4 134.43,78.98 ; v1(117.89,48.7) 117.89,44.64 113.38,40.13 113.38,39.17 112.68,38.48 112.68,35.94 113.19,35.43 113.19,34.98 112.97,34.76 Q5.6
I2C_3_SDA_R: length 11.8
  TOP w0.102: v1(113.75,30.22) v4(114.36,30.22)
  BOTTOM w0.102: Q5.1 113.75,34.25 R33.1 v1(113.75,30.22) 113.75,30.11 114.27,29.59 118.95,29.59 119.05,29.69 JTP1.7
ILMT_0.95V: length 4.4
  BOTTOM w0.102: PRH04.1 168.24,60.85 v2(168.76,60.33)
  BOTTOM w0.254: PRH04.1 PRH03.2 166.59,60.97 166.59,62.33 166.33,62.58 PUH01.12
IMON_APU: length 2.7
  TOP w0.203: PUZ01.10 146.32,142.83 145.58,143.57 PRZ76.2 144.75,144.06 PCZ62.2
IMON_NB: length 2.7
  TOP w0.203: PUZ01.2 149.52,143.13 v1(149.96,143.57) 149.96,144.25 ; 149.96,144.25 150.08,144.13 PRZ18.2 ; 149.96,144.25 PCZ18.2
INVTPWM: length 132.1
  TOP w0.102: v1(213.59,49.2) 213.79,49.2 v2(214.16,49.56) ; UC10.4 127.49,105.53 127.55,105.59 RV7.1 127.55,106.36 v1(127.03,106.88) 127.03,107.44 126.65,107.82 122.79,107.82 121.76,106.78 121.76,106.08 122.34,105.5 RC20.1 RC23.1
  IN1 w0.127: v1(127.03,106.88) 129.62,106.88 132.75,103.75 136.69,103.75 142.72,97.72 143.29,97.72 153.58,87.43 156.43,87.43 166.28,77.59 175.68,77.59 178.28,74.99 179.19,74.99 186.5,67.68 189.12,67.68 189.71,67.09 195.39,67.09 202.74,59.74 213.19,59.74 v1(213.35,59.57)
  IN2 w0.127: v1(213.35,59.57) 212.76,58.98 212.76,50.03 v1(213.59,49.2)
  BOTTOM w0.102: JEDP1.27 212.97,47.45 213.52,48 213.52,49.13 v1(213.59,49.2)
INVTPWM_R: length 24.1
  TOP w0.102: v1(123.22,102.91) 123.47,103.16 RC23.2 123.08,104.18 RPC2.7 ; UC10.2 126.84,103.91 126.55,104.2 125.57,104.2 125.46,104.09 125.46,99.98 124.6,99.11 123.93,99.11 123.91,99.13 v1(123.48,99.13)
  IN1 w0.127: v1(123.22,102.91) 122.46,102.15 122.46,100.15 v1(123.48,99.13)
  BOTTOM w0.102: UC1.A24 123.56,90.88 123.56,91.53 123.3,91.78 123.3,91.9 123.15,92.05 123.15,98.8 v1(123.48,99.13)
ISOLATE#: length 4.8
  TOP w0.102: RL9.1 27.96,90.03 RL8.2 26.47,90.03 25.98,89.53 25.61,89.53 v2(25.04,88.96) 25.04,88.59 24.68,88.24 UL1.20
JACK_PLUG: length 24.9
  TOP w0.102: JHP1.5 v4(12.65,18.75)
  TOP w0.254: v1(18.13,18.35) DA9.3 17.59,17.24 v1(17.12,17.71) ; RA51.1 31.78,19.74 v1(31.72,19.81)
  IN2 w0.254: v1(18.13,18.35) 18.13,17.9 18.58,17.46 23.59,17.46 25.18,19.05 28.1,19.05 28.86,19.81 v1(31.72,19.81) ; v1(17.12,17.71) 16.8,18.03 13.28,18.03 JHP1.5
JACK_PLUG_DET: length 9.8
  TOP w0.254: JHP1.6 11.71,19.21 13.74,19.21 v4(14.54,18.41) 15.29,18.41 16.2,17.5 DA9.2 16.2,16.25 16.15,16.2 16.15,16.12 16.09,16.06 RA62.1
JHDD_P10: length 4.7
  BOTTOM w0.102: JHDD1.8 186.7,36.34 186.53,36.51 186.53,36.9 186.66,37.03 RS23.2 186.83,37.45 187.5,38.12 v2(187.5,39.84)
KB_BL_PWM: length 19.5
  TOP w0.102: v1(90.52,33.08) 93.94,36.5 v4(100.87,36.5) v1(104.95,36.5)
  BOTTOM w0.102: JKBBL1.4 90.6,33.08 v1(90.52,33.08) ; Q4.1 104.87,36.42 v1(104.95,36.5)
KB_DET: length 62.8
  TOP w0.102: v1(124.3,43.94) 124.24,43.94 123.86,44.32 120.24,44.32 119.41,45.14 118.52,45.14 v1(118.39,45.27)
  IN1 w0.127: v1(119.06,55.79) 119.06,55.24 119.48,54.82 119.48,51.52 118.33,50.37 118.33,48.24 118.11,48.02 118.11,45.55 v1(118.39,45.27)
  IN2 w0.127: v1(124.3,43.94) 124.3,43.93 124.3,43.3 122.11,41.11 122.11,38.8 119.82,36.51 116.71,36.51 116.4,36.2 113.06,36.2 112.87,36.39 112,36.39 110.7,35.09 104.01,35.09 103.65,35.45 v1(103.65,35.48)
  BOTTOM w0.102: R30.1 R31.1 v2(102.37,36.58) 102.76,36.58 103.65,35.7 v1(103.65,35.48) ; UC1.BA28 121.42,68.92 121.42,68.4 121.43,68.39 121.43,64.15 121.88,63.69 121.88,62.21 121.38,61.7 121.38,60.09 120.77,59.48 120.77,57.02 120.24,56.5 119.77,56.5 v1(119.06,55.79)
KB_LED_PWM: length 102.4
  TOP w0.102: v1(41.12,71.94) 39.72,71.94 39.19,72.47 37.02,72.47 36.77,72.22 UE1.25 ; v1(104.87,37.66) v2(104.4,38.13) 104.05,38.48 93.8,38.48 92.84,39.43 v1(92.49,39.43)
  IN1 w0.127: v1(41.12,71.94) 41.12,71.88 41.37,71.62 44.04,71.62 44.55,72.13 49.83,72.13 50.52,71.45 50.52,69.21 51.22,68.51 51.22,68 51.66,67.56 51.66,64.77 53.82,62.61 55.03,62.61 57.05,60.58 57.05,52.97 58.48,51.54 58.48,44.35 57.91,43.78 57.91,42.79 58.33,42.38 v1(58.33,42.37)
  BOTTOM w0.102: Q4.2 104.45,37.04 104.87,37.46 v1(104.87,37.66) ; v1(58.33,42.37) 58.56,42.37 59.38,41.55 61.02,41.55 61.53,42.06 62.37,42.06 63.07,41.35 67.39,41.35 68.74,40 71.73,40 73.06,41.33 73.06,42.17 73.3,42.41 73.88,42.41 77.3,39 92.08,39 92.49,39.4 v1(92.49,39.43)
KB_RST#: length 144.1
  TOP w0.102: RC113.2 33.17,81.42 v2(34.1,81.42) UE1.2 37.44,81.42 41.2,77.67 v1(41.62,77.67)
  IN1 w0.127: v1(114.13,44.39) 114.2,44.32 115.85,44.32 117.86,46.33 117.86,47.73 117.44,48.15 117.44,49.84 119.22,51.62 119.22,54.71 118.54,55.4 118.54,59.42 118.29,59.67 v1(118.14,59.67)
  IN2 w0.127: v1(114.13,44.39) 113.65,44.86 111.96,44.86 111.86,44.76 109.66,44.76 109.49,44.6 109.14,44.6 108.79,44.95 107.36,44.95 106.95,45.36 104.63,45.36 102.89,43.62 95.35,43.62 95.06,43.91 89.38,43.91 89.09,43.62 89.08,43.62 87.37,41.91 74.15,41.91 73.8,41.56 73.11,41.56 72.04,42.62 72.04,43.23 71.04,44.23 71.04,46.31 70.69,46.67 70.69,48.32 69.65,49.35 69.65,52.97 68.01,54.61 64.68,54.61 59.19,60.1 59.19,76.16 57.6,77.74 55.85,77.74 55.76,77.66 54.2,77.66 54.07,77.78 47.19,77.78 46.68,77.28 42,77.28 v1(41.62,77.67)
  BOTTOM w0.102: v1(118.14,59.67) 119.03,60.56 119.03,64.15 120.04,65.16 120.04,66.92 120.35,67.22 120.35,68.12 120.31,68.15 120.31,68.16 120.28,68.19 UC1.BA30
KSI0: length 55.5
  TOP w0.102: v1(46.64,69.6) 46.26,69.22 46.26,68.71 46.13,68.58 UE1.55 ; v1(65.82,33.08) v4(66.61,33.08)
  IN1 w0.127: v1(65.82,33.08) 65.33,33.08 63.9,31.64 58.01,31.64 53.94,35.72 53.94,51.36 53.67,51.63 53.67,57.9 46.24,65.33 46.24,69.21 46.63,69.6 v1(46.64,69.6)
  BOTTOM w0.102: JKB1.9 66.15,33.41 v1(65.82,33.08)
KSI1: length 51.9
  TOP w0.102: v1(46.67,69.01) 46.6,68.95 46.6,68.92 46.53,68.84 UE1.56 ; v1(64.55,33.14) 64.88,32.81 v4(64.88,32.62)
  IN1 w0.127: v1(46.67,69.01) 46.67,65.26 53.93,58 53.93,51.73 54.19,51.47 54.19,35.82 57.13,32.89 60.91,32.89 61.9,31.9 63.5,31.9 64.55,32.95 v1(64.55,33.14)
  BOTTOM w0.102: JKB1.7 v1(64.55,33.14)
KSI2: length 50.5
  TOP w0.102: v4(61.17,33.03) 61.29,32.91 v1(62.15,32.91) ; v1(47.51,69.59) 47.1,69.19 47.1,68.78 46.93,68.61 UE1.57
  IN1 w0.127: v1(47.51,69.59) 47.49,69.59 47.1,69.2 47.1,69.18 47.09,69.17 47.09,65.2 54.18,58.11 54.18,51.84 54.45,51.57 54.45,35.93 57.23,33.14 61.91,33.14 v1(62.15,32.91)
  BOTTOM w0.102: v1(62.15,32.91) 62.95,33.71 JKB1.5
KSI3: length 52.7
  TOP w0.102: v4(47.02,65.79) 47.33,66.1 UE1.58 47.33,68.82 v1(47.51,69)
  IN1 w0.127: v1(47.51,69) 47.51,65.14 54.43,58.21 54.43,51.95 54.7,51.68 54.7,36.04 57.34,33.4 62.3,33.4 v1(62.81,32.89)
  BOTTOM w0.102: v1(62.81,32.89) 63.19,32.51 64.61,32.51 65.35,33.24 JKB1.8
KSI4: length 52.2
  TOP w0.102: UE1.59 47.73,68.65 47.91,68.83 47.91,69.09 v1(48.71,69.88) ; v4(62.58,31.52) 62.14,31.96 v1(62.14,32.32)
  IN1 w0.127: v1(62.14,32.32) 62.96,32.32 63.28,32.63 63.28,33.08 62.44,33.92 59.66,33.92 55.34,38.24 55.34,51.94 55.07,52.21 55.07,58.48 48.31,65.24 48.31,69.49 v1(48.71,69.88)
  BOTTOM w0.102: v1(62.14,32.32) 61.74,32.72 61.74,33.13 62.15,33.54 JKB1.4
KSI5: length 47.6
  TOP w0.102: UE1.60 48.13,68.76 48.67,69.3 v1(48.73,69.3) ; v4(63.27,33.43) 63.56,33.14 v1(63.79,33.14)
  IN1 w0.127: v1(48.73,69.3) 48.88,69.15 48.88,65.03 55.32,58.58 55.32,52.31 55.59,52.05 55.59,38.34 59.76,34.17 62.57,34.17 63.6,33.14 v1(63.79,33.14)
  BOTTOM w0.102: JKB1.6 63.75,33.18 v1(63.79,33.14)
KSI6: length 44.4
  TOP w0.102: v1(61.35,35.21) v4(61.76,34.81) ; UE1.61 48.53,68.6 48.8,68.87 48.88,68.87 49.35,69.34 49.35,69.49 v1(49.25,69.59)
  IN1 w0.127: v1(49.25,69.59) 49.15,69.49 49.15,65.12 55.58,58.69 55.58,52.42 55.84,52.15 55.84,39.31 60.33,34.82 60.96,34.82 v1(61.35,35.21)
  BOTTOM w0.102: v1(61.35,35.21) JKB1.3
KSI7: length 41.9
  TOP w0.102: v1(60.55,35.24) v4(60.55,36.03) ; UE1.62 48.93,68.6 49.37,69.04 49.62,69.04 v1(49.65,69.07)
  IN1 w0.127: v1(60.55,35.24) 56.1,39.68 56.1,52.26 55.84,52.53 55.84,58.79 49.64,64.98 49.64,68.89 49.65,68.9 v1(49.65,69.07)
  BOTTOM w0.102: v1(60.55,35.24) JKB1.2
KSO0: length 74
  TOP w0.102: UE1.39 39.73,68.5 39.64,68.6 39.64,68.9 v1(39.5,69.03) ; v1(73.25,29.65) 73.87,29.65 v4(74.02,29.5)
  IN1 w0.127: v1(73.25,29.65) 73.25,29.55 70.57,26.87 56.45,26.87 49.29,34.03 49.29,53.38 41.3,61.37 41.3,66.69 39.58,68.4 39.58,68.95 v1(39.5,69.03)
  BOTTOM w0.102: JKB1.18 73.35,29.75 v1(73.25,29.65)
KSO1: length 73.8
  TOP w0.102: v1(71.85,29.65) 71.85,30.16 v4(72.32,30.63) ; UE1.40 40.13,68.61 39.93,68.81 39.93,69.25 39.55,69.63 v1(39.55,69.63)
  IN1 w0.127: v1(39.55,69.63) 39.62,69.63 39.92,69.33 39.92,68.43 41.56,66.79 41.56,61.47 49.54,53.48 49.54,34.23 56.59,27.19 69.39,27.19 v1(71.85,29.65)
  BOTTOM w0.102: v1(71.85,29.65) 71.54,29.96 71.54,33.16 71.75,33.37 JKB1.16
KSO2: length 72
  TOP w0.102: v1(40.34,69.01) 40.35,69.01 40.53,68.83 UE1.41 ; v1(72.49,29.65) v4(72.49,28.82)
  IN1 w0.127: v1(40.34,69.01) 40.55,68.8 40.55,68.16 41.81,66.9 41.81,61.58 49.8,53.59 49.8,34.39 56.71,27.48 69.09,27.48 71.68,30.07 72.07,30.07 v1(72.49,29.65)
  BOTTOM w0.102: JKB1.17 72.55,30.81 72.49,30.75 v1(72.49,29.65)
KSO3: length 70.7
  TOP w0.102: v1(70.39,29.65) v4(70.94,29.65) ; v1(40.36,69.59) 40.55,69.59 40.93,69.21 UE1.42
  IN1 w0.127: v1(70.39,29.65) 70.39,29.59 68.54,27.73 56.82,27.73 50.05,34.5 50.05,43.79 50.12,43.86 50.12,53.63 42.06,61.68 42.06,67 40.92,68.15 40.92,69.22 40.55,69.59 v1(40.36,69.59)
  BOTTOM w0.102: JKB1.15 70.95,30.21 v1(70.39,29.65)
KSO4: length 67.6
  TOP w0.102: v1(67.64,28.7) 67.64,28.24 v4(67.55,28.15) ; UE1.43 41.33,68.68 41.18,68.83 41.18,69.27 41.52,69.61 v1(41.63,69.61)
  IN1 w0.127: v1(67.64,28.7) 67.64,28.48 67.27,28.11 56.8,28.11 50.89,34.02 50.89,50.1 50.62,50.36 50.62,53.84 42.9,61.57 42.9,66.52 41.17,68.26 41.17,69.2 41.58,69.61 v1(41.63,69.61)
  BOTTOM w0.102: JKB1.11 67.75,33.41 67.64,33.29 v1(67.64,28.7)
KSO5: length 64.7
  TOP w0.102: v1(66.88,28.7) 66.8,28.7 v4(66.21,29.28) ; UE1.44 41.73,68.83 41.62,68.94 41.62,68.97 41.59,68.99 v1(41.59,69.01)
  IN1 w0.127: v1(66.88,28.7) 66.01,28.7 65.85,28.55 56.76,28.55 51.15,34.16 51.15,50.2 50.88,50.47 50.88,53.95 43.16,61.67 43.16,66.63 41.59,68.2 41.59,69 v1(41.59,69.01)
  BOTTOM w0.102: JKB1.10 66.95,33.34 66.84,33.23 66.84,29.81 66.88,29.77 v1(66.88,28.7)
KSO6: length 67.7
  TOP w0.102: v4(69.45,30.68) 69.17,30.4 v1(69.17,29.65) ; v1(42.31,69.62) 42.31,69.53 42.03,69.24 42.03,68.75 42.13,68.64 UE1.45
  IN1 w0.127: v1(42.31,69.62) 42.01,69.32 42.01,68.13 43.41,66.74 43.41,61.78 51.13,54.05 51.13,50.58 51.4,50.31 51.4,34.34 56.94,28.8 65.27,28.8 66.19,29.71 67.93,29.71 68.26,29.38 68.91,29.38 v1(69.17,29.65)
  BOTTOM w0.102: v1(69.17,29.65) 69.17,30.32 69.35,30.5 JKB1.13
KSO7: length 64.3
  TOP w0.102: v1(42.43,69.02) 42.43,68.98 42.53,68.88 UE1.46 ; v4(67.9,29.98) 68.32,29.98 v1(68.5,29.8)
  IN1 w0.127: v1(42.43,69.02) 42.43,68.07 43.66,66.84 43.66,64.67 51.39,56.95 51.39,50.68 51.65,50.41 51.65,34.45 57.01,29.09 65.21,29.09 66.08,29.97 68.37,29.97 68.5,29.84 v1(68.5,29.8)
  BOTTOM w0.102: JKB1.12 68.55,30.31 68.5,30.26 v1(68.5,29.8)
KSO8: length 67.1
  TOP w0.102: v4(69.34,28.96) 69.8,29.42 v1(69.8,29.65) ; UE1.47 42.93,68.73 42.86,68.8 42.86,69.28 43.23,69.64 v1(43.29,69.64)
  IN1 w0.127: v1(43.29,69.64) 42.86,69.21 42.85,69.2 42.85,68.86 42.86,68.85 42.86,68.01 43.92,66.95 43.92,64.78 51.64,57.05 51.64,50.79 51.91,50.52 51.91,34.79 57.25,29.45 65.05,29.45 65.82,30.22 69.22,30.22 v1(69.8,29.65)
  BOTTOM w0.102: v1(69.8,29.65) 70.15,30 JKB1.14
KSO9: length 75.8
  TOP w0.102: UE1.48 43.33,68.91 43.28,68.96 43.28,69.03 v1(43.27,69.03) ; v1(79.78,29.65) v4(80.34,29.65)
  IN1 w0.127: v1(43.27,69.03) 43.27,68.91 44.17,68.01 44.17,64.88 51.89,57.16 51.89,50.89 52.16,50.63 52.16,34.98 57.44,29.7 64.72,29.7 65.49,30.48 73.02,30.48 74.08,29.41 79.55,29.41 v1(79.78,29.65)
  BOTTOM w0.102: v1(79.78,29.65) 79.16,29.65 78.15,30.65 JKB1.24
KSO10: length 75.1
  TOP w0.102: UE1.49 43.7,67.83 43.7,69.22 v1(44.1,69.62) ; v1(79.75,30.82) v4(79.75,31.46)
  IN1 w0.127: v1(79.75,30.82) 78.59,29.66 74.19,29.66 73.06,30.79 65.45,30.79 64.61,29.95 57.55,29.95 52.42,35.09 52.42,50.73 52.15,51 52.15,57.27 44.43,64.99 44.43,68.12 43.69,68.85 43.69,69.2 44.1,69.62 v1(44.1,69.62)
  BOTTOM w0.102: JKB1.26 v1(79.75,30.82)
KSO11: length 72.1
  TOP w0.102: v1(78.84,30.82) 78.84,30.4 v4(78.65,30.21) ; v1(44.11,69.03) 44.11,68.92 44.13,68.89 UE1.50
  IN1 w0.127: v1(44.11,69.03) 44.11,68.91 44.68,68.34 44.68,65.09 52.4,57.37 52.4,51.1 52.67,50.84 52.67,35.19 57.6,30.26 64.55,30.26 65.34,31.05 73.26,31.05 74.39,29.92 77.93,29.92 v1(78.84,30.82)
  BOTTOM w0.102: v1(78.84,30.82) 78.95,30.93 JKB1.25
KSO12: length 76.4
  TOP w0.102: v1(77.69,30.82) 77.69,31.59 v4(77.73,31.63) ; UE1.51 44.54,67.81 44.54,69.2 44.96,69.61 v1(44.97,69.61)
  IN1 w0.127: v1(44.97,69.61) 44.94,69.61 44.53,69.2 44.53,68.85 44.93,68.45 44.93,65.2 52.66,57.48 52.66,51.21 52.92,50.94 52.92,35.3 57.68,30.54 64.39,30.54 65.27,31.43 73.36,31.43 74.55,30.23 77.11,30.23 v1(77.69,30.82)
  BOTTOM w0.102: v1(77.69,30.82) 76.65,29.78 75.3,29.78 74.15,30.92 JKB1.19
KSO13: length 68.8
  TOP w0.102: v1(44.95,69.03) 44.93,69.01 UE1.52 ; v1(76.74,31.05) v4(76.74,30.28)
  IN1 w0.127: v1(76.74,31.05) 76.74,30.79 76.62,30.66 74.48,30.66 73.45,31.69 65.13,31.69 64.23,30.79 57.79,30.79 53.18,35.4 53.18,51.05 52.91,51.31 52.91,57.58 45.19,65.3 45.19,68.66 44.95,68.9 v1(44.95,69.03)
  BOTTOM w0.102: JKB1.22 76.55,31.24 v1(76.74,31.05)
KSO14: length 71
  TOP w0.102: v1(75.98,31.08) 75.98,31.97 v4(76.12,32.11) ; v1(45.82,69.64) 45.77,69.64 45.41,69.29 45.41,68.81 45.33,68.72 UE1.53
  IN1 w0.127: v1(75.98,31.08) 75.81,30.92 74.59,30.92 73.5,32 64.99,32 64.04,31.05 57.89,31.05 53.43,35.51 53.43,51.15 53.16,51.42 53.16,57.69 45.44,65.41 45.44,68.76 45.4,68.8 45.4,69.22 v1(45.82,69.64)
  BOTTOM w0.102: v1(75.98,31.08) 76.42,30.64 76.95,30.64 77.35,31.04 JKB1.23
KSO15: length 65.9
  TOP w0.102: v1(45.82,69.02) 45.76,68.95 45.76,67.82 UE1.54 ; v1(75.41,31.34) 75.41,31.24 v4(75,30.83)
  IN1 w0.127: v1(45.82,69.02) 45.7,68.9 45.7,65.51 53.42,57.79 53.42,51.52 53.69,51.26 53.69,35.61 57.95,31.35 63.97,31.35 64.87,32.25 73.61,32.25 74.53,31.34 v1(75.41,31.34)
  BOTTOM w0.102: v1(75.41,31.34) 75.75,31.68 JKB1.21
KSO16: length 63.6
  TOP w0.102: v1(74.65,32.34) v4(74.04,32.34) ; UE1.81 50.55,75.82 50.07,75.34 v1(50.07,75.22)
  IN1 w0.127: v1(50.26,68.77) 50.26,67.94 49.9,67.58 49.9,65.09 56.13,58.85 56.13,52.59 56.36,52.37 56.36,40.8 63.56,33.6 66.02,33.6 67.11,32.51 74.39,32.51 74.56,32.34 v1(74.65,32.34)
  BOTTOM w0.102: v1(74.65,32.34) 74.72,32.34 74.82,32.44 74.82,33.06 74.95,33.19 JKB1.20 ; v1(50.07,75.22) 50.07,75.05 50.6,74.52 50.6,69.11 v1(50.26,68.77)
LAN_MDIN0: length 26.8
  TOP w0.089: UL1.2 23.48,82.99 23.4,82.91 23.4,82.48 23.17,82.25 23.17,81.65 23.28,81.54 EL1.4 EL1.7 23.28,79.74 23.17,79.63 23.17,78.98 23.71,78.45 27.09,78.45 27.34,78.19 27.34,77.66 27.09,77.4 v3(26.5,77.4) 24.79,77.4 24.7,77.31 24.7,76.98 24.79,76.89 27.09,76.89 27.34,76.64 27.34,76.07 27.09,75.81 24.73,75.81 24.64,75.73 24.64,75.23 24.73,75.14 26.99,75.14 27.49,74.64 27.49,72.4 27.23,72.13 26.7,72.13 26.43,71.86 TL1.15
LAN_MDIN1: length 26.9
  TOP w0.089: UL1.5 24.68,83.19 24.61,83.12 24.61,82.16 24.67,82.1 24.67,81.65 24.78,81.54 EL1.1 EL1.9 24.78,79.93 24.7,79.84 24.7,79.71 24.79,79.62 25.51,79.62 25.76,79.88 26.34,79.88 v1(26.49,80.03) ; TL1.9 26.75,64.24 26.96,64.45 28.28,64.45 v1(28.29,64.44)
  IN2 w0.089: v1(26.49,80.03) 26.65,79.87 27.38,79.87 27.9,79.35 27.9,73.54 28.74,72.7 28.74,67.81 29.69,66.86 29.69,65.02 29.21,64.54 28.39,64.54 v1(28.29,64.44)
LAN_MDIN2: length 26.8
  TOP w0.089: v1(26.09,81.68) 26.03,81.74 26.03,82.14 25.85,82.32 25.85,82.41 25.43,82.83 25.43,83.05 25.48,83.1 UL1.7
  BOTTOM w0.089: TL2.10 26.5,71.86 26.7,72.07 27.4,72.07 27.81,72.48 27.81,73.82 27.09,74.54 25.43,74.54 25.33,74.64 25.33,75.13 25.45,75.24 27.15,75.24 27.53,75.62 27.53,76.13 27.21,76.45 25.32,76.45 25.21,76.57 25.21,76.97 25.32,77.08 27.28,77.08 27.53,77.34 27.53,77.97 27.15,78.35 25.01,78.35 24.93,78.44 24.93,78.81 25.01,78.9 25.55,78.9 25.82,79.16 25.82,79.81 25.56,80.07 24.73,80.07 24.64,80.16 24.64,80.59 24.73,80.68 25.68,80.68 26.09,81.08 v1(26.09,81.68)
LAN_MDIN3: length 26.9
  TOP w0.089: v1(27.49,81.99) 27.37,82.11 27.37,82.31 27.83,82.77 27.83,84.21 27.43,84.61 UL1.10
  BOTTOM w0.089: TL2.16 26.37,64.24 26.62,64.49 27.02,64.49 27.28,64.75 27.28,65.38 27.52,65.63 29.22,65.63 29.63,66.04 29.63,67.11 29.34,67.4 28.85,67.4 28.76,67.49 28.76,67.89 28.85,67.98 28.99,67.98 29.24,68.23 29.24,68.89 28.99,69.15 28.75,69.15 28.57,69.33 28.57,70.58 28.95,70.96 28.95,79.61 27.49,81.08 v1(27.49,81.99)
LAN_MDIP0: length 26.8
  TOP w0.089: TL1.16 26.55,73.13 26.64,73.04 26.64,72.52 26.75,72.41 27.11,72.41 27.21,72.51 27.21,74.53 26.88,74.86 24.61,74.86 24.35,75.12 24.35,75.84 24.61,76.1 26.97,76.1 27.06,76.19 27.06,76.52 26.97,76.61 24.67,76.61 24.42,76.87 24.42,77.43 24.67,77.68 26.97,77.68 27.06,77.77 27.06,78.08 26.97,78.16 v3(24.41,78.16) 23.59,78.16 22.89,78.86 22.89,79.63 22.78,79.74 EL1.6 EL1.5 22.78,81.54 22.89,81.65 22.89,82.37 23.12,82.6 23.12,83.02 23.08,83.06 UL1.1
LAN_MDIP1: length 27
  TOP w0.089: v1(26.49,79.45) 26.34,79.6 25.88,79.6 25.63,79.34 v3(25.31,79.34) 24.67,79.34 24.41,79.6 24.41,79.82 24.28,79.95 EL1.8 EL1.2 24.28,81.54 24.39,81.65 24.39,81.98 24.33,82.05 24.33,83.14 24.28,83.19 UL1.4 ; TL1.10 26.4,65.51 27.18,64.73 28.01,64.73 v1(28.29,65.02)
  IN2 w0.089: v1(26.49,79.45) 26.67,79.62 27.28,79.62 27.66,79.24 27.66,73.43 28.49,72.6 28.49,67.71 29.44,66.76 29.44,65.12 29.1,64.78 28.53,64.78 v1(28.29,65.02)
LAN_MDIP2: length 26.8
  TOP w0.089: v1(25.51,81.68) 25.75,81.93 25.75,82.03 25.57,82.21 25.57,82.29 v3(25.41,82.45) 25.15,82.71 25.15,83.02 25.08,83.09 UL1.6
  BOTTOM w0.089: TL2.9 25.96,73.13 26.74,72.35 27.29,72.35 27.53,72.59 27.53,73.7 26.97,74.26 25.32,74.26 25.05,74.53 25.05,75.24 25.33,75.52 27.03,75.52 27.25,75.74 27.25,76.02 27.1,76.17 25.21,76.17 24.93,76.45 24.93,77.08 25.21,77.37 27.16,77.37 27.25,77.46 27.25,77.86 27.03,78.07 24.9,78.07 24.64,78.33 24.64,78.93 24.9,79.18 25.43,79.18 25.53,79.28 25.53,79.7 25.44,79.79 24.61,79.79 24.35,80.04 24.35,80.7 24.61,80.96 25.56,80.96 25.81,81.2 25.81,81.38 v1(25.51,81.68)
LAN_MDIP3: length 26.9
  TOP w0.089: v1(26.7,81.97) 26.77,81.91 27,81.91 27.09,82 27.09,82.43 27.55,82.89 27.55,84.1 27.31,84.33 27.03,84.33 26.91,84.21 UL1.9
  BOTTOM w0.089: v1(26.7,81.97) 26.89,81.97 27.21,81.66 27.21,80.96 28.67,79.5 28.67,71.08 28.29,70.7 28.29,69.21 28.64,68.86 28.87,68.86 28.96,68.78 28.96,68.35 28.87,68.26 28.74,68.26 28.48,68 28.48,67.37 28.74,67.11 29.23,67.11 29.34,67 29.34,66.15 29.1,65.91 27.4,65.91 26.99,65.5 26.99,64.86 26.9,64.77 26.82,64.77 26.09,65.51 TL2.15
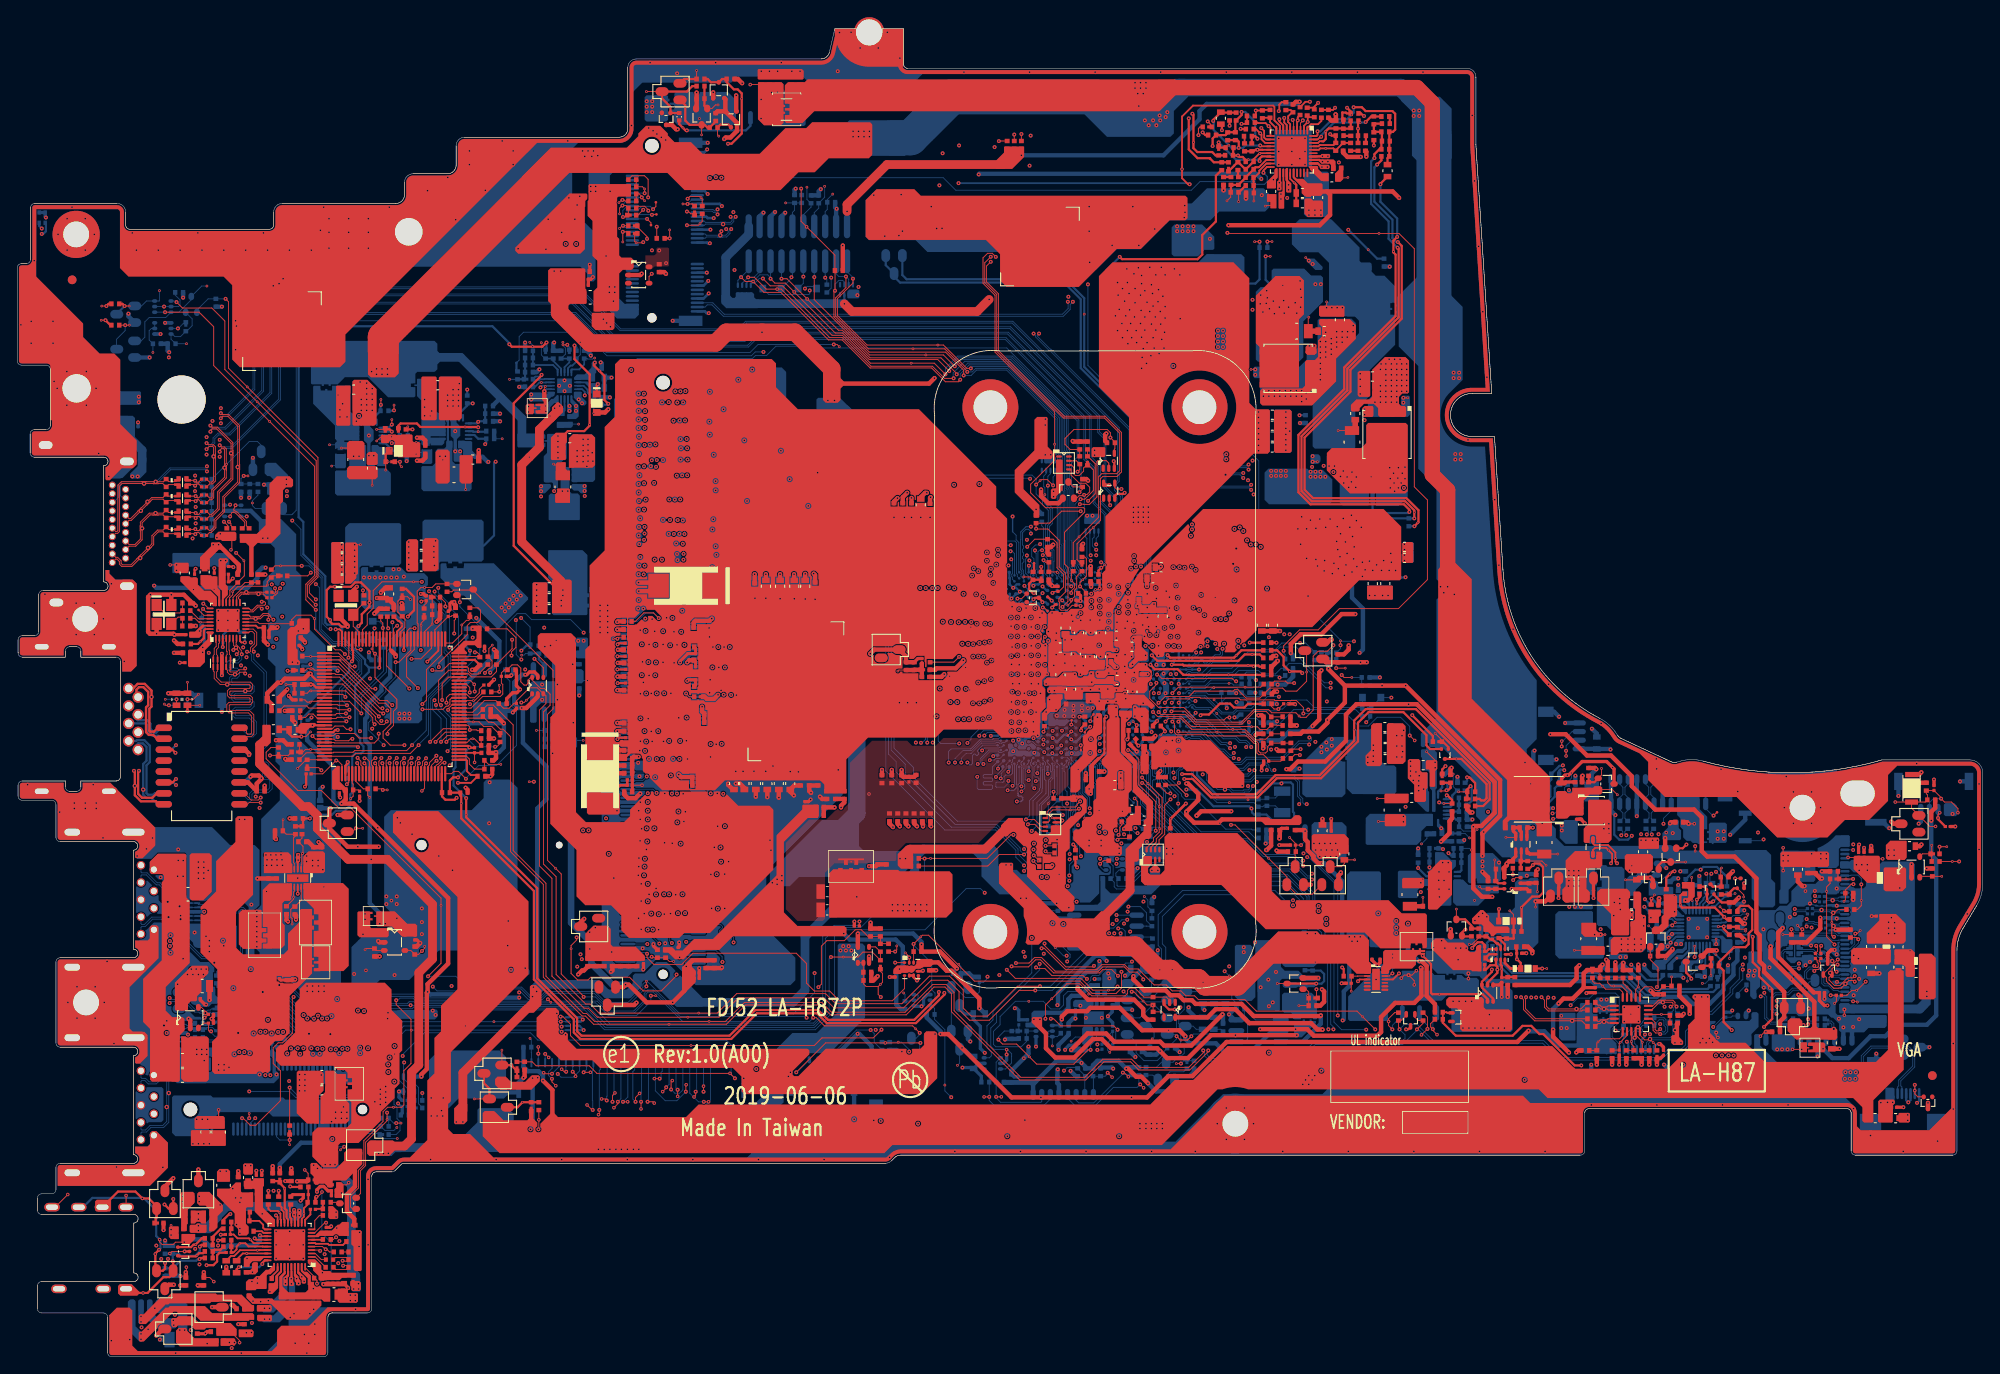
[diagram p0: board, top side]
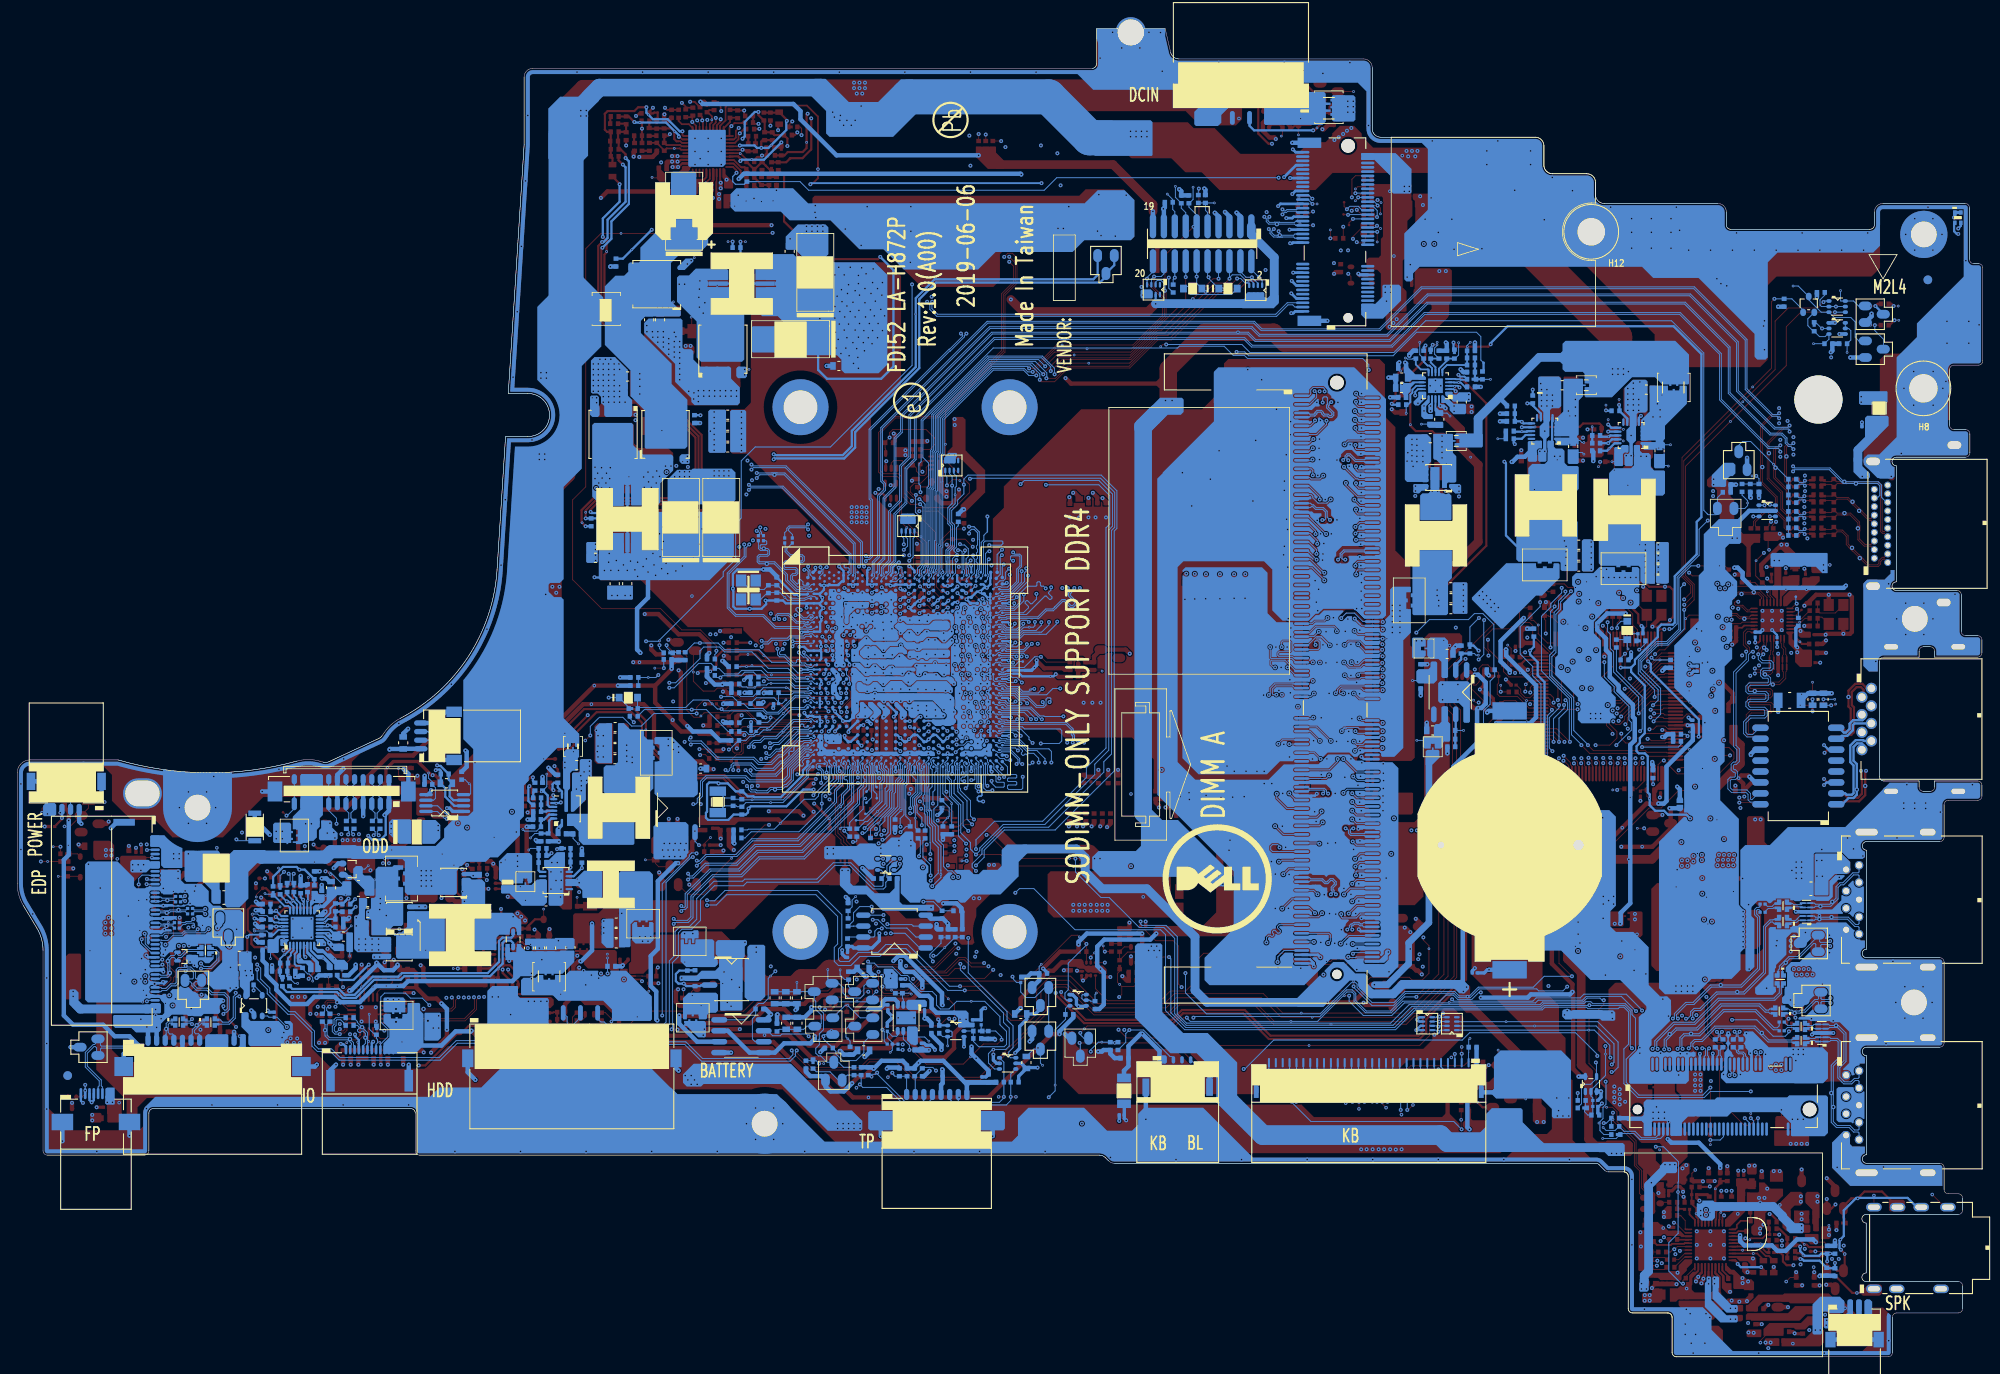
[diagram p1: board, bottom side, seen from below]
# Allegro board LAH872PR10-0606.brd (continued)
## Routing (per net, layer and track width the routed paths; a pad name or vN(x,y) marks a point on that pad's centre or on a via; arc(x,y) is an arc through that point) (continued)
LANXIN: length 2.7
  TOP w0.102: UL1.28 21.06,85.81 RL2.2
LANXIN_R: length 4.4
  TOP w0.102: CL1.1 RL2.1 18.92,86.48 17.13,86.48 YL1.1
LANXOUT: length 2.5
  TOP w0.102: RL3.2 20.65,85.87 21.11,85.41 v2(21.28,85.41) UL1.29
LANXOUT_R: length 2.6
  TOP w0.102: CL7.1 19.2,84.98 RL3.1 19.07,86 18.69,86 YL1.3
LCD_TEST: length 216.4
  TOP w0.102: v1(211.1,48.83) 210.98,48.83 210.85,48.95 v2(210.85,50.5) 210.85,51.3 211.55,52 RV2.1 ; v1(49.25,71.5) 49.97,72.22 UE1.72
  IN1 w0.127: v1(211.1,48.83) 207.21,48.83 206.51,48.13 201.88,48.13 199.46,45.71 199.46,45.22 197.01,42.77 192.42,42.77 190.95,44.24 189.57,44.24 189.15,43.82 181.51,43.82 181.11,43.43 158.76,43.43 157.24,41.91 156.18,41.91 156.08,41.8 150.45,41.8 143.01,34.36 136.8,34.36 135.46,33.02 130.1,33.02 129.18,32.09 123.28,32.09 122.82,31.64 119.33,31.64 119.03,31.94 108.11,31.94 108.03,32.01 92.58,32.01 88.38,36.22 69.31,36.22 65.9,39.63 65.46,39.63 63.06,42.03 62.69,42.03 60.97,43.75 60.97,51.57 58.83,53.71 58.83,61.72 54.2,66.35 54.2,68.19 53.07,69.32 53.07,71.41 51,73.48 51,76.86 50.78,77.08 49.14,77.08 48.49,76.43 v1(48.49,76.34)
  BOTTOM w0.102: v1(49.25,71.5) 49.25,74.24 48.25,75.24 48.25,76.1 v1(48.49,76.34)
LCD_TST_C: length 6.3
  TOP w0.102: v1(214.28,54.92) v2(214.28,53.06) 214.28,52.45 213.84,52 RV2.2
  BOTTOM w0.102: v1(214.28,54.92) 214.28,55.62 213.9,56 213.08,56 213.02,55.95 JEDP1.10
LDO1_CAP: length 3.8
  TOP w0.203: UA1.21 28.76,14.81 28.58,14.99 28.58,15.35 28.13,15.81 CA479.2 26.98,16.77 RA47.2
LDO2_CAP: length 1.6
  TOP w0.203: UA1.32 30.26,10.03 29.57,9.34 CA482.2
LDO3_CAP: length 4.3
  TOP w0.203: CA493.2 37.86,13 36.24,13 36.1,13.14 34.71,13.14 34.63,13.21 UA1.6
LG1_APU: length 27.6
  TOP w0.102: v1(143.86,114.8) v2(143.37,114.8)
  IN2 w0.762: 149.77,116.77 147.54,114.55 144.6,114.55 ; 148.31,135.12 148.31,132.77 149.51,131.57 151.16,131.57 153.32,129.41 153.32,124.2 150.53,121.41 150.53,118.36
  vias: v1(143.86,114.17) v1(147.73,136.26) v1(147.73,135.68) v1(150.15,117.53) v1(150.72,117.53)
LG_1.2V: length 9.8
  IN2 w0.762: 66.33,110.23 67.64,108.92 67.64,102.46 66.58,101.4
  vias: v1(65.25,111.31) v1(65.63,110.87) v1(65.92,101.24) v1(65.92,100.67)
LG_CHG: length 3.5
  IN2 w0.762: 192.25,46.44 190.06,46.44 190.03,46.48 188.76,46.48
  vias: v1(186.28,46.48) v1(186.91,46.48) v1(192.76,47.99) v1(193.34,47.99)
LG_NB: length 31.2
  TOP w0.102: v1(161.07,111.5) v2(161.58,111.5)
  IN1 w0.762: 153.91,139.68 154.78,138.81 154.78,135.12 157.96,131.95 157.96,117.03 157.2,116.26 157.2,111.63 156.75,111.18
  vias: v1(151.67,139.6) v1(152.31,139.6) v1(156.56,110.17) v1(156.56,109.53) v1(161.07,110.93)
LID_SW#: length 265.6
  TOP w0.102: RE18.1 42.25,85.55 42.48,85.31 v1(42.48,84.74) 42.53,84.69 UE1.115 ; v4(223.4,63.25) 223.2,63.05 v1(223.2,62.64)
  TOP w0.254: EC2.1 223.2,62.5 v1(223.2,62.64)
  IN1 w0.127: v1(42.48,84.74) 42.71,84.51 43.46,83.76 50.08,83.76 51.17,82.66 51.17,81.89 52.13,80.93 53.66,80.93 53.82,80.77 55.37,80.77 56.49,79.65 56.49,78.29 57.06,77.72 57.06,76.06 58.4,74.71 58.4,72.66 62.52,68.54 62.52,62.62 65.15,60 65.15,49.81 65.81,49.16 65.81,47.7 68.32,45.18 68.32,44.33 70.31,42.34 71.38,42.34 72.92,40.8 95.21,40.8 96.97,39.04 102.06,39.04 102.19,39.16 103.49,39.16 104.33,38.33 116.36,38.33 116.91,37.79 124.31,37.79 124.87,38.35 126.8,38.35 127.59,39.14 141.09,39.14 141.49,39.53 141.49,40.56 147.68,46.75 147.68,48.97 150.43,51.71 150.43,52.65 152.66,54.88 152.66,56.27 154.17,57.78 154.17,60.38 153.62,60.93 153.62,62.93 153.37,63.17 153.37,67.61 156.54,70.77 156.54,71.6 158.29,73.35 175.78,73.35 177.7,71.43 179.6,71.43 181.2,69.83 181.2,69.08 184.82,65.46 190.55,65.46 193.43,62.59 193.43,59.47 193.59,59.3 193.59,59.22 194.15,58.67 203.36,58.67 205.08,56.95 210.41,56.95 213.78,53.59 220.19,53.59 223.87,57.27 223.87,61.59 223.2,62.26 v1(223.2,62.64)
  BOTTOM w0.102: v1(42.48,84.74) 42.48,85.07 42.03,85.52 DE1.1
  BOTTOM w0.254: JPWR1.3 v1(223.2,62.64)
LINE1-L: length 3.3
  TOP w0.203: UA1.18 30.66,15.92 30.59,15.98 30.59,16.65 v2(30.44,16.8) 30.29,16.95 29.45,16.95 29.18,17.22 CA500.1
LINE1-L_C: length 8.1
  TOP w0.254: v1(24.77,16.6) 24.64,16.6 23.96,15.92 RA59.1 ; CA500.2 v1(29.18,19.3)
  IN2 w0.254: v1(29.18,19.3) 29.18,18.41 27.66,16.89 25.05,16.89 v1(24.77,16.6)
LINE1-L_R: length 12.3
  TOP w0.254: RA55.1 23.38,13.56 v1(23.34,13.52) ; CA503.2 v1(30.39,19.3)
  IN2 w0.254: v1(23.34,13.52) 23.01,13.85 23.01,14.52 24.13,15.64 24.82,15.64 25.5,16.31 28.29,16.31 30.39,18.41 v1(30.39,19.3)
LINE1-R: length 2.4
  TOP w0.203: CA503.1 30.72,17.38 30.72,17.1 30.97,16.85 30.97,16.01 31.06,15.92 UA1.17
LOM_TCT: length 12.6
  TOP w0.508: v1(27.11,67.45) 27.25,67.58 28.06,67.58 v4(28.37,67.28) 28.37,67.18 27.83,66.64 CL21.1 26.84,66.78 TL1.11 ; TL1.14 26.47,70.59 26.95,70.11 v1(26.95,69.99)
  IN1 w0.508: v1(27.11,67.45) 27.11,69.82 v1(26.95,69.99)
  BOTTOM w0.508: TL1.11 26.45,66.78 v1(27.11,67.45) ; v1(26.95,69.99) 26.95,70.08 26.44,70.59 TL1.14
LPC_AD0: length 140
  TOP w0.102: UE1.10 37.83,78.22 41.62,74.43 41.62,74.07 42.15,73.53 42.64,73.53 42.94,73.83 v1(42.94,73.88)
  IN2 w0.127: v1(42.94,73.88) 42.99,73.83 43.49,73.83 44.11,73.21 51.41,73.21 54.2,70.42 54.2,70.1 55.43,68.87 55.43,58.25 64.35,49.33 65.36,49.33 67.34,47.35 67.34,45.88 67.53,45.68 67.53,41.22 70.17,38.59 95.63,38.59 97.23,40.19 100.53,40.19 101.16,40.82 103.95,40.82 104.46,41.33 104.73,41.6 105.62,41.6 105.82,41.4 110.86,41.4 111.27,41.81 116.22,41.81 118.4,43.99 118.93,43.99 121.09,46.15 121.09,47.3 122.67,48.88 122.67,52.36 122.49,52.54 122.49,55.12 v1(122.26,55.35)
  BOTTOM w0.102: UC1.BA26 122.48,66.33 122.58,66.24 122.58,63.54 122.39,63.35 122.39,62.02 122.02,61.65 122.02,59.88 121.38,59.23 121.38,56.53 121.37,56.53 121.37,56.24 v1(122.26,55.35)
LPC_AD1: length 141.4
  TOP w0.102: UE1.8 37.46,79.02 41.96,74.52 41.96,74.51 v1(42.02,74.45)
  IN2 w0.127: v1(42.02,74.45) 42.19,74.45 42.27,74.36 42.49,74.36 42.55,74.3 43.64,74.3 44.29,73.64 52.62,73.64 55.09,71.18 55.09,69.97 56.05,69.01 56.05,58.24 64.51,49.78 65.53,49.78 67.77,47.53 67.77,46.05 68.06,45.77 68.06,41.31 70.35,39.02 74.79,39.02 75.07,39.31 90.78,39.31 91.6,40.13 96.55,40.13 97.13,40.7 100.42,40.7 100.98,41.25 103.77,41.25 104.23,41.71 104.28,41.77 104.55,42.03 105.8,42.03 106,41.84 110.68,41.84 111.09,42.24 116.04,42.24 118.22,44.42 118.75,44.42 120.66,46.33 120.66,47.48 121.99,48.8 121.99,51.78 121.67,52.09 121.67,54.32 v1(122.07,54.72)
  BOTTOM w0.102: v1(122.07,54.72) 121.07,55.73 v2(121.07,56.09) 121.07,56.57 121.07,56.57 121.07,59.36 121.72,60 121.72,61.66 122.14,62.08 122.14,63.48 122.38,63.71 122.38,66 122.08,66.29 122.08,68.26 122.28,68.46 122.28,68.69 122.13,68.84 122.13,69.05 122.24,69.15 122.24,69.46 122.04,69.66 UC1.AY28
LPC_AD2: length 141.3
  TOP w0.102: v1(42.54,74.8) 42.43,74.8 42.27,74.95 42.1,74.95 37.73,79.33 37.02,79.33 36.92,79.42 UE1.7
  IN2 w0.127: v1(42.54,74.8) 42.59,74.8 42.6,74.79 42.67,74.79 42.73,74.73 43.21,74.73 43.41,74.92 43.95,74.92 44.29,75.26 45.88,75.26 46.77,74.37 53.52,74.37 56.49,71.4 56.49,58.42 64.26,50.64 65.27,50.64 65.6,50.32 67.35,50.32 67.59,50.07 67.59,48.32 68.21,47.71 68.21,46.23 68.49,45.95 68.49,41.77 70.81,39.45 74.61,39.45 74.89,39.74 90.58,39.74 91.51,40.67 96.03,40.67 96.5,41.14 100.26,41.14 100.88,41.77 103.67,41.77 104.19,42.29 104.37,42.46 105.96,42.46 106.41,42.92 107.84,42.92 108.09,42.67 115.86,42.67 118.04,44.86 118.58,44.86 120.23,46.51 120.23,47.66 121.07,48.49 121.07,51.89 121.24,52.07 121.24,54.85 121.81,55.41 121.81,56.15 123.18,57.52 123.18,61.7 123.28,61.8 v1(123.28,61.82)
  BOTTOM w0.102: v1(123.28,61.82) 123.28,62.71 123.84,63.27 123.84,64.16 123.92,64.24 123.92,64.81 123.29,65.43 123.29,68.32 123.35,68.37 123.35,68.74 123.03,69.05 UC1.AY25
LPC_AD3: length 141.4
  TOP w0.102: v1(42.44,75.4) 42.17,75.4 37.35,80.22 UE1.5
  IN2 w0.127: v1(124.62,63.78) 124.54,63.69 124.54,63.67 122.71,61.85 122.71,60.38 122.3,59.96 122.3,59.32 122.75,58.87 122.75,57.7 120.56,55.51 120.56,55.2 119.8,54.44 119.8,46.77 119.37,46.35 118.79,46.35 115.55,43.11 108.27,43.11 108.02,43.35 106.24,43.35 105.78,42.9 104.1,42.9 103.46,42.25 96.01,42.25 95.73,41.97 89.74,41.97 87.94,40.17 74.71,40.17 74.43,39.89 71.23,39.89 69.41,41.7 69.41,45.64 68.64,46.41 68.64,47.89 68.02,48.5 68.02,50.25 66.86,51.41 64.58,51.41 56.92,59.08 56.92,71.58 53.7,74.8 46.94,74.8 46.06,75.69 44.11,75.69 43.78,75.36 43.39,75.36 43.18,75.57 42.6,75.57 v1(42.44,75.4)
  BOTTOM w0.102: UC1.AY23 124.13,69.08 124.45,68.76 124.45,68.73 124.48,68.71 124.48,68.27 124.48,68.27 124.48,68.22 124.55,68.15 124.55,67.67 123.98,67.1 123.98,65.67 124.61,65.04 124.61,63.79 v1(124.62,63.78)
LPC_CLK0_EC: length 138.7
  TOP w0.102: v1(41.53,73.54) 41.51,73.54 41.31,73.74 41.31,74.31 38.19,77.42 UE1.12 v2(34.12,77.42) 33.96,77.42 33.69,77.15 RE11.1
  IN2 w0.127: v1(41.53,73.54) 41.53,73.52 42.08,72.97 43.13,72.97 43.76,72.35 50.87,72.35 51.66,71.56 51.66,70.99 53.82,68.83 53.82,57.75 63.29,48.29 65.8,48.29 66.89,47.19 66.89,45.72 67.1,45.5 67.1,41.04 70.2,37.94 96.17,37.94 97.91,39.68 100.63,39.68 101.34,40.39 104.13,40.39 104.44,40.7 104.91,41.17 105.44,41.17 105.64,40.97 111.04,40.97 111.45,41.38 116.39,41.38 118.57,43.56 119.11,43.56 121.52,45.97 121.52,47.12 123.1,48.7 v1(123.1,52.91) 122.93,53.09 122.93,55.3 v1(122.26,55.96)
  BOTTOM w0.102: RC77.2 RC89.1 120.93,51.92 121.92,52.91 v1(123.1,52.91) ; RC107.1 123.16,60.02 123.16,58.09 122.26,57.2 v1(122.26,55.96)
LPC_CLK1: length 19.1
  IN2 w0.127: v1(123.61,58.21) 123.61,56.4 123.36,56.15 123.36,53.4 123.53,53.23 123.53,47.93 122.23,46.63 v1(121.94,46.63)
  BOTTOM w0.102: v1(123.61,58.21) 123.61,58.4 123.46,58.55 123.46,60.01 RC109.1 ; RC78.2 RC94.1 v2(120.62,47.58) 121.57,46.63 v1(121.94,46.63)
LPC_FRAME#: length 152.8
  TOP w0.102: UE1.4 37.38,80.62 42.01,76 42.79,76 43.41,75.37 43.41,73.6 42.52,72.7 42.52,71.94 43.34,71.12 v1(44.99,71.12)
  IN2 w0.127: v1(44.99,71.12) 45.79,71.92 50.61,71.92 51.15,71.37 51.15,70.61 53.31,68.45 53.31,57.65 63.11,47.86 65.62,47.86 66.46,47.01 66.46,45.54 66.67,45.33 66.67,40.86 70.1,37.43 88.77,37.43 88.85,37.36 96.2,37.36 98.02,39.17 100.84,39.17 101.62,39.96 108.13,39.96 108.72,40.54 111.22,40.54 111.63,40.95 116.57,40.95 117.16,41.54 117.95,41.54 122,45.59 v1(122,45.97) 122.37,45.97 123.97,47.57 123.97,53.4 123.79,53.58 123.79,55.97 124.04,56.22 124.04,58.4 123.7,58.74 123.7,61.61 123.71,61.62 123.71,62.24 124.65,63.17 v1(124.65,63.19)
  BOTTOM w0.102: RC88.1 RC76.2 121.06,48.09 122.35,46.8 122.35,46.46 122,46.12 v1(122,45.97) ; v1(124.65,63.19) 124.34,63.19 124.24,63.29 124.24,63.94 124.35,64.04 124.35,64.98 123.75,65.58 123.75,67.96 123.78,68 123.78,68.71 123.9,68.82 123.9,69.11 123.58,69.43 UC1.AY24
LPC_RST_A#: length 36.8
  TOP w0.102: v2(102.21,47.77) 102.21,47.3 v1(102.02,47.11) RC111.2
  IN2 w0.127: v1(121.99,64.33) 121.99,64.23 120.37,62.61 120.37,59.04 119.24,57.91 119.24,57.18 116.11,54.05 113.14,54.05 112.37,53.27 111.71,53.27 106.94,48.51 102.78,48.51 102.02,47.75 v1(102.02,47.11)
  BOTTOM w0.102: UC1.AY27 121.93,69.05 121.71,68.83 121.7,68.83 121.63,68.76 121.63,68.74 121.63,68.73 121.63,68.48 121.63,68.48 121.63,68.07 121.76,67.94 121.76,65.91 121.99,65.68 v1(121.99,64.33)
LPCPD#: length 8.9
  BOTTOM w0.102: UC1.AC1 137.91,78.81 138.65,79.54 141.19,79.54 141.89,80.24 v2(143.66,80.24) RC108.2
LX1_APU: length 10
  IN2 w0.762: 151.42,126.49 151.42,128.58 150.3,129.7 149.01,129.7 146.85,131.86 146.85,133.85
  vias: v1(144.43,122.42) v1(144.5,123.44) v1(144.75,121.47) v1(145.13,122.49) v1(145.2,123.95) v1(145.26,123.12) v1(145.51,121.85) v1(145.96,122.74) v1(146.08,121.28) v1(146.66,122.04) v1(146.85,135.19) v1(146.85,134.62) v1(147.16,122.8) v1(147.23,121.34) v1(147.74,122.04) v1(148.5,122.55) v1(148.69,121.34) v1(149.07,125.09) v1(149.13,124.14) v1(149.13,122.04) v1(149.2,123.19) v1(150.85,124.71) v1(151.48,124.71) v2(147.06,124.57)
LX_0.95V: length 1.6
  TOP w0.102: PRH07.1 v2(158.16,62.24)
  vias: v1(161.08,62.83) v1(161.08,62.2)
LX_1.2V: length 8.2
  IN2 w0.762: 63.79,101.4 63.79,106.61 64.93,107.75 64.93,109.15
  vias: v1(63.34,100.66) v1(63.98,100.66) v1(64.93,110.55) v1(64.93,109.98)
LX_1.8V:
  vias: v1(163.1,55.11) v2(163.33,55.55)
LX_3V: length 3.1
  BOTTOM w0.254: 50.05,106.12 50.05,108.73 50,108.78 PU301.6
  vias: v1(49.12,104.7) v1(49.75,104.7) v2(49.45,104.29)
LX_5V: length 7.2
  TOP w0.102: PR505.1 v2(37.65,105.66)
  IN2 w0.254: v1(39.72,104.7) v1(39.72,109.4)
  BOTTOM w0.254: PU501.6 39.96,109.16 v1(39.72,109.4)
  vias: v1(39.09,104.7)
LX_CHG: length 7.2
  TOP w0.102: v1(183.99,49.08) v2(184.5,49.08)
  IN2 w0.762: 191.12,48.04 189.82,49.33 184.92,49.33
  vias: v1(183.3,49.08) v1(191.78,47.71) v1(192.12,48.15)
LX_NB: length 37.2
  IN2 w0.762: 152.75,104.26 152.75,107.56 153.25,108.06 153.25,114.83 157.17,118.75 157.17,131.59 153.26,135.5 153.26,138.04
  vias: v1(151.67,138.96) v1(152.31,138.96) v1(152.43,103.56) v1(153.07,103.56) v1(153.77,102.36) v1(154.09,102.99) v1(154.15,101.6) v1(154.53,102.29) v1(154.72,101.09) v1(155.04,101.72) v1(155.1,102.87) v1(155.55,101.09) v1(155.61,102.29) v1(159.48,103.37) v1(159.55,102.1) v1(159.55,101.02) v1(159.93,102.74) v1(159.99,101.6) v1(160.05,100.64) v1(160.44,102.17) v1(160.5,103.37) v1(160.5,101.02) v1(160.82,101.6) v1(160.94,102.74) v1(161.26,103.44) v1(161.26,102.1) v2(157.32,102.32)
MASK_BASE_LED#: length 81.6
  TOP w0.102: v1(54.35,79.51) 54.35,79.55 54.86,80.06 55.05,80.06 55.18,80.19 55.18,80.92 RE53.2 54.81,81.52 54.81,82.35 v2(55.2,82.75)
  IN1 w0.127: v1(31.96,97.23) 31.78,97.4 31.78,98.59 33.05,99.86 33.05,111.9 26.93,118.03 18.66,118.03 17.7,118.99 17.7,121.71 17.31,122.11 v1(17.06,122.11) ; v1(54.35,79.51) 54.22,79.51 54.13,79.42 51.49,79.42 49.44,81.47 47.33,81.47 46.44,80.58 45.55,80.58 44.12,82.01 42.72,82.01 40.73,84.01 36.71,84.01 36.41,84.31 v1(36.41,84.62)
  BOTTOM w0.102: R78.2 18.36,123.44 18.92,122.88 18.92,122.28 18.74,122.11 Q7.2 v1(17.06,122.11) Q7.5 ; v1(31.96,97.23) 32.97,96.22 32.97,93.19 35.52,90.64 35.52,85.21 36.11,84.62 v1(36.41,84.62)
MASK_SATA_LED#: length 73.9
  TOP w0.102: v1(48.99,80.2) 48.99,80.66 52.29,83.97 52.29,85.02 52.65,85.38 53.49,85.38 53.84,85.73 53.84,86.8 53.56,87.08 RE20.2 ; v1(24.21,123.01) 24.55,122.68 24.55,114.96 v2(26.74,112.77) 34.95,104.56 34.95,90.65 33.94,89.65 33.94,88.82 v1(34.71,88.06)
  IN1 w0.127: v1(34.71,88.06) 35.53,87.23 35.53,84.68 36.46,83.75 40.52,83.75 42.52,81.76 42.52,81.59 43.79,80.32 48.87,80.32 v1(48.99,80.2)
  BOTTOM w0.102: v1(24.21,123.01) R42.1 22.18,123.01 20.88,121.7 Q12.2
MCT: length 7.4
  TOP w0.102: RL13.1 v2(19.78,78.43)
  TOP w0.508: RL13.1 RL14.1 v1(17.56,77.15)
  BOTTOM w0.508: CL20.1 20.29,77.15 RL13.1 RL14.1 v1(17.56,77.15)
MCT0: length 9.2
  TOP w0.102: v1(17.62,75.75) 17.23,75.75 v2(17.09,75.89)
  TOP w0.254: TL1.3 18.02,70.59 v1(18.39,70.23)
  IN2 w0.254: v1(17.62,75.75) 17.18,75.31 17.18,71.43 v1(18.39,70.23)
  BOTTOM w0.102: RL12.2 v1(17.62,75.75)
MCT1: length 13.6
  TOP w0.102: RL13.2 v2(21.22,75.75)
  TOP w0.254: v1(18.45,67.18) 18.05,66.78 TL1.6 ; v1(19.78,75.05) RL13.2
  IN1 w0.254: v1(18.45,67.18) 17.5,68.13 17.5,73.88 18.67,75.05 v1(19.78,75.05)
MCT2: length 9.5
  TOP w0.102: RL14.2 v1(18.51,76.45)
  IN2 w0.254: v1(18.45,71.12) 17.81,71.75 17.81,74.99 18.51,75.69 v1(18.51,76.45)
  BOTTOM w0.102: v1(18.51,76.45) v2(17.2,76.45)
  BOTTOM w0.254: TL2.6 17.92,70.59 v1(18.45,71.12)
MCT3: length 15.8
  TOP w0.102: v1(19.78,76.45) 20.47,76.45 v2(21.05,77.03)
  IN1 w0.254: v1(18.45,66.48) 16.89,68.04 16.89,73.87 19.47,76.45 v1(19.78,76.45)
  BOTTOM w0.254: RL15.2 v1(19.78,76.45) ; v1(18.45,66.48) 18.15,66.78 TL2.3
MEM_VOLT_SEL: length 16.5
  TOP w0.102: v1(132.63,74.96) 132.93,74.66 135.76,74.66 136.87,73.56 142.31,73.56 143.77,75.02 145.14,75.02 145.72,74.44 RC79.2 147.02,74.4 RC90.1
  BOTTOM w0.1: v1(132.63,74.96) 132.83,75.16 UC1.AJ7
MIC_CAP: length 2.3
  TOP w0.203: CA26.1 31.68,17.61 31.68,16.81 31.71,16.78 v2(31.71,16.76) 31.71,16.2 31.86,16.05 UA1.15
NCT7718_DXN: length 120
  IN2 w0.254: v1(179.61,68.77) 179.43,68.58 179.06,68.58 177.45,70.19 177.45,70.99 164.27,84.18 154.13,84.18 145.58,92.73 145.58,97.67 141.58,101.67 141.58,104.33 141.07,104.83 140.6,104.83 v1(140.5,104.94)
  BOTTOM w0.254: v1(140.5,104.94) 140.39,104.83 132.46,104.83 131.42,105.88 131.42,107.66 123.99,115.09 v2(123.99,121.23) 123.99,123.09 121.79,125.28 103.35,125.28 102.85,125.78 Q13.3 ; U1.3 177.71,64.71 178.15,65.15 178.15,66.37 C12.2 178.27,67.11 C13.2 179.21,68.7 179.55,68.7 v1(179.61,68.77)
NCT7718_DXP: length 121.7
  IN2 w0.254: v1(140.5,104.35) 140.6,104.45 140.91,104.45 141.19,104.17 141.19,101.52 145.2,97.52 145.2,92.57 153.97,83.8 164.11,83.8 177.07,70.83 177.07,70.03 178.9,68.2 v1(179.77,68.2)
  BOTTOM w0.254: U1.2 177.6,64.06 178.66,65.12 178.66,66.11 C12.1 179.18,66.73 C13.1 179.18,68.14 179.31,68.27 179.7,68.27 v1(179.77,68.2) ; Q13.2 100.92,126.92 Q13.1 101.89,125.6 102.59,124.9 121.64,124.9 123.58,122.96 123.58,114.96 131.03,107.5 131.03,105.72 132.3,104.45 140.39,104.45 v1(140.5,104.35)
NO_SMOKE_OVP: length 12.2
  TOP w0.102: v1(177.2,45.14) v2(177.73,45.14)
  TOP w0.254: 171.82,45.54 171.81,45.52 171.17,45.52 170.66,45.02 PC909.1 PC908.1 ; 171.82,45.54 PU900.1 ; 171.82,45.54 171.99,45.37 v1(171.99,45.02) 171.99,44.64 170.85,43.49 PQ900.5 ; v1(177.2,45.14) PD901.2
  IN1 w0.254: v1(177.2,45.14) 172.12,45.14 v1(171.99,45.02)
NO_SMOKE_UVP: length 29.3
  TOP w0.254: PU900.7 171.01,47.4 170.73,47.13 PC910.1 PC911.1 170.51,47.9 170.21,48.19 169.69,48.19 169.07,47.57 v1(169.07,47.52) ; PQ900.2 170.85,41.59 170.28,42.16 v2(165.25,42.16) 164.44,42.16 164.28,42.31 164.28,45.66 v1(163.32,46.63) ; PD902.2 172.16,51.98 172.18,52 v1(172.18,52.07)
  IN1 w0.254: v1(172.18,52.07) 172.18,51.11 169.07,48 v1(169.07,47.52)
  IN2 w0.254: v1(163.32,46.63) 163.89,46.63 164.12,46.86 168.41,46.86 v1(169.07,47.52)
NTC_CHG: length 2.4
  TOP w0.102: v1(192.31,50.16) v2(192.66,50.51)
  BOTTOM w0.203: PUB01.13 192.43,50.04 v1(192.31,50.16) 191.99,50.16 191.8,49.97 PRB13.2
ODD_DA#: length 5.2
  TOP w0.102: T18.1 197.49,63.3 v1(197.11,62.92)
  BOTTOM w0.102: JODD1.24 JODD1.23 196.2,63.73 197.01,62.92 v1(197.11,62.92)
ON/OFF#: length 287.2
  TOP w0.102: v1(45.56,77.7) 42.93,80.33 UE1.114 ; SW1.2 221.7,64.5 RE44.2 221.97,64.77 221.97,65.34 221.84,65.46 EC1.1 222.72,65.83 CE18.1 223.55,65.02 v1(223.55,64.89) 223.95,64.5 224.76,64.5 225.51,63.75 v4(225.51,63.27) ; SW1.2 220.13,63.79 ED3.3 222.25,61.67 v4(222.91,61.67) ; SW1.2 v4(218.23,64.5)
  IN1 w0.127: v1(45.56,77.7) 45.73,77.7 46.1,77.33 50.88,77.33 51.25,76.96 51.25,73.58 53.32,71.51 53.32,69.58 54.45,68.45 54.45,66.47 59.09,61.83 59.09,53.82 61.24,51.68 61.24,43.84 62.79,42.29 63.17,42.29 65.57,39.88 66,39.88 69.34,36.55 88.41,36.55 92.57,32.38 108.17,32.38 108.37,32.19 119.13,32.19 119.41,31.92 122.74,31.92 123.17,32.35 129.08,32.35 130,33.27 135.35,33.27 136.7,34.62 142.9,34.62 150.34,42.06 155.84,42.06 156.11,42.33 157.3,42.33 158.66,43.68 180.94,43.68 181.34,44.08 189.05,44.08 189.46,44.5 191.06,44.5 192.53,43.02 196.91,43.02 199.21,45.32 199.21,45.82 201.77,48.38 206.41,48.38 207.11,49.08 210.22,49.08 210.38,49.25 211.93,49.25 213.05,48.13 220.65,48.13 225.14,52.62 225.14,58.1 225.71,58.67 225.71,64.07 224.89,64.89 v1(223.55,64.89) 221.98,63.32 221.98,60.92 221.29,60.23 213.42,60.23 213.18,59.99 203.09,59.99 v1(202.93,60.15)
  BOTTOM w0.102: SW2.2 202.78,60 v1(202.93,60.15) ; v1(223.55,64.89) 222.67,64.89 222.2,64.43 JPWR1.2
P_ZVDDP: length 14.3
  TOP w0.254: v1(131.84,81.56) 132.47,80.93 141.9,80.93 142.64,81.66 v2(143.49,81.66) 144.39,81.66 RC1.2
  BOTTOM w0.2: v1(131.84,81.56) 132.03,81.75 UC1.U8
P_ZVSS: length 14.3
  TOP w0.254: RC2.1 v2(140.76,79.29) 135.5,79.29 134.85,79.95 132.19,79.95 v1(131.69,80.45)
  BOTTOM w0.2: UC1.W8 131.69,80.66 v1(131.69,80.45)
PANEL_BKLEN: length 142.6
  TOP w0.102: v1(51.44,87.74) 51.44,88.46 51.34,88.56 DV1.3 ; QC1.1 122.73,101.14 RC8.1 123.8,100.9 123.44,100.54 v1(123.44,100.52) ; RE48.2 56.1,71.31 55.72,70.92 v1(55.53,70.92)
  IN1 w0.127: v1(51.44,87.74) 52.1,87.74 54,85.84 54,85.42 57.37,82.04 57.95,82.04 58.33,81.66 62.01,81.66 66.32,85.96 66.32,86.55 71.51,91.75 71.51,114.57 v1(71.35,114.74)
  BOTTOM w0.102: v1(55.53,70.92) 53.25,70.92 51.34,72.83 51.34,78.23 52.29,79.18 52.29,80.26 53.76,81.72 53.76,84.89 51.44,87.21 v1(51.44,87.74) ; v1(123.44,100.52) 123.44,101.3 123.62,101.49 123.62,103.82 123.36,104.08 123.36,108.91 114.98,117.3 93.56,117.3 93.36,117.5 88.16,117.5 87.09,116.43 85.8,116.43 85.44,116.07 72.06,116.07 71.35,115.37 v1(71.35,114.74)
PANEL_BKLEN_APU: length 16.6
  TOP w0.102: QC1.3 123.1,99.82 123.4,100.12 123.88,100.12 v1(123.97,100.21) 124.03,100.26 124.31,100.26 124.62,100.57 124.62,101.1 124.15,101.57 123.41,101.57 122.46,102.53 122.46,103.07 122.35,103.18 RPC2.5
  BOTTOM w0.102: UC1.B23 124.13,90.74 123.78,91.08 123.78,91.59 123.78,91.59 123.78,91.71 123.37,92.12 123.37,97.54 124,98.17 124,100.18 v1(123.97,100.21)
PBTN_OUT#: length 211.8
  TOP w0.102: v1(39.99,74.81) 38.58,76.22 UE1.15 34.16,76.22 v2(34.04,76.11) 33.7,76.11 33.42,76.39 CE15.1
  IN1 w0.127: v1(43.6,85.4) 43.66,85.47 46.26,85.47 46.77,84.96 50.9,84.96 52.68,83.18 53.82,83.18 55.22,81.78 55.82,81.78 58.09,79.52 58.09,78.94 59.56,77.46 59.56,74.67 63.73,70.5 63.73,65.18 68.1,60.81 68.1,47.06 72.76,42.4 74.28,42.4 74.39,42.29 95.52,42.29 97.5,40.31 101.18,40.31 101.34,40.47 103.98,40.47 104.85,39.6 117.81,39.6 118.11,39.9 121.41,39.9 121.64,40.13 124.43,40.13 124.83,40.53 128.81,40.53 129.09,40.8 129.29,41.01 132.51,41.01 132.81,41.31 139.54,41.31 145.7,47.47 145.7,52.11 148.18,54.58 148.18,60.52 151.68,64.03 151.68,68.1 154.21,70.63 154.21,76.2 v1(152.62,77.78)
  BOTTOM w0.102: v1(152.62,77.78) 152.05,77.78 149.22,80.62 147.79,80.62 147.33,80.16 RC74.2 146.86,80.05 146.2,79.39 144.64,79.39 144.22,79.81 141.95,79.81 141.14,79 138.43,79 137.91,78.48 136.41,78.48 136.32,78.57 136.05,78.57 135.74,78.26 UC1.AD2 ; v1(39.99,74.81) 39.99,76.71 42.9,79.62 42.9,81.97 43.28,82.35 43.28,84.01 43.6,84.32 v1(43.6,85.4)
PCIE_ARX_C_DTX_N0: length 4.5
  TOP w0.102: UL1.18 25.48,88.09 25.5,88.1 25.5,88.39 26.01,88.9 v3(26.62,88.9) 27.73,88.9 27.75,88.92 28.32,88.92 28.35,88.9 CL9.1
PCIE_ARX_C_DTX_P0: length 4.4
  TOP w0.102: UL1.17 25.88,88 25.7,88.18 25.7,88.3 26.09,88.69 26.31,88.69 26.33,88.67 26.9,88.67 26.92,88.69 v3(28.04,88.69) 28.6,88.69 29.02,88.28 CL8.1
PCIE_ARX_DTX_N0: length 191.2
  TOP w0.102: v1(29.96,89.36) 30.01,89.31 30.01,88.87 29.9,88.77 29.73,88.77 CL9.2
  IN2 w0.102: 137.89,83.89 137.87,83.87 137.85,83.87 137.23,83.24 136.18,83.24 135.66,82.72 135.66,82.22 135.35,81.91 134.17,81.91 133.86,82.22 133.86,82.53 v1(133.71,82.67)
  IN2 w0.127: 137.89,83.89 138.51,84.51 140.56,84.51 141.77,85.72 141.77,86.8 141,87.56 141,94.41 139.92,95.5 139.92,97.11 137.42,99.61 137.42,101.15 126.57,112 126.57,114.53 122.81,118.3 122.81,120.61 117.71,125.71 108.63,125.71 103.08,131.25 87.33,131.25 83.9,134.68 81.58,134.68 79.73,132.82 79.73,129.61 75.61,125.49 67.44,125.49 66.66,124.71 65.86,124.71 64.56,123.41 35,123.41 30.01,118.42 30.01,89.41 v1(29.96,89.36)
  BOTTOM w0.102: UC1.U5 133.83,82.3 133.83,82.56 v1(133.71,82.67)
PCIE_ARX_DTX_N1: length 99.4
  IN2 w0.102: 136.91,85.01 136.88,84.98 136.87,84.98 135.2,83.31 131.69,83.31 131.49,83.11 131.49,82.68 131.42,82.61 131.15,82.61 v1(131.1,82.66)
  IN2 w0.127: 136.91,85.01 137.56,85.67 138.07,85.67 138.79,86.39 138.79,93.56 137.76,94.6 137.76,96.22 135.26,98.72 135.26,100.25 124.41,111.1 124.41,113.64 120.6,117.44 120.6,119.75 117,123.35 101.29,123.35 97.39,127.25 87.54,127.25 83.08,131.7 83.08,132.36 v1(82.9,132.54)
  BOTTOM w0.102: v1(82.9,132.54) 83.06,132.38 83.06,132.08 82.88,131.9 82.33,131.9 82.31,131.92 81.74,131.92 81.72,131.9 79.97,131.9 79.82,132.05 JWLAN1.43 ; UC1.R10 131.37,83.07 131.37,82.76 131.27,82.66 v1(131.1,82.66)
PCIE_ARX_DTX_N2: length 221.3
  IN2 w0.102: 134.65,84.25 134.65,83.92 v1(134.84,83.73)
  IN2 w0.127: v1(28.83,32.74) 28.83,34.5 31.4,37.07 31.4,38.42 30.74,39.09 30.74,43.29 38.58,51.13 38.58,62.29 36.74,64.14 36.74,65.83 34.63,67.94 34.63,70.44 35.65,71.46 35.65,79.13 35.61,79.17 35.61,82.74 34.63,83.72 34.63,86.17 35.12,86.66 35.12,90.01 34.69,90.44 34.69,97.01 35.54,97.85 35.54,116.39 37.76,118.61 66.9,118.61 67.11,118.41 74.12,118.41 75.59,119.87 81.81,119.87 81.82,119.86 93.8,119.86 95.96,117.71 113.77,117.71 117.96,113.52 117.96,107.99 120.79,105.16 120.79,103.21 122.98,101.02 122.98,98.28 124.12,97.14 126.66,97.14 128.15,95.65 131.39,95.65 133.43,93.61 133.43,92.78 133.77,92.44 133.77,91.56 135.73,89.59 135.73,85.66 134.87,84.79 134.87,84.46 134.65,84.25
  BOTTOM w0.102: UC1.R4 134.43,83.33 v1(134.84,83.73) ; JSSD1.43 28.87,33.22 29.02,33.08 29.02,32.93 v1(28.83,32.74)
PCIE_ARX_DTX_N3: length 212.6
  IN2 w0.127: v1(133.32,84.74) 133.32,84.75 133.57,85 133.57,85.2 133.12,85.65 133.12,86.25 132.8,86.57 132.8,90.46 132.17,91.09 132.17,93.17 130.85,94.49 127.61,94.49 126.12,95.98 123.2,95.98 121.82,97.36 121.82,100.53 116.56,105.79 116.56,113.28 113.29,116.55 95.01,116.55 92.85,118.7 81.34,118.7 81.33,118.71 76.26,118.71 74.45,116.9 37.82,116.9 36.7,115.78 36.7,97.3 35.94,96.54 35.94,91.35 36.29,91 36.29,86.18 35.94,85.83 35.94,84.23 36.81,83.36 36.81,70.98 35.79,69.96 35.79,68.71 37.89,66.61 37.89,66.21 38.58,65.52 38.58,64.19 40.03,62.74 40.03,60.04 39.75,59.75 39.75,50.14 32.8,43.2 32.8,36.83 32.24,36.26 32.24,36 32.37,35.87 v1(32.59,35.87)
  BOTTOM w0.102: JSSD1.29 32.38,34.91 32.21,35.07 32.21,35.77 32.31,35.87 v1(32.59,35.87) ; v1(133.32,84.74) 133.79,84.74 133.89,84.64 133.89,84.4 133.79,84.3 133.64,84.3 UC1.N5
PCIE_ARX_DTX_P0: length 191.2
  TOP w0.102: CL8.2 29.6,88.28 29.88,88.57 29.99,88.57 30.21,88.79 30.21,89.03 v1(30.54,89.36)
  IN2 w0.102: v1(134.42,82.65) 134.4,82.67 134.2,82.67 134.1,82.57 134.1,82.31 134.26,82.15 135.25,82.15 135.42,82.31 135.42,82.82 136.08,83.48 137.13,83.48 137.68,84.04 137.68,84.06 137.7,84.07
  IN2 w0.127: v1(30.54,89.36) 30.3,89.6 30.3,89.61 30.27,89.64 30.27,118.31 35.11,123.15 64.67,123.15 65.97,124.45 66.77,124.45 67.55,125.23 75.72,125.23 79.99,129.5 79.99,132.71 81.69,134.41 83.79,134.41 87.22,130.99 102.97,130.99 108.52,125.44 117.6,125.44 122.54,120.5 122.54,118.19 126.31,114.43 126.31,111.89 137.16,101.04 137.16,99.5 139.66,97 139.66,95.39 140.74,94.3 140.74,87.45 141.5,86.69 141.5,85.83 140.45,84.78 138.41,84.78 137.7,84.07
  BOTTOM w0.102: UC1.U4 134.43,82.01 134.33,81.91 134.13,81.91 134.03,82.01 134.03,82.46 134.22,82.65 v1(134.42,82.65)
PCIE_ARX_DTX_P1: length 99.3
  IN2 w0.102: 137,84.74 136.96,84.74 135.3,83.07 131.83,83.07 131.73,82.97 131.73,82.76 131.83,82.66 v1(131.9,82.66)
  IN2 w0.127: v1(83.49,132.54) 83.35,132.4 83.35,131.81 87.65,127.51 97.5,127.51 101.4,123.61 117.11,123.61 120.87,119.86 120.87,117.55 124.67,113.75 124.67,111.21 135.52,100.36 135.52,98.82 138.02,96.33 138.02,94.71 139.06,93.67 139.06,86.28 138.18,85.4 137.67,85.4 137,84.74
  BOTTOM w0.102: v1(131.9,82.66) 131.73,82.83 131.73,82.97 131.92,83.16 131.99,83.16 UC1.R8 ; JWLAN1.41 79.84,131.55 79.98,131.69 v3(82.03,131.69) 82.96,131.69 83.26,131.99 83.26,132.32 v1(83.49,132.54)
PCIE_ARX_DTX_P2: length 221.3
  IN2 w0.102: v1(134.01,83.73) 134.12,83.63 134.26,83.63 134.4,83.77 134.4,84.37
  IN2 w0.127: 134.4,84.37 134.6,84.57 134.6,84.9 135.47,85.77 135.47,89.48 133.5,91.45 133.5,92.33 133.16,92.67 133.16,93.5 131.28,95.39 128.04,95.39 126.55,96.88 124.01,96.88 122.72,98.17 122.72,100.91 120.52,103.1 120.52,105.05 117.7,107.88 117.7,113.41 113.66,117.45 95.85,117.45 93.69,119.6 81.71,119.6 81.7,119.61 75.7,119.61 74.23,118.14 67,118.14 66.79,118.34 37.87,118.34 35.8,116.28 35.8,97.74 34.96,96.9 34.96,90.55 35.39,90.12 35.39,86.55 34.9,86.06 34.9,83.83 35.87,82.85 35.87,79.28 35.92,79.24 35.92,71.36 34.9,70.34 34.9,68.05 37,65.94 37,64.25 38.85,62.4 38.85,51.02 31,43.18 31,39.2 31.67,38.53 31.67,36.96 29.1,34.39 29.1,33.07 29.42,32.75 v1(29.42,32.74)
  BOTTOM w0.102: v1(29.42,32.74) 29.22,32.94 29.22,33.08 29.38,33.24 JSSD1.41 ; UC1.R5 133.71,83.13 133.86,83.13 134.14,83.41 134.14,83.63 134.04,83.73 v1(134.01,83.73)
PCIE_ARX_DTX_P3: length 212.6
  IN2 w0.102: v1(134.21,84.89) 134.15,84.96 134.15,85 133.43,85.72
  IN2 w0.127: v1(31.81,35.86) 31.97,36.03 31.97,36.37 32.54,36.93 32.54,43.31 39.48,50.25 39.48,59.86 39.77,60.15 39.77,62.63 38.31,64.08 38.31,65.41 37.63,66.1 37.63,66.5 35.53,68.6 35.53,70.07 36.55,71.09 36.55,83.25 35.67,84.13 35.67,85.94 36.02,86.29 36.02,90.89 35.67,91.24 35.67,96.65 36.43,97.41 36.43,115.89 37.71,117.16 74.34,117.16 76.15,118.97 81.44,118.97 81.45,118.96 92.96,118.96 95.12,116.81 113.4,116.81 116.82,113.39 116.82,105.9 122.08,100.64 122.08,97.47 123.31,96.24 126.23,96.24 127.72,94.75 130.96,94.75 132.43,93.28 132.43,91.2 133.06,90.57 133.06,86.68 133.38,86.36 133.38,85.76 133.43,85.72
  BOTTOM w0.102: v1(31.81,35.86) 31.97,35.69 31.97,35.02 31.87,34.92 JSSD1.31 ; v1(134.21,84.89) 134.1,84.78 134.1,84.5 134.29,84.31 UC1.N4
PCIE_ATX_C_DRX_N0: length 182.3
  TOP w0.102: v1(29.76,85.7) 29.76,85.7 29.38,86.07 29.38,86.2 29.16,86.42 28.58,86.42 28.17,86.02 28.02,86.02 27.99,86.04 27.42,86.04 27.4,86.02 27.1,86.02 27.02,86.09 27.02,86.17 26.97,86.21 UL1.14
  IN2 w0.127: v1(142.06,96.43) 142.33,96.43 142.4,96.5 142.4,96.96 139,100.35 139,101.81 128.15,112.65 128.15,115.19 124.39,118.95 124.39,121.65 119.7,126.34 109.21,126.34 103.66,131.89 90.97,131.89 88.94,133.92 85.56,133.92 84.11,135.37 81.37,135.37 78.97,132.97 78.97,129.75 75.57,126.35 66.83,126.35 66.78,126.3 66.55,126.3 64.29,124.04 34.49,124.04 29.37,118.93 29.37,96.9 27.97,95.51 27.97,90.29 29.86,88.4 29.86,86.91 29.44,86.49 29.44,86.03 29.76,85.71 v1(29.76,85.7)
  BOTTOM w0.102: v1(142.06,96.43) 142.06,96.02 141.91,95.87 141.91,95.69 CL14.2
PCIE_ATX_C_DRX_N1: length 81.5
  IN2 w0.127: v1(136.5,96.2) 136.29,96.41 135.94,96.41 134.64,97.71 134.64,98.06 134.36,98.34 134.36,99.58 130.39,103.55 129.38,103.55 124.93,108 124.93,109.23 123.35,110.8 123.35,113.42 119.65,117.12 119.65,119.43 116.83,122.25 101.05,122.25 97.01,126.3 86.42,126.3 82.58,130.13 82.58,130.92 v1(82.38,131.12)
  BOTTOM w0.102: JWLAN1.37 79.92,130.55 80.07,130.4 v3(81.7,130.4) 82.34,130.4 82.62,130.68 82.62,130.88 v1(82.38,131.12) ; CC2.2 138.33,95.62 138.77,96.06 138.77,96.24 138.62,96.39 136.69,96.39 v1(136.5,96.2)
PCIE_ATX_C_DRX_N2: length 2.8
  BOTTOM w0.102: JSSD1.47 27.87,34.83 27.78,34.92 27.78,35.1 27.91,35.23 28.4,35.23 28.63,35.46 28.63,35.63 CS33.2
PCIE_ATX_C_DRX_N3: length 2.2
  BOTTOM w0.102: CS31.2 30.73,35.63 30.73,35.07 30.87,34.92 JSSD1.35
PCIE_ATX_C_DRX_P0: length 182.3
  TOP w0.102: v1(29.18,85.7) 29.18,86.11 29.08,86.22 28.66,86.22 28.26,85.81 v3(27.71,85.81) UL1.13
  IN2 w0.127: v1(29.18,85.7) 29.18,86.6 29.6,87.02 29.6,88.29 27.71,90.18 27.71,95.62 29.11,97.01 29.11,119.03 34.38,124.31 64.18,124.31 66.44,126.56 66.68,126.56 66.73,126.61 75.46,126.61 78.71,129.86 78.71,133.08 81.26,135.63 84.22,135.63 85.67,134.18 89.05,134.18 91.08,132.15 103.77,132.15 109.32,126.61 119.81,126.61 124.65,121.76 124.65,119.06 128.42,115.3 128.42,112.76 139.27,101.92 139.27,100.46 142.66,97.07 142.66,96.39 142.47,96.21 v1(142.47,96.02)
  BOTTOM w0.102: CL13.2 142.11,95.64 142.11,95.78 142.35,96.02 v1(142.47,96.02)
PCIE_ATX_C_DRX_P1: length 81.6
  IN2 w0.127: v1(136.5,96.78) 136.4,96.68 136.05,96.68 134.91,97.82 134.91,98.17 134.62,98.45 134.62,99.69 130.5,103.82 129.48,103.82 125.19,108.11 125.19,109.34 123.62,110.91 123.62,113.53 119.92,117.23 119.92,119.54 116.94,122.51 101.16,122.51 97.12,126.56 86.53,126.56 82.85,130.24 82.85,131.01 v1(82.97,131.12)
  BOTTOM w0.102: v1(136.5,96.78) 136.69,96.59 138.71,96.59 138.97,96.32 138.97,96.07 139.22,95.82 CC1.2 ; v1(82.97,131.12) 82.82,130.98 82.82,130.6 82.42,130.2 82,130.2 81.98,130.17 81.41,130.17 81.39,130.2 80.07,130.2 79.92,130.05 JWLAN1.35
PCIE_ATX_C_DRX_P2: length 2.8
  BOTTOM w0.102: CS34.2 28.43,35.66 28.43,35.54 28.32,35.43 27.83,35.43 27.58,35.18 27.58,35 27.38,34.79 JSSD1.49
PCIE_ATX_C_DRX_P3: length 2.2
  BOTTOM w0.102: JSSD1.37 30.38,34.92 30.52,35.07 30.52,35.66 CS32.2
PCIE_ATX_DRX_N0: length 13.2
  BOTTOM w0.102: UC1.D1 136.22,89.21 136.43,89.21 136.52,89.3 136.79,89.3 136.87,89.21 137.07,89.21 137.15,89.3 137.36,89.3 137.45,89.21 137.8,89.21 138.9,90.31 138.9,90.95 140.37,92.43 142.13,92.43 142.21,92.5 142.21,92.96 142.08,93.09 141.19,93.09 140.97,93.31 140.97,93.75 141.19,93.98 v3(141.65,93.98) 141.97,93.98 142.07,94.08 142.07,94.32 141.97,94.42 141.41,94.42 141.31,94.52 141.31,94.79 141.41,94.89 CL14.1
PCIE_ATX_DRX_N1: length 13
  BOTTOM w0.102: UC1.C1 136.68,89.7 137,89.7 137.1,89.81 137.1,90.1 137.39,90.39 137.54,90.39 137.64,90.29 137.64,89.92 137.7,89.86 137.79,89.86 138.32,90.39 138.32,90.74 138.22,90.85 137.92,90.85 137.7,91.07 137.7,91.54 137.92,91.76 139.13,91.76 139.23,91.86 139.23,92.17 139.07,92.33 137.16,92.33 136.94,92.55 136.94,93.02 137.16,93.25 138.51,93.25 138.97,93.7 138.97,93.97 CC2.1
PCIE_ATX_DRX_N2: length 212.9
  IN2 w0.102: v1(136.94,91.5) 136.3,91.5 136.05,91.75 136.05,91.95
  IN2 w0.127: 136.05,91.95 136.05,93.18 132.15,97.08 132.15,98.67 131.05,99.77 127.12,99.77 122.39,104.5 122.39,105.73 121.83,106.29 121.83,109.1 121.07,109.86 121.07,112.59 114.41,119.25 96.59,119.25 94.44,121.4 82.45,121.4 82,121.86 77.85,121.86 77.48,122.22 71.56,122.22 70.51,121.17 66.94,121.17 65.91,120.14 36.68,120.14 34,117.47 34,99.44 32.64,98.08 32.64,85.31 32.25,84.92 32.25,82.27 33.56,80.96 33.56,77.78 33.78,77.56 33.78,71.89 32.42,70.54 32.42,65.65 36.99,61.09 36.99,51.7 29.2,43.92 29.2,40.85 28.52,40.17 28.52,38.13 28.84,37.81 v1(28.84,37.8)
  BOTTOM w0.102: UC1.B1 136.43,90.71 136.43,90.86 136.49,90.92 136.49,91.33 136.66,91.5 v1(136.94,91.5) ; v1(28.84,37.8) 28.65,37.6 28.65,37.24 CS33.1
PCIE_ATX_DRX_N3: length 208.2
  IN2 w0.102: v1(134.34,91.81) 134.46,91.93 134.46,91.95
  IN2 w0.127: v1(30.9,37.78) 30.72,37.96 30.72,38.21 30.1,38.82 30.1,43.55 37.89,51.33 37.89,61.59 35.86,63.61 35.86,64.88 33.37,67.37 33.37,70.08 35.02,71.73 35.02,78.3 34.88,78.44 34.88,82.58 33.94,83.51 33.94,85.02 33.54,85.42 33.54,91.15 33.74,91.36 33.74,97.52 34.9,98.68 34.9,116.84 37.3,119.24 67.17,119.24 67.37,119.04 73.71,119.04 75.54,120.87 76.84,120.87 77.2,120.51 82.07,120.51 82.08,120.5 94.07,120.5 96.22,118.35 114.04,118.35 119.91,112.47 119.91,109.68 120.86,108.72 120.86,105.98 121.42,105.42 121.42,103.52 125.95,98.99 125.95,98.75 128.38,96.32 131.61,96.32 134.06,93.88 134.06,93.04 134.47,92.63 134.47,91.96 134.46,91.95
  BOTTOM w0.102: CS31.1 31,36.9 30.74,37.16 30.74,37.63 v1(30.9,37.78) ; v1(134.34,91.81) 134.53,91.81 134.77,91.57 134.77,91.11 135.18,90.7 135.18,90.56 UC1.B3
PCIE_ATX_DRX_P0: length 13.2
  BOTTOM w0.102: UC1.D2 136.06,88.95 136.35,88.95 136.41,89.01 137.88,89.01 139.1,90.23 139.1,90.86 140.43,92.2 v3(141.3,92.2) 142.19,92.2 142.41,92.42 142.41,93.04 142.17,93.29 141.28,93.29 141.18,93.39 141.18,93.67 141.25,93.75 142.03,93.75 142.27,93.99 CL13.1
PCIE_ATX_DRX_P1: length 13
  BOTTOM w0.102: UC1.C2 136.08,89.81 136.35,89.53 136.38,89.5 137.72,89.5 138.53,90.3 138.53,90.83 138.31,91.05 138,91.05 137.9,91.15 137.9,91.45 138,91.56 139.22,91.56 139.44,91.78 139.44,92.25 139.15,92.53 137.24,92.53 137.14,92.64 137.14,92.94 137.24,93.04 138.6,93.04 139.18,93.62 139.18,94.57 CC1.1
PCIE_ATX_DRX_P2: length 212.9
  IN2 w0.102: 136.43,91.95 v1(136.5,91.88)
  IN2 w0.127: 136.43,91.95 136.32,92.06 136.32,93.29 132.42,97.19 132.42,98.78 131.16,100.03 127.23,100.03 122.65,104.61 122.65,105.84 122.09,106.4 122.09,109.21 121.33,109.97 121.33,112.7 114.52,119.51 96.7,119.51 94.55,121.66 82.56,121.66 82.11,122.12 77.96,122.12 77.59,122.49 71.45,122.49 70.4,121.44 66.83,121.44 65.8,120.41 36.57,120.41 33.74,117.57 33.74,99.55 32.38,98.19 32.38,85.42 31.99,85.03 31.99,82.16 33.3,80.85 33.3,77.67 33.51,77.45 33.51,72 32.15,70.65 32.15,65.54 36.72,60.98 36.72,51.81 28.94,44.03 28.94,40.96 28.26,40.28 v1(28.26,37.8)
  BOTTOM w0.102: CS34.1 28.44,37.24 28.44,37.61 v1(28.26,37.8) ; UC1.B2 136.22,90.9 136.22,90.94 136.29,91.01 136.29,91.42 136.5,91.63 v1(136.5,91.88)
PCIE_ATX_DRX_P3: length 208.2
  IN2 w0.102: 134.85,91.95 134.85,91.93 134.98,91.81 v1(135.07,91.81)
  IN2 w0.127: v1(30.31,37.78) 30.45,37.92 30.45,38.1 29.84,38.71 29.84,43.66 37.62,51.44 37.62,61.48 35.59,63.5 35.59,64.77 33.11,67.26 33.11,70.19 34.75,71.84 34.75,78.19 34.61,78.33 34.61,82.47 33.68,83.4 33.68,84.91 33.28,85.31 33.28,91.26 33.48,91.47 33.48,97.63 34.64,98.79 34.64,116.95 37.19,119.51 67.27,119.51 67.48,119.31 73.6,119.31 75.43,121.13 76.95,121.13 77.31,120.77 82.18,120.77 82.19,120.76 94.18,120.76 96.33,118.61 114.15,118.61 120.18,112.58 120.18,109.79 121.13,108.83 121.13,106.09 121.69,105.53 121.69,103.63 126.22,99.1 126.22,98.86 128.49,96.59 131.72,96.59 134.33,93.99 134.33,93.15 134.74,92.74 134.74,92.09 134.85,91.97 134.85,91.95
  BOTTOM w0.102: UC1.A3 135.08,91.21 134.98,91.31 134.98,91.72 v1(135.07,91.81) ; CS32.1 30.54,37.24 30.54,37.55 v1(30.31,37.78)
PLT_RST#: length 198.7
  TOP w0.102: v1(38.13,76.72) 37.83,77.02 UE1.13 ; RW3.2 72.13,133.76 72.91,133.76 73.33,133.34 v1(73.33,133.25) ; v1(93.1,42.98) 93.44,43.32 93.44,47.75 94.08,48.38 96.11,48.38 97.38,49.65 98.08,49.65 98.85,48.88 RC112.2 CC21.1 RC66.2 100.31,48.03 RC111.1 ; RL16.2 29.96,91.96 v2(30.6,91.96) v1(33.06,91.96)
  IN1 w0.127: v1(73.33,133.25) 73.02,132.94 67.91,132.94 59.81,124.84 40.42,124.84 34.32,118.74 34.32,99.18 33.06,97.92 v1(33.06,91.96)
  IN2 w0.127: v1(93.1,42.98) 92.95,42.83 89.38,42.83 87.69,41.14 74.47,41.14 74.07,40.75 71.78,40.75 70.28,42.25 70.28,45.99 69.92,46.35 69.92,48 68.89,49.04 68.89,50.61 67.22,52.28 65.57,52.28 57.78,60.06 57.78,73.78 55.4,76.16 52.93,76.16 52.47,76.62 52.47,76.62 51.62,77.47 47.24,77.47 46.79,77.03 38.44,77.03 v1(38.13,76.72)
  BOTTOM w0.102: v1(33.06,91.96) 33.9,91.96 35.31,90.55 35.31,84.59 36.75,83.16 37.91,83.16 40.03,81.03 40.03,79.43 38.13,77.53 v1(38.13,76.72)
PLT_RST#_RW: length 4.1
  TOP w0.102: RW4.1 RW3.1 70.72,133.85 v1(70.33,133.85) 70.29,133.85 70,133.56 v2(70,132.89)
  BOTTOM w0.102: JWLAN1.52 70.7,134.3 70.33,133.93 v1(70.33,133.85)
PM_SLP_S3#: length 207
  TOP w0.102: v1(31.42,79.76) 31.43,79.75 31.91,79.75 31.98,79.81 RE31.1 ; v1(60.04,66.86) v2(59.5,66.86)
  IN1 w0.127: v1(31.42,79.76) 32.7,78.48 33.18,78.48 34.2,77.47 38.64,77.47 39.15,76.96 42.24,76.96 43.7,78.42 46.9,78.42 47.03,78.29 53.55,78.29 54.25,77.59 54.25,73.64 56.05,71.84 56.05,71.36 60.04,67.37 v1(60.04,66.86) ; v1(68.74,58.48) 68.36,58.1 68.36,47.15 72.86,42.65 74.39,42.65 74.48,42.56 95.6,42.56 97.61,40.56 101.05,40.56 101.21,40.72 104.09,40.72 104.96,39.86 117.6,39.86 117.89,40.15 121.22,40.15 121.45,40.38 124.32,40.38 124.72,40.78 128.7,40.78 129.19,41.26 132.4,41.26 132.71,41.57 139.44,41.57 145.35,47.48 145.35,52.11 147.93,54.69 147.93,60.67 151.43,64.17 151.43,68.21 153.89,70.67 153.89,75.81 152.21,77.5 152.21,77.96 152.62,78.37 v1(152.62,78.37)
  IN2 w0.127: v1(68.74,58.48) 68.26,58 62.14,58 59.69,60.44 59.69,66.51 v1(60.04,66.86)
  BOTTOM w0.102: UC1.AC2 136.07,79.04 136.32,79.04 136.4,79.12 136.72,79.12 136.83,79.01 137.8,79.01 138.84,80.05 141.12,80.05 143.03,81.95 146.2,81.95 146.78,82.53 148.62,82.53 149.06,82.08 149.06,81.19 151.88,78.37 v1(152.62,78.37)
PM_SLP_S3#_EC: length 2.7
  TOP w0.102: RE31.2 33.5,79.81 33.69,80.01 v2(34.15,80.01) 34.39,80.01 34.57,79.82 UE1.6
PM_SLP_S5#: length 182.7
  TOP w0.102: v1(127.86,43.05) 127.44,42.63 v2(126.81,42.63) 124.98,42.63 123.61,44 115.98,44 v1(114.99,44.99)
  IN1 w0.102: 139.16,65.28 139.16,65.44 138.81,65.8 138.81,74.4 137.54,75.67 135.89,75.67 135.12,76.43 134.55,76.43 v1(134.16,76.05)
  IN1 w0.127: 139.16,65.28 139.16,57.64 131.92,50.4 131.92,49.65 127.42,45.14 127.42,43.25 127.62,43.05 v1(127.86,43.05)
  IN2 w0.127: v1(114.99,44.99) 114.37,45.61 110.8,45.61 110.57,45.84 107.69,45.84 107.24,46.29 104.11,46.29 103.67,45.84 102.65,45.84 101.85,45.04 89.79,45.04 87.16,42.41 74.41,42.41 73.02,43.81 72.18,43.81 72.08,43.91 71.55,44.44 71.55,46.52 71.19,46.88 71.19,48.53 70.59,49.13 70.59,54.01 70.1,54.5 70.1,58.08 68.87,59.3 64.78,59.3 61.63,62.46 61.63,74.51 61.41,74.73 61.41,80.92 60.42,81.91 60.04,81.91 59.47,81.34 59.47,80.83 58.98,80.34 49.75,80.34 48.78,79.37 47.91,79.37 46.71,80.58 45.44,80.58 41.52,84.49 v1(41.52,84.7) ; v1(125.51,35.68) 125.34,35.85 125.34,35.86 124.81,36.38 124.81,39.68 127.86,42.73 v1(127.86,43.05)
  BOTTOM w0.1: v1(134.16,76.05) 134.22,76.05 134.43,76.26 UC1.AG4
  BOTTOM w0.102: v1(41.52,84.7) 41.52,84.51 41.07,84.07 CE16.1 40.08,83.28 RE35.1 ; R67.2 125.94,35.66 125.54,35.66 v1(125.51,35.68)
PM_SLP_S5#_R: length 3.1
  TOP w0.102: v1(39.92,82.22) 39.48,82.22 39.33,82.36 UE1.123
  BOTTOM w0.102: v1(39.92,82.22) 39.2,82.94 RE35.2
POK: length 241.9
  TOP w0.102: CE17.1 35.5,67.78 37.05,69.33 v1(37.06,69.33) 37.23,69.33 37.73,68.83 UE1.34 ; PR35.1 v1(173.8,56.07) ; v1(42.26,110.68) v2(42.26,111.31)
  IN1 w0.127: v1(42.26,110.68) 42.26,109.73 40.6,108.07 36.55,108.07 36.1,107.63 36.1,97.53 35.28,96.71 35.28,91.67 32.1,88.49 32.1,85.42 31.81,85.13 31.81,81.2 30.98,80.36 30.98,79.4 33.28,77.1 34.34,77.1 38.27,73.16 38.27,70.94 37.06,69.73 v1(37.06,69.33) ; v1(173.8,56.07) 173.42,55.68 170.98,55.68 162.12,46.82 150.3,46.82 149.12,45.64 149.12,43.77 142.83,37.49 137.26,37.49 136.63,36.85 125.44,36.85 124.97,36.38 120.14,36.38 119.31,35.56 117.19,35.56 116.71,36.04 111.58,36.04 111.41,35.87 105.66,35.87 105.49,35.7 104.42,35.7 103.53,36.58 93.18,36.58 90.1,39.65 71.16,39.65 68.93,41.88 68.93,42.09 66.96,44.06 65.67,45.36 v1(65.07,45.36)
  IN2 w0.127: v1(65.07,45.36) 64.46,45.97 62.9,45.97 49.37,59.49 49.37,66.73 48.17,67.94 38.87,67.94 37.49,69.33 v1(37.06,69.33)
  IN2 w0.254: v1(52.93,110.85) 52.93,110.37 51.48,108.92 44.02,108.92 v1(42.26,110.68)
  BOTTOM w0.254: PU301.9 51.35,109.66 52.29,110.61 PR304.2 52.4,110.85 v1(52.93,110.85) ; v1(42.26,110.68) 42.22,110.64 PR504.2 41.31,109.08 PU501.9
PROG: length 2.2
  BOTTOM w0.203: PUB01.19 194.7,52.98 v2(194.62,53.06) 194.62,53.98 PRB17.2
PROH: length 5.8
  TOP w0.254: v1(197.07,52.95) 196.93,52.81 196.58,52.81 v2(196.51,52.88) 196.36,53.04 PQB33.2 196.36,54.33 196.02,54.67 PRB44.2
  BOTTOM w0.203: PUB01.23 196.3,52.37 196.88,52.95 v1(197.07,52.95) 197.1,52.95 197.85,53.7 PRB21.2
PS_ID: length 131.4
  TOP w0.102: UE1.16 36.61,75.82 36.62,75.82 37.24,75.82 37.31,75.75 v1(38.32,75.75)
  TOP w0.254: v1(82.59,141.04) 82.6,141.05 83.01,141.05 84.19,142.23 v2(84.19,146.27) 84.19,146.89 83.72,147.36 83.28,147.36 82.44,148.2 PR5.1 81.91,148.57 PD2.1 80.61,148.18 80.23,148.57 PR1.2
  IN1 w0.127: v1(82.59,141.04) 77.82,136.27 77.08,136.27 75.66,134.85 75.66,132.05 74.58,130.97 72.44,130.97 70.5,129.02 70.5,116.54 69.91,115.95 69.91,114.03 70.24,113.7 70.24,92.28 65.05,87.08 65.05,86.49 62.64,84.08 57.32,84.08 51.58,89.82 48.5,89.82 48.14,89.47 45.88,89.47 45.18,90.17 39.59,90.17 39.09,90.67 35.54,90.67 v1(34.71,89.83)
  BOTTOM w0.102: v1(38.32,75.75) 37.73,76.35 37.73,77.57 39.83,79.67 39.83,80.95 37.82,82.95 36.66,82.95 35.11,84.5 35.11,89.43 v1(34.71,89.83)
PSID: length 10.2
  TOP w0.254: PL3.1 76.93,143.32 v2(77.37,142.88) 77.65,142.6 v1(77.81,142.6)
  BOTTOM w0.254: v1(77.81,142.6) 84.68,142.6 85.2,143.12 PJPDC1.3
PSID-1: length 4.2
  TOP w0.102: PQ2.2 80.72,145.13 81.14,145.55 v2(81.44,145.55)
  TOP w0.254: PR3.2 PR6.1 79.86,145.45 PQ2.2
PSID-2: length 10
  TOP w0.102: v2(73.12,147.11) PQ1.1
  TOP w0.254: PR3.1 78.45,147.74 77.81,147.11 PQ1.1 74.93,146.31 75.9,145.34 PD1.2 75.92,144.61 PL3.2
PSID-3: length 3.1
  TOP w0.102: v2(78.94,149.56) PR1.1
  TOP w0.254: PR1.1 77.51,148.57 PQ1.3
PSID-4: length 8
  TOP w0.102: PQ2.1 v2(79.53,142.07)
  TOP w0.254: PR4.2 81.16,143.62 PR7.1 80.2,142.92 79.88,143.23 PQ2.1 78.13,143.23 77.62,143.74 77.62,145.53 PQ1.2
PSID-5: length 2.9
  TOP w0.102: PR7.2 81.38,142.07 v2(81.52,141.93)
  TOP w0.254: PR7.2 81.72,143.26 82.64,143.26 PD3.1
PTP_DIS#: length 136
  TOP w0.102: v1(38.19,74.8) 37.12,74.8 36.94,74.62 UE1.19 ; v1(128.48,33.04) 128.64,33.04 v4(129.12,32.56)
  IN1 w0.127: v1(52.61,75.88) 53.23,75.26 53.23,73.22 54.08,72.37 54.08,70.02 56.17,67.94 56.17,66.8 59.86,63.11 59.86,54.14 62.06,51.93 62.06,44.1 63.11,43.05 63.48,43.05 65.88,40.65 66.32,40.65 69.66,37.31 88.75,37.31 92.77,33.28 108.87,33.28 109.2,32.95 119.5,32.95 119.75,32.7 122.45,32.7 122.99,33.24 126.13,33.24 126.81,33.92 127.63,33.92 128.48,33.07 v1(128.48,33.04)
  IN2 w0.127: v1(52.61,75.88) 52.61,75.92 51.31,77.22 47.34,77.22 46.89,76.77 40.84,76.77 38.87,74.8 v1(38.19,74.8)
  BOTTOM w0.102: R23.2 129.42,32.84 128.67,32.84 v1(128.48,33.04) 128.48,32.9 125.1,29.52 123.35,29.52 123.05,29.82 JTP1.3
QPCN_CHG:
  vias: v2(194.19,46.46)
QPCP_CHG:
  vias: v2(195.55,46.27)
REGOUT:
  vias: v2(20.48,89.2)
RESERVE_2: length 8.5
  BOTTOM w0.102: RC56.1 120.83,62.12 v2(120.28,62.67) 120.11,62.84 120.11,63.86 120.95,64.71 RC61.2 121.15,64.91 121.15,68.73 120.83,69.04 UC1.AY29
RING2: length 10.2
  BOTTOM w1.016: 31.34,17.39 31.26,17.47 24.37,17.47 23.28,16.38 23.28,16.25 22.23,15.2
  vias: v1(21.05,15.24) v1(21.05,14.66) v1(32.77,17) v1(32.77,16.42)
RING2_R: length 24.8
  IN1 w1.016: JHP1.4 6.02,6.73 14.13,6.73 15.73,8.32 15.73,10.46 15.27,10.92 15.27,14.54 16.99,16.25 19.27,16.25 20.42,17.39
  vias: v1(21.14,18.66) v1(21.14,18.03) v4(23.58,17.66)
RJ45_MDIN0: length 9.8
  TOP w0.267: TL1.2 16.24,71.86 15.8,72.3 15.29,72.3 14.97,72.63 14.97,75.51 15.22,75.76 15.22,77.29 14.66,77.86 14.15,77.86 13.85,77.56 13.85,76.9 JLAN1.2
RJ45_MDIN1: length 17
  TOP w0.267: v1(13.57,68.13) 13.67,68.03 v3(13.67,66.38) 13.67,65.29 14.37,64.59 16.11,64.59 16.46,64.24 TL1.8
  IN1 w0.178: v1(13.57,68.13) 13.67,68.23 13.67,68.86 15.02,70.21 15.02,71.74 15.6,72.32 15.6,74.67 15.53,74.75 15.36,74.75 14.05,73.44 JLAN1.6
RJ45_MDIN2: length 5.2
  BOTTOM w0.267: TL2.7 16.71,71.86 16.38,72.19 15.75,72.19 15.1,72.85 15.1,73.45 14.91,73.64 JLAN1.5
RJ45_MDIN3: length 10.6
  BOTTOM w0.267: TL2.1 16.32,64.24 15.59,64.97 15.03,64.97 14.64,65.36 v3(14.64,65.95) 14.64,68.92 15.02,69.3 15.02,70.91 14.61,71.32 14.07,71.32 13.88,71.13 13.88,70.75 JLAN1.8
RJ45_MDIP0: length 9.9
  TOP w0.267: JLAN1.1 13.47,77.72 13.99,78.24 14.82,78.24 15.6,77.45 v3(15.6,76.72) 15.6,75.61 15.35,75.35 15.35,72.8 15.47,72.69 15.89,72.69 16.34,73.13 TL1.1
RJ45_MDIP1: length 17
  TOP w0.267: v1(14.15,68.13) 14.05,68.03 14.05,65.45 14.5,65 15.7,65 16.21,65.51 TL1.7
  IN1 w0.178: v1(14.15,68.13) 13.97,68.31 13.97,68.74 15.32,70.09 15.32,71.61 15.91,72.19 15.91,74.8 15.66,75.05 15.21,75.05 14.58,75.68 JLAN1.3
RJ45_MDIP2: length 5.1
  BOTTOM w0.267: TL2.8 16.7,73.13 16.15,72.58 15.91,72.58 15.48,73.01 15.48,73.61 15.07,74.02 13.98,74.02 13.76,74.24 13.76,74.48 13.94,74.66 JLAN1.4
RJ45_MDIP3: length 10.6
  BOTTOM w0.267: TL2.2 15.99,65.51 15.83,65.35 15.2,65.35 15.02,65.53 15.02,68.77 15.4,69.15 15.4,71.06 14.77,71.7 13.91,71.7 13.81,71.6 JLAN1.7
RTC_CLK: length 16.2
  TOP w0.102: v1(134.92,72.71) 135,72.63 v2(139.4,72.63) 142.7,72.63 143.8,71.53 144.05,71.53 144.25,71.32 144.25,70.42 144.46,70.21 145.06,70.21 145.26,70.4 145.26,70.9 RC80.2 147.08,71.35 RC91.1 147.98,71.36 RC62.1
  BOTTOM w0.1: UC1.AN4 134.92,72.81 v1(134.92,72.71)
RTC_DET#: length 23.8
  TOP w0.102: QC3.1 149.83,81.89 v2(149.83,79.61) 149.83,78.54 148.68,77.4 147.4,77.4 147.04,77.75 145.56,77.75 RC70.2 144.39,76.58 142.8,76.58 141.81,77.57 141.47,77.57 141.31,77.4 136.79,77.4 136.17,76.78 133.39,76.78 132.65,76.04 v1(132.62,76.04)
  BOTTOM w0.102: v1(132.62,76.04) 132.59,76.07 132.57,76.07 UC1.AG8
RTC_DIS: length 9.5
  TOP w0.102: v2(40.14,61.45) v1(39.35,61.45) 38.97,61.07 QE1.2 ; UE1.36 38.53,66.8 v1(38.31,66.57)
  IN1 w0.127: v1(38.31,66.57) 38.31,66.31 38.83,65.78 38.83,64.38 39.35,63.87 v1(39.35,61.45)
  BOTTOM w0.102: v1(38.31,66.57) 38.32,66.59 RE29.1
S5_MUX_CTRL: length 78.8
  TOP w0.102: v1(141.64,78.54) 141.51,78.54 141.19,78.86 133,78.86 132.55,79.31 v1(132.45,79.31)
  IN1 w0.102: 139.88,72.02 139.8,71.94 139.8,66.91 139.88,66.83
  IN1 w0.127: v1(129.54,45.95) 130.06,45.95 132.69,48.57 132.69,50.08 140.12,57.51 140.12,66.59 139.88,66.83 ; 139.88,72.02 142.4,74.54 142.4,77.97 141.83,78.54 v1(141.64,78.54)
  BOTTOM w0.102: v1(132.45,79.31) 132.45,79.52 UC1.AA7 ; Q15.5 R65.2 R57.1 117.3,36.68 116.67,36.05 113.71,36.05 113.45,36.32 113.45,37.84 114.21,38.6 114.21,39.56 115.99,41.33 v2(117.55,41.33) 119.22,41.33 120.11,40.44 121.13,40.44 121.57,40.89 121.57,41.97 122.08,42.48 123.44,42.48 124.75,43.79 124.75,44.13 124.96,44.34 125.68,44.34 126.68,45.33 128.37,45.33 128.81,45.77 129.36,45.77 v1(129.54,45.95)
SATA_ACT#: length 338.6
  TOP w0.102: RC104.2 v1(120.42,65.7)
  IN1 w0.127: v1(18.68,119.57) 19.55,118.69 26.63,118.69 33.31,112.01 33.31,99.75 32.81,99.25 32.81,93.11 32.04,92.34 32.04,89.15 31.59,88.7 31.59,85.63 31.3,85.34 31.3,81.41 30.47,80.57 30.47,79.18 33.06,76.59 34.13,76.59 37.77,72.95 37.77,71.28 36.29,69.8 36.29,65.13 38.07,63.35 38.07,60.94 45.29,53.71 45.29,38.68 45.69,38.29 45.69,37.18 43.87,35.36 43.87,32.04 v1(43.82,32) ; v1(73.76,128.65) 73.27,128.65 71.77,127.14 71.77,91.65 69.03,88.91 69.03,83.89 68.54,83.4 67.41,83.4 66.11,84.69 65.4,84.69 64.51,83.8 64.51,82.1 66.39,80.22 66.39,64.55 68.34,62.61 v1(68.42,62.61)
  IN2 w0.127: v1(120.42,65.7) 120.22,65.49 120.22,64.73 118.56,63.07 118.56,57.46 115.89,54.8 112.62,54.8 106.84,49.02 102.65,49.02 99.44,45.8 89.47,45.8 86.84,43.18 76.11,43.18 76.04,43.24 74.67,43.24 73.22,44.68 73.22,45.13 72.36,45.99 72.36,46.79 71.96,47.19 71.96,48.84 71.35,49.45 71.35,54.33 70.86,54.82 70.86,60.68 68.93,62.61 v1(68.42,62.61) ; v1(73.76,128.65) 69.38,128.65 62.39,128.65 61.38,127.63 25.37,127.63 18.68,120.94 v1(18.68,119.57)
  BOTTOM w0.102: UC1.AY30 120.28,69.4 120.6,69.09 120.6,68.84 120.48,68.73 120.48,68.27 120.52,68.24 120.52,68.24 120.55,68.2 120.55,65.82 120.45,65.72 120.45,65.72 v1(120.42,65.7) ; v1(43.82,32) 43.82,31.97 43.79,31.94 43.79,29.36 44.13,29.01 44.13,27.69 44.48,27.34 44.48,26.3 44.03,25.84 RS27.2 ; R44.1 19.3,120.15 18.72,119.57 v1(18.68,119.57) Q14.2
SATA_ACT#_R: length 7.6
  BOTTOM w0.102: Q12.3 20.33,120.68 20.33,119.88 19.68,119.24 R44.2 18.97,118.61 18.32,118.61 18.02,118.92 Q14.3 17.87,118.31 R49.2 v2(19.67,117.79)
SATA_ARX_C_DTX_N0: length 4.4
  BOTTOM w0.102: CS10.2 188.88,38.54 188.68,38.33 188.68,38.19 188.85,38.02 188.85,37.87 188.68,37.7 188.51,37.7 188.35,37.86 188.21,37.86 187.95,37.6 v3(187.95,37.1) 187.95,36.43 188.2,36.17 JHDD1.5
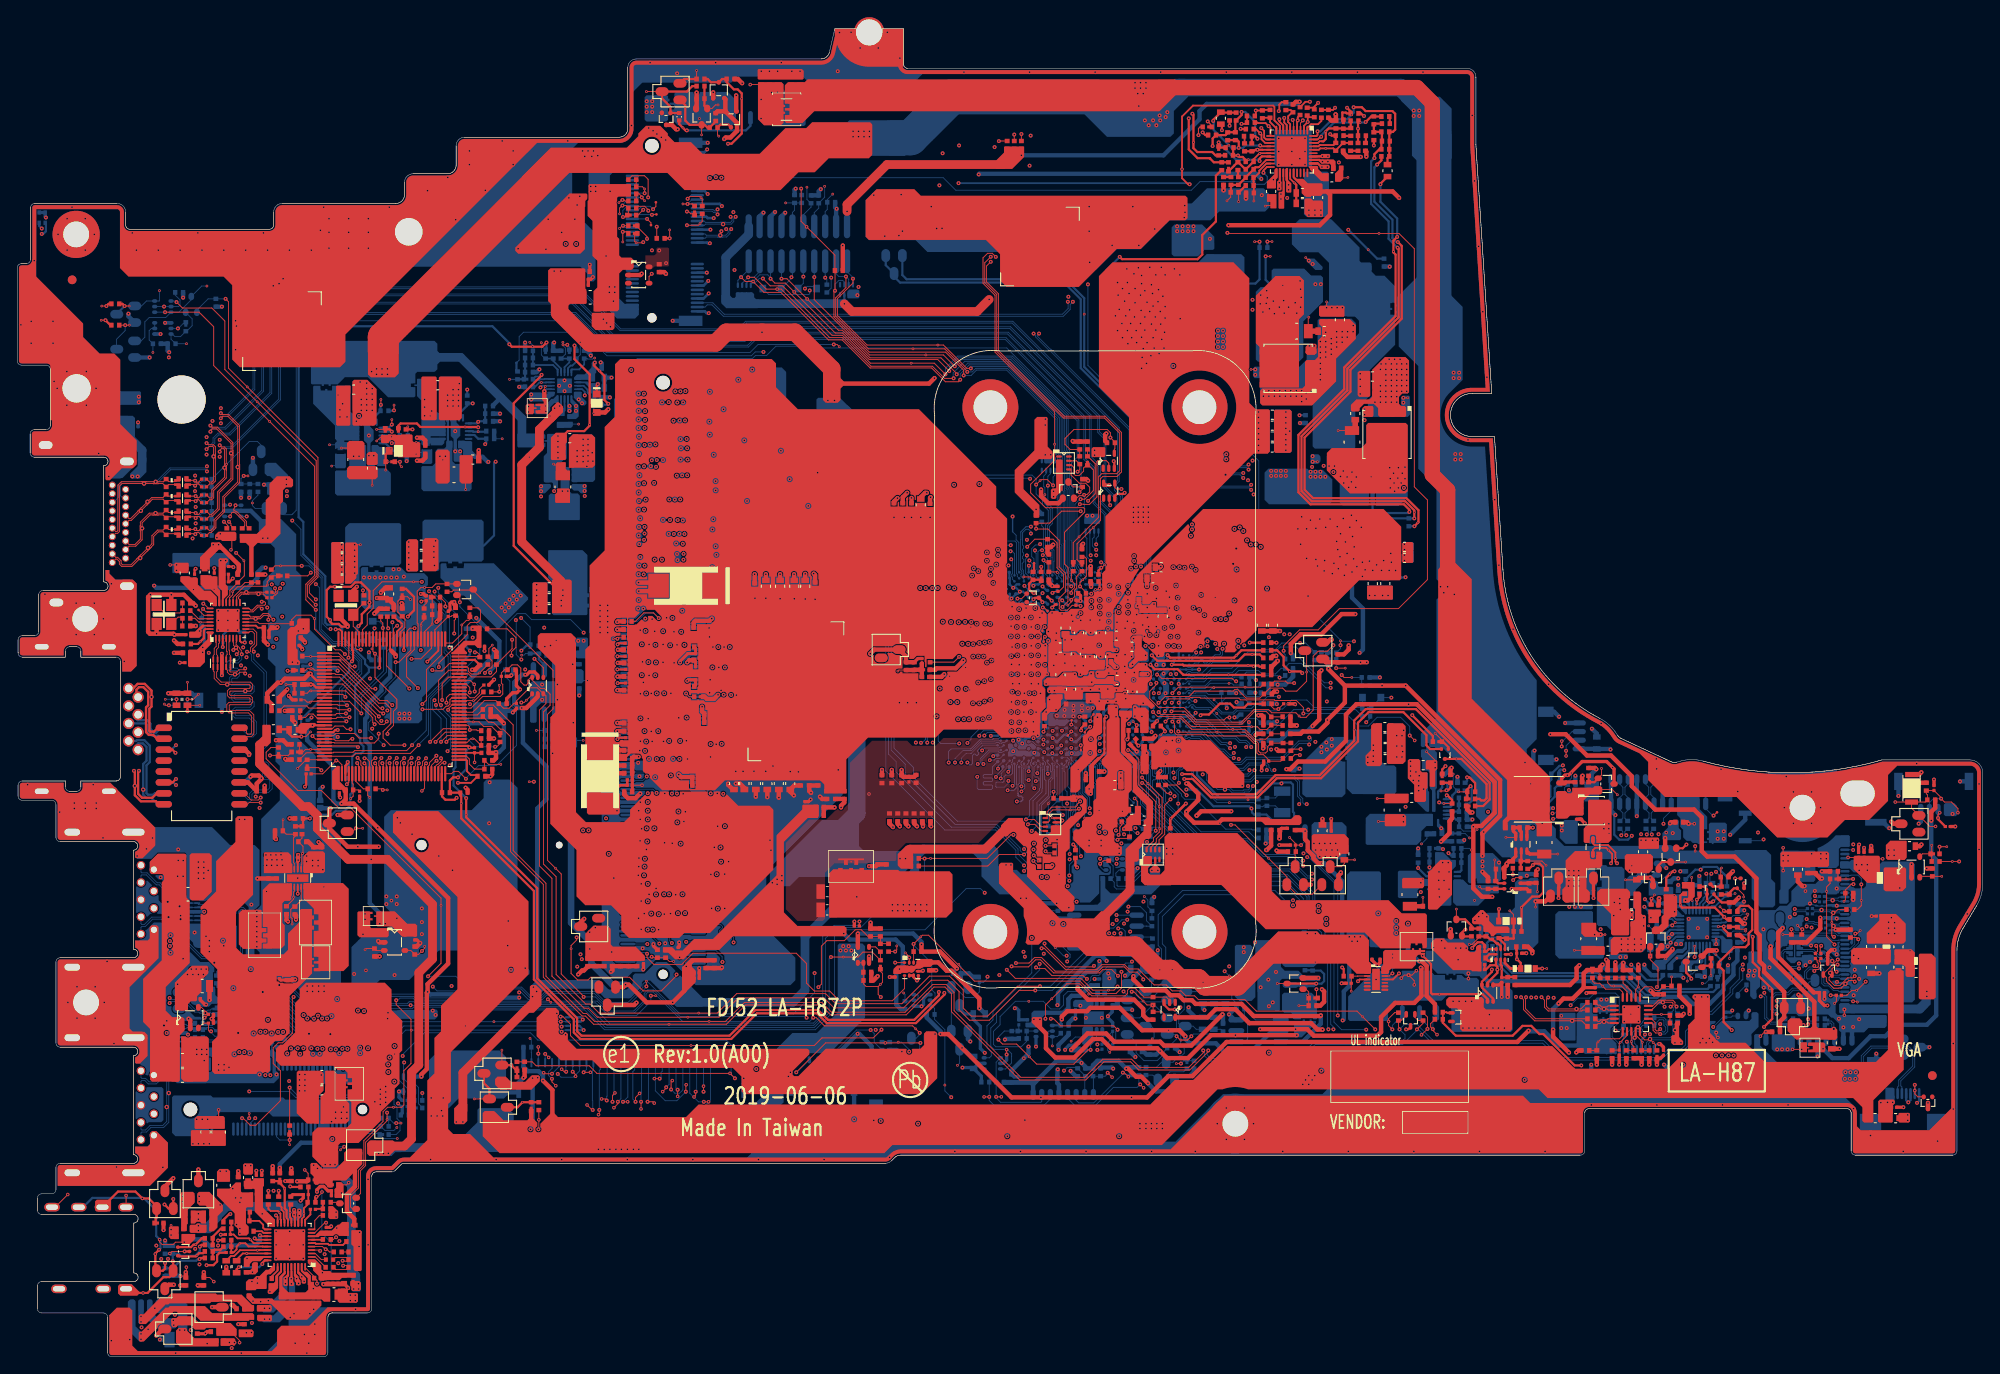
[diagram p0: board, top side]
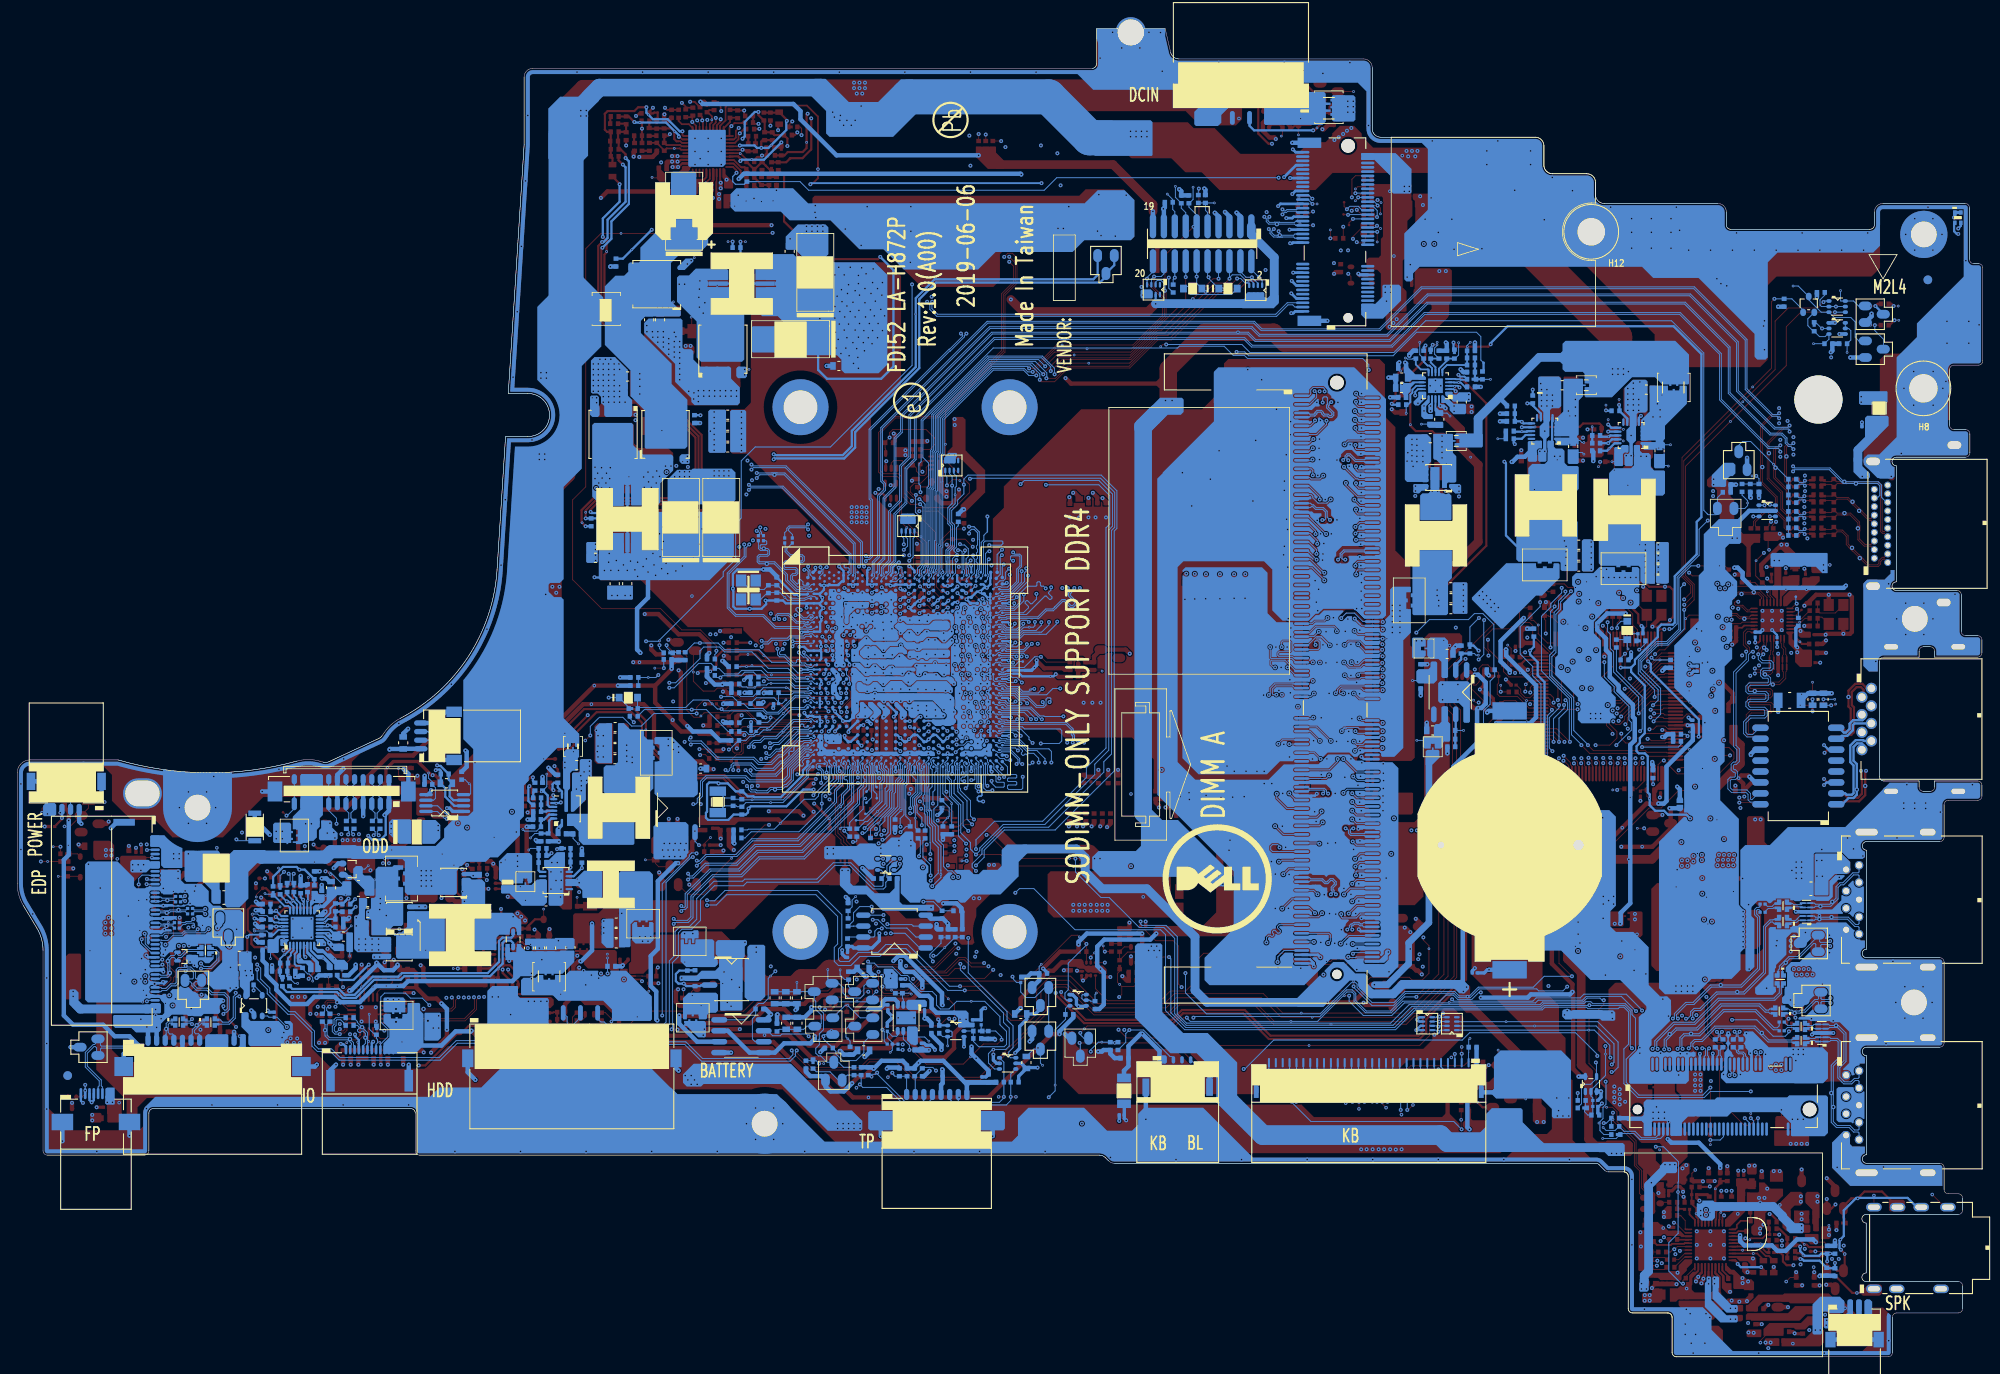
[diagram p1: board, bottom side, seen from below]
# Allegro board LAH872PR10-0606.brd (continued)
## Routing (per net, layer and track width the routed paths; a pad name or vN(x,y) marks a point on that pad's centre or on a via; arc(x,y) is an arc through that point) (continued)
SATA_ARX_C_DTX_N1: length 5.5
  BOTTOM w0.102: CS17.2 189.62,62.66 189.62,63.23 189.2,63.65 JODD1.9 189.2,64.99 189.58,65.38 189.58,66.23 189.2,66.61 JODD1.10
SATA_ARX_C_DTX_P0: length 4.4
  BOTTOM w0.102: JHDD1.6 187.7,36.19 187.71,36.2 187.71,37.7 v3(188.33,38.32) 188.88,38.88 188.88,39 CS9.2
SATA_ARX_C_DTX_P1: length 5.4
  BOTTOM w0.102: CS16.2 189.87,62.58 189.87,63.23 190.2,63.56 JODD1.11 190.2,64.99 189.82,65.38 189.82,66.23 190.2,66.61 JODD1.12
SATA_ARX_C_RD_DTX_N0: length 2.5
  TOP w0.102: US1.4 184.87,39.31 184.74,39.18 184.03,39.18 183.83,38.98 183.7,38.98 CS6.2
SATA_ARX_C_RD_DTX_P0: length 2.5
  TOP w0.102: US1.5 184.87,38.81 184.74,38.94 v3(184.39,38.94) 184.13,38.94 183.92,38.74 183.7,38.74 CS5.2
SATA_ARX_DTX_N0: length 71.9
  TOP w0.102: CS6.1 176.44,39.3 175.26,40.48 175.26,41.74 v1(175.33,41.81)
  IN2 w0.127: v1(152.12,50.92) 152.24,50.79 152.64,50.79 153.7,49.73 153.7,47.05 157.74,43.01 174.31,43.01 175.13,42.19 175.13,42 v1(175.33,41.81)
  BOTTOM w0.102: v1(152.12,50.92) 151.94,50.74 150.52,50.74 150.11,51.15 150.11,53.56 147.62,56.05 144.29,56.05 142.22,58.13 137.02,58.13 130.77,64.37 130.77,65.98 130.33,66.42 130.33,68.23 130.41,68.31 130.41,68.74 130.49,68.81 130.49,69.08 130.12,69.45 130.12,69.59 UC1.AY12
SATA_ARX_DTX_N1: length 82
  IN2 w0.127: v1(149.43,57.1) 149.55,57.21 150.21,57.21 150.79,56.64 152.08,56.64 152.88,55.84 152.88,54.54 155.86,51.56 156.87,51.56 157.85,50.58 158.94,50.58 159.45,51.09 165.97,51.09 168.63,53.75 168.63,59.53 174.51,65.4 178.79,65.4 179.43,64.77 186.89,64.77 189.59,62.07 189.59,60.96 v1(189.36,60.73)
  BOTTOM w0.102: UC1.BA8 132.39,68.96 132.39,69.17 132.29,69.27 132.22,69.27 132.04,69.09 132.04,68.86 132.19,68.72 132.19,67.87 132.52,67.54 132.52,66.48 133.2,65.79 133.2,64.45 137.66,59.99 142.96,59.99 144.79,58.16 148.29,58.16 149.1,57.35 149.18,57.35 v1(149.43,57.1) ; v1(189.36,60.73) 189.36,60.78 189.54,60.97 189.54,61.11 CS17.1
SATA_ARX_DTX_P0: length 71.9
  TOP w0.102: CS5.1 181.81,39.06 v3(180.68,39.06) 176.34,39.06 175.02,40.38 175.02,41.53 v1(174.74,41.81)
  IN2 w0.127: v1(152.12,50.33) 152.26,50.48 152.51,50.48 153.39,49.6 153.39,46.92 157.61,42.7 174.18,42.7 174.82,42.06 174.82,41.88 v1(174.74,41.81)
  BOTTOM w0.102: UC1.BA12 130.18,68.95 130.18,68.41 130.09,68.33 130.09,68.12 129.9,67.93 129.9,67.72 130.09,67.52 130.09,67.31 129.9,67.12 129.9,66.9 130.09,66.71 130.09,66.32 130.53,65.88 130.53,64.27 136.92,57.89 142.12,57.89 144.2,55.81 147.52,55.81 149.87,53.46 149.87,51.05 150.42,50.51 151.94,50.51 v1(152.12,50.33)
SATA_ARX_DTX_P1: length 82
  IN2 w0.127: v1(149.43,57.68) 149.59,57.53 150.34,57.53 150.92,56.95 152.21,56.95 153.19,55.97 153.19,54.67 155.99,51.87 157,51.87 157.98,50.89 158.81,50.89 159.33,51.4 165.84,51.4 168.32,53.88 168.32,59.65 174.38,65.71 178.92,65.71 179.56,65.08 187.02,65.08 189.9,62.2 189.9,60.77 v1(189.94,60.73)
  BOTTOM w0.102: v1(189.94,60.73) 189.94,60.83 189.84,60.93 189.84,61.07 CS16.1 ; UC1.AY8 132.63,69.41 132.63,69.14 132.69,69.08 132.69,68.8 132.43,68.53 132.43,67.97 132.75,67.64 132.75,66.57 133.44,65.89 133.44,64.55 137.76,60.23 143.06,60.23 144.89,58.4 148.39,58.4 149.2,57.59 149.34,57.59 v1(149.43,57.68)
SATA_ARX_RD_DTX_N0: length 6.2
  TOP w0.102: v1(190.92,38.11) 190.7,37.89 190.49,37.89 190.33,38.05 190.33,38.87 189.89,39.31 US1.12
  BOTTOM w0.102: v1(190.92,38.11) 191.26,37.76 191.38,37.76 191.55,37.93 191.55,38.33 191.35,38.53 191.35,39.1 191.26,39.19 190.8,39.19 190.47,38.86 190.47,38.64 190.37,38.54 CS10.1
SATA_ARX_RD_DTX_P0: length 6.2
  TOP w0.102: v1(190.92,37.52) 190.79,37.65 190.39,37.65 190.09,37.96 190.09,38.6 189.88,38.81 US1.11
  BOTTOM w0.102: v1(190.92,37.52) 191.48,37.52 191.79,37.83 191.79,38.43 191.59,38.63 191.59,39.2 191.36,39.43 CS9.1
SATA_ATX_C_DRX_N0: length 6
  BOTTOM w0.102: JHDD1.3 189.2,36.13 189.33,36.26 189.33,36.54 v3(189.73,36.94) 189.88,37.09 192.07,37.09 192.39,37.41 192.39,38.64 CS8.2
SATA_ATX_C_DRX_N1: length 5.4
  BOTTOM w0.102: CS15.2 186.82,62.61 186.82,63.22 187.2,63.61 JODD1.5 187.2,64.99 186.82,65.38 186.82,66.23 187.2,66.61 JODD1.6
SATA_ATX_C_DRX_P0: length 6
  BOTTOM w0.102: JHDD1.2 189.7,36.14 189.57,36.27 189.57,36.44 189.98,36.85 192.17,36.85 192.63,37.31 v3(192.63,37.98) 192.63,38.65 CS7.2
SATA_ATX_C_DRX_P1: length 5.5
  BOTTOM w0.102: CS14.2 186.58,62.64 186.58,63.22 186.2,63.61 JODD1.3 186.2,64.99 186.58,65.38 186.58,66.23 186.2,66.61 JODD1.4
SATA_ATX_C_RD_DRX_N0: length 2.5
  TOP w0.102: US1.2 184.87,40.31 184.74,40.44 v3(184.39,40.44) 184.01,40.44 183.81,40.64 183.7,40.64 CS4.2
SATA_ATX_C_RD_DRX_P0: length 2.5
  TOP w0.102: CS3.2 183.7,40.88 183.91,40.88 184.11,40.68 184.74,40.68 184.87,40.81 US1.1
SATA_ATX_DRX_N0: length 74.3
  TOP w0.102: CS4.1 181.91,40.32 181.79,40.21 177.9,40.21 177.47,40.64 177.47,41.46 v1(177.12,41.81)
  IN2 w0.127: v1(151.23,51.83) 151.11,51.94 150.21,51.94 149.47,51.2 149.47,48.87 153.48,44.86 153.79,44.86 156.59,42.07 170.88,42.07 171.81,41.14 177.19,41.14 177.39,41.33 177.39,41.54 v1(177.12,41.81)
  BOTTOM w0.102: v1(151.23,51.83) 151.05,52 150.79,52 150.54,52.24 150.54,53.74 147.8,56.48 144.48,56.48 142.31,58.65 137.1,58.65 131.2,64.55 131.2,66.51 131.24,66.55 131.24,68 131.05,68.2 131.05,68.74 130.98,68.82 130.98,69.1 131.28,69.4 UC1.AY10
SATA_ATX_DRX_N1: length 80.7
  IN2 w0.127: v1(150.45,56.17) 150.45,56.07 150.58,55.94 151.75,55.94 152.24,55.45 152.24,54.23 155.61,50.86 156.67,50.86 158.68,48.85 160.9,48.85 162.34,50.29 166.06,50.29 169.27,53.49 169.27,59.26 174.64,64.64 178.66,64.64 179.16,64.13 185.6,64.13 186.78,62.95 186.78,60.84 186.98,60.65 v1(186.98,60.64)
  BOTTOM w0.102: v1(150.45,56.17) 150.45,56.08 150.27,55.91 149.93,55.91 148.44,57.39 144.86,57.39 142.69,59.56 137.48,59.56 132.62,64.42 132.62,65.38 131.92,66.07 131.92,66.99 132.02,67.09 132.21,67.09 132.31,67.19 132.31,67.38 132.21,67.49 132.02,67.49 131.92,67.59 131.92,68.36 131.83,68.45 UC1.BA9 ; CS15.1 186.81,61.06 186.81,60.81 v1(186.98,60.64)
SATA_ATX_DRX_P0: length 74.3
  TOP w0.102: v1(177.9,41.78) 177.71,41.59 177.71,40.74 178,40.44 v3(181.19,40.44) 181.69,40.44 CS3.1
  IN2 w0.127: v1(177.9,41.78) 177.7,41.58 177.7,41.2 177.32,40.83 171.68,40.83 170.75,41.75 156.46,41.75 153.66,44.55 153.35,44.55 149.16,48.74 149.16,51.33 150.08,52.26 151.07,52.26 v1(151.23,52.41)
  BOTTOM w0.102: v1(151.23,52.41) 151.05,52.24 150.88,52.24 150.78,52.34 150.78,53.84 147.9,56.72 144.58,56.72 142.41,58.89 137.2,58.89 131.44,64.65 131.44,66.41 131.48,66.45 131.48,68.1 131.29,68.3 131.29,68.95 UC1.BA10
SATA_ATX_DRX_P1: length 80.6
  IN2 w0.127: v1(150.45,55.49) 150.45,55.49 150.58,55.63 151.62,55.63 151.93,55.33 151.93,54.1 155.48,50.55 156.54,50.55 158.55,48.54 161.03,48.54 162.47,49.98 166.19,49.98 169.58,53.36 169.58,59.13 174.77,64.33 178.53,64.33 179.03,63.82 185.47,63.82 186.47,62.82 186.47,60.71 v1(186.39,60.64)
  BOTTOM w0.102: UC1.AY9 131.66,69.14 131.66,68.88 131.53,68.75 131.53,68.37 131.68,68.22 131.68,65.97 132.38,65.28 132.38,64.32 137.38,59.32 142.59,59.32 144.76,57.15 148.35,57.15 149.83,55.67 150.27,55.67 150.44,55.49 v1(150.45,55.49) ; CS14.1 186.57,61.06 186.57,60.81 v1(186.39,60.64)
SATA_ATX_RD_DRX_N0: length 5.1
  TOP w0.102: v1(192.12,40.71) 192.25,40.71 192.39,40.84 192.39,41.12 192.29,41.22 v3(191.22,41.22) 190.82,41.22 190.04,40.44 190.02,40.44 189.89,40.31 US1.14
  BOTTOM w0.102: CS8.1 192.44,40.26 192.44,40.56 192.29,40.71 v1(192.12,40.71)
SATA_ATX_RD_DRX_P0: length 5.1
  TOP w0.102: US1.15 189.85,40.81 189.89,40.77 190.03,40.77 190.72,41.46 192.39,41.46 192.63,41.22 192.63,40.9 v1(192.81,40.72)
  BOTTOM w0.102: CS7.1 192.68,40.16 192.68,40.58 v1(192.81,40.72)
SATA_EN: length 3.4
  TOP w0.102: RS9.2 185.35,35.66 CS35.1 186.15,36.44 v2(186.28,36.57) 187.06,37.35 US1.7
SATA_ODD_PRSNT#: length 248.1
  TOP w0.102: UE1.101 48.13,82.38 46.9,81.15 v1(45.82,81.15) ; v1(161.81,72.24) v4(162.39,71.66) ; RC44.2 43.01,84.81 v1(43.11,84.7) ; v1(127.91,44.29) 127.18,45.02 126.15,45.02 125.76,44.64 120.43,44.64 118.91,46.16 118.33,46.16 117.51,45.33 115.62,45.33 115.55,45.4 v1(115.54,45.4) ; v1(149.45,74.8) 149.45,75.5 148.64,76.3 146.16,76.3 146.09,76.38 142.15,76.38 141.96,76.58 137.51,76.58 137.42,76.67 136.35,76.67 136.17,76.49 133.81,76.49 v1(133.36,76.05)
  IN1 w0.102: v1(133.36,76.05) 133.36,76.5 133.5,76.64 135.21,76.64 135.98,75.87 137.63,75.87 139.01,74.48 139.01,65.88 139.54,65.35 139.54,65.28
  IN1 w0.127: 139.54,65.28 139.54,57.66 132.18,50.29 132.18,49.55 127.81,45.18 127.81,44.39 v1(127.91,44.29) ; v1(161.81,72.24) 175.24,72.24 177.26,70.21 177.26,70.11 177.4,69.97 179.95,69.97 181.48,68.44 181.48,67.39 184.89,63.98 189.42,63.98 191.3,62.1 v1(191.3,61.97)
  IN2 w0.127: v1(43.11,84.7) 43.11,83.37 45.33,81.15 v1(45.82,81.15) 46.07,80.89 46.83,80.89 47.41,80.32 47.91,80.32 48.23,80.64 58.84,80.64 59.15,80.96 59.15,81.47 59.91,82.23 60.49,82.23 61.72,81 61.72,74.79 62.73,73.77 62.73,61.71 64.89,59.56 68.97,59.56 70.35,58.18 70.35,54.6 70.84,54.11 70.84,49.24 71.45,48.63 71.45,46.98 71.8,46.63 71.8,44.55 72.29,44.06 73.12,44.06 74.52,42.67 87.05,42.67 89.68,45.3 100.64,45.3 101.6,46.25 102.42,46.25 103.03,46.86 107.16,46.86 107.92,46.1 110.67,46.1 110.91,45.86 115.07,45.86 v1(115.54,45.4)
  BOTTOM w0.102: v1(133.36,76.05) 133.63,76.32 UC1.AG5 ; v1(149.45,74.8) 154.4,74.8 155.86,73.34 157.01,73.34 158.02,74.35 160.75,74.35 161.81,73.3 v1(161.81,72.24) ; JODD1.16 JODD1.15 192.2,63.51 191.3,62.61 v1(191.3,61.97)
SATA_ZVDD: length 2
  TOP w0.102: v1(130.09,73.44) 130.07,73.44 v2(129.66,73.85)
  TOP w0.254: RC103.1 130.05,73.4 v1(130.09,73.44)
  BOTTOM w0.254: UC1.AP11 130.4,73.44 v1(130.09,73.44)
SATA_ZVSS: length 1.6
  TOP w0.254: v1(130.29,71.06) 129.98,71.37 RC102.1
  BOTTOM w0.254: v1(130.29,71.06) 130.35,71.06 130.73,71.43 UC1.AU11
SCL_CHG: length 2.6
  BOTTOM w0.203: PRB20.2 197.04,53.74 v2(196.36,53.06) 195.9,52.6 PUB01.22
SDA_CHG: length 2.4
  BOTTOM w0.203: PUB01.21 195.5,52.7 195.94,53.14 195.94,53.32 196.25,53.63 PRB19.2
SERIRQ: length 143.8
  TOP w0.102: v1(43.58,75.77) 43.52,75.77 43,76.3 42.14,76.3 37.41,81.02 UE1.3
  IN1 w0.127: v1(119.29,46.86) 119.54,46.86 122.84,50.16 122.84,52.45 122.83,52.46 122.83,52.49 122.47,52.85 122.44,52.85 121.26,54.03 121.26,58.32 v1(119.51,60.06)
  IN2 w0.102: 121.44,65.28 121.44,70.14 v1(121.32,70.26)
  IN2 w0.127: 121.44,65.28 121.44,65.17 121.11,64.84 121.11,64.65 119.5,63.04 119.5,60.08 v1(119.51,60.06) ; v1(119.29,46.86) 118.69,46.86 115.37,43.54 108.45,43.54 108.2,43.79 106.06,43.79 105.6,43.33 103.93,43.33 103.28,42.68 95.07,42.68 94.79,42.4 89.56,42.4 87.87,40.71 74.65,40.71 74.25,40.32 71.41,40.32 69.85,41.88 69.85,45.82 69.49,46.17 69.49,47.82 68.45,48.86 68.45,50.43 67.04,51.85 64.76,51.85 57.35,59.26 57.35,71.76 53.88,75.23 52.31,75.23 50.75,76.79 47.52,76.79 47.07,76.34 44.15,76.34 v1(43.58,75.77)
  BOTTOM w0.102: UC1.AV27 121.77,70.71 v1(121.32,70.26)
SKU_ID: length 28.5
  TOP w0.102: v1(153.91,79.27) 154.19,78.99 v2(155.08,78.99)
  IN1 w0.102: 139.88,78.43 139.16,77.72 132.64,77.72 v1(132.07,77.16)
  IN1 w0.127: 139.88,78.43 139.94,78.49 140.26,78.49 140.99,79.22 146.27,79.22 146.56,79.51 148.54,79.51 149.26,78.8 151.93,78.8 152.4,79.27 v1(153.91,79.27)
  BOTTOM w0.102: RC132.1 RC133.2 154.19,78.99 v1(153.91,79.27) ; UC1.AE8 132.03,77.2 v1(132.07,77.16)
SLEEVE: length 15.6
  IN1 w1.016: 31.4,17.52 24.16,17.52 22.51,15.87 22.51,14.54 21.75,13.77 20.54,13.77 19.85,14.47 18.96,14.47
  BOTTOM w0.102: v1(17.88,14.79) v2(17.88,15.29)
  vias: v1(17.88,14.16) v1(32.17,17.08) v1(32.17,16.51)
SLEEVE_R: length 15.8
  TOP w0.102: JHP1.3 4.41,17.4 v4(5.88,18.87)
  IN1 w1.016: 18.34,19.34 16.78,19.34 16.26,18.83 6.46,18.83 5.53,17.89
  vias: v1(19.21,18.66) v1(19.21,18.03)
SN_0.95V: length 1.7
  TOP w0.102: PRH07.2 v2(158.03,64.9)
SN_1.2V: length 1.2
  TOP w0.102: PCM11.1 62.43,103.69 v2(62.33,103.79)
SN_1.8V: length 2.6
  TOP w0.102: PC1806.1 v2(163.34,53.42)
  TOP w0.508: PR1804.2 PC1806.1
SN_3V: length 1.7
  TOP w0.102: PR305.2 v2(52.1,100.83)
SN_5V: length 1.3
  TOP w0.102: PC509.1 v2(41.25,101.33)
SN_+APU_CORE: length 2.8
  TOP w0.102: PRZ74.2 150.02,120.81 v2(150.08,120.87)
  TOP w0.635: PCZ54.1 PRZ74.2
SN_+APU_CORE_NB: length 3
  TOP w0.102: PRZ10.2 v2(153.49,107.69)
  TOP w0.635: PRZ10.2 155.48,108.07 PCZ13.1
SN_CHG: length 1.7
  TOP w0.102: PRB40.2 v2(180.93,47.26)
SSD_SCP#: length 71
  TOP w0.102: UE1.107 45.73,82.14 44.36,80.77 v1(43.98,80.77) ; v1(44.04,27.17) v2(44.6,27.17)
  IN1 w0.127: v1(42.58,71.12) 41.88,70.42 39.3,70.42 38.83,69.95 38.83,67.75 40.79,65.79 40.79,61.16 48.74,53.21 48.74,42.07 47.62,40.96 47.62,32.44 46.16,30.98 46.16,29.3 v1(44.04,27.17)
  BOTTOM w0.102: v1(42.58,71.12) 40.84,72.85 40.84,73.76 41.12,74.04 41.12,75.62 42.83,77.34 42.83,77.91 43.98,79.05 v1(43.98,80.77) ; RS26.2 RE49.1 43.73,27.17 v1(44.04,27.17)
SUSCLK_WLAN: length 235.5
  TOP w0.102: RC62.2 148.19,70.65 v1(149.13,70.65) ; RE34.1 40.18,88.64 v1(40.18,89.11)
  IN1 w0.127: v1(57.95,85.66) 58.12,85.48 62.06,85.48 63.65,87.07 63.65,87.68 68.74,92.77 68.74,109.34 68.23,109.85 68.23,118.04 66.46,119.82 66.46,121.01 65.6,121.86 65.6,129.21 68.82,132.43 70.3,132.43 v1(70.39,132.52) ; v1(40.18,89.11) 41.14,89.11 41.69,89.66 44.8,89.66 46.2,88.26 47.9,88.26 48.47,87.69 50.14,87.69 50.71,87.12 51.53,87.12 56.1,82.55 56.1,82.23 57.26,81.07 v1(58.58,81.07) 58.39,80.88 58.39,79.94 58.59,79.73 58.59,79.15 60.07,77.67 60.07,74.88 64.24,70.71 64.24,65.39 68.61,61.03 68.61,59.54 69.16,58.99 69.16,54.25 70.07,53.34 70.07,46.84 70.52,46.39 70.52,45.91 72.49,43.94 74.36,43.94 74.69,43.6 75.92,43.6 76.19,43.32 86.5,43.32 87.21,44.04 95.27,44.04 97.99,41.32 100.73,41.32 100.9,41.49 105,41.49 105.87,40.62 110.57,40.62 111.12,41.17 119.72,41.17 120.46,41.91 128.07,41.91 128.19,42.03 131.81,42.03 132.12,42.33 139.12,42.33 144.39,47.6 144.39,53.3 147.07,55.98 147.07,60.9 150.61,64.43 150.61,69.2 149.15,70.65 v1(149.13,70.65)
  BOTTOM w0.102: v1(70.39,132.52) 70.37,132.54 70.37,133.28 70.89,133.8 JWLAN1.50 ; v1(57.95,85.66) 57.98,85.62 57.98,81.64 58.56,81.07 v1(58.58,81.07)
SUSP#: length 257.2
  TOP w0.254: R52.1 154.14,45.09 v1(153.96,45.27) ; UE1.116 42.13,80.19 v1(42.07,80.13) ; v1(61.5,117.93) 61.02,117.44 v2(59.89,117.44) 57.47,117.44 v1(57.18,117.72) ; v1(34.01,62.59) DE2.2 33.21,61.8 R51.1 R53.1
  IN1 w0.254: v1(153.96,45.27) 153.7,45.53 150.74,45.53 150.35,45.14 150.35,43.25 143.38,36.28 137.79,36.28 137.16,35.64 136.55,35.64 135.73,34.83 134.92,34.83 134.46,34.37 129.73,34.37 129.14,34.96 126.51,34.96 125.7,34.14 124.39,34.14 123.8,34.73 123.44,34.73 123.27,34.56 120.03,34.56 119.83,34.36 119.5,34.03 112.03,34.03 111.4,34.66 106.35,34.66 106.05,34.36 93.37,34.36 89.34,38.39 70.67,38.39 67.28,41.78 67.28,42.04 66.33,42.98 65.08,42.98 63.34,44.72 63.34,52.18 60.94,54.58 60.94,67.4 54.64,73.69 54.64,77.7 53.73,78.61 47.16,78.61 47.03,78.74 43.46,78.74 v1(42.07,80.13)
  BOTTOM w0.254: 40.86,80.13 40.86,79.62 39.28,78.04 39.28,72.51 39.85,71.94 39.85,71.37 40.23,70.99 40.23,70.42 39.98,70.16 39.28,70.16 38.93,69.81 38.93,65.62 38.71,65.4 38.71,64.13 38.06,63.48 37.03,63.48 36.57,63.03 34.44,63.03 v1(34.01,62.59) ; 40.86,80.13 v1(42.07,80.13) ; 40.86,80.13 40.42,80.58 40.42,81.04 37.77,83.69 37.77,84.7 37.35,85.12 36.03,85.12 35.8,85.35 35.8,90.75 33.24,93.3 33.24,97.07 32.7,97.62 32.7,116.59 35.93,119.82 55.22,119.82 57.18,117.85 v1(57.18,117.72) ; PRM09.1 61.5,117.08 v1(61.5,117.93)
SWTRAP: length 3.9
  TOP w0.102: UE1.70 52.27,71.42 52.7,71.85 v2(52.93,71.85) 53.13,71.85 RE39.1 RE41.2
SYS_RESET_L: length 10
  BOTTOM w0.102: v2(139.07,76.39) 139.51,75.94 CC15.2 139.93,76.11 ; RC92.1 142.52,76.62 140.44,76.62 139.93,76.11 ; 139.93,76.11 RC81.2 139.73,77.01 138.4,77.01 138.21,77.2 136.96,77.2 136.92,77.16 UC1.AF1
SYSON: length 56.4
  TOP w0.102: UE1.95 53.64,81.42 CE12.1 53.76,81.61 53.45,81.91 53.19,81.91 v1(53.18,81.91) ; v1(63.92,117.66) v2(63.42,117.66)
  IN1 w0.127: v1(63.92,117.66) 64.28,118.03 64.94,118.03 65.31,117.65 65.31,116.26 66.96,114.61 66.96,110.4 68.23,109.13 68.23,93 64.83,89.59 63.03,89.59 62.33,88.9 62.33,87.99 60.38,86.04 58.69,86.04 v1(58.55,85.9)
  IN2 w0.127: v1(53.18,81.91) 54.2,82.93 57.12,82.93 57.69,82.35 58.33,82.35 v1(58.58,82.1)
  BOTTOM w0.102: v1(63.92,117.66) 64.16,117.42 PRM08.1 ; PR2501.1 59.6,84.85 v1(58.55,85.9)
  BOTTOM w0.254: PR2501.1 59.17,82.69 v1(58.58,82.1)
T_CRIT#: length 3.2
  BOTTOM w0.102: U1.4 175.83,65.36 175.71,65.48 175.71,66.46 v2(175.87,66.62) 176.35,67.1 R46.2
TON_1.2V: length 4.2
  BOTTOM w0.102: v2(65.43,117.95) 65.43,116.51 64.98,116.06 PRM07.2
  BOTTOM w0.203: PUM01.9 64,114.95 64.3,115.25 64.51,115.25 64.97,115.71 PRM07.2
TOUCH_SCREEN_INT#: length 6.7
  TOP w0.102: v2(206.87,50.16) 207.31,49.72 v1(207.43,49.72) 207.36,49.65 R17.2
  BOTTOM w0.102: v1(207.43,49.72) 207.64,49.5 209,49.5 209.23,49.26 211.24,49.26 211.56,48.95 JEDP1.24
TOUCH_SCREEN_RST: length 8.4
  TOP w0.102: v2(205.16,49.09) R19.2 206.16,49.71 v1(206.16,49.72)
  BOTTOM w0.102: JEDP1.25 211.62,48.45 211.59,48.42 210.88,48.42 210.28,49.02 209.19,49.02 208.91,49.3 206.58,49.3 v1(206.16,49.72)
TP_CLK: length 114.2
  TOP w0.102: v1(52.59,77.24) 52.59,77.81 52.18,78.22 UE1.87 ; v4(127.23,32.51) v1(126.71,33.02)
  IN1 w0.127: v1(52.59,77.24) 52.6,77.22 52.6,76.47 52.04,75.91 52.04,75.43 52.98,74.5 52.98,73.06 53.83,72.2 53.83,69.92 55.91,67.83 55.91,66.69 59.6,63 59.6,54.03 61.81,51.82 61.81,43.99 63,42.79 63.38,42.79 65.78,40.39 66.21,40.39 69.55,37.05 88.62,37.05 92.72,32.95 108.84,32.95 109.09,32.7 119.39,32.7 119.65,32.44 122.55,32.44 123.07,32.96 126.66,32.96 v1(126.71,33.02)
  BOTTOM w0.102: v1(126.71,33.02) 126.54,32.85 126.54,32.75 126.41,32.62 C7.1 R25.2 125.05,32.57 JTP1.1
TP_DATA: length 108.8
  TOP w0.102: v1(53.16,77.35) 53.16,78.13 v4(53.1,78.19) 52.66,78.62 UE1.88
  IN1 w0.127: v1(53.16,77.35) 53.16,77.31 53.49,76.98 53.49,73.32 54.34,72.47 54.34,70.15 60.11,64.38 60.11,54.24 62.52,51.83 62.52,44.38 66,40.9 66.42,40.9 69.76,37.56 88.85,37.56 92.88,33.54 108.97,33.54 109.3,33.21 119.6,33.21 119.81,33 121.37,33 v1(121.64,33.27)
  BOTTOM w0.102: JTP1.2 124.05,32.56 R26.2 124.11,32.65 C8.1 123.11,33.65 122.02,33.65 v1(121.64,33.27)
TP_EN: length 3.3
  TOP w0.102: UE1.82 52.16,76.22 52.23,76.29 v2(53.02,76.29) 53.16,76.29 R34.1
TP_I2C_INT#: length 18.3
  TOP w0.102: v1(130.49,31.67) v4(130.88,31.28)
  BOTTOM w0.102: R24.2 135.56,33.14 133.96,33.14 132.98,32.16 Q2.3 131.96,32.75 R22.2 R29.1 130.34,31.82 v1(130.49,31.67) 130.15,31.33 127.38,31.33 125.26,29.21 122.91,29.21 122.05,30.06 JTP1.4
TP_I2C_INT#_APU: length 66.4
  TOP w0.102: v1(153.77,82.74) v2(153.77,83.24)
  IN1 w0.127: v1(135.16,40.64) 135.61,40.19 137.03,40.19 137.57,40.74 139.68,40.74 146.31,47.37 146.31,51.91 148.76,54.36 148.76,60.22 152.26,63.72 152.26,67.95 154.95,70.65 154.95,81.55 v1(153.77,82.74)
  BOTTOM w0.102: v1(153.77,82.74) 153.77,82.34 RC52.2 ; v1(135.16,40.64) 135.16,40.41 134.72,39.97 134.72,38.03 135.19,37.56 135.19,36.29 135.61,35.87 135.61,35.3 135.29,34.98 135.04,34.98 134.3,34.25 Q2.1 132.96,34.25 132.38,33.66 R22.1
TP_ON#_GATE: length 99
  TOP w0.102: R34.2 55.81,77.3 55.83,77.33 v1(56.02,77.33) v2(56.02,78.08)
  IN2 w0.127: v1(56.02,77.33) 56.02,75.91 58.04,73.89 58.04,60.17 65.67,52.53 67.33,52.53 69.14,50.72 69.14,49.14 70.18,48.1 70.18,46.45 70.53,46.1 70.53,44.02 71.28,43.27 71.28,42.67 72.94,41 73.97,41 74.36,41.4 87.58,41.4 88.02,41.84 88.03,41.84 89.11,42.92 89.59,43.4 94.17,43.4 94.46,43.11 103.1,43.11 104.18,44.19 105.91,44.19 105.94,44.22 108.81,44.22 108.93,44.09 109.7,44.09 109.8,44.19 v1(112.75,44.19)
  BOTTOM w0.102: v1(112.75,44.19) 112.62,44.06 112.62,43.87 112.26,43.52 C9.2 111.79,42.41 111.16,41.78 110.14,41.78 108.99,42.93 Q3.2 Q6.2
TPAN_VDD_F:
  vias: v2(219.95,47.21)
TS_EN_R: length 2.4
  BOTTOM w0.102: R6.2 42.58,83.38 DE1.2 41.31,82.39 v2(41.22,82.3)
TS_EN_RR: length 225.8
  TOP w0.102: v1(213.33,41.33) 213.74,41.33 v2(213.83,41.25)
  IN1 w0.127: v1(213.33,41.33) 211.68,41.33 208.61,38.26 207.64,38.26 207.13,38.77 196.63,38.77 195.13,37.27 192.93,37.27 191.09,39.11 190.21,39.11 189.49,38.39 186.3,38.39 185.64,39.05 185.64,39.05 157.45,39.05 156.9,38.49 153.88,38.49 153.58,38.79 150.85,38.79 150.4,38.35 150.4,37.59 145.31,32.5 137.58,32.5 135.4,30.32 124.14,30.32 123.33,29.51 108.15,29.51 107.57,30.09 87.31,30.09 82.71,34.69 68.06,34.69 66.97,35.78 64.5,35.78 59.02,41.26 59.02,44.27 59.44,44.69 59.44,50.93 57.3,53.08 57.3,61.09 52.61,65.78 52.61,67.46 51.54,68.52 51.54,68.94 50.77,69.72 50.77,71.55 49.75,72.58 44.48,72.58 43.91,72 41.75,72 41.37,72.39 40.18,72.39 v1(39.83,72.74)
  BOTTOM w0.102: v1(213.33,41.33) 213.21,41.45 JEDP1.39 ; R6.1 42.58,79.75 39.58,76.76 39.58,72.99 v1(39.83,72.74)
UG1_APU: length 10.8
  TOP w0.102: v1(150.08,127.44) v2(149.73,127.8)
  IN2 w0.762: 145.96,135.63 145.58,135.25 145.58,131.69 147.99,129.28 147.99,129.28 148.62,128.65 149.77,128.65 150.28,128.14
  vias: v1(146.65,136.5) v1(146.65,135.87) v1(150.53,127.06)
UG_1.2V: length 9.3
  IN2 w0.762: 63.6,109.02 61.69,107.12 61.69,105.34 59.98,103.63 59.98,101.21
  vias: v1(60.87,101.21) v1(60.87,100.64) v1(64.17,110.55) v1(64.17,109.98)
UG_CHG: length 10.8
  IN2 w0.762: v1(181.71,52.32) 183.26,52.32 185.29,50.29 190.78,50.29 191.4,49.67
  vias: v1(181.01,52.32) v1(191.91,48.73) v1(192.29,49.16)
UG_NB: length 36.2
  TOP w0.102: v1(150.53,104.07) v2(151.08,104.07)
  IN2 w0.762: 150.53,105.41 150.53,106.74 152.36,108.57 152.36,115.2 156.28,119.12 156.28,131.22 152.31,135.2 152.31,137.02
  vias: v1(150.53,104.71) v1(151.61,138.33) v1(152.24,138.33)
USB3_ARX_DTX_0_N1: length 173.9
  IN2 w0.102: v1(137.57,81.9) 136.96,82.51 136.36,82.51 136.09,82.25 136.09,81.3 136.04,81.25
  IN2 w0.127: 136.04,81.25 136.04,67.06 136.31,66.79 136.31,56.32 131.45,51.47 131.45,45.81 131.89,45.38 131.89,40.57 124.41,33.09 123.01,33.09 121.98,32.06 108.73,32.06 107.71,33.09 91.38,33.09 90.82,32.53 85.93,32.53 85.26,33.2 67.54,33.2 66.83,33.91 60.86,33.91 52.8,41.97 45.06,41.97 44.71,42.32 36.85,42.32 35.93,41.4 35.02,41.4 33.82,40.19 33.82,39.44 v1(33.71,39.33)
  BOTTOM w0.102: v1(137.57,81.9) 137.03,81.36 136.78,81.36 136.53,81.11 UC1.W1 ; v1(33.71,39.33) 33.71,40.03 33.46,40.27 32.77,40.27 30.87,42.17 27.7,42.17 25.26,44.62 25.26,49.93 24.64,50.56 24.43,50.56 24.23,50.35 LU1.2 23.67,50.19 RU2.1
USB3_ARX_DTX_0_N1_R: length 9.9
  BOTTOM w0.102: JUSB1.5 14.38,49.93 14.48,50.03 14.88,50.03 15.73,50.88 v3(18.98,50.88) 19.45,50.88 19.58,50.75 EU4.1 EU4.9 20.92,50.75 21.39,50.75 21.65,50.49 22.25,50.49 22.38,50.35 LU1.1 22.75,50.19 RU2.2
USB3_ARX_DTX_0_N2: length 178.6
  IN2 w0.127: v1(139.45,82.3) 139.75,82 139.75,81.27 138.87,80.4 138.87,73.89 137.94,72.96 137.94,68.15 138.41,67.67 138.41,55.69 133.78,51.06 133.78,48.05 134.09,47.75 134.09,46.16 133.78,45.86 133.78,39.78 127.77,33.77 127.77,33.33 125.14,30.7 123.92,30.7 122.86,29.64 107.8,29.64 106.26,31.19 94.03,31.19 93.37,30.53 85.63,30.53 85.49,30.4 74.16,30.4 73.64,30.93 65.76,30.93 65.24,30.4 55.15,30.4 46.7,38.85 42.92,38.85 42.07,39.7 37.31,39.7 36.02,38.41 34.97,38.41 33.64,37.07 33.64,35.75 33.51,35.62 33.35,35.62 33.24,35.72 v1(33.24,35.87)
  BOTTOM w0.102: v1(139.45,82.3) 139.82,81.92 139.82,81.73 139.71,81.62 139.18,81.62 138.23,80.67 137.93,80.67 137.83,80.77 137.83,80.98 137.73,81.08 137.53,81.08 137.43,80.98 137.43,80.83 137.26,80.67 136.83,80.67 136.61,80.45 136.19,80.45 UC1.Y1 ; RU7.1 21.61,36.38 LU4.2 22.07,36.51 22.16,36.6 24.95,36.6 26.56,38.21 31.04,38.21 32.6,36.65 33.42,36.65 33.69,36.38 33.69,36.12 33.41,35.85 33.27,35.85 v1(33.24,35.87)
USB3_ARX_DTX_0_N2_R: length 18.4
  BOTTOM w0.102: RU7.2 20.62,36.38 LU4.1 20.34,36.66 20.08,36.66 19.96,36.78 19.55,36.78 19.42,36.65 EU6.9 EU6.1 17.8,36.65 17.67,36.78 16.98,36.78 16.81,36.61 16.81,34.7 17.61,33.9 v3(17.61,30.67) 17.61,27.26 17,26.65 15.53,26.65 15.01,26.13 14.48,26.13 14.38,26.03 JUSB2.5
USB3_ARX_DTX_0_P1: length 173.9
  IN2 w0.102: 136.35,81.06 136.35,81.16 136.38,81.18 136.38,82.13 136.48,82.23 136.81,82.23 136.99,82.05 136.99,81.9 v1(136.99,81.9)
  IN2 w0.127: v1(34.49,39.31) 34.43,39.36 34.32,39.36 34.13,39.56 34.13,40.06 35.15,41.09 36.06,41.09 36.98,42.01 44.58,42.01 44.93,41.66 52.67,41.66 60.73,33.6 66.7,33.6 67.41,32.89 85.13,32.89 85.8,32.22 90.95,32.22 91.51,32.77 107.58,32.77 108.6,31.75 122.11,31.75 123.14,32.78 124.54,32.78 132.2,40.44 132.2,45.5 131.77,45.94 131.77,51.34 136.62,56.19 136.62,66.92 136.35,67.19 136.35,81.06
  BOTTOM w0.102: RU1.1 23.67,51.02 LU1.3 24.31,50.86 24.37,50.8 24.74,50.8 25.5,50.03 25.5,44.72 27.8,42.41 v3(28.53,42.41) 30.97,42.41 32.87,40.51 33.56,40.51 33.94,40.13 33.94,39.67 34.25,39.36 34.43,39.36 v1(34.49,39.31) ; v1(136.99,81.9) 137.02,81.87 137.02,81.7 136.92,81.6 136.68,81.6 136.22,81.14 136.22,81.11 136.12,81.01 UC1.W2
USB3_ARX_DTX_0_P1_R: length 10
  BOTTOM w0.102: RU1.2 22.75,51.02 LU1.4 22.32,50.86 22.19,50.72 21.75,50.72 21.56,50.92 21.56,50.94 21.25,51.25 EU4.8 EU4.2 19.58,51.25 19.45,51.12 v3(17.59,51.12) 15.63,51.12 14.78,50.27 14.48,50.27 14.38,50.37 JUSB1.6
USB3_ARX_DTX_0_P2: length 178.6
  IN2 w0.127: v1(140.06,82.32) 140.06,81.14 139.18,80.27 139.18,73.76 138.25,72.83 138.25,68.28 138.72,67.8 138.72,55.56 134.09,50.93 134.09,48.18 134.4,47.87 134.4,46.04 134.09,45.73 134.09,39.65 128.08,33.64 128.08,33.2 125.27,30.39 124.05,30.39 122.99,29.33 107.67,29.33 106.13,30.88 94.16,30.88 93.5,30.22 85.76,30.22 85.62,30.09 74.03,30.09 73.51,30.61 65.89,30.61 65.37,30.09 55.02,30.09 46.57,38.54 42.79,38.54 41.94,39.39 37.44,39.39 36.15,38.1 35.1,38.1 33.95,36.94 33.95,36.09 v1(34.18,35.87)
  BOTTOM w0.102: UC1.Y2 135.75,80.46 136.05,80.15 136.35,80.15 136.41,80.21 136.71,80.21 136.93,80.43 138.33,80.43 139.28,81.38 139.81,81.38 140.06,81.63 v1(140.06,82.32) ; v1(34.18,35.87) 33.92,36.12 33.92,36.48 33.52,36.89 32.7,36.89 31.14,38.45 26.47,38.45 v3(25.67,37.65) 24.86,36.84 22.18,36.84 22.01,37.01 LU4.3 21.61,37.14 RU8.1
USB3_ARX_DTX_0_P2_R: length 18.3
  BOTTOM w0.102: JUSB2.6 14.38,26.47 14.48,26.37 14.91,26.37 15.43,26.89 16.9,26.89 17.37,27.36 v3(17.37,29.04) 17.37,30.45 17.37,30.91 17.37,30.91 17.37,33.8 16.57,34.6 16.57,36.71 16.88,37.02 17.67,37.02 17.8,37.15 EU6.2 EU6.8 19.39,37.15 19.52,37.02 20.48,37.02 LU4.4 20.62,37.14 RU8.2
USB3_ATX_C_DRX_0_N1: length 2
  BOTTOM w0.102: CU10.1 25.29,51.77 24.93,52.13 24.38,52.13 24.31,52.2 LU2.2 23.67,52.03 RU3.1
USB3_ATX_C_DRX_0_N2: length 1.8
  BOTTOM w0.102: RU9.1 21.7,38.16 LU5.2 21.88,38.16 22.01,38.29 22.68,38.29 CU20.1
USB3_ATX_C_DRX_0_P1: length 2
  BOTTOM w0.102: RU4.1 23.67,52.86 LU2.3 24.15,52.7 24.48,52.37 25.03,52.37 CU11.1
USB3_ATX_C_DRX_0_P2: length 1.8
  BOTTOM w0.102: RU10.1 21.61,38.79 LU5.3 21.87,38.53 22.68,38.53 CU21.1
USB3_ATX_DRX_0_N1: length 175.7
  IN2 w0.127: v1(138.31,82.61) 138.39,82.53 138.39,81.95 137.92,81.48 137.92,74.29 136.99,73.35 136.99,67.45 137.47,66.97 137.47,56.14 132.83,51.5 132.83,47.66 133.14,47.35 133.14,46.72 132.83,46.42 132.83,40.17 124.39,31.73 123.43,31.73 122.74,31.04 107.92,31.04 106.83,32.14 92.67,32.14 92.11,31.58 80.84,31.58 80.18,32.24 75.28,32.24 74.91,31.87 65.06,31.87 64.68,31.49 55.42,31.49 46.79,40.12 44.36,40.12 43.37,41.12 38.73,41.12 38.43,40.82 36.69,40.82 35.66,39.79 35.66,39.56 v1(35.43,39.33)
  BOTTOM w0.102: CU10.2 25.88,51.87 26.02,52.02 26.17,52.02 26.27,51.92 26.27,51.5 25.93,51.15 25.93,45.07 28.02,42.98 31.55,42.98 33.56,40.97 34.42,40.97 35.6,39.78 35.6,39.5 v1(35.43,39.33) ; v1(138.31,82.61) 138.22,82.7 138.22,82.74 138.04,82.93 136.68,82.93 136.66,82.9 136.37,82.9 136.31,82.96 135.93,82.96 135.83,83.06 UC1.R2
USB3_ATX_DRX_0_N2: length 182
  IN2 w0.127: v1(34.88,35.81) 34.96,35.89 34.96,36.32 35.85,37.21 36.16,37.21 37.71,38.75 41.6,38.75 42.45,37.9 46.11,37.9 54.74,29.27 66.14,29.27 66.39,29.52 67.85,29.52 68.14,29.23 86.28,29.23 86.36,29.31 93.48,29.31 94.42,30.24 105.86,30.24 107.7,28.41 123.78,28.41 124.59,29.22 125.4,29.22 137.96,41.78 137.96,44.19 140.69,46.92 140.69,50.75 139.36,52.08 139.36,68.06 138.88,68.54 138.88,72.57 139.82,73.5 139.82,79.88 140.69,80.76 140.69,82.49 141.32,83.12 141.77,83.12 v1(141.89,83.24)
  BOTTOM w0.102: v1(141.89,83.24) 141.77,83.12 141.21,83.12 140.78,83.55 138.91,83.55 138.65,83.81 137.04,83.81 136.86,84 136.36,84 136.3,84.06 136.01,84.06 135.71,83.76 UC1.P2 ; v1(34.88,35.81) 34.96,35.89 34.96,37.02 34.65,37.32 32.88,37.32 30.08,40.12 26.44,40.12 24.34,38.02 23.77,38.02 CU20.2
USB3_ATX_DRX_0_P1: length 175.7
  IN2 w0.127: v1(36.01,39.33) 35.98,39.37 35.98,39.66 36.82,40.51 38.56,40.51 38.86,40.81 43.24,40.81 44.23,39.81 46.66,39.81 55.29,31.18 64.81,31.18 65.19,31.56 75.04,31.56 75.41,31.93 80.05,31.93 80.71,31.27 92.24,31.27 92.8,31.83 106.7,31.83 107.79,30.73 122.87,30.73 123.56,31.42 124.52,31.42 133.15,40.04 133.15,46.29 133.45,46.59 133.45,47.48 133.15,47.79 133.15,51.38 137.78,56.01 137.78,67.1 137.3,67.58 137.3,73.22 138.24,74.16 138.24,81.35 138.7,81.82 138.7,82.8 v1(138.31,83.19)
  BOTTOM w0.102: UC1.R1 136.57,83.17 138.28,83.17 v1(138.31,83.19) ; CU11.2 25.88,52.38 26.01,52.26 26.27,52.26 26.51,52.01 26.51,51.4 26.17,51.05 26.17,45.17 28.12,43.22 v3(30.45,43.22) 31.65,43.22 33.66,41.21 34.51,41.21 35.84,39.88 35.84,39.5 v1(36.01,39.33)
USB3_ATX_DRX_0_P2: length 182
  IN2 w0.127: v1(35.47,35.81) 35.27,36.01 35.27,36.19 35.98,36.89 36.29,36.89 37.84,38.44 41.47,38.44 42.32,37.59 45.98,37.59 54.61,28.96 66.27,28.96 66.52,29.21 67.73,29.21 68.01,28.92 86.41,28.92 86.49,28.99 93.61,28.99 94.55,29.93 105.73,29.93 107.57,28.09 123.91,28.09 124.72,28.9 125.53,28.9 138.27,41.65 138.27,44.06 141,46.79 141,50.88 139.67,52.21 139.67,68.19 139.2,68.67 139.2,72.44 140.13,73.37 140.13,79.75 141.01,80.63 141.01,82.36 141.45,82.81 141.77,82.81 141.89,82.68 v1(141.89,82.55)
  BOTTOM w0.102: CU21.2 23.66,38.48 23.88,38.26 24.24,38.26 26.34,40.36 30.18,40.36 32.98,37.56 v3(33.9,37.56) 34.75,37.56 35.2,37.11 35.2,36.08 v1(35.47,35.81) ; v1(141.89,82.55) 141.89,82.7 141.71,82.88 141.12,82.88 140.68,83.31 138.81,83.31 138.55,83.57 136.95,83.57 136.76,83.76 136.26,83.76 136.26,83.76 UC1.P1
USB3_ATX_L_DRX_0_N1: length 11.7
  BOTTOM w0.102: RU3.2 22.75,52.03 LU2.1 22.11,52.2 21.98,52.33 21,52.33 EU4.7 EU4.4 19.58,52.25 19.45,52.38 v3(18.87,52.38) 17.67,52.38 16.81,53.24 16.81,54.57 16.51,54.87 16.16,54.87 15,56.03 14.48,56.03 14.38,55.93 JUSB1.8
USB3_ATX_L_DRX_0_N2: length 14.2
  BOTTOM w0.102: JUSB2.8 14.38,32.03 14.48,32.13 14.83,32.13 15.22,31.73 16.16,31.73 16.4,31.97 16.4,31.98 16.85,32.43 16.85,33.71 16.14,34.42 16.14,37.54 16.88,38.28 17.82,38.28 17.95,38.15 EU6.4 EU6.7 19.61,38.15 19.74,38.28 20.37,38.28 LU5.1 20.62,38.03 RU9.2
USB3_ATX_L_DRX_0_P1: length 11.8
  BOTTOM w0.102: RU4.2 22.75,52.86 LU2.4 22.11,52.7 21.98,52.57 21.1,52.57 EU4.6 EU4.5 19.58,52.75 19.45,52.62 17.77,52.62 v3(17.49,52.9) 17.05,53.34 17.05,54.67 16.61,55.11 16.26,55.11 15.1,56.27 14.48,56.27 14.38,56.37 JUSB1.9
USB3_ATX_L_DRX_0_P2: length 14.2
  BOTTOM w0.102: RU10.2 20.62,38.79 LU5.4 20.35,38.52 19.74,38.52 19.61,38.65 EU6.6 EU6.5 17.93,38.65 17.79,38.52 v3(17.05,38.52) 16.78,38.52 15.9,37.64 15.9,34.32 16.61,33.61 16.61,32.53 16.16,32.08 16.16,32.07 16.06,31.97 15.32,31.97 14.92,32.37 14.48,32.37 14.38,32.47 JUSB2.9
USB20_N0: length 113.3
  IN2 w0.127: v1(208.09,38.68) 208.29,38.68 208.7,38.27 208.7,35.46 204.8,31.56 178.53,31.56 176.09,34 150.13,34 150.13,34 149.6,34 147.16,36.44 147.16,41.46 144.57,44.05 144.57,48.5 143.86,49.21 143.86,52.05 142.75,53.15 142.75,64.55 143.48,65.27 143.48,66.24 v1(143.6,66.36)
  BOTTOM w0.102: v1(143.6,66.36) 143.41,66.17 143.41,65.94 143.14,65.67 142.63,65.67 142.53,65.57 141.19,65.57 140.8,65.96 v3(140.34,65.96) 139.49,65.96 139.15,66.29 138.96,66.29 138.22,67.04 138.22,68.2 137.6,68.82 137.46,68.82 137.33,68.69 137.18,68.69 137.04,68.83 137.04,68.97 137.17,69.1 137.17,69.25 136.85,69.57 136.42,69.57 135.98,70.01 UC1.AW2 ; v1(208.09,38.68) 208.2,38.79 208.84,38.79 LU7.3 209,38.67 RU14.1
USB20_N0_R: length 3.3
  BOTTOM w0.102: RU14.2 210.17,38.67 LU7.4 210.34,38.8 210.7,38.8 210.85,38.65 210.85,37.71 210.66,37.52 210.35,37.52 210.2,37.38 JIOB1.4
USB20_N1: length 102.7
  IN2 w0.127: v1(202.6,41.91) 202.6,42.1 202.41,42.29 201.78,42.29 201.27,41.78 199.3,41.78 198.18,42.9 192.88,42.9 191.99,43.79 189.71,43.79 189.29,43.37 184.51,43.37 180.94,39.8 156.06,39.8 148.12,47.75 148.12,49.87 147.34,50.64 147.34,55.74 148.31,56.71 148.31,60.85 149.14,61.67 149.14,64.08 v1(148.96,64.26)
  BOTTOM w0.102: RU16.1 205.31,38.67 LU8.3 203.74,38.67 203.06,39.35 203.06,41.74 202.93,41.87 202.63,41.87 v1(202.6,41.91) ; v1(148.96,64.26) 149.14,64.44 149.14,64.8 148.77,65.17 148.77,66.82 148.27,67.31 143.82,67.31 143.35,66.85 139.28,66.85 138.66,67.47 138.66,68.42 136.74,70.33 136.4,70.33 136.3,70.23 136.05,70.23 135.73,70.56 UC1.AV2
USB20_N1_R: length 3.5
  BOTTOM w0.102: RU16.2 206.49,38.67 LU8.4 206.66,38.8 206.95,38.8 207.82,37.93 207.82,37.73 207.65,37.56 207.33,37.56 207.2,37.43 JIOB1.7
USB20_N2: length 127
  TOP w0.102: R11.2 209.15,46.11 209.15,45.9 209.28,45.76 209.28,45.37 209.18,45.27 209,45.27 v1(208.83,45.45)
  IN2 w0.127: v1(204.44,39.86) 204.33,39.97 203.84,39.97 201.08,37.21 201.08,35.62 198.6,33.14 179.19,33.14 176.75,35.58 151.2,35.58 149.26,37.52 149.26,43.11 146.15,46.22 146.15,49.15 145.45,49.85 145.45,52.69 144.34,53.81 144.34,62.44 145.53,63.64 145.53,66.59 146.55,67.61 146.55,67.79 146.71,67.95 146.71,68.64 146.47,68.88 143.92,68.88 143.61,68.56 143.61,68.37 v1(143.77,68.21)
  BOTTOM w0.102: UC1.AU2 136.08,71.11 136.41,70.77 136.93,70.77 140.19,67.52 143.07,67.52 143.54,67.98 143.54,68 143.74,68.21 v1(143.77,68.21) ; v1(204.44,39.86) 204.42,39.86 204.4,39.88 204.4,39.96 204.3,40.06 204.06,40.06 203.76,40.36 203.76,41.82 204.27,42.33 205.74,42.33 206.26,42.86 207.49,42.86 207.87,43.24 207.87,43.43 207.68,43.62 207.12,43.62 D1.2 207.13,43.94 207.59,43.94 207.69,44.04 207.69,44.8 208.21,45.32 208.7,45.32 v1(208.83,45.45) 209,45.27 209.67,45.27 209.92,45.03 209.92,44.94 209.93,44.93 209.93,43.5 210.06,43.37 210.6,43.37 211.15,42.82 211.58,42.82 211.71,42.95 JEDP1.36
USB20_N3: length 120.8
  IN2 w0.127: v1(207.04,45.14) 206.66,45.14 206.6,45.08 206.41,45.08 206.16,44.83 206.16,39.31 199.05,32.2 178.8,32.2 176.36,34.64 149.87,34.64 147.8,36.7 147.8,42.1 145.2,44.69 145.2,48.76 144.5,49.46 144.5,52.3 143.39,53.41 143.39,62.9 144.46,63.97 144.46,66.86 145.42,67.82 145.42,68 v1(145.21,68.22)
  BOTTOM w0.102: R9.1 206.04,47.62 L1.4 205.77,47.35 205.31,47.35 204.96,47.01 204.96,46.02 205.84,45.14 v1(207.04,45.14) ; v1(145.21,68.22) 145.21,68.7 145.1,68.8 143.17,68.8 142.55,68.19 140.46,68.19 139.62,69.03 139.3,69.03 136.92,71.41 136.36,71.41 136.3,71.35 136.05,71.35 135.75,71.66 UC1.AT2
USB20_N3_R: length 8.3
  BOTTOM w0.102: JEDP1.33 211.81,44.45 211.73,44.37 211,44.37 210.9,44.47 v3(210.9,46.01) 210.9,46.3 210.54,46.67 210.15,46.67 ED2.2 209.78,46.8 209.65,46.67 209.41,46.67 208.73,47.35 207.3,47.35 L1.3 207.03,47.62 R9.2
USB20_N4: length 126.5
  IN2 w0.127: v1(150.13,71.19) 150.05,71.27 149.62,71.27 149.2,71.68 149.2,73.51 150.66,74.97 150.66,77.4 150.41,77.65 150.41,85.34 145.07,90.67 145.07,91.1 142.34,93.84 142.34,93.98 140.55,95.76 140.55,97.38 138.06,99.87 138.06,101.41 127.21,112.26 127.21,114.8 123.44,118.56 123.44,120.87 122.11,122.2 122.11,122.64 v1(122.08,122.66)
  BOTTOM w0.102: v1(150.13,71.19) 150,71.32 148.97,71.32 147.12,69.47 142.89,69.47 142.28,68.86 140.74,68.86 139.85,69.75 139.53,69.75 137.37,71.9 136.36,71.9 136.25,72.02 136.07,72.02 135.95,71.9 135.78,71.9 135.67,72 135.67,72.11 135.78,72.21 UC1.AR2 ; v1(122.08,122.66) 122.11,122.63 122.11,121.88 121.46,121.22 82.16,121.22 80.83,122.55 JWLAN1.5
USB20_N5: length 174.4
  IN2 w0.127: v1(38.37,35.81) 38.23,35.95 38.23,36.16 38.62,36.55 40.68,36.55 41.83,35.4 45.49,35.4 53.87,27.02 94.41,27.02 95.42,28.04 104.95,28.04 106.86,26.13 126.82,26.13 132.25,31.57 134.66,31.57 137.83,34.73 139.8,34.73 143.29,38.22 143.29,48.19 142.9,48.58 142.9,51.66 141.81,52.76 141.81,68.74 141.24,69.3 141.24,69.5 v1(141.37,69.62)
  BOTTOM w0.102: v1(38.37,35.81) 38.12,36.06 38.12,36.73 35.95,38.9 33.53,38.9 30.73,41.7 24.26,41.7 23.65,42.31 23.65,43.12 LU3.3 23.91,43.38 RU6.1 ; v1(141.37,69.62) 141.29,69.7 140.85,69.7 140.13,70.42 139.7,70.42 137.6,72.51 136.38,72.51 136.3,72.43 136.04,72.43 135.72,72.76 UC1.AP2
USB20_N5_R: length 17.3
  IN2 w0.127: JUSB1.2 15.88,53.43 16.01,53.31 17,53.31 17.82,52.49 17.82,50.2 17.31,49.69 17.31,48.38 17.49,48.21 17.61,48.21 v1(17.74,48.34)
  BOTTOM w0.102: v1(17.74,48.34) 17.9,48.18 18.86,48.18 18.96,48.29 18.96,48.87 EU3.3 19.34,48.81 19.34,48.71 21.52,46.53 22.53,46.53 23.64,45.41 23.64,45.1 23.78,44.96 LU3.4 23.78,44.46 RU6.2
USB20_N6: length 172.6
  IN2 w0.127: v1(37.02,35.75) 36.93,35.84 36.93,36.19 38.23,37.49 41.08,37.49 41.93,36.64 45.59,36.64 54.26,27.97 94.02,27.97 95.03,28.98 105.34,28.98 107.25,27.08 125.86,27.08 128.74,29.96 128.74,30.6 130.46,32.32 130.9,32.32 134.71,36.13 139.85,36.13 142.33,38.6 142.33,45.51 141.96,45.88 141.96,51.27 140.62,52.6 140.62,68.58 140.29,68.91 140.29,70.52 140.65,70.87 140.83,70.87 v1(140.93,70.77)
  BOTTOM w0.102: v1(140.93,70.77) 140.78,70.92 140.71,70.92 140.44,71.19 139.86,71.19 138.1,72.95 136.45,72.95 136.28,73.13 136.01,73.13 UC1.AN2 ; RU12.1 24.15,40.57 LU6.3 24.76,40.44 24.89,40.31 25.18,40.31 25.9,41.03 30.45,41.03 33.25,38.23 35.67,38.23 v3(36.39,37.52) 37.02,36.88 v1(37.02,35.75)
USB20_N6_R: length 22.2
  IN2 w0.127: v1(17.71,41.71) 17.58,41.58 17.11,41.58 16.55,41.02 16.55,35.11 16.8,34.86 16.8,30.02 16.19,29.41 16.01,29.41 15.88,29.53 JUSB2.2
  BOTTOM w0.102: RU12.2 23.16,40.57 LU6.4 22.55,40.44 22.42,40.31 22.17,40.31 22.06,40.2 21.32,40.2 21.21,40.31 20.74,40.31 19.51,41.54 19.19,41.54 19.08,41.64 19.08,42.11 EU5.3 18.8,41.64 18.7,41.54 17.89,41.54 v1(17.71,41.71)
USB20_N7: length 133.8
  IN2 w0.127: v1(198.09,35.05) 198.15,34.98 198.15,34.6 197.96,34.4 197.21,34.4 196.85,34.76 179.35,34.76 177.27,36.84 151.78,36.84 150.52,38.1 150.52,43.63 147.41,46.74 147.41,49.67 146.71,50.37 146.71,56.31 147.53,57.14 147.53,61.13 148.5,62.1 148.5,68.64 146.99,70.14 143.82,70.14 143.29,70.67 143.29,70.79 v1(143.39,70.89)
  BOTTOM w0.102: JFP1.6 218.5,31.37 218.63,31.5 218.63,32.18 220.25,33.8 220.25,35.29 219.47,36.07 219.33,36.07 219.17,35.92 219.17,35.19 EU1.2 218.73,35.33 218.73,35.79 218.63,35.89 215.5,35.89 214.52,34.91 214.52,31.79 213.78,31.05 201.27,31.05 198.15,34.16 198.15,34.98 v1(198.09,35.05) ; v1(143.39,70.89) 143.25,71.04 143.25,71.26 142.84,71.67 142.1,71.67 141.67,72.1 140.24,72.1 138.23,74.1 136.41,74.1 136.34,74.17 136.06,74.17 135.74,73.86 UC1.AM2
USB20_P0: length 113.3
  IN2 w0.127: v1(143.02,66.36) 143.16,66.22 143.16,65.4 142.44,64.68 142.44,53.02 143.54,51.92 143.54,49.08 144.26,48.37 144.26,43.92 146.85,41.33 146.85,36.31 149.47,33.69 150.26,33.69 175.96,33.69 178.4,31.25 204.93,31.25 209.01,35.33 209.01,38.4 208.25,39.16 208.2,39.16 v1(208.09,39.26)
  BOTTOM w0.102: v1(143.02,66.36) 143.17,66.21 143.17,66.04 143.04,65.91 142.53,65.91 142.43,65.81 141.29,65.81 140.9,66.2 139.59,66.2 139.25,66.53 139.06,66.53 138.45,67.14 138.45,68.3 136.96,69.8 136.63,69.8 136.53,69.9 UC1.AW1 ; RU13.1 209,39.17 LU7.2 208.82,39.03 208.32,39.03 v1(208.09,39.26)
USB20_P0_R: length 3.3
  BOTTOM w0.102: RU13.2 210.17,39.17 LU7.1 210.34,39.04 210.8,39.04 211.09,38.75 v3(211.09,38.12) 211.09,37.5 211.2,37.39 JIOB1.3
USB20_P1: length 102.7
  IN2 w0.127: v1(149.84,64.26) 149.84,64.36 149.76,64.45 149.58,64.45 149.45,64.32 149.45,61.54 148.62,60.72 148.62,56.58 147.66,55.61 147.66,50.77 148.43,49.99 148.43,47.88 156.19,40.11 180.81,40.11 184.38,43.68 189.16,43.68 189.58,44.1 192.12,44.1 193.01,43.21 198.31,43.21 199.43,42.09 201.14,42.09 201.65,42.6 202.54,42.6 202.82,42.32 v1(203.01,42.32)
  BOTTOM w0.102: v1(149.84,64.26) 149.55,64.26 149.38,64.42 149.38,64.9 149.01,65.27 149.01,66.92 148.37,67.55 143.72,67.55 143.25,67.08 139.38,67.08 138.9,67.57 138.9,68.52 136.84,70.57 136.2,70.57 UC1.AV1 ; v1(203.01,42.32) 203.01,42.13 203.3,41.84 203.3,39.45 203.84,38.91 204.54,38.91 204.8,39.17 LU8.2 205.31,39.17 RU15.1
USB20_P1_R: length 3.5
  BOTTOM w0.102: RU15.2 206.49,39.17 LU8.1 206.66,39.04 207.05,39.04 v3(207.55,38.55) 208.06,38.03 208.06,37.54 208.2,37.39 JIOB1.6
USB20_P2: length 127.4
  TOP w0.102: v1(208.83,44.86) 209,45.03 209.28,45.03 209.52,45.27 209.52,45.86 209.39,46 209.39,46.11 R12.2
  IN2 w0.127: v1(143.18,68.21) 143.29,68.32 143.29,68.69 143.79,69.19 146.6,69.19 147.02,68.77 147.02,67.82 146.86,67.66 146.86,67.48 145.85,66.46 145.85,63.51 144.65,62.31 144.65,53.93 145.76,52.82 145.76,49.98 146.46,49.28 146.46,46.35 149.58,43.24 149.58,37.65 151.33,35.9 176.88,35.9 179.32,33.46 198.47,33.46 200.76,35.75 200.76,37.34 203.71,40.28 204.76,40.28 204.89,40.41 204.89,40.64 204.76,40.76 v1(204.44,40.76)
  BOTTOM w0.102: v1(204.44,40.76) 204.5,40.7 204.5,40.51 204.3,40.3 204.16,40.3 204,40.46 204,41.72 204.37,42.1 205.84,42.1 206.36,42.62 207.59,42.62 208.11,43.14 208.11,43.43 208.3,43.62 208.75,43.62 D1.3 208.73,43.94 208.03,43.94 207.93,44.04 207.93,44.7 208.31,45.08 208.61,45.08 v1(208.83,44.86) 209,45.03 209.58,45.03 209.68,44.93 209.68,44.84 209.69,44.83 209.69,43.4 209.97,43.13 210.5,43.13 211.05,42.58 211.58,42.58 211.71,42.45 JEDP1.37 ; v1(143.18,68.21) 143.23,68.16 143.23,68.02 142.97,67.75 140.29,67.75 137.03,71.01 136.63,71.01 UC1.AU1
USB20_P3: length 120.8
  IN2 w0.127: v1(146.09,68.22) 145.72,67.85 145.72,67.67 144.78,66.74 144.78,63.84 143.7,62.77 143.7,53.54 144.81,52.43 144.81,49.59 145.52,48.89 145.52,44.82 148.11,42.23 148.11,36.83 150,34.95 176.49,34.95 178.92,32.51 198.92,32.51 205.84,39.43 205.84,44.96 206.28,45.39 206.47,45.39 206.6,45.52 206.6,45.65 206.73,45.78 206.99,45.78 v1(207.04,45.73)
  BOTTOM w0.102: v1(146.09,68.22) 145.89,68.02 145.79,68.02 145.66,68.15 145.66,68.34 145.44,68.56 145.44,68.8 145.2,69.04 143.07,69.04 142.45,68.43 140.56,68.43 139.72,69.27 139.39,69.27 138.71,69.95 138.71,70.1 138.73,70.12 138.73,70.26 138.58,70.4 138.44,70.4 138.42,70.39 138.28,70.39 138.13,70.53 138.14,70.67 138.15,70.69 138.15,70.84 138.01,70.98 137.87,70.98 137.85,70.96 137.7,70.96 137.56,71.11 137.56,71.25 137.58,71.27 137.58,71.41 137.43,71.55 137.29,71.55 137.27,71.54 137.13,71.54 137.01,71.65 136.36,71.65 136.36,71.66 UC1.AT1 ; v1(207.04,45.73) 206.7,45.38 205.94,45.38 205.2,46.12 205.2,46.91 205.41,47.11 205.79,47.11 L1.1 206.04,46.86 R8.1
USB20_P3_R: length 8.3
  BOTTOM w0.102: JEDP1.34 211.86,43.95 211.68,44.13 210.9,44.13 210.66,44.37 v3(210.66,44.64) 210.66,46.2 210.44,46.43 210.16,46.43 ED2.3 209.78,46.29 209.63,46.43 209.31,46.43 208.63,47.11 207.28,47.11 L1.2 207.03,46.86 R8.2
USB20_P4: length 126.5
  IN2 w0.127: v1(150.15,72) 150.15,71.76 149.96,71.58 149.75,71.58 149.51,71.81 149.51,73.38 150.97,74.84 150.97,77.53 150.72,77.78 150.72,85.47 145.38,90.8 145.38,91.23 142.65,93.97 142.65,94.1 140.87,95.89 140.87,97.51 138.37,100 138.37,101.54 127.52,112.39 127.52,114.93 123.76,118.69 123.76,121 122.43,122.33 122.43,122.42 v1(122.67,122.66)
  BOTTOM w0.102: v1(122.67,122.66) 122.35,122.35 122.35,121.78 121.56,120.98 82.06,120.98 80.73,122.31 80.18,122.31 79.92,122.05 JWLAN1.3 ; v1(150.15,72) 150.3,72 150.4,71.9 150.4,71.71 150.29,71.6 148.91,71.6 147.02,69.71 142.79,69.71 142.18,69.1 140.84,69.1 139.95,69.99 139.63,69.99 137.47,72.14 136.6,72.14 UC1.AR1
USB20_P5: length 174.3
  IN2 w0.127: v1(141.37,70.21) 141.24,70.21 140.93,69.9 140.93,69.18 141.49,68.61 141.49,52.63 142.59,51.53 142.59,48.45 142.98,48.06 142.98,38.35 139.67,35.04 137.7,35.04 134.54,31.88 132.12,31.88 126.69,26.44 106.99,26.44 105.08,28.35 95.29,28.35 94.28,27.33 53.99,27.33 45.62,35.71 41.96,35.71 40.81,36.86 38.49,36.86 37.92,36.29 37.92,35.94 37.79,35.81 v1(37.79,35.81)
  BOTTOM w0.102: v1(141.37,70.21) 141.1,69.94 140.95,69.94 140.23,70.66 139.79,70.66 137.7,72.75 136.19,72.75 UC1.AP1 ; RU5.1 23.15,43.38 LU3.2 23.41,43.12 23.41,42.22 24.16,41.46 30.63,41.46 33.43,38.66 35.85,38.66 37.88,36.63 37.88,35.9 v1(37.79,35.81)
USB20_P5_R: length 17.2
  IN2 w0.127: JUSB1.3 15.88,52.87 16.01,52.99 16.87,52.99 17.51,52.36 17.51,50.33 17,49.82 17,48.25 17.36,47.9 17.6,47.9 v1(17.74,47.76)
  BOTTOM w0.102: v1(17.74,47.76) 17.93,47.95 18.73,47.95 18.83,47.84 18.83,47.39 EU3.2 19.4,47.38 19.4,47.96 19.5,48.06 19.65,48.06 21.42,46.29 22.43,46.29 v3(22.9,45.82) 23.4,45.31 23.4,45.08 23.28,44.96 LU3.1 23.28,44.46 RU5.2
USB20_P6: length 172.5
  IN2 w0.127: v1(140.93,71.35) 140.68,71.35 139.98,70.65 139.98,68.78 140.31,68.46 140.31,52.47 141.64,51.14 141.64,45.75 142.02,45.38 142.02,38.73 139.72,36.44 134.59,36.44 130.78,32.63 130.33,32.63 128.43,30.73 128.43,30.09 125.73,27.39 107.38,27.39 105.47,29.3 94.9,29.3 93.89,28.28 54.39,28.28 45.72,36.95 42.06,36.95 41.2,37.81 38.1,37.81 36.62,36.32 36.62,35.93 36.44,35.75 v1(36.44,35.75)
  BOTTOM w0.102: RU11.1 24.15,39.81 LU6.2 24.76,39.94 24.89,40.07 25.28,40.07 26,40.79 30.36,40.79 33.15,37.99 35.57,37.99 36.78,36.78 36.78,36.09 v1(36.44,35.75) ; UC1.AN1 136.65,73.19 136.9,73.19 137,73.29 137,73.47 137.1,73.57 137.28,73.57 137.41,73.44 137.41,73.29 137.51,73.19 138.19,73.19 139.96,71.43 140.54,71.43 140.62,71.35 v1(140.93,71.35)
USB20_P6_R: length 22.2
  IN2 w0.127: JUSB2.3 15.88,28.97 16.01,29.09 16.32,29.09 17.11,29.89 17.11,34.99 16.86,35.24 16.86,40.89 17.24,41.27 17.57,41.27 v1(17.71,41.13)
  BOTTOM w0.102: v1(17.71,41.13) 17.89,41.3 18.7,41.3 18.8,41.2 EU5.2 19.08,40.74 19.08,41.2 19.19,41.3 19.41,41.3 20.64,40.07 21.11,40.07 21.22,39.96 v3(21.87,39.96) 22.16,39.96 22.27,40.07 22.42,40.07 22.55,39.94 LU6.1 23.16,39.81 RU11.2
USB20_P7: length 133.7
  IN2 w0.127: v1(198.86,35.05) 198.65,35.05 198.47,34.86 198.47,34.47 198.09,34.09 197.08,34.09 196.72,34.45 179.22,34.45 177.14,36.53 151.65,36.53 150.21,37.97 150.21,43.5 147.1,46.61 147.1,49.54 146.4,50.24 146.4,56.44 147.22,57.26 147.22,61.26 148.18,62.23 148.18,68.51 146.86,69.83 143.69,69.83 142.98,70.54 142.98,70.72 v1(142.81,70.89)
  BOTTOM w0.102: v1(198.86,35.05) 198.66,35.05 198.39,34.78 198.39,34.26 201.36,31.29 213.68,31.29 214.28,31.89 214.28,35 215.41,36.13 218.63,36.13 218.73,36.23 218.73,36.67 EU1.3 219.3,36.69 219.3,36.42 219.4,36.32 219.56,36.32 220.49,35.39 220.49,33.7 218.87,32.08 218.87,31.5 219,31.37 JFP1.5 ; UC1.AM1 136.19,73.86 138.13,73.86 140.14,71.86 141.57,71.86 142,71.43 142.74,71.43 143.01,71.16 143.01,71.1 v1(142.81,70.89)
USB_EN#: length 246.5
  TOP w0.102: v1(21.77,39.43) 21.84,39.43 CU12.1 21.4,40.63 UU1.4 ; CU24.1 54.18,78.1 53.69,77.61 53.69,77.19 53.13,76.62 52.63,76.62 52.23,77.02 UE1.84 50.27,77.02 49.87,76.63 v1(49.87,76.06) ; v1(61.67,41.56) v2(62.01,41.22)
  IN1 w0.127: v1(39.59,40.25) 38.31,38.97 37.38,38.97 35.11,36.7 24.48,36.7 21.77,39.41 v1(21.77,39.43) ; v1(200.94,42.6) 199.86,41.52 198.88,41.52 198.18,40.83 195.06,40.83 193.99,41.9 192.21,41.9 190.71,43.4 189.89,43.4 189.47,42.98 181.81,42.98 181.36,42.54 158.95,42.54 157.45,41.04 150.77,41.04 147,37.27 147,36.11 144.49,33.6 137.24,33.6 135.9,32.25 130.42,32.25 129.5,31.33 123.6,31.33 123.12,30.85 119.03,30.85 118.71,31.17 107.3,31.17 107.17,31.05 90.52,31.05 86.11,35.45 68.38,35.45 66.66,37.17 65.58,37.17 64.35,38.4 64.35,39.67 62.74,41.27 61.96,41.27 v1(61.67,41.56) 61.67,41.89 60.21,43.35 60.21,51.25 58.06,53.39 58.06,61.41 53.44,66.03 53.44,67.71 52.31,68.84 52.31,69.79 51.53,70.57 51.53,71.87 49.65,73.75 49.65,75.39 49.87,75.61 49.87,76.05 v1(49.87,76.06)
  BOTTOM w0.102: v1(200.94,42.6) RE16.2 199.93,42.24 UU2.4 ; v1(61.67,41.56) 61.67,41.55 61.47,41.35 52.28,41.35 51.9,41.73 46.78,41.73 46.35,42.16 41.44,42.16 39.59,40.32 v1(39.59,40.25)
USB_OC0#: length 197.7
  TOP w0.102: v1(73.63,41.98) v2(74.19,41.98) ; UU1.3 21.61,38.79 CU13.1 22.22,37.94 22.32,37.84 v1(22.53,37.84)
  IN1 w0.127: v1(73.63,41.98) 73.68,42.03 95.41,42.03 97.39,40.05 101.28,40.05 101.45,40.22 103.88,40.22 104.75,39.35 116.86,39.35 117.39,38.82 121.79,38.82 122.84,39.87 124.53,39.87 124.93,40.27 128.92,40.27 129.4,40.76 132.61,40.76 132.92,41.06 139.65,41.06 145.96,47.37 145.96,52 148.5,54.54 148.5,60.37 151.94,63.81 151.94,68 154.63,70.69 154.63,81.05 154.15,81.53 150.53,81.53 v1(149.07,82.99) ; v1(29.13,39.17) 31.97,39.17 33.5,40.7 39.98,40.7 40.29,40.38 v1(40.29,40.19)
  BOTTOM w0.102: v1(73.63,41.98) 73.63,41.33 71.98,39.68 68.68,39.68 67.21,41.15 51.97,41.15 51.66,41.46 46.52,41.46 46.07,41.91 42.01,41.91 v1(40.29,40.19) ; RC68.2 149.72,82.99 v1(149.07,82.99) 146.95,82.99 146.17,82.21 142.19,82.21 140.73,80.75 138.93,80.75 137.69,79.5 137.17,79.5 137.12,79.56 136.44,79.56 136.33,79.66 136.04,79.66 135.74,79.36 UC1.AB2 ; v1(29.13,39.17) 26.26,39.17 24.35,37.27 22.96,37.27 22.53,37.7 v1(22.53,37.84)
USB_OC1#: length 103.5
  IN1 w0.127: v1(156.75,38.03) 156.79,38.07 156.84,38.07 157.57,38.8 185.46,38.8 186.16,38.1 189.75,38.1 190.83,37.02 195.23,37.02 196.57,38.35 v1(197.07,38.35)
  IN2 w0.127: v1(149.89,58.1) 149.89,58.64 149.85,58.68 149.85,60.21 150.73,61.09 150.73,67.69 147.54,70.88 147.54,76.32 147.13,76.74 v1(146.62,76.74)
  BOTTOM w0.1: 136.09,76.61 UC1.AG2
  BOTTOM w0.102: 136.09,76.61 136.38,76.9 136.39,76.9 136.41,76.91 138.03,76.91 139.99,74.94 141.29,74.94 141.72,75.37 143.41,75.37 143.98,75.94 RC69.2 144.5,76 145.26,76.76 146.44,76.76 146.46,76.74 v1(146.62,76.74) ; UU2.3 199.3,39.63 199.15,39.48 CU25.1 198.2,39.48 v1(197.07,38.35) ; v1(149.89,58.1) 150.05,58.1 153.01,55.14 153.01,38.92 153.89,38.03 v1(156.75,38.03)
USB_ZVSS: length 2.3
  TOP w0.102: v1(133.37,72.71) 133.28,72.71 v2(132.88,72.31)
  TOP w0.254: RC100.1 133.37,72.86 v1(133.37,72.71)
  BOTTOM w0.2: UC1.AN7 132.83,73.25 v1(133.37,72.71)
USBSS_ZVDD: length 12.2
  TOP w0.254: v1(133.67,81.57) 133.96,81.28 141.41,81.28 v2(141.64,81.52) 142.27,82.14 RC106.1
  BOTTOM w0.2: UC1.W5 133.63,81.51 133.67,81.55 v1(133.67,81.57)
USBSS_ZVSS: length 11.4
  TOP w0.254: v1(134.16,80.47) 135.43,80.47 135.54,80.37 v2(143.02,80.37) 144.24,80.37 144.36,80.24 RC105.1
  BOTTOM w0.2: UC1.W4 134.43,80.75 v1(134.16,80.47)
VCIN0_PH1: length 136.4
  TOP w0.254: PH1.1 122.96,57.1 v1(123.16,56.91) ; v1(44.93,82.16) UE1.109 ; v1(52.17,64.96) v2(52.17,63.03) 52.17,62.73 60.42,54.48 60.42,44 65.06,39.37 65.06,37.84 65.57,37.33 82.77,37.33 85.76,40.32 93.06,40.32 94.2,39.17 104.24,39.17 107.1,42.03 v1(107.1,42.41)
  IN1 w0.254: v1(123.16,56.91) 123.9,56.17 123.9,50.39 120.43,46.92 120.43,46.35 117.38,43.3 107.98,43.3 v1(107.1,42.41)
  IN2 w0.254: v1(44.93,82.16) 45.63,82.16 46.41,81.38 51.89,81.38 v1(52.61,82.1)
  BOTTOM w0.254: PR9.2 52.17,82.55 v1(52.61,82.1) 52.61,81.66 51.72,80.77 51.72,79.24 50.93,78.45 50.93,68.54 50.71,68.32 50.71,66.42 v1(52.17,64.96)
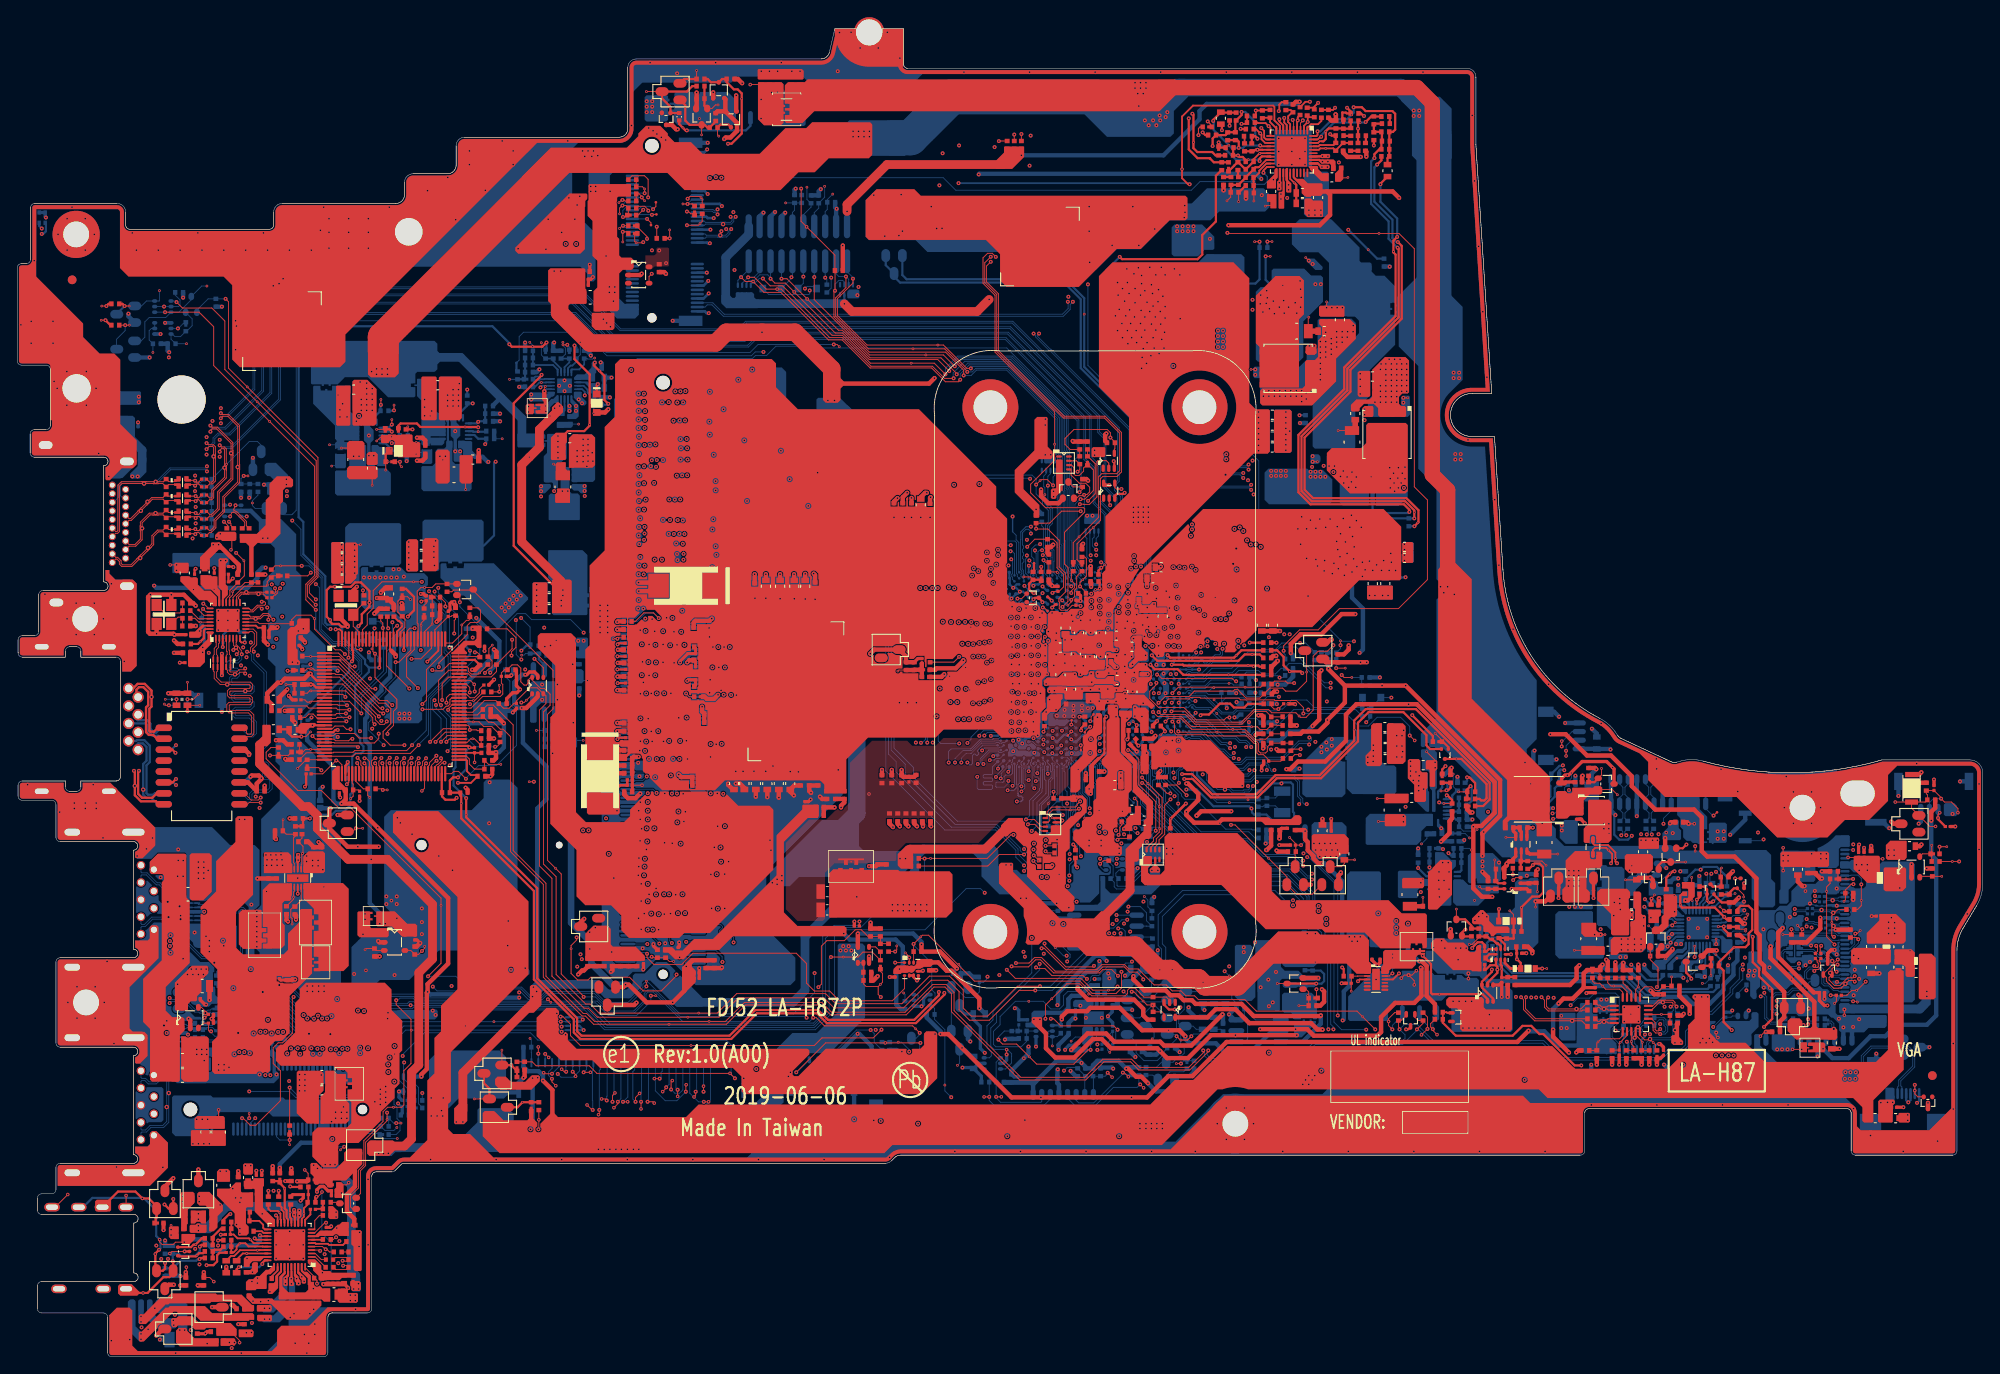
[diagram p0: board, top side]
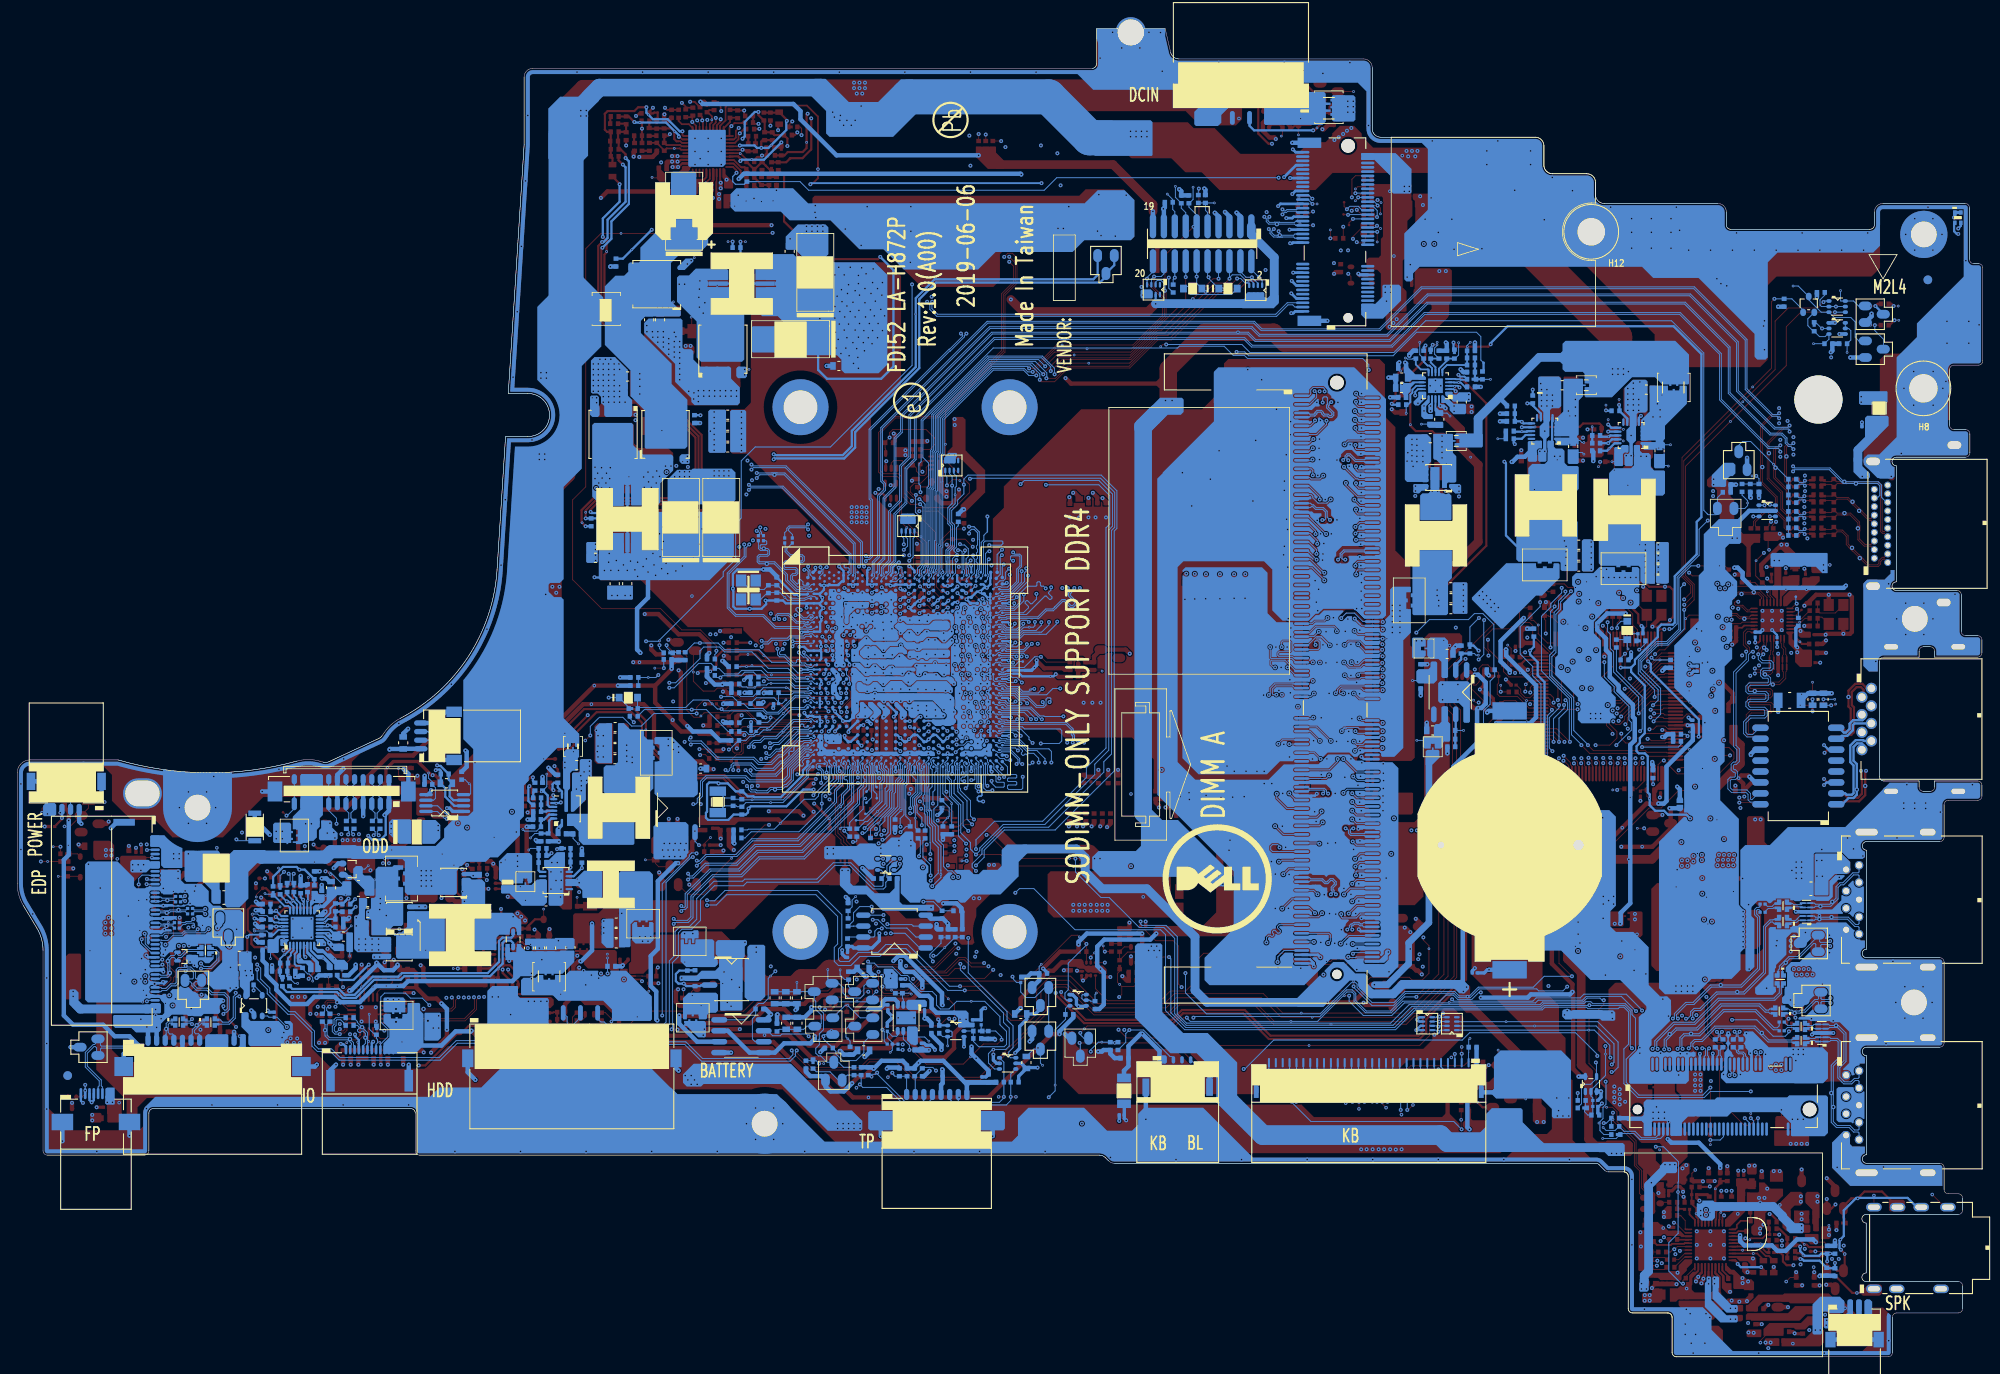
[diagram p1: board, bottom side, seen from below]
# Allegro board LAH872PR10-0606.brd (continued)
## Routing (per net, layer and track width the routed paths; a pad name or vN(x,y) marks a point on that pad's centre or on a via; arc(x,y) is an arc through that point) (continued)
VCIN1_BATT_TEMP: length 228.4
  TOP w0.203: PR39.2 PR41.1 166.09,40.06 166.16,39.99 PD6.2
  TOP w0.254: PRB24.2 199.88,52.04 200.27,52.43 201.16,52.43 201.61,51.99 201.61,49.63 201.19,49.2 201.19,47.98 200.83,47.63 v2(199.49,47.63) 197.72,45.86 PC14.1 198.28,44.9 198.28,38.93 v1(199.23,37.98) ; UE1.63 49.33,65.62 CE7.2 49.36,65.16 49.75,64.77 50.83,64.77 v1(51.06,64.99) ; PR39.2 165.65,38.84 167.17,37.33 173.77,37.33 174.91,38.48 175.93,38.48 176.88,37.52 177.33,37.52 180.97,33.88 v1(181.74,33.88)
  IN1 w0.203: v1(51.06,64.99) 51.06,64.86 56.76,59.16 56.76,52.85 58.19,51.42 58.19,44.47 57.62,43.9 57.62,41.35 64.11,34.86 66.58,34.86 67.67,33.76 80.18,33.76 84.78,29.16 107.18,29.16 107.76,28.58 123.72,28.58 124.53,29.39 135.78,29.39 137.96,31.57 146.1,31.57 149.7,35.17 177.96,35.17 179.26,33.88 v1(181.74,33.88)
  IN1 w0.254: v1(199.23,37.98) 199.23,37.98 200.25,36.95 200.25,34.32 198.78,32.85 182.77,32.85 v1(181.74,33.88)
VCIN1_BATT_TEMP_R: length 4.4
  TOP w0.102: PR39.1 164.25,38.74 164.25,38.35 v1(164.5,38.1) 164.5,37.94 v4(164.98,37.46)
  BOTTOM w0.102: v1(164.5,38.1) 164.5,39.53 PBATT1.5
VCOUT0: length 2.8
  TOP w0.102: UE1.104 v2(46.93,85.06) 46.93,85.31 47.28,85.66 RE30.1
VCOUT0_MAIN_PWR_ON: length 20.4
  TOP w0.102: v1(46.96,87.82) 47.05,87.9 CE14.1 47.53,87.63 47.28,87.37 RE30.2 ; PR507.1 43.74,104.06 v1(44.47,104.06) 44.47,103.68 v2(44.66,103.49)
  IN2 w0.127: v1(44.47,104.06) 44.62,104.06 46.01,102.67 46.01,88.9 46.96,87.94 v1(46.96,87.82)
VCOUT1_PH: length 5.2
  TOP w0.102: RE33.1 CE9.1 CE13.1 v2(48.22,85.19) 47.33,84.3 UE1.103
VGATE: length 226.9
  TOP w0.102: v1(47.98,71.5) 49.5,73.02 UE1.74
  TOP w0.203: PUZ01.20 145.22,138.34 144.81,137.93 v1(144.81,137.66)
  IN1 w0.127: v1(47.98,71.5) 46.64,70.16 39.4,70.16 39.08,69.84 39.08,68.54 41.05,66.58 41.05,61.26 48.99,53.32 48.99,41.97 47.87,40.85 47.87,32.02 47.07,31.22 v1(47.07,30.67) ; v1(81.82,137.09) 80.74,136.01 77.19,136.01 75.92,134.74 75.92,131.95 74.68,130.72 72.55,130.72 70.75,128.92 70.75,116.43 70.17,115.85 70.17,114.14 70.5,113.81 70.5,92.17 65.3,86.98 65.3,86.38 62.73,83.82 57.22,83.82 51.66,89.38 48.95,89.38 v1(48.93,89.4)
  BOTTOM w0.102: v1(47.98,71.5) 48.05,71.57 48.05,76.52 51.28,79.75 51.28,86.1 50.2,87.18 50.2,87.56 48.93,88.83 v1(48.93,89.4) ; v1(81.82,137.09) 107.6,137.09 109.06,135.63 136.43,135.63 137.44,136.63 142.52,136.63 ; RC38.1 v1(47.07,30.67)
  BOTTOM w0.127: v1(144.81,137.66) 145.26,137.22 145.26,136.65 144.94,136.33 143.91,136.33 PRZ70.2 142.52,136.63
VL: length 2.4
  BOTTOM w0.254: PU501.15 42.78,106.22 v2(43.43,105.57) 43.66,105.34 PC515.1
VR_ON: length 228.2
  TOP w0.102: v1(47.02,90.1) v2(46.05,90.1) 42.39,90.1 41.37,89.09 41.37,87.05 40.67,86.36 40.67,85.09 40.13,84.54 UE1.121 ; v1(74.32,131.39) PRZ85.1
  TOP w0.254: PRH20.2 164.5,72.18 162.11,74.58 v1(162.11,74.6)
  IN1 w0.127: v1(47.02,90.1) 47.05,90.08 51.68,90.08 57.42,84.34 62.53,84.34 64.79,86.59 64.79,87.19 69.95,92.34 69.95,113.64 69.66,113.93 69.66,116.06 70.24,116.64 70.24,129.13 72.34,131.22 74.15,131.22 v1(74.32,131.39) ; v1(162.11,74.6) 162.11,76.44 158.36,80.18 155.99,80.18 155.56,80.62 155.56,82.96 v1(155.33,83.19)
  IN2 w0.127: v1(74.32,131.39) 74.32,132.19 75.56,133.43 75.56,134.53 80.03,139 117.88,139 118.32,138.55 118.32,138.37 116.61,136.66 116.61,132.26 124.18,124.69 v1(124.42,124.69)
  BOTTOM w0.102: v1(124.42,124.69) 124.42,115.27 133.9,105.79 142.64,105.79 144.27,104.16 144.27,97.53 144.92,96.88 144.92,92.71 146.36,91.26 146.36,90.74 153.91,83.19 v1(155.33,83.19)
VREF_0.775V: length 11.9
  TOP w0.102: PQ801.1 v2(146.42,43.4)
  TOP w0.254: v1(150.94,43.39) 150.93,43.4 PQ801.1
  BOTTOM w0.254: PR802.2 150.49,44.94 PR803.1 151.47,44.9 151.86,44.51 151.86,43.68 151.57,43.39 v1(150.94,43.39) 150.65,43.1 PC803.1 149.02,43.1 148.9,43.22 PU800.3
VSUM+_APU: length 14
  TOP w0.203: PUZ01.14 144.53,140.74 v1(144.43,140.84)
  TOP w0.254: v1(141.94,140.56) 141.94,141.28 141.77,141.46 PCZ66.1 140.69,141.46 140.67,141.45 PCZ53.1 ; PRZ71.1 PRZ79.1 139.91,144.66 PRZ84.1 138.97,143.82 v1(138.97,143.7)
  BOTTOM w0.254: v1(144.43,140.84) 142.72,140.84 142.44,140.56 v1(141.94,140.56) 141.11,140.56 v2(140.79,140.87) 139.04,142.63 139.04,143.63 v1(138.97,143.7)
VSUM+_APU_R: length 24.6
  TOP w0.102: v1(145.07,127.95) v2(145.6,127.95)
  TOP w0.254: v1(139.99,142.62) 139.99,143.19 PRZ84.2
  IN1 w0.254: v1(145.07,127.95) 143.16,129.85 143.16,130.3 137.89,135.57 137.89,140.52 v1(139.99,142.62)
  BOTTOM w0.254: v1(145.07,127.95) 145.07,125.22 145.51,124.78 PLZ04.2
VSUM-_APU: length 34
  TOP w0.102: v1(144.36,129.65) v2(143.79,129.65)
  TOP w0.254: v1(142.27,144.74) 142.27,144.38 PRZ71.2 141.55,143.66 PCZ66.2 140.69,142.38 140.67,142.36 PCZ53.2 140.66,142.3 140.41,142.04 PCZ65.1 138.91,141.65 v1(138.91,140.77) ; v1(144.12,141.63) 144.12,141.65 143.85,141.92 PRZ72.1 143.46,141.91 PRZ66.1
  IN1 w0.254: v1(138.91,140.77) 138.46,140.33 138.46,135.7 142.07,132.09 v1(144.36,129.65)
  BOTTOM w0.254: v1(142.27,144.74) 142.69,144.74 143.86,143.57 143.86,141.88 v1(144.12,141.63) ; PLZ04.3 143.87,124.78 144.36,125.27 PHZ4.2 v1(144.36,129.65)
VSUMN_NB: length 73.6
  TOP w0.254: v1(160.4,128.95) 160.52,128.82 160.52,120.85 154.56,114.89 154.56,112.36 149.23,107.04 149.23,100.66 150.42,99.47 161.28,99.47 162.34,98.42 v2(162.34,98.19) v1(162.34,97.48) ; v1(157.7,139.38) 157.7,139.82 158.28,140.39 PRZ11.2 158.52,141.28 PCZ11.2 158.58,142.36 PCZ12.2 157.69,142.43 PCZ14.1 PRZ13.1 157.72,143.38 PRZ15.1
  BOTTOM w0.254: v1(157.7,139.38) 157.32,139 157.32,134.04 159.36,132.01 159.36,129.99 v1(160.4,128.95) ; v1(162.34,97.48) PHZ1.2 158.03,97.48 157.49,96.94 PLZ02.3
VSUMP_NB: length 18.4
  TOP w0.203: v1(151.1,142.48) 151.1,142.07 150.97,141.94 PUZ01.40
  TOP w0.254: v1(155.29,145.28) 156.24,145.28 156.69,144.84 159.8,144.84 160.12,144.52 160.12,142.68 159.86,142.43 PCZ12.1 159.43,141.41 PCZ11.1 159.43,141.28 PRZ11.1 PRZ09.1 159.23,139.37 PRZ12.1
  BOTTOM w0.254: v1(151.1,142.48) 151.41,142.48 152.82,143.89 154.53,143.89 v2(155.04,144.39) 155.29,144.65 v1(155.29,145.28)
VSUMP_NB_R: length 62.9
  TOP w0.254: PRZ12.2 158.4,136.39 v1(158.4,136.33) ; v1(161.77,98.23) 161.77,98.48 161.13,99.12 150.28,99.12 148.88,100.52 148.88,107.18 154.2,112.51 154.2,115.04 160.17,121 160.17,128.15 159.91,128.41 v2(159.91,128.51) 159.91,129.77 v1(160.35,130.21)
  BOTTOM w0.254: v1(161.77,98.23) 161.64,98.1 157.9,98.1 157.49,98.5 PLZ02.2 ; v1(160.35,130.21) 160.35,132.35 158.4,134.3 v1(158.4,136.33)
VTTREF_1.2V: length 2.3
  BOTTOM w0.203: PCM19.1 60.17,112.77 60.68,113.28 v2(60.91,113.28) 61.44,113.28 61.46,113.3 PUM01.4
WL_OFF#: length 178.9
  TOP w0.102: v1(147.16,82.08) 147.16,82.67 149.01,84.51 151.16,84.51 153.64,86.99 160.5,86.99 163.86,90.36 163.86,99.63 162.34,101.15 162.34,128.84 160.56,130.61 v2(158.24,130.61) 140.69,130.61 v1(140.62,130.68) ; RW13.2 71.01,136.89 71.45,137.32 72.89,137.32 73.31,136.9 v1(73.31,134.81)
  IN1 w0.102: v1(134.67,79.39) 138,79.39 138.49,79.87 139.88,79.87
  IN1 w0.127: 139.88,79.87 139.94,79.87 139.95,79.86 146.01,79.86 147.16,81.01 v1(147.16,82.08)
  IN2 w0.127: v1(73.31,134.81) 75.46,134.81 79.93,139.28 112.45,139.28 113.31,140.13 117.22,140.13 117.93,139.42 136.58,139.42 136.81,139.19 136.81,134.49 v1(140.62,130.68)
  BOTTOM w0.102: UC1.AA4 134.43,79.57 134.61,79.39 v1(134.67,79.39) ; RC98.2 147.33,81.65 147.16,81.83 v1(147.16,82.08)
WL_OFF#_R: length 3.8
  TOP w0.102: RW13.1 RW11.1 72.65,136.04 v2(72.9,135.79) v1(72.9,135.29)
  BOTTOM w0.102: JWLAN1.56 72.89,135.3 v1(72.9,135.29)
WLAN_EN: length 89
  TOP w0.102: v1(52.14,67.2) 51.28,68.07 50.73,68.07 50.46,67.8 UE1.64 ; UW1.4 73.42,125.6 v1(73.73,125.92)
  IN1 w0.127: v1(73.73,125.92) 72.02,124.21 72.02,114.14 73.52,112.64 73.52,108.35 75.48,106.38 75.48,100.64 74.09,99.25 74.09,94.04 73.41,93.37 73.41,90.06 72.93,89.58 70.93,89.58 69.29,87.94 69.29,83.66 68.74,83.12 66.9,83.12 v1(65.82,84.2)
  BOTTOM w0.102: v1(65.82,84.2) 64.31,85.71 59.77,85.71 59.08,86.41 58.09,86.41 56.82,85.14 56.82,79.98 RE54.1 56.71,79.09 57.25,78.56 57.25,75.87 58.02,75.1 58.02,71.08 55.7,68.75 53.62,68.75 52.14,67.28 v1(52.14,67.2)
WLAN_WAKE#: length 74.3
  TOP w0.102: UE1.90 52.41,79.42 52.78,79.05 55.08,79.05 55.69,79.66 RE25.1 55.69,80.51 57.5,82.32 v1(57.5,83.37) ; RW6.1 79.6,132.01 v2(79.34,131.75) 79.16,131.57 v1(77.82,131.57)
  IN1 w0.127: v1(77.82,131.57) 75.98,131.57 74.88,130.46 72.66,130.46 71.01,128.81 71.01,116.33 70.42,115.74 70.42,114.25 70.75,113.92 70.75,92.07 65.55,86.87 65.55,86.28 62.84,83.56 57.69,83.56 v1(57.5,83.37)
WLAN_WAKE#_R: length 4
  TOP w0.102: RW6.2 79.6,134.63 v2(79.46,134.77) 79.34,134.89 78.15,134.89 v1(77.9,134.65)
  BOTTOM w0.102: JWLAN1.55 78.31,135.05 v1(77.9,134.65)
WOL_EN: length 52.5
  TOP w0.102: UL2.4 45.74,47.24 RL11.2 46.63,46.78 v1(47.03,47.19) 47.34,47.49 v2(47.34,47.72) ; UE1.98 49.33,81.68 47.56,79.9 47.56,76.36 v1(47.08,75.89)
  IN1 w0.127: v1(47.08,75.89) 44.41,75.89 44.1,76.2 42.55,76.2 41.92,75.56 40.14,75.56 39.41,74.82 39.41,72.45 39.66,72.19 39.66,71.6 39.12,71.06 39.12,70.59 37.99,69.47 37.99,68.23 40.48,65.74 40.48,59.96 47.6,52.85 47.6,47.81 47.03,47.25 v1(47.03,47.19)
XCLKI: length 5
  TOP w0.102: UE1.122 39.73,84.26 39.05,84.94 YE1.3 39.05,86.42 40.24,87.61 RE34.2
N17389450: length 1.2
  TOP w0.102: PR503.2 42.21,106.91 v2(41.78,106.48)
N17415515:
  vias: v2(79.27,143.96)
N21380741: length 1
  BOTTOM w0.102: PC508.1 v2(43.1,104.07)
N23133643: length 1.2
  BOTTOM w0.102: PDB01.1 188.01,56.7 v2(187.61,57.09)
N27121430: length 10
  TOP w0.508: RC3.2 106.67,79.88 106.84,80.05 109.06,80.05 109.94,80.93 v1(109.94,80.98)
  BOTTOM w0.102: UC1.AA40 114.04,79.6
  BOTTOM w0.11: 114.04,79.6 113.77,79.6 113.36,79.78
  BOTTOM w0.2: 113.36,79.78 113.25,79.78
  BOTTOM w0.3: 111.29,79.81 111.3,79.82 113.21,79.82 113.25,79.78
  BOTTOM w0.38: 111.29,79.81 110.54,79.81 v2(110.21,80.14) 109.94,80.41 v1(109.94,80.98)
N27174658: length 104.6
  TOP w0.102: v1(194.98,59.37) v2(194.98,58.8)
  TOP w0.254: v1(146.33,83.03) 146.32,83.03 PR904.2 ; PD901.1 174.7,45.8 v1(174.28,46.22) 174.24,46.26 PC903.2 174.24,47.28 174.2,47.32 PR905.2
  TOP w0.305: PU900.3 172.87,45.79 173.52,45.14 PD901.1
  IN1 w0.127: v1(146.33,83.03) 146.33,83.03 148.22,83.03 149.18,83.99 157.98,83.99 165.58,76.39 174.78,76.39 177.14,74.03 177.97,74.03 181.71,70.29 181.71,69.51 185.24,65.97 191.55,65.97 195.36,62.16 195.36,59.75 v1(194.98,59.37)
  IN2 w0.254: v1(174.28,46.22) 173.14,46.22 171.48,47.87 171.48,52.13 173.07,53.72 173.07,56.64 175.04,58.61 176.56,58.61 177.26,59.3 187.68,59.3 188.06,58.92 194.53,58.92 v1(194.98,59.37)
N27174719: length 4.9
  TOP w0.102: PR907.2 169.83,48.73 169.05,47.95 v2(168.74,47.95)
  TOP w0.254: PR907.2 PR908.2 170.8,48.88 171.14,48.53 PC904.2 171.89,48.06 172.06,48.06 172.37,47.75 PU900.6
N27174755: length 6.7
  TOP w0.102: v2(173.44,51.85) 173.86,51.43 PD902.1
  TOP w0.254: PU900.5 172.87,47.95 172.18,48.64 PC905.1 173.01,48.69 PR911.1 173.87,48.62 173.88,48.64 PR909.1 173.88,50.64 PD902.1
N27174767: length 4.4
  TOP w0.102: v2(167.23,52.05) PD900.1
  TOP w0.254: PD900.1 168.25,50.86 168.98,50.12 PR906.2 PR907.1
N27174913: length 37.4
  TOP w0.254: v1(171.36,45.02) 171.36,44.76 170.2,43.6 PQ900.6 170.2,42.94 171.5,41.64 PQ900.3 ; PR901.1 191.61,55.68 v2(191.98,56.05) 192.38,56.45 v1(192.58,56.45)
  IN1 w0.254: v1(171.36,45.02) 171.36,45.14 171.74,45.52 176.56,45.52 176.69,45.65 180.88,45.65 182.03,46.79 182.03,51.11 186.6,55.68 186.6,56.7 187.21,57.31 188.33,57.31 189.45,56.19 192.12,56.19 192.38,56.45 v1(192.58,56.45)
N27175044: length 3.7
  TOP w0.254: PR902.2 PR903.2 173.16,44.1 PC901.2 v2(172.5,45.08) 172.5,45.46 172.37,45.59 PU900.2
N28483977: length 5.2
  TOP w0.102: v2(177.66,57.16) 177.17,57.64 PR31.2
  TOP w0.254: PR45.1 PR35.2 ; PR45.1 175.51,57.63 PR31.2 ; PR45.1 174.77,57.69 PQ13.2
N28484391: length 3
  TOP w0.102: v2(169.93,54.66) 170.19,54.4 PR33.2
  TOP w0.254: PQ12.6 171.81,54.41 PC13.1 PR33.2
N28484416: length 2.9
  TOP w0.102: PR36.2 176.64,54.96 v2(176.64,54.08)
  TOP w0.381: PR36.2 175.71,55.1 PR44.2 175.67,55.06 PQ12.2
N28484439: length 3.1
  TOP w0.102: v2(196.81,44.34) PC14.2
  TOP w0.254: PR43.1 196.82,45.47 PC14.2 195.94,45.46 PQ11.2
N28484451: length 4.3
  TOP w0.102: PQ13.6 v2(172.98,60.4)
  TOP w0.381: PQ13.6 174.12,60.86 173.85,61.13 PR34.2 PR38.1 174.58,61.22 174.77,61.03 PQ13.5
N28484500: length 3.6
  TOP w0.102: PR40.1 171.69,56.85 v2(171.69,57.77)
  TOP w0.254: PR40.1 171.8,56.67 PC13.2 172.06,55.06 PQ12.5
N28866422: length 12.2
  TOP w0.203: PRB02.3 183.1,58.91 183.37,59.18 184.63,59.18 v2(184.89,58.92) 185.33,58.48 185.33,57.51 v1(185.2,57.39)
  IN2 w0.254: v1(185.2,57.39) 185.35,57.23 185.35,55.38 188.41,52.32 v1(189.07,52.32)
  BOTTOM w0.254: v1(189.07,52.32) 189.65,51.75 PRB12.1
N28866577: length 2
  TOP w0.102: v2(200.87,49.72) 200.11,49.72 PCB11.1
  TOP w0.254: PCB11.1 199.83,50 PRB30.2
N28866613: length 11.9
  TOP w0.203: v1(185.9,57.39) 185.71,57.58 v2(185.71,57.92) 185.71,58.64 184.85,59.49 183.3,59.49 183.1,59.69 PRB02.2
  IN2 w0.254: v1(185.9,57.39) 185.73,57.22 185.73,55.54 188.06,53.21 v1(189.14,53.21)
  BOTTOM w0.254: v1(189.14,53.21) 189.14,53.2 PRB11.1
N29056076: length 3.7
  TOP w0.102: v2(193.86,57.53) PQB29.1
  TOP w0.254: PQB29.1 191.11,57.53 190.73,57.15 PQB28.2
N29179188: length 2.5
  TOP w0.102: PQB03.3 185.33,65.96 v2(185.94,65.35)
N29179461:
  vias: v1(184.37,61.97) v1(184.37,61.4) v1(184.95,61.97) v1(184.95,61.4) v2(184.97,60.85)
N29179506: length 53.3
  TOP w0.381: v1(182.15,62.03) 181.68,62.51 PQB12.4 ; PQB03.1 185.55,68.35 v2(185.39,68.51) 184.69,69.21 181.85,69.21 180.26,67.62 v1(180.12,67.62) 179.84,67.62 179.46,67.24 PQB11.4 179.85,66.72 179.97,66.84 180.98,66.84 PCB01.2
  IN1 w0.254: v1(182.15,62.03) 181.52,62.67 181.52,65.97 180.12,67.37 v1(180.12,67.62)
  IN1 w0.508: v1(182.15,62.03) 185.01,59.18 188.82,59.18 190.41,57.59 197.27,57.59 198.03,56.83 198.03,54.86 197.68,54.52 197.68,49.12 195.68,47.11 194.69,47.11 193.61,46.03 v1(193.61,44.07)
  BOTTOM w0.508: PRB07.1 192.59,44.36 192.6,44.34 193.33,44.34 v1(193.61,44.07)
N33029358: length 2.5
  TOP w0.102: RA32.2 35.14,16.44 35.06,16.37 34.58,15.84 34.58,14.91 34.48,14.81 UA1.10
N33029552: length 0.8
  TOP w0.102: RA50.1 CA487.2
N33029645: length 1.7
  TOP w0.203: RA31.2 RA48.1 34.72,17.2 CA478.1
N33495776: length 5.1
  BOTTOM w0.102: v2(93.82,136.09) 93.82,134.82 93.14,134.13 RH3.2 93.14,133.55 92.62,133.03 JHDT1.13
N33495778: length 4.1
  BOTTOM w0.102: v2(94.76,135.19) 94.13,134.55 RH4.2 94.13,133.4 93.89,133.15 JHDT1.15
N33495792: length 5.1
  BOTTOM w0.102: 91.35,131.44 91.35,132.77 92.25,133.67 RH2.2 92.21,134.12 91.77,134.56 v2(91.77,135.99)
N33497375: length 1.1
  TOP w0.254: RC30.2 118.16,91.38 T12.1
N33500586: length 7.8
  BOTTOM w0.102: T17.1 129.68,63.13 129.15,63.65 ; UC1.AY16 127.98,69.66
  BOTTOM w0.105: 127.98,69.66 127.98,69.4 128.3,69.08 128.3,68.83 128.19,68.72 128.19,68.35 127.83,67.99 127.83,67.1 128.17,66.76 128.17,64.63 129.15,63.65
N33500588: length 3.1
  BOTTOM w0.102: T16.1 129.42,66.01 129.42,67.68 129.49,67.75 129.49,68.47 UC1.BA13
N33500590: length 8.6
  BOTTOM w0.102: T15.1 130.1,62.38 129.56,62.91
  BOTTOM w0.105: 129.56,62.91 127.92,64.56 127.92,66.61 127.63,66.9 127.63,68.08 127.98,68.44 UC1.BA16
N33500707: length 3.3
  BOTTOM w0.105: UC1.AY15 128.76,69.07 128.76,68.83 128.84,68.75 128.84,67.99 128.64,67.78 128.64,66.33 T14.1
N33501029: length 4.2
  BOTTOM w0.102: T13.1 128.52,65.43 128.75,65.66
  BOTTOM w0.105: UC1.BA14 129.06,68.93 129.06,67.89 128.93,67.77 128.93,65.84 128.75,65.66
N33501291: length 87.7
  TOP w0.102: RC63.2 146.12,78.56 147.37,78.56 147.6,78.33 v1(148.38,78.33) ; RC67.1 100.3,44.83 100.55,44.57 100.55,43.56 v2(100.3,43.31) 100.05,43.05 ; 100.05,43.05 100.05,42.13 v1(100.35,41.83) ; 100.05,43.05 98.65,43.05 98.33,43.37 RC65.2 98.32,43.77 CC16.1 98.32,45.79 UC13.2 UC13.1
  IN1 w0.127: v1(100.35,41.83) 100.45,41.83 100.62,41.99 105.21,41.99 106.08,41.13 110.36,41.13 110.91,41.68 119.51,41.68 120.25,42.41 127.86,42.41 128.68,43.24 129.57,43.24 130.4,44.06 130.4,44.57 130.65,44.83 130.65,46.18 133.5,49.03 133.5,50.54 140.5,57.53 140.5,72.13 143.54,75.18 145.39,75.18 145.89,74.67 146.91,74.67 147.74,75.5 147.74,76.77 148.38,77.41 v1(148.38,78.33)
N33501698: length 5.7
  BOTTOM w0.102: UC1.AY14 129.08,69.41 129.4,69.09 129.4,68.82 129.26,68.68 129.26,67.81 129.14,67.68 129.14,65.01 T25.1
N33504981: length 7.6
  BOTTOM w0.102: UC1.BA25 123.03,67.04 122.98,66.99 122.98,65.4 123.12,65.26 v2(123.12,64.96) 123.12,64.23 122.98,64.09 122.98,63.18 122.9,63.1 RC107.2
N33505212: length 8.2
  BOTTOM w0.102: RC109.2 124.04,61.5 v2(124.04,62.63) 124.04,64.02 124.14,64.13 124.14,64.9 123.49,65.55 123.49,68.17 123.58,68.26 UC1.BA24
N33518659: length 2.7
  TOP w0.102: RD4.2 78.11,76.74 v1(77.72,77.12)
  BOTTOM w0.102: JDIMM1.143 78.11,76.74 v1(77.72,77.12)
N33520030: length 2.5
  TOP w0.102: v2(69.25,83.49) v1(69.74,83.49) 69.91,83.66 RD1.2
  BOTTOM w0.102: JDIMM1.116 v1(69.74,83.49)
N33523233: length 2.6
  TOP w0.102: UV1.3 221.18,55.86 RV3.2 v2(223.63,55.86)
N33524727: length 15
  BOTTOM w0.102: RV18.2 RV19.2 RV20.2 RV21.2 RV17.2 RV16.2 RV35.2 RV34.2 v2(24.32,103.77) 26.98,106.43 27.91,106.43 28.36,105.98 QV1.1
N33525049: length 3.6
  BOTTOM w0.102: QV2.2 27.66,98.64 27.33,98.97 v2(27.33,99.27) 27.33,99.54 27.97,100.19 RV30.1
N33527050: length 3.7
  TOP w0.102: v1(73.89,133.43) 74.21,133.75 T19.1
  BOTTOM w0.102: v1(73.89,133.43) 73.55,133.76 72.57,133.76 72.11,133.3 JWLAN1.48
N33527052: length 2.8
  TOP w0.102: T24.1 73.81,132.82 v1(73.76,132.77)
  BOTTOM w0.102: v1(73.76,132.77) 73.73,132.8 JWLAN1.46
N33527054: length 2.6
  TOP w0.102: T23.1 73.64,131.84 v1(73.19,132.3)
  BOTTOM w0.102: JWLAN1.44 v1(73.19,132.3)
N33528036: length 3.6
  TOP w0.254: DA10.2 20.2,12.75 20.48,13.04 20.71,13.04 v2(20.75,13.07) 21.45,13.77 RA52.1
N33528038: length 3.4
  TOP w0.254: DA10.3 18.79,11.75 18.86,11.68 20.77,11.68 v2(20.88,11.8) 21.14,12.05 21.6,12.05 RA53.1
N33534280: length 4.1
  BOTTOM w0.102: R28.2 109.65,45.4 v2(109.41,45.64)
  BOTTOM w0.508: 110.59,44.57 R28.2 109.65,43.76 Q3.3
N33534316: length 4
  BOTTOM w0.102: v2(109.25,33.89) 109.51,34.15 Q6.1 110.28,35.77 R32.1
N33537088: length 28.1
  TOP w0.102: v1(83.4,32.38) v4(82.83,32.95) 67.36,32.95 66.47,33.84 60.3,33.84 59.84,34.3 R41.1 R39.2
  BOTTOM w0.102: JKB1.30 82.95,32.83 v1(83.4,32.38)
N33537136: length 2.9
  BOTTOM w0.102: v2(59.59,37.02) 59.74,36.88 RE43.2 59.74,35.35 59.75,35.34 JKB1.1
N33538511: length 17.1
  TOP w0.102: v1(10.26,120.52) v2(9.76,120.52)
  TOP w0.254: v1(10.26,120.52) 10.83,119.95 R40.1
  IN1 w0.254: v1(10.26,120.52) 10.26,121.03 9.11,122.17 7.46,122.17 2.96,126.68 2.96,130.45 v1(2.85,130.55)
  BOTTOM w0.254: v1(2.85,130.55) 3.02,130.55 3.34,130.87 3.34,131.74 3.25,131.83 LED1.2
N33538529: length 15.6
  TOP w0.102: v1(10.36,122.17) v2(9.83,122.17)
  TOP w0.254: R43.1 10.61,122.42 v1(10.36,122.17)
  IN1 w0.254: v1(2.85,131.19) 3.08,131.19 3.34,130.93 3.34,126.93 7.59,122.68 9.37,122.68 9.88,122.17 v1(10.36,122.17)
  BOTTOM w0.254: v1(2.85,131.19) 2.55,131.49 LED1.4
N33538830: length 4.1
  BOTTOM w0.102: Q14.6 Q14.5 15.59,119.57 15.34,119.31 15.34,118.22 R50.2 v2(15.77,116.77)
N33539236: length 9.6
  BOTTOM w0.102: JKBBL1.2 94.05,34.76 94.22,34.92 94.45,34.92 97.52,37.99 v1(99.17,37.99) 99.59,37.58 99.59,36.57 R30.2
N33547368: length 3.6
  BOTTOM w0.102: QS1.6 104.61,42.11 104.68,42.04 104.68,41.65 104.49,41.46 QS1.5 103.77,41.46 103.65,41.35 RS25.2 103.16,42.15 v2(103.01,42.3)
N33548334: length 8.6
  BOTTOM w0.102: v2(44.17,25.38) 42.6,25.38 42.25,25.74 RS27.1 42.12,25.97 40.55,25.97 39.84,25.26 37.96,25.26 37.82,25.4 37.44,25.4 37.13,25.71 JSSD1.10
N33548545: length 8.2
  BOTTOM w0.102: v2(44.12,26.67) 43.77,26.32 42.72,26.32 RS26.1 41.68,26.22 40.42,26.22 39.66,25.46 38.04,25.46 37.63,25.87 JSSD1.8
N33548604: length 3.9
  TOP w0.102: RS28.1 v1(31.66,25.2) v2(31.66,24.66)
  BOTTOM w0.102: JSSD1.38 30.13,25.59 30.51,25.2 v1(31.66,25.2)
N33562066: length 3.4
  TOP w0.102: Q16.1 153.86,56.98 154.21,57.34 R56.2 v2(155.41,57.78)
N33562240: length 3.8
  BOTTOM w0.102: R55.1 120.87,37.22 Q15.3 ; v2(120.28,36.15) Q15.3 ; Q15.3 119.84,37.22 119.77,37.29 119.77,37.75 119.89,37.87 Q15.2
N33563792: length 3.3
  BOTTOM w0.102: R64.2 125.54,41.68 125.43,41.58 U6.3 ; R64.2 R68.2 ; R64.2 124.61,42.28 v2(124.51,42.17)
N33563833: length 3.5
  BOTTOM w0.102: Q18.1 131.21,42.46 131.8,43.06 R71.2 132.23,43.85 132.77,44.39 v2(132.77,44.99)
N33563843: length 3.4
  BOTTOM w0.102: Q20.1 131.77,38.44 132.11,38.1 132.11,37.19 v2(131.89,36.97) 131.62,36.7 R72.2
N33563845: length 8.9
  BOTTOM w0.102: v2(134.21,45.02) 134.21,43.92 Q19.3 132.93,43.42 132.45,42.94 132.45,42.3 131.86,41.71 130.4,41.71 130.02,42.1 130.02,43.11 129.71,43.42 Q18.3
N33563855: length 5.9
  BOTTOM w0.102: Q21.3 132.16,40.88 v2(131.91,40.88) 130.44,39.41 Q20.3
N33563865: length 15.3
  BOTTOM w0.102: v2(137.8,43.54) C39.1 ; C39.1 137.79,42.46 Q19.1 135.79,41.52 135.61,41.33 135.61,40.38 134.97,39.75 134.97,38.73 135.26,38.44 Q21.1 136.64,38.44 137,38.08 C44.1 C38.1 139.87,38.08 R73.1 ; C39.1 C40.1 C37.1
N33564171: length 1.7
  BOTTOM w0.102: v2(122.46,36.7) 122.94,37.18 123.94,37.18
N33564185: length 18.8
  TOP w0.102: v1(114.02,36.88) 114.02,36.84 114.49,36.36 116.13,36.36 v2(117.62,34.87) 118.46,34.03 122.78,34.03 124.43,35.68 v1(124.73,35.68)
  BOTTOM w0.102: C46.1 R65.1 R63.1 114.7,37.87 114.02,37.19 v1(114.02,36.88) ; v1(124.73,35.68) 124.73,36.23 125.43,36.94 U6.6
N33564230: length 5.4
  BOTTOM w0.102: R66.1 126.72,36.52 127.29,37.1 C47.1 126.72,37.27 126.21,37.27 126.08,37.39 U6.5 ; R66.1 126.71,36.35 R67.1 ; R66.1 126.72,35.64 v2(126.96,35.4)
N33566966: length 5.3
  TOP w0.102: UE1.76 v2(52.99,73.82) 53.66,73.82 54.21,73.27 55.15,73.27 56.03,72.4 RE48.1
N33567076: length 2
  TOP w0.102: CE8.1 v2(31.24,78.16)
  TOP w0.254: RE11.2 CE8.1
N33568379: length 4.5
  TOP w0.102: UE1.125 38.53,81.32 v1(38.5,81.29)
  BOTTOM w0.102: RE36.1 v2(37.51,81.02) 38.23,81.02 v1(38.5,81.29)
N34251929: length 1.6
  TOP w0.102: v1(124.68,73.25) 124.61,73.25 124.06,72.7 T26.1
  BOTTOM w0.102: v1(124.68,73.25) 124.53,73.11 UC1.AP23
N34251932: length 1.2
  TOP w0.102: v1(122.48,73.51) 122.52,73.54 T27.1
  BOTTOM w0.102: UC1.AP25 122.63,73.51 v1(122.48,73.51)
N34251935: length 1.4
  TOP w0.102: T28.1 122.48,72.65 v1(122.48,72.71)
  BOTTOM w0.102: UC1.AR25 122.63,72.71 v1(122.48,72.71)
N34251938: length 1.3
  TOP w0.102: v1(123.58,71.11) 123.6,71.09 T29.1
  BOTTOM w0.102: UC1.AV25 123.43,71.11 v1(123.58,71.11)
N34368532: length 5
  TOP w0.102: v2(31.95,50.33) 31.95,50.95 31.78,51.11 31.78,52.01 32.11,52.34 C17.1 33,53.08 33,54.15 33,54.15 U2.12
N34368546: length 2.6
  TOP w0.102: U2.10 32.2,54.13 32.1,54.03 v2(32.1,53.44) 32.1,53.2 C24.1
N34368727: length 2.8
  TOP w0.102: v1(159.8,44.57) 159.74,44.57 159.44,44.27 U3.12
  BOTTOM w0.102: v1(159.8,44.57) 159.81,44.59 C20.2 v2(159.81,46.38)
N34582676: length 5.4
  TOP w0.102: RE20.1 52.6,85.76 52.47,85.63 52.21,85.63 v2(51.66,85.09) 51.66,84.07 50.58,82.99 49.83,82.99 49.73,83.09 UE1.97
N34587636: length 2.4
  TOP w0.102: v2(40.42,47.33) 40.56,47.47 RL10.2 41.74,47.24 UL2.3
N34587774: length 1.6
  TOP w0.102: UL1.27 21.69,86.21 TP53.1
N34587776: length 1.9
  TOP w0.102: v1(21.62,87.56) 21.69,87.56 22.24,87.01 UL1.25
  BOTTOM w0.102: v1(21.62,87.56) 21.73,87.66 TP54.1
N34587780: length 2.1
  TOP w0.102: v1(21.59,86.96) 21.94,86.61 UL1.26
  BOTTOM w0.102: RL6.2 21.43,86.8 v1(21.59,86.96)
N34587808: length 3.5
  TOP w0.203: UL1.31 21.85,84.61 21.69,84.45
  TOP w0.254: 21.69,84.45 21.69,83.56 v2(21.26,83.13) 21.01,82.88 RL7.2
N35139402: length 2.9
  BOTTOM w0.102: v2(130.97,53.51) 131.38,53.1 131.38,52.31 CC121.1 RC128.1
N35174703: length 3.6
  TOP w0.102: v2(198.04,56.83) 197.95,56.74 PRB42.2
  TOP w0.254: PRB42.2 198.03,55.71 PRB43.1 197.03,54.67 PQB33.1
N35174707: length 3.6
  TOP w0.102: PQB32.2 199.86,54.47 200.62,53.72 v2(200.62,53.46)
  TOP w0.254: PRB43.2 198.93,53.75 PCB36.1 198.94,53.93 199.48,54.47 PQB32.2
N35501849: length 5
  TOP w0.102: US1.20 186.56,42.39 186.2,42.74 184.58,42.74 v2(184.23,43.09) 183.89,43.43 183.3,43.43 183.04,43.68 RS6.2
N35501851: length 3.4
  TOP w0.102: RS5.2 190.36,35.81 190.36,36.28 v2(190.1,36.53) 189.78,36.85 189.11,36.85 188.56,37.4 US1.10
N35711175: length 4.4
  TOP w0.102: RE53.1 54.69,80.47 v2(53.74,79.51) 53.61,79.38 52.74,79.38 52.46,79.67 52.46,80.04 52.28,80.22 UE1.92
N35713947: length 7.3
  TOP w0.102: UL1.19 25.08,88.29 26.38,89.59 28.94,89.59 29.05,89.71 v2(29.05,89.73) 29.05,90.14 RL16.1 29.71,90.8 RL17.1
N38653708: length 2.7
  TOP w0.102: PRH05.2 v2(165.77,64.33)
  TOP w0.254: v1(166.11,65.29) 166.17,65.29 166.73,64.74 PRH05.2
  BOTTOM w0.254: PUH01.7 166.06,65.23 v1(166.11,65.29)
N39173777: length 4.8
  BOTTOM w0.102: 167.32,65.83 166.86,66.29 v2(166.86,67.75)
  BOTTOM w0.254: PUH01.9 166.53,63.93 166.75,64.15 166.75,65.27 167.32,65.83 PCH10.1
N39173785: length 5
  BOTTOM w0.102: v2(169.64,61.31) 169.45,61.12 168.05,61.12 PRH11.2
  BOTTOM w0.254: PUH01.11 166.6,63.03 167.17,62.46 PCH11.1 167.55,61.64 PRH11.2
N39200796: length 4
  BOTTOM w0.102: PRM06.2 66.24,116.06 66.3,116 66.86,116 66.99,116.12 v2(67.1,116.12)
  BOTTOM w0.203: PRM06.2 65.88,115.37 65.31,114.8 64.49,114.8 64.4,114.71 PUM01.10
N39291721: length 3.7
  TOP w0.102: v2(179.02,58.45) PR32.2
  TOP w0.381: PR32.2 175.77,58.45 PQ13.3
N39393826: length 3.3
  TOP w0.102: PQB03.2 184.1,67.65 v2(184.1,68.41)
  TOP w0.254: PQB03.2 183.26,66.81 PRB03.2 PRB04.1
N39406703: length 3.9
  BOTTOM w0.102: PRB31.2 198.97,49.08 199.39,49.5 v2(200.83,49.5)
  BOTTOM w0.203: PUB01.29 198.05,49.64 198.65,49.04 PRB31.2
N39655859: length 2.4
  TOP w0.102: PR507.2 v2(42.82,103.09)
  TOP w0.254: PD501.1 42.82,104.94 PR507.2
N39825950: length 2.9
  TOP w0.203: PRZ81.2 143.95,142.74 144.43,142.26 v1(144.43,142.25) 144.59,142.09 144.59,141.56 145.01,141.14 PUZ01.13
N39825993: length 2.6
  TOP w0.203: PUZ01.1 149.92,142.88 150.35,143.31 151.16,143.31 151.55,143.7 PRZ16.2
N39826003: length 29.2
  TOP w0.203: v1(142.27,143.35) 142.74,143.35 PRZ80.1 PRZ87.2
  IN1 w0.254: v1(142.27,143.35) 142.68,143.35 143.04,143 143.04,138.52 143.29,138.27 145.73,138.27 146.02,137.98 147.42,137.98 149.13,136.27 149.13,132.71 149.7,132.14 153.56,132.14 v1(154.67,131.03)
  BOTTOM w0.254: v1(154.67,131.03) v2(156.99,128.72) 158.02,127.68 PHZ3.2
N39826010: length 0.9
  TOP w0.254: PRZ07.1 154.15,141.96 PCZ07.2
N39826022: length 10.4
  TOP w0.203: PUZ01.37 151.21,140.74 151.35,140.89 152.96,140.89 PCZ08.1
  TOP w0.254: v1(152.56,142.16) 152.74,141.98 PRZ07.2 153.21,141.98 PCZ08.1 ; PRZ04.1 PRZ00.2 v1(155.8,142.79) 155.8,143.66 PRZ03.2
  IN2 w0.254: v1(155.8,142.79) 155.17,142.16 v1(152.56,142.16)
N39826039: length 6.5
  TOP w0.203: PUZ01.38 151.16,141.14 151.35,141.33 151.61,141.33
  TOP w0.254: PRZ03.1 154.96,143.69 PCZ07.1 154.89,142.79 PRZ06.2 154.07,142.82 PCZ10.2 152.4,142.82 v2(152.05,142.48) 152.05,141.59 151.79,141.33 151.61,141.33
N39826047: length 3.1
  TOP w0.203: PUZ01.15 144.69,140.34
  TOP w0.254: PCZ61.2 PRZ66.2 143.71,140.17 143.88,140.34 v1(144.12,140.34) 144.69,140.34
N39826052: length 0.9
  TOP w0.254: PRZ15.2 159.5,144.14 PCZ15.1
N39826074: length 0.9
  TOP w0.203: PRZ72.2 142.62,141.85 PCZ61.1
N39826078: length 3.8
  TOP w0.203: PUZ01.25 147.92,136.97 v2(148.39,136.49)
  TOP w0.254: v2(148.39,136.49) 148.62,136.26 PRZ26.1 148.62,134.22 148.62,134.21 PCZ63.1
N39826110: length 9.1
  TOP w0.203: PUZ01.39 151.12,141.54 151.42,141.85 v1(151.52,141.85)
  TOP w0.254: PCZ15.2 157.65,144.2 PRZ13.2 157.34,144.22 v1(156.69,143.57)
  BOTTOM w0.254: v1(156.69,143.57) 156.63,143.51 v2(156.05,143.51) 153.01,143.51 151.52,142.02 v1(151.52,141.85)
N39826159: length 3
  TOP w0.203: PUZ01.11 145.63,142.87 v1(145.41,143.09) 145.06,143.44 144.18,143.44 144.12,143.51 PRZ80.2
N39826167: length 6.5
  TOP w0.203: 143.67,139.24 144.29,139.86 144.32,139.86 144.36,139.9 v2(144.38,139.9) 144.4,139.9 144.44,139.94 PUZ01.16
  TOP w0.254: 143.67,139.24 PCZ59.1 142.77,138.07 PRZ47.1 142.71,138.07 141.88,138.9 PCZ60.1 141.81,138.9 141.4,138.48 141.4,138.47 140.89,137.97 PRZ75.1
N39826173: length 8.7
  TOP w0.254: v1(144.37,139.03) 144.37,139.31 144.62,139.57 145.6,139.57 PUZ01.17 ; v1(139.61,141.2) PRZ69.1 140.41,140.6 PCZ58.1
  BOTTOM w0.254: v1(139.61,141.2) 141.62,139.19 v2(143.05,139.19) 144.18,139.19 144.33,139.03 v1(144.37,139.03)
N39826315: length 4.9
  TOP w0.203: PUZ01.36 151.25,140.34 151.41,140.5 v2(152.05,140.5) 152.94,140.5 PCZ08.2 153.21,140.27 154.07,141.13 PRZ05.1 154.93,141.14 PCZ06.2
N39826443: length 0.9
  TOP w0.254: PRZ04.2 154.94,140.22 PCZ06.1
N39826445: length 0.9
  TOP w0.254: PCZ04.2 156.72,141.18 PRZ00.1
N39826475: length 7.9
  TOP w0.102: PRZ77.1 141.01,134.84 v2(140.57,134.4)
  TOP w0.203: 144.21,138.31 144.29,138.31 145.12,139.14 PUZ01.18
  TOP w0.254: PRZ77.1 141.04,135.43 PRZ65.1 141.04,136.26 PRZ73.2 142.74,137.1 PCZ68.1 143.61,137.99 143.65,137.99 143.67,138.02 PRZ47.2 143.67,138.1 143.89,138.31 144.21,138.31
N39826481: length 0.8
  TOP w0.254: PCZ60.2 141.85,137.22 PRZ73.1
N39826485: length 0.9
  TOP w0.254: PCZ37.1 PRZ65.2
N39826489: length 5.5
  TOP w0.102: v2(143.7,134.38) PRZ78.1
  TOP w0.203: PRZ78.1 143.7,136.16 PCZ57.2 143.67,136.66 143.66,136.67 PCZ68.2 143.78,137.13 144.33,137.68 144.33,137.92 145.15,138.74 PUZ01.19
N39826495: length 2.2
  TOP w0.102: v2(141.92,134.32) PRZ77.2
  TOP w0.254: PRZ77.2 141.96,135.4 PCZ57.1
N39826560: length 62.1
  TOP w0.254: PRZ09.2 158.52,139.11 v1(158.02,138.62) ; v1(162.35,96.57) v2(162.76,96.97) 162.82,97.04 162.82,98.44 161.43,99.83 150.57,99.83 149.59,100.81 149.59,106.89 154.91,112.21 154.91,114.74 160.88,120.71 160.88,129.16 v1(160.44,129.61)
  BOTTOM w0.254: v1(160.44,129.61) 160.27,129.61 159.8,130.08 159.8,132.2 157.7,134.3 157.7,138.3 v1(158.02,138.62) ; PHZ1.1 v1(162.35,96.57)
N39826575: length 17.1
  TOP w0.102: v1(145.27,129.66) v2(145.8,129.66)
  TOP w0.254: PRZ79.2 v1(140.88,143.14)
  IN1 w0.254: v1(145.27,129.66) 145.28,129.84 143.16,132.08 140.88,134.36 v1(140.88,143.14)
  BOTTOM w0.254: PHZ4.1 v1(145.27,129.66)
N39826587: length 59.3
  TOP w0.203: v1(153.13,145.22) 152.89,144.98 PRZ86.2 PRZ16.1
  IN1 w0.254: v1(149.01,109.47) 147.93,110.55 144.56,110.55 136.75,118.36 136.75,129.98 137.19,130.42 137.19,140.58 140.48,143.87 145.59,143.87 146.47,143 150.59,143 152.82,145.22 v1(153.13,145.22)
  BOTTOM w0.254: v1(149.01,109.47) 149.02,109.48 PHZ2.2
N39839956: length 2.5
  BOTTOM w0.254: PR1803.2 v1(162.78,56.83) 163.74,55.88 PU1801.4
N39865555: length 4.3
  BOTTOM w0.102: v2(57.21,113.65) PRM13.1
  BOTTOM w0.254: PCM17.2 PRM10.2 PCM18.1 PRM14.1 58.15,113.66 PRM13.1
N39865992: length 5.2
  TOP w0.102: v2(167.49,65.69) PRH13.1
  TOP w0.254: v1(168.88,66.35) 168.49,65.97 PRH13.1 PRH14.1
  BOTTOM w0.254: v1(168.88,66.35) 169.01,66.23 169.01,64.63 168.56,64.18 PRH08.2
N40401450: length 2.6
  TOP w0.102: v2(164.77,72.49) 165.41,71.84 PRH20.1
  TOP w0.254: PQH01.2 166.3,70.89 165.67,71.52 PRH20.1
N40405759: length 9.2
  TOP w0.254: PQH01.1 v2(167.23,69.52) 167.81,69.52 170.74,66.59 170.74,64.94 170.49,64.69 170.1,64.69 169.92,64.87 169.41,64.87 PRH14.2
N48572179: length 0.9
  BOTTOM w0.254: PRH12.1 168.44,65.64 PCH14.2

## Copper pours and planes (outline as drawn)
3VS_LS on TOP (solid shape): 31.93,54.98 31.93,54.12 31.92,54.11 31.92,53.65 31.82,53.45 31.9,53.24 31.66,53.01 31.08,53.01 30.81,52.74 30.81,50.44 31.09,50.16 31.09,47.87 30.68,47.47 28.56,47.47 28.54,47.5 28.54,48.02 28.56,48.04 29.06,48.04 29.09,48.07 29.09,48.73 29.07,48.74 29.07,48.76 28.56,48.76 28.54,48.78 28.54,49.22 28.56,49.25 29.07,49.25 29.08,49.25 29.08,49.96 29.07,49.97 28.55,49.97 28.54,49.99 28.54,54.28 29.31,55.05 31.87,55.05
5VS on TOP (solid shape): 38.52,54.41 38.52,45.46 37.9,44.85 35.69,44.85 35.68,44.85 35.22,44.85 35.2,44.84 34.49,44.84 34.46,44.86 34.46,45.19 34.47,45.19 34.99,45.19 35.01,45.21 35.01,45.7 34.99,45.72 34.47,45.72 34.46,45.73 34.46,45.98 34.47,45.99 34.99,45.99 35.01,46.01 35.01,46.51 35,46.52 34.47,46.52 34.46,46.53 34.46,49.51 34.47,49.52 34.99,49.52 35.02,49.55 35.02,50.25 35.01,50.26 34.48,50.26 34.47,50.27 34.47,50.72 34.48,50.72 34.98,50.72 35.01,50.75 35.01,51.43 34.99,51.45 34.49,51.45 34.47,51.47 34.47,52.1 33.26,53.31 33.26,55.02 33.32,55.08 37.85,55.08
+0.6V_DDR_VTT on TOP (solid shape): 60.04,109.72 59.91,109.6 59.22,109.6 59.09,109.72 59.09,110.61 59.28,110.8 60.04,110.8
+0.6V_DDR_VTT on TOP (solid shape): 68.96,49.75 68.96,48.76 68.97,48.76 68.97,47.94 69.22,47.68 71.85,47.68 72.93,46.6 72.93,46.31 72.94,46.31 72.94,46.14 72.83,46.03 72.47,46.03 72.47,46.01 66.08,46.01 66.01,46.08 66.01,49.18 66.96,50.13 68.58,50.13
+0.6V_DDR_VTT on BOTTOM (solid shape): 69.48,47.14 69.48,46.78 70.1,46.16 70.26,46.16 71.77,46.16 71.83,46.1 71.83,45.87 71.79,45.83 69.56,45.83 69.16,46.23 69.16,46.62 68.89,46.89 68.89,47.21 69.03,47.34 69.28,47.34
+0.6V_DDR_VTT on IN1 (solid shape): 67.4,60.52 67.4,49.22 67.26,49.08 66.43,49.08 66.27,49.24 66.27,49.84 66.2,49.91 66.2,50.76 66.21,50.77 66.24,50.92 66.21,51.07 66.2,51.08 66.2,53.11 65.69,53.62 65.65,53.67 65.65,60.18 65.28,60.55 65.28,61.31 65.43,61.46 66.46,61.46
+0.6V_DDR_VTT on IN2 (solid shape): 67.45,62.15 67.45,61.15 67.23,60.92 65.63,60.92 65.08,61.47 65.08,62.37 65.22,62.51 67.09,62.51
+0.6V_DDR_VTT on IN2 (solid shape): 59.72,110.55 59.72,109.66 59.6,109.53 59.34,109.53 59.33,109.52 58.96,109.52 58.02,108.58 57.76,108.58 57.11,109.23 57.11,109.33 58.52,110.74 59.53,110.74
+0.6VSP on TOP (solid shape): 61.69,110.74 61.69,109.79 61.57,109.66 60.36,109.66 60.23,109.79 60.23,110.04 60.8,110.04 60.8,110.55 60.23,110.55 60.23,110.8 61.63,110.8
+0.6VSP on BOTTOM (solid shape): 62.9,111.74 62.9,110.93 62.86,110.89 62.42,110.89 61.95,110.41 61.95,110.04 61.5,109.6 60.17,109.6 60.04,109.72 60.04,110.68 60.17,110.8 61.49,110.8 62.06,111.37 62.29,111.37 62.64,111.73 62.65,111.74 62.7,111.8 62.84,111.8
+0.95VALW on TOP (solid shape): 130.27,75.48 131.09,75.48 131.48,75.09 131.48,72.64 131.35,72.51 130.56,72.51 130.48,72.59 130.48,73.71 129.97,74.22 129.76,74.22 129.66,74.32 129.66,75.63 129.76,75.73 130.01,75.73
+0.95VALW on BOTTOM (solid shape): 154.34,71.94 154.34,71.24 153.77,71.24 153.77,69.21 154.34,69.21 154.34,65.46 153.94,65.07 149.75,65.07 149.39,65.43 149.39,69.15 152.31,72.07 154.21,72.07
+0.95VALW on BOTTOM (solid shape): 130.48,76.01 130.48,74.99 130.5,74.97 130.5,74.95 130.89,74.57 130.89,74.32 130.8,74.23 130.77,74.24 130.72,74.24 130.66,74.23 129.7,74.23 129.65,74.24 129.59,74.24 129.02,74.8 129.02,75.04 129.63,75.65 129.63,75.67 130.1,76.14 130.35,76.14
+0.95VALW on BOTTOM (solid shape): 127.72,45.05 127.72,44.6 127.55,44.29 127.72,43.99 127.72,43.38 127.69,43.36 127.53,43.18 127.52,42.94 127.51,42.85 127.42,42.81 126.2,42.81 126.08,42.93 126.08,43.63 126.09,43.63 126.09,44.24 126.08,44.24 126.08,44.48 126.72,45.12 127.64,45.12
+0.95VALW on VCC: 127.42,70.45 127.42,75.75 129.98,75.75 131.63,74.1 153.06,74.1 153.7,74.75 153.7,65.59 136.62,65.59 136.62,66.71 136.09,67.24 132.39,67.24 131.99,66.84 131.99,65.88
+0.95VALWP on TOP (solid shape): 158.57,73.61 158.57,68.9 158.35,68.67 156.91,68.67 156.69,68.89 156.69,69.91 157.33,70.55 157.33,70.92 157.32,70.92 157.32,73.4 157.58,73.66 158.53,73.66
+0.95VALWP on BOTTOM (solid shape): 158.59,73.59 158.59,69.15 158.97,68.77 159.99,68.77 160.25,68.51 160.25,65.68 160,65.42 156.34,65.42 156.33,65.43 155.14,65.43 154.49,66.08 154.49,71.72 154.52,71.75 155.13,71.75 155.58,72.19 155.58,72.84 155.68,72.94 157.18,72.94 157.9,73.66 158.53,73.66
+0.95VS on TOP (solid shape): 154.72,60.26 154.72,58.61 154.59,58.48 153.92,58.48 153.36,57.92 151.26,57.92 151.01,58.17 151.01,58.38 150.43,58.96 150.43,60.58 150.62,60.76 154.21,60.76
+0.95VS on TOP (solid shape): 98.07,56.61 102.36,56.61 102.52,56.45 108.32,56.45 108.68,56.09 108.68,51.79 107.96,51.07 94.4,51.07 94.35,51.13 94.35,51.74 94.35,51.74 94.35,56.22 94.8,56.67 98.01,56.67
+0.95VS on BOTTOM (solid shape): 154.47,61.65 154.47,58.02 154.28,57.84 150.94,57.84 150.58,58.2 150.58,58.43 150.4,58.6 150.4,61.84 150.72,62.16 153.96,62.16
+0.95VS on VCC: 150.18,55.72 150.15,55.68 144.32,55.68 141.15,52.38 138.63,52.38 137.38,52.63 136.14,52.38 129.47,52.38 129.46,52.42 129.12,52.69 128.77,52.42 128.76,52.38 122.53,52.38 122.21,52.59 121.89,52.38 121.18,52.38 121.09,52.43 121.09,52.54 120.79,53.08 120.48,52.54 120.49,52.43 120.4,52.38 114.33,52.38 113.09,52.63 111.85,52.39 111.82,52.38 111.79,52.36 110.86,51.75 110.2,50.86 101.61,50.86 101.38,51.09 101.38,61.23 101.44,61.32 101.54,61.31 101.85,61.25 102.09,61.45 102.17,61.51 102.26,61.47 102.91,61.71 102.23,61.81 102.15,61.75 102.05,61.8 101.81,61.94 101.54,61.87 101.44,61.86 101.38,61.95 101.38,64.83 113,64.83 116.3,68.13 129.02,68.13 130.36,66.79 130.46,66.46 130.79,66.37 132.05,65.1 132.05,64.47 132.45,64.07 134.65,64.07 134.9,63.96 135.15,64.07 135.55,64.07 135.79,63.96 136.03,64.05 136.05,64.07 136.09,64.07 136.62,64.6 136.62,65.08 153.85,65.08 154.09,64.85 154.09,57.82 151.95,55.68 150.75,55.68 150.72,55.72 150.69,55.75 150.65,55.83 150.69,55.9 150.45,56.53 150.21,55.9 150.24,55.83 150.21,55.75 ; 1 cut-out
+0.95VS_APU_GFX on BOTTOM (solid shape): 124.41,76.05 124.41,76.04 124.78,75.85 125.08,76.14 125.34,76.14 125.42,76.05 125.44,76.02 125.46,75.99 125.46,75.69 124.83,75.05 124.83,74.57 124.55,74.29 124.07,74.29 123.71,74.65 123.7,74.65 123.68,74.67 123.29,74.74 123.08,74.41 123.08,74.39 122.92,74.23 122,74.23 121.93,74.24 121.86,74.23 120.9,74.23 120.84,74.24 120.79,74.23 120.76,74.23 120.51,74.48 120.51,74.67 120.71,74.87 120.73,74.87 120.96,74.98 121.07,75.21 121.07,75.23 122.03,76.2 124.26,76.2
+0.95VS_APU_GFX on TOP: outline of 86 points within 89.32,50.68 125.22,76.18
+0.95VS_APU_GFX on VCC: 126.91,75.75 126.91,74.8 126.85,74.71 126.75,74.71 126.19,74.42 126.75,74.13 126.85,74.14 126.91,74.05 126.91,70.25 128.3,68.85 128.33,68.78 128.3,68.7 128.24,68.64 119.27,68.64 118.27,69.63 118.27,69.89 118.3,69.9 118.53,70.23 118.3,70.56 118.27,70.58 118.27,71.58 118.59,71.9 118.61,71.9 118.84,72.01 118.94,72.24 118.95,72.26 119.06,72.37 119.1,72.36 119.59,72.56 119.33,73.02 119.29,73.03 119.29,74.55 119.33,74.63 119.43,74.64 119.91,74.89 119.59,75.33 119.5,75.39 119.52,75.5 119.77,75.75
+0.775VALW on TOP (solid shape): 119.1,39.37 119.1,38.35 118.4,38.35 117.89,38.86 117.89,39.37 118.02,39.49 118.97,39.49
+0.775VALW on BOTTOM (solid shape): 150.91,38.79 149.26,37.14 148.5,37.14 148.37,37.27 148.37,38.86 148.56,39.05 150.91,39.05
+0.775VALW on BOTTOM (solid shape): 119.67,39.75 119.41,39.75 119.08,39.41 119.08,38.38 118.99,38.29 117.25,38.29 117.15,38.4 117.15,38.79 117.22,38.86 117.71,38.86 117.86,39.02 117.86,39.97 118.14,40.25 119.67,40.25
+1.2V_DDR on TOP (solid shape): 95.49,69.88 85.49,69.88 85.49,84.88 95.49,84.88
+1.2V_DDR on TOP (solid shape): outline of 11650 points within 66.01,65.5 119.7,116.01
+1.2V_DDR on BOTTOM (solid shape): outline of 2746 points within 115.28,70.61 119.9,88.17
+1.2V_DDR on BOTTOM (solid shape): outline of 2960 points within 66.46,67.73 93,91.79
+1.2V_DDR on VCC: 80.91,61.27 78.52,63.66 78.52,67.47 77.23,68.77 71.51,68.77 71.28,69 71.28,84.54 75.6,88.85 75.6,91.14 76.21,91.75 77.99,91.75 84.21,97.98 114.1,97.98 116.37,95.71 116.37,91.01 117.38,90 117.38,88.85 119.16,87.08 119.16,83.65 119.92,82.89 119.92,79.15 119.16,78.4 119.16,75.86 118.78,75.48 118.78,72.81 117.76,71.79 117.76,69.42 117.77,69.42 117.77,68.78 117.62,68.64 116.07,68.64 112.77,65.34 90.99,65.34 86.92,61.27
+1.2V_DDR on GND: 72.21,70.29 73.06,70.29 74.01,71.24 74.01,72.07 75.28,73.34 77.63,73.34 78.96,74.67 80.87,74.67 83.73,77.53 83.73,81.15 79.22,85.65 76.86,85.65 76.83,85.65 76.25,86.23 74.41,86.23 74.1,86.55 72.85,86.55 72.02,85.72 69.61,85.72 69.19,85.3 69.19,71.09 69.48,70.8 71.7,70.8
+1.2V_DDR on GND: 116.22,70.59 115.63,71.18 115.53,71.18 115.22,71.49 115.22,71.76 115.79,72.33 115.79,76.77 115.92,76.91 115.92,77.48 116.1,77.66 116.35,77.66 116.68,77.98 116.68,80.04 115.79,80.93 115.79,87.68 115.97,87.86 117.01,87.86 117.39,87.48 118.4,87.48 118.58,87.3 118.58,86.66 118.96,86.28 118.96,83.49 119.72,82.73 119.72,79.21 118.96,78.45 118.96,77.77 119.22,77.52 119.22,75.59 118.96,75.34 118.96,73.05 118.28,72.37 118.02,72.37 117.69,72.04 117.69,70.77 117.51,70.59
+1.2VP on TOP (solid shape): 64.43,90.19 64.43,86.61 64.27,86.45 62.18,86.45 62.14,86.49 62.14,90.27 62.24,90.37 64.26,90.37
+1.2VP on TOP (solid shape): 63.43,110.48 63.43,109.83 62.24,108.65 62.08,108.65 61.48,109.24 61.48,109.37 62.13,110.02 62.13,110.38 62.72,110.97 62.94,110.97
+1.2VP on BOTTOM (solid shape): 66.26,93.21 66.26,86.36 66.14,86.23 62.33,86.23 62.14,86.42 62.14,90.1 61.69,90.55 61.69,93.72 61.76,93.78 65.69,93.78
+1.2VP on BOTTOM (solid shape): 63.3,111.73 63.3,110.5 63.09,110.29 62.77,110.29 62.52,110.04 62.33,110.04 62.2,110.17 62.2,110.36 62.58,110.74 62.9,110.74 62.96,110.8 63.03,110.8 63.09,110.87 63.09,111.74 63.13,111.78 63.25,111.78
+1.8V_ALW on TOP (solid shape): 43.91,24.91 43.91,24.05 43.23,23.36 40.91,23.36 40.66,23.62 40.66,24.82 40.99,25.15 43.67,25.15
+1.8V_ALW on TOP (solid shape): 29.47,73.38 29.47,71.4 29.06,70.99 27.72,70.99 27.66,71.05 27.66,71.31 28.48,72.13 28.48,73.42 28.55,73.48 29.36,73.48
+1.8V_ALW on TOP (solid shape): 151.42,49.08 156.43,49.08 157.07,48.45 157.07,45.96 157.11,45.92 157.11,45.92 157.33,45.7 157.33,45.25 157.32,45.25 157.32,44.63 157.23,44.54 155.64,44.54 154.47,45.72 144.43,45.72 144.43,47.37 146.53,49.46 151.04,49.46
+1.8V_ALW on TOP (solid shape): 129.54,75.08 129.54,74.57 129.54,74.52 129.54,74.45 128.81,73.72 128.81,73.21 128.78,73.21 128.78,72.45 128.81,72.45 128.81,72.05 128.66,71.78 128.81,71.5 128.81,70.74 128.81,70.36 129.15,70.22 129.18,70.23 130.15,69.26 130.15,66.45 130.23,66.37 130.23,66.33 131.98,64.58 131.98,61.95 131.79,61.76 131.79,60.47 131.48,60.16 131.44,60.17 131.03,60.11 130.96,59.69 130.98,59.66 130.34,59.02 130.34,57.76 130.15,57.57 128.92,57.57 128.8,57.69 128.81,57.7 128.81,59.03 130.34,60.57 130.35,60.57 130.44,60.64 130.5,60.73 130.51,60.73 130.9,61.13 130.9,62.33 131.22,62.65 131.22,64.11 130.46,64.87 130.46,64.88 129.62,65.72 129.62,68.91 128.24,70.29 128.24,74.35 128.03,74.57 128.03,74.59 128.03,75.11 128.04,75.12 129.5,75.12
+1.8V_ALW on TOP (solid shape): outline of 223 points within 114.08,46.6 127.61,57.44
+1.8V_ALW on BOTTOM (solid shape): 57.69,28.25 57.69,26.79 58.45,26.03 58.45,23.81 51.09,23.81 50.83,24.06 50.83,24.63 53.48,27.28 53.48,28.73 53.65,28.9 57.04,28.9
+1.8V_ALW on BOTTOM (solid shape): 44.64,24.81 44.64,23.84 44.6,23.8 43.95,23.8 43.57,23.43 43.57,23.41 43.51,23.35 41.7,23.35 41.61,23.44 41.61,24.64 41.83,24.85 44.6,24.85
+1.8V_ALW on BOTTOM (solid shape): 154.97,49.97 156.37,49.97 156.37,50.54 156.69,50.54 156.94,50.29 156.94,48.45 156.56,48.06 154.85,48.06 154.47,48.45 154.47,50.41 154.59,50.54 154.97,50.54
+1.8V_ALW on BOTTOM (solid shape): 129.53,76.07 129.53,75.69 128.89,75.06 128.89,74.77 129.3,74.36 129.3,74.19 129.04,73.93 128.88,73.93 128.83,73.98 128.75,74.12 128.6,74.2 128,74.8 128,75.12 129.02,76.14 129.46,76.14
+1.8V_ALW on BOTTOM (solid shape): 98.52,47.75 98.52,39.43 94.4,35.3 91.35,35.3 89.06,33.02 89.06,29.59 88.68,29.21 86.71,29.21 86.65,29.27 86.65,34.22 90.08,37.65 92.93,37.65 95.35,40.07 95.35,47.87 95.54,48.06 98.21,48.06
+1.8V_ALW on BOTTOM (solid shape): 149.92,49.46 151.06,49.46 151.28,49.24 151.28,48.68 151.26,48.65 150.89,48.65 150.82,48.65 150.8,48.63 150.8,48.11 150.78,48.1 150.54,48.1 150.52,48.12 150.52,48.63 150.5,48.65 150.01,48.65 150,48.63 150,48.1 149.99,48.09 149.74,48.09 149.72,48.11 149.72,48.63 149.69,48.65 149.26,48.66 149.23,48.68 149.23,49.51 149.32,49.59 149.78,49.59
+1.8V_ALW on IN1 (solid shape): 116.11,57.13 116.11,55.98 118.14,53.94 118.14,52.89 117.95,52.7 116.28,52.7 114.07,54.9 110.83,54.9 110.83,56.68 114.01,56.68 114.84,57.51 115.72,57.51
+1.8V_ALW on IN1 (solid shape): 98.94,47.02 98.9,46.99 95.54,46.99 95.35,47.18 95.35,48.26 95.86,48.76 98.93,48.76 98.94,48.77
+1.8V_AVDD on TOP (solid shape): 30.77,10.85 30.77,9.84 30.32,9.39 30.32,8.2 30.32,8.19 30.32,7.99 29.63,7.3 29.24,7.3 29.1,7.44 29.1,7.69 29.19,7.78 29.19,8.49 29.27,8.57 29.8,8.57 29.98,8.75 29.98,9.41 30.56,9.99 30.56,10.85 30.62,10.9 30.72,10.9
+1.8V_CPVDD on TOP (solid shape): 37.92,20.05 37.92,18.68 37.71,18.47 36.94,18.47 36.87,18.55 36.87,19.5 37.07,19.7 37.07,20.28 37.09,20.3 37.68,20.3
+1.8V_CPVDD on TOP (solid shape): 29.55,11.67 29.55,11.57 29.5,11.51 28.66,11.51 28.25,11.11 27.34,11.11 27.02,10.79 27.02,10.54 26.94,10.46 26.92,10.45 26.36,10.45 26.33,10.48 26.33,11.44 26.61,11.72 29.5,11.72
+1.8V_DVDDIO on TOP (solid shape): 38.52,15.62 38.52,14.05 37.38,14.05 37.05,14.26 36.73,14.05 35.16,14.05 35.01,13.9 33.82,13.9 33.77,13.95 33.77,14.08 33.82,14.13 34.64,14.13 35.19,14.68 36.56,14.68 37.25,15.36 37.44,15.36 37.75,15.68 38.45,15.68
+1.8VALWP on BOTTOM (solid shape): 158.47,56.26 158.47,47.68 158.4,47.62 157.26,47.62 157.13,47.75 157.13,50.29 156.69,50.73 154.59,50.73 154.53,50.8 154.53,56.07 154.91,56.45 158.28,56.45
+1.8VS on TOP (solid shape): 52.29,27.43 51.91,27.05 50.9,27.05 50.77,27.17 50.77,28.89 51.28,29.4 52.29,29.4
+1.8VS on TOP (solid shape): 126.43,105.66 126.43,104.74 126.3,104.6 124.95,104.6 124.84,104.71 124.84,105.59 125.02,105.77 126.33,105.77
+1.8VS on TOP (solid shape): 117,139.5 115.6,138.11 113.76,138.11 113.76,139.11 114.67,140.01 114.67,140.66 114.72,140.71 117,140.71
+1.8VS on TOP (solid shape): 60.92,42.59 60.92,40.9 60.02,40 59.28,40 59.17,40.11 59.17,41.09 59.57,41.5 59.57,41.93 59.58,41.93 59.58,42.65 59.57,42.65 59.57,43.05 59.74,43.22 60.28,43.22
+1.8VS on TOP (solid shape): 40.1,24.09 40.1,23.93 40.1,23.92 40.1,22.41 38.19,20.5 36.71,20.5 36.66,20.45 36.66,19.7 36.64,19.68 36.18,19.68 35.74,20.13 35.08,20.13 34.95,20 34.64,20 34.45,20.19 34.45,20.95 34.07,21.33 34.07,22.41 34.2,22.54 34.79,22.54 35.44,21.89 37.07,21.89 37.99,22.81 37.99,23.72 38.47,24.2 39.99,24.2
+1.8VS on TOP (solid shape): 119.73,109.15 119.73,108.5 119.72,108.5 119.72,105.83 120.3,105.26 120.3,104.56 120.11,104.37 118.71,104.37 116.93,102.59 116.93,100.88 118.77,99.04 118.77,97.64 118.71,97.58 118.14,97.58 118.14,98.27 115.91,100.5 115.91,103.1 118.2,105.39 118.2,108.95 118.53,109.28 119.6,109.28
+1.8VS on TOP (solid shape): outline of 209 points within 122.71,58.27 129.5,75.82
+1.8VS on TOP (solid shape): outline of 432 points within 130.59,47.49 163.8,60.89
+1.8VS on BOTTOM (solid shape): 61.44,42.79 61.36,42.79 60.83,42.27 60.22,42.27 59.71,42.78 59.71,43.14 60.38,43.81 61.44,43.81
+1.8VS on BOTTOM (solid shape): 120.69,104.53 120.69,103.95 120.61,103.87 119.44,103.87 119.33,103.98 119.33,104.55 119.22,104.66 119.22,105.02 119.28,105.09 120.13,105.09
+1.8VS on BOTTOM (solid shape): 85.63,123.55 85.63,123.19 85.89,122.93 86.14,122.93 86.14,122.04 86.01,121.92 82.39,121.92 81.82,122.49 81.82,123.44 82.77,123.44 83.09,123.12 83.36,123.12 83.49,123.25 83.49,123.68 83.58,123.77 85.41,123.77
+1.8VS on BOTTOM (solid shape): 128.45,76.01 128.45,75.75 127.81,75.12 127.81,74.74 128,74.55 128,74.23 127.88,74.1 127.7,74.1 127.65,74.15 127.59,74.19 126.99,74.8 126.99,75.18 127.62,75.82 127.81,75.82 128.07,76.07 128.38,76.07
+1.8VS on BOTTOM (solid shape): outline of 118 points within 71.54,40.7 79.66,45.91
+1.8VS on BOTTOM (solid shape): outline of 497 points within 111.03,52.81 134.62,61.06
+1.8VS on IN1 (solid shape): 119.73,109.15 119.73,108.2 119.6,108.07 118.59,108.07 118.21,108.45 118.21,109.79 119.1,109.79
+1.8VS on IN1 (solid shape): 123.15,94.78 123.98,94.78 124.11,94.65 124.11,94.46 123.79,94.15 120.3,94.15 120.17,94.27 120.17,94.65 120.68,95.16 120.68,95.73 118.14,98.27 118.14,98.78 118.26,98.91 119.03,98.91
+1.8VS on IN1 (solid shape): 122.02,105.66 125.3,105.66 125.31,105.65 125.71,105.65 126.27,105.09 126.27,103.75 125.76,103.75 125.13,104.39 119.6,104.39 119.1,104.9 119.1,105.53 119.23,105.66 122.02,105.66
+1.8VS on IN1 (solid shape): 128.01,59.49 128.3,59.34 128.6,59.49 134.4,59.49 134.53,59.37 134.53,58.22 133.64,57.34 129,57.34 128.05,58.29 127.92,58.29 127.8,58.42 127.8,59.3 127.99,59.49
+1.8VS on IN2 (solid shape): 35.31,23.09 35.31,21.92 35.08,21.69 34.75,21.69 34.25,22.19 34.25,22.2 34.15,22.3 34.15,23.31 34.28,23.44 34.96,23.44
+1.8VS on IN2 (solid shape): 52.04,27.62 52.04,27.11 50.96,26.03 48.42,26.03 48.42,27.05 50.07,27.05 50.83,27.81 51.85,27.81
+1.8VS on IN2 (solid shape): outline of 1035 points within 120.11,74.17 128.89,94.78
+1.8VS_LS on TOP (solid shape): 159.51,47.3 163.61,47.3 163.61,47.11 163.55,47.05 163.1,47.05 162.53,46.48 162.53,45.59 162.09,45.14 159.67,45.14 159.4,44.87 159.4,44.65 159.26,44.51 158.59,44.51 158.53,44.57 158.5,44.57 158.5,45.33 158.72,45.56 158.72,47.09 158.93,47.31 159.5,47.31
+2.5V_MEM on TOP (solid shape): 78.71,45.97 78.39,45.65 78.39,45.33 78.84,44.89 78.84,43.56 77.63,42.35 77.25,42.35 77.25,45.27 78.33,46.35 78.71,46.35
+2.5V_MEM on BOTTOM (solid shape): 64.74,70.38 64.74,68.83 63.98,68.83 63.15,69.65 63.15,70.44 63.28,70.57 64.55,70.57
+2.5VP on BOTTOM (solid shape): 62.9,75.5 62.9,73.85 63.18,73.57 63.56,73.57 63.79,73.34 63.79,72.32 63.96,72.15 64.85,72.15 65.06,71.94 65.06,70.92 64.85,70.72 64.16,70.72 64.16,71.28 63.67,71.28 63.67,70.72 62.97,70.72 62.77,70.92 62.77,71.33 62.54,71.56 62.01,71.56 61.88,71.69 61.88,73.59 62.14,73.85 62.14,75.5 62.26,75.62 62.77,75.62
+3V_DVDD on TOP (solid shape): 35.33,10.62 35.33,10.16 35.53,9.96 36.36,9.96 36.55,9.77 39.28,9.77 39.34,9.71 39.34,9.27 39.28,9.2 37.76,9.2 37.69,9.13 37.68,9.13 37.47,8.92 35.98,8.92 35.94,8.89 35.12,8.89 35.01,9 35.01,9.41 34.39,10.03 34.39,10.28 33.77,10.9 33.77,11.26 33.82,11.31 34.64,11.31
+3VALW on TOP (solid shape): 31.84,58.29 31.84,57.4 31.96,57.27 31.96,56.32 31.88,56.23 28.71,56.23 28.66,56.27 28.66,58.58 28.74,58.66 31.48,58.66
+3VALW on TOP (solid shape): 45.3,50.35 46.26,50.35 46.47,50.13 46.47,48.94 46.4,48.87 44.73,48.87 43.55,50.04 41.86,50.04 41.72,50.17 41.72,51.74 41.76,51.78 43.87,51.78
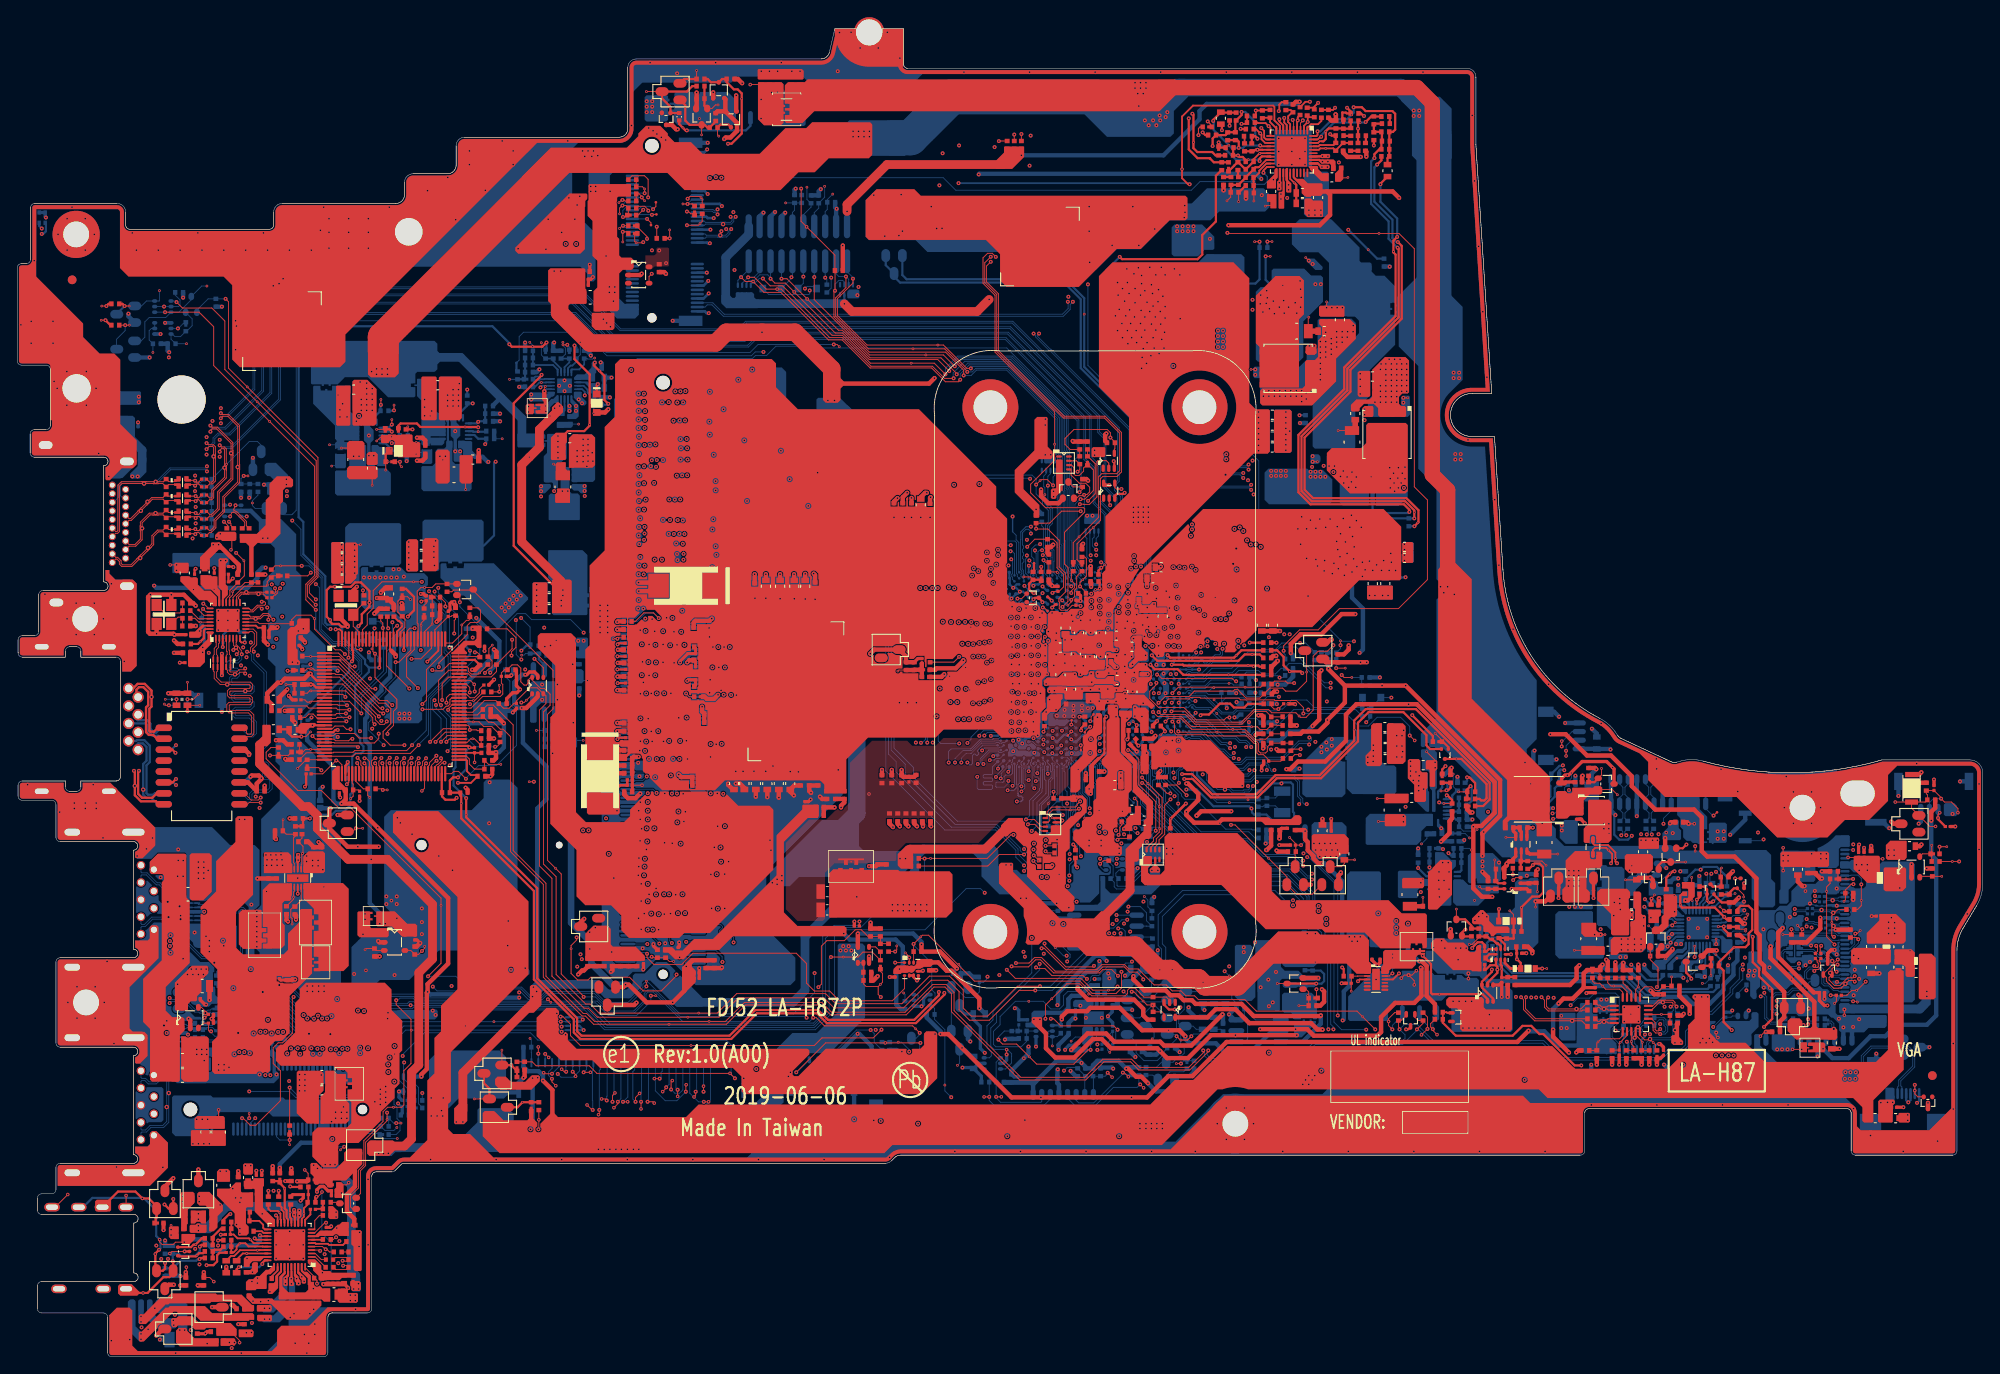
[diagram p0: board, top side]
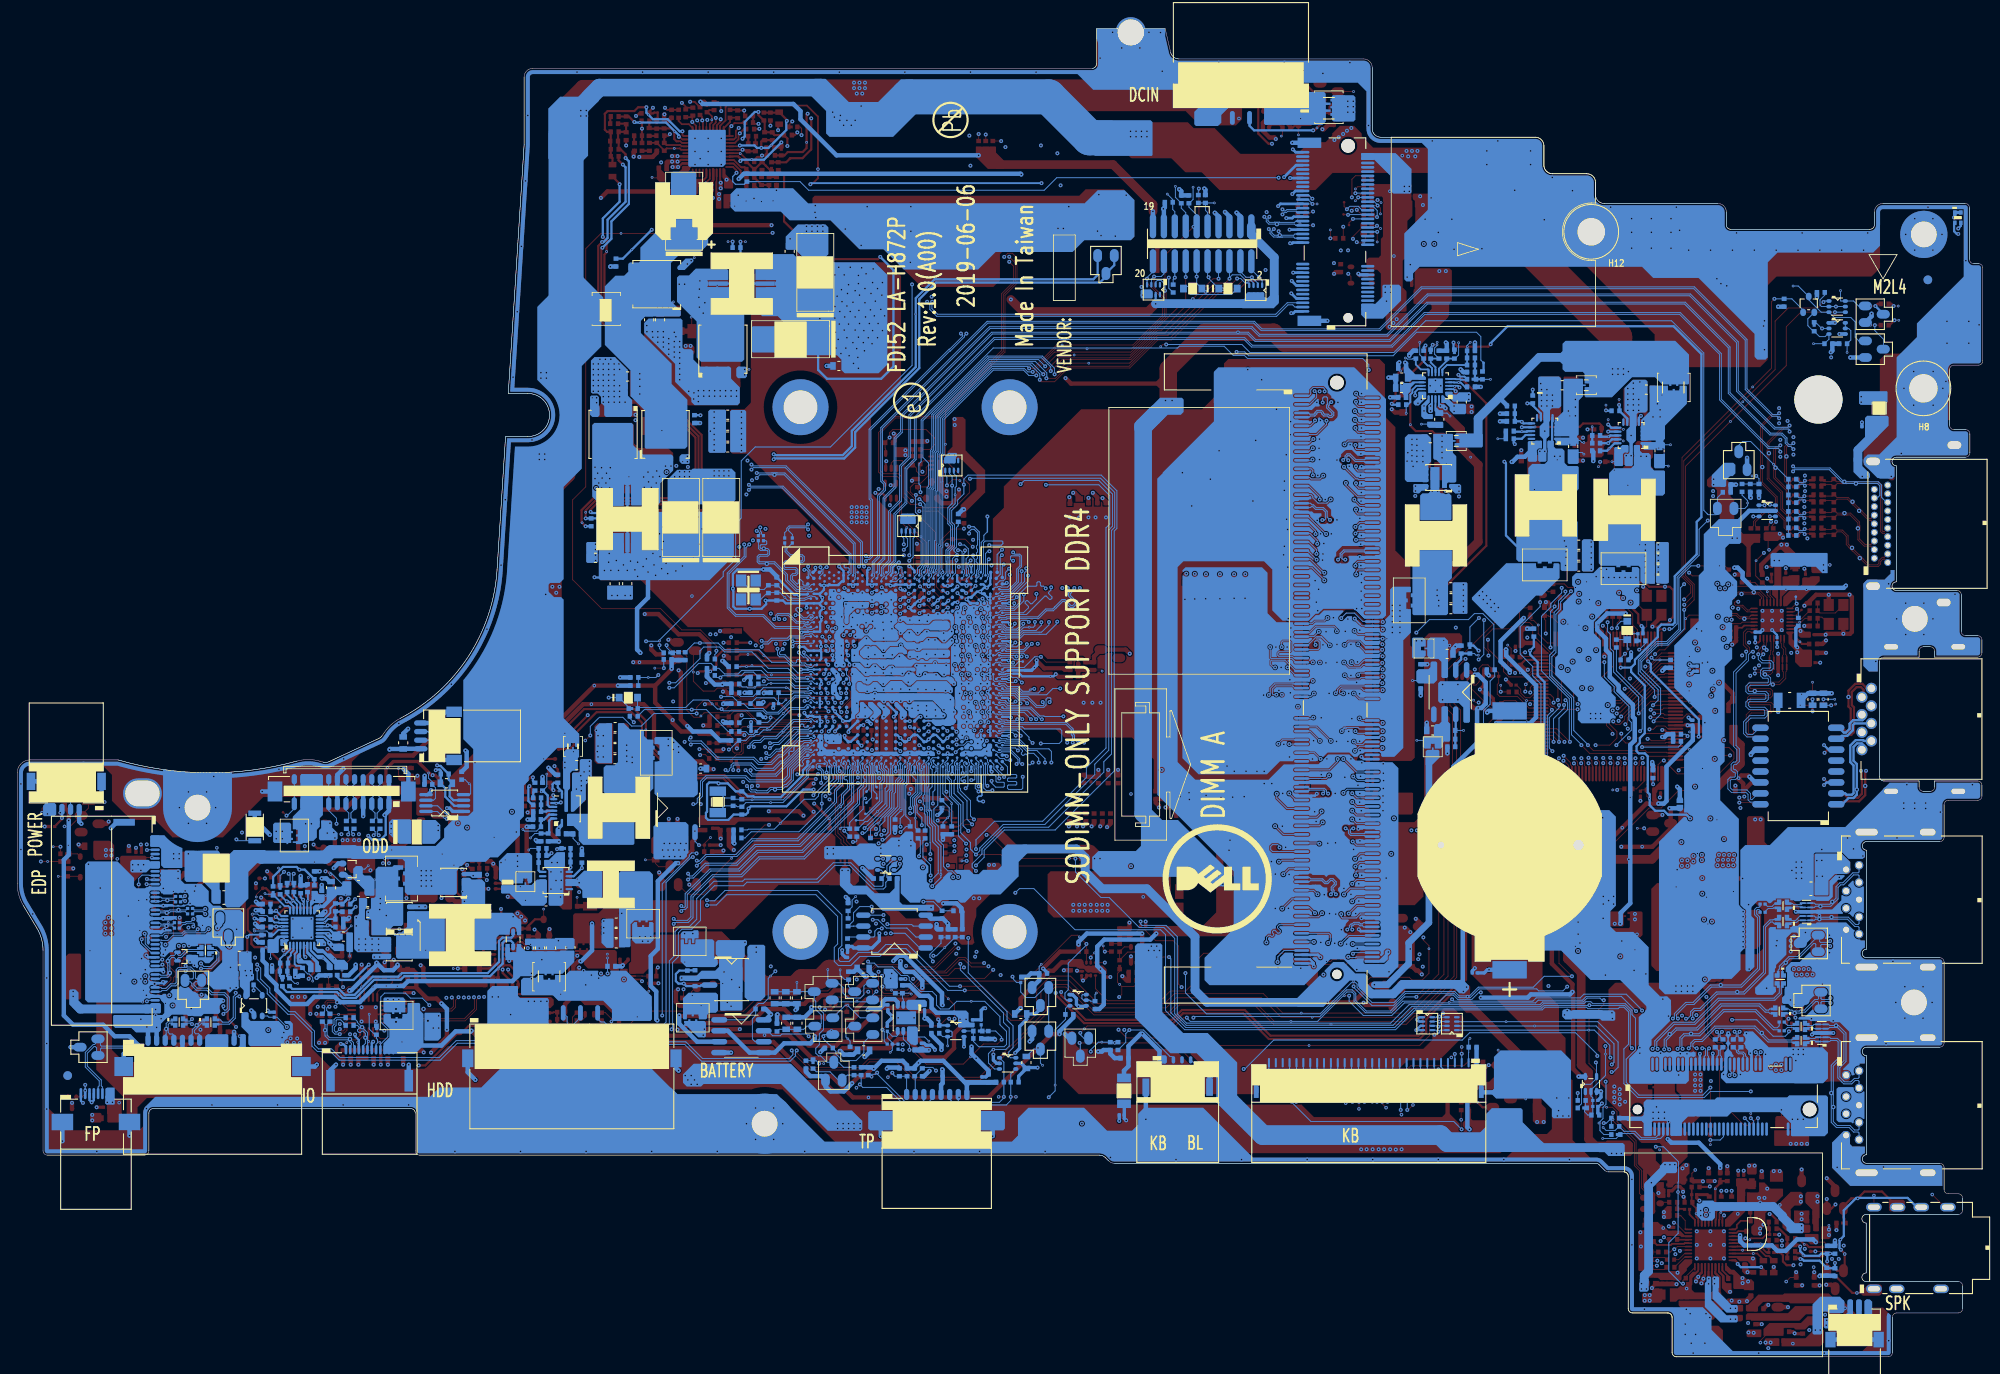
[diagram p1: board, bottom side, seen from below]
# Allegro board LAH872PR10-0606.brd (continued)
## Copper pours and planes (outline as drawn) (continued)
+3VALW on TOP (solid shape): 125.95,69.57 125.33,68.95 125.33,68.94 125.12,68.73 125.12,66.14 125,66.02 125,65.38 124.87,65.25 124.47,65.25 124.11,65.62 124.11,66.23 124.55,66.67 124.55,68.75 125.57,69.76 125.95,69.76
+3VALW on BOTTOM (solid shape): 225.4,64.07 225.4,62.99 225.27,62.86 224.06,62.86 223.87,63.05 223.87,64.19 224.06,64.38 225.08,64.38
+3VALW on BOTTOM (solid shape): 66.33,83.5 66.33,81.34 66.2,81.21 65.06,81.21 64.73,81.54 64.73,82.11 65.29,82.11 65.29,82.6 64.73,82.6 64.73,83.29 65.06,83.62 66.2,83.62
+3VALW on BOTTOM (solid shape): 143.54,47.65 143.54,46.49 143.87,46.16 143.87,41.81 143.42,41.37 142.01,41.37 141.48,41.89 141.48,42.17 141.49,42.18 141.49,47.73 141.66,47.9 143.29,47.9
+3VALW on BOTTOM (solid shape): 172.42,57.62 172.42,55.48 171.99,55.05 169.64,55.05 169.64,55.62 169.07,55.62 169.07,55.05 168.75,55.05 168.56,55.24 168.56,58.27 168.86,58.57 171.47,58.57
+3VALW on BOTTOM (solid shape): 49.88,92.2 49.88,91.69 51.91,91.69 51.91,92.26 55.38,92.26 59.36,88.28 59.36,88.05 55.99,84.67 55.75,84.67 55.2,85.23 55.19,85.23 51.91,88.51 51.22,88.51 49.18,90.55 49.18,92.13 49.31,92.26 49.82,92.26
+3VALW on IN1 (solid shape): 43.21,50.48 43.21,49.08 43.15,49.02 42.71,49.02 42.58,49.14 40.67,49.14 40.67,50.16 41.56,50.16 42.01,50.6 43.09,50.6
+3VALW on IN1 (solid shape): 31.8,57.89 31.8,55.82 31.96,55.66 31.96,55.53 31.38,54.95 31.22,54.95 30.51,55.66 30.51,57.05 30.53,57.15 30.51,57.24 30.51,57.86 30.67,58.01 31.67,58.01
+3VALW on IN1 (solid shape): 125.15,66.19 125.15,65.11 124.97,64.93 123.54,64.93 122.61,64.93 122.25,64.57 122.22,64.6 121.72,64.56 121.76,64.06 121.76,63.42 121.71,63.34 121.62,63.32 121.15,62.99 121.62,62.65 121.71,62.64 121.76,62.56 121.76,61.98 121.5,61.71 120.36,61.71 120.05,62.03 120.05,64.6 121.91,66.46 124.88,66.46
+3VALW on IN2 (solid shape): outline of 401 points within 141.39,70.71 147.25,82.61
+3VALW on TOP: 73.07,126.44 73.7,126.44 74.03,126.76 75.61,126.76 75.75,126.89 75.75,128.83 75.62,128.96 74.37,128.96 74.28,128.87 74.28,128.3 74.05,128.07 73.01,128.07 72.98,128.03 72.98,126.53
+3VALW on VCC: 60.99,50.12 60.99,59.35 52.1,68.24 52.1,90.06 55.15,93.11 55.15,121.62 63.77,130.23 83.75,130.23 83.85,130.13 83.85,116.77 72.95,116.77 70.14,113.96 70.14,90.27 66.33,86.33 66.33,64.85 69.88,61.29 69.88,45.04 71.68,43.24 101.23,43.24 101.38,43.39 101.38,50.12 101.61,50.35 110.5,50.35 112.03,51.87 141.37,51.87 144.54,55.18 152.16,55.18 154.59,57.61 154.59,60.13 169.73,60.13 170.98,58.88 170.98,54.27 164.71,47.94 146.74,47.94 142.55,43.75 122.99,43.75 115.37,36.13 103.92,36.13 103.92,38.33 103.33,38.92 100.39,38.92 99.5,38.03 65.93,38.03 63.19,40.76 60.85,40.76 58.94,42.67 42.75,42.67 28.81,47.27 28.55,47.54 28.55,58.5 28.78,58.73 31.49,58.73 31.91,58.31 31.91,55.44 31.91,55.41 41.96,49.43 42,49.4 60.27,49.4 ; 2 cut-outs
+3VALW_1.8V on BOTTOM (solid shape): 168.63,54.86 170.02,54.86 170.04,54.84 172.09,54.84 172.17,54.76 172.17,53.95 172.09,53.87 171.19,53.87 169.77,52.45 167.23,52.45 166.85,52.83 166.85,55.37 166.98,55.49 167.99,55.49
+3VALW_2.5V on BOTTOM (solid shape): 64.55,83.27 64.55,81.51 64.19,81.15 63.26,81.15 62.9,80.79 62.9,79.05 62.77,78.93 62.26,78.93 62.14,79.05 62.14,83.24 62.52,83.62 64.19,83.62
+3VALW_EC on TOP (solid shape): 34.75,73.55 35.8,73.55 35.85,73.5 35.85,73.36 35.79,73.3 34.61,73.3 34.45,73.14 34,73.14 33.33,72.47 32.71,72.47 32.67,72.51 32.67,73.4 32.97,73.7 34.6,73.7
+3VALW_EC on TOP (solid shape): 37.46,68.67 37.46,66.9 38.17,66.19 38.39,66.19 38.39,65.59 37.88,65.59 37.82,65.65 37.82,65.81 37.68,65.94 37.02,65.94 37.02,65.94 36.72,65.94 36.59,66.06 36.59,68.11 37.18,68.7 37.43,68.7
+3VALW_EC on TOP (solid shape): 53.95,84.96 53.95,82.48 53.88,82.42 53.5,82.42 53.18,82.74 52.29,82.74 51.98,82.42 51.98,82.18 52.27,81.89 52.27,81.76 52.2,81.69 50.52,81.69 50.46,81.75 50.46,81.79 51.91,83.24 53.12,83.24 53.37,83.5 53.37,84.26 53.25,84.39 52.8,84.39 52.68,84.51 52.68,84.89 52.8,85.02 53.88,85.02
+3VALWP on TOP (solid shape): 48.94,94.95 48.94,91.61 48.66,91.34 47.27,91.34 47.09,91.52 47.09,94.86 47.41,95.18 48.72,95.18
+3VALWP on BOTTOM (solid shape): 54.2,97.08 54.2,92.71 53.95,92.45 49.18,92.45 49.05,92.32 49.05,91.51 48.91,91.37 47.21,91.37 47.09,91.5 47.09,97.08 47.34,97.34 53.95,97.34
+3VLP on TOP (solid shape): 210.09,36.36 210.09,35.56 209.95,35.41 208.1,35.41 208.1,35.72 208.64,35.72 208.64,36.15 208.1,36.15 208.1,36.46 208.18,36.55 209.9,36.55
+3VLP on BOTTOM (solid shape): 51.99,106.51 52.06,106.48 52.13,106.47 52.75,106.47 52.87,106.36 52.87,104.2 52.74,104.07 51.91,104.07 51.79,104.2 51.79,105.11 51.79,105.12 51.73,105.51 51.35,105.61 51.26,105.63 51.22,105.71 51.22,106.42 51.32,106.52 51.98,106.52
+3VS on TOP (solid shape): 104.1,58.78 104.1,56.74 102.71,56.74 102.33,57.13 102.33,58.46 103.28,59.42 103.46,59.42
+3VS on TOP (solid shape): 219.93,28.25 219.93,27.36 219.81,27.24 218.73,27.24 218.6,27.36 218.6,28.25 218.71,28.36 219.83,28.36
+3VS on TOP (solid shape): 39.93,8.62 39.93,7.84 39.73,7.65 38.95,7.65 38.83,7.77 38.83,8.19 38.71,8.31 38.71,8.82 39.72,8.82
+3VS on TOP (solid shape): 193.58,36.7 193.58,36.38 193.46,36.25 192.44,36.25 192.2,36.49 192.2,37.24 192.36,37.41 192.87,37.41
+3VS on TOP (solid shape): 96.05,113.41 96.05,112.96 95.67,112.58 95.67,111.25 95.35,110.93 93.95,110.93 93.63,111.25 93.63,113.85 95.6,113.85
+3VS on TOP (solid shape): 132.36,57.19 132.81,56.74 132.81,56.43 132.68,56.3 131.73,56.3 131.6,56.43 131.6,56.68 132.11,57.19 132.11,57.95 132.36,57.95
+3VS on TOP (solid shape): 219.43,50.36 219.43,48.31 219.17,48.05 215.08,48.05 214.92,48.22 214.92,49.27 216.38,50.73 216.38,51.43 216.44,51.49 218.3,51.49
+3VS on TOP (solid shape): 219.55,59.94 219.55,58.03 219.3,57.78 217.33,57.78 217.14,57.97 217.14,59.49 217.65,60 219.49,60
+3VS on TOP (solid shape): 66.01,126.42 66.01,124.2 66.14,124.07 66.14,122.49 66.07,122.42 64.23,122.42 63.92,122.11 62.33,122.11 61.69,122.74 61.69,126.3 61.95,126.55 65.88,126.55
+3VS on TOP (solid shape): 60.73,32.58 60.73,32.21 60.71,32.13 60.72,32.06 60.72,32.03 59.75,31.06 56.1,31.06 55.55,31.62 55.55,32.3 55.81,32.57 56.76,32.57 57.36,31.97 59.04,31.97 59.8,32.74 60.57,32.74
+3VS on TOP (solid shape): 33.98,85.81 33.98,84.32 33.68,84.02 32.57,84.02 32.4,83.86 32.4,82.38 32.59,82.19 32.59,81.12 32.85,80.86 32.85,80.54 32.72,80.42 31.54,80.42 31.41,80.54 31.41,84.47 31.8,84.86 32.2,84.86 32.55,85.21 32.55,85.66 32.73,85.84 33.95,85.84
+3VS on TOP (solid shape): 32.06,101.96 32.06,101.29 31.86,101.09 31.21,101.09 30.89,100.76 30.89,99.45 30.58,99.15 30.58,95.68 29.53,94.63 27.93,94.63 27.47,94.17 26.96,94.17 26.96,94.25 26.58,94.63 25.92,94.63 25.87,94.69 25.87,95.68 27.85,95.68 28.88,96.71 28.88,97.32 28.88,97.32 28.88,99.61 29.32,100.05 29.32,101.51 30.18,102.38 31.65,102.38
+3VS on TOP (solid shape): 93.15,64.12 93.15,62.86 92.94,62.64 91.86,62.64 89.08,59.87 89.08,51.67 90.65,50.1 96.11,50.1 96.36,49.84 96.36,49.08 96.17,48.89 83.16,48.89 81.57,47.3 78.52,47.3 77.44,46.22 76.42,46.22 75.66,46.99 75.09,46.99 75.03,47.05 75.03,47.56 75.09,47.62 76.11,47.62 76.49,47.24 77.31,47.24 78.65,48.57 80.84,48.57 82.87,50.6 88.24,55.98 88.24,60.65 91.22,63.62 91.22,64.07 91.35,64.19 93.07,64.19
+3VS on TOP (solid shape): 28.41,51.88 28.41,49.93 28.41,49.87 28.44,49.84 28.94,49.84 28.95,49.83 28.95,49.38 28.95,49.37 28.51,49.37 28.51,49.37 28.44,49.37 28.42,49.34 28.41,49.28 28.41,48.72 28.42,48.68 28.42,48.67 28.42,48.65 28.48,48.65 28.51,48.63 28.95,48.63 28.96,48.62 28.96,48.18 28.95,48.17 28.5,48.17 28.49,48.16 28.42,48.16 28.42,48.12 28.42,48.11 28.42,48.08 28.41,48.08 28.41,47.5 28.34,47.43 26.26,47.43 25.75,47.94 25.75,51.56 26.16,51.97 28.32,51.97
+3VS on TOP (solid shape): 106.43,46.1 106.43,45.63 106.13,45.34 105.33,45.34 105.23,45.25 105.22,45.24 105.09,45.21 104.98,45.12 104.51,45.12 104.49,45.1 104.48,45.1 104.36,45.03 104.29,44.91 104.28,44.9 104.09,44.7 104.02,44.68 103.98,44.65 103.83,44.65 103.66,44.71 103.48,44.65 102.79,44.65 102.65,44.51 101.82,44.51 101.82,45.08 102.25,45.5 103.49,45.5 103.66,45.45 103.82,45.5 103.99,45.5 104.25,45.46 104.42,45.65 104.43,45.66 104.5,45.73 104.5,46.03 104.73,46.26 106.27,46.26
+3VS on TOP (solid shape): outline of 553 points within 114.32,51.77 124.26,65.26
+3VS on TOP (solid shape): outline of 1284 points within 30.07,22.04 44.74,43.49
+3VS on BOTTOM (solid shape): 44.52,40.17 44.52,39.33 44.27,39.09 42.83,39.09 42.71,39.2 42.71,40.04 42.96,40.29 44.4,40.29
+3VS on BOTTOM (solid shape): 48.86,40.21 48.86,39.56 48.52,39.22 47.8,39.22 47.5,39.52 47.5,39.86 48.03,40.39 48.68,40.39
+3VS on BOTTOM (solid shape): 37.35,22.37 37.35,22.35 37.52,22.18 37.52,21.35 35.7,21.35 35.53,21.52 35.53,22.54 35.66,22.66 37.05,22.66
+3VS on BOTTOM (solid shape): 39.85,8.63 39.91,8.57 39.91,7.67 39.81,7.57 39.01,7.57 38.83,7.74 38.83,9.04 39.85,9.04
+3VS on BOTTOM (solid shape): 98.59,108.52 98.59,107.75 98.52,107.69 96.55,107.69 94.71,109.53 93.19,109.53 92.87,109.85 92.87,111.31 93.06,111.5 95.6,111.5
+3VS on BOTTOM (solid shape): 31.49,102.5 31.49,101.25 31.39,101.15 29.98,101.15 29.96,101.13 29.82,101.27 29.82,101.95 29.37,102.4 29.07,102.4 28.75,102.72 28.75,103.72 28.98,103.94 30.05,103.94
+3VS on BOTTOM (solid shape): 202.54,37.4 202.54,36.19 204.44,34.29 213.71,34.29 213.9,34.1 213.9,32.13 213.65,31.87 202.92,31.87 201.84,32.95 201.84,37.4 201.96,37.52 202.41,37.52
+3VS on BOTTOM (solid shape): 132.81,56.62 132.81,54.79 131.78,53.76 131.1,53.76 131.09,53.77 130.97,53.79 130.85,53.77 130.84,53.76 129.74,53.76 127.84,51.86 122.65,51.86 122.08,51.86 122.08,51.85 121.97,51.85 121.86,51.97 121.86,52.49 121.92,52.55 125.19,52.55 125.2,52.57 125.52,52.57 125.88,52.92 125.88,55.82 125.93,55.88 126.34,55.88 126.44,55.77 126.44,54.49 127.03,53.89 128.76,53.89 129,54.14 129.04,54.14 129.67,54.78 131.28,54.78 131.6,55.09 131.6,56.68 131.73,56.81 132.62,56.81
+3VS on BOTTOM (solid shape): 97.82,61.91 97.82,59.39 98.42,58.8 102.76,58.8 103.34,58.22 103.35,58.22 103.48,58.1 103.48,56.7 102.59,55.81 90.85,55.81 89.75,54.71 87.68,54.71 87.45,54.93 87.45,56.34 88.15,57.04 98.62,57.04 98.63,56.99 98.64,56.94 98.66,56.89 98.68,56.84 98.72,56.8 98.76,56.76 98.8,56.73 98.85,56.71 98.9,56.7 98.95,56.69 99.01,56.69 99.06,56.7 99.11,56.71 99.16,56.73 99.2,56.76 99.24,56.8 99.27,56.84 99.3,56.89 99.32,56.94 99.33,56.99 99.34,57.04 99.33,57.1 99.32,57.15 99.3,57.2 99.27,57.24 99.24,57.29 99.2,57.32 99.16,57.35 99.11,57.38 99.06,57.39 99.01,57.4 98.95,57.4 98.9,57.39 98.85,57.38 98.8,57.35 98.76,57.32 98.72,57.29 98.68,57.24 98.66,57.2 98.64,57.15 98.63,57.1 98.62,57.04 88.15,57.04 93.53,62.42 97.32,62.42
+3VS on BOTTOM (solid shape): outline of 1865 points within 27.62,42.16 37.63,97.4
+3VS on IN1 (solid shape): 31.59,101.36 31.4,101.17 30.74,101.17 30.58,101.33 30.58,103.56 31.59,103.56
+3VS on IN1 (solid shape): 18.97,116.81 18.97,115.82 17.3,115.82 17.15,115.98 17.15,116.95 17.29,117.1 18.68,117.1
+3VS on IN1 (solid shape): 35.91,45.4 35.91,42.35 35.79,42.22 35.47,42.22 31.78,42.22 30.11,43.9 31.94,43.9 31.94,43.85 31.94,43.79 31.96,43.74 31.98,43.7 32.01,43.65 32.05,43.61 32.09,43.58 32.14,43.55 32.19,43.53 32.24,43.52 32.29,43.52 32.35,43.52 32.4,43.53 32.45,43.55 32.49,43.58 32.53,43.61 32.57,43.65 32.6,43.7 32.62,43.74 32.64,43.79 32.65,43.85 32.65,43.9 32.64,43.95 32.62,44 32.6,44.05 32.57,44.1 32.53,44.14 32.49,44.17 32.45,44.2 32.4,44.21 32.35,44.23 32.29,44.23 32.24,44.23 32.19,44.21 32.14,44.2 32.09,44.17 32.05,44.14 32.01,44.1 31.98,44.05 31.96,44 31.94,43.95 31.94,43.9 30.11,43.9 26.06,47.94 26.06,51.62 26.45,52 29.31,52
+3VS on IN2 (solid shape): 19.4,115.95 19.28,115.82 17.56,115.82 17.37,116.01 17.37,116.9 17.56,117.09 19.4,117.09
+3VS on IN2 (solid shape): 63.51,126.94 63.51,126.17 63.32,125.98 60.63,125.98 60.39,126.23 60.39,126.84 60.67,127.12 63.33,127.12
+3VS on IN2 (solid shape): 60.7,32.75 60.7,32.29 60.56,32.15 59.66,32.15 59.54,32.27 59.54,32.6 58.94,33.2 58.94,33.69 59.16,33.91 59.53,33.91
+3VS on IN2 (solid shape): 49.89,40.59 49.89,39.66 49.78,39.56 48.39,39.56 48.03,39.92 48.03,39.93 48.01,39.95 48.01,40.16 48.01,40.17 48.01,40.71 48.13,40.84 49.64,40.84
+3VS on IN2 (solid shape): outline of 541 points within 212,26.92 223.49,59.94
+3VS on VCC: 41.7,22.67 41.59,22.67 41.49,22.66 40.91,23.24 39.02,23.24 39.02,31.2 39.51,31.68 43.74,31.68 43.98,31.45 43.98,30 46.39,27.25 46.66,26.98 92.85,26.98 95.39,29.52 121.74,29.52 123.2,30.98 136.09,30.98 140.6,35.49 146.44,35.49 153.43,42.48 173.26,42.48 173.26,40.28 176.27,37.27 184.59,37.27 186.36,35.49 191.08,35.49 192.86,37.27 194.22,37.27 194.22,36.09 194.75,35.56 203.28,35.56 208.44,40.72 208.44,42.44 208.86,42.86 210.05,42.86 210.88,42.03 213.56,42.03 214.85,43.32 214.85,45 214.01,45.84 213.56,45.84 211.85,47.56 211.09,47.56 209.94,48.7 208.74,48.7 208.44,49 208.44,58.32 210.1,59.98 227.23,59.98 227.23,55.03 227.09,54.01 226.69,53.06 225.11,50.44 224.45,48.91 224.23,47.27 224.23,24.62 214.27,24.62 214.27,28.35 213.78,29.53 212.6,30.02 182.65,30.02 181.47,29.53 180.98,28.35 180.98,24.62 102.66,24.62 101.83,24.45 101.13,23.98 100.82,23.67 44.96,23.67 44.32,23.54 43.78,23.18 43.27,22.67
+3VS_APU on TOP (solid shape): outline of 195 points within 122.39,65.64 126.07,74.84
+3VS_APU on BOTTOM (solid shape): 126.39,76.08 126.43,76 126.48,75.94 126.48,75.69 125.84,75.06 125.84,74.23 125.65,74.04 125.54,74.04 125.52,74.07 125.42,74.18 125.28,74.23 125.27,74.24 125.11,74.4 125.1,74.41 125.07,74.48 125.02,74.54 125.02,74.99 126.16,76.14 126.33,76.14
+3VS_CAM on TOP (solid shape): 217.71,47.31 217.71,45.9 217.43,45.62 213.36,45.62 213.1,45.88 213.1,47.23 213.42,47.55 217.47,47.55
+3VS_SSD on TOP (solid shape): 24.11,27.82 24.11,26.55 24.06,26.5 20.72,26.5 20.61,26.6 20.61,27.68 20.93,28 23.94,28
+3VS_SSD on TOP (solid shape): 37.16,32.89 38.13,32.89 38.2,32.82 38.2,29.84 38.58,29.46 38.58,27.49 38.2,27.11 35.26,27.11 35.25,27.13 35.25,30.24 35.78,30.78 35.78,33.21 35.85,33.27 36.78,33.27
+3VS_SSD on BOTTOM (solid shape): outline of 128 points within 17.99,25.65 39.66,30.39
+3VS_TOUCH on BOTTOM (solid shape): 118.59,31.87 118.21,31.49 117.83,31.49 117.7,31.62 114.46,31.62 114.4,31.68 114.4,32.13 114.46,32.19 118.59,32.19
+3VS_WLAN_NGFF on TOP (solid shape): 71.33,136.31 71.33,134.95 71.27,134.9 69.85,134.9 69.71,134.76 69.71,134.37 69.64,134.2 69.71,134.02 69.71,130.22 69.95,129.98 69.95,128.06 70.21,127.8 71.34,127.8 71.62,127.52 71.62,126.61 71.4,126.38 70.37,126.38 69.95,125.96 69.95,121.79 69.73,121.57 67.87,121.57 67.83,121.54 67,121.54 66.96,121.57 66.96,123.88 67.41,124.33 67.41,127.44 66.85,128 66.85,132.08 66.28,132.65 66.28,134.38 66.39,134.49 66.39,136.25 66.49,136.35 71.29,136.35
+3VS_WLAN_NGFF on BOTTOM (solid shape): 72.23,139.89 72.23,139.25 72.17,139.19 70.71,139.19 68.87,137.35 68.87,135.63 68.49,135.25 66.52,135.25 66.39,135.38 66.39,138.11 68.23,139.95 72.17,139.95
+3VS_WLAN_NGFF on BOTTOM (solid shape): 69.76,124.52 69.76,123.25 70.58,122.42 72.17,122.42 72.23,122.36 72.23,121.15 71.79,120.71 69.69,120.71 67.6,122.8 67.6,124.39 67.85,124.65 69.63,124.65
+5V_AVDD on TOP (solid shape): 28.67,20.7 28.67,19.87 28.56,19.76 28.56,17.33 29.96,15.93 29.96,15.17 29.9,15.12 29.35,15.12 27.6,16.87 27.6,19.45 27.51,19.54 26.59,19.54 26.32,19.81 26.32,20.44 26.36,20.48 27.38,20.48 27.42,20.52 27.42,20.67 27.5,20.76 28.61,20.76
+5V_HDD on BOTTOM (solid shape): 183.04,41.08 183.04,39.98 183.15,39.87 183.63,39.87 183.63,39.34 183.63,39.32 184.99,39.32 185,39.34 185,39.87 185.67,39.87 185.84,39.7 185.84,38.86 185.15,38.17 185.15,37.13 185.84,36.45 185.84,35.23 182.16,35.23 181.2,36.19 181.2,36.77 181.2,39.87 181.58,40.25 181.58,40.44 181.58,40.45 181.58,41.02 181.7,41.14 182.98,41.14
+5V_HDMI on TOP (solid shape): 25.46,95.78 25.46,95 25.31,94.85 23.81,94.85 23.67,94.99 23.11,94.99 23,95.11 23,95.54 23.38,95.93 25.31,95.93
+5V_HDMI on BOTTOM (solid shape): 13.69,109.15 13.69,106.93 12.29,106.93 10.96,108.26 10.96,109.28 11.08,109.41 13.43,109.41
+5V_HDMI on BOTTOM (solid shape): 15.02,104.52 15.02,102.87 14.26,102.1 13.31,102.1 13.12,102.29 13.12,102.67 14,103.56 14,103.77 14,104.33 14.26,104.58 14.96,104.58
+5V_HDMI on IN1 (solid shape): 23.83,95.79 23.83,95.24 23.61,95.02 22.33,95.02 22.11,95.24 22.11,95.76 22.27,95.92 23.7,95.92
+5V_HDMI on IN1 (solid shape): 14.64,102.36 14.64,99.94 13.81,99.94 13.32,100.44 12.35,100.44 12.15,100.64 12.15,102.23 12.53,102.61 14.39,102.61
+5V_PVDD on TOP (solid shape): 31.17,10.85 31.17,10.02 31.23,9.96 31.23,9.66 30.82,9.25 30.82,8.19 31.52,7.49 33.5,7.49 33.82,7.81 33.82,8.31 33.75,8.38 33.75,9.14 32.95,9.94 32.95,10.85 33,10.9 33.1,10.9 33.16,10.85 33.16,10.09 33.36,9.89 33.69,9.89 34.12,9.46 34.12,8.75 34.15,8.72 34.55,8.72 34.62,8.22 35.12,8.3 35.37,8.06 35.48,7.94 36.35,7.94 36.37,7.93 36.37,6.45 36.33,6.41 35.64,6.41 35.39,6.66 30.45,6.66 30.39,6.73 30.39,7.49 30.45,7.55 30.45,9.32 30.95,9.81 30.95,10.83 31.02,10.9 31.12,10.9
+5V_USB_PWR1 on TOP (solid shape): outline of 213 points within 14.64,32 20.04,58.48
+5V_USB_PWR1 on BOTTOM (solid shape): 19.53,58.41 19.53,53.72 19.47,53.65 18,53.65 17.94,53.72 17.94,55.37 17.18,56.13 15.86,56.13 15.4,56.59 15.4,57.53 16.38,58.5 19.43,58.5
+5V_USB_PWR2 on BOTTOM (solid shape): outline of 153 points within 196.38,36.13 202.35,40.06
+5VALW on TOP (solid shape): 35.76,58.53 35.76,56.44 35.56,56.23 34.03,56.23 34.01,56.26 33.37,56.26 33.24,56.38 33.24,58.16 33.84,58.76 35.54,58.76
+5VALW on TOP (solid shape): 22.21,45.33 22.21,44.58 21.4,43.78 21.4,42.44 21.18,42.22 20.93,41.97 20.9,41.94 20.9,41.48 20.75,41.33 20.16,41.33 19.85,41.02 19.85,40.38 19.72,40.25 18.45,40.25 18.32,40.38 18.32,43.49 20.29,45.46 22.07,45.46
+5VALW on BOTTOM (solid shape): 202.66,47.04 202.66,44.98 202.54,44.85 202.54,43.06 202.33,42.86 202.31,42.86 202.09,42.63 202.09,42.32 202.11,42.3 202.09,42.29 202.09,41.71 201.96,41.59 201.71,41.59 201.37,41.93 201.37,43.59 201.21,43.75 201.04,43.75 200.88,43.9 200.88,44.45 201,44.57 201,45.71 201.16,45.87 201.16,47.05 201.23,47.13 202.57,47.13
+5VALW on BOTTOM (solid shape): outline of 1025 points within 39.91,73.66 49.69,91.82
+5VALW on IN1 (solid shape): 33.56,58.73 35.03,58.73 35.21,58.55 35.21,56.95 35.09,56.83 32.32,56.83 32.01,57.13 32.01,58.61 32.14,58.73 32.74,58.73 32.93,58.92 33.37,58.92
+5VALW on IN2 (solid shape): outline of 479 points within 19.37,41.13 35.15,62.76
+5VALW on VCC: 19.89,23.24 17.69,25.44 17.62,44.02 17.62,59.52 18.62,60.51 23.38,60.51 25.73,62.86 28.33,62.86 29.63,64.15 29.63,66.76 35.13,72.26 43,72.26 43.79,73.04 43.79,74.95 44.1,75.26 44.1,75.92 36.8,83.22 36.8,88.98 37.16,89.34 38.75,89.34 40.1,90.7 40.1,91.58 40.33,91.82 44.44,91.82 51.6,84.66 51.6,68.03 60.49,59.14 60.49,50.33 60.06,49.91 42.14,49.91 32.42,55.7 32.42,58.52 31.7,59.24 28.57,59.24 28.04,58.71 28.04,47.33 28.54,46.83 28.56,46.82 42.64,42.16 58.73,42.16 60.49,40.4 60.49,39.07 63.94,35.62 115.58,35.62 123.2,43.24 142.76,43.24 146.95,47.43 164.92,47.43 171.34,53.91 194.07,53.91 194.85,54.69 194.85,56.85 195.47,57.46 196.12,57.46 196.12,57.29 197.6,55.81 200.46,55.81 201.2,55.07 201.2,49.1 202.35,47.96 202.35,44.55 200.78,42.98 153.22,42.98 146.23,36 140.39,36 135.88,31.49 122.99,31.49 121.53,30.03 95.18,30.03 92.64,27.49 46.88,27.49 46.76,27.6 44.48,30.19 44.48,31.66 43.95,32.19 39.3,32.19 38.52,31.41 38.52,23.24 ; 1 cut-out
+5VALW_VDD on BOTTOM (solid shape): 64.17,80.7 64.17,80.2 64.42,79.94 65.59,79.94 65.82,79.71 65.82,78.52 65.59,78.29 63.79,78.29 63.41,78.67 63.41,80.7 63.53,80.83 64.04,80.83
+5VALWP on TOP (solid shape): 39.59,94.42 39.59,91.05 39.4,90.86 39.4,90.55 38.77,89.91 38.13,89.91 38.13,94.61 38.2,94.67 39.34,94.67
+5VALWP on BOTTOM (solid shape): 44.62,96.75 44.62,92.26 44.34,91.97 40.01,91.97 39.79,91.75 39.79,90.2 39.49,89.9 38.14,89.9 38.11,89.93 38.11,90.03 38.11,90.03 38.11,94.58 38.11,94.58 38.11,96.45 38.58,96.92 44.45,96.92
+5VS on TOP (solid shape): 27.4,22.35 27.4,21.33 27.28,21.2 26.39,21.2 26.26,21.33 26.26,22.35 26.39,22.47 27.28,22.47
+5VS on TOP (solid shape): 38.07,7.74 38.39,7.42 39.47,7.42 39.59,7.3 39.59,6.44 39.44,6.28 37.43,6.28 37.24,6.48 37.24,7.93 37.25,7.93 38.07,7.93
+5VS on TOP (solid shape): 148.42,138.13 148.42,137.24 148.5,137.16 148.51,137.15 148.55,137.08 148.62,137.04 148.63,137.03 148.7,136.96 149.43,136.96 149.95,136.44 151.55,136.44 151.67,136.32 151.67,135.17 151.48,134.98 149.58,134.98 149.26,135.29 149.26,136.03 148.21,137.07 148.21,138.11 148.26,138.16 148.4,138.16
+5VS on TOP (solid shape): outline of 670 points within 21.31,32.89 34.26,62.86
+5VS on TOP (solid shape): outline of 876 points within 54.1,23.68 219.21,44.93
+5VS on BOTTOM (solid shape): 14.39,112.14 14.39,110.87 14.19,110.68 11.4,110.68 11.08,110.99 11.08,112.2 11.15,112.26 14.26,112.26
+5VS on BOTTOM (solid shape): 198.66,61.91 198.66,59.9 198.51,59.75 196.57,59.75 196.57,61.93 196.73,62.1 198.47,62.1
+5VS on BOTTOM (solid shape): 185.84,41.65 185.84,40.19 185.69,40.05 183.65,40.05 183.64,40.04 183.32,40.04 183.31,40.05 183.31,41.51 183.42,41.62 183.42,41.65 183.55,41.78 185.71,41.78
+5VS on BOTTOM (solid shape): 151.04,32.82 151.04,31.87 150.59,31.43 148.94,31.43 148.66,31.71 139.64,31.71 134.21,26.28 130.4,26.28 130.21,26.47 130.21,27.43 131.42,28.63 133.07,28.63 138.5,34.06 149.8,34.06
+5VS on IN1 (solid shape): outline of 2136 points within 16.98,6.3 134.12,49.21
+5VS on IN2 (solid shape): 26.78,63.98 26.78,62.31 26.65,62.18 25.56,62.18 25.43,62.31 25.43,64.15 25.61,64.33 26.44,64.33
+5VS on IN2 (solid shape): 15.08,112.01 15.08,110.49 15.34,110.23 15.34,109.72 15.78,109.28 15.78,108.9 14.77,108.9 13.88,109.79 13.88,112.01 14.07,112.2 14.89,112.2
+5VS on IN2 (solid shape): outline of 356 points within 183.68,38.73 196.76,42.6
+5VS on VCC: 194.96,36.06 194.73,36.3 194.73,37.36 195.3,37.93 195.3,40.49 193.96,41.82 193.96,42.48 200.99,42.48 202.85,44.34 202.85,48.17 201.71,49.31 201.71,55.28 200.67,56.32 197.81,56.32 197.01,57.12 197.01,61.29 197.24,61.53 203.26,61.53 207.93,56.85 207.93,48.55 207.55,48.17 207.55,44.4 207.93,44.02 207.93,40.93 203.07,36.06
+5VS_KBL on BOTTOM (solid shape): 95.92,34.79 95.92,34.54 95.47,34.09 94.97,34.09 94.84,34.22 94.84,34.92 94.97,35.05 95.67,35.05
+5VS_ODD on BOTTOM (solid shape): 195.49,67.62 195.49,63.69 196.38,62.8 196.38,61.34 195.8,61.34 195.8,59.94 195.82,59.93 196.38,59.93 196.38,59.75 194.68,59.75 194.44,59.99 193.98,59.99 193.59,60.38 193.59,61.27 193.25,61.61 193.25,62.62 192.88,62.99 192.88,67.56 193.07,67.75 195.36,67.75
+17.4V_BATT on BOTTOM (solid shape): 176.75,55.56 176.75,48.13 175.93,47.3 172.75,47.3 172.75,48.7 172.37,49.08 171.17,49.08 171.17,49.72 170.91,49.97 170.6,49.97 170.34,49.72 170.34,49.02 169.9,49.02 169.83,49.08 169.83,50.63 170.46,51.25 170.53,51.31 170.59,51.38 170.83,51.62 173.39,51.62 174.02,52.26 174.02,55.11 174.41,55.49 175.61,55.49 175.8,55.68 176.63,55.68
+17.4V_BATT+ on TOP (solid shape): 190.07,58.17 190.07,56.71 189.59,56.23 187.29,56.23 186.8,56.72 186.8,58.23 187.01,58.44 187.43,58.44 187.44,58.45 189.79,58.45
+17.4V_BATT+ on BOTTOM (solid shape): 170.34,47.05 171.17,47.05 171.17,48 171.67,48 171.67,46.53 171.53,46.39 171,46.39 170.78,46.16 170.78,43.98 170.75,43.95 170.22,43.95 169.92,44.25 168.31,44.25 168.02,44.54 165.04,44.54 163.67,45.91 163.67,47.19 163.71,47.23 165.27,47.23 165.36,47.14 169.31,47.14 169.83,47.67 169.83,48 170.34,48
+17.4V_BATT++ on BOTTOM (solid shape): outline of 131 points within 154.66,39.05 169.86,44.89
+19V_ADPIN on TOP (solid shape): 89.05,147.96 89.05,143.49 88.74,143.18 86.78,143.18 86.08,143.89 86.08,148.14 86.14,148.2 88.81,148.2
+19V_ADPIN on BOTTOM (solid shape): 91.62,144.75 91.62,143.3 91.42,143.1 88.87,143.1 88.49,143.48 88.49,144.39 87.2,145.68 87.2,147.17 87.39,147.36 89.01,147.36
+19V_VIN on TOP (solid shape): 134.59,146.68 132.74,144.83 92.62,144.83 91.24,143.44 89.38,143.44 89.2,143.62 89.2,144.37 89.21,144.37 89.74,144.37 89.74,144.38 89.74,144.89 89.73,144.9 89.21,144.9 89.2,144.91 89.2,145.17 89.21,145.17 89.74,145.17 89.75,145.18 89.75,145.68 89.73,145.7 89.21,145.7 89.19,145.72 89.19,147.83 89.57,148.2 91.52,148.2 91.84,148.52 134.59,148.52
+19V_VIN on TOP (solid shape): 169.01,90.42 169.01,76.51 178.09,67.43 178.09,63.35 178.08,63.33 178.05,63.18 178.08,63.03 178.09,63.02 178.09,62.54 178.11,62.52 178.12,62.5 178.18,62.34 178.31,62.22 178.34,62.21 178.34,60.64 178.22,60.51 176.63,60.51 176.56,60.57 176.56,61.84 175.99,62.42 173.45,62.42 173.2,62.16 173.2,61.21 172.69,61.21 172.63,61.27 172.63,62.35 173.14,62.86 173.14,67.05 165.12,75.06 165.12,91.57 165.28,91.73 165.87,92.32 167.1,92.32
+19V_VIN on IN1 (solid shape): 133.97,148.55 133.97,146.83 133.84,146.7 132.77,146.7 132.69,146.62 129.76,146.62 129.64,146.74 129.64,148.39 129.87,148.63 133.89,148.63
+19V_VIN on IN1 (solid shape): 166.73,91.35 166.73,88.77 166.54,88.58 165.06,88.58 164.93,88.7 164.93,91.35 165.01,91.43 166.66,91.43
+19VB on TOP (solid shape): 44.34,118.01 44.34,114.34 43.88,113.88 41.11,113.88 40.76,114.23 40.76,118.02 40.8,118.06 44.28,118.06
+19VB on TOP (solid shape): 182.72,58.74 182.72,58.22 182.72,58.22 182.72,58.03 182.91,57.84 183.36,57.84 183.49,57.97 183.49,58.71 183.51,58.73 184.06,58.73 184.18,58.61 184.18,57.15 183.93,56.89 182.79,56.89 182.34,56.45 182.34,54.41 182.72,54.03 182.72,53.15 182.72,53.08 182.47,52.83 179.87,52.83 179.55,53.14 179.55,54.35 179.93,54.73 179.93,57.72 181.01,58.8 182.66,58.8
+19VB on TOP (solid shape): outline of 216 points within 58.68,134.54 99.35,143.54
+19VB on BOTTOM (solid shape): 103.33,143.61 103.33,139.8 103.16,139.63 96.57,139.63 96.49,139.71 96.49,140.38 96.49,140.38 96.49,143.56 96.7,143.77 103.17,143.77
+19VB on BOTTOM (solid shape): 163.2,146.51 165.31,146.51 166.68,145.13 166.68,139.32 166.43,139.07 162.64,139.07 162.07,139.65 162.07,144.78 160.79,146.05 160.79,146.6 161.25,147.06 162.65,147.06
+19VB on BOTTOM (solid shape): 136.09,148.22 136.09,146.53 134.4,144.85 134.4,142.24 134.01,141.85 126.62,141.85 123.94,144.53 123.94,148.13 124.33,148.52 125.72,148.52 128.35,145.89 131.77,145.89 134.47,148.58 135.72,148.58
+19VB on BOTTOM (solid shape): 203.81,58.35 203.81,55.56 204.28,55.08 204.28,52.52 204.02,52.26 202.55,52.26 201.54,53.27 201.54,56.38 200.53,57.4 199.68,57.4 199.42,57.65 199.42,58.73 199.61,58.92 203.23,58.92
+19VB on BOTTOM (solid shape): 61.38,107.17 61.38,106.74 60.8,106.74 60.8,106.23 61.38,106.23 61.38,105.85 61.25,105.72 58.23,105.72 58.1,105.86 58.1,107.24 58.21,107.35 61.19,107.35
+19VB on BOTTOM (solid shape): 48.82,117.78 48.82,116.94 49.12,116.64 49.12,115.69 48.82,115.4 48.82,114.82 48.53,114.53 46.5,114.53 46.26,114.29 46.26,113.18 45.74,113.18 45.74,112.74 46.26,112.74 46.26,111.69 46.14,111.56 43.09,111.56 40.75,113.9 38.08,113.9 37.24,113.06 34.25,113.06 34.13,113.17 34.13,116.52 35.74,118.12 48.49,118.12
+19VB on BOTTOM (solid shape): outline of 297 points within 160.31,53.72 185.98,125.85
+19VB on IN1 (solid shape): outline of 136 points within 65.31,137.55 77.19,143.68
+19VB on IN2 (solid shape): 163.87,145.96 163.87,144.46 163.42,144.01 162.15,144.01 162.02,144.14 162.02,144.78 160.37,146.43 159.29,146.43 159.29,148.17 159.55,148.44 161.39,148.44
+19VB on IN2 (solid shape): 136.27,148.43 136.27,146.54 136.15,146.43 135.85,146.43 135.84,146.44 135.36,146.44 134.18,145.25 134.18,144.08 132.96,142.87 130.94,142.87 130.57,143.24 130.57,144.58 133.45,147.46 134.45,148.46 136.24,148.46
+19VB on IN2 (solid shape): 168,114.88 168,113.12 167.81,112.93 165.55,112.93 165.26,112.64 165.26,105.78 165.63,105.41 168.02,105.41 168.08,105.35 168.08,103.5 167.89,103.31 164.25,103.31 163.63,103.93 163.63,114.36 164.25,114.98 167.9,114.98
+19VB_0.95V on TOP (solid shape): 165.01,69.25 165.01,68.36 164.77,68.11 164.77,66.32 164.73,66.28 164.19,66.28 164.12,66.35 164.12,68.23 164.06,68.29 163.74,68.29 163.68,68.36 163.68,69.25 163.81,69.37 164.89,69.37
+19VB_0.95V on BOTTOM (solid shape): 164.97,70.24 164.97,66.12 164.8,65.94 164.8,63.39 164.78,63.37 164.42,63.37 164.4,63.39 164.4,65.85 164.16,66.09 164.16,67.88 163.9,68.14 163.34,68.14 163.25,68.23 163.25,69.64 163.11,69.78 163.11,70.53 163.22,70.64 164.58,70.64
+19VB_1.2V on TOP (solid shape): 63.85,107.43 63.85,107.31 63.85,106.29 63.72,106.17 63.72,104.33 63.66,104.26 62.14,104.26 62.01,104.39 62.01,106.87 62.58,107.44 63.84,107.44
+19VB_1.2V on BOTTOM (solid shape): 63.85,107.25 63.85,104.45 63.72,104.33 63.53,104.33 62.84,103.63 62.84,101.02 62.26,101.02 62.26,101.53 62.14,101.66 61.31,101.66 61.18,101.79 61.18,104.71 61.57,105.09 61.57,107.25 61.63,107.31 63.79,107.31
+19VB_3V on TOP (solid shape): 48.74,113.85 48.74,109.02 48.61,108.9 47.09,108.9 46.96,109.02 46.96,113.85 47.09,113.98 48.61,113.98
+19VB_3V on BOTTOM (solid shape): 48.74,113.59 48.74,109.91 49.74,108.91 49.74,108.35 49.75,108.28 49.78,108.21 49.79,108.2 49.79,107.09 49.73,107.04 47.17,107.04 46.96,107.24 46.96,111.18 46.45,111.69 46.45,113.66 46.52,113.72 48.61,113.72
+19VB_5V on TOP (solid shape): 38.71,112.9 38.71,108.39 38.58,108.26 37.18,108.26 37.05,108.39 37.05,112.82 37.15,112.91 38.69,112.91
+19VB_5V on BOTTOM (solid shape): 38.71,112.9 38.71,109.91 39.71,108.91 39.71,108.35 39.72,108.28 39.75,108.21 39.76,108.2 39.76,106.65 39.65,106.54 37.12,106.54 36.93,106.74 36.93,108.26 34.39,110.8 34.39,112.83 34.47,112.91 35.24,112.91 35.24,112.36 36.59,112.36 36.59,112.91 37.81,112.91 37.82,112.91 38.69,112.91
+19VB_APU on TOP (solid shape): 154.22,122.11 154.22,121.01 154.15,120.93 151.43,120.93 151.27,121.09 151.27,122.07 151.41,122.22 154.12,122.22
+19VB_APU on TOP (solid shape): 157.22,114.55 157.22,111.74 157.1,111.61 155.94,111.61 155.76,111.79 155.76,114.45 155.95,114.63 157.14,114.63
+19VB_APU on BOTTOM (solid shape): 155.98,128.97 155.98,127.41 156.16,127.24 157.21,127.24 157.39,127.06 157.39,126.17 157.86,125.69 158.88,125.69 160.12,124.46 160.12,122.55 159.55,122.55 159.55,121.15 160.12,121.15 160.12,117.66 157.13,114.68 157.13,111.69 155.48,110.04 155.48,105.72 155.36,105.6 150.78,105.6 150.53,105.85 150.53,111.28 152.37,113.12 152.37,115.47 155.93,119.02 155.93,120.45 155.42,120.96 151.42,120.96 151.29,121.09 151.29,121.6 152.43,122.74 152.43,127.19 151.2,128.42 149.04,128.42 148.12,129.34 148.12,131.38 149.01,132.27 152.69,132.27
+19VB_CHG on TOP (solid shape): 187.42,54.03 187.42,53.4 187.23,53.21 187.23,52.2 187.23,52.19 187.47,51.95 187.51,51.91 187.7,51.91 187.79,51.82 187.79,50.94 187.73,50.88 187.41,50.88 187.31,50.78 187.31,49.11 187.21,49 185.38,49 185.2,49.18 185.2,51.49 183.61,53.08 183.61,54.03 183.99,54.41 187.04,54.41
+19VB_CHG on BOTTOM (solid shape): 184.81,56.97 186.46,56.97 186.76,56.66 186.76,53.51 186.93,53.35 187.18,53.35 187.3,53.23 187.3,52.13 187.42,52 187.68,52 187.87,51.81 187.87,51 187.75,50.88 187.34,50.88 187.23,50.77 187.23,49.08 187.17,49.02 185.39,49.02 185.2,49.21 185.2,49.59 184.69,50.1 183.74,50.1 183.55,50.29 183.55,54.61 184.12,54.61 184.12,56.64 183.55,56.64 183.55,57.15 184.63,57.15
+VDD_TOUCH on TOP (solid shape): 222.93,46.38 222.93,41.79 222.7,41.56 221.1,41.56 220.97,41.7 220.97,46.75 221.09,46.87 222.44,46.87
+VDD_TOUCH on BOTTOM (solid shape): 212.98,40.96 213.55,40.96 213.58,40.92 213.58,39.94 213.57,39.93 211.81,39.93 211.7,40.05 211.7,40.98 211.82,41.11 212.84,41.11
+VDD_TOUCH on BOTTOM (solid shape): 222.35,42.57 222.35,40.99 221.31,39.94 220.7,39.94 220.76,40 220.76,40.9 221.28,41.42 221.28,42.35 221.63,42.7 222.22,42.7
+VDDCR_FCH_ALW on TOP (solid shape): outline of 155 points within 131.54,66.14 142.58,72.13
+VDDCR_FCH_ALW on BOTTOM (solid shape): 123.72,35.96 124.37,35.96 124.37,35.43 124.3,35.36 122.4,35.36 122.21,35.56 122.21,35.75 122.37,35.91 122.92,35.91 123.08,36.06 123.62,36.06
+VDDCR_FCH_ALW on BOTTOM (solid shape): 133.13,72.45 133.37,72.36 133.62,72.45 133.86,72.45 134.1,72.36 134.34,72.45 134.61,72.45 134.67,72.39 134.67,71.9 134.59,71.77 134.58,71.62 134.58,71.6 134.42,71.44 134.4,71.44 134.25,71.38 134.14,71.27 134.13,71.25 132.77,71.25 132.58,71.44 132.58,72.04 132.58,72.05 132.61,72.15 132.61,72.26 132.6,72.29 132.77,72.45
+VDDREG on TOP (solid shape): 22.64,90.74 23.21,90.74 23.28,90.67 23.28,89.4 23.59,89.09 23.59,87.31 23.55,87.27 23.43,87.27 23.35,87.35 23.35,88.37 22.48,89.24 21.85,89.24 21.31,89.78 21.31,90.86 22.51,90.86
GND on TOP (solid shape): 34.77,115.25 26.77,115.25 26.77,123.25 34.77,123.25
GND on TOP (solid shape): 122.84,125.09 114.84,125.09 114.84,133.09 122.84,133.09
GND on TOP (solid shape): 11.1,108.9 3.85,108.9 3.85,115.65 11.1,115.65
GND on TOP (solid shape): 24.74,21.59 24.74,20.37 23.21,20.37 23.21,21.52 23.53,21.84 24.48,21.84
GND on TOP (solid shape): 41.88,104.96 41.88,103.82 41.75,103.69 40.74,103.69 40.61,103.82 40.61,104.96 40.86,105.21 41.63,105.21
GND on TOP (solid shape): 46.58,94.86 46.58,91.43 46.45,91.31 45.37,91.31 45.18,91.5 45.18,94.73 45.5,95.05 46.39,95.05
GND on TOP (solid shape): 51.66,113.72 51.66,109.15 51.41,108.9 49.12,108.9 48.99,109.02 48.99,113.85 49.12,113.98 51.41,113.98
GND on TOP (solid shape): 61.61,89.91 61.61,86.54 61.46,86.39 59.96,86.39 59.89,86.46 59.89,89.93 60.01,90.05 61.48,90.05
GND on TOP (solid shape): 70.01,65.4 70.01,63.24 69.82,63.05 66.39,63.05 66.2,63.24 66.2,65.53 66.26,65.59 69.82,65.59
GND on TOP (solid shape): 128.55,67.98 128.55,66.02 128.49,65.95 127.98,65.95 127.92,66.02 127.92,67.98 128.04,68.11 128.42,68.11
GND on TOP (solid shape): 148.09,109.93 148.09,105.28 147.92,105.1 146.19,105.1 146.04,105.25 146.04,110 146.16,110.12 147.9,110.12
GND on TOP (solid shape): 159.85,89.59 159.85,88.1 159.79,88.04 156.96,88.04 156.86,88.14 156.86,89.62 156.9,89.67 159.77,89.67
GND on TOP (solid shape): 190.77,60.27 190.77,59.14 190.68,59.05 188.49,59.05 188.42,59.13 188.42,60.29 188.5,60.38 190.67,60.38
GND on TOP (solid shape): 67.15,106.87 67.15,103.69 66.84,103.37 64.11,103.37 64.11,106.8 64.55,107.25 66.77,107.25
GND on TOP (solid shape): 91.38,149.52 91.38,148.61 91.27,148.5 86.15,148.5 86.04,148.61 86.04,149.63 86.14,149.73 91.16,149.73 91.16,149.73
GND on TOP (solid shape): 24.24,26.3 24.24,24.6 24.16,24.52 20.25,24.52 20.18,24.59 20.18,26.25 20.27,26.34 24.2,26.34
GND on TOP (solid shape): 40.03,14.54 40.03,10.08 39.91,9.96 39.28,9.96 39.09,10.16 39.09,12.82 38.83,13.08 38.83,14.66 38.9,14.73 39.85,14.73
GND on TOP (solid shape): 190.99,51.98 190.99,51.34 190.76,51.1 190.76,50.48 190.7,50.43 189.62,50.43 189.54,50.5 189.54,51.95 189.59,52 190.97,52
GND on TOP (solid shape): 37.99,94.53 37.99,90.08 37.82,89.91 36.63,89.91 36.5,90.04 36.5,94.62 36.61,94.73 37.79,94.73
GND on TOP (solid shape): 20.27,58.54 22.32,58.54 22.6,58.27 22.6,54.05 21.62,53.08 20.26,53.08 20.04,53.3 20.04,58.33 20.26,58.55
GND on TOP (solid shape): 131.29,71.18 131.29,70.47 131.47,70.29 131.47,67.86 131.35,67.73 130.65,67.73 130.52,67.86 130.52,69.83 130.63,69.93 130.63,71.21 130.65,71.24 131.23,71.24
GND on TOP (solid shape): 161.33,73.33 161.33,69.25 161.01,68.93 159.3,68.93 159.15,69.07 159.15,73.52 159.29,73.66 161.01,73.66
GND on TOP (solid shape): 162.21,94.6 162.21,92.38 162.14,92.31 161.05,92.31 160.94,92.42 160.94,94.55 161.13,94.74 162.08,94.74
GND on TOP (solid shape): 37.3,16.9 37.3,16.16 37.23,16.09 37.13,16.06 37.05,16.01 36.32,16.01 36.17,16.17 36.17,17.48 36.2,17.52 36.69,17.52
GND on TOP (solid shape): 69.4,121.31 69.4,119.57 69.38,119.57 69.19,119.38 67.2,119.38 66.76,119.82 66.76,121.27 66.86,121.38 69.33,121.38
GND on TOP (solid shape): 27.97,10.92 27.97,9.9 27.66,9.58 26.32,9.58 26.32,10.09 27.09,10.09 27.28,10.28 27.28,10.83 27.43,10.98 27.91,10.98
GND on TOP (solid shape): 150.59,134.41 151.61,134.41 151.74,134.29 151.74,132.63 151.61,132.51 149.97,132.51 149.58,132.9 149.58,134.54 149.7,134.67 150.34,134.67
GND on TOP (solid shape): 35.59,32.95 35.59,30.95 35.05,30.41 35.05,27.12 35.04,27.11 33.69,27.11 32.48,28.32 32.48,33.09 32.66,33.26 35.29,33.26
GND on TOP (solid shape): 166.72,57.46 166.72,53.72 165.01,52 164.05,52 163.93,52.13 163.93,56.32 164.16,56.55 164.36,56.65 164.46,56.85 165.39,57.78 166.4,57.78
GND on TOP (solid shape): 163.04,69.31 163.04,68.17 163.26,67.94 163.8,67.94 163.87,67.87 163.87,66.15 163.71,65.98 163.71,64.66 163.55,64.51 162.54,64.51 162.33,64.71 162.33,66.52 161.58,67.27 161.58,69.31 161.76,69.49 162.85,69.49
GND on TOP (solid shape): 121.48,104.21 121.48,100.71 121.38,100.71 120.75,100.07 120.75,99.88 120.62,99.75 120.24,99.75 120.11,99.88 120.11,100.79 120.28,100.96 120.64,100.96 120.72,101.05 120.72,103.81 120.73,103.81 120.73,104.23 120.8,104.31 121.38,104.31
GND on TOP (solid shape): 171.04,51.24 171.04,50.67 171.67,50.03 173.2,50.03 173.39,49.84 173.39,49.27 171.93,49.27 171.55,48.89 171.29,48.89 171.23,48.95 171.23,49.08 170.91,49.4 170.4,49.4 170.4,50.03 170.15,50.29 169.23,50.29 169.05,50.47 169.05,50.97 170.02,51.94 170.34,51.94
GND on TOP (solid shape): 105,135 135.73,135 135.99,134.74 135.99,132.39 135.73,132.14 133.89,132.14 130.56,128.81 127.76,128.81 123.35,124.39 114.97,124.39 114.21,125.15 114.21,128.2 112.56,129.85 98.97,129.85 98.59,130.23 98.59,134.49 99.86,135.76 104.24,135.76
GND on TOP (solid shape): 19.58,37.26 19.85,37.13 20.11,37.26 22.02,37.26 22.26,37.01 22.26,32.24 22.02,32 19.4,32 19.06,32.34 19.06,37.21 19.11,37.26
GND on TOP (solid shape): 121.46,77 121.46,76.51 121.29,76.34 121.29,75.54 120.72,74.97 120.02,74.97 119.71,74.65 119.71,74.64 119.68,74.61 119.68,74.1 119.56,73.98 119.11,73.98 119.05,74.04 119.05,74.8 119.67,75.42 119.67,76.63 120.07,77.02 121.44,77.02
GND on TOP (solid shape): 170.4,41.6 170.4,40.64 170.66,40.38 173.33,40.38 173.71,40 173.71,38.1 173.45,37.84 167.93,37.84 167.67,38.1 167.67,40.17 167.31,40.53 166.44,40.53 166.06,40.92 166.06,41.52 166.38,41.84 170.15,41.84 170.16,41.85
GND on TOP (solid shape): 27.21,7.3 27.21,7.17 27.59,6.79 29.63,6.79 29.88,6.54 35.28,6.54 35.34,6.47 35.34,5.96 33.69,4.31 31.34,4.31 29.5,6.15 27.34,6.15 26.64,6.85 26.64,7.3 26.7,7.36 27.15,7.36
GND on TOP (solid shape): 38.32,8.44 38.69,8.08 38.69,7.9 38.55,7.76 38.36,7.76 38.2,7.92 38.2,8 38.01,8.19 35.47,8.19 35.34,8.31 35.34,8.62 35.42,8.69 35.8,8.69 35.85,8.75 37.61,8.75 37.69,8.82 38.32,8.82
GND on TOP (solid shape): 130.63,88.34 130.63,87.53 130.77,87.39 131.58,87.39 131.97,87.78 132.29,87.78 132.35,87.71 132.35,87.15 132.38,87.13 133.54,87.13 133.56,87.1 133.56,87.05 133.57,86.99 133.57,86.49 133.55,86.46 130.41,86.46 130.39,86.49 130.39,86.93 130.29,87.03 130.02,87.03 129.92,87.13 129.92,87.46 130.06,87.6 130.06,88.33 130.09,88.36 130.61,88.36
GND on TOP (solid shape): 155.55,119.95 155.55,118.36 153.26,116.07 153.26,113.41 150.47,110.61 144.69,110.61 144.43,110.87 144.43,112.33 144.69,112.58 149.32,112.58 149.64,112.9 149.64,115.69 149.83,115.88 150.78,115.88 151.16,116.26 151.16,118.17 151.61,118.61 151.61,119.76 151.29,120.07 151.29,120.52 151.42,120.65 154.85,120.65
GND on TOP (solid shape): 165.95,48.45 165.95,48.44 166.24,48.16 168.07,48.16 168.56,47.67 168.56,47.3 168.82,47.05 169.33,47.05 169.52,47.24 169.52,47.66 169.73,47.87 170.09,47.87 170.09,45.97 170.15,45.91 170.15,44.83 169.07,44.83 168.94,44.95 166.85,44.95 164.3,47.51 164.3,48.13 164.8,48.63 165.77,48.63
GND on TOP (solid shape): 188.71,53.89 188.71,52.23 188.72,52.22 188.72,51.52 188.86,51.37 189.11,51.37 189.26,51.21 189.26,47.56 188.73,47.02 186.18,47.02 185.9,46.74 185.22,46.74 185.16,46.8 185.16,48.46 185.52,48.83 187.31,48.83 187.46,48.98 187.46,50.58 187.51,50.63 187.74,50.63 187.99,50.88 187.99,52.07 187.8,52.26 187.8,54.03 187.87,54.1 188.5,54.1
GND on TOP (solid shape): 161.73,115.82 161.73,112.16 161.58,112.01 160.94,112.01 160.56,111.63 160.56,110.8 160.82,110.55 161.2,110.55 161.39,110.36 161.39,109.41 161.26,109.28 158.34,109.28 158.15,109.47 158.15,110.29 157.64,110.8 156.5,110.8 155.99,110.29 155.99,110.04 155.86,109.91 155.1,109.91 154.97,110.04 154.97,110.68 155.61,111.31 157.13,111.31 157.45,111.63 157.45,114.75 158.93,116.24 161.31,116.24
GND on TOP (solid shape): 103,150 99,150 96.17,151.17 95,154 95,154.4 103,154.4
GND on TOP (solid shape): 130.67,83.85 130.66,83.75 130.67,83.66 130.67,82.51 131.22,81.97 131.3,81.97 131.36,81.91 131.36,81.13 131.17,80.94 130.32,80.94 129.84,80.46 129.5,80.13 129.3,80.13 129.17,80.26 129.17,80.56 129.78,81.17 129.78,81.19 129.79,81.2 129.85,81.4 129.8,81.59 129.8,82.2 129.87,82.34 129.87,82.5 129.87,82.53 129.87,82.99 129.46,83.39 129.46,83.64 129.68,83.86 130.65,83.86
GND on TOP (solid shape): 125.16,79.63 125.16,79.04 125.38,78.83 126.42,78.83 126.73,79.14 127.43,79.14 127.44,79.13 127.44,78.63 127.56,78.51 127.83,78.51 128,78.33 128,78.13 127.85,77.98 127.53,77.98 127.28,78.23 125.22,78.23 125.02,78.03 121.49,78.03 121.47,78.05 119.74,78.05 119.71,78.02 119.41,78.02 119.28,78.14 119.28,78.59 119.66,78.97 120.55,78.97 120.55,78.97 120.94,78.97 121.49,79.52 121.56,79.58 123.01,79.58 123.14,79.45 123.14,79.12 123.32,78.93 123.71,78.93 123.88,79.11 124.36,79.11 124.57,79.33 124.57,79.64 124.66,79.72 125.07,79.72
GND on TOP (solid shape): 41.75,112.51 41.75,108.51 41.5,108.26 39.09,108.26 38.96,108.39 38.96,109.43 39.37,109.43 39.37,109.38 39.37,109.32 39.39,109.27 39.41,109.22 39.44,109.18 39.48,109.14 39.52,109.11 39.57,109.08 39.62,109.06 39.67,109.05 39.72,109.05 39.77,109.05 39.83,109.06 39.88,109.08 39.92,109.11 39.96,109.14 40,109.18 40.03,109.22 40.05,109.27 40.07,109.32 40.08,109.38 40.08,109.43 40.07,109.48 40.05,109.53 40.03,109.58 40,109.63 39.96,109.66 39.92,109.7 39.88,109.72 39.83,109.74 39.77,109.76 39.72,109.76 39.67,109.76 39.62,109.74 39.57,109.72 39.52,109.7 39.48,109.66 39.44,109.63 39.41,109.58 39.39,109.53 39.37,109.48 39.37,109.43 38.96,109.43 38.96,113.4 39.15,113.59 40.68,113.59
GND on TOP (solid shape): 17.51,24.9 17.51,21.98 15.4,19.87 5.45,19.87 5.42,19.87 4.7,19.87 4.7,21.14 4.7,22 4.79,22.21 5,22.3 6.18,22.3 13.5,22.3 14.2,22.9 13.7,23.67 13.7,24.21 13.7,24.44 14.23,24.44 14.23,24.44 15.15,24.44 15.43,24.72 15.43,25.97 15.68,26.22 16.19,26.22
GND on TOP (solid shape): 129.18,76.98 130.92,76.98 132.17,75.73 132.17,75.67 131.85,75.35 131.73,75.35 131.35,75.73 130.27,75.73 130.14,75.86 129.69,75.86 129.57,75.73 129.54,75.71 129.54,75.47 129.48,75.4 128.11,75.4 128.02,75.49 128.02,75.68 127.76,75.95 126.55,75.95 126.39,75.79 126.39,75.16 125.47,75.16 125.37,75.27 125.37,75.66 125.06,75.96 124.27,75.96 124.16,76.07 124.16,77.13 124.19,77.16 125.68,77.16 125.78,77.06 125.78,76.5 125.84,76.44 125.91,76.44 125.91,76.43 126.62,76.43 126.62,76.44 126.77,76.44 126.77,76.43 127.48,76.43 127.48,76.5 127.63,76.66 127.63,77.09 127.7,77.15 128.45,77.15 128.62,77.32 128.84,77.32
GND on TOP (solid shape): outline of 89 points within 121.37,81.18 127.94,84.41
GND on TOP (solid shape): outline of 101 points within 57.88,128.27 66.23,135.25
GND on TOP (solid shape): 16.42,49.97 16.42,46.35 13.05,42.98 13.05,38.16 13.43,37.78 14.77,37.78 15.15,37.4 15.15,34.98 14.71,34.55 14.26,34.1 13.81,34.1 13.81,34.1 13.7,34.2 13.7,34.21 13.7,34.83 14.2,35.6 13.5,36.2 5,36.2 4.79,36.29 4.7,36.5 4.7,45.9 4.79,46.11 5,46.2 13.5,46.2 14.03,46.44 14.2,46.99 14.19,47.01 14.03,47.36 13.7,47.57 13.7,48.4 15.16,48.4 15.4,48.64 15.4,49.97 15.59,50.16 16.23,50.16
GND on TOP (solid shape): 5.4,66.25 5.6,65.75 6.1,65.55 6.9,65.55 7.4,65.75 7.6,66.25 7.6,66.75 10.6,66.75 10.6,66.73 10.83,66.73 16.04,61.53 16.04,59.43 14.58,57.97 14.27,57.97 14.27,57.97 13.81,57.97 13.7,58.08 13.7,58.73 14.2,59.5 13.5,60.1 5,60.1 4.79,60.19 4.7,60.4 4.7,64.2 4.5,64.7 4,64.9 0.6,64.9 0.39,64.99 0.3,65.2 0.3,66.45 0.39,66.66 0.6,66.75 5.4,66.75
GND on TOP (solid shape): 10.71,91.05 11.41,90.36 13.43,90.36 13.88,89.91 13.88,80.32 13.23,79.68 12.2,79.68 12.2,80.85 12,81.35 11.5,81.55 7.6,81.55 7.6,82.05 7.4,82.55 6.9,82.75 6.1,82.75 5.6,82.55 5.4,82.05 5.4,81.55 0.6,81.55 0.39,81.64 0.3,81.85 0.3,83.35 0.39,83.56 0.6,83.65 2,83.65 2.5,83.85 2.7,84.35 2.7,88.6 2.79,88.81 3,88.9 10.05,88.9 10.75,89.5 10.25,90.27 10.25,91.47 10.71,91.47
GND on TOP (solid shape): outline of 192 points within 60.36,30.54 106.9,40.57
GND on TOP (solid shape): outline of 1494 points within 0.2,0.2 228.2,154.2
GND on TOP (solid shape): outline of 1594 points within 60.49,48.7 87.85,84.13
GND on BOTTOM (solid shape): 61.61,89.91 61.61,86.54 61.46,86.39 59.96,86.39 59.89,86.46 59.89,89.93 60.01,90.05 61.48,90.05
GND on BOTTOM (solid shape): 75.63,146.56 75.63,143.81 75.44,143.63 73.12,143.63 72.91,143.84 72.91,146.45 73.13,146.68 75.51,146.68
GND on BOTTOM (solid shape): 148.09,109.93 148.09,105.28 147.92,105.1 146.19,105.1 146.04,105.25 146.04,110 146.16,110.12 147.9,110.12
GND on BOTTOM (solid shape): 159.85,89.59 159.85,88.1 159.79,88.04 156.96,88.04 156.86,88.14 156.86,89.62 156.9,89.67 159.77,89.67
GND on BOTTOM (solid shape): 162.28,94.61 162.28,92.43 162.16,92.31 161.05,92.31 160.94,92.41 160.94,94.61 161.07,94.74 162.15,94.74
GND on BOTTOM (solid shape): 181.33,62.35 181.33,59.69 181.31,59.67 179.89,59.67 179.24,60.31 179.24,61.85 179.8,62.42 181.26,62.42
GND on BOTTOM (solid shape): 150.43,142.55 150.43,138.49 150.29,138.35 150.28,138.36 146.38,138.36 146.07,138.67 146.07,142.6 146.12,142.65 150.33,142.65
GND on BOTTOM (solid shape): 206.56,37.19 206.56,35.91 206.14,35.5 204.14,35.5 203.88,35.76 203.88,37.39 203.98,37.5 206.25,37.5
GND on BOTTOM (solid shape): 46.58,94.86 46.58,91.43 46.45,91.31 45.37,91.31 45.18,91.5 45.18,94.73 45.5,95.05 46.39,95.05
GND on BOTTOM (solid shape): 67.15,106.87 67.15,101.98 66.9,101.72 64.49,101.72 64.42,101.79 64.42,103.75 64.11,104.07 64.11,106.8 64.55,107.25 66.77,107.25
GND on BOTTOM (solid shape): 125.78,97.88 125.78,96.9 125.72,96.84 124.07,96.84 124,96.9 124,97.81 124.23,98.03 125.62,98.03
GND on BOTTOM (solid shape): 143.04,119.69 143.04,116.9 142.91,116.77 139.5,116.77 139.3,116.97 139.3,119.51 139.61,119.82 142.91,119.82
GND on BOTTOM (solid shape): 152.43,137.6 152.43,132.9 152.05,132.52 149.83,132.52 149.51,132.84 149.51,137.6 149.7,137.79 152.24,137.79
GND on BOTTOM (solid shape): 160.5,50.73 160.5,48.13 159.93,47.56 159.23,47.56 159.1,47.68 159.1,50.86 159.17,50.92 160.31,50.92
GND on BOTTOM (solid shape): 181.07,39.94 181.07,36.83 181.01,36.76 179.49,36.76 179.17,37.08 179.17,39.87 179.29,40 181.01,40
GND on BOTTOM (solid shape): 37.99,94.53 37.99,90.08 37.82,89.92 37.49,89.92 37.48,89.91 36.61,89.91 36.48,90.04 36.48,94.61 36.6,94.73 37.79,94.73
GND on BOTTOM (solid shape): 63.28,78.31 63.28,76.24 63.05,76 60.87,76 60.36,75.5 60.36,73.85 60.23,73.72 59.72,73.72 59.6,73.85 59.6,78.29 59.85,78.54 63.05,78.54
GND on BOTTOM (solid shape): 139.1,130.23 139.1,128.84 138.97,128.71 137.96,128.71 137.19,127.95 134.4,127.95 134.15,128.2 134.15,131.32 134.47,131.65 137.68,131.65
GND on BOTTOM (solid shape): 161.2,73.21 161.2,69.34 160.88,69.02 159.29,69.02 159.29,69.03 159.29,71.52 159.28,71.52 159.28,73.65 159.29,73.66 160.75,73.66
GND on BOTTOM (solid shape): 97.67,124.07 97.73,124.06 97.75,124.06 97.86,123.95 97.86,123.19 97.73,123.06 96.54,123.06 96.46,123.14 96.46,123.88 96.69,124.1 97.6,124.1
GND on BOTTOM (solid shape): 121.45,28.57 129.32,28.57 129.51,28.38 129.51,26.54 129.32,26.35 113.83,26.35 113.64,26.54 113.64,28.38 113.83,28.57 121.41,28.57
GND on BOTTOM (solid shape): 56.8,34.86 56.8,31.17 57.06,30.92 57.06,30.54 56.55,30.03 51.28,30.03 50.07,28.82 50.07,27.94 49.88,27.74 47.98,27.74 47.85,27.87 47.85,34.48 48.99,35.62 56.04,35.62
GND on BOTTOM (solid shape): 150.05,103.12 151.71,103.12 152.82,102.01 152.82,99.5 152.43,99.12 145.45,99.12 144.94,99.63 144.94,102.81 145.39,103.26 149.91,103.26
GND on BOTTOM (solid shape): 166.59,57.78 167.1,57.78 167.17,57.72 167.17,57.02 166.66,56.51 166.66,52.57 166.53,52.45 165.2,52.45 164.94,52.7 164.94,56.83 164.75,57.02 164.75,58.61 164.82,58.67 165.71,58.67
GND on BOTTOM (solid shape): 193.07,61.47 193.34,61.21 193.34,60.21 193.2,60.07 191.36,60.07 191.17,60.26 191.17,60.89 191.8,61.53 191.8,62.16 191.99,62.35 193.07,62.35
GND on BOTTOM (solid shape): 173.76,42.55 173.76,42.42 173.77,42.41 173.77,37.97 173.57,37.77 166.85,37.77 166.66,37.97 166.66,41.59 166.79,41.71 169.96,41.71 170.21,41.97 170.21,43.05 170.28,43.11 173.2,43.11
GND on BOTTOM (solid shape): 62.45,112.14 62.45,111.83 62.25,111.63 62.09,111.63 61.52,111.06 59.6,111.06 59.47,111.18 59.47,112.01 59.6,112.14 60.87,112.14 61.12,111.88 61.5,111.88 61.63,112.01 61.63,112.14 61.69,112.2 62.39,112.2
GND on BOTTOM (solid shape): 163.03,69.35 163.03,68.04 163.13,67.94 163.78,67.94 163.93,67.79 163.93,65.8 164.06,65.68 164.06,63.44 164.01,63.39 163.71,63.39 162.33,64.76 162.33,66.53 161.65,67.21 161.65,69.37 161.76,69.48 161.92,69.48 161.93,69.49 162.89,69.49
GND on BOTTOM (solid shape): 165.96,48.61 169.35,48.61 169.39,48.57 169.39,47.91 169.37,47.88 168.78,47.88 168.62,47.72 168.61,47.71 168.61,47.39 168.51,47.29 165.73,47.29 165.63,47.39 163.79,47.39 163.65,47.53 163.65,48.55 163.8,48.7 165.87,48.7
GND on BOTTOM (solid shape): 161.73,115.82 161.73,112.16 161.58,112.01 160.94,112.01 160.56,111.63 160.56,110.93 160.18,110.55 160.18,109.47 159.99,109.28 157.13,109.28 156.94,109.47 156.94,111.25 157.45,111.76 157.45,114.74 158.95,116.24 161.31,116.24
GND on BOTTOM (solid shape): 155.55,120.2 155.55,119.04 151.94,115.44 151.94,113.36 150.06,111.47 150.06,111.02 149.69,110.65 144.7,110.65 144.43,110.91 144.43,112.71 145.45,113.72 145.45,114.93 145.64,115.12 149.01,115.12 149.83,115.95 149.83,116.9 150.08,117.15 150.91,117.15 151.1,117.34 151.1,120.52 151.29,120.71 155.04,120.71
GND on BOTTOM (solid shape): 188.69,51.49 188.88,51.3 189.11,51.3 189.24,51.18 189.24,47.4 188.88,47.05 185,47.05 184.95,47.1 184.95,48.7 185.07,48.83 187.36,48.83 187.55,49.02 187.55,50.7 187.59,50.74 187.87,50.74 187.99,50.86 187.99,52 187.74,52.26 187.74,53.21 187.87,53.34 188.69,53.34
GND on BOTTOM (solid shape): 145.51,135.19 145.51,133.66 145,133.15 139.67,133.15 138.65,132.14 133.89,132.14 130.53,128.77 127.73,128.77 125.38,126.42 116.75,126.42 114.72,128.46 105.76,128.46 104.4,129.82 99,129.82 98.59,130.23 98.59,134.49 99.73,135.63 102.84,135.63 104.36,134.11 136.5,134.11 138.25,135.86 144.84,135.86
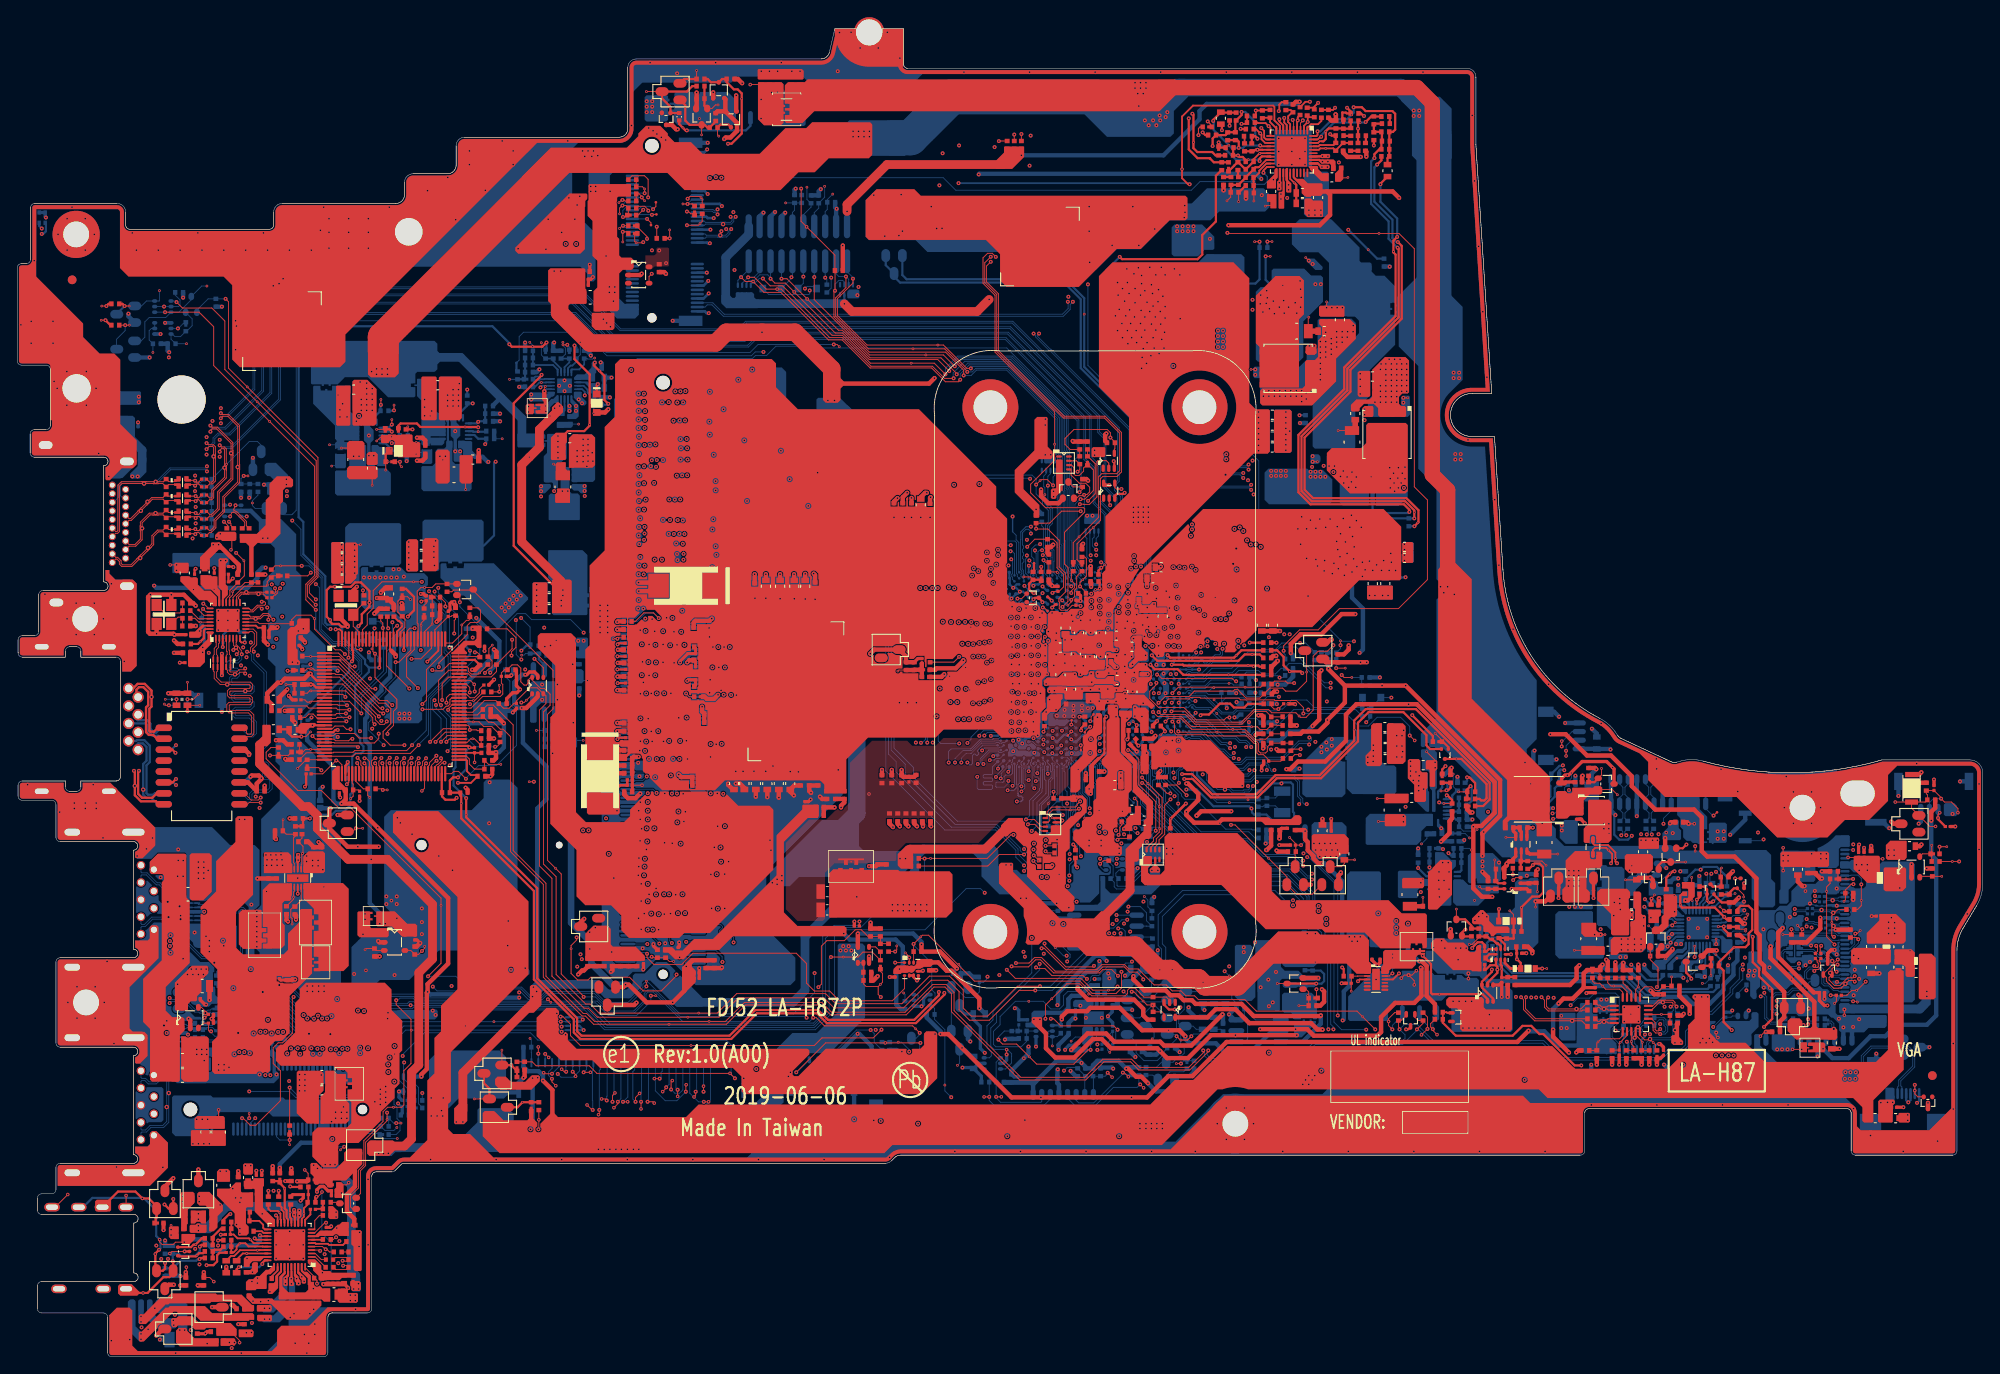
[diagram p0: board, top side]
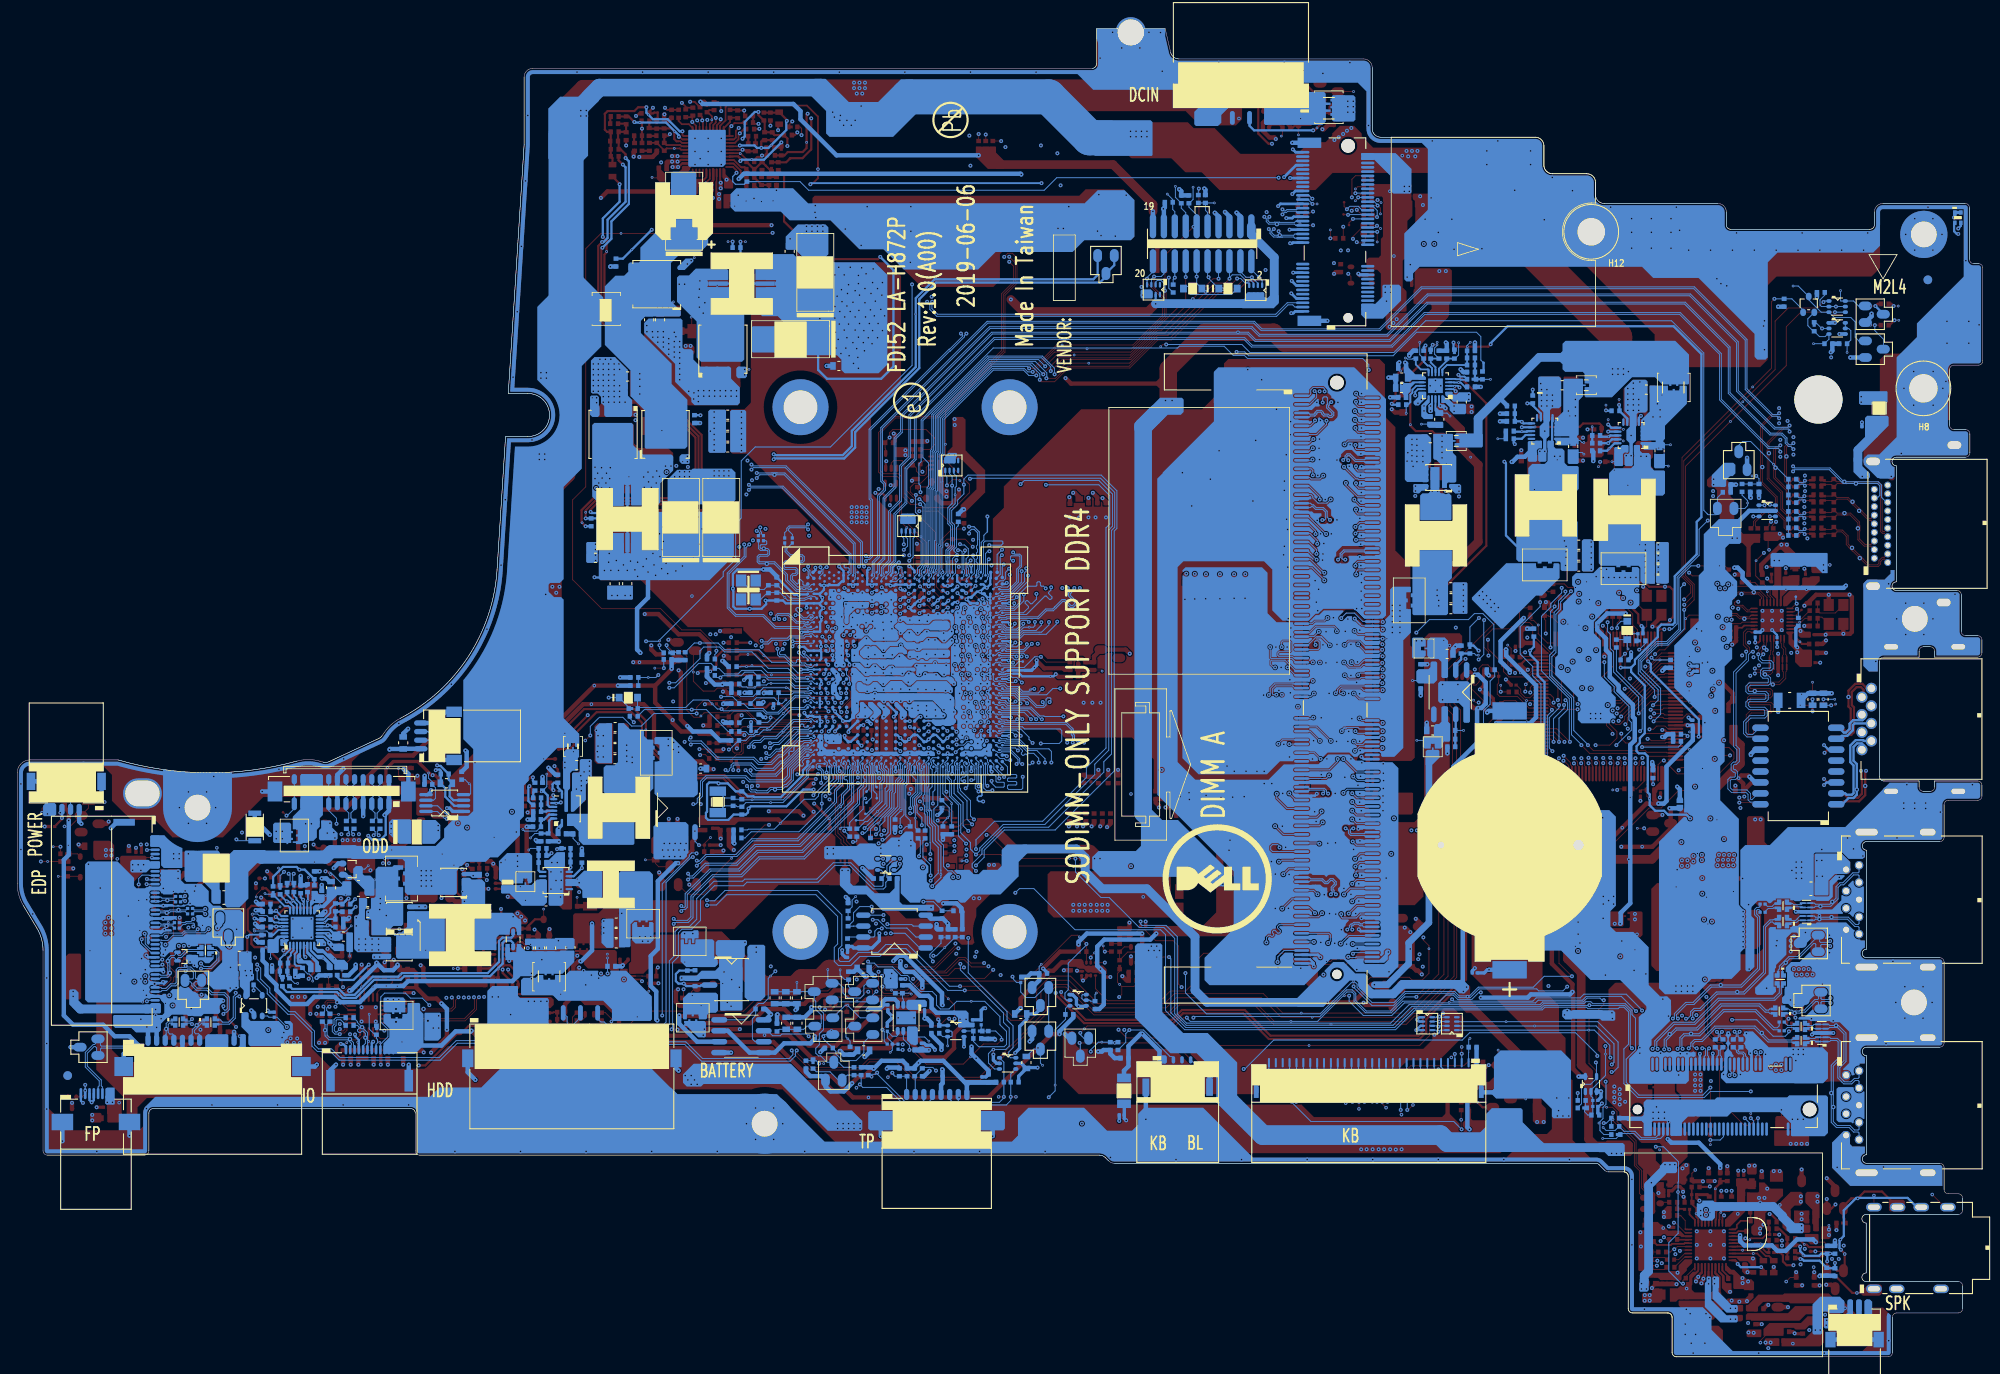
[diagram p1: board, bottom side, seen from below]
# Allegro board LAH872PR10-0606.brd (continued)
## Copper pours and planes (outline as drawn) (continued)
GND on BOTTOM (solid shape): 147.23,48.19 147.23,46.79 146.85,46.41 146.85,45.33 147.29,44.89 148.88,44.89 149.45,44.32 151.35,44.32 151.42,44.25 151.42,43.75 151.35,43.68 151.14,43.68 150.94,43.74 150.74,43.68 149.26,43.68 149.01,43.94 146.97,43.94 146.72,43.68 146.72,40.32 146.66,40.25 144.24,40.25 144.12,40.38 144.12,46.29 143.86,46.54 143.86,47.68 143.61,47.94 143.61,48.32 143.73,48.45 146.97,48.45
GND on BOTTOM (solid shape): 17.51,24.9 17.51,21.98 15.4,19.87 5.45,19.87 5.42,19.87 4.7,19.87 4.7,22 4.79,22.21 5,22.3 13.5,22.3 14.2,22.9 13.7,23.67 13.7,24.21 13.7,24.44 14.23,24.44 14.23,24.44 15.15,24.44 15.43,24.72 15.43,25.97 15.68,26.22 16.19,26.22
GND on BOTTOM (solid shape): 51.66,113.85 51.66,110.46 51.04,109.84 51.04,108.63 51.49,108.19 51.49,107.09 51.09,106.7 51.09,105.71 51.19,105.52 51.4,105.49 51.64,105.43 51.68,105.18 51.66,105.14 51.66,104.2 51.53,104.07 50.82,104.07 50.7,104.19 50.7,105.15 50.69,105.18 50.67,105.28 50.69,105.37 50.7,105.4 50.7,106.73 50.37,107.06 50.37,108.74 50.29,108.83 50.29,110.07 50.07,110.29 49.25,110.29 48.99,110.55 48.99,113.72 49.25,113.98 51.53,113.98
GND on BOTTOM (solid shape): 41.63,112.64 41.63,109.96 41.02,109.36 41.02,108.14 41.41,107.76 41.41,106.61 41.06,106.26 41.06,105.2 41.16,105.02 41.36,104.98 41.61,104.92 41.64,104.67 41.63,104.63 41.63,103.69 41.5,103.56 40.79,103.56 40.67,103.68 40.67,104.64 40.65,104.68 40.64,104.77 40.65,104.86 40.67,104.89 40.67,106.16 40.29,106.54 40.29,108.16 40.22,108.23 40.22,109.6 40.04,109.78 39.21,109.78 38.96,110.04 38.96,113.4 39.15,113.59 40.67,113.59
GND on BOTTOM (solid shape): 132.32,87.69 132.32,87.27 132.28,87.23 132.28,87.19 132.28,87.18 132.25,87.03 132.28,86.88 132.28,86.87 132.28,86.17 132.22,85.97 132.28,85.77 132.28,85.37 132.11,85.19 131.96,85.19 131.79,85.37 131.79,86.08 131.75,86.12 131.75,86.23 130.99,86.99 130.9,86.99 130.89,87 130.73,87.04 130.58,87 130.57,86.99 129.8,86.99 129.79,87 129.71,87.03 129.63,87.04 129.61,87.04 129.43,87.22 129.43,87.25 129.43,87.35 129.4,87.46 129.4,87.47 129.4,87.69 129.46,87.76 132.26,87.76
GND on BOTTOM (solid shape): 120.72,85.59 120.83,85.58 120.94,85.59 120.95,85.6 121.82,85.6 121.87,85.58 121.94,85.58 122.36,85.15 122.4,85.15 122.44,85.11 125.06,85.11 125.1,85.15 125.15,85.15 125.4,85.41 125.47,85.44 125.54,85.41 125.78,85.3 126.03,85.39 126.42,85.01 126.42,84.85 125.96,84.4 125.96,84.1 125.93,84.05 125.91,83.97 125.87,83.93 125.61,83.93 125.57,83.98 125.57,83.99 125.54,84.01 125.54,84.02 125.47,84.14 125.35,84.22 125.34,84.22 124.92,84.63 124.5,84.63 124.03,84.17 124,84.14 123.97,84.11 123.82,83.95 123.67,83.95 122.99,84.63 122.5,84.63 122.31,84.45 120.87,84.45 120.75,84.48 120.62,84.45 120.32,84.45 120.04,84.73 120.04,85.32 120.32,85.6 120.72,85.6
GND on BOTTOM (solid shape): 115.7,71.16 115.7,71.14 115.8,70.87 116.06,70.78 116.09,70.78 116.38,70.48 117.29,70.48 117.53,70.38 117.78,70.48 118.39,70.48 118.5,70.41 118.63,70.38 118.65,70.38 118.86,70.17 118.86,69.91 118.73,69.79 118.33,69.79 118.08,69.94 117.83,69.79 117.23,69.79 116.98,69.94 116.73,69.79 116.13,69.79 115.88,69.94 115.63,69.79 115.18,69.79 115.11,69.85 115.11,70.31 115.26,70.56 115.11,70.8 115.11,71.18 115.24,71.31 115.56,71.31
GND on BOTTOM (solid shape): 133.91,80.01 133.91,79.71 133.88,79.69 133.77,79.61 133.7,79.49 133.69,79.48 133.4,79.18 133.4,79.04 133.32,78.71 133.58,78.48 133.6,78.48 133.76,78.31 133.77,78.29 133.79,78.19 133.85,78.09 133.85,77.09 133.69,76.93 133.67,76.94 133.4,76.84 133.3,76.57 133.31,76.55 133.12,76.36 132.77,76.36 132.72,76.41 132.69,76.43 132.56,76.56 132.56,76.65 132.56,76.65 132.56,76.76 132.61,76.8 132.63,76.8 132.88,76.9 132.99,77.16 132.99,77.18 133.15,77.34 133.15,77.61 133.16,77.71 133.15,77.81 133.15,77.98 132.87,78.26 132.87,78.28 132.8,78.5 132.61,78.64 132.58,78.65 132.58,78.98 132.6,78.99 132.77,79.15 132.8,79.38 132.79,79.4 133.05,79.66 133.08,79.69 133.53,80.14 133.78,80.14
GND on BOTTOM (solid shape): 10.71,91.05 11.41,90.36 13.43,90.36 13.88,89.91 13.88,80.32 13.23,79.68 12.2,79.68 12.2,80.85 12,81.35 11.5,81.55 7.6,81.55 7.6,82.05 7.4,82.55 6.9,82.75 6.1,82.75 5.6,82.55 5.4,82.05 5.4,81.55 0.6,81.55 0.39,81.64 0.3,81.85 0.3,83.35 0.39,83.56 0.6,83.65 2,83.65 2.5,83.85 2.7,84.35 2.7,88.6 2.79,88.81 3,88.9 10.05,88.9 10.75,89.5 10.25,90.27 10.25,91.47 10.71,91.47
GND on BOTTOM (solid shape): 15.05,55.35 15.17,55.33 15.63,54.87 15.66,54.78 15.6,54.71 15.36,53.81 16.27,53.66 16.37,53.67 16.43,53.58 16.43,53.08 17.51,52 19.29,52 19.34,51.95 19.34,51.55 19.29,51.5 16.35,51.5 16.26,51.57 16.29,51.68 15.81,52.77 15.6,51.6 15.62,51.58 15.62,51.5 15.47,51.5 15.17,51.2 15.06,51.17 14.99,51.25 14.6,51.73 13.98,51.63 13.87,51.61 13.81,51.71 13.81,54.59 13.87,54.69 13.98,54.67 14.68,54.61 15,55.24
GND on BOTTOM (solid shape): outline of 192 points within 13.75,27.15 16.99,31.35
GND on BOTTOM (solid shape): outline of 125 points within 0.3,44.81 28.16,66.75
GND on BOTTOM (solid shape): outline of 179 points within 119.53,79.98 131.5,83.75
GND on BOTTOM (solid shape): outline of 199 points within 119.29,73.34 131.5,80.14
GND on BOTTOM (solid shape): outline of 116 points within 121.78,69.85 135.43,72.39
GND on BOTTOM (solid shape): outline of 465 points within 17.99,31.78 30.42,37.83
GND on BOTTOM (solid shape): outline of 571 points within 33.37,31.75 58.14,67.11
GND on BOTTOM (solid shape): outline of 710 points within 4.7,32.72 26.45,50.5
GND on BOTTOM (solid shape): outline of 1456 points within 0.2,0.2 228.2,154.2
GND on BOTTOM (solid shape): outline of 1775 points within 202.09,37.71 220.51,57.59
GND on BOTTOM (solid shape): outline of 7143 points within 67.92,43.22 95.92,115.03
GND on VCC (solid shape): 163.67,51.94 163.55,51.81 160.88,51.81 160.82,51.87 160.82,55.11 162.75,55.11 162.75,55.06 162.76,55.01 162.78,54.96 162.81,54.91 162.84,54.87 162.88,54.83 162.92,54.8 162.97,54.78 163.02,54.77 163.08,54.76 163.13,54.76 163.18,54.77 163.23,54.78 163.28,54.8 163.32,54.83 163.36,54.87 163.4,54.91 163.42,54.96 163.44,55.01 163.45,55.06 163.46,55.11 163.45,55.17 163.44,55.22 163.42,55.27 163.4,55.31 163.36,55.36 163.32,55.39 163.28,55.42 163.23,55.45 163.18,55.46 163.13,55.47 163.08,55.47 163.02,55.46 162.97,55.45 162.92,55.42 162.88,55.39 162.84,55.36 162.81,55.31 162.78,55.27 162.76,55.22 162.75,55.17 162.75,55.11 160.82,55.11 160.82,55.81 163.67,55.81
GND on VCC (solid shape): outline of 89 points within 181.71,48.51 184.5,50.54
GND on IN1 (solid shape): 135.99,135.38 135.99,132.39 135.73,132.14 133.96,132.14 130.59,128.77 127.73,128.77 125.7,126.74 123.99,126.74 117,133.73 117,136.58 117.51,137.09 134.27,137.09
GND on IN1 (solid shape): 17.51,24.9 17.51,21.98 15.4,19.87 5.45,19.87 5.42,19.87 4.7,19.87 4.7,22 4.79,22.21 5,22.3 13.5,22.3 14.2,22.9 13.7,23.67 13.7,24.21 13.7,24.44 14.27,24.44 14.27,24.44 15.15,24.44 15.43,24.72 15.43,25.97 15.68,26.22 16.19,26.22
GND on IN1 (solid shape): 16.42,49.97 16.42,46.35 13.05,42.98 13.05,38.16 13.43,37.78 14.77,37.78 15.15,37.4 15.15,34.98 14.26,34.09 14.16,34.09 14.16,34.09 13.7,34.09 13.7,34.21 13.7,34.83 14.2,35.6 13.5,36.2 5,36.2 4.79,36.29 4.7,36.5 4.7,45.9 4.79,46.11 5,46.2 13.5,46.2 14.03,46.44 14.2,46.99 14.19,47.01 14.03,47.36 13.7,47.57 13.7,48.4 13.71,48.4 15.16,48.4 15.4,48.64 15.4,49.97 15.59,50.16 16.23,50.16
GND on IN1 (solid shape): 5.4,66.25 5.6,65.75 6.1,65.55 6.9,65.55 7.4,65.75 7.6,66.25 7.6,66.75 10.6,66.75 10.6,66.73 10.83,66.73 16.04,61.53 16.04,59.43 14.58,57.97 14.27,57.97 14.27,57.97 13.81,57.97 13.7,58.08 13.7,58.73 14.2,59.5 13.5,60.1 5,60.1 4.79,60.19 4.7,60.4 4.7,64.2 4.5,64.7 4,64.9 0.6,64.9 0.39,64.99 0.3,65.2 0.3,66.45 0.39,66.66 0.6,66.75 5.4,66.75
GND on IN1 (solid shape): 10.71,91.05 11.41,90.36 13.43,90.36 13.88,89.91 13.88,80.32 13.23,79.68 12.2,79.68 12.2,80.85 12,81.35 11.5,81.55 7.6,81.55 7.6,82.05 7.4,82.55 6.9,82.75 6.1,82.75 5.6,82.55 5.4,82.05 5.4,81.55 0.6,81.55 0.39,81.64 0.3,81.85 0.3,83.35 0.39,83.56 0.6,83.65 2,83.65 2.5,83.85 2.7,84.35 2.7,88.6 2.79,88.81 3,88.9 10.05,88.9 10.75,89.5 10.25,90.27 10.25,91.47 10.71,91.47
GND on IN1 (solid shape): outline of 1852 points within 0.2,0.2 228.2,154.2
GND on IN2 (solid shape): 135.99,135.38 135.99,132.39 135.73,132.14 133.96,132.14 130.59,128.77 127.73,128.77 125.7,126.74 123.99,126.74 117,133.73 117,136.58 117.51,137.09 134.27,137.09
GND on IN2 (solid shape): 17.51,24.9 17.51,21.98 15.4,19.87 5.45,19.87 5.42,19.87 4.7,19.87 4.7,22 4.79,22.21 5,22.3 13.5,22.3 14.2,22.9 13.7,23.67 13.7,24.21 13.7,24.44 14.27,24.44 14.27,24.44 15.15,24.44 15.43,24.72 15.43,25.97 15.68,26.22 16.19,26.22
GND on IN2 (solid shape): 16.42,49.97 16.42,46.35 13.05,42.98 13.05,38.16 13.43,37.78 14.77,37.78 15.15,37.4 15.15,34.98 14.26,34.09 14.16,34.09 14.16,34.09 13.7,34.09 13.7,34.21 13.7,34.83 14.2,35.6 13.5,36.2 5,36.2 4.79,36.29 4.7,36.5 4.7,45.9 4.79,46.11 5,46.2 13.5,46.2 14.03,46.44 14.2,46.99 14.19,47.01 14.03,47.36 13.7,47.57 13.7,48.4 13.71,48.4 15.16,48.4 15.4,48.64 15.4,49.97 15.59,50.16 16.23,50.16
GND on IN2 (solid shape): 5.4,66.25 5.6,65.75 6.1,65.55 6.9,65.55 7.4,65.75 7.6,66.25 7.6,66.75 10.6,66.75 10.6,66.73 10.83,66.73 16.04,61.53 16.04,59.43 14.58,57.97 14.27,57.97 14.27,57.97 13.81,57.97 13.7,58.08 13.7,58.73 14.2,59.5 13.5,60.1 5,60.1 4.79,60.19 4.7,60.4 4.7,64.2 4.5,64.7 4,64.9 0.6,64.9 0.39,64.99 0.3,65.2 0.3,66.45 0.39,66.66 0.6,66.75 5.4,66.75
GND on IN2 (solid shape): outline of 130 points within 38.83,44.13 44.42,53.78
GND on IN2 (solid shape): 10.71,91.05 11.41,90.36 13.43,90.36 13.88,89.91 13.88,80.32 13.23,79.68 12.2,79.68 12.2,80.85 12,81.35 11.5,81.55 7.6,81.55 7.6,82.05 7.4,82.55 6.9,82.75 6.1,82.75 5.6,82.55 5.4,82.05 5.4,81.55 0.6,81.55 0.39,81.64 0.3,81.85 0.3,83.35 0.39,83.56 0.6,83.65 2,83.65 2.5,83.85 2.7,84.35 2.7,88.6 2.79,88.81 3,88.9 10.05,88.9 10.75,89.5 10.25,90.27 10.25,91.47 10.71,91.47
GND on IN2 (solid shape): outline of 1862 points within 0.2,0.2 228.2,154.2
GND on VCC: 124.62,57.5 125.04,57.08 129.15,57.08 129.51,57.44 129.51,62.37 129.28,62.61 124.73,62.61 124.62,62.5
GND on VCC: 186.58,36 184.8,37.78 176.48,37.78 173.77,40.49 173.77,42.48 193.46,42.48 193.46,41.61 194.79,40.28 194.79,38.14 194.43,37.78 192.65,37.78 190.87,36
GND on VCC: 132.6,66.73 132.5,66.63 132.5,64.74 132.66,64.57 135.88,64.57 136.11,64.81 136.11,66.5 135.88,66.73
GND on VCC: outline of 854 points within 0.2,0.2 228.2,154.2
GND on VCC: 60.99,39.28 60.99,40.25 62.98,40.25 65.71,37.52 99.71,37.52 100.6,38.41 103.12,38.41 103.41,38.12 103.41,36.14 103.4,36.13 64.15,36.13
GND on VCC: 62.01,99.35 62.18,99.18 64.83,99.18 64.93,99.29 64.93,103.56 65.31,103.94 65.31,104.9 65.19,105.02 64.87,105.02 64.74,104.9 64.74,104.52 64.23,104.01 62.31,104.01 62.01,103.71
GND on VCC: 211.09,42.54 210.26,43.37 208.86,43.37 208.44,43.79 208.44,44.23 208.06,44.61 208.06,47.96 208.29,48.19 209.73,48.19 210.88,47.05 211.64,47.05 213.35,45.33 213.8,45.33 214.35,44.78 214.35,43.53 213.35,42.54
GND on GND: outline of 427 points within 0.2,0.2 228.2,154.2 ; 2 cut-outs
GNDA on TOP (solid shape): 21.93,15.53 21.4,15.53 21.22,15.71 20.86,15.71 20.68,15.53 20.18,15.53 20.18,17 21.93,17
GNDA on TOP (solid shape): 29.94,10.85 29.94,10.09 29.43,9.58 29.12,9.58 28.99,9.46 28.99,7.96 28.91,7.88 27.82,7.88 27.68,7.74 26.64,7.74 26.58,7.81 26.58,8.69 26.89,9.01 27.4,9.01 27.78,9.39 28.16,9.39 28.89,10.12 29.21,10.12 29.75,10.66 29.75,10.85 29.82,10.92 29.88,10.92
GNDA on TOP (solid shape): 25.99,20.23 25.99,19.23 26.11,19.11 27.4,19.11 27.42,19.09 27.42,17.48 27.33,17.39 26.7,17.39 26.58,17.27 26.58,15.46 26.89,15.14 26.89,14.35 26.64,14.09 25.75,14.09 25.69,14.16 25.69,14.85 25.27,15.27 25.27,16.67 23.21,18.73 23.21,19.49 23.28,19.55 24.67,19.55 25.37,20.25 25.97,20.25
GNDA on VCC: 10.35,5.21 10.18,5.28 10,5.3 2.85,5.3 2.64,5.39 2.55,5.6 2.55,8.25 2.64,8.46 2.85,8.55 13.55,8.55 14.25,9.15 13.75,9.92 13.75,15.38 14.25,16.15 13.55,16.75 2.85,16.75 2.64,16.84 2.55,17.05 2.55,18.45 2.64,18.66 2.85,18.75 4,18.75 4.47,18.92 4.7,19.36 16.01,19.36 16.52,19.87 18.72,19.87 19.42,19.17 22.81,19.17 23.32,19.68 24.78,19.68 25.29,20.19 26.11,20.19 26.56,20.63 32.38,20.63 33.94,19.07 33.94,15.66 33.63,15.34 33.63,15.16 33.57,15.11 29.83,15.11 29.56,14.84 29.56,12.81 29.51,12.76 25.95,12.76 25.51,12.31 24,12.31 23.34,11.66 23.34,9.42 23.74,9.01 27.38,9.01 27.76,9.39 28.46,9.39 29.94,10.88 29.94,10.92 30.72,10.92 30.77,10.86 30.77,9.89 30.26,9.38 30.26,8.17 30.13,8.04 30.13,7.97 29.46,7.3 27.83,7.3 27.32,7.81 23.38,7.81 22.24,8.95 17.07,8.95 14.34,6.22 11.36,6.22
GNDA on GND: 10.35,5.21 10.18,5.28 10,5.3 2.85,5.3 2.64,5.39 2.55,5.6 2.55,8.25 2.64,8.46 2.85,8.55 13.55,8.55 14.25,9.15 13.75,9.92 13.75,15.38 14.25,16.15 13.55,16.75 2.85,16.75 2.64,16.84 2.55,17.05 2.55,18.45 2.64,18.66 2.85,18.75 4,18.75 4.47,18.92 4.7,19.36 16.01,19.36 16.52,19.87 18.72,19.87 19.42,19.17 22.81,19.17 23.32,19.68 24.78,19.68 25.29,20.19 26.11,20.19 26.56,20.63 32.38,20.63 33.94,19.07 33.94,15.66 33.63,15.34 33.63,15.16 33.57,15.11 29.83,15.11 29.56,14.84 29.56,12.81 29.51,12.76 25.95,12.76 25.51,12.31 24,12.31 23.34,11.66 23.34,9.42 23.74,9.01 27.38,9.01 27.76,9.39 28.46,9.39 29.94,10.88 29.94,10.92 30.72,10.92 30.77,10.86 30.77,9.89 30.26,9.38 30.26,8.17 30.13,8.04 30.13,7.97 29.46,7.3 27.83,7.3 27.32,7.81 23.38,7.81 22.24,8.95 17.07,8.95 15.03,6.91 12.05,6.91 11.36,6.22
VBAT on BOTTOM (solid shape): 198.58,48.56 199.2,48.56 199.32,48.43 199.32,47.02 199.25,46.95 198.13,46.95 198.01,47.06 198.01,48.41 198.01,48.51 197.8,48.72 196.95,48.72 196.91,48.76 196.91,48.93 196.96,48.98 198.16,48.98
VDD_1.2V on BOTTOM (solid shape): 67.28,114.42 67.15,114.3 67.15,113.41 66.52,113.41 66.33,113.6 64.8,113.6 64.71,113.68 64.71,113.88 65.06,114.23 65.95,114.23 66.77,115.06 67.28,115.06
VDD_CHG on TOP (solid shape): 194.93,55.05 194.93,53.5 194.22,52.79 193.66,52.79 193.58,52.87 193.58,53.22 193.68,53.32 194.06,53.32 194.17,53.42 194.17,54.21 194.17,54.34 194.06,54.44 193.51,54.44 193.43,54.52 193.43,54.61 193.44,54.62 193.48,54.8 193.44,54.97 193.43,54.98 193.43,55.15 193.48,55.2 194.78,55.2
VDD_CHG on BOTTOM (solid shape): 194.19,54.13 194.19,53.17 194.34,53.02 194.35,52.93 194.39,52.84 194.39,51.52 194.34,51.47 194.27,51.47 194.22,51.52 194.22,52.42 193.87,52.76 192.95,52.76 192.69,53.02 192.69,53.72 192.76,53.78 193.35,53.78 193.46,53.88 193.46,54.07 193.55,54.17 194.16,54.17
VDDCR_FCH_S5 on BOTTOM (solid shape): 151.04,41.68 151.04,39.3 150.97,39.24 150.59,39.24 150.59,39.81 149.2,39.81 149.2,39.24 148.37,39.24 148.24,39.37 148.24,39.75 147.99,40 147.23,40 146.97,40.25 146.97,42.1 147.2,42.33 150.39,42.33
VDDP_1.2V on BOTTOM (solid shape): 66.46,113.22 67.22,113.22 67.34,113.34 67.6,113.34 67.73,113.22 67.73,112.71 67.72,112.71 67.72,112.27 67.28,111.82 67.28,111.25 66.77,111.25 66.77,111.95 66.52,112.2 66.52,112.64 65.97,113.19 64.95,113.19 64.93,113.22 64.93,113.41 66.26,113.41
VDDP_CHG on BOTTOM (solid shape): 194.03,48.13 194.03,47.43 193.52,46.92 192.86,46.92 191.55,45.61 191.55,45.08 191.49,45.02 190.03,45.02 189.96,45.08 189.96,45.72 190.41,46.16 191.22,46.16 191.95,46.9 192.33,46.9 192.5,47.07 192.51,47.07 192.87,47.43 193.49,47.43 193.77,47.71 193.77,48.13 193.84,48.19 193.96,48.19
VIN_0.775V on BOTTOM (solid shape): 149.59,48.51 149.59,47.99 149.61,47.97 150.1,47.97 150.12,47.99 150.12,48.5 150.13,48.51 150.38,48.51 150.39,48.5 150.39,47.98 150.4,47.97 150.9,47.97 150.92,48 150.92,48.51 150.94,48.53 151.26,48.53 151.31,48.48 151.31,45.97 150.65,45.31 150.05,45.31 150.05,45.32 149.23,45.32 149.23,45.31 147.31,45.31 147,45.62 147,46.13 147.41,46.53 147.41,48.33 147.61,48.53 149.57,48.53
+APU_CORE on TOP (solid shape): outline of 1407 points within 119.56,79.1 145.56,127.25
+APU_CORE on BOTTOM (solid shape): 145.55,109.92 145.55,105.3 145.42,105.16 143.77,105.16 143.7,105.24 143.7,109.9 143.89,110.09 145.38,110.09
+APU_CORE on BOTTOM (solid shape): 142.61,127.83 142.61,125.21 140.21,125.21 140.21,125.21 140.21,124.36 142.58,124.36 142.58,121.75 141.83,121 140.02,121 138.85,119.82 138.85,117.03 138.27,116.45 133.13,116.45 132.62,115.95 132.62,114.74 132.24,114.36 128.3,114.36 127.29,115.37 127.29,125.79 128.75,127.25 137.26,127.25 138.21,128.2 142.24,128.2
+APU_CORE on BOTTOM (solid shape): 123.44,81.97 124,81.97 124.14,82.12 124.7,82.12 124.9,81.92 124.91,81.85 124.92,81.81 124.92,81.72 124.96,81.68 124.96,81.34 124.83,81.22 124.35,81.22 124.34,81.22 124.23,81.24 124.12,81.22 124.11,81.22 124,81.22 123.81,81.02 123.62,81.02 123.43,81.22 123.35,81.22 123.34,81.22 123.23,81.24 123.12,81.22 123.11,81.22 123.05,81.22 122.86,81.02 122.61,81.02 122.35,81.28 120.25,81.28 120,81.53 120,82.04 120.19,82.23 123.18,82.23
+APU_CORE on BOTTOM (solid shape): 121.51,80.67 121.65,80.86 121.89,80.83 121.91,80.8 121.95,80.74 121.97,80.67 121.97,80.6 121.97,80.57 123.7,80.57 123.71,80.58 124.03,80.58 124.17,80.44 124.17,80.24 124.13,80.24 124.11,80.21 124.1,80.21 123.92,80.03 123.93,79.77 123.93,79.76 123.93,79.73 123.94,79.72 123.94,79.31 123.75,79.12 123.48,79.12 123.44,79.16 123.39,79.2 123.31,79.27 123.31,79.43 123.04,79.7 122.63,79.7 122.52,79.59 121.95,79.59 121.9,79.64 121.41,79.64 120.88,79.11 120.57,79.11 120.37,79.31 120.07,79.31 120.03,79.35 120.03,80.55 120.05,80.57 120.31,80.57 120.31,80.57 120.6,80.57 121.5,80.57 121.51,80.59
+APU_CORE on BOTTOM (solid shape): outline of 122 points within 119.56,83.06 126.03,86.74
+APU_CORE on IN1 (solid shape): outline of 4364 points within 119.11,78.99 137,99.07
+APU_CORE on VCC: 119.67,83.86 119.67,87.29 117.89,89.06 117.89,90.21 116.87,91.22 116.87,95.92 114.46,98.34 114.46,123.14 116.47,125.15 137.07,125.15 138.13,124.09 138.13,115.94 143.92,110.16 145.42,110.16 145.56,110.03 145.56,105.25 145.31,105 143.7,105 137.81,99.12 135.69,99.12 126.15,89.57 126.15,83.86 125.91,83.62 125.4,83.62 124.88,83.1 124.88,80.68 124.62,80.43 124.62,79.29 124.26,78.93 120.43,78.93 120.43,83.1
+APU_CORE_NB on TOP (solid shape): outline of 2546 points within 119.69,76.42 160.82,98.57
+APU_CORE_NB on BOTTOM (solid shape): 125.09,41.28 125.08,41.22 125.08,41.18 125.08,40.69 125.08,40.65 125.09,40.58 124.85,40.34 123.6,40.34 123.28,40.65 122.81,40.65 122.69,40.77 122.69,41.02 122.7,41.02 122.7,41.28 122.92,41.51 124.87,41.51
+APU_CORE_NB on BOTTOM (solid shape): 157.09,97.58 157.09,93.41 157.9,93.41 157.9,95.78 160.51,95.78 160.82,95.47 160.82,90.49 160.63,90.3 147.94,90.3 145.13,93.11 145.13,97.59 145.77,98.23 156.43,98.23
+APU_CORE_NB on BOTTOM (solid shape): 127.62,77.85 127.88,77.85 127.95,77.92 128.02,77.98 128.07,78.05 128.5,78.47 128.93,78.47 129.23,78.17 129.28,78.12 129.35,78.08 129.38,78.06 129.49,78.05 129.56,78.06 129.76,78.06 129.87,78.17 130.05,78.17 130.34,78.46 130.69,78.46 130.88,78.26 130.88,77.61 130.55,77.28 129.78,77.28 129.72,77.21 129.35,77.21 129.33,77.22 129.27,77.28 129.04,77.28 128.89,77.43 128.77,77.43 128.73,77.43 128.7,77.43 128.58,77.43 128.43,77.28 120.13,77.28 120,77.15 119.81,77.15 119.74,77.22 119.71,77.29 119.68,77.33 119.68,77.8 119.71,77.81 119.84,77.91 119.91,78.06 119.91,78.08 120.39,78.56 123.87,78.56 124.51,77.91 124.96,77.91 125.62,78.58 126.89,78.58
+APU_CORE_NB on BOTTOM (solid shape): 131.17,80.68 131.25,80.68 131.27,80.68 131.36,80.59 131.35,80.56 131.33,80.45 131.35,80.34 131.36,80.31 131.28,80.24 131.25,80.24 131.17,80.23 131.09,80.2 131.08,80.2 130.92,80.2 129.86,79.13 129.47,79.13 129.43,79.17 129.38,79.2 129.34,79.25 125.77,79.25 125.72,79.2 125.46,79.2 125.31,79.34 125.31,79.43 125.23,79.5 125.23,79.51 124.97,79.77 124.79,79.78 124.72,79.77 124.57,79.77 124.49,79.69 124.11,79.69 124.04,79.77 124.04,80 124.17,80.14 126.42,80.14 126.64,80.36 127.08,80.36 127.43,80.01 127.65,79.84 127.91,79.88 127.94,79.88 128.57,80.52 128.96,80.52 129.16,80.31 129.17,80.3 129.34,80.1 129.6,80.07 129.61,80.07 129.91,80.07 130.54,80.71 131.09,80.71
+APU_CORE_NB on BOTTOM (solid shape): 125.89,82.85 125.89,82.6 125.96,82.53 126.94,82.53 127.38,82.09 127.39,82.08 127.72,81.8 128.07,82.05 128.08,82.06 128.63,82.61 128.7,82.61 128.77,82.68 128.99,82.68 129.23,82.58 129.47,82.68 129.84,82.68 130.48,82.04 130.48,81.66 130.04,81.22 129.35,81.22 129.34,81.22 129.23,81.24 129.12,81.22 129.11,81.22 128.35,81.22 128.34,81.22 128.23,81.24 128.12,81.22 128.11,81.22 127.35,81.22 127.34,81.22 127.23,81.24 127.12,81.22 127.11,81.22 126.62,81.22 126.17,81.66 126.17,81.67 126.1,81.77 125.99,81.84 125.99,81.85 125.96,81.87 125.84,81.88 125.78,81.87 125.54,81.87 125.34,81.67 125.11,81.67 125.02,81.76 125.02,82.1 125.45,82.53 125.45,82.53 125.54,82.62 125.54,82.82 125.62,82.9 125.84,82.9
+APU_CORE_NB on BOTTOM (solid shape): outline of 817 points within 125.97,80.14 134.18,89.28
+APU_CORE_NB on IN2 (solid shape): 132.02,88.82 132.02,87.84 131.97,87.82 131.92,87.79 131.88,87.76 131.84,87.73 131.81,87.68 131.79,87.64 131.77,87.59 131.77,87.54 131.77,87.49 131.77,87.44 131.79,87.39 131.81,87.34 131.84,87.3 131.88,87.26 131.92,87.23 131.97,87.21 132.02,87.19 132.02,86.25 132.25,86.02 132.25,85.35 132.55,85.05 132.55,84.74 132.55,84.67 132.44,84.56 131.28,84.56 131.15,84.68 131.15,86.32 130.6,86.87 130.6,87.15 130.97,87.15 130.97,87.09 130.98,87.04 131,86.99 131.02,86.95 131.05,86.91 131.09,86.87 131.13,86.84 131.18,86.81 131.23,86.8 131.28,86.79 131.33,86.79 131.38,86.8 131.43,86.81 131.48,86.84 131.52,86.87 131.56,86.91 131.59,86.95 131.61,86.99 131.63,87.04 131.64,87.09 131.64,87.15 131.63,87.2 131.61,87.25 131.59,87.29 131.56,87.34 131.52,87.37 131.48,87.4 131.43,87.43 131.38,87.44 131.33,87.45 131.28,87.45 131.23,87.44 131.18,87.43 131.13,87.4 131.09,87.37 131.05,87.34 131.02,87.29 131,87.25 130.98,87.2 130.97,87.15 130.6,87.15 130.6,88.93 130.7,89.03 131.81,89.03
+APU_CORE_NB on IN2 (solid shape): outline of 1407 points within 122.61,77.21 133.97,86.04
+APU_CORE_NB on VCC: 131.84,74.61 130.19,76.26 119.67,76.26 119.67,78.19 119.9,78.42 124.47,78.42 125.13,79.07 125.13,80.22 125.38,80.47 125.38,82.88 125.62,83.12 126.12,83.12 126.65,83.65 126.65,89.36 135.9,98.61 158.81,98.61 160.18,97.24 160.18,81.95 152.84,74.61
+FP_VCC on TOP (solid shape): 218.16,29.78 218.16,29.46 217.97,29.27 217.97,28.22 217.91,28.22 217.91,27.31 217.84,27.24 216.38,27.24 216.25,27.36 216.25,29.71 216.44,29.9 218.03,29.9
+FP_VCC on BOTTOM (solid shape): 218.06,31.2 218.06,30.42 218.16,30.32 218.16,29.46 218.03,29.33 217.14,29.33 217.08,29.4 217.08,31.24 217.14,31.3 217.96,31.3
+INV_PWR_SRC on TOP (solid shape): 210.54,58.54 210.54,57.15 210.35,56.95 205.01,56.95 204.89,57.08 204.89,58.54 205.08,58.73 208.76,58.73 208.76,58.73 210.34,58.73
+INV_PWR_SRC on BOTTOM (solid shape): 207.45,58.83 207.96,58.86 208.82,58.86 208.95,58.73 208.95,55.43 208.76,55.24 206.79,55.24 205.84,54.29 205.84,52.89 205.65,52.7 204.82,52.7 204.76,52.76 204.76,54.22 204.89,54.35 204.89,58.67 205.08,58.86 206.94,58.86
+INV_PWR_SRC on BOTTOM (solid shape): 212.95,60.51 212.95,59.37 212.89,59.3 211.93,59.3 211.68,59.05 211.68,57.15 211.36,56.83 209.27,56.83 209.21,56.88 209.21,59.15 210.35,59.76 211.3,60.64 212.82,60.64
+LAN_VDD10 on TOP (solid shape): 19.91,92.26 19.91,91.24 19.78,91.12 18.45,91.12 18.26,91.31 18.26,92.2 18.39,92.32 19.85,92.32
+LAN_VDD10 on TOP (solid shape): 22.83,85.05 22.83,84.95 22.78,84.9 21.74,84.9 21.41,84.58 21.41,83.84 21.18,83.6 20.06,83.6 19.97,83.69 19.97,84.25 20.04,84.32 20.67,84.32 21.46,85.11 22.78,85.11
+LAN_VDD10 on TOP (solid shape): 24.48,92.71 24.48,92.45 24.23,92.2 24.23,89.82 24.39,89.65 24.39,89.64 24.48,89.56 24.48,88.59 23.99,88.11 23.99,87.31 23.94,87.26 23.83,87.26 23.78,87.31 23.78,89.09 23.4,89.47 23.4,92.71 23.53,92.83 24.35,92.83
+LAN_VDD10 on BOTTOM (solid shape): 24.65,93.29 24.65,91.99 24.52,91.86 23.21,91.86 22.89,92.05 22.58,91.86 21.01,91.86 20.74,91.98 20.46,91.86 19.38,91.86 18.64,91.12 18.07,91.12 18.03,91.16 18.03,93.38 18.12,93.46 24.48,93.46
+LAN_VDD10 on IN1 (solid shape): outline of 343 points within 20.94,81.45 26.77,92.9
+LAN_VDD33 on TOP (solid shape): 41.02,51.71 41.02,49.95 41.13,49.84 43.02,49.84 43.17,49.69 43.17,48.95 42.99,48.78 39.78,48.78 39.54,49.02 39.54,51.67 39.66,51.78 40.94,51.78
+LAN_VDD33 on TOP (solid shape): 23.78,94.43 23.78,93.85 23.78,93.84 23.41,93.84 22.38,92.82 22.38,91.55 22.32,91.48 22.22,91.48 22.22,91.58 21.24,91.58 21.24,92.96 22.52,94.23 22.52,94.61 22.59,94.69 23.53,94.69
+LAN_VDD33 on TOP (solid shape): 22.83,84.27 22.83,84.14 22.58,83.89 22.58,82.91 21.81,82.15 21.81,80.77 21.24,80.2 19.97,80.2 19.85,80.32 19.85,82.1 19.97,82.23 20.91,82.23 22.12,83.43 22.12,84.04 21.99,84.17 21.99,84.27 22.04,84.32 22.78,84.32
+LAN_VDD33 on IN1 (solid shape): 41.06,50.72 40.94,50.6 40.17,50.6 40.04,50.73 40.04,52.84 41.06,52.84
+LAN_VDD33 on IN1 (solid shape): 29.82,83.2 30.25,82.77 30.25,80.78 30.18,80.71 29.29,80.71 29.21,80.78 29.21,82.07 29.2,82.07 29.2,82.27 28.85,82.62 28.85,82.87 29.36,83.38 29.65,83.38
+LAN_VDD33 on IN1 (solid shape): 23.84,94.51 23.84,93.37 23.61,93.15 22.32,93.15 21.15,91.98 20.75,91.98 20.38,91.63 20.75,91.27 20.75,87.73 20.38,87.33 20.75,86.92 20.75,85.34 20.7,85.33 20.39,84.98 20.7,84.63 20.75,84.62 20.75,83.62 21.88,82.49 21.88,81.66 21.69,81.47 20.23,81.47 19.34,82.35 19.34,88.58 18.89,89.02 18.89,93.39 19.11,93.6 21.29,93.6 22.09,94.4 22.09,94.41 22.44,94.76 23.59,94.76
+LAN_VDD33 on IN2 (solid shape): 30.17,82.89 30.17,82.48 29.98,82.29 27.97,82.29 27.72,82.55 27.72,83.24 27.53,83.43 27.53,84.17 28.89,84.17
+LAN_VDD33 on IN2 (solid shape): 22.7,82.93 22.26,82.93 21.81,82.48 21.81,81.77 21.69,81.64 21.38,81.64 20.8,82.23 20.8,83.12 21.37,83.69 22.7,83.69
+LCDVDD on TOP (solid shape): 219.5,56.73 219.5,54.58 219.05,54.14 217.07,54.14 216.89,54.32 216.89,56.76 217.01,56.89 219.33,56.89
+LCDVDD_CONN on TOP (solid shape): 216.44,58.12 216.44,55.24 216.32,55.11 214.97,55.11 213.39,56.69 213.39,58.13 213.52,58.26 216.3,58.26
+LCDVDD_CONN on BOTTOM (solid shape): 215.24,57.59 215.24,56.45 215.11,56.32 213.39,56.32 212.95,56.76 211.93,56.76 211.81,56.89 211.81,57.53 211.87,57.59 212.95,57.59 213.14,57.78 215.05,57.78
+MIC2-VREFO on TOP (solid shape): 20.68,14.23 20.68,13.72 20.04,13.08 19.27,13.08 19.08,13.27 19.08,14.22 19.15,14.28 20.63,14.28
+RTC_APU_R on TOP (solid shape): 149.24,62.72 149.24,62.06 149,61.82 145.02,61.82 144.55,62.29 144.55,62.61 144.59,62.65 145.51,62.65 145.63,62.52 148.05,62.52 148.49,62.97 148.99,62.97
+RTC_APU_R on IN1 (solid shape): outline of 202 points within 131.5,71.48 135.81,72.96
+RTCVCC on TOP (solid shape): 207.43,39.03 207.43,38.54 207.74,38.22 208.38,38.22 208.57,38.41 209.08,38.41 209.27,38.22 211.3,38.22 211.49,38.03 211.49,37.08 211.3,36.89 206.71,36.89 205.72,37.88 205.72,39.04 206.03,39.35 207.11,39.35
+SPI_VCC on TOP (solid shape): 130.58,63.98 130.58,61.88 130.53,61.82 129.68,61.82 129.57,61.71 129.57,61.17 129.52,61.13 128.49,61.13 128.38,61.23 128.38,61.47 128.87,61.95 128.87,62.52 129.48,63.13 129.87,63.13 129.87,64.05 130.52,64.05
ACIN_CHG on TOP (solid shape): 192.88,53.53 192.88,51.37 192.63,51.12 192.18,51.12 191.89,50.83 191.89,50.12 190.95,49.18 190.04,49.18 189.94,49.28 189.94,49.78 190.19,50.03 190.74,50.03 191.07,50.36 191.07,51.16 191.33,51.42 191.33,53.75 191.36,53.78 192.63,53.78
ACIN_CHG on BOTTOM (solid shape): 193.51,51.34 193.63,51.34 193.68,51.29 193.68,51.19 193.63,51.14 192.8,51.14 192.36,51.58 192.36,51.93 192.44,52 192.85,52
ASGATE on BOTTOM (solid shape): 194.41,48.19 194.41,47.18 193.46,46.22 192.88,46.22 192.44,45.78 192.44,45.08 192.31,44.95 191.8,44.95 191.74,45.02 191.74,45.61 192.86,46.73 193.57,46.73 194.17,47.33 194.17,48.17 194.24,48.23 194.37,48.23
AUD_SPK_L+ on TOP (solid shape): 29.56,5.9 29.56,5.39 29.43,5.27 27.91,5.27 27.85,5.33 27.85,5.96 27.91,6.03 29.43,6.03
AUD_SPK_L+ on TOP (solid shape): 31.56,10.85 31.56,10.04 31.61,9.99 31.61,9.38 31.43,9.2 31.43,8.31 31.35,8.24 31.02,8.24 30.95,8.31 30.95,9.18 31.35,9.58 31.35,10.85 31.4,10.9 31.5,10.9
AUD_SPK_L+ on BOTTOM (solid shape): 31.4,9.2 31.4,6.76 29.78,5.14 28.61,5.14 28.48,5.27 28.48,5.9 28.61,6.03 29.22,6.03 29.56,6.37 29.56,6.41 30.7,7.55 30.7,8 30.64,8.06 30.64,9.2 30.77,9.33 31.28,9.33
AUD_SPK_L+_C on TOP (solid shape): 23.21,7.23 26.07,7.23 26.55,6.75 26.55,6.71 26.59,6.71 27.28,6.03 27.47,6.03 27.53,5.96 27.53,5.39 27.4,5.27 26.2,5.27 26.13,5.33 26.13,5.77 25.53,6.38 25.23,6.38 25.2,6.41 24.93,6.41 24.85,6.4 24.77,6.38 24.26,6.38 24.16,6.4 24.06,6.41 23.55,6.41 23.46,6.4 23.35,6.38 22.54,6.38 22.39,6.22 17.69,6.22 17.56,6.09 17.24,6.09 14.96,3.81 14.26,3.81 14.13,3.93 14.13,4.76 14.32,4.95 14.7,4.95 16.67,6.92 17.43,6.92 17.88,7.36 23.08,7.36
AUD_SPK_L+_C on BOTTOM (solid shape): 14.7,6.54 14.7,3.93 14.58,3.81 14.19,3.81 14.07,3.93 14.07,6.54 14.19,6.66 14.58,6.66
AUD_SPK_L- on TOP (solid shape): 29.59,4.76 29.59,4.25 29.47,4.12 28.04,4.12 27.88,4.28 27.88,4.79 27.97,4.88 29.47,4.88
AUD_SPK_L- on TOP (solid shape): 31.96,10.85 31.96,10.02 32.01,9.96 32.01,9.25 32.06,9.2 32.06,8.69 32.17,8.59 32.17,8.31 32.09,8.24 31.66,8.24 31.58,8.31 31.58,9.15 31.73,9.3 31.73,9.99 31.76,10.02 31.76,10.85 31.81,10.9 31.91,10.9
AUD_SPK_L- on BOTTOM (solid shape): 32.09,9.25 32.09,8.77 32.29,8.57 32.29,5.8 30.49,4 28.61,4 28.48,4.12 28.48,4.69 28.61,4.82 29.78,4.82 31.56,6.6 31.56,9.23 31.66,9.33 32.01,9.33
AUD_SPK_L-_C on TOP (solid shape): 22.64,5.08 27.34,5.08 27.53,4.88 27.53,4.31 27.02,4.31 26.89,4.19 21.31,4.19 20.54,4.95 18.83,4.95 18.51,5.27 18.2,5.27 16.79,3.86 16.45,3.68 16.27,3.34 14.7,1.77 14.26,1.77 14.13,1.9 14.13,2.85 14.19,2.92 14.45,2.92 17.24,5.71 17.56,5.71 17.75,5.9 21.81,5.9
AUD_SPK_L-_C on BOTTOM (solid shape): 13.75,6.47 13.75,3.55 14.39,2.92 14.51,2.92 14.64,2.79 14.64,1.9 14.51,1.77 14.19,1.77 12.86,3.11 12.86,6.41 13.12,6.66 13.56,6.66
AUD_SPK_R+ on TOP (solid shape): 25.34,2.03 25.34,1.39 25.21,1.27 25.18,1.27 24.93,1.37 24.68,1.27 23.69,1.27 23.62,1.33 23.62,2.09 23.69,2.15 25.21,2.15
AUD_SPK_R+ on TOP (solid shape): 32.77,10.85 32.77,9.91 33.56,9.13 33.56,8.62 33.46,8.52 33.13,8.52 33.05,8.59 33.05,8.95 32.83,9.18 32.83,9.41 32.52,9.71 32.52,9.99 32.55,10.02 32.55,10.85 32.6,10.9 32.72,10.9
AUD_SPK_R+ on IN2 (solid shape): 34.45,8.75 34.45,6.15 33.64,5.34 33.64,4.5 33.63,4.5 33.63,4.26 30.55,1.18 25.24,1.18 24.93,1.37 24.61,1.18 24.45,1.18 24.32,1.3 24.32,2.06 24.45,2.19 29.93,2.19 32.62,4.88 32.62,5.85 33.44,6.66 33.44,8.31 33.1,8.64 33.1,8.9 32.83,9.18 32.83,9.41 32.93,9.51 33.69,9.51
AUD_SPK_R+_C on TOP (solid shape): 19.72,3.21 19.72,3.04 20.61,2.15 23.37,2.15 23.41,2.11 23.41,1.25 23.36,1.2 18.89,1.2 18.45,1.65 18.45,3.04 18.77,3.36 19.57,3.36
AUD_SPK_R+_C on BOTTOM (solid shape): 19.78,6.09 19.78,2.73 19.66,2.6 18.83,2.6 18.7,2.73 18.7,5.08 18.51,5.27 18.07,5.27 17.88,5.08 16.35,5.08 16.1,5.33 16.1,6.47 16.61,6.98 18.89,6.98
AUD_SPK_R- on TOP (solid shape): 27.45,2.98 27.45,2.41 27.33,2.28 25.8,2.28 25.74,2.34 25.74,3.16 25.77,3.18 27.25,3.18
AUD_SPK_R- on TOP (solid shape): 32.37,10.85 32.37,10.02 32.39,9.99 32.39,9.63 32.7,9.33 32.7,9.1 32.93,8.87 32.93,8.42 32.83,8.31 32.47,8.31 32.39,8.39 32.39,8.64 32.24,8.8 32.24,9.28 32.14,9.38 32.14,10.85 32.19,10.9 32.32,10.9
AUD_SPK_R- on IN2 (solid shape): 32.7,9.23 32.7,9.1 32.93,8.87 32.93,8.44 33.18,8.19 33.18,6.79 31.35,4.96 31.35,4.05 29.8,2.49 26.49,2.49 26.32,2.66 26.32,3.36 26.51,3.55 29.43,3.55 30.34,4.45 30.34,5.41 32.16,7.23 32.16,8.06 32.22,8.12 32.22,8.13 32.34,8.25 32.34,8.69 32.22,8.82 32.22,9.23 32.32,9.33 32.6,9.33
AUD_SPK_R-_C on TOP (solid shape): 21.13,3.93 24.8,3.93 25.5,3.23 25.5,2.49 25.44,2.43 23.19,2.43 23.15,2.47 23.15,3.04 23.14,3.05 23.14,3.28 23.05,3.36 21.96,3.36 21.77,3.17 20.64,3.17 20.15,3.66 18.69,3.66 18.48,3.45 18.11,3.45 17.9,3.65 17.9,4.34 18.07,4.5 18.51,4.5 18.71,4.71 20.35,4.71
AUD_SPK_R-_C on BOTTOM (solid shape): 15.72,6.54 15.72,5.14 16.35,4.5 18.39,4.5 18.45,4.44 18.45,3.42 18.32,3.3 16.16,3.3 15.08,4.38 15.08,6.54 15.21,6.66 15.59,6.66
BGATE on BOTTOM (solid shape): 176.51,56.38 176.59,56.35 176.68,56.33 176.75,56.26 176.75,56 176.63,55.88 175.74,55.88 175.55,55.68 174.47,55.68 174.41,55.75 174.41,56.38
BST1_APU on TOP (solid shape): 146.46,138.15 146.46,137.07 146.27,136.88 146.27,135.91 146.2,135.84 145.26,135.84 145.21,135.89 145.21,136.62 146.08,137.49 146.08,138.02 146.27,138.22 146.4,138.22
BST1_APU_R on TOP (solid shape): 146.33,135.14 146.33,133.55 146.3,133.53 145.64,133.53 145.61,133.55 145.61,134.24 145.57,134.28 145.27,134.28 145.22,134.33 145.22,135.15 145.25,135.18 146.29,135.18
BST_0.95V on BOTTOM (solid shape): 165.23,62.48 165.23,62.02 165.84,61.41 165.84,60.55 165.28,60.55 165.28,61.36 164.98,61.66 164.98,62.48 165.03,62.53 165.18,62.53
BST_1.2V on BOTTOM (solid shape): 63.7,111.75 63.7,110.74 63.72,110.71 63.72,109.98 63.6,109.85 63.6,109.41 62.71,109.41 62.71,110.04 63.15,110.04 63.49,110.38 63.49,111.73 63.66,111.79
BST_1.2V_R on BOTTOM (solid shape): 64.55,108.2 64.36,108.01 62.71,108.01 62.71,108.64 62.77,108.71 64.55,108.71
BST_3V on BOTTOM (solid shape): 49.79,106.83 49.79,106.65 49.63,106.48 49.63,106.23 49.37,105.97 48.04,105.97 48.04,106.17 47.15,106.17 47.15,105.97 47.09,105.97 46.96,106.1 46.96,106.74 47.09,106.86 49.75,106.86
BST_3V_R on BOTTOM (solid shape): 48.07,105.51 48.1,105.55 48.15,105.54 48.23,105.47 48.23,103.94 48.1,103.82 47.09,103.82 46.96,103.94 46.96,105.47 47.04,105.54 47.09,105.55 47.12,105.51 47.12,105.48 48.07,105.48
BST_5V on BOTTOM (solid shape): 39.76,106.32 39.76,106.14 39.59,105.97 39.59,105.72 39.34,105.47 38.01,105.47 38.01,105.66 37.12,105.66 37.12,105.65 37.06,105.55 36.94,105.58 36.93,105.59 36.93,106.23 37.05,106.36 39.72,106.36
BST_5V_R on BOTTOM (solid shape): 38.03,105 38.06,105.05 38.12,105.04 38.2,104.96 38.2,103.43 38.07,103.31 37.05,103.31 36.93,103.43 36.93,104.96 37.01,105.04 37.06,105.05 37.09,105 37.09,104.97 38.03,104.97
BST_CHG on BOTTOM (solid shape): 190.14,49.28 190.14,48.38 190.15,48.38 190.15,47.18 190.03,47.05 189.45,47.05 189.39,47.11 189.39,49.27 189.45,49.33 190.09,49.33
BST_CHG_R on BOTTOM (solid shape): 193.66,49.69 193.66,49.59 193.61,49.54 192.16,49.54 191.55,48.93 191.55,48.42 191.5,48.37 190.89,48.37 190.84,48.42 190.84,49.36 190.92,49.44 191.65,49.44 191.98,49.77 193.58,49.77
BST_NB on TOP (solid shape): 151.16,138.34 151.16,138.1 151.66,137.6 152.37,137.6 152.37,136.71 151.53,136.71 151.1,137.14 150.21,138.03 150.21,138.16 150.08,138.29 150.08,138.41 150.15,138.47 151.04,138.47
BST_NB_R on TOP (solid shape): 154.09,136.94 153.77,136.62 153.2,136.62 153.13,136.69 153.13,137.49 153.13,137.57 153.58,138.02 153.58,138.46 154.09,138.46
DCIN_CHG on BOTTOM (solid shape): 190.61,55.16 190.61,54.82 190.79,54.64 192.34,54.64 192.44,54.54 192.44,53.08 192.95,52.57 193.77,52.57 193.99,52.36 193.99,51.54 193.94,51.49 193.84,51.49 193.18,52.15 192.72,52.15 191.19,53.68 189.73,53.68 189.61,53.81 189.61,55.15 189.7,55.24 190.53,55.24
HPOUT_L on TOP (solid shape): 14.26,7.49 14.26,7.42 13.94,7.11 11.97,7.11 11.72,7.36 11.72,8.24 11.92,8.44 13.31,8.44
JACK_PLUG on IN2 (solid shape): 13.57,18.17 13.57,17.08 13.39,16.9 11.92,16.9 11.77,17.05 11.77,18.14 11.9,18.27 13.47,18.27
JACK_PLUG_DET on TOP (solid shape): 10.91,18.22 10.91,17.05 10.75,16.9 9.2,16.9 9.05,17.05 9.05,18.07 9.25,18.27 10.85,18.27
LG1_APU on TOP (solid shape): 150.97,117.66 150.97,116.71 150.78,116.52 149.89,116.52 149.7,116.71 149.7,117.41 150.08,117.79 150.85,117.79
LG1_APU on TOP (solid shape): 147.67,138.15 147.67,136.82 148.05,136.44 148.05,135.42 147.99,135.36 147.54,135.36 147.45,135.45 147.45,136.69 147.35,136.79 147.35,138.09 147.48,138.22 147.61,138.22
LG1_APU on BOTTOM (solid shape): 144.81,114.93 144.81,113.98 144.62,113.79 143.8,113.79 143.61,113.98 143.61,114.93 143.8,115.12 144.62,115.12
LG1_APU on IN2 (solid shape): 144.88,114.8 144.88,114.3 144.5,113.91 143.73,113.91 143.61,114.04 143.61,114.93 143.73,115.06 144.62,115.06
LG1_APU on IN2 (solid shape): 148.24,136.38 148.24,135.89 148.69,135.44 148.69,134.87 148.62,134.81 148.05,134.81 147.93,134.93 147.93,135.12 147.48,135.57 147.48,136.38 147.61,136.51 148.11,136.51
LG1_APU on IN2 (solid shape): 150.97,118.61 150.97,117.41 149.96,116.39 149.64,116.39 149.39,116.64 149.39,116.96 149.89,117.47 149.89,117.66 150.15,117.91 150.15,118.55 150.34,118.74 150.85,118.74
LG_1.2V on BOTTOM (solid shape): 65.6,112.13 65.6,111.61 66.14,111.07 66.14,110.8 65.95,110.61 65.57,110.61 64.68,111.5 64.68,112.14 64.74,112.2 65.53,112.2
LG_1.2V on BOTTOM (solid shape): 66.16,101.42 66.16,100.52 66.07,100.42 66.04,100.43 65.9,100.44 65.76,100.39 65.5,100.39 65.19,100.71 64.68,100.71 64.42,100.96 64.42,101.34 64.55,101.47 66.11,101.47
LG_1.2V on IN2 (solid shape): 66.86,110.25 66.86,110.2 66.38,109.72 66.28,109.72 65.41,110.59 65.41,110.76 64.92,111.26 64.92,111.39 65.17,111.64 65.47,111.64
LG_1.2V on IN2 (solid shape): 67.65,102.03 67.65,101.85 66.22,100.42 66.07,100.42 66.06,100.42 65.95,100.44 65.83,100.42 65.82,100.42 65.7,100.42 65.6,100.52 65.6,101.43 65.69,101.52 66.15,101.52 67.09,102.46 67.22,102.46
LG_CHG on BOTTOM (solid shape): 187.17,46.73 187.17,46.35 187.04,46.22 185.07,46.22 184.95,46.35 184.95,46.79 185.01,46.86 187.04,46.86
LG_CHG on IN2 (solid shape): 189.5,46.2 189.49,46.15 189.45,46.11 187.16,46.11 187.11,46.16 186.22,46.16 186.09,46.29 186.09,46.72 186.22,46.85 187.46,46.85 187.54,46.85 187.55,46.86 189.5,46.86
LG_CHG on IN2 (solid shape): 193.63,48.12 193.63,46.67 193.19,46.22 192.82,46.22 192.66,46.06 192.17,46.06 192.17,46.81 192.18,46.82 192.29,46.82 192.69,47.22 192.69,47.65 192.52,47.83 192.52,48.11 192.64,48.24 193.51,48.24
LG_NB on TOP (solid shape): 157.58,110.42 157.58,109.41 157.45,109.28 156.43,109.28 156.31,109.41 156.31,110.29 156.56,110.55 157.45,110.55
LG_NB on TOP (solid shape): 152.56,139.75 152.56,139.5 152.43,139.36 151.55,139.36 151.49,139.42 150.15,139.42 150.08,139.49 150.08,139.61 150.18,139.71 150.2,139.71 151.01,139.71 151.05,139.71 151.47,139.71 151.61,139.86 152.45,139.86
LG_NB on BOTTOM (solid shape): 161.83,111.63 161.83,109.53 161.58,109.28 160.94,109.28 160.75,109.47 160.75,110.55 160.82,110.61 160.82,111.56 161.01,111.76 161.71,111.76
LG_NB on IN1 (solid shape): 153.57,140.34 153.89,140.34 154.11,140.12 154.11,139.39 154.08,139.37 154.09,139.35 153.15,139.35 153.12,139.35 151.48,139.35 151.42,139.41 151.42,140.26 151.51,140.35 153.56,140.35
LG_NB on IN1 (solid shape): 161.83,111.63 161.83,109.55 161.56,109.28 156.5,109.28 156.31,109.47 156.31,111.31 156.56,111.56 156.88,111.56 157.07,111.37 157.07,110.68 157.32,110.42 160.63,110.42 160.82,110.61 160.82,111.56 161.01,111.76 161.71,111.76
LX1_APU on TOP (solid shape): 149.51,125.15 149.51,121.22 148.94,120.65 148.94,112.77 148.88,112.71 144.37,112.71 144.37,117.41 143.93,117.85 143.93,123.38 146.21,125.66 149.01,125.66
LX1_APU on TOP (solid shape): 147.23,138.09 147.23,136.73 147.23,136.69 147.29,136.63 147.29,134.96 147.22,134.83 147.22,134.68 147.22,133.56 147.15,133.49 146.63,133.49 146.57,133.55 146.57,135.37 146.66,135.46 146.94,135.46 147.04,135.55 147.04,135.62 147.04,136.68 147.04,136.68 147.04,138.09 147.1,138.15 147.16,138.15
LX1_APU on BOTTOM (solid shape): 150.34,125.73 151.48,125.73 151.74,125.47 151.74,122.68 149.45,120.39 149.45,116.2 148.94,115.69 144.18,115.69 143.93,115.95 143.93,123.82 144.48,124.37 148.21,124.37 148.21,125.19 145.83,125.19 145.77,125.25 145.77,126.31 145.98,126.52 149.55,126.52
LX1_APU on IN2 (solid shape): 147.22,135.37 147.22,134.82 147.21,134.74 147.22,134.66 147.22,133.57 147.19,133.54 146.48,133.54 146.46,133.55 146.46,135.35 146.54,135.42 147.18,135.42
LX1_APU on IN2 (solid shape): 151.81,126.47 151.81,124.66 151.61,124.46 150.72,124.46 150.59,124.58 150.59,124.9 151.03,125.33 151.03,126.49 151.79,126.49
LX_0.95V on TOP (solid shape): 161.39,62.83 161.39,61.82 161.27,61.69 158.98,61.69 158.92,61.75 158.92,62.96 159.04,63.09 161.14,63.09
LX_0.95V on BOTTOM (solid shape): 164.52,63.04 164.52,61.77 164.47,61.72 163.76,61.72 163.15,61.11 163.15,60.03 162.65,59.53 156.82,59.53 156.69,59.66 156.69,62.64 157.18,63.13 163.44,63.13 163.45,63.14 164.42,63.14
LX_1.2V on TOP (solid shape): 64.23,100.83 64.23,99.31 62.58,99.31 62.52,99.37 62.52,100.32 62.73,100.55 62.68,100.87 62.77,100.96 64.11,100.96
LX_1.2V on BOTTOM (solid shape): 64.5,111.75 64.5,111.36 65.25,110.61 65.25,109.34 64.93,109.02 63.98,109.02 63.92,109.09 63.92,109.53 63.98,109.6 64.42,109.6 64.68,109.85 64.68,110.55 64.3,110.93 64.3,110.99 64.29,111 64.29,111.73 64.36,111.8 64.46,111.8
LX_1.2V on BOTTOM (solid shape): 64.17,100.64 64.42,100.39 65.12,100.39 65.38,100.13 65.38,97.34 65.31,97.28 61.82,97.28 61.76,97.34 61.76,100.13 62.01,100.39 62.16,100.39 62.39,100.3 62.63,100.39 62.96,100.39 63.15,100.58 63.15,103.44 64.17,103.44
LX_1.2V on IN2 (solid shape): 64.29,101.77 64.29,100.49 64.2,100.39 63.22,100.39 63.09,100.52 63.09,101.79 63.21,101.91 64.16,101.91
LX_1.2V on IN2 (solid shape): 65.22,110.75 65.22,109.87 65.34,109.75 65.34,108.61 65.29,108.56 64.59,108.56 64.53,108.62 64.53,109.34 64.69,109.51 64.69,110.77 64.74,110.81 65.16,110.81
LX_1.8V on TOP (solid shape): 163.48,55.62 163.48,54.67 163.29,54.48 161.01,54.48 160.94,54.54 160.94,55.56 161.07,55.68 163.42,55.68
LX_1.8V on BOTTOM (solid shape): 163.48,55.56 164.63,55.56 164.69,55.49 164.69,54.8 164.63,54.73 163.21,54.73 162.72,54.24 162.72,53.4 162.66,53.34 160.56,53.34 160.44,53.46 160.44,56.38 160.56,56.51 162.53,56.51
LX_3V on TOP (solid shape): 50.26,105.21 50.26,101.78 50.01,101.53 48.87,101.53 48.61,101.78 48.61,105.21 48.87,105.47 50.01,105.47
LX_3V on BOTTOM (solid shape): 50.57,106.42 50.57,105.43 50.57,105.42 50.54,105.28 50.57,105.13 50.57,105.12 50.57,104.14 50.9,103.82 52.34,103.82 52.8,103.36 52.8,100.89 52.55,100.64 47.21,100.64 46.96,100.89 46.96,103.43 47.09,103.56 48.23,103.56 48.61,103.94 48.61,105.34 48.87,105.59 49.62,105.59 49.87,105.85 49.87,106.41 49.98,106.52 50.48,106.52
LX_5V on TOP (solid shape): 40.36,106.23 40.36,104.58 40.1,104.32 38.58,104.32 38.32,104.58 38.32,106.23 38.58,106.48 40.1,106.48
LX_5V on BOTTOM (solid shape): 40.54,105.92 40.54,104.92 40.54,104.91 40.51,104.77 40.54,104.63 40.54,104.62 40.54,103.63 40.86,103.31 42.85,103.31 43.4,102.76 43.4,100.3 43.24,100.13 37.18,100.13 36.93,100.39 36.93,102.93 37.05,103.05 38.2,103.05 38.58,103.43 38.58,104.83 38.83,105.09 39.58,105.09 39.84,105.34 39.84,105.9 39.95,106.01 40.45,106.01
LX_CHG on TOP (solid shape): 183.49,50.39 183.49,49.59 183.74,49.33 184.12,49.33 184.25,49.21 184.25,48.95 184.12,48.83 182.15,48.83 181.76,49.21 181.76,50.46 183.42,50.46
LX_CHG on BOTTOM (solid shape): 183.1,51.68 183.1,49.97 183.74,49.33 184.12,49.33 184.37,49.08 184.37,46.48 184.18,46.29 179.17,46.29 178.72,46.73 178.72,51.43 179.1,51.81 182.98,51.81
LX_CHG on BOTTOM (solid shape): 193.72,48.91 193.72,48.79 193.64,48.72 192.81,48.72 192.38,48.28 192.38,48 191.55,47.18 190.47,47.18 190.41,47.24 190.41,47.87 190.57,48.04 191.68,48.04 191.99,48.35 192.04,48.37 192.09,48.39 192.14,48.39 192.72,48.97 193.66,48.97
LX_CHG on IN2 (solid shape): 185.2,49.23 185.17,49.21 185.17,48.95 185.07,48.95 184.57,48.45 183.21,48.45 183.07,48.59 183.07,49.14 183.26,49.33 184.25,49.33 184.63,49.72 185.2,49.72
LX_CHG on IN2 (solid shape): 192.36,48.24 192.36,48.03 192,47.67 192,47.61 191.77,47.38 191.25,47.38 190.76,47.86 190.76,48.22 191.86,48.22 192.01,48.38 192.23,48.38
LX_NB on TOP (solid shape): 151.37,139.29 151.45,139.22 152.95,139.22 153.2,138.98 153.2,137.92 153.13,137.85 152.69,137.85 152.66,137.88 152.66,138.56 152.5,138.73 151.54,138.73 151.23,139.04 150.15,139.04 150.08,139.1 150.08,139.23 150.15,139.29 151.29,139.29
LX_NB on TOP (solid shape): outline of 102 points within 152.18,100.39 161.58,108.58
LX_NB on BOTTOM (solid shape): outline of 110 points within 152.18,98.93 161.58,108.58
LX_NB on IN2 (solid shape): 153.32,104.45 153.32,103.5 153.2,103.37 152.31,103.37 152.18,103.5 152.18,104.33 152.56,104.71 153.07,104.71
LX_NB on IN2 (solid shape): 153.65,138.29 153.65,137.8 153.58,137.73 152.88,137.73 152.88,137.93 152.9,137.96 152.88,137.98 152.88,138.3 152.47,138.71 151.48,138.71 151.42,138.77 151.42,139.15 151.48,139.22 152.72,139.22
QPCN_CHG on BOTTOM (solid shape): 194.83,48.18 194.83,46.9 193.77,45.84 193.77,44.75 193.75,44.73 193.15,44.73 193.14,44.75 193.14,45.4 193.33,45.59 193.33,45.91 194.57,47.15 194.57,48.17 194.62,48.21 194.79,48.21
QPCP_CHG on BOTTOM (solid shape): 195.61,48.13 195.61,46.99 195.93,46.67 195.93,45.91 195.74,45.72 194.85,45.72 194.6,45.46 194.6,44.76 194.55,44.72 194.02,44.72 193.96,44.78 193.96,45.72 194.34,46.1 195.11,46.1 195.42,46.41 195.42,48.13 195.49,48.19 195.55,48.19
REGOUT on TOP (solid shape): 20.16,90.61 20.86,90.61 20.99,90.48 20.99,89.78 21.69,89.09 22.45,89.09 23.19,88.35 23.19,87.32 23.14,87.27 22.77,87.27 22.07,87.97 21.15,87.97 18.96,90.17 18.96,90.67 19.02,90.74 20.04,90.74
RING2 on TOP (solid shape): 33.03,17.1 33.03,16.34 32.77,16.09 32.77,15.17 32.72,15.12 32.6,15.12 32.55,15.17 32.55,17.13 32.62,17.2 32.93,17.2
RING2 on TOP (solid shape): 21.31,15.36 21.94,15.36 22.01,15.3 22.01,14.54 21.88,14.41 20.16,14.41 20.04,14.54 20.04,15.24 20.16,15.36 20.74,15.36 20.87,15.5 21.17,15.5
RING2 on BOTTOM (solid shape): 22.8,15.05 22.8,14.74 22.42,14.37 20.96,14.37 20.81,14.52 20.81,15.35 20.98,15.53 22.32,15.53
RING2 on BOTTOM (solid shape): outline of 92 points within 31.13,15.83 33.23,18.17
RING2_R on TOP (solid shape): 23.9,17.6 23.9,16.98 23.28,16.35 23.28,15.04 22.83,14.6 22.32,14.6 22.32,17.14 21.88,17.58 21.18,17.58 20.93,17.84 20.93,18.98 21.12,19.17 22.32,19.17
RING2_R on IN1 (solid shape): 21.56,18.85 21.56,17.84 20.67,16.95 19.85,16.95 19.85,17.52 20.48,18.16 20.48,18.79 20.67,18.98 21.43,18.98
RING2_R on IN1 (solid shape): 5.72,8.26 5.72,7.63 5.67,7.58 5.75,7.58 5.75,6.99 5.57,6.82 4.2,6.82 3.97,7.04 3.97,8.26 4.1,8.39 5.6,8.39
SLEEVE on TOP (solid shape): 18.77,15.11 18.77,13.74 18.72,13.69 17.86,13.69 17.62,13.93 17.62,15.04 17.75,15.17 18.7,15.17
SLEEVE on IN1 (solid shape): 19.15,14.98 19.15,13.97 19.08,13.9 17.75,13.9 17.62,14.03 17.62,14.92 17.75,15.04 19.08,15.04
SLEEVE on IN1 (solid shape): 32.42,17.58 32.42,16.31 32.29,16.19 31.78,16.19 31.66,16.31 31.66,16.76 31.4,17.01 31.21,17.01 31.21,18.03 31.97,18.03
SLEEVE_R on TOP (solid shape): 20.61,18.98 20.61,17.9 19.81,17.11 19.81,15.46 19.72,15.36 19.72,14.67 19.65,14.6 19.08,14.6 19.05,14.64 19.05,16.09 18.96,16.18 18.96,18.98 19.15,19.17 20.42,19.17
SLEEVE_R on IN1 (solid shape): 5.57,18.07 5.57,17.08 5.39,16.9 3.36,16.9 3.26,17 3.26,18.07 3.34,18.14 5.27,18.14 5.29,18.17 5.47,18.17
SLEEVE_R on IN1 (solid shape): 19.78,18.79 19.78,17.9 19.66,17.78 19.02,17.78 18.89,17.9 18.89,18.47 18.53,18.83 18.26,18.83 18.26,19.85 18.72,19.85
SN_0.95V on TOP (solid shape): 161.67,65.42 161.67,64.51 161.52,64.36 158.88,64.36 158.88,65.37 158.98,65.47 161.62,65.47
SN_1.2V on TOP (solid shape): 63.72,103.25 63.92,103.06 64.17,103.06 64.23,102.99 64.23,101.91 62.58,101.91 62.58,103.82 62.77,104.01 63.72,104.01
SN_3V on TOP (solid shape): 52.93,104.66 52.93,101.78 52.68,101.53 51.66,101.53 51.41,101.78 51.41,104.72 51.52,104.84 52.75,104.84
SN_5V on TOP (solid shape): 41.88,103.31 41.88,102.29 41.63,102.04 38.58,102.04 38.32,102.29 38.32,103.31 38.58,103.56 41.63,103.56
SN_CHG on TOP (solid shape): 184.44,47.68 184.44,46.79 184.37,46.73 181.77,46.73 181.77,47.75 184.37,47.75
TPAN_VDD_F on TOP (solid shape): 220.51,46.99 220.51,44.32 220.38,44.19 219.55,44.19 219.43,44.32 219.43,45.33 219.24,45.52 219.07,45.52 219.07,45.64 218.17,45.64 218.16,45.65 218.16,47.3 218.22,47.37 220.13,47.37
UG1_APU on TOP (solid shape): 146.84,138.15 146.84,136.69 146.91,136.63 146.91,135.68 146.84,135.61 146.46,135.61 146.4,135.67 146.4,136.63 146.59,136.82 146.59,137.02 146.59,138.15 146.65,138.22 146.78,138.22
UG1_APU on BOTTOM (solid shape): 151.67,126.74 151.67,126.49 151.55,126.36 150.85,126.36 149.83,127.38 149.83,127.57 149.96,127.69 150.72,127.69
UG1_APU on IN2 (solid shape): 150.78,128.2 150.78,126.93 150.66,126.8 150.34,126.8 149.83,127.31 149.83,128.33 150.02,128.52 150.47,128.52
UG1_APU on IN2 (solid shape): 146.91,136.58 146.91,135.76 146.72,135.57 146.47,135.57 146.15,135.25 145.83,135.25 145.45,135.63 145.45,135.69 146.53,136.77 146.72,136.77
UG_1.2V on BOTTOM (solid shape): 62.01,101.34 62.01,101.09 61.31,100.39 60.74,100.39 60.61,100.52 60.61,101.28 60.8,101.47 61.88,101.47
UG_1.2V on BOTTOM (solid shape): 64.1,111.74 64.1,110.94 64.42,110.61 64.42,109.85 64.32,109.75 64.02,109.75 63.89,109.87 63.89,111.73 63.96,111.8 64.04,111.8
UG_1.2V on IN2 (solid shape): 64.42,110.78 64.42,109.71 64.41,109.71 64.41,109.41 64.4,109.39 64.4,109.28 63.71,108.59 63.44,108.59 63.07,108.96 63.07,109.13 63.69,109.75 63.69,110.74 63.78,110.83 64.37,110.83
UG_1.2V on IN2 (solid shape): 60.36,102.26 60.36,101.59 60.39,101.56 60.94,101.56 61.13,101.37 61.13,100.48 61.01,100.37 61,100.37 60.87,100.39 60.75,100.37 60.74,100.37 59.83,100.37 59.57,100.62 59.57,102.26 59.66,102.35 60.28,102.35
UG_CHG on BOTTOM (solid shape): 183.1,52.48 183.1,52.16 182.98,52.03 180.85,52.03 180.76,52.13 180.76,52.45 180.91,52.61 182.98,52.61
UG_CHG on BOTTOM (solid shape): 193.72,49.3 193.72,49.19 193.65,49.12 192.68,49.12 192.08,48.52 191.75,48.52 191.7,48.57 191.7,48.9 192.18,49.37 192.22,49.37 192.23,49.38 193.65,49.38
UG_CHG on IN2 (solid shape): 182.44,52.54 182.44,51.85 180.89,51.85 180.72,52.01 180.72,52.54 180.85,52.67 182.32,52.67
UG_CHG on IN2 (solid shape): 191.11,50 191.59,50 192.21,49.38 192.41,49.38 192.54,49.25 192.54,49.04 192.01,48.51 191.75,48.51 191.65,48.61 191.65,48.87 191.09,49.43 191.09,49.99 191.11,50
UG_NB on TOP (solid shape): 150.2,138.91 151.01,138.91 151.16,138.91 151.47,138.6 152.36,138.6 152.5,138.47 152.5,138.22 152.37,138.1 151.48,138.1 151.35,138.23 151.35,138.35 151.1,138.6 150.15,138.6 150.08,138.66 150.08,138.85 150.15,138.91
UG_NB on BOTTOM (solid shape): 151.42,104.71 151.42,104.07 151.16,103.82 150.35,103.82 150.28,103.89 150.28,104.82 150.39,104.94 151.19,104.94
UG_NB on IN2 (solid shape): 150.91,105.72 150.91,103.94 150.81,103.84 150.35,103.84 150.15,104.05 150.15,105.72 150.28,105.85 150.78,105.85
UG_NB on IN2 (solid shape): 152.5,138.46 152.5,137.4 152.69,137.21 152.69,136.76 151.93,136.76 151.55,137.13 151.55,137.14 151.34,137.36 151.34,138.44 151.47,138.57 152.38,138.57
